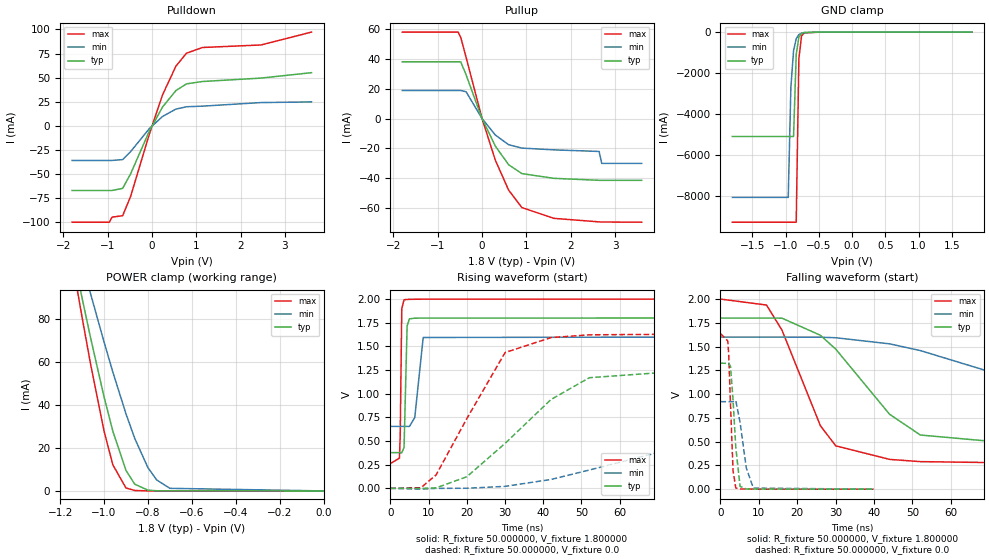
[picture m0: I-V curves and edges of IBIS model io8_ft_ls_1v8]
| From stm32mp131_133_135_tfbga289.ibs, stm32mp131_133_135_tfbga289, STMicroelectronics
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|   Model io8_ft_ls_1v8
[Model]  io8_ft_ls_1v8
Model_type I/O
Polarity   Non-Inverting
Enable   Active-Low
Vinl =   0.540000V
Vinh =   1.260000V
Vmeas =  0.900000V
Cref =   50.000000pF
Rref =   100.000000M
Vref =   0.0V
C_comp   3.181500pF   3.164300pF   3.208900pF
[Temperature Range]   25.000000   0.140000k   -40.000000
[Pullup Reference]   1.800000V   1.600000V   2.000000V
[Pulldown Reference]   0.0V   0.0V   0.0V
[POWER Clamp Reference]   1.800000V   1.600000V   2.000000V
[GND Clamp Reference]   0.0V   0.0V   0.0V
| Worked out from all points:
|   slope of the pulldown table from 0 to 0.27 V, typ, clamps not added: 12.5 ohm
|   slope of the pullup table from 0 to 0.27 V, typ, clamps not added: 16 ohm
|   GND clamp passes 1 mA (typ) near -0.47 V on its own axis
|   POWER clamp passes 1 mA (typ) near -0.83 V on its own axis
|   rising waveform, R_fixture 50.000000, V_fixture 1.800000: 20-80 % time 363ps typ, 728ps min, 285ps max; typ from 0.377 V to 1.8 V
|   rising waveform, R_fixture 50.000000, V_fixture 0.0: 20-80 % time 21.7ns typ, 54ns min, 12.5ns max; typ from 0 V to 1.32 V
|   falling waveform, R_fixture 50.000000, V_fixture 1.800000: 20-80 % time 18.6ns typ, 47.6ns min, 10.6ns max; typ from 1.8 V to 0.377 V
|   falling waveform, R_fixture 50.000000, V_fixture 0.0: 20-80 % time 1.22ns typ, 1.91ns min, 857ps max; typ from 1.32 V to 0 V
[Pulldown]
|Voltage   I(typ)   I(min)   I(max)
-1.8V     -67.09mA   -35.91mA   -100mA
-960mV    -67.09mA   -35.91mA   -100mA
-900mV    -67.09mA   -35.91mA   -94.73mA
-660mV    -64.86mA   -35.04mA   -93.29mA
-480mV    -49.73mA   -26.7mA    -73.15mA
-60mV     -5.61mA    -2.937mA   -8.854mA
240mV     19.58mA    9.767mA    32.18mA
540mV     36.57mA    17.36mA    61.85mA
780mV     43.58mA    19.81mA    75.41mA
1.14V     46.02mA    20.44mA    81.32mA
2.46V     49.57mA    24.16mA    83.94mA
3.6V      55.18mA    24.86mA    97.31mA
[Pullup]
|Voltage   I(typ)   I(min)   I(max)
-1.8V     37.91mA    18.78mA    57.81mA
-540mV    37.91mA    18.78mA    57.81mA
-480mV    37.91mA    18.78mA    54.19mA
-360mV    29.25mA    17.91mA    40.95mA
0V        5.86pA     765pA      4.35pA
300mV     -18.47mA   -11.04mA   -27.85mA
600mV     -30.86mA   -17.49mA   -47.91mA
900mV     -36.82mA   -19.76mA   -59.55mA
1.62V     -39.97mA   -20.94mA   -66.73mA
2.64V     -41.3mA    -22mA      -69.09mA
2.7V      -41.3mA    -30mA      -69.18mA
3.6V      -41.3mA    -30mA      -69.3mA
[GND_clamp]
|Voltage   I(typ)   I(min)   I(max)
-1.8V     -5.08A     -8.044A    -9.251A
-960mV    -5.08A     -8.044A    -9.251A
-920mV    -5.08A     -2.669A    -9.251A
-880mV    -5.08A     -908mA     -9.251A
-840mV    -1.096A    -323.6mA   -9.251A
-800mV    -248.9mA   -123.7mA   -1.293A
-760mV    -64.81mA   -51.32mA   -196.6mA
-720mV    -22.13mA   -23.23mA   -39.69mA
-480mV    -1.149mA   -1.898mA   -936.1uA
1.8V      0A         44.33nA    0A
[POWER_clamp]
|Voltage   I(typ)   I(min)   I(max)
-1.8V     460.5mA    392.1mA    526.9mA
-1.12V    99.56mA    114.1mA    92.51mA
-1.1V     89.79mA    106.4mA    80.86mA
-1.06V    70.71mA    91.32mA    58.34mA
-1V       43.82mA    69.37mA    27.91mA
-960mV    27.85mA    55.39mA    12.18mA
-900mV    9.544mA    35.9mA     1.368mA
-860mV    3.133mA    24.42mA    203.6uA
-800mV    367uA      10.84mA    10.43uA
-760mV    78.93uA    5.095mA    1.426uA
-700mV    7.679uA    1.212mA    72.45nA
0V        0A         59.16nA    0A
[Ramp]
| variable   typ   min   max
dV/dt_r  0.79476/21.60778n   0.55238/53.91503n   0.98220/12.41421n
dV/dt_f  0.85363/18.45188n   0.56723/47.51838n   1.04298/10.52669n
R_load = 50.000000
[Rising Waveform]
R_fixture= 50.000000
V_fixture= 1.800000
V_fixture_min= 1.600000
V_fixture_max= 2.000000
|time   V(typ)   V(min)   V(max)
0s        377.3mV    654.6mV    261.7mV
2.402ns   377.3mV    654.6mV    319.2mV
2.603ns   377.3mV    654.6mV    570.9mV
3.003ns   375.6mV    654.6mV    1.896V
3.604ns   434.3mV    654.6mV    1.993V
4.404ns   1.716V     654.7mV    1.996V
5.005ns   1.791V     653.5mV    1.997V
6.406ns   1.798V     748.7mV    1.998V
8.609ns   1.799V     1.594V     1.999V
99.7ns    1.8V       1.6V       2V
[Rising Waveform]
R_fixture= 50.000000
V_fixture= 0.0
V_fixture_min= 0.0
V_fixture_max= 0.0
|time   V(typ)   V(min)   V(max)
0s        2.004nV    378.7nV    939.1pV
8.008ns   -568.6uV   -8.718mV   6.504mV
12.01ns   5.152mV    -235.5uV   143.1mV
20.02ns   122.6mV    950uV      737.3mV
30.03ns   474.9mV    20.83mV    1.435V
42.04ns   938.7mV    93.95mV    1.593V
52.05ns   1.169V     193.5mV    1.622V
104.1ns   1.319V     729.9mV    1.637V
164.2ns   1.325V     894.4mV    1.637V
997ns     1.325V     920.7mV    1.637V
[Falling Waveform]
R_fixture= 50.000000
V_fixture= 1.800000
V_fixture_min= 1.600000
V_fixture_max= 2.000000
|time   V(typ)   V(min)   V(max)
0s        1.8V       1.6V       2V
12.01ns   1.8V       1.6V       1.937V
16.02ns   1.799V     1.6V       1.674V
26.03ns   1.619V     1.599V     667.3mV
30.03ns   1.473V     1.593V     455.6mV
44.04ns   787.9mV    1.529V     313.2mV
52.05ns   569.6mV    1.458V     289.8mV
100.1ns   396.2mV    867.2mV    263.4mV
166.2ns   378.8mV    690.4mV    261.7mV
997ns     377.3mV    654.6mV    261.7mV
[Falling Waveform]
R_fixture= 50.000000
V_fixture= 0.0
V_fixture_min= 0.0
V_fixture_max= 0.0
|time   V(typ)   V(min)   V(max)
0s        1.325V     920.7mV    1.637V
1.922ns   1.324V     920.7mV    1.559V
2.162ns   1.327V     920.7mV    1.42V
2.643ns   1.289V     920.7mV    877.3mV
3.283ns   942.2mV    920.4mV    197.1mV
4.004ns   439mV      932.3mV    13.3mV
5.125ns   29.12mV    702.9mV    2.27mV
6.727ns   1.816mV    225.3mV    1.271mV
8.569ns   716.3uV    11.3mV     981.8uV
39.88ns   2.004nV    378.7nV    939.1pV
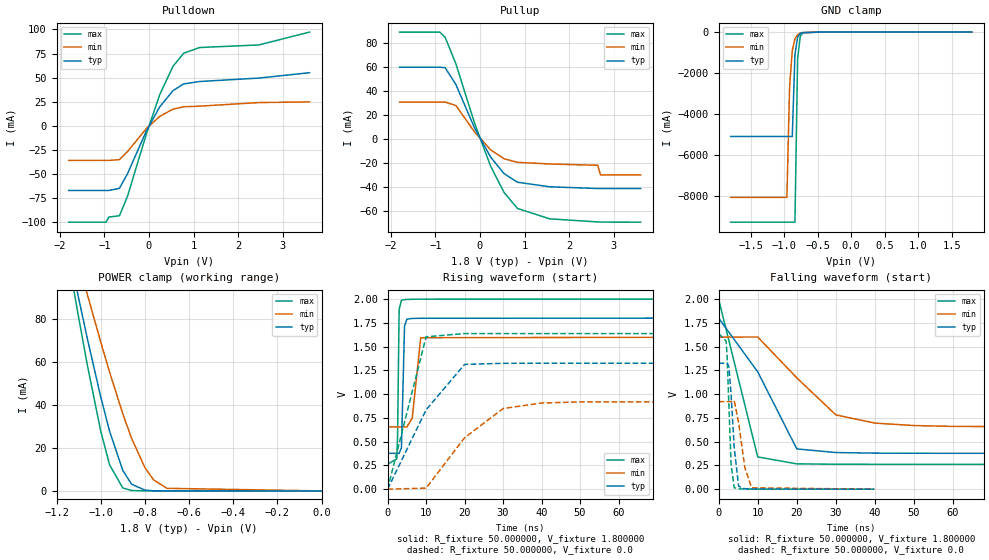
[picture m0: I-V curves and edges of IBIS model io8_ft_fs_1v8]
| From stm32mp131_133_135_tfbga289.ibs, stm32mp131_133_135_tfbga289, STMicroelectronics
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|   Model io8_ft_fs_1v8
[Model]  io8_ft_fs_1v8
Model_type I/O
Polarity   Non-Inverting
Enable   Active-Low
Vinl =   0.540000V
Vinh =   1.260000V
Vmeas =  0.900000V
Cref =   50.000000pF
Rref =   100.000000M
Vref =   0.0V
C_comp   3.181500pF   3.164300pF   3.208900pF
[Temperature Range]   25.000000   0.140000k   -40.000000
[Pullup Reference]   1.800000V   1.600000V   2.000000V
[Pulldown Reference]   0.0V   0.0V   0.0V
[POWER Clamp Reference]   1.800000V   1.600000V   2.000000V
[GND Clamp Reference]   0.0V   0.0V   0.0V
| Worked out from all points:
|   slope of the pulldown table from 0 to 0.27 V, typ, clamps not added: 12.5 ohm
|   slope of the pullup table from 0 to 0.27 V, typ, clamps not added: 16 ohm
|   GND clamp passes 1 mA (typ) near -0.47 V on its own axis
|   POWER clamp passes 1 mA (typ) near -0.83 V on its own axis
|   rising waveform, R_fixture 50.000000, V_fixture 1.800000: 20-80 % time 365ps typ, 729ps min, 287ps max; typ from 0.377 V to 1.8 V
|   rising waveform, R_fixture 50.000000, V_fixture 0.0: 20-80 % time 11.5ns typ, 13.1ns min, 6.13ns max; typ from 0 V to 1.32 V
|   falling waveform, R_fixture 50.000000, V_fixture 1.800000: 20-80 % time 12ns typ, 14ns min, 6.29ns max; typ from 1.8 V to 0.377 V
|   falling waveform, R_fixture 50.000000, V_fixture 0.0: 20-80 % time 1.22ns typ, 1.91ns min, 860ps max; typ from 1.32 V to 0 V
[Pulldown]
|Voltage   I(typ)   I(min)   I(max)
-1.8V     -67.09mA   -35.91mA   -100mA
-960mV    -67.09mA   -35.91mA   -100mA
-900mV    -67.09mA   -35.91mA   -94.73mA
-660mV    -64.86mA   -35.04mA   -93.29mA
-480mV    -49.73mA   -26.7mA    -73.15mA
-60mV     -5.61mA    -2.937mA   -8.854mA
240mV     19.58mA    9.767mA    32.18mA
540mV     36.57mA    17.36mA    61.85mA
780mV     43.58mA    19.81mA    75.41mA
1.14V     46.02mA    20.44mA    81.32mA
2.46V     49.57mA    24.16mA    83.94mA
3.6V      55.18mA    24.86mA    97.31mA
[Pullup]
|Voltage   I(typ)   I(min)   I(max)
-1.8V     59.55mA    30.58mA    88.77mA
-900mV    59.55mA    30.58mA    88.77mA
-780mV    59.21mA    30.58mA    84.38mA
-540mV    45.23mA    27.77mA    62.46mA
-120mV    8.961mA    5.668mA    12.94mA
240mV     -15.24mA   -9.189mA   -22.87mA
540mV     -28.9mA    -16.58mA   -44.57mA
840mV     -36.08mA   -19.51mA   -57.87mA
1.56V     -39.85mA   -20.89mA   -66.5mA
2.64V     -41.3mA    -22mA      -69.09mA
2.7V      -41.3mA    -30mA      -69.18mA
3.6V      -41.3mA    -30mA      -69.3mA
[GND_clamp]
|Voltage   I(typ)   I(min)   I(max)
-1.8V     -5.08A     -8.044A    -9.251A
-960mV    -5.08A     -8.044A    -9.251A
-920mV    -5.08A     -2.669A    -9.251A
-880mV    -5.08A     -908mA     -9.251A
-840mV    -1.096A    -323.6mA   -9.251A
-800mV    -248.9mA   -123.7mA   -1.293A
-760mV    -64.81mA   -51.32mA   -196.6mA
-720mV    -22.13mA   -23.23mA   -39.69mA
-480mV    -1.149mA   -1.898mA   -936.1uA
1.8V      0A         44.33nA    0A
[POWER_clamp]
|Voltage   I(typ)   I(min)   I(max)
-1.8V     460.5mA    392.1mA    526.9mA
-1.12V    99.56mA    114.1mA    92.51mA
-1.1V     89.79mA    106.4mA    80.86mA
-1.06V    70.71mA    91.32mA    58.34mA
-1V       43.82mA    69.37mA    27.91mA
-960mV    27.85mA    55.39mA    12.18mA
-900mV    9.544mA    35.9mA     1.368mA
-860mV    3.133mA    24.42mA    203.6uA
-800mV    367uA      10.84mA    10.43uA
-760mV    78.93uA    5.095mA    1.426uA
-700mV    7.679uA    1.212mA    72.45nA
0V        0A         59.16nA    0A
[Ramp]
| variable   typ   min   max
dV/dt_r  0.79476/4.10814n   0.55240/10.19838n   0.98226/2.31449n
dV/dt_f  0.85363/4.33132n   0.56724/10.75987n   1.04297/2.48564n
R_load = 50.000000
[Rising Waveform]
R_fixture= 50.000000
V_fixture= 1.800000
V_fixture_min= 1.600000
V_fixture_max= 2.000000
|time   V(typ)   V(min)   V(max)
0s        377.3mV    654.6mV    261.7mV
2.402ns   377.3mV    654.6mV    319.5mV
2.603ns   377.3mV    654.6mV    570.4mV
3.003ns   375.6mV    654.6mV    1.89V
3.604ns   434.2mV    654.6mV    1.988V
4.404ns   1.713V     654.7mV    1.994V
5.005ns   1.788V     653.6mV    1.996V
6.406ns   1.796V     748.6mV    1.998V
8.609ns   1.798V     1.593V     1.999V
99.7ns    1.8V       1.6V       2V
[Rising Waveform]
R_fixture= 50.000000
V_fixture= 0.0
V_fixture_min= 0.0
V_fixture_max= 0.0
|time   V(typ)   V(min)   V(max)
0s        2.004nV    378.7nV    939.1pV
10.01ns   835mV      10.85mV    1.603V
20.02ns   1.313V     541.8mV    1.637V
30.03ns   1.324V     848.6mV    1.637V
40.04ns   1.325V     906.5mV    1.637V
50.05ns   1.325V     918.2mV    1.637V
991ns     1.325V     920.7mV    1.637V
[Falling Waveform]
R_fixture= 50.000000
V_fixture= 1.800000
V_fixture_min= 1.600000
V_fixture_max= 2.000000
|time   V(typ)   V(min)   V(max)
0s        1.8V       1.6V       2V
10.01ns   1.235V     1.601V     339.2mV
20.02ns   423.6mV    1.171V     266.3mV
30.03ns   385.3mV    781.3mV    262.2mV
40.04ns   379.1mV    694.9mV    261.7mV
50.05ns   377.6mV    669.2mV    261.7mV
60.06ns   377.3mV    660.3mV    261.7mV
100.1ns   377.3mV    654.7mV    261.7mV
991ns     377.3mV    654.6mV    261.7mV
[Falling Waveform]
R_fixture= 50.000000
V_fixture= 0.0
V_fixture_min= 0.0
V_fixture_max= 0.0
|time   V(typ)   V(min)   V(max)
0s        1.325V     920.7mV    1.637V
1.922ns   1.324V     920.7mV    1.558V
2.162ns   1.327V     920.7mV    1.417V
2.643ns   1.288V     920.7mV    874.9mV
3.203ns   992.4mV    920.5mV    256.7mV
4.004ns   436.6mV    931.2mV    16mV
5.125ns   30.14mV    700.1mV    3.312mV
6.727ns   3.667mV    224.1mV    1.151mV
8.488ns   1.83mV     14.08mV    645.6uV
39.88ns   2.004nV    378.7nV    939.1pV
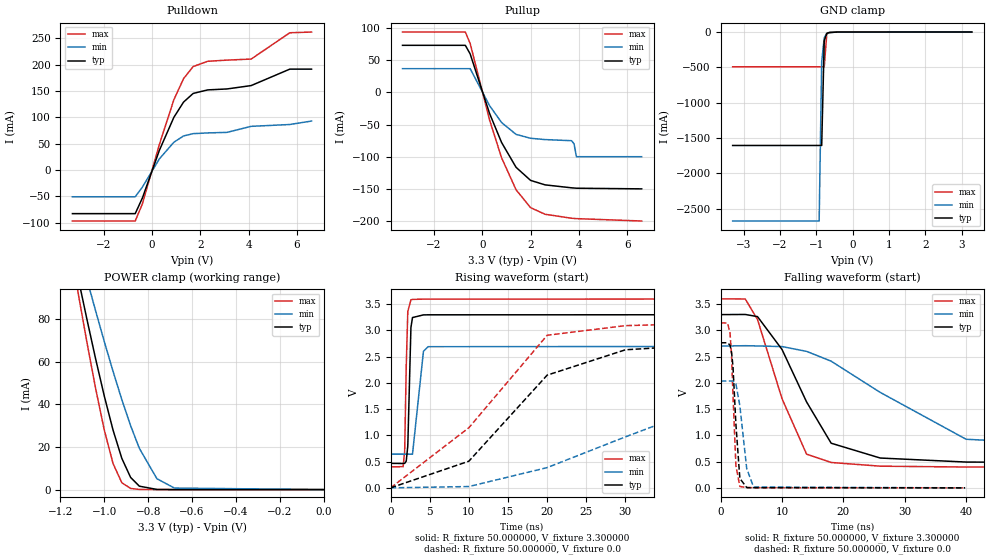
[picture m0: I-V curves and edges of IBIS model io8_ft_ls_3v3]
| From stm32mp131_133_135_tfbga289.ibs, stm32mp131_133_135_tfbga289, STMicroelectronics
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|   Model io8_ft_ls_3v3
[Model]  io8_ft_ls_3v3
Model_type I/O
Polarity   Non-Inverting
Enable   Active-Low
Vinl =   0.990000V
Vinh =   2.310000V
Vmeas =  1.650000V
Cref =   50.000000pF
Rref =   100.000000M
Vref =   0.0V
C_comp   3.331100pF   3.329200pF   3.346200pF
[Temperature Range]   25.000000   0.140000k   -40.000000
[Pullup Reference]   3.300000V   2.700000V   3.600000V
[Pulldown Reference]   0.0V   0.0V   0.0V
[POWER Clamp Reference]   3.300000V   2.700000V   3.600000V
[GND Clamp Reference]   0.0V   0.0V   0.0V
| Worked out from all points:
|   slope of the pulldown table from 0 to 0.495 V, typ, clamps not added: 8.27 ohm
|   slope of the pullup table from 0 to 0.495 V, typ, clamps not added: 9.61 ohm
|   GND clamp passes 1 mA (typ) near -0.46 V on its own axis
|   POWER clamp passes 1 mA (typ) near -0.82 V on its own axis
|   rising waveform, R_fixture 50.000000, V_fixture 3.300000: 20-80 % time 298ps typ, 372ps min, 282ps max; typ from 0.466 V to 3.3 V
|   rising waveform, R_fixture 50.000000, V_fixture 0.0: 20-80 % time 11.1ns typ, 22.9ns min, 12.3ns max; typ from 0 V to 2.76 V
|   falling waveform, R_fixture 50.000000, V_fixture 3.300000: 20-80 % time 7.44ns typ, 16.2ns min, 5.44ns max; typ from 3.3 V to 0.466 V
|   falling waveform, R_fixture 50.000000, V_fixture 0.0: 20-80 % time 746ps typ, 1.13ns min, 609ps max; typ from 2.76 V to 0 V
[Pulldown]
|Voltage   I(typ)   I(min)   I(max)
-3.3V     -82.68mA   -50.69mA   -96.69mA
-700mV    -82.68mA   -50.69mA   -96.69mA
-400mV    -52.74mA   -32.14mA   -63.87mA
300mV     37.41mA    21.2mA     48.47mA
900mV     100mA      52.8mA     133.4mA
1.3V      128.9mA    64.69mA    173.3mA
1.7V      145.4mA    69.09mA    196.4mA
2.3V      152.1mA    70.46mA    206.4mA
3.1V      153.9mA    71.5mA     208.6mA
4.1V      160.3mA    82.94mA    210.6mA
5.7V      191.5mA    86.44mA    260.5mA
6.6V      191.5mA    93mA       261.9mA
[Pullup]
|Voltage   I(typ)   I(min)   I(max)
-3.3V     73.22mA    36.92mA    93.89mA
-700mV    73.22mA    36.92mA    93.89mA
-500mV    59.82mA    36.92mA    76.02mA
300mV     -32.45mA   -20.38mA   -42.55mA
800mV     -77.86mA   -46.83mA   -101.6mA
1.4V      -116.5mA   -65.29mA   -151.4mA
2V        -136.8mA   -71.31mA   -179.2mA
2.6V      -143.8mA   -73.35mA   -189.5mA
3.7V      -148.4mA   -75.1mA    -195.7mA
3.8V      -148.7mA   -80mA      -196mA
3.9V      -149mA     -100mA     -196.3mA
6.6V      -150mA     -100mA     -200mA
[GND_clamp]
|Voltage   I(typ)   I(min)   I(max)
-3.3V     -1.605A    -2.674A    -491.7mA
-920mV    -1.605A    -2.674A    -491.7mA
-850mV    -1.605A    -419.8mA   -491.7mA
-780mV    -124.6mA   -80.71mA   -491.7mA
-710mV    -18.13mA   -20.11mA   -27.93mA
-640mV    -6.917mA   -6.958mA   -7.362mA
-430mV    -466.9uA   -1.206mA   -281.7uA
3.28V     0A         45.63nA    0A
[POWER_clamp]
|Voltage   I(typ)   I(min)   I(max)
-3.28V    1.28A      1.024A     1.509A
-1.12V    99.56mA    114.1mA    92.51mA
-1.08V    80.16mA    98.83mA    69.45mA
-1.04V    61.47mA    83.9mA     47.62mA
-1V       43.82mA    69.37mA    27.91mA
-960mV    27.85mA    55.39mA    12.18mA
-920mV    14.63mA    42.15mA    3.226mA
-880mV    5.71mA     29.97mA    537.4uA
-840mV    1.599mA    19.32mA    75.95uA
-760mV    78.93uA    5.095mA    1.426uA
-680mV    3.528uA    713.7uA    27.27nA
0V        0A         62.3nA     0A
[Ramp]
| variable   typ   min   max
dV/dt_r  1.65858/10.24860n   1.22046/21.78605n   1.88568/7.88366n
dV/dt_f  1.70022/7.28874n   1.23440/16.12476n   1.92035/5.37283n
R_load = 50.000000
[Rising Waveform]
R_fixture= 50.000000
V_fixture= 3.300000
V_fixture_min= 2.700000
V_fixture_max= 3.600000
|time   V(typ)   V(min)   V(max)
0s        466.3mV    642.7mV    399.4mV
1.602ns   463.9mV    642.7mV    403.6mV
1.802ns   465.7mV    642.7mV    694.9mV
2.002ns   509mV      642.7mV    2.309V
2.202ns   796.8mV    642.8mV    3.358V
2.603ns   3.056V     641.6mV    3.583V
2.803ns   3.244V     641.9mV    3.59V
4.204ns   3.295V     2.601V     3.595V
4.805ns   3.296V     2.689V     3.595V
99.7ns    3.3V       2.7V       3.6V
[Rising Waveform]
R_fixture= 50.000000
V_fixture= 0.0
V_fixture_min= 0.0
V_fixture_max= 0.0
|time   V(typ)   V(min)   V(max)
0s        2.574nV    280.9nV    5.711nV
10.01ns   507.7mV    24.77mV    1.145V
20.02ns   2.147V     385.7mV    2.907V
30.03ns   2.63V      971.6mV    3.09V
40.04ns   2.72V      1.534V     3.13V
50.05ns   2.748V     1.821V     3.139V
60.06ns   2.758V     1.925V     3.142V
80.08ns   2.764V     2V         3.143V
100.1ns   2.764V     2.023V     3.143V
991ns     2.764V     2.034V     3.143V
[Falling Waveform]
R_fixture= 50.000000
V_fixture= 3.300000
V_fixture_min= 2.700000
V_fixture_max= 3.600000
|time   V(typ)   V(min)   V(max)
0s        3.3V       2.7V       3.6V
4.004ns   3.303V     2.708V     3.598V
6.006ns   3.262V     2.703V     3.207V
10.01ns   2.635V     2.691V     1.697V
14.01ns   1.637V     2.6V       642.1mV
18.02ns   850.4mV    2.413V     483.3mV
26.03ns   568mV      1.818V     412.8mV
40.04ns   491.4mV    925.7mV    396.6mV
82.08ns   467.6mV    673.9mV    399.1mV
997ns     466.3mV    642.7mV    399.4mV
[Falling Waveform]
R_fixture= 50.000000
V_fixture= 0.0
V_fixture_min= 0.0
V_fixture_max= 0.0
|time   V(typ)   V(min)   V(max)
0s        2.764V     2.034V     3.143V
1.121ns   2.764V     2.034V     3.14V
1.522ns   2.719V     2.034V     2.951V
1.762ns   2.589V     2.034V     2.541V
2.002ns   2.318V     2.037V     1.778V
2.482ns   1.209V     1.98V      420.7mV
3.123ns   180.2mV    1.566V     27.35mV
4.244ns   5.433mV    367.8mV    4.58mV
5.365ns   2.953mV    15.69mV    3.729mV
39.88ns   2.574nV    280.9nV    5.711nV
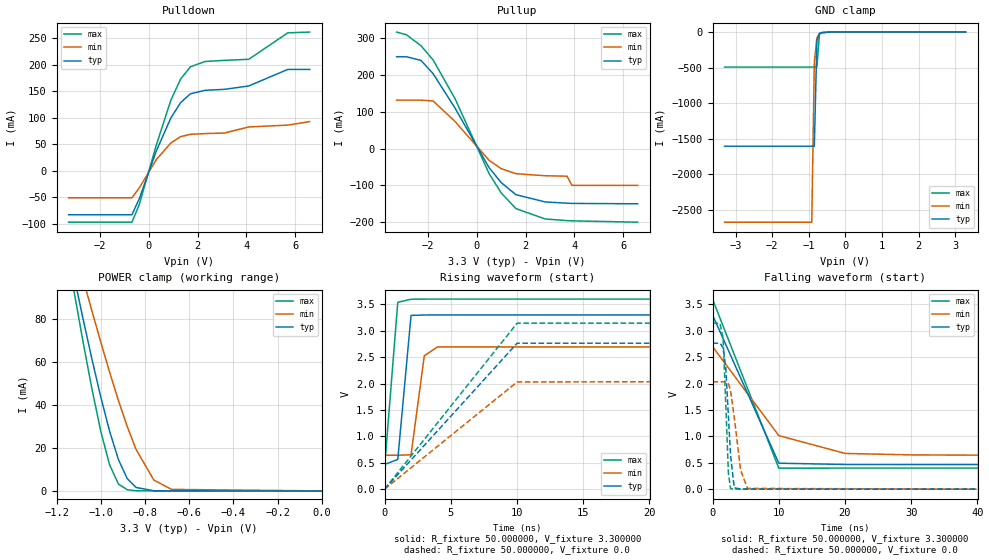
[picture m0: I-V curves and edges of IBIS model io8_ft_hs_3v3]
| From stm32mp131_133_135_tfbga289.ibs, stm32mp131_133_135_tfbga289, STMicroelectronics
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|   Model io8_ft_hs_3v3
[Model]  io8_ft_hs_3v3
Model_type I/O
Polarity   Non-Inverting
Enable   Active-Low
Vinl =   0.990000V
Vinh =   2.310000V
Vmeas =  1.650000V
Cref =   50.000000pF
Rref =   100.000000M
Vref =   0.0V
C_comp   3.331100pF   3.329200pF   3.346200pF
[Temperature Range]   25.000000   0.140000k   -40.000000
[Pullup Reference]   3.300000V   2.700000V   3.600000V
[Pulldown Reference]   0.0V   0.0V   0.0V
[POWER Clamp Reference]   3.300000V   2.700000V   3.600000V
[GND Clamp Reference]   0.0V   0.0V   0.0V
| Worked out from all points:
|   slope of the pulldown table from 0 to 0.495 V, typ, clamps not added: 8.27 ohm
|   slope of the pullup table from 0 to 0.495 V, typ, clamps not added: 9.61 ohm
|   GND clamp passes 1 mA (typ) near -0.46 V on its own axis
|   POWER clamp passes 1 mA (typ) near -0.82 V on its own axis
|   rising waveform, R_fixture 50.000000, V_fixture 3.300000: 20-80 % time 624ps typ, 658ps min, 612ps max; typ from 0.466 V to 3.3 V
|   rising waveform, R_fixture 50.000000, V_fixture 0.0: 20-80 % time 6.01ns typ, 6.02ns min, 6.01ns max; typ from 0 V to 2.76 V
|   falling waveform, R_fixture 50.000000, V_fixture 3.300000: 20-80 % time 6.06ns typ, 7.33ns min, 6ns max; typ from 3.3 V to 0.466 V
|   falling waveform, R_fixture 50.000000, V_fixture 0.0: 20-80 % time 720ps typ, 1.13ns min, 527ps max; typ from 2.76 V to 0 V
[Pulldown]
|Voltage   I(typ)   I(min)   I(max)
-3.3V     -82.68mA   -50.69mA   -96.69mA
-700mV    -82.68mA   -50.69mA   -96.69mA
-400mV    -52.74mA   -32.14mA   -63.87mA
300mV     37.41mA    21.2mA     48.47mA
900mV     100mA      52.8mA     133.4mA
1.3V      128.9mA    64.69mA    173.3mA
1.7V      145.4mA    69.09mA    196.4mA
2.3V      152.1mA    70.46mA    206.4mA
3.1V      153.9mA    71.5mA     208.6mA
4.1V      160.3mA    82.94mA    210.6mA
5.7V      191.5mA    86.44mA    260.5mA
6.6V      191.5mA    93mA       261.9mA
[Pullup]
|Voltage   I(typ)   I(min)   I(max)
-3.3V     249.5mA    131.5mA    316.4mA
-2.9V     249.5mA    131.5mA    309.3mA
-2.3V     239.6mA    131.5mA    279.6mA
-1.8V     203.4mA    129.4mA    240.8mA
-900mV    110mA      73.66mA    135.5mA
500mV     -51.98mA   -32.11mA   -68.11mA
1V        -92.73mA   -54.65mA   -120.7mA
1.6V      -125.3mA   -68.24mA   -163.1mA
2.8V      -145mA     -73.8mA    -191.2mA
3.7V      -148.4mA   -75.1mA    -195.7mA
3.9V      -149mA     -100mA     -196.3mA
6.6V      -150mA     -100mA     -200mA
[GND_clamp]
|Voltage   I(typ)   I(min)   I(max)
-3.3V     -1.605A    -2.674A    -491.7mA
-920mV    -1.605A    -2.674A    -491.7mA
-850mV    -1.605A    -419.8mA   -491.7mA
-780mV    -124.6mA   -80.71mA   -491.7mA
-710mV    -18.13mA   -20.11mA   -27.93mA
-640mV    -6.917mA   -6.958mA   -7.362mA
-430mV    -466.9uA   -1.206mA   -281.7uA
3.28V     0A         45.63nA    0A
[POWER_clamp]
|Voltage   I(typ)   I(min)   I(max)
-3.28V    1.28A      1.024A     1.509A
-1.12V    99.56mA    114.1mA    92.51mA
-1.08V    80.16mA    98.83mA    69.45mA
-1.04V    61.47mA    83.9mA     47.62mA
-1V       43.82mA    69.37mA    27.91mA
-960mV    27.85mA    55.39mA    12.18mA
-920mV    14.63mA    42.15mA    3.226mA
-880mV    5.71mA     29.97mA    537.4uA
-840mV    1.599mA    19.32mA    75.95uA
-760mV    78.93uA    5.095mA    1.426uA
-680mV    3.528uA    713.7uA    27.27nA
0V        0A         62.3nA     0A
[Ramp]
| variable   typ   min   max
dV/dt_r  1.65858/0.65228n   1.22046/1.25109n   1.88568/1.02238n
dV/dt_f  1.70022/1.60578n   1.23439/3.71657n   1.92035/1.23486n
R_load = 50.000000
[Rising Waveform]
R_fixture= 50.000000
V_fixture= 3.300000
V_fixture_min= 2.700000
V_fixture_max= 3.600000
|time   V(typ)   V(min)   V(max)
0s        466.3mV    642.7mV    399.6mV
1.001ns   563.8mV    642.7mV    3.539V
2.002ns   3.291V     650.3mV    3.597V
3.003ns   3.298V     2.527V     3.599V
4.004ns   3.299V     2.693V     3.6V
99.1ns    3.3V       2.7V       3.6V
[Rising Waveform]
R_fixture= 50.000000
V_fixture= 0.0
V_fixture_min= 0.0
V_fixture_max= 0.0
|time   V(typ)   V(min)   V(max)
0s        2.574nV    280.9nV    5.711nV
10.01ns   2.764V     2.03V      3.143V
20.02ns   2.764V     2.034V     3.143V
991ns     2.764V     2.034V     3.143V
[Falling Waveform]
R_fixture= 50.000000
V_fixture= 3.300000
V_fixture_min= 2.700000
V_fixture_max= 3.600000
|time   V(typ)   V(min)   V(max)
0s        3.3V       2.7V       3.6V
10.01ns   491.5mV    1.014V     397mV
20.02ns   467.5mV    676.7mV    399.3mV
30.03ns   466.4mV    649mV      399.6mV
40.04ns   466.3mV    643.9mV    399.6mV
991ns     466.3mV    642.7mV    399.6mV
[Falling Waveform]
R_fixture= 50.000000
V_fixture= 0.0
V_fixture_min= 0.0
V_fixture_max= 0.0
|time   V(typ)   V(min)   V(max)
0s        2.764V     2.034V     3.143V
1.121ns   2.764V     2.034V     3.139V
1.602ns   2.68V      2.034V     2.856V
2.002ns   2.304V     2.036V     1.616V
2.402ns   1.371V     2.002V     306.3mV
2.723ns   645.9mV    1.866V     9.639mV
3.283ns   24.97mV    1.361V     2.969mV
4.244ns   2.933mV    358mV      1.604mV
5.285ns   1.718mV    14.36mV    1.119mV
39.88ns   2.574nV    280.9nV    5.711nV
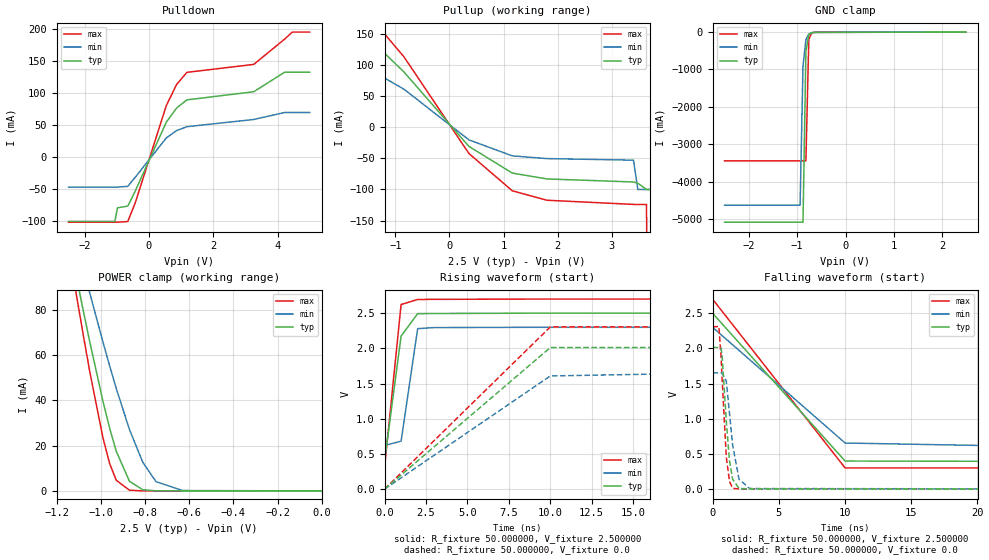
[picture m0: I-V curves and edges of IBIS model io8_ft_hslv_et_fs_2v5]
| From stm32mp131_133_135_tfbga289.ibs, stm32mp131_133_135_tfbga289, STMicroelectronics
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|   Model io8_ft_hslv_et_fs_2v5
[Model]  io8_ft_hslv_et_fs_2v5
Model_type I/O
Polarity   Non-Inverting
Enable   Active-Low
Vinl =   0.750000V
Vinh =   1.750000V
Vmeas =  1.250000V
Cref =   50.000000pF
Rref =   100.000000M
Vref =   0.0V
C_comp   3.268600pF   3.267200pF   3.310300pF
[Temperature Range]   25.000000   0.140000k   -40.000000
[Pullup Reference]   2.500000V   2.300000V   2.700000V
[Pulldown Reference]   0.0V   0.0V   0.0V
[POWER Clamp Reference]   2.500000V   2.300000V   2.700000V
[GND Clamp Reference]   0.0V   0.0V   0.0V
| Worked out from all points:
|   slope of the pulldown table from 0 to 0.375 V, typ, clamps not added: 9.35 ohm
|   slope of the pullup table from 0 to 0.375 V, typ, clamps not added: 11.7 ohm
|   GND clamp passes 1 mA (typ) near -0.47 V on its own axis
|   POWER clamp passes 1 mA (typ) near -0.82 V on its own axis
|   rising waveform, R_fixture 50.000000, V_fixture 2.500000: 20-80 % time 711ps typ, 631ps min, 621ps max; typ from 0.396 V to 2.5 V
|   rising waveform, R_fixture 50.000000, V_fixture 0.0: 20-80 % time 6.01ns typ, 6.17ns min, 6.01ns max; typ from 0 V to 2.01 V
|   falling waveform, R_fixture 50.000000, V_fixture 2.500000: 20-80 % time 6.02ns typ, 6.13ns min, 6.01ns max; typ from 2.5 V to 0.396 V
|   falling waveform, R_fixture 50.000000, V_fixture 0.0: 20-80 % time 457ps typ, 600ps min, 384ps max; typ from 2.01 V to 0 V
[Pulldown]
|Voltage   I(typ)   I(min)   I(max)
-2.5V     -100mA     -46.5mA    -101.2mA
-1.06V    -100mA     -46.5mA    -101.2mA
-980mV    -78.83mA   -46.5mA    -101.2mA
-660mV    -76.17mA   -45.35mA   -100.2mA
-420mV    -51.93mA   -30.73mA   -70.08mA
540mV     54.77mA    30.24mA    80.67mA
860mV     76.84mA    41.64mA    113.6mA
1.18V     89.58mA    47.74mA    132.5mA
3.26V     102.3mA    59.01mA    144.9mA
4.22V     132.7mA    69.88mA    184.3mA
4.46V     132.7mA    69.88mA    195.3mA
5V        132.7mA    69.88mA    195.3mA
[Pullup]
|Voltage   I(typ)   I(min)   I(max)
-2.5V     135.7mA    85.31mA    174.8mA
-1.48V    135.7mA    85.31mA    172.6mA
-1.32V    128.7mA    84.79mA    162mA
-840mV    88.44mA    60.86mA    112.7mA
360mV     -30.95mA   -20.48mA   -42.37mA
1.16V     -73.66mA   -46.1mA    -102.1mA
1.8V      -83.12mA   -50.48mA   -117.3mA
3.4V      -88mA      -53mA      -124mA
3.48V     -90mA      -100mA     -124.1mA
3.64V     -100mA     -100mA     -124.1mA
3.72V     -100mA     -100mA     -1A
4.92V     -100mA     -100mA     -1A
[GND_clamp]
|Voltage   I(typ)   I(min)   I(max)
-2.5V     -5.082A    -4.628A    -3.442A
-940mV    -5.082A    -4.628A    -3.442A
-880mV    -5.082A    -910.9mA   -3.442A
-820mV    -518.2mA   -200mA     -3.442A
-760mV    -65.41mA   -52.42mA   -196.1mA
-700mV    -14.98mA   -16.7mA    -21.53mA
-640mV    -6.913mA   -6.897mA   -7.503mA
2.48V     0A         42.99nA    0A
[POWER_clamp]
|Voltage   I(typ)   I(min)   I(max)
-2.49V    840.6mA    685.1mA    983.2mA
-1.11V    94.66mA    110.3mA    86.66mA
-1.08V    80.16mA    98.83mA    69.45mA
-1.05V    66.06mA    87.6mA     52.92mA
-990mV    39.64mA    65.82mA    23.5mA
-960mV    27.85mA    55.39mA    12.18mA
-930mV    17.59mA    45.37mA    4.744mA
-870mV    4.273mA    27.14mA    331.7uA
-810mV    535.4uA    12.72mA    17.14uA
-750mV    53.58uA    4.101mA    867.4nA
-630mV    505.3nA    181.4uA    0A
0V        0A         61.21nA    0A
[Ramp]
| variable   typ   min   max
dV/dt_r  1.20762/1.63655n   0.99054/3.00030n   1.38258/1.30470n
dV/dt_f  1.26241/1.08990n   1.00776/2.21955n   1.43924/0.87726n
R_load = 50.000000
[Rising Waveform]
R_fixture= 50.000000
V_fixture= 2.500000
V_fixture_min= 2.300000
V_fixture_max= 2.700000
|time   V(typ)   V(min)   V(max)
0s        396mV      620.4mV    301.3mV
1.001ns   2.174V     681.8mV    2.623V
2.002ns   2.493V     2.28V      2.694V
3.003ns   2.495V     2.295V     2.696V
9.009ns   2.5V       2.299V     2.7V
99.1ns    2.5V       2.3V       2.7V
[Rising Waveform]
R_fixture= 50.000000
V_fixture= 0.0
V_fixture_min= 0.0
V_fixture_max= 0.0
|time   V(typ)   V(min)   V(max)
0s        2.078nV    303.8nV    1.128nV
10.01ns   2.011V     1.608V     2.304V
20.02ns   2.013V     1.65V      2.304V
30.03ns   2.013V     1.651V     2.304V
991ns     2.013V     1.651V     2.304V
[Falling Waveform]
R_fixture= 50.000000
V_fixture= 2.500000
V_fixture_min= 2.300000
V_fixture_max= 2.700000
|time   V(typ)   V(min)   V(max)
0s        2.5V       2.3V       2.7V
10.01ns   399.3mV    655.3mV    301.5mV
20.02ns   396mV      621.4mV    301.3mV
30.03ns   396mV      620.4mV    301.3mV
991ns     396mV      620.4mV    301.3mV
[Falling Waveform]
R_fixture= 50.000000
V_fixture= 0.0
V_fixture_min= 0.0
V_fixture_max= 0.0
|time   V(typ)   V(min)   V(max)
0s        2.013V     1.651V     2.304V
480.5ps   2.013V     1.651V     2.311V
640.6ps   2.009V     1.651V     1.897V
720.7ps   1.908V     1.652V     1.578V
1.041ns   966.6mV    1.535V     453.9mV
1.281ns   402.5mV    1.08V      112.1mV
1.522ns   140.7mV    625.1mV    11.47mV
2.002ns   10.88mV    141.2mV    3.459mV
2.803ns   3.099mV    9.098mV    1.825mV
39.88ns   2.078nV    303.8nV    1.128nV
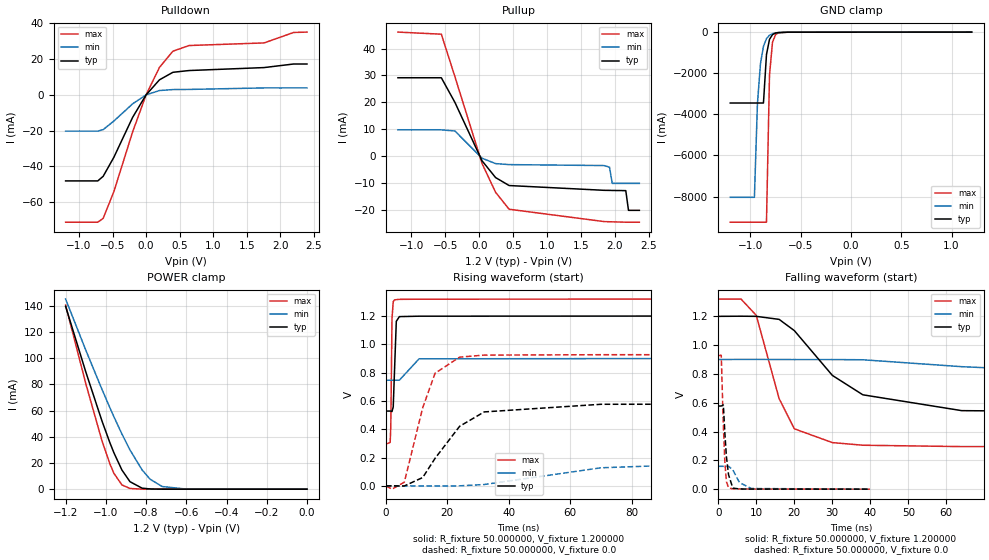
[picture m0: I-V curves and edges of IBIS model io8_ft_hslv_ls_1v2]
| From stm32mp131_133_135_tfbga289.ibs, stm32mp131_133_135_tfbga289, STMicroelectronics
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|   Model io8_ft_hslv_ls_1v2
[Model]  io8_ft_hslv_ls_1v2
Model_type I/O
Polarity   Non-Inverting
Enable   Active-Low
Vinl =   0.360000V
Vinh =   0.840000V
Vmeas =  0.600000V
Cref =   50.000000pF
Rref =   100.000000M
Vref =   0.0V
C_comp   2.940600pF   2.918400pF   2.961700pF
[Temperature Range]   25.000000   0.140000k   -40.000000
[Pullup Reference]   1.200000V   0.900000V   1.320000V
[Pulldown Reference]   0.0V   0.0V   0.0V
[POWER Clamp Reference]   1.200000V   0.900000V   1.320000V
[GND Clamp Reference]   0.0V   0.0V   0.0V
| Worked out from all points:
|   slope of the pulldown table from 0 to 0.18 V, typ, clamps not added: 23.2 ohm
|   slope of the pullup table from 0 to 0.18 V, typ, clamps not added: 28.5 ohm
|   GND clamp passes 1 mA (typ) near -0.47 V on its own axis
|   POWER clamp passes 1 mA (typ) near -0.83 V on its own axis
|   rising waveform, R_fixture 50.000000, V_fixture 1.200000: 20-80 % time 511ps typ, 1.42ns min, 320ps max; typ from 0.529 V to 1.2 V
|   rising waveform, R_fixture 50.000000, V_fixture 0.0: 20-80 % time 12.8ns typ, 30.4ns min, 6.86ns max; typ from 0 V to 0.577 V
|   falling waveform, R_fixture 50.000000, V_fixture 1.200000: 20-80 % time 16.2ns typ, 40.8ns min, 6.7ns max; typ from 1.2 V to 0.529 V
|   falling waveform, R_fixture 50.000000, V_fixture 0.0: 20-80 % time 1.02ns typ, 2.3ns min, 759ps max; typ from 0.577 V to 0 V
[Pulldown]
|Voltage   I(typ)   I(min)   I(max)
-1.2V     -48.14mA   -20.28mA   -71.24mA
-720mV    -48.14mA   -20.28mA   -71.24mA
-640mV    -45.58mA   -19.44mA   -69.11mA
-480mV    -34.9mA    -14.62mA   -54.1mA
-200mV    -12.54mA   -4.988mA   -20.65mA
0V        0A         -3pA       0A
200mV     8.434mA    2.439mA    15.39mA
400mV     12.64mA    2.982mA    24.45mA
640mV     13.62mA    3.048mA    27.62mA
1.76V     15.28mA    3.899mA    29.08mA
2.2V      17.28mA    3.899mA    34.92mA
2.4V      17.28mA    3.899mA    35.14mA
[Pullup]
|Voltage   I(typ)   I(min)   I(max)
-1.2V     29.16mA    9.837mA    46.09mA
-560mV    29.16mA    9.837mA    45.31mA
-360mV    20.04mA    9.414mA    29.58mA
40mV      -1.628mA   -670.5uA   -2.623mA
240mV     -7.854mA   -2.676mA   -13.31mA
440mV     -10.81mA   -3.05mA    -19.6mA
1.84V     -12.58mA   -3.4mA     -24.17mA
1.92V     -12.61mA   -4mA       -24.24mA
1.96V     -12.63mA   -10mA      -24.27mA
2.16V     -12.7mA    -10mA      -24.4mA
2.2V      -20mA      -10mA      -24.4mA
2.36V     -20mA      -10mA      -24.4mA
[GND_clamp]
|Voltage   I(typ)   I(min)   I(max)
-1.2V     -3.45A     -8.037A    -9.248A
-960mV    -3.45A     -8.037A    -9.248A
-930mV    -3.45A     -3.504A    -9.248A
-900mV    -3.45A     -1.544A    -9.248A
-870mV    -3.45A     -693.1mA   -9.248A
-840mV    -1.093A    -319.7mA   -9.248A
-810mV    -355mA     -153mA     -2.104A
-780mV    -122.1mA   -76.47mA   -492.8mA
-750mV    -46.85mA   -40.02mA   -125.6mA
-720mV    -21.41mA   -22.04mA   -38.94mA
-630mV    -6.028mA   -5.668mA   -6.589mA
1.2V      0A         44.19nA    0A
[POWER_clamp]
|Voltage   I(typ)   I(min)   I(max)
-1.2V     139.7mA    145.3mA    140.7mA
-1.1V     89.79mA    106.4mA    80.86mA
-1.02V    52.48mA    76.58mA    37.41mA
-980mV    35.57mA    62.3mA     19.38mA
-960mV    27.85mA    55.39mA    12.18mA
-920mV    14.63mA    42.15mA    3.226mA
-880mV    5.71mA     29.97mA    537.4uA
-820mV    777uA      14.76mA    28.17uA
-780mV    170.8uA    7.604mA    3.856uA
-720mV    16.71uA    2.018mA    195.3nA
-600mV    157.7nA    78.69uA    0A
0V        0A         56.62nA    0A
[Ramp]
| variable   typ   min   max
dV/dt_r  0.34635/12.77779n   95.18962m/30.40235n 0.55614/6.74798n
dV/dt_f  0.40279/16.13854n   91.98000m/40.72299n 0.61499/6.56990n
R_load = 50.000000
[Rising Waveform]
R_fixture= 50.000000
V_fixture= 1.200000
V_fixture_min= 0.900000
V_fixture_max= 1.320000
|time   V(typ)   V(min)   V(max)
0s        528.7mV    746.7mV    295mV
1.401ns   528.8mV    746.7mV    307.3mV
1.602ns   528.8mV    746.7mV    412.3mV
2.002ns   525.2mV    746.7mV    1.183V
2.402ns   557.9mV    746.7mV    1.302V
2.803ns   804.8mV    746.7mV    1.314V
3.403ns   1.163V     746.7mV    1.316V
4.404ns   1.196V     746.8mV    1.318V
10.81ns   1.199V     897.8mV    1.319V
99.7ns    1.2V       900mV      1.32V
[Rising Waveform]
R_fixture= 50.000000
V_fixture= 0.0
V_fixture_min= 0.0
V_fixture_max= 0.0
|time   V(typ)   V(min)   V(max)
0s        2.345nV    636.2nV    922.7pV
2.002ns   224.7uV    217.4nV    -23.05mV
6.006ns   -592.6uV   -216.6uV   26.06mV
12.01ns   59.41mV    -362.8uV   552.7mV
16.02ns   194.6mV    -75.36uV   795.6mV
24.02ns   421.1mV    386uV      909.7mV
32.03ns   522.7mV    9.872mV    924.1mV
70.07ns   576.7mV    128mV      926.9mV
106.1ns   577.1mV    155.7mV    926.9mV
997ns     577.3mV    158.7mV    926.9mV
[Falling Waveform]
R_fixture= 50.000000
V_fixture= 1.200000
V_fixture_min= 0.900000
V_fixture_max= 1.320000
|time   V(typ)   V(min)   V(max)
0s        1.2V       900mV      1.32V
6.006ns   1.201V     901.1mV    1.32V
10.01ns   1.2V       901.1mV    1.207V
16.02ns   1.179V     900.2mV    628.8mV
20.02ns   1.101V     900mV      419.2mV
30.03ns   789.7mV    900mV      323.3mV
38.04ns   655.2mV    898.5mV    305.1mV
64.06ns   545.2mV    850.5mV    295.6mV
148.1ns   528.7mV    752mV      295mV
997ns     528.7mV    746.7mV    295mV
[Falling Waveform]
R_fixture= 50.000000
V_fixture= 0.0
V_fixture_min= 0.0
V_fixture_max= 0.0
|time   V(typ)   V(min)   V(max)
0s        577.3mV    158.7mV    926.9mV
800.8ps   577.4mV    158.7mV    930mV
1.361ns   584.1mV    158.7mV    435.1mV
1.762ns   384.9mV    158.7mV    185.2mV
2.162ns   225.6mV    158.7mV    52.33mV
2.723ns   100.3mV    158.7mV    9.14mV
3.844ns   7.692mV    133.9mV    2.144mV
5.606ns   1.315mV    45.49mV    1.385mV
8.729ns   549uV      4.482mV    1.201mV
39.88ns   2.345nV    636.2nV    922.7pV
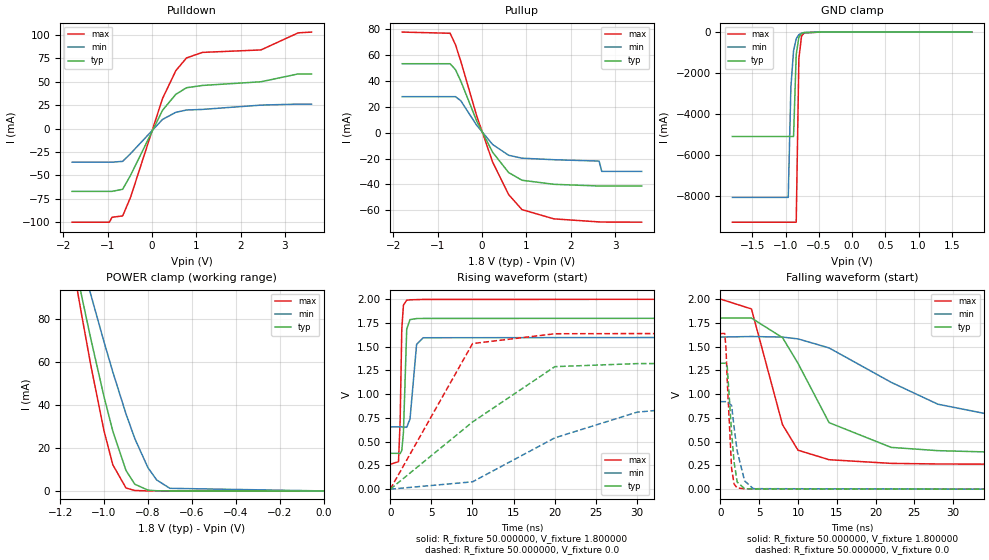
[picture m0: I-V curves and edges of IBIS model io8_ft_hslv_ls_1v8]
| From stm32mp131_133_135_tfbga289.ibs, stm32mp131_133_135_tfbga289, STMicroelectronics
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|   Model io8_ft_hslv_ls_1v8
[Model]  io8_ft_hslv_ls_1v8
Model_type I/O
Polarity   Non-Inverting
Enable   Active-Low
Vinl =   0.540000V
Vinh =   1.260000V
Vmeas =  0.900000V
Cref =   50.000000pF
Rref =   100.000000M
Vref =   0.0V
C_comp   3.156400pF   3.140600pF   3.186200pF
[Temperature Range]   25.000000   0.140000k   -40.000000
[Pullup Reference]   1.800000V   1.600000V   2.000000V
[Pulldown Reference]   0.0V   0.0V   0.0V
[POWER Clamp Reference]   1.800000V   1.600000V   2.000000V
[GND Clamp Reference]   0.0V   0.0V   0.0V
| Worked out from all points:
|   slope of the pulldown table from 0 to 0.27 V, typ, clamps not added: 12.5 ohm
|   slope of the pullup table from 0 to 0.27 V, typ, clamps not added: 16 ohm
|   GND clamp passes 1 mA (typ) near -0.47 V on its own axis
|   POWER clamp passes 1 mA (typ) near -0.83 V on its own axis
|   rising waveform, R_fixture 50.000000, V_fixture 1.800000: 20-80 % time 299ps typ, 482ps min, 244ps max; typ from 0.377 V to 1.8 V
|   rising waveform, R_fixture 50.000000, V_fixture 0.0: 20-80 % time 12.3ns typ, 15ns min, 6.42ns max; typ from 0 V to 1.32 V
|   falling waveform, R_fixture 50.000000, V_fixture 1.800000: 20-80 % time 5.97ns typ, 14.2ns min, 3.67ns max; typ from 1.8 V to 0.377 V
|   falling waveform, R_fixture 50.000000, V_fixture 0.0: 20-80 % time 726ps typ, 1.07ns min, 542ps max; typ from 1.32 V to 0 V
[Pulldown]
|Voltage   I(typ)   I(min)   I(max)
-1.8V     -67.09mA   -35.91mA   -100mA
-960mV    -67.09mA   -35.91mA   -100mA
-900mV    -67.09mA   -35.91mA   -94.73mA
-660mV    -64.86mA   -35.04mA   -93.29mA
-480mV    -49.73mA   -26.69mA   -73.15mA
240mV     19.58mA    9.766mA    32.18mA
540mV     36.57mA    17.36mA    61.85mA
780mV     43.58mA    19.8mA     75.41mA
1.14V     46.02mA    20.44mA    81.32mA
2.46V     49.96mA    25.03mA    83.95mA
3.3V      58.34mA    26.11mA    102.2mA
3.6V      58.34mA    26.11mA    103mA
[Pullup]
|Voltage   I(typ)   I(min)   I(max)
-1.8V     53.37mA    27.88mA    77.86mA
-720mV    53.37mA    27.88mA    76.95mA
-600mV    48.8mA     27.88mA    68.13mA
-480mV    39.99mA    24.74mA    55.38mA
-120mV    8.961mA    5.668mA    12.94mA
240mV     -15.24mA   -9.188mA   -22.87mA
600mV     -30.86mA   -17.49mA   -47.91mA
900mV     -36.82mA   -19.76mA   -59.55mA
1.62V     -39.97mA   -20.94mA   -66.73mA
2.64V     -41.3mA    -22mA      -69.09mA
2.7V      -41.3mA    -30mA      -69.18mA
3.6V      -41.3mA    -30mA      -69.3mA
[GND_clamp]
|Voltage   I(typ)   I(min)   I(max)
-1.8V     -5.08A     -8.044A    -9.251A
-960mV    -5.08A     -8.044A    -9.251A
-920mV    -5.08A     -2.669A    -9.251A
-880mV    -5.08A     -908mA     -9.251A
-840mV    -1.096A    -323.6mA   -9.251A
-800mV    -248.9mA   -123.7mA   -1.293A
-760mV    -64.81mA   -51.32mA   -196.6mA
-720mV    -22.13mA   -23.23mA   -39.69mA
-480mV    -1.149mA   -1.898mA   -936.1uA
1.8V      0A         44.33nA    0A
[POWER_clamp]
|Voltage   I(typ)   I(min)   I(max)
-1.8V     460.5mA    392.1mA    526.9mA
-1.12V    99.56mA    114.1mA    92.51mA
-1.1V     89.79mA    106.4mA    80.86mA
-1.06V    70.71mA    91.32mA    58.34mA
-1V       43.82mA    69.37mA    27.91mA
-960mV    27.85mA    55.39mA    12.18mA
-900mV    9.544mA    35.9mA     1.368mA
-860mV    3.133mA    24.42mA    203.6uA
-800mV    367uA      10.84mA    10.43uA
-760mV    78.93uA    5.095mA    1.426uA
-700mV    7.679uA    1.212mA    72.45nA
0V        0A         59.16nA    0A
[Ramp]
| variable   typ   min   max
dV/dt_r  0.79476/5.90039n   0.55238/13.48172n   0.98226/3.51185n
dV/dt_f  0.85363/5.80959n   0.56722/14.21745n   1.04297/3.35400n
R_load = 50.000000
[Rising Waveform]
R_fixture= 50.000000
V_fixture= 1.800000
V_fixture_min= 1.600000
V_fixture_max= 2.000000
|time   V(typ)   V(min)   V(max)
0s        377.3mV    654.6mV    261.7mV
1.001ns   377.2mV    654.7mV    289.1mV
1.201ns   374.4mV    654.7mV    716.1mV
1.401ns   406.2mV    654.8mV    1.684V
1.602ns   599.4mV    654.5mV    1.937V
2.002ns   1.685V     650.6mV    1.988V
2.402ns   1.784V     739.3mV    1.992V
3.203ns   1.795V     1.524V     1.994V
4.004ns   1.796V     1.593V     1.996V
99.7ns    1.8V       1.6V       2V
[Rising Waveform]
R_fixture= 50.000000
V_fixture= 0.0
V_fixture_min= 0.0
V_fixture_max= 0.0
|time   V(typ)   V(min)   V(max)
0s        2.004nV    378.7nV    939.1pV
10.01ns   707mV      77.34mV    1.532V
20.02ns   1.289V     540.1mV    1.635V
30.03ns   1.321V     810.3mV    1.637V
40.04ns   1.324V     888.6mV    1.637V
50.05ns   1.325V     911mV      1.637V
60.06ns   1.325V     918.2mV    1.637V
991ns     1.325V     920.6mV    1.637V
[Falling Waveform]
R_fixture= 50.000000
V_fixture= 1.800000
V_fixture_min= 1.600000
V_fixture_max= 2.000000
|time   V(typ)   V(min)   V(max)
0s        1.8V       1.6V       2V
4.004ns   1.8V       1.606V     1.896V
8.008ns   1.594V     1.6V       678.2mV
10.01ns   1.323V     1.581V     409.7mV
14.01ns   699.9mV    1.486V     309.9mV
22.02ns   439.5mV    1.124V     271.3mV
28.03ns   405.2mV    894mV      265mV
36.04ns   387.6mV    764.6mV    262.5mV
70.07ns   377.5mV    662.3mV    261.7mV
997ns     377.3mV    654.6mV    261.7mV
[Falling Waveform]
R_fixture= 50.000000
V_fixture= 0.0
V_fixture_min= 0.0
V_fixture_max= 0.0
|time   V(typ)   V(min)   V(max)
0s        1.325V     920.6mV    1.637V
560.6ps   1.325V     920.7mV    1.638V
720.7ps   1.328V     920.7mV    1.481V
880.9ps   1.289V     920.7mV    1.144V
1.441ns   598.3mV    881mV      221mV
1.762ns   287.1mV    653.6mV    54.58mV
2.162ns   75.49mV    401.6mV    12.93mV
3.123ns   4.704mV    86.65mV    4.01mV
4.244ns   2.241mV    5.196mV    3.424mV
39.88ns   2.004nV    378.7nV    939.1pV
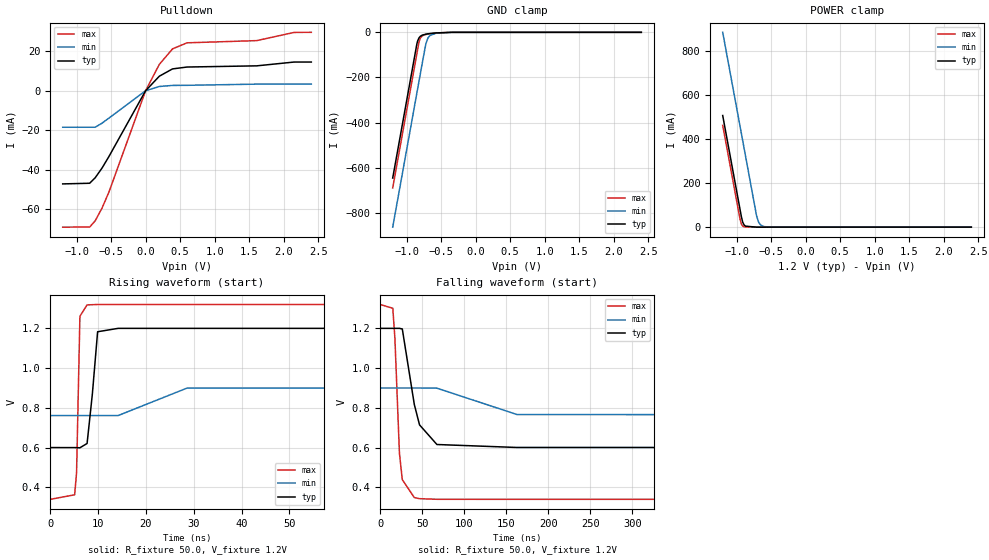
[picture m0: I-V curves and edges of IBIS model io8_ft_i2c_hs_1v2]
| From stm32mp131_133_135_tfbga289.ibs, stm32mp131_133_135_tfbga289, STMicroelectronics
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|   io8_ft_i2c_hs_1v2
[Model]   io8_ft_i2c_hs_1v2
Model_type I/O_open_drain
Polarity   Non-Inverting
Enable   Active-Low
| CAP_THRESHOLD on pad IOFT is "UDTCAPC" :
| Rising=20.0% of vddiom   Falling=80.0% of vddiom
| C_comp min and max val. don't necessarily correlate with the min and max pvt
| but are the smallest and greatest pad capacitance found.
| var   typ   min   max
C_comp   1.36950pF  1.28355pF  1.45130pF
Vinl = 360.0mV
Vinh = 840.0mV
Vmeas = 600.0mV   | Reference voltage for timing measurements
Cref  = 100.0nF   | Timing specification test load capacitance value
Rref  = 1.0kOhm   | Timing specification test load resistance value
Vref  = 600.1mV   | Timing specification test load voltage
[Model Spec]
| TIME_THRESHOLD on pin ZIV11 is "CMOS" :
| Rising=40.0% of vdd   Falling=60.0% of vdd
Vinl 465.80000mV 358.80000mV 518.80000mV
Vinh 741.20000mV 543.20000mV 820.20000mV
| variable   typ   min   max
[Temperature Range] 25.0 140.0 -40.0
| variable   typ   min   max
[Voltage Range] 1.2V 900.0mV 1.32V
| variable   typ   min   max
[POWER Clamp Reference] 1.2V 900.0mV 1.32V
| variable   typ   min   max
[GND Clamp Reference] 0V 0V 0V
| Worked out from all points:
|   slope of the pulldown table from 0 to 0.18 V, typ, clamps not added: 26.5 ohm
|   GND clamp passes 1 mA (typ) near -0.49 V on its own axis
|   POWER clamp passes 1 mA (typ) near -0.83 V on its own axis
|   rising waveform, R_fixture 50.0, V_fixture 1.2V: 20-80 % time 937ps typ, 3.09ns min, 434ps max; typ from 0.6 V to 1.2 V
|   falling waveform, R_fixture 50.0, V_fixture 1.2V: 20-80 % time 14ns typ, 37.2ns min, 5.71ns max; typ from 1.2 V to 0.601 V
[POWER Clamp]
-1.2V     507mA      884.8mA    462.5mA
-950mV    82mA       459.8mA    37.51mA
-930mV    48mA       425.8mA    13.86mA
-910mV    22.04mA    391.8mA    5.123mA
-890mV    10.12mA    357.8mA    1.893mA
-870mV    4.646mA    323.8mA    699.7uA
-710mV    9.171uA    51.95mA    243.5nA
-680mV    2.852uA    22.37mA    54.74nA
-650mV    886.6nA    9.63mA     12.33nA
-600mV    125.8nA    2.365mA    1.054nA
-490mV    1.049nA    108uA      41.48pA
2.4V      0A         0A         0A
[GND Clamp]
-1.2V     -646.3mA   -864.2mA   -690.1mA
-850mV    -51.35mA   -269.2mA   -95.05mA
-840mV    -39.26mA   -252.2mA   -78.05mA
-820mV    -24.85mA   -218.2mA   -44.05mA
-800mV    -17.5mA    -184.2mA   -25.22mA
-770mV    -12.13mA   -133.2mA   -15.02mA
-720mV    -8.143mA   -50.86mA   -9.665mA
-690mV    -6.656mA   -25.2mA    -7.855mA
-660mV    -5.424mA   -13.63mA   -6.324mA
-570mV    -2.602mA   -3.787mA   -2.765mA
-350mV    -41.28uA   -263.5uA   -8.566uA
2.4V      4.788nA    1.261uA    272.6pA
| variable   typ   min   max
[Pullup Reference] 1.2V 900.0mV 1.32V
| variable   typ   min   max
[Pulldown Reference] 0V 0V 0V
[Pulldown]
-1.2V     -47.11mA   -18.46mA   -68.98mA
-810mV    -46.78mA   -18.46mA   -68.93mA
-730mV    -44.02mA   -18.46mA   -65.79mA
-630mV    -39.07mA   -16.4mA    -59.3mA
-530mV    -33.22mA   -13.8mA    -51.19mA
0V        0A         0A         1fA
200mV     7.375mA    2.155mA    13.36mA
390mV     11.04mA    2.691mA    21.16mA
600mV     11.99mA    2.746mA    24.23mA
1.61V     12.59mA    3.342mA    25.35mA
2.15V     14.51mA    3.342mA    29.49mA
2.4V      14.51mA    3.342mA    29.54mA
[Ramp]
dV/dt_r 359.7803mV/936.25418ps 83.02702mV/3.08549ns 587.93904mV/433.07975ps
dV/dt_f 359.28377mV/14.03786ns 82.9748mV/37.17162ns 587.93924mV/5.7085ns
R_load = 50.0
| Removed startup time: 0s 0s 0s  .
| Removed end time: 2.1994us.
[Rising Waveform]
R_fixture   = 50.0
V_fixture   = 1.2V
V_fixture_min = 900.0mV
V_fixture_max = 1.32V
0s        600.4mV    761.6mV    340.1mV
5.1ns     600.3mV    761.6mV    362.9mV
5.5ns     600.2mV    761.6mV    474.7mV
6.2ns     599.3mV    761.6mV    1.261V
7.7ns     621.1mV    761.6mV    1.318V
8.8ns     868.9mV    761.6mV    1.319V
9.9ns     1.183V     761.5mV    1.32V
14.2ns    1.2V       761.5mV    1.32V
28.6ns    1.2V       899.6mV    1.32V
2.199us   1.2V       900mV      1.32V
| Removed startup time: 0s 0s 0s  .
| Removed end time: 2.1994us.
[Falling Waveform]
R_fixture   = 50.0
V_fixture   = 1.2V
V_fixture_min = 900.0mV
V_fixture_max = 1.32V
0s        1.2V       900mV      1.32V
14.9ns    1.2V       900mV      1.301V
17.4ns    1.2V       900mV      1.151V
22.8ns    1.2V       900mV      572.3mV
26.2ns    1.197V     900mV      439mV
40.5ns    817.1mV    900mV      349mV
46.7ns    714.6mV    900mV      343.4mV
67.4ns    615.8mV    899.2mV    340.3mV
162.7ns   600.9mV    766.6mV    340.1mV
2.199us   601.2mV    761.7mV    340.1mV
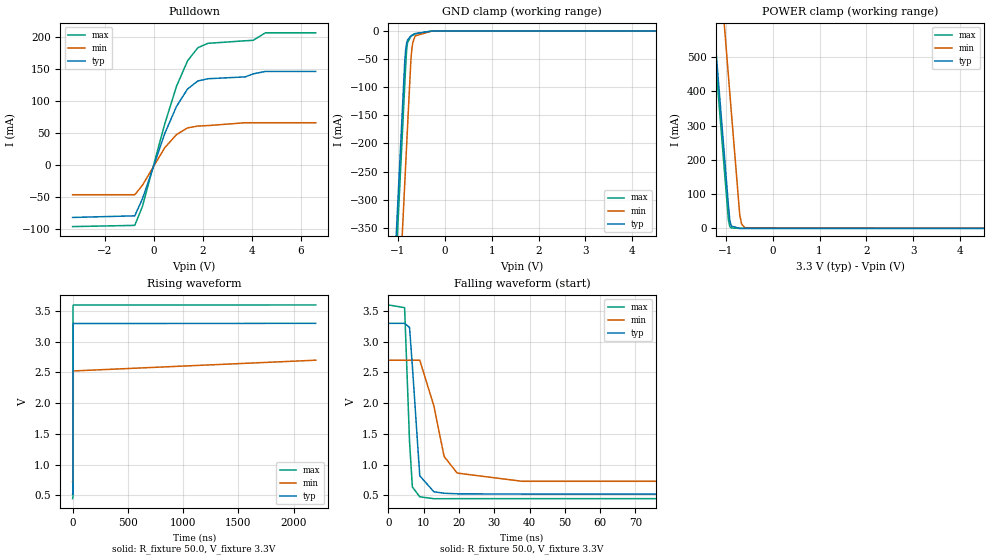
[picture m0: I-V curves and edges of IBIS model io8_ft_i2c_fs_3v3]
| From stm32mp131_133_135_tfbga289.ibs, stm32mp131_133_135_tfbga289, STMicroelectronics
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|   io8_ft_i2c_fs_3v3
[Model]   io8_ft_i2c_fs_3v3
Model_type I/O_open_drain
Polarity   Non-Inverting
Enable   Active-Low
| CAP_THRESHOLD on pad IOFT is "UDTCAPC" :
| Rising=20.0% of vddiom   Falling=80.0% of vddiom
| C_comp min and max val. don't necessarily correlate with the min and max pvt
| but are the smallest and greatest pad capacitance found.
| var   typ   min   max
C_comp   1.34042pF  1.15520pF  1.54320pF
Vinl = 990.0mV
Vinh = 2.31V
Vmeas = 1.65V   | Reference voltage for timing measurements
Cref  = 100.0nF   | Timing specification test load capacitance value
Rref  = 1.0kOhm   | Timing specification test load resistance value
Vref  = 1.6501V   | Timing specification test load voltage
[Model Spec]
| TIME_THRESHOLD on pin ZIV11 is "CMOS" :
| Rising=40.0% of vdd   Falling=60.0% of vdd
Vinl 1.34180V 1.13180V 1.44880V
Vinh 1.68120V 1.43520V 1.78820V
| variable   typ   min   max
[Temperature Range] 25.0 140.0 -40.0
| variable   typ   min   max
[Voltage Range] 3.3V 2.7V 3.6V
| variable   typ   min   max
[POWER Clamp Reference] 3.3V 2.7V 3.6V
| variable   typ   min   max
[GND Clamp Reference] 0V 0V 0V
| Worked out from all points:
|   slope of the pulldown table from 0 to 0.495 V, typ, clamps not added: 9.3 ohm
|   GND clamp passes 1 mA (typ) near -0.49 V on its own axis
|   POWER clamp passes 1 mA (typ) near -0.83 V on its own axis
|   rising waveform, R_fixture 50.0, V_fixture 3.3V: 20-80 % time 285ps typ, 435ps min, 261ps max; typ from 0.519 V to 3.3 V
|   falling waveform, R_fixture 50.0, V_fixture 3.3V: 20-80 % time 1.76ns typ, 4.19ns min, 1.17ns max; typ from 3.3 V to 0.519 V
[POWER Clamp]
-3.3V     4.077A     4.455A     4.033A
-1.46V    949mA      1.327A     904.5mA
-1.27V    626mA      1.004A     581.5mA
-1.26V    609mA      986.8mA    564.5mA
-1.03V    218mA      595.8mA    173.5mA
-940mV    65mA       442.8mA    22.8mA
-910mV    22.04mA    391.8mA    5.123mA
-880mV    6.856mA    340.8mA    1.151mA
-700mV    6.214uA    39.22mA    148.1nA
-660mV    1.31uA     12.75mA    20.31nA
-590mV    85.8nA     1.786mA    712.7pA
6.6V      0A         0A         0A
[GND Clamp]
-3.3V     -4.218A    -4.435A    -4.26A
-1.1V     -477.8mA   -695.1mA   -520mA
-850mV    -52.79mA   -270.1mA   -95.04mA
-830mV    -31.95mA   -236.1mA   -61.04mA
-810mV    -21.49mA   -202.1mA   -32.57mA
-790mV    -15.94mA   -168.1mA   -20.48mA
-720mV    -8.551mA   -51.68mA   -9.742mA
-700mV    -7.47mA    -32.3mA    -8.496mA
-680mV    -6.53mA    -20.95mA   -7.399mA
-630mV    -4.559mA   -8.621mA   -5.037mA
-270mV    -2.277uA   -52.49uA   -181.4nA
6.6V      13.05nA    3.22uA     779pA
| variable   typ   min   max
[Pullup Reference] 3.3V 2.7V 3.6V
| variable   typ   min   max
[Pulldown Reference] 0V 0V 0V
[Pulldown]
-3.3V     -81.92mA   -46.49mA   -96.17mA
-770mV    -79.41mA   -46.49mA   -94.28mA
-460mV    -53.18mA   -31.87mA   -65.04mA
450mV     48.74mA    26.76mA    63.75mA
930mV     91.28mA    47.31mA    122.6mA
1.38V     118.4mA    57.78mA    162.3mA
1.8V      130.9mA    60.6mA     182.8mA
2.21V     134.4mA    61.34mA    189.6mA
3.73V     137.3mA    65.79mA    193.6mA
4.05V     142mA      65.79mA    194.3mA
4.55V     145.8mA    65.79mA    206mA
6.6V      145.8mA    65.79mA    206mA
[Ramp]
dV/dt_r 1.66844V/278.46617ps 1.18658V/429.88362ps 1.89295V/253.04391ps
dV/dt_f 1.66844V/1.7575ns 1.18658V/4.19342ns 1.89295V/1.17033ns
R_load = 50.0
| Removed startup time: 0s 0s 0s  .
| Removed end time: 2.1994us.
[Rising Waveform]
R_fixture   = 50.0
V_fixture   = 3.3V
V_fixture_min = 2.7V
V_fixture_max = 3.6V
0s        519.3mV    722.4mV    445.1mV
3.1ns     518.7mV    722.4mV    473.2mV
3.3ns     516.8mV    722.4mV    933mV
3.6ns     555.1mV    722.3mV    3.098V
3.9ns     1.084V     722.1mV    3.546V
4.2ns     2.84V      721.7mV    3.586V
4.3ns     3.089V     721.6mV    3.589V
5.3ns     3.294V     951.9mV    3.596V
6ns       3.297V     2.525V     3.598V
2.199us   3.3V       2.7V       3.6V
| Removed startup time: 0s 0s 0s  .
| Removed end time: 2.1994us.
[Falling Waveform]
R_fixture   = 50.0
V_fixture   = 3.3V
V_fixture_min = 2.7V
V_fixture_max = 3.6V
0s        3.3V       2.7V       3.6V
4.6ns     3.3V       2.7V       3.556V
6ns       3.233V     2.7V       1.376V
6.8ns     2.608V     2.7V       635.6mV
8.9ns     816.6mV    2.7V       475.1mV
12.9ns    557.1mV    1.955V     444.5mV
15.8ns    533.2mV    1.132V     444.3mV
19.5ns    524mV      861.5mV    444.8mV
37.9ns    519.3mV    727.7mV    445.1mV
2.199us   519.3mV    722.4mV    445.1mV
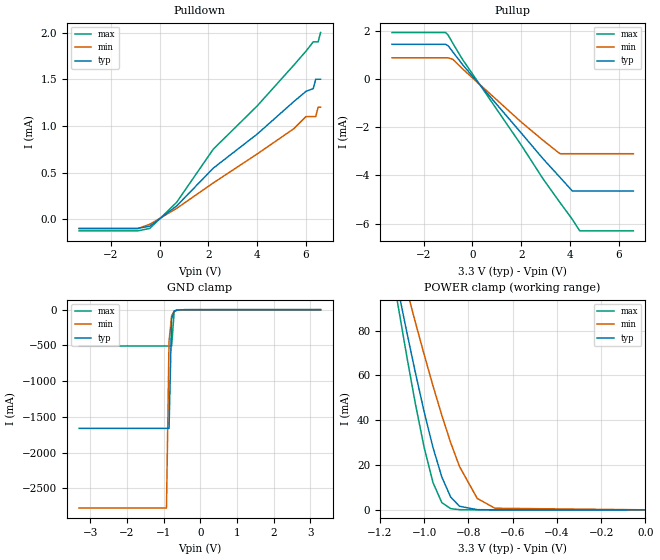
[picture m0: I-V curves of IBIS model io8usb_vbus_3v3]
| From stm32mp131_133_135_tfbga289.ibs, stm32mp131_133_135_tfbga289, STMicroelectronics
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|   Model io8usb_vbus_3v3
[Model]  io8usb_vbus_3v3
Model_type I/O
Polarity   Non-Inverting
Enable   Active-High
Vinl =   0.990000V
Vinh =   2.310000V
Vmeas =  1.650000V
Cref =   50.000000pF
Rref =   100.000000M
Vref =   0.0V
C_comp   3.902700pF   3.901500pF   3.914800pF
[Temperature Range]   25.000000   0.140000k   -40.000000
[Pullup Reference]   3.300000V   2.700000V   3.600000V
[Pulldown Reference]   0.0V   0.0V   0.0V
[POWER Clamp Reference]   3.300000V   2.700000V   3.600000V
[GND Clamp Reference]   0.0V   0.0V   0.0V
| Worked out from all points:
|   slope of the pulldown table from 0 to 0.495 V, typ, clamps not added: 5.1 kohm
|   slope of the pullup table from 0 to 0.495 V, typ, clamps not added: 860 ohm
|   GND clamp passes 1 mA (typ) near -0.46 V on its own axis
|   POWER clamp passes 1 mA (typ) near -0.82 V on its own axis
[Pulldown]
|Voltage   I(typ)   I(min)   I(max)
-3.3V     -96uA      -100uA     -123uA
-900mV    -96uA      -100uA     -123uA
-400mV    -73.4uA    -51.72uA   -96.68uA
700mV     144.1uA    117.9uA    183.5uA
2.2V      548.1uA    390uA      751.2uA
4V        912.7uA    700uA      1.214mA
5.5V      1.26mA     970uA      1.65mA
6V        1.37mA     1.1mA      1.8mA
6.3V      1.4mA      1.1mA      1.9mA
6.4V      1.5mA      1.1mA      1.9mA
6.5V      1.5mA      1.2mA      1.9mA
6.6V      1.5mA      1.2mA      2mA
[Pullup]
|Voltage   I(typ)   I(min)   I(max)
-3.3V     1.436mA    879uA      1.927mA
-1.1V     1.436mA    879uA      1.927mA
-1V       1.383mA    879uA      1.827mA
-800mV    1.12mA     813uA      1.475mA
-400mV    590.8uA    414.8uA    802.3uA
2V        -2.239mA   -1.786mA   -2.738mA
2.9V      -3.315mA   -2.548mA   -4.148mA
3.5V      -3.98mA    -3.03mA    -4.998mA
3.6V      -4.09mA    -3.1mA     -5.137mA
4.1V      -4.65mA    -3.1mA     -5.827mA
4.4V      -4.65mA    -3.1mA     -6.3mA
6.6V      -4.65mA    -3.1mA     -6.3mA
[GND_clamp]
|Voltage   I(typ)   I(min)   I(max)
-3.3V     -1.662A    -2.777A    -508.4mA
-920mV    -1.662A    -2.777A    -508.4mA
-850mV    -1.662A    -441.8mA   -508.4mA
-780mV    -129mA     -87.56mA   -508.4mA
-710mV    -18.66mA   -22.27mA   -28.79mA
-640mV    -7.04mA    -7.478mA   -7.491mA
-430mV    -483.3uA   -1.241mA   -292.5uA
3.28V     0A         49.83nA    0A
[POWER_clamp]
|Voltage   I(typ)   I(min)   I(max)
-3.28V    1.28A      1.024A     1.509A
-1.12V    99.56mA    114.1mA    92.51mA
-1.08V    80.16mA    98.83mA    69.45mA
-1.04V    61.47mA    83.9mA     47.62mA
-1V       43.82mA    69.37mA    27.91mA
-960mV    27.85mA    55.39mA    12.18mA
-920mV    14.63mA    42.15mA    3.226mA
-880mV    5.71mA     29.97mA    537.4uA
-840mV    1.599mA    19.32mA    75.95uA
-760mV    78.93uA    5.095mA    1.427uA
-680mV    3.529uA    713.7uA    37.26nA
0V        0A         68.58nA    0A
[Ramp]
| variable   typ   min   max
dV/dt_r  0.10687/1.50810n   68.66910m/2.93589n  0.14407/1.12599n
dV/dt_f  19.32000m/1.19881n  12.84000m/1.99221n  26.82000m/1.00808n
R_load = 50.000000
|End [Model] io8usb_vbus_3v3
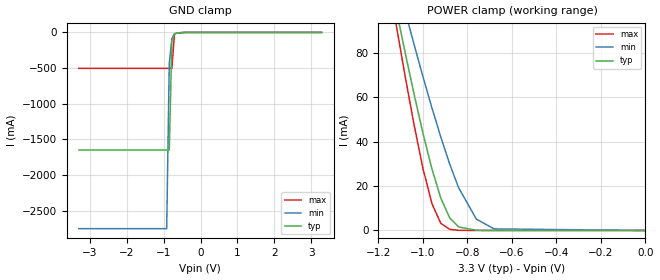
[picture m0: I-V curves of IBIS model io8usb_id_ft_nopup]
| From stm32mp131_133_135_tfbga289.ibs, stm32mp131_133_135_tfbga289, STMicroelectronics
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|   Model io8usb_id_ft_nopup
[Model]  io8usb_id_ft_nopup
Model_type Input
Polarity   Non-Inverting
Vinl =   0.990000V
Vinh =   2.310000V
C_comp   3.385500pF   3.380900pF   3.405500pF
[Temperature Range]   25.000000   0.140000k   -40.000000
[Pullup Reference]   3.300000V   2.700000V   3.600000V
[Pulldown Reference]   0.0V   0.0V   0.0V
[POWER Clamp Reference]   3.300000V   2.700000V   3.600000V
[GND Clamp Reference]   0.0V   0.0V   0.0V
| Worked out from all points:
|   GND clamp passes 1 mA (typ) near -0.46 V on its own axis
|   POWER clamp passes 1 mA (typ) near -0.82 V on its own axis
[GND_clamp]
|Voltage   I(typ)   I(min)   I(max)
-3.3V     -1.648A    -2.751A    -503.9mA
-920mV    -1.648A    -2.751A    -503.9mA
-850mV    -1.648A    -437.6mA   -503.9mA
-780mV    -127.7mA   -86.69mA   -503.9mA
-710mV    -18.39mA   -21.99mA   -28.41mA
-640mV    -6.939mA   -7.349mA   -7.384mA
-430mV    -466.9uA   -1.207mA   -281.8uA
3.28V     0A         -31.43nA   -31.97nA
[POWER_clamp]
|Voltage   I(typ)   I(min)   I(max)
-3.28V    1.28A      1.024A     1.509A
-1.12V    99.56mA    114.1mA    92.51mA
-1.08V    80.16mA    98.83mA    69.45mA
-1.04V    61.47mA    83.9mA     47.62mA
-1V       43.82mA    69.37mA    27.91mA
-960mV    27.85mA    55.39mA    12.18mA
-920mV    14.63mA    42.15mA    3.226mA
-880mV    5.71mA     29.97mA    537.4uA
-840mV    1.599mA    19.32mA    75.95uA
-760mV    78.93uA    5.095mA    1.427uA
-680mV    3.529uA    713.7uA    70.04nA
0V        0A         70.49nA    0A
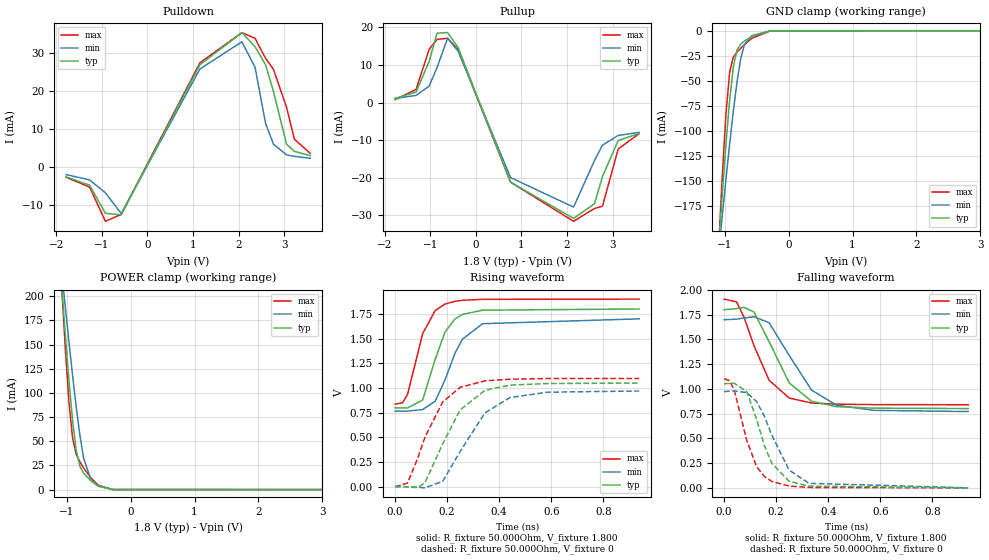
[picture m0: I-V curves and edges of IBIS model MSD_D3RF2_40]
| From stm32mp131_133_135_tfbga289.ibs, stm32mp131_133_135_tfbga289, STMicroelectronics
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[Model] MSD_D3RF2_40
Model_type   I/O
C_comp 2.228pF   2.149pF   2.345pF
Vinh = 1.150V
Vinl = 650.000mV
Vmeas = 900.000mV
Vref = 900.000mV
[Model Spec]
Vinh   1.150V   1.100V   1.200V
Vinl   650.000mV   600.000mV   700.000mV
Vmeas   900.000mV   850.000mV   950.000mV
Vref   900.000mV   850.000mV   950.000mV
[Temperature Range]   25.000   125.000   -40.000
[Voltage Range]   1.800V   1.700V   1.900V
[GND Clamp Reference]   0.00V   0.00V   0.00V
[Pulldown Reference]   0.00V   0.00V   0.00V
[POWER Clamp Reference]   1.800V   1.700V   1.900V
[Pullup Reference]   1.800V   1.700V   1.900V
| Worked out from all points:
|   slope of the pulldown table from 0 to 0.27 V, typ, clamps not added: 37.2 ohm
|   slope of the pullup table from 0 to 0.27 V, typ, clamps not added: 29.4 ohm
|   GND clamp passes 1 mA (typ) near -0.41 V on its own axis
|   POWER clamp passes 1 mA (typ) near -0.41 V on its own axis
|   rising waveform, R_fixture 50.000Ohm, V_fixture 1.800: 20-80 % time 75.4ps typ, 92ps min, 68ps max; typ from 0.798 V to 1.8 V
|   rising waveform, R_fixture 50.000Ohm, V_fixture 0: 20-80 % time 120ps typ, 138ps min, 111ps max; typ from 0.001 V to 1.05 V
|   falling waveform, R_fixture 50.000Ohm, V_fixture 1.800: 20-80 % time 115ps typ, 134ps min, 101ps max; typ from 1.8 V to 0.801 V
|   falling waveform, R_fixture 50.000Ohm, V_fixture 0: 20-80 % time 83.6ps typ, 100ps min, 73.1ps max; typ from 1.05 V to 0 V
[GND Clamp]
-1.785V   -901.2mA   -688.7mA   -1.21A
-1.094V   -214.6mA   -220.9mA   -215.3mA
-1.036V   -161.8mA   -183.6mA   -143.3mA
-978.8mV  -112.2mA   -147.3mA   -82mA
-921.2mV  -68.48mA   -112.3mA   -40.93mA
-863.6mV  -35.72mA   -79.61mA   -26.14mA
-806.1mV  -18.98mA   -50.61mA   -21.24mA
-748.5mV  -13.21mA   -27.8mA    -17.43mA
-690.9mV  -10.21mA   -13.79mA   -13.87mA
-575.8mV  -5.519mA   -4.737mA   -7.464mA
-287.9mV  -70.53uA   -119uA     -55.71uA
3.57V     33.94nA    572.8nA    3.717nA
[Power Clamp]
-1.77V    882.6mA    689.8mA    1.159A
-1.079V   212.4mA    226.5mA    212.1mA
-1.021V   160.9mA    189.3mA    146.7mA
-963.6mV  112.9mA    152.9mA    90.89mA
-906.1mV  71.15mA    117.8mA    52.89mA
-848.5mV  40.01mA    84.75mA    36.15mA
-790.9mV  23.77mA    55.41mA    28.47mA
-733.3mV  16.96mA    32.2mA     22.3mA
-618.2mV  8.941mA    9.722mA    11.92mA
-503mV    3.409mA    3.507mA    4.442mA
-272.7mV  29.94uA    100.2uA    29.64uA
3.585V    -51.59nA   -929.3nA   -5.523nA
[Pulldown]
-1.785V   -2.6mA     -2mA       -2.7mA
-1.267V   -4.8mA     -3.4mA     -5.3mA
-921.2mV  -12.19mA   -6.8mA     -14.29mA
-575.8mV  -12.6mA    -12.24mA   -12.48mA
1.152V    26.92mA    25.79mA    27.42mA
2.073V    35.36mA    32.95mA    35.37mA
2.361V    31.62mA    26.21mA    33.85mA
2.591V    26.91mA    11.5mA     28.61mA
2.764V    19.9mA     6mA        25.7mA
3.052V    6mA        3.2mA      15.7mA
3.224V    4.1mA      2.8mA      7.3mA
3.57V     3mA        2.3mA      3.6mA
[Pullup]
-1.77V    1.1mA      1.1mA      773.7uA
-1.309V   2.8mA      1.921mA    3.516mA
-1.021V   11mA       4.389mA    14.22mA
-848.5mV  18.49mA    9.339mA    16.82mA
-618.2mV  18.64mA    17.12mA    17.12mA
-387.9mV  14.68mA    13.71mA    14.14mA
763.6mV   -21.21mA   -19.96mA   -21.18mA
2.145V    -30.84mA   -27.83mA   -31.61mA
2.606V    -26.91mA   -15.4mA    -28.18mA
2.779V    -19.7mA    -11.34mA   -27.6mA
3.124V    -10.1mA    -8.753mA   -12.36mA
3.585V    -8.2mA     -7.926mA   -8.247mA
[Ramp]
R_load=50.000Ohm
dV/dt_r   614.460mV/98.500ps  569.819mV/115.500ps  646.950mV/90.000ps
dV/dt_f   614.460mV/100.000ps  569.819mV/118.500ps  646.950mV/88.000ps
[Rising waveform]
R_fixture=50.000Ohm
V_fixture=1.800
V_fixture_min=1.700
V_fixture_max=1.900
0s        798.1mV    765.1mV    835.3mV
29ps      796.5mV    764.3mV    849mV
48ps      796.6mV    764.7mV    933.3mV
106ps     876.7mV    780.2mV    1.55V
154ps     1.288V     864.3mV    1.783V
192ps     1.567V     1.081V     1.85V
230ps     1.698V     1.351V     1.878V
259ps     1.745V     1.494V     1.888V
336ps     1.788V     1.651V     1.898V
938ps     1.8V       1.7V       1.9V
[Rising waveform]
R_fixture=50.000Ohm
V_fixture=0
0s        680.8uV    673.2uV    -3.341mV
48ps      -4.502mV   -1.464mV   35.27mV
87ps      -11.24mV   -7.271mV   286.5mV
115ps     40.22mV    -13.72mV   501mV
183ps     432.4mV    52.48mV    856.8mV
250ps     776.3mV    355.3mV    1.006V
345ps     975.4mV    746.1mV    1.071V
441ps     1.028V     901.7mV    1.088V
585ps     1.044V     956.3mV    1.095V
938ps     1.049V     968.6mV    1.096V
[Falling waveform]
R_fixture=50.000Ohm
V_fixture=1.800
V_fixture_min=1.700
V_fixture_max=1.900
0s        1.799V     1.698V     1.906V
48ps      1.81V      1.704V     1.878V
77ps      1.823V     1.715V     1.721V
115ps     1.775V     1.728V     1.435V
173ps     1.477V     1.668V     1.087V
250ps     1.061V     1.338V     907mV
336ps     874.3mV    987.4mV    856.8mV
432ps     820mV      834.9mV    844.9mV
575ps     805mV      782.8mV    840.6mV
938ps     800.8mV    770.5mV    839.4mV
[Falling waveform]
R_fixture=50.000Ohm
V_fixture=0
0s        1.051V     972.7mV    1.102V
20ps      1.055V     975.9mV    1.084V
39ps      1.057V     978.6mV    990.5mV
87ps      972.9mV    962.1mV    480.3mV
125ps     692.9mV    871.3mV    214.9mV
154ps     433.2mV    728.2mV    117.2mV
183ps     249.2mV    535mV      65.56mV
250ps     66.91mV    178.6mV    18.15mV
326ps     17.47mV    45.87mV    4.36mV
938ps     12.79uV    22.79uV    -548nV
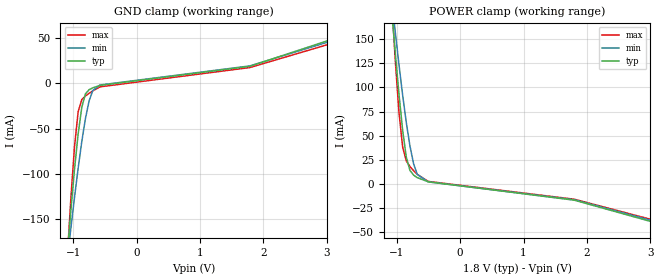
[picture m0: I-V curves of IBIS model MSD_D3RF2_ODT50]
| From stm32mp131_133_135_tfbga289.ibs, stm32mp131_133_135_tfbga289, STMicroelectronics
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[Model] MSD_D3RF2_ODT50
Model_type   Input
C_comp 2.137pF   2.101pF   2.161pF
Vinh = 1.150V
Vinl = 650.000mV
[Temperature Range]   25.000   125.000   -40.000
[Voltage Range]   1.800V   1.700V   1.900V
[GND Clamp Reference]   0.00V   0.00V   0.00V
[POWER Clamp Reference]   1.800V   1.700V   1.900V
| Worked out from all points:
|   GND clamp passes 1 mA (typ) near -0.51 V on its own axis
|   POWER clamp passes 1 mA (typ) near -0.36 V on its own axis
[GND Clamp]
-1.785V   -857.9mA   -648mA     -1.167A
-1.094V   -190.2mA   -195.8mA   -194.3mA
-1.036V   -140.6mA   -160.4mA   -127.3mA
-978.8mV  -95.2mA    -126.3mA   -70.24mA
-921.2mV  -55.93mA   -93.89mA   -31.36mA
-863.6mV  -26.43mA   -64.25mA   -17.75mA
-806.1mV  -11.49mA   -38.75mA   -13.78mA
-748.5mV  -6.856mA   -19.33mA   -10.89mA
-690.9mV  -4.834mA   -7.894mA   -8.224mA
-575.8mV  -2.08mA    -1.648mA   -3.72mA
1.785V    18.98mA    19.43mA    17.59mA
3.57V     60.15mA    57.63mA    54.49mA
[Power Clamp]
-1.77V    824.9mA    636.5mA    1.105A
-1.079V   181mA      191.5mA    188.8mA
-1.021V   134.9mA    156.8mA    126.8mA
-963.6mV  92.62mA    123.4mA    73.67mA
-906.1mV  55.4mA     91.94mA    38.12mA
-848.5mV  27.54mA    63.44mA    23.6mA
-790.9mV  13.74mA    39.09mA    17.85mA
-733.3mV  8.908mA    20.68mA    13.48mA
-675.8mV  6.312mA    9.71mA     9.711mA
-503mV    1.984mA    1.889mA    2.393mA
1.8V      -17.11mA   -16.63mA   -16.13mA
3.585V    -49.91mA   -48.31mA   -47.06mA
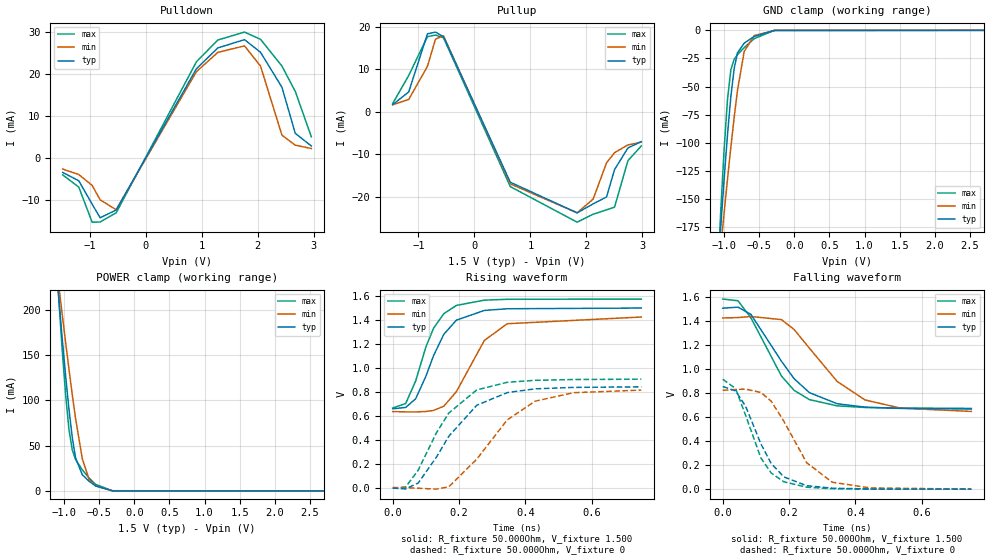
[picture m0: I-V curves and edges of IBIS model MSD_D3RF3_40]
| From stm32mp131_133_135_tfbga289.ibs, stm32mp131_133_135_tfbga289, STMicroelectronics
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[Model] MSD_D3RF3_40
Model_type   I/O
C_comp 2.240pF   2.160pF   2.357pF
Vinh = 925.000mV
Vinl = 575.000mV
Vmeas = 750.000mV
Vref = 750.000mV
[Model Spec]
Vinh   925.000mV   888.000mV   963.000mV
Vinl   575.000mV   538.000mV   613.000mV
Vmeas   750.000mV   713.000mV   788.000mV
Vref   750.000mV   713.000mV   788.000mV
[Temperature Range]   25.000   125.000   -40.000
[Voltage Range]   1.500V   1.425V   1.575V
[GND Clamp Reference]   0.00V   0.00V   0.00V
[Pulldown Reference]   0.00V   0.00V   0.00V
[POWER Clamp Reference]   1.500V   1.425V   1.575V
[Pullup Reference]   1.500V   1.425V   1.575V
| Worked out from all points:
|   slope of the pulldown table from 0 to 0.225 V, typ, clamps not added: 36.6 ohm
|   slope of the pullup table from 0 to 0.225 V, typ, clamps not added: 31.2 ohm
|   GND clamp passes 1 mA (typ) near -0.40 V on its own axis
|   POWER clamp passes 1 mA (typ) near -0.41 V on its own axis
|   rising waveform, R_fixture 50.000Ohm, V_fixture 1.500: 20-80 % time 81.8ps typ, 98.2ps min, 72.2ps max; typ from 0.658 V to 1.5 V
|   rising waveform, R_fixture 50.000Ohm, V_fixture 0: 20-80 % time 133ps typ, 149ps min, 119ps max; typ from -0.004 V to 0.842 V
|   falling waveform, R_fixture 50.000Ohm, V_fixture 1.500: 20-80 % time 128ps typ, 153ps min, 113ps max; typ from 1.5 V to 0.667 V
|   falling waveform, R_fixture 50.000Ohm, V_fixture 0: 20-80 % time 87.9ps typ, 105ps min, 76.7ps max; typ from 0.854 V to 0 V
[GND Clamp]
-1.48V    -593.9mA   -479.7mA   -763.1mA
-1.098V   -218.2mA   -223.3mA   -220.2mA
-1.05V    -174.1mA   -192.4mA   -159.6mA
-1.002V   -131.9mA   -161.9mA   -105.2mA
-954.6mV  -92.83mA   -132.3mA   -61.52mA
-906.8mV  -59.01mA   -103.9mA   -35.13mA
-859.1mV  -33.79mA   -77.16mA   -25.62mA
-811.4mV  -19.9mA    -53.07mA   -21.61mA
-715.9mV  -11.4mA    -18.73mA   -15.39mA
-572.7mV  -5.41mA    -4.631mA   -7.313mA
-286.4mV  -67.53uA   -115uA     -52.79uA
2.959V    27.81nA    447.4nA    3.163nA
[Power Clamp]
-1.459V   577.6mA    479.2mA    722.9mA
-1.077V   211mA      225.5mA    210.2mA
-1.03V    168.2mA    194.7mA    155.6mA
-981.8mV  127.5mA    164.3mA    106.7mA
-934.1mV  90.48mA    134.7mA    68.25mA
-886.4mV  59mA       106.2mA    45.16mA
-838.6mV  36.16mA    79.4mA     34.6mA
-743.2mV  17.85mA    35.54mA    23.3mA
-647.7mV  10.74mA    12.83mA    14.33mA
-552.3mV  5.472mA    5.424mA    7.214mA
-313.6mV  99.23uA    231.1uA    112.6uA
2.98V     -43.92nA   -827nA     -4.179nA
[Pulldown]
-1.48V    -3.4mA     -2.6mA     -4mA
-1.193V   -5.4mA     -3.9mA     -6.9mA
-954.6mV  -10.97mA   -6.5mA     -15.27mA
-811.4mV  -14.22mA   -9.94mA    -15.22mA
-525mV    -12.36mA   -12.3mA    -13.03mA
906.8mV   21.31mA    20.61mA    22.96mA
1.289V    26.28mA    25.22mA    28.17mA
1.766V    28.26mA    26.77mA    30.06mA
2.052V    25.24mA    21.95mA    28.34mA
2.434V    16.92mA    5.5mA      21.96mA
2.673V    5.9mA      3.1mA      15.9mA
2.959V    2.9mA      2.3mA      5.1mA
[Pullup]
-1.459V   1.7mA      1.657mA    1.971mA
-1.173V   4.7mA      2.929mA    8.571mA
-838.6mV  18.38mA    10.71mA    17.72mA
-695.5mV  18.79mA    17.13mA    18.09mA
-552.3mV  17.7mA     17.94mA    17.47mA
640.9mV   -16.58mA   -16.97mA   -17.61mA
1.834V    -23.79mA   -23.78mA   -25.99mA
2.12V     -21.68mA   -20.55mA   -24.11mA
2.359V    -20.05mA   -12.01mA   -23.08mA
2.502V    -13.6mA    -9.614mA   -22.45mA
2.741V    -8.5mA     -7.786mA   -11.5mA
2.98V     -7mA       -7.143mA   -8.029mA
[Ramp]
R_load=50.000Ohm
dV/dt_r   502.920mV/108.000ps  480.719mV/124.500ps  542.820mV/96.500ps
dV/dt_f   502.920mV/108.500ps  480.719mV/131.000ps  542.820mV/96.000ps
[Rising waveform]
R_fixture=50.000Ohm
V_fixture=1.500
V_fixture_min=1.425
V_fixture_max=1.575
0s        658.2mV    635.1mV    665mV
39ps      669.9mV    632.7mV    702.1mV
69ps      741.3mV    632.3mV    889.6mV
100ps     930.2mV    635.7mV    1.175V
123ps     1.102V     644.8mV    1.331V
154ps     1.281V     680.2mV    1.453V
192ps     1.399V     802mV      1.522V
276ps     1.48V      1.229V     1.566V
345ps     1.494V     1.369V     1.573V
749ps     1.5V       1.425V     1.575V
[Rising waveform]
R_fixture=50.000Ohm
V_fixture=0
0s        -4.307mV   803.6uV    -4.774mV
39ps      -10.98mV   -916uV     5.28mV
77ps      38.78mV    -5.215mV   146.3mV
131ps     251.8mV    -13.05mV   454.4mV
169ps     428.8mV    7.094mV    623mV
253ps     687.6mV    236.9mV    815.7mV
345ps     793.6mV    565.6mV    879.6mV
429ps     824.9mV    721.9mV    896.1mV
544ps     837.1mV    792.7mV    902.9mV
749ps     841.7mV    814.6mV    905.7mV
[Falling waveform]
R_fixture=50.000Ohm
V_fixture=1.500
V_fixture_min=1.425
V_fixture_max=1.575
0s        1.505V     1.424V     1.581V
46ps      1.514V     1.427V     1.567V
85ps      1.454V     1.436V     1.425V
177ps     1.064V     1.41V      941mV
215ps     919.2mV    1.328V     821.9mV
261ps     803.1mV    1.173V     744.9mV
345ps     710.5mV    895.3mV    693mV
429ps     682mV      741.8mV    679.2mV
536ps     671.6mV    673.9mV    674.2mV
749ps     667.3mV    646.5mV    671.7mV
[Falling waveform]
R_fixture=50.000Ohm
V_fixture=0
0s        854mV      822.2mV    914.2mV
39ps      816.7mV    828.9mV    836.6mV
69ps      689.9mV    832mV      614.1mV
115ps     376.9mV    804.3mV    259.6mV
146ps     214mV      732mV      134.8mV
184ps     102.6mV    565.9mV    61.67mV
253ps     28.76mV    219.7mV    16.25mV
330ps     8.155mV    57.88mV    3.875mV
444ps     1.411mV    10.33mV    521.5uV
749ps     28.97uV    274uV      20.03uV
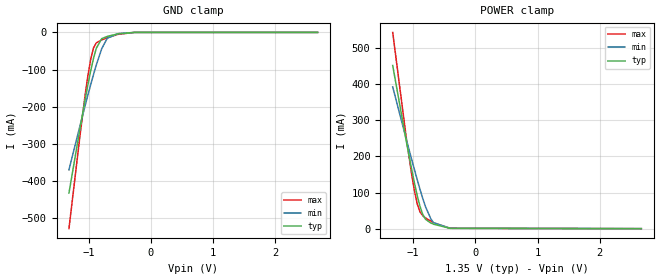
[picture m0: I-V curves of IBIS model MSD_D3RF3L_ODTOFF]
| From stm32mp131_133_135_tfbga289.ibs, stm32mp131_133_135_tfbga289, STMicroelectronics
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[Model] MSD_D3RF3L_ODTOFF
Model_type   Input
C_comp 2.247pF   2.166pF   2.364pF
Vinh = 810.000mV
Vinl = 540.000mV
[Receiver Thresholds]
Vth   =  0.675V
Vth_min  =  0.6615V
Vth_max  =  0.6885V
Vinh_ac  =  0.160V
Vinh_dc  =  0.090V
Vinl_ac  = -0.160V
Vinl_dc  = -0.090V
Tslew_ac =  5.000ns |Not specified, so set to high value
[Temperature Range]   25.000   125.000   -40.000
[Voltage Range]   1.350V   1.283V   1.450V
[GND Clamp Reference]   0.00V   0.00V   0.00V
[POWER Clamp Reference]   1.350V   1.283V   1.450V
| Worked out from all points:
|   GND clamp passes 1 mA (typ) near -0.41 V on its own axis
|   POWER clamp passes 1 mA (typ) near -0.41 V on its own axis
[GND Clamp]
-1.318V   -432.8mA   -370.3mA   -528.8mA
-1.142V   -260.6mA   -252.7mA   -280.2mA
-1.055V   -178.2mA   -195.3mA   -165.2mA
-1.011V   -139.1mA   -167.2mA   -114.1mA
-966.7mV  -102.4mA   -139.8mA   -71.26mA
-922.7mV  -69.52mA   -113.2mA   -41.65mA
-878.8mV  -42.91mA   -87.93mA   -28.28mA
-790.9mV  -16.85mA   -43.88mA   -20.2mA
-703mV    -10.77mA   -15.98mA   -14.6mA
-527.3mV  -3.882mA   -3.287mA   -5.181mA
-263.6mV  -34.33uA   -68.91uA   -22.73uA
2.68V     23.23nA    650.7nA    2.891nA
[Power Clamp]
-1.33V    452.1mA    392.8mA    543.8mA
-1.111V   241.8mA    247.2mA    250.6mA
-1.023V   162.2mA    190.3mA    147.9mA
-978.8mV  125.1mA    162.4mA    103.4mA
-934.9mV  91.03mA    135.1mA    67.95mA
-890.9mV  61.68mA    108.8mA    46.37mA
-847mV    39.38mA    83.87mA    35.91mA
-803mV    26.06mA    61.08mA    29.87mA
-715.1mV  15.46mA    26.37mA    20.47mA
-671.2mV  12.27mA    16.31mA    16.36mA
-407.6mV  879.9uA    1.157mA    1.067mA
2.668V    -39.91nA   -766.7nA   -3.592nA
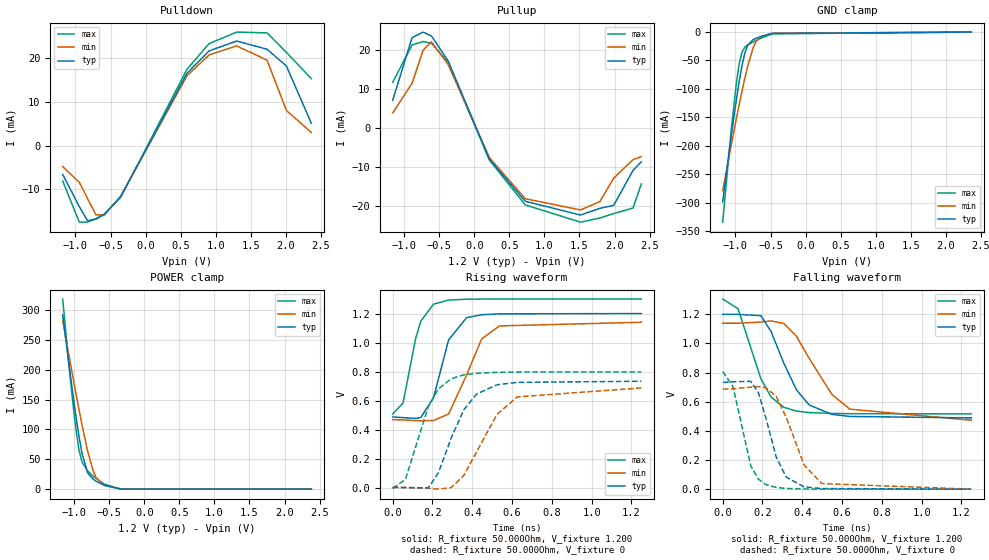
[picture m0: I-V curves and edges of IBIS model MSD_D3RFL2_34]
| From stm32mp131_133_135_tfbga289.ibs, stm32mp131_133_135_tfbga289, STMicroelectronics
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[Model] MSD_D3RFL2_34
Model_type   I/O
C_comp 2.255pF   2.172pF   2.373pF
Vinh = 820.000mV
Vinl = 380.000mV
Vmeas = 600.000mV
Vref = 600.000mV
[Model Spec]
Vinh   820.000mV   790.000mV   870.000mV
Vinl   380.000mV   350.000mV   430.000mV
Vmeas   600.000mV   570.000mV   650.000mV
Vref   600.000mV   570.000mV   650.000mV
[Receiver Thresholds]
Vth   =  0.600V
Vth_min  =  0.5880V
Vth_max  =  0.6120V
Vinh_ac  =  0.220V
Vinh_dc  =  0.130V
Vinl_ac  = -0.220V
Vinl_dc  = -0.130V
Tslew_ac =  5.000ns |Not specified, so set to high value
[Temperature Range]   25.000   125.000   -40.000
[Voltage Range]   1.200V   1.140V   1.300V
[GND Clamp Reference]   0.00V   0.00V   0.00V
[Pulldown Reference]   0.00V   0.00V   0.00V
[POWER Clamp Reference]   1.200V   1.140V   1.300V
[Pullup Reference]   1.200V   1.140V   1.300V
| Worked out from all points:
|   slope of the pulldown table from 0 to 0.18 V, typ, clamps not added: 31.3 ohm
|   slope of the pullup table from 0 to 0.18 V, typ, clamps not added: 26.5 ohm
|   GND clamp passes 1 mA (typ) near -0.41 V on its own axis
|   POWER clamp passes 1 mA (typ) near -0.41 V on its own axis
|   rising waveform, R_fixture 50.000Ohm, V_fixture 1.200: 20-80 % time 86ps typ, 113ps min, 73ps max; typ from 0.487 V to 1.2 V
|   rising waveform, R_fixture 50.000Ohm, V_fixture 0: 20-80 % time 138ps typ, 170ps min, 120ps max; typ from 0.001 V to 0.733 V
|   falling waveform, R_fixture 50.000Ohm, V_fixture 1.200: 20-80 % time 146ps typ, 190ps min, 121ps max; typ from 1.2 V to 0.489 V
|   falling waveform, R_fixture 50.000Ohm, V_fixture 0: 20-80 % time 92.7ps typ, 118ps min, 79ps max; typ from 0.732 V to 0 V
[GND Clamp]
-1.182V   -298.7mA   -278.8mA   -334.6mA
-1.064V   -186.5mA   -201.2mA   -176.5mA
-984.9mV  -117.2mA   -151mA     -87.71mA
-945.5mV  -85.9mA    -126.8mA   -54.95mA
-906.1mV  -58.53mA   -103.4mA   -34.88mA
-866.7mV  -37.07mA   -81.25mA   -26.52mA
-827.3mV  -23.31mA   -60.73mA   -22.77mA
-748.5mV  -13.21mA   -27.8mA    -17.44mA
-709.1mV  -11.06mA   -17.22mA   -14.97mA
-630.3mV  -7.606mA   -7.312mA   -10.35mA
-472.7mV  -2.342mA   -2.056mA   -3.037mA
2.364V    24.05nA    406.6nA    2.606nA
[Power Clamp]
-1.164V   291.7mA    282.1mA    318.2mA
-1.085V   217.9mA    230.4mA    219.1mA
-1.006V   147.8mA    179.6mA    130.3mA
-966.7mV  115.3mA    154.7mA    92.57mA
-927.3mV  85.58mA    130.4mA    63.26mA
-887.9mV  59.89mA    107mA      45.2mA
-809.1mV  27.4mA     63.99mA    30.58mA
-730.3mV  16.7mA     30.88mA    21.97mA
-690.9mV  13.64mA    20.08mA    18.15mA
-572.7mV  6.466mA    6.412mA    8.539mA
-336.4mV  182.5uA    350.9uA    204.7uA
2.382V    -20.25nA   -432nA     -2.132nA
[Pulldown]
-1.182V   -6.6mA     -4.8mA     -8.1mA
-945.5mV  -13.94mA   -8.4mA     -17.51mA
-827.3mV  -17.19mA   -12.13mA   -17.47mA
-709.1mV  -16.81mA   -15.79mA   -16.7mA
-590.9mV  -15.78mA   -15.92mA   -15.69mA
-354.6mV  -11.64mA   -11.57mA   -11.83mA
590.9mV   16.52mA    15.96mA    17.45mA
906.1mV   21.65mA    20.73mA    23.3mA
1.3V      23.89mA    22.78mA    25.94mA
1.733V    22.02mA    19.52mA    25.76mA
2.009V    18.18mA    8.01mA     21.29mA
2.364V    5.1mA      3mA        15.3mA
[Pullup]
-1.164V   7.2mA      3.962mA    11.8mA
-887.9mV  23.27mA    11.55mA    21.41mA
-730.3mV  24.7mA     20.07mA    22.27mA
-612.1mV  23.69mA    22.21mA    21.84mA
-375.8mV  17.4mA     16.45mA    16.98mA
215.2mV   -7.945mA   -7.529mA   -8.167mA
727.3mV   -18.74mA   -18.08mA   -19.68mA
1.515V    -22.27mA   -20.97mA   -24.11mA
1.791V    -20.55mA   -18.82mA   -23.03mA
1.988V    -19.79mA   -12.8mA    -21.9mA
2.264V    -10.8mA    -8.043mA   -20.47mA
2.382V    -8.6mA     -7.295mA   -14.29mA
[Ramp]
R_load=50.000Ohm
dV/dt_r   433.200mV/113.000ps  406.739mV/142.000ps  474.120mV/96.500ps
dV/dt_f   433.200mV/120.000ps  406.709mV/155.000ps  474.120mV/100.500ps
[Rising waveform]
R_fixture=50.000Ohm
V_fixture=1.200
V_fixture_min=1.140
V_fixture_max=1.300
0s        486.9mV    468.9mV    507.3mV
52ps      482.2mV    466mV      582.8mV
115ps     476.8mV    461.9mV    1.026V
141ps     483mV      460.5mV    1.147V
205ps     618.5mV    462.5mV    1.265V
281ps     1.018V     506.9mV    1.293V
371ps     1.171V     774.6mV    1.299V
447ps     1.192V     1.025V     1.3V
537ps     1.198V     1.115V     1.3V
1.25ns    1.2V       1.14V      1.3V
[Rising waveform]
R_fixture=50.000Ohm
V_fixture=0
0s        960.3uV    881.1uV    -6.61mV
64ps      -235.3uV   889.5uV    56.32mV
179ps     -2.377mV   -5.391mV   559.1mV
230ps     102.2mV    -11.14mV   680.3mV
294ps     341.8mV    -525.3uV   750.3mV
358ps     537.2mV    84.11mV    777.8mV
422ps     645.3mV    246.9mV    788.3mV
524ps     708.6mV    504.1mV    794.4mV
626ps     725.3mV    625.2mV    796.6mV
1.25ns    733.1mV    687.1mV    797.4mV
[Falling waveform]
R_fixture=50.000Ohm
V_fixture=1.200
V_fixture_min=1.140
V_fixture_max=1.300
0s        1.2V       1.139V     1.305V
77ps      1.2V       1.139V     1.239V
192ps     1.191V     1.147V     758.2mV
243ps     1.083V     1.155V     632.5mV
307ps     865.3mV    1.137V     562.2mV
371ps     681.4mV    1.049V     535.8mV
435ps     577.8mV    896.9mV    525.9mV
549ps     513.3mV    650.5mV    519.9mV
639ps     499.2mV    549.2mV    518.1mV
1.25ns    489.2mV    473.2mV    517mV
[Falling waveform]
R_fixture=50.000Ohm
V_fixture=0
0s        732.4mV    686.7mV    808.4mV
52ps      737.1mV    688.8mV    703.4mV
141ps     740.3mV    700.7mV    159.9mV
179ps     664.3mV    704.3mV    69.61mV
218ps     484.5mV    696.4mV    30.77mV
269ps     220.7mV    636.3mV    11.69mV
320ps     81.78mV    490.7mV    4.708mV
409ps     15.88mV    166.3mV    970.7uV
498ps     4.344mV    38.55mV    199.8uV
1.25ns    1.445uV    21.49uV    0V
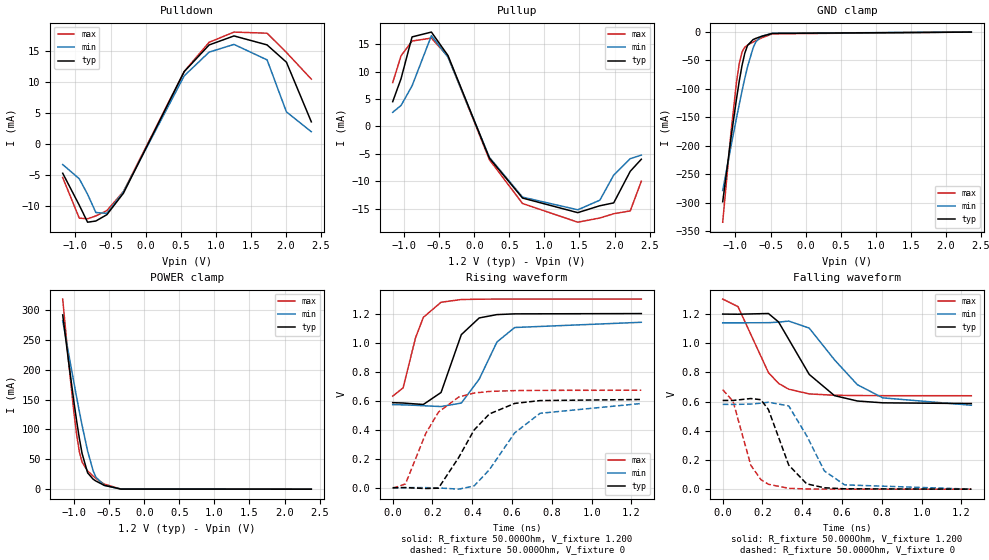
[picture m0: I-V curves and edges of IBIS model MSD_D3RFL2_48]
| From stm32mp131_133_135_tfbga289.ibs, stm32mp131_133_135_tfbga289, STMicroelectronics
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[Model] MSD_D3RFL2_48
Model_type   I/O
C_comp 2.255pF   2.172pF   2.373pF
Vinh = 820.000mV
Vinl = 380.000mV
Vmeas = 600.000mV
Vref = 600.000mV
[Model Spec]
Vinh   820.000mV   790.000mV   870.000mV
Vinl   380.000mV   350.000mV   430.000mV
Vmeas   600.000mV   570.000mV   650.000mV
Vref   600.000mV   570.000mV   650.000mV
[Receiver Thresholds]
Vth   =  0.600V
Vth_min  =  0.5880V
Vth_max  =  0.6120V
Vinh_ac  =  0.220V
Vinh_dc  =  0.130V
Vinl_ac  = -0.220V
Vinl_dc  = -0.130V
Tslew_ac =  5.000ns |Not specified, so set to high value
[Temperature Range]   25.000   125.000   -40.000
[Voltage Range]   1.200V   1.140V   1.300V
[GND Clamp Reference]   0.00V   0.00V   0.00V
[Pulldown Reference]   0.00V   0.00V   0.00V
[POWER Clamp Reference]   1.200V   1.140V   1.300V
[Pullup Reference]   1.200V   1.140V   1.300V
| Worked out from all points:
|   slope of the pulldown table from 0 to 0.18 V, typ, clamps not added: 41.6 ohm
|   slope of the pullup table from 0 to 0.18 V, typ, clamps not added: 36.3 ohm
|   GND clamp passes 1 mA (typ) near -0.41 V on its own axis
|   POWER clamp passes 1 mA (typ) near -0.41 V on its own axis
|   rising waveform, R_fixture 50.000Ohm, V_fixture 1.200: 20-80 % time 96.4ps typ, 124ps min, 82.1ps max; typ from 0.586 V to 1.2 V
|   rising waveform, R_fixture 50.000Ohm, V_fixture 0: 20-80 % time 165ps typ, 198ps min, 141ps max; typ from 0 V to 0.608 V
|   falling waveform, R_fixture 50.000Ohm, V_fixture 1.200: 20-80 % time 173ps typ, 220ps min, 140ps max; typ from 1.2 V to 0.587 V
|   falling waveform, R_fixture 50.000Ohm, V_fixture 0: 20-80 % time 103ps typ, 128ps min, 87.4ps max; typ from 0.608 V to 0 V
[GND Clamp]
-1.182V   -298.7mA   -278.8mA   -334.6mA
-1.064V   -186.5mA   -201.2mA   -176.5mA
-984.9mV  -117.2mA   -151mA     -87.71mA
-945.5mV  -85.9mA    -126.8mA   -54.95mA
-906.1mV  -58.53mA   -103.4mA   -34.88mA
-866.7mV  -37.07mA   -81.25mA   -26.52mA
-827.3mV  -23.31mA   -60.73mA   -22.77mA
-748.5mV  -13.21mA   -27.8mA    -17.44mA
-709.1mV  -11.06mA   -17.22mA   -14.97mA
-630.3mV  -7.606mA   -7.312mA   -10.35mA
-472.7mV  -2.342mA   -2.056mA   -3.037mA
2.364V    24.05nA    406.6nA    2.606nA
[Power Clamp]
-1.164V   291.7mA    282.1mA    318.2mA
-1.085V   217.9mA    230.4mA    219.1mA
-1.006V   147.8mA    179.6mA    130.3mA
-966.7mV  115.3mA    154.7mA    92.57mA
-927.3mV  85.58mA    130.4mA    63.26mA
-887.9mV  59.89mA    107mA      45.2mA
-809.1mV  27.4mA     63.99mA    30.58mA
-730.3mV  16.7mA     30.88mA    21.97mA
-690.9mV  13.64mA    20.08mA    18.15mA
-572.7mV  6.466mA    6.412mA    8.539mA
-336.4mV  182.5uA    350.9uA    204.7uA
2.382V    -20.25nA   -432nA     -2.132nA
[Pulldown]
-1.182V   -4.7mA     -3.3mA     -5.4mA
-945.5mV  -9.87mA    -5.6mA     -11.96mA
-827.3mV  -12.61mA   -8.1mA     -12.05mA
-709.1mV  -12.42mA   -11.05mA   -11.6mA
-551.5mV  -11.39mA   -11.18mA   -10.73mA
-315.1mV  -7.913mA   -7.699mA   -7.643mA
551.5mV   11.72mA    11.04mA    11.75mA
906.1mV   16.02mA    14.86mA    16.45mA
1.261V    17.48mA    16.11mA    18.1mA
1.733V    16.03mA    13.61mA    17.92mA
2.009V    13.23mA    5.21mA     14.81mA
2.364V    3.6mA      2mA        10.5mA
[Pullup]
-1.164V   4.5mA      2.557mA    7.977mA
-1.045V   8.7mA      3.814mA    12.86mA
-887.9mV  16.31mA    7.385mA    15.56mA
-612.1mV  17.19mA    16.54mA    16.09mA
-375.8mV  12.92mA    12.62mA    12.74mA
215.2mV   -5.799mA   -5.653mA   -6.081mA
687.9mV   -13.08mA   -12.91mA   -14.07mA
1.476V    -15.74mA   -15.22mA   -17.48mA
1.791V    -14.48mA   -13.46mA   -16.71mA
1.988V    -13.96mA   -8.894mA   -15.94mA
2.224V    -8.2mA     -5.895mA   -15.42mA
2.382V    -6mA       -5.248mA   -10.01mA
[Ramp]
R_load=50.000Ohm
dV/dt_r   366.690mV/131.500ps  344.609mV/162.000ps  399.540mV/112.000ps
dV/dt_f   366.690mV/138.500ps  344.609mV/176.000ps  399.540mV/114.500ps
[Rising waveform]
R_fixture=50.000Ohm
V_fixture=1.200
V_fixture_min=1.140
V_fixture_max=1.300
0s        586.2mV    572.5mV    631.1mV
52ps      583.8mV    571.1mV    687.7mV
115ps     577.3mV    567.8mV    1.034V
154ps     573.7mV    565mV      1.174V
243ps     656.2mV    559.4mV    1.278V
345ps     1.055V     583.5mV    1.297V
435ps     1.17V      748.6mV    1.299V
524ps     1.193V     1.004V     1.3V
613ps     1.198V     1.104V     1.3V
1.25ns    1.2V       1.14V      1.3V
[Rising waveform]
R_fixture=50.000Ohm
V_fixture=0
0s        252uV      153.2uV    -3.982mV
64ps      823uV      576.8uV    26.22mV
166ps     -5.529mV   701.6uV    373.5mV
230ps     -3.078mV   -1.204mV   520.8mV
332ps     208.9mV    -9.85mV    625.1mV
409ps     397.3mV    11.93mV    652.4mV
486ps     508.4mV    123.8mV    663.6mV
613ps     580.9mV    377.7mV    669.2mV
741ps     600.6mV    513mV      670.8mV
1.25ns    608.1mV    580.5mV    672mV
[Falling waveform]
R_fixture=50.000Ohm
V_fixture=1.200
V_fixture_min=1.140
V_fixture_max=1.300
0s        1.2V       1.14V      1.303V
77ps      1.199V     1.14V      1.251V
230ps     1.204V     1.141V     798.7mV
281ps     1.146V     1.145V     725mV
332ps     1.027V     1.152V     685.1mV
435ps     786.4mV    1.104V     652.9mV
562ps     641mV      886.6mV    643.6mV
677ps     604.3mV    716.1mV    641.6mV
805ps     591.8mV    625.7mV    640.9mV
1.25ns    586.8mV    575.4mV    640.4mV
[Falling waveform]
R_fixture=50.000Ohm
V_fixture=0
0s        608.1mV    581.1mV    681.9mV
52ps      608mV      580.7mV    602.7mV
141ps     621.2mV    583.2mV    165mV
192ps     613.2mV    589.6mV    65.07mV
230ps     545.1mV    595.9mV    33.32mV
332ps     165.1mV    570.6mV    5.974mV
422ps     36.56mV    366.5mV    1.307mV
511ps     9.521mV    125.2mV    329.5uV
613ps     2.393mV    29.41mV    96.99uV
1.25ns    2.439uV    44.99uV    650nV
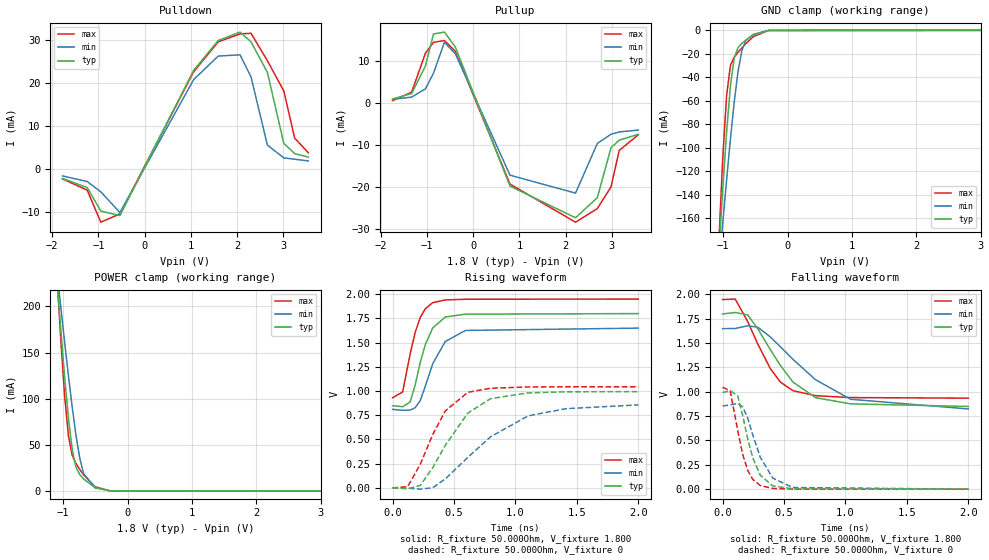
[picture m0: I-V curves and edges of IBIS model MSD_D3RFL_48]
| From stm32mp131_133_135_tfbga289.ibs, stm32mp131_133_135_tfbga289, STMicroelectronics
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[Model] MSD_D3RFL_48
Model_type   I/O
C_comp 2.228pF   2.147pF   2.347pF
Vinh = 1.440V
Vinl = 360.000mV
Vmeas = 900.000mV
Vref = 900.000mV
[Model Spec]
Vinh   1.440V   1.365V   1.515V
Vinl   360.000mV   285.000mV   435.000mV
Vmeas   900.000mV   825.000mV   975.000mV
Vref   900.000mV   825.000mV   975.000mV
[Temperature Range]   25.000   125.000   -40.000
[Voltage Range]   1.800V   1.650V   1.950V
[GND Clamp Reference]   0.00V   0.00V   0.00V
[Pulldown Reference]   0.00V   0.00V   0.00V
[POWER Clamp Reference]   1.800V   1.650V   1.950V
[Pullup Reference]   1.800V   1.650V   1.950V
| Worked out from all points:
|   slope of the pulldown table from 0 to 0.27 V, typ, clamps not added: 41 ohm
|   slope of the pullup table from 0 to 0.27 V, typ, clamps not added: 32.3 ohm
|   GND clamp passes 1 mA (typ) near -0.40 V on its own axis
|   POWER clamp passes 1 mA (typ) near -0.41 V on its own axis
|   rising waveform, R_fixture 50.000Ohm, V_fixture 1.800: 20-80 % time 129ps typ, 162ps min, 114ps max; typ from 0.848 V to 1.8 V
|   rising waveform, R_fixture 50.000Ohm, V_fixture 0: 20-80 % time 309ps typ, 493ps min, 239ps max; typ from 0.001 V to 0.994 V
|   falling waveform, R_fixture 50.000Ohm, V_fixture 1.800: 20-80 % time 317ps typ, 461ps min, 248ps max; typ from 1.8 V to 0.85 V
|   falling waveform, R_fixture 50.000Ohm, V_fixture 0: 20-80 % time 126ps typ, 156ps min, 109ps max; typ from 0.993 V to 0 V
[GND Clamp]
-1.773V   -889mA     -680.4mA   -1.192A
-1.064V   -186.5mA   -201.2mA   -176.5mA
-1.005V   -133.8mA   -163.4mA   -107.6mA
-945.5mV  -85.89mA   -126.8mA   -54.95mA
-886.4mV  -46.93mA   -92.18mA   -29.68mA
-827.3mV  -23.31mA   -60.73mA   -22.77mA
-768.2mV  -14.61mA   -34.71mA   -18.7mA
-709.1mV  -11.06mA   -17.22mA   -14.97mA
-650mV    -8.417mA   -8.794mA   -11.47mA
-531.8mV  -4.026mA   -3.406mA   -5.382mA
-295.4mV  -87.46uA   -140.3uA   -72.54uA
3.545V    30.39nA    447.4nA    3.637nA
[Power Clamp]
-1.745V   858.7mA    673.3mA    1.125A
-1.095V   227.7mA    237.3mA    232.3mA
-1.036V   174.2mA    199mA      163.4mA
-977.3mV  123.8mA    161.5mA    103.2mA
-918.2mV  79.24mA    125.1mA    60.03mA
-859.1mV  44.68mA    90.74mA    38.59mA
-800mV    25.45mA    59.93mA    29.58mA
-740.9mV  17.64mA    35.13mA    23.09mA
-681.8mV  13mA       18.78mA    17.36mA
-504.5mV  3.465mA    3.577mA    4.548mA
-268.2mV  26.04uA    93.18uA    29.58uA
3.573V    -30.16nA   -532.8nA   -4.248nA
[Pulldown]
-1.773V   -2.3mA     -1.7mA     -2.4mA
-1.241V   -4.4mA     -3mA       -5mA
-945.5mV  -9.88mA    -5.4mA     -12.48mA
-531.8mV  -10.94mA   -10.23mA   -10.54mA
1.064V    22.92mA    20.76mA    22.58mA
1.595V    29.86mA    26.24mA    29.55mA
2.068V    31.83mA    26.53mA    31.41mA
2.305V    29.56mA    21.37mA    31.55mA
2.659V    22.44mA    5.5mA      25.16mA
3.014V    5.9mA      2.5mA      18.1mA
3.25V     3.5mA      2.2mA      7.1mA
3.545V    2.7mA      1.8mA      3.7mA
[Pullup]
-1.745V   1mA        900uA      600uA
-1.332V   2.3mA      1.454mA    2.615mA
-1.036V   8.8mA      3.377mA    11.85mA
-859.1mV  16.47mA    7.15mA     14.48mA
-622.7mV  16.92mA    14.49mA    14.91mA
-386.4mV  13.35mA    11.76mA    12.33mA
795.5mV   -19.73mA   -17.13mA   -19.24mA
2.214V    -27.27mA   -21.4mA    -28.32mA
2.686V    -22.48mA   -9.569mA   -25.08mA
2.982V    -10.6mA    -7.392mA   -19.91mA
3.159V    -8.8mA     -6.846mA   -11.25mA
3.573V    -7.4mA     -6.4mA     -7.508mA
[Ramp]
R_load=50.000Ohm
dV/dt_r   583.770mV/220.000ps  505.859mV/323.500ps  617.730mV/177.000ps
dV/dt_f   583.678mV/222.000ps  504.444mV/309.500ps  617.730mV/179.000ps
[Rising waveform]
R_fixture=50.000Ohm
V_fixture=1.800
V_fixture_min=1.650
V_fixture_max=1.950
0s        848.3mV    810.7mV    931.1mV
82ps      838.1mV    800.9mV    990.4mV
143ps     887.3mV    803.5mV    1.383V
184ps     1.063V     828.3mV    1.606V
225ps     1.295V     901.2mV    1.759V
266ps     1.477V     1.048V     1.85V
327ps     1.652V     1.283V     1.913V
429ps     1.765V     1.512V     1.941V
593ps     1.794V     1.626V     1.948V
2ns       1.8V       1.65V      1.95V
[Rising waveform]
R_fixture=50.000Ohm
V_fixture=0
0s        1.105mV    1.195mV    336.7uV
123ps     -8.926mV   -3.146mV   12.63mV
225ps     24.95mV    -13.22mV   242.3mV
327ps     209.2mV    1.288mV    550.9mV
429ps     440.1mV    92mV       794.8mV
613ps     772.6mV    316.1mV    987mV
797ps     921.6mV    527.1mV    1.029V
1.103ns   981.1mV    743.7mV    1.042V
1.409ns   992mV      817.9mV    1.044V
2ns       994.1mV    857.2mV    1.044V
[Falling waveform]
R_fixture=50.000Ohm
V_fixture=1.800
V_fixture_min=1.650
V_fixture_max=1.950
0s        1.8V       1.649V     1.948V
103ps     1.815V     1.651V     1.953V
205ps     1.79V      1.678V     1.721V
286ps     1.649V     1.664V     1.492V
388ps     1.435V     1.565V     1.24V
470ps     1.272V     1.463V     1.101V
572ps     1.101V     1.335V     1.012V
756ps     940.3mV    1.125V     960.2mV
1.042ns   876.4mV    923.5mV    941.1mV
2ns       849.6mV    824.2mV    934.8mV
[Falling waveform]
R_fixture=50.000Ohm
V_fixture=0
0s        993.4mV    854.5mV    1.047V
62ps      1.009V     864.4mV    1.011V
123ps     963.1mV    881mV      605mV
164ps     755.9mV    846mV      356.3mV
205ps     512.9mV    730mV      192.2mV
246ps     322.4mV    556.7mV    100mV
307ps     142.8mV    327.7mV    37.45mV
409ps     32.8mV     112.8mV    7.691mV
572ps     4.018mV    16.75mV    961.4uV
2ns       15.29uV    95.2uV     764.6nV
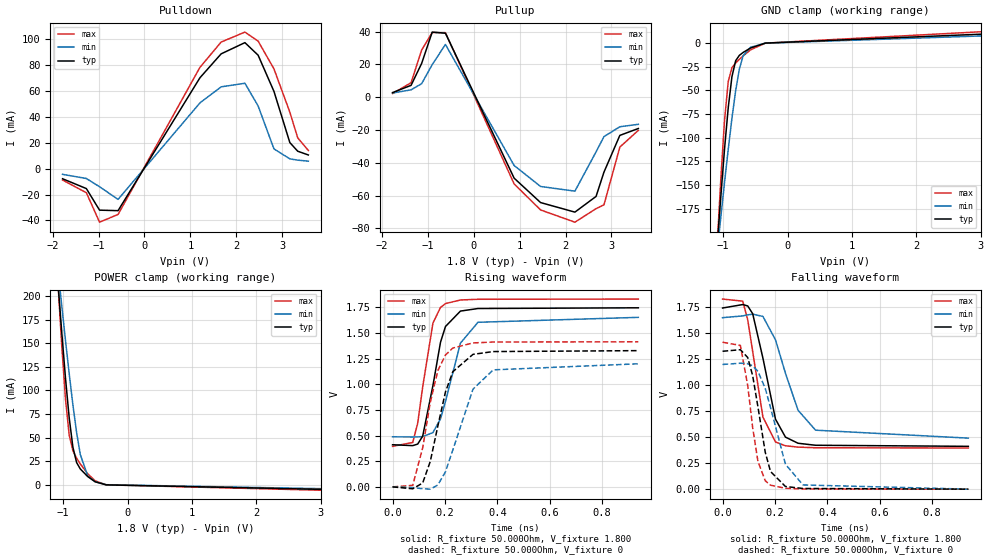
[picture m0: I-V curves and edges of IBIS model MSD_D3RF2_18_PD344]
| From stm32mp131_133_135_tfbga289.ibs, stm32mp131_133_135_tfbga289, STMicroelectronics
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[Model] MSD_D3RF2_18_PD344
Model_type   I/O
C_comp 2.313pF   2.232pF   2.432pF
Vinh = 1.150V
Vinl = 650.000mV
Vmeas = 900.000mV
Vref = 900.000mV
[Model Spec]
Vinh   1.150V   1.100V   1.200V
Vinl   650.000mV   600.000mV   700.000mV
Vmeas   900.000mV   850.000mV   950.000mV
Vref   900.000mV   850.000mV   950.000mV
[Temperature Range]   25.000   125.000   -40.000
[Voltage Range]   1.800V   1.700V   1.900V
[GND Clamp Reference]   0.00V   0.00V   0.00V
[Pulldown Reference]   0.00V   0.00V   0.00V
[POWER Clamp Reference]   1.800V   1.700V   1.900V
[Pullup Reference]   1.800V   1.700V   1.900V
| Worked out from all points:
|   slope of the pulldown table from 0 to 0.27 V, typ, clamps not added: 15.3 ohm
|   slope of the pullup table from 0 to 0.27 V, typ, clamps not added: 14.6 ohm
|   GND clamp passes 1 mA (typ) near -0.41 V on its own axis
|   POWER clamp passes 1 mA (typ) near -0.41 V on its own axis
|   rising waveform, R_fixture 50.000Ohm, V_fixture 1.800: 20-80 % time 56.5ps typ, 72.2ps min, 49.3ps max; typ from 0.411 V to 1.74 V
|   rising waveform, R_fixture 50.000Ohm, V_fixture 0: 20-80 % time 73.9ps typ, 93.3ps min, 64.9ps max; typ from 0.001 V to 1.33 V
|   falling waveform, R_fixture 50.000Ohm, V_fixture 1.800: 20-80 % time 63.9ps typ, 91.1ps min, 53.4ps max; typ from 1.74 V to 0.412 V
|   falling waveform, R_fixture 50.000Ohm, V_fixture 0: 20-80 % time 54.2ps typ, 75.8ps min, 45.1ps max; typ from 1.33 V to 0 V
[GND Clamp]
-1.785V   -901.2mA   -688.6mA   -1.21A
-1.094V   -214.7mA   -220.8mA   -215.3mA
-1.036V   -161.8mA   -183.6mA   -143.3mA
-978.8mV  -112.1mA   -147.2mA   -82.01mA
-921.2mV  -68.48mA   -112.4mA   -40.94mA
-863.6mV  -35.72mA   -79.61mA   -26.14mA
-806.1mV  -18.98mA   -50.62mA   -21.23mA
-748.5mV  -13.21mA   -27.8mA    -17.43mA
-690.9mV  -10.21mA   -13.8mA    -13.87mA
-575.8mV  -5.52mA    -4.739mA   -7.464mA
-345.4mV  -312.6uA   -378.8uA   -329uA
3.57V     10.68mA    8.508mA    13.66mA
[Power Clamp]
-1.77V    882.5mA    689.6mA    1.159A
-1.079V   212.4mA    226.4mA    212.1mA
-1.021V   160.9mA    189.3mA    146.7mA
-963.6mV  112.9mA    152.9mA    90.87mA
-906.1mV  71.13mA    117.8mA    52.88mA
-848.5mV  39.99mA    84.73mA    36.14mA
-790.9mV  23.76mA    55.38mA    28.45mA
-733.3mV  16.95mA    32.18mA    22.29mA
-618.2mV  8.932mA    9.702mA    11.91mA
-503mV    3.404mA    3.492mA    4.434mA
-330.3mV  151.6uA    319.4uA    178.5uA
3.585V    -5.406mA   -4.594mA   -6.496mA
[Pulldown]
-1.785V   -7.8mA     -4.4mA     -8.8mA
-1.267V   -15.4mA    -7.6mA     -18.6mA
-978.8mV  -32.1mA    -14mA      -41.42mA
-575.8mV  -32.5mA    -23.76mA   -35.41mA
1.209V    70.39mA    50.93mA    78.43mA
1.67V     88.85mA    63.32mA    97.99mA
2.188V    97.54mA    66.1mA     105.7mA
2.476V    87.81mA    48.54mA    98.72mA
2.821V    59.8mA     15.3mA     77.21mA
3.167V    20.2mA     7.6mA      43.7mA
3.339V    13.5mA     6.6mA      23.8mA
3.57V     10.6mA     5.8mA      14.1mA
[Pullup]
-1.77V    2.8mA      2.547mA    2.179mA
-1.367V   7.2mA      4.468mA    8.789mA
-1.136V   20.6mA     8.232mA    28.74mA
-906.1mV  39.67mA    19.82mA    39.4mA
-618.2mV  38.98mA    32.13mA    39.33mA
878.8mV   -49.37mA   -41.65mA   -52.88mA
1.455V    -64.25mA   -54.44mA   -68.74mA
2.203V    -70.07mA   -57.29mA   -76.21mA
2.664V    -60.5mA    -33.33mA   -67.94mA
2.836V    -45.7mA    -24.05mA   -65.63mA
3.182V    -23.3mA    -18.03mA   -30.43mA
3.585V    -19.1mA    -16.55mA   -20.22mA
[Ramp]
R_load=50.000Ohm
dV/dt_r   797.490mV/66.000ps  707.609mV/83.500ps  853.950mV/58.000ps
dV/dt_f   797.490mV/60.000ps  707.609mV/83.500ps  853.950mV/50.000ps
[Rising waveform]
R_fixture=50.000Ohm
V_fixture=1.800
V_fixture_min=1.700
V_fixture_max=1.900
0s        411.1mV    488.5mV    395.5mV
77ps      402.5mV    486.5mV    433.3mV
96ps      417.9mV    487.4mV    622.2mV
115ps     494.9mV    490.6mV    974.4mV
154ps     986.3mV    529.1mV    1.595V
183ps     1.409V     662.6mV    1.747V
202ps     1.562V     833.1mV    1.785V
259ps     1.712V     1.4V       1.82V
326ps     1.737V     1.603V     1.827V
938ps     1.744V     1.651V     1.829V
[Rising waveform]
R_fixture=50.000Ohm
V_fixture=0
0s        1.127mV    996.4uV    984uV
77ps      -17.64mV   -5.769mV   15.69mV
115ps     39.03mV    -16.81mV   381.9mV
144ps     249.1mV    -21.21mV   823.8mV
173ps     596.4mV    20.04mV    1.134V
202ps     925.9mV    148.5mV    1.285V
230ps     1.122V     360.8mV    1.352V
307ps     1.291V     952.6mV    1.402V
384ps     1.318V     1.14V      1.411V
938ps     1.327V     1.199V     1.413V
[Falling waveform]
R_fixture=50.000Ohm
V_fixture=1.800
V_fixture_min=1.700
V_fixture_max=1.900
0s        1.742V     1.649V     1.828V
77ps      1.775V     1.666V     1.808V
96ps      1.762V     1.676V     1.629V
115ps     1.687V     1.683V     1.323V
154ps     1.26V      1.661V     693.5mV
202ps     673.1mV    1.436V     453.6mV
240ps     500.6mV    1.115V     417.4mV
288ps     441.5mV    758.9mV    404.3mV
355ps     422.2mV    567.1mV    398.2mV
938ps     411.8mV    490.8mV    395.7mV
[Falling waveform]
R_fixture=50.000Ohm
V_fixture=0
0s        1.326V     1.199V     1.413V
68ps      1.341V     1.211V     1.382V
96ps      1.266V     1.207V     996.9mV
115ps     1.09V      1.185V     590.6mV
135ps     791.3mV    1.133V     266.8mV
163ps     353.9mV    968.7mV    80.74mV
183ps     169.7mV    785mV      38.25mV
240ps     25.53mV    239.3mV    8.445mV
307ps     6.537mV    40.67mV    2.042mV
938ps     3.609uV    16.19uV    1.347uV
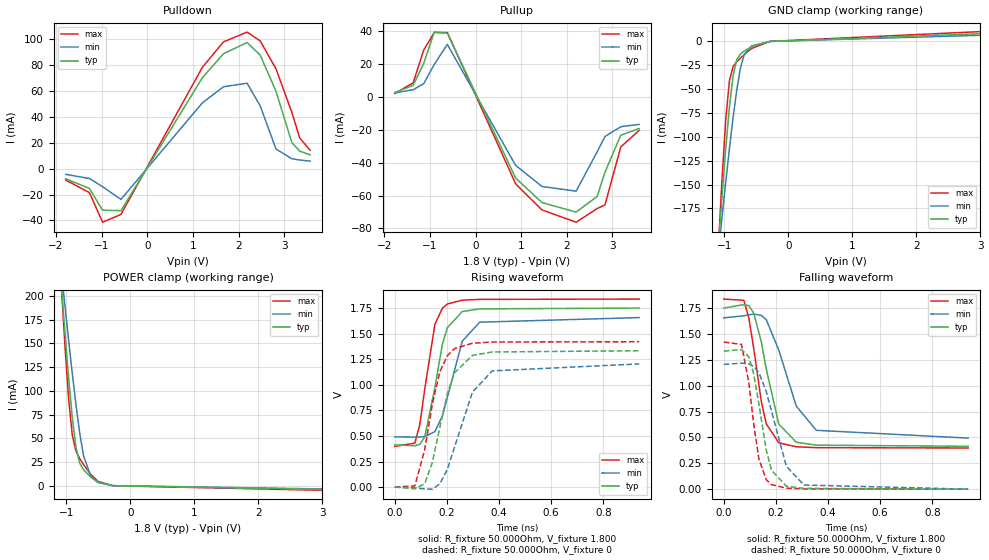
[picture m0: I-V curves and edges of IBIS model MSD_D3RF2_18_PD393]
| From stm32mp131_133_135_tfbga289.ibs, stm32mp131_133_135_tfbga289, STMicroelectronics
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[Model] MSD_D3RF2_18_PD393
Model_type   I/O
C_comp 2.343pF   2.262pF   2.463pF
Vinh = 1.150V
Vinl = 650.000mV
Vmeas = 900.000mV
Vref = 900.000mV
[Model Spec]
Vinh   1.150V   1.100V   1.200V
Vinl   650.000mV   600.000mV   700.000mV
Vmeas   900.000mV   850.000mV   950.000mV
Vref   900.000mV   850.000mV   950.000mV
[Temperature Range]   25.000   125.000   -40.000
[Voltage Range]   1.800V   1.700V   1.900V
[GND Clamp Reference]   0.00V   0.00V   0.00V
[Pulldown Reference]   0.00V   0.00V   0.00V
[POWER Clamp Reference]   1.800V   1.700V   1.900V
[Pullup Reference]   1.800V   1.700V   1.900V
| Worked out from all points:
|   slope of the pulldown table from 0 to 0.27 V, typ, clamps not added: 15.3 ohm
|   slope of the pullup table from 0 to 0.27 V, typ, clamps not added: 14.6 ohm
|   GND clamp passes 1 mA (typ) near -0.41 V on its own axis
|   POWER clamp passes 1 mA (typ) near -0.41 V on its own axis
|   rising waveform, R_fixture 50.000Ohm, V_fixture 1.800: 20-80 % time 56.5ps typ, 72.4ps min, 49.6ps max; typ from 0.413 V to 1.75 V
|   rising waveform, R_fixture 50.000Ohm, V_fixture 0: 20-80 % time 74.2ps typ, 93.7ps min, 65.6ps max; typ from 0.001 V to 1.33 V
|   falling waveform, R_fixture 50.000Ohm, V_fixture 1.800: 20-80 % time 64.6ps typ, 91.9ps min, 54ps max; typ from 1.75 V to 0.414 V
|   falling waveform, R_fixture 50.000Ohm, V_fixture 0: 20-80 % time 54.5ps typ, 76.8ps min, 45.4ps max; typ from 1.33 V to 0 V
[GND Clamp]
-1.785V   -901.7mA   -689.1mA   -1.21A
-1.094V   -214.9mA   -221.1mA   -215.5mA
-1.036V   -162mA     -183.8mA   -143.5mA
-978.8mV  -112.3mA   -147.4mA   -82.22mA
-921.2mV  -68.63mA   -112.4mA   -41.13mA
-863.6mV  -35.85mA   -79.72mA   -26.32mA
-806.1mV  -19.09mA   -50.71mA   -21.39mA
-748.5mV  -13.31mA   -27.88mA   -17.56mA
-690.9mV  -10.29mA   -13.87mA   -13.98mA
-575.8mV  -5.571mA   -4.782mA   -7.532mA
-287.9mV  -72.78uA   -122.5uA   -58.3uA
3.57V     9.343mA    7.446mA    11.95mA
[Power Clamp]
-1.77V    883mA      690.1mA    1.159A
-1.079V   212.6mA    226.6mA    212.3mA
-1.021V   161mA      189.4mA    146.9mA
-963.6mV  113.1mA    153mA      91.13mA
-906.1mV  71.28mA    117.8mA    53.07mA
-848.5mV  40.13mA    84.84mA    36.32mA
-790.9mV  23.88mA    55.48mA    28.61mA
-733.3mV  17.05mA    32.27mA    22.42mA
-618.2mV  8.997mA    9.762mA    11.99mA
-503mV    3.435mA    3.526mA    4.476mA
-272.7mV  28uA       96.27uA    27.84uA
3.585V    -4.731mA   -4.02mA    -5.687mA
[Pulldown]
-1.785V   -7.8mA     -4.4mA     -8.8mA
-1.267V   -15.3mA    -7.6mA     -18.5mA
-978.8mV  -32.1mA    -13.9mA    -41.38mA
-575.8mV  -32.49mA   -23.76mA   -35.4mA
1.209V    70.38mA    50.92mA    78.43mA
1.67V     88.85mA    63.32mA    97.99mA
2.188V    97.55mA    66.1mA     105.6mA
2.476V    87.76mA    48.48mA    98.74mA
2.821V    59.8mA     15.2mA     77.16mA
3.167V    20.3mA     7.7mA      43.7mA
3.339V    13.6mA     6.7mA      23.9mA
3.57V     10.7mA     5.8mA      14.2mA
[Pullup]
-1.77V    2.8mA      2.547mA    2.179mA
-1.367V   7.2mA      4.495mA    8.716mA
-1.136V   20.5mA     8.205mA    28.69mA
-906.1mV  39.63mA    19.85mA    39.36mA
-618.2mV  38.98mA    32.13mA    39.33mA
878.8mV   -49.37mA   -41.65mA   -52.89mA
1.455V    -64.25mA   -54.44mA   -68.74mA
2.203V    -70.07mA   -57.29mA   -76.21mA
2.664V    -60.51mA   -33.33mA   -67.93mA
2.836V    -45.7mA    -23.98mA   -65.61mA
3.182V    -23.2mA    -18.03mA   -30.35mA
3.585V    -19.1mA    -16.6mA    -20.22mA
[Ramp]
R_load=50.000Ohm
dV/dt_r   800.940mV/66.000ps  710.369mV/83.500ps  858.450mV/58.500ps
dV/dt_f   800.940mV/60.000ps  710.369mV/84.500ps  858.450mV/50.500ps
[Rising waveform]
R_fixture=50.000Ohm
V_fixture=1.800
V_fixture_min=1.700
V_fixture_max=1.900
0s        413mV      490.5mV    397.6mV
77ps      404.4mV    488.8mV    429.6mV
96ps      418mV      490.1mV    610.4mV
115ps     491.1mV    494mV      956.8mV
154ps     972.5mV    541.9mV    1.591V
183ps     1.401V     696.6mV    1.75V
202ps     1.559V     878.9mV    1.79V
259ps     1.716V     1.427V     1.827V
326ps     1.742V     1.612V     1.835V
938ps     1.75V      1.657V     1.838V
[Rising waveform]
R_fixture=50.000Ohm
V_fixture=0
0s        1.14mV     968.2uV    1.004mV
77ps      -17.18mV   -6.678mV   11.12mV
115ps     34.02mV    -18.22mV   367.6mV
144ps     239.5mV    -20.1mV    810.5mV
173ps     584mV      32.62mV    1.128V
202ps     917.7mV    174.2mV    1.285V
230ps     1.119V     396.6mV    1.355V
298ps     1.287V     928.8mV    1.406V
374ps     1.321V     1.136V     1.418V
938ps     1.333V     1.204V     1.421V
[Falling waveform]
R_fixture=50.000Ohm
V_fixture=1.800
V_fixture_min=1.700
V_fixture_max=1.900
0s        1.749V     1.655V     1.836V
77ps      1.782V     1.674V     1.824V
96ps      1.772V     1.684V     1.654V
115ps     1.701V     1.691V     1.357V
144ps     1.422V     1.678V     845.8mV
163ps     1.159V     1.637V     631.5mV
211ps     629.3mV    1.344V     447.6mV
278ps     453.3mV    802.3mV    409.6mV
355ps     425.2mV    568.3mV    400.7mV
938ps     413.7mV    493.1mV    397.7mV
[Falling waveform]
R_fixture=50.000Ohm
V_fixture=0
0s        1.333V     1.205V     1.421V
68ps      1.348V     1.217V     1.398V
96ps      1.279V     1.21V      1.03V
115ps     1.111V     1.185V     624.2mV
135ps     818.9mV    1.123V     288.4mV
163ps     375.2mV    944mV      90.48mV
183ps     183.4mV    753.2mV    43.48mV
240ps     28.9mV     222.7mV    10.07mV
307ps     7.744mV    40.03mV    2.562mV
938ps     4.514uV    20.14uV    0V
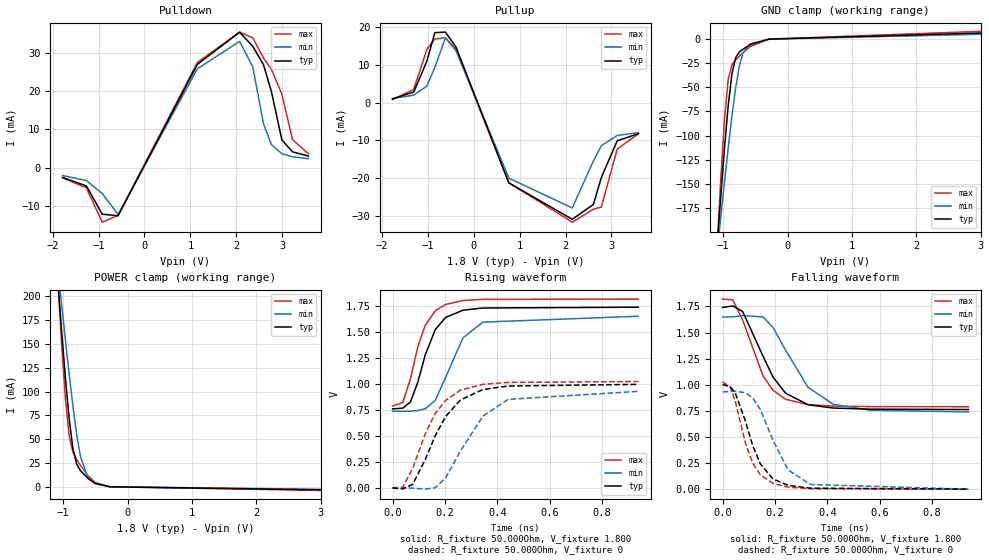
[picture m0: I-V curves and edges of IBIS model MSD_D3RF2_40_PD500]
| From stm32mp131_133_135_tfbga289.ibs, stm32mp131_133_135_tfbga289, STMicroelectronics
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[Model] MSD_D3RF2_40_PD500
Model_type   I/O
C_comp 2.389pF   2.307pF   2.511pF
Vinh = 1.150V
Vinl = 650.000mV
Vmeas = 900.000mV
Vref = 900.000mV
[Model Spec]
Vinh   1.150V   1.100V   1.200V
Vinl   650.000mV   600.000mV   700.000mV
Vmeas   900.000mV   850.000mV   950.000mV
Vref   900.000mV   850.000mV   950.000mV
[Temperature Range]   25.000   125.000   -40.000
[Voltage Range]   1.800V   1.700V   1.900V
[GND Clamp Reference]   0.00V   0.00V   0.00V
[Pulldown Reference]   0.00V   0.00V   0.00V
[POWER Clamp Reference]   1.800V   1.700V   1.900V
[Pullup Reference]   1.800V   1.700V   1.900V
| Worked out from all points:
|   slope of the pulldown table from 0 to 0.27 V, typ, clamps not added: 37.2 ohm
|   slope of the pullup table from 0 to 0.27 V, typ, clamps not added: 29.4 ohm
|   GND clamp passes 1 mA (typ) near -0.40 V on its own axis
|   POWER clamp passes 1 mA (typ) near -0.41 V on its own axis
|   rising waveform, R_fixture 50.000Ohm, V_fixture 1.800: 20-80 % time 79.1ps typ, 96.7ps min, 71.7ps max; typ from 0.759 V to 1.74 V
|   rising waveform, R_fixture 50.000Ohm, V_fixture 0: 20-80 % time 125ps typ, 142ps min, 114ps max; typ from -0.002 V to 0.994 V
|   falling waveform, R_fixture 50.000Ohm, V_fixture 1.800: 20-80 % time 115ps typ, 135ps min, 99.1ps max; typ from 1.74 V to 0.763 V
|   falling waveform, R_fixture 50.000Ohm, V_fixture 0: 20-80 % time 85.5ps typ, 102ps min, 73.9ps max; typ from 1 V to 0 V
[GND Clamp]
-1.785V   -902.3mA   -689.6mA   -1.211A
-1.094V   -215.1mA   -221.3mA   -215.9mA
-1.036V   -162.2mA   -184mA     -144mA
-978.8mV  -112.6mA   -147.7mA   -82.55mA
-921.2mV  -68.85mA   -112.7mA   -41.43mA
-863.6mV  -36.05mA   -79.88mA   -26.58mA
-806.1mV  -19.27mA   -50.85mA   -21.61mA
-748.5mV  -13.46mA   -28mA      -17.75mA
-690.9mV  -10.41mA   -13.96mA   -14.14mA
-575.8mV  -5.648mA   -4.846mA   -7.634mA
-287.9mV  -74.98uA   -125.3uA   -60.3uA
3.57V     7.346mA    5.855mA    9.39mA
[Power Clamp]
-1.77V    883.7mA    690.7mA    1.16A
-1.079V   212.9mA    226.9mA    212.8mA
-1.021V   161.3mA    189.7mA    147.3mA
-963.6mV  113.3mA    153.3mA    91.41mA
-906.1mV  71.51mA    118.1mA    53.37mA
-848.5mV  40.33mA    85.03mA    36.57mA
-790.9mV  24.05mA    55.63mA    28.83mA
-733.3mV  17.2mA     32.4mA     22.61mA
-618.2mV  9.094mA    9.85mA     12.12mA
-503mV    3.487mA    3.577mA    4.547mA
-272.7mV  29uA       100.4uA    30.26uA
3.585V    -3.718mA   -3.159mA   -4.469mA
[Pulldown]
-1.785V   -2.6mA     -2.1mA     -2.7mA
-1.267V   -4.8mA     -3.4mA     -5.3mA
-921.2mV  -12.19mA   -6.8mA     -14.28mA
-575.8mV  -12.6mA    -12.25mA   -12.47mA
1.152V    26.92mA    25.79mA    27.43mA
2.073V    35.35mA    32.95mA    35.37mA
2.361V    31.62mA    26.22mA    33.85mA
2.591V    26.91mA    11.5mA     28.61mA
2.764V    19.9mA     6mA        25.7mA
2.994V    7.2mA      3.6mA      19.1mA
3.224V    4.1mA      2.8mA      7.3mA
3.57V     3mA        2.3mA      3.6mA
[Pullup]
-1.77V    1mA        1.074mA    773.7uA
-1.309V   2.8mA      1.974mA    3.516mA
-1.021V   11mA       4.389mA    14.14mA
-848.5mV  18.49mA    9.339mA    16.82mA
-618.2mV  18.64mA    17.12mA    17.13mA
-387.9mV  14.67mA    13.72mA    14.14mA
763.6mV   -21.21mA   -19.96mA   -21.19mA
2.145V    -30.84mA   -27.84mA   -31.6mA
2.606V    -26.91mA   -15.4mA    -28.18mA
2.779V    -19.8mA    -11.41mA   -27.59mA
3.124V    -10.1mA    -8.679mA   -12.28mA
3.585V    -8.2mA     -7.926mA   -8.247mA
[Ramp]
R_load=50.000Ohm
dV/dt_r   590.550mV/102.500ps  551.489mV/120.500ps  614.430mV/93.500ps
dV/dt_f   590.550mV/101.000ps  551.489mV/119.500ps  614.430mV/86.500ps
[Rising waveform]
R_fixture=50.000Ohm
V_fixture=1.800
V_fixture_min=1.700
V_fixture_max=1.900
0s        758.8mV    735.8mV    785.8mV
39ps      765.5mV    734.9mV    819.7mV
68ps      824.5mV    736.4mV    1.046V
96ps      1.013V     742.5mV    1.353V
125ps     1.28V      759.7mV    1.564V
163ps     1.521V     840.9mV    1.702V
202ps     1.638V     1.059V     1.763V
269ps     1.708V     1.443V     1.801V
345ps     1.729V     1.593V     1.812V
938ps     1.737V     1.65V      1.815V
[Rising waveform]
R_fixture=50.000Ohm
V_fixture=0
0s        -2.077mV   665.2uV    -2.863mV
39ps      -11.37mV   -399uV     3.385mV
77ps      33.31mV    -4.315mV   187.1mV
125ps     272.3mV    -13.85mV   521.4mV
163ps     500.9mV    281.4uV    714.1mV
202ps     683.3mV    93.47mV    839.8mV
259ps     844.8mV    353.2mV    938.8mV
345ps     944.9mV    688.8mV    995.1mV
441ps     978.7mV    850.2mV    1.013V
938ps     994.4mV    927.3mV    1.022V
[Falling waveform]
R_fixture=50.000Ohm
V_fixture=1.800
V_fixture_min=1.700
V_fixture_max=1.900
0s        1.741V     1.648V     1.821V
39ps      1.755V     1.651V     1.813V
77ps      1.701V     1.662V     1.618V
154ps     1.276V     1.65V      1.088V
192ps     1.076V     1.551V     948.4mV
240ps     920.2mV    1.334V     861.7mV
326ps     809.3mV    976.5mV    809.4mV
422ps     777mV      813mV      795.9mV
566ps     766.4mV    755.2mV    790.6mV
938ps     762.9mV    740.4mV    789.5mV
[Falling waveform]
R_fixture=50.000Ohm
V_fixture=0
0s        1.002V     931.3mV    1.028V
29ps      981.5mV    935.8mV    979.6mV
48ps      924.5mV    937.8mV    846.6mV
87ps      653.9mV    923.5mV    443.5mV
115ps     417.9mV    873.1mV    249.6mV
144ps     242.7mV    763.8mV    137.8mV
192ps     98.35mV    470.9mV    55.26mV
250ps     36.24mV    184.1mV    19.65mV
336ps     9.626mV    44.46mV    4.525mV
938ps     -3.064uV   34.02uV    -1uV
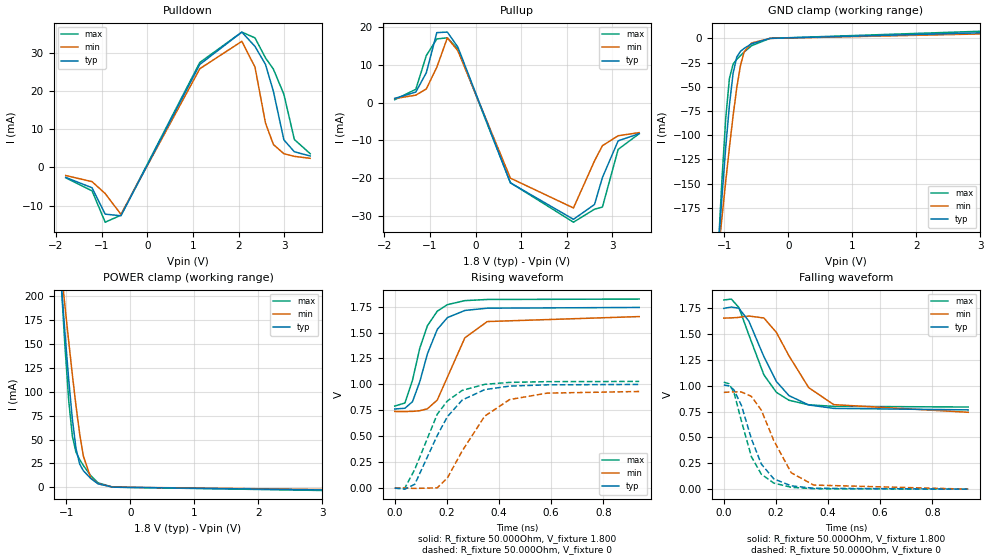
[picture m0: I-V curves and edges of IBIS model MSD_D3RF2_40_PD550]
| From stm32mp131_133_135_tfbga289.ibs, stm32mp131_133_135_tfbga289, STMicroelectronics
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[Model] MSD_D3RF2_40_PD550
Model_type   I/O
C_comp 2.402pF   2.319pF   2.523pF
Vinh = 1.150V
Vinl = 650.000mV
Vmeas = 900.000mV
Vref = 900.000mV
[Model Spec]
Vinh   1.150V   1.100V   1.200V
Vinl   650.000mV   600.000mV   700.000mV
Vmeas   900.000mV   850.000mV   950.000mV
Vref   900.000mV   850.000mV   950.000mV
[Temperature Range]   25.000   125.000   -40.000
[Voltage Range]   1.800V   1.700V   1.900V
[GND Clamp Reference]   0.00V   0.00V   0.00V
[Pulldown Reference]   0.00V   0.00V   0.00V
[POWER Clamp Reference]   1.800V   1.700V   1.900V
[Pullup Reference]   1.800V   1.700V   1.900V
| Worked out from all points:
|   slope of the pulldown table from 0 to 0.27 V, typ, clamps not added: 37.2 ohm
|   slope of the pullup table from 0 to 0.27 V, typ, clamps not added: 29.4 ohm
|   GND clamp passes 1 mA (typ) near -0.40 V on its own axis
|   POWER clamp passes 1 mA (typ) near -0.41 V on its own axis
|   rising waveform, R_fixture 50.000Ohm, V_fixture 1.800: 20-80 % time 79.1ps typ, 97.1ps min, 71.9ps max; typ from 0.762 V to 1.74 V
|   rising waveform, R_fixture 50.000Ohm, V_fixture 0: 20-80 % time 125ps typ, 143ps min, 115ps max; typ from -0.002 V to 0.999 V
|   falling waveform, R_fixture 50.000Ohm, V_fixture 1.800: 20-80 % time 116ps typ, 136ps min, 100ps max; typ from 1.75 V to 0.766 V
|   falling waveform, R_fixture 50.000Ohm, V_fixture 0: 20-80 % time 85.9ps typ, 102ps min, 74.6ps max; typ from 1.01 V to 0 V
[GND Clamp]
-1.785V   -902.5mA   -689.8mA   -1.211A
-1.094V   -215.2mA   -221.3mA   -216.1mA
-1.036V   -162.3mA   -184.1mA   -144mA
-978.8mV  -112.6mA   -147.7mA   -82.66mA
-921.2mV  -68.94mA   -112.7mA   -41.52mA
-863.6mV  -36.12mA   -79.94mA   -26.66mA
-806.1mV  -19.32mA   -50.9mA    -21.69mA
-748.5mV  -13.5mA    -28.05mA   -17.83mA
-690.9mV  -10.45mA   -14mA      -14.19mA
-575.8mV  -5.674mA   -4.868mA   -7.668mA
-287.9mV  -75.78uA   -126.4uA   -61.1uA
3.57V     6.676mA    5.321mA    8.541mA
[Power Clamp]
-1.77V    883.8mA    690.9mA    1.161A
-1.079V   213mA      227mA      212.9mA
-1.021V   161.4mA    189.7mA    147.4mA
-963.6mV  113.4mA    153.3mA    91.57mA
-906.1mV  71.59mA    118.1mA    53.46mA
-848.5mV  40.4mA     85.07mA    36.66mA
-790.9mV  24.12mA    55.69mA    28.9mA
-733.3mV  17.24mA    32.45mA    22.67mA
-618.2mV  9.128mA    9.881mA    12.16mA
-503mV    3.505mA    3.595mA    4.563mA
-272.7mV  30uA       102.8uA    29.36uA
3.585V    -3.38mA    -2.872mA   -4.063mA
[Pulldown]
-1.785V   -2.6mA     -2.1mA     -2.7mA
-1.209V   -5.3mA     -3.7mA     -6.1mA
-921.2mV  -12.19mA   -6.8mA     -14.29mA
-575.8mV  -12.61mA   -12.24mA   -12.47mA
1.152V    26.92mA    25.79mA    27.42mA
2.073V    35.36mA    32.95mA    35.36mA
2.361V    31.62mA    26.21mA    33.85mA
2.591V    26.91mA    11.6mA     28.62mA
2.764V    19.9mA     6mA        25.7mA
2.994V    7.2mA      3.6mA      19.1mA
3.224V    4.1mA      2.9mA      7.3mA
3.57V     3mA        2.4mA      3.6mA
[Pullup]
-1.77V    1.1mA      1.074mA    773.7uA
-1.309V   2.8mA      1.974mA    3.516mA
-1.079V   7.9mA      3.616mA    12.43mA
-848.5mV  18.5mA     9.365mA    16.83mA
-618.2mV  18.64mA    17.11mA    17.13mA
-387.9mV  14.68mA    13.71mA    14.14mA
763.6mV   -21.2mA    -19.96mA   -21.18mA
2.145V    -30.84mA   -27.84mA   -31.6mA
2.606V    -26.92mA   -15.4mA    -28.17mA
2.779V    -19.8mA    -11.38mA   -27.6mA
3.124V    -10.1mA    -8.753mA   -12.36mA
3.585V    -8.2mA     -7.926mA   -8.2mA
[Ramp]
R_load=50.000Ohm
dV/dt_r   592.680mV/103.000ps  553.109mV/120.500ps  617.310mV/94.000ps
dV/dt_f   592.680mV/101.000ps  553.109mV/120.000ps  617.310mV/88.000ps
[Rising waveform]
R_fixture=50.000Ohm
V_fixture=1.800
V_fixture_min=1.700
V_fixture_max=1.900
0s        762.1mV    738.3mV    790.2mV
39ps      769.4mV    737.5mV    820.2mV
68ps      832.5mV    739.2mV    1.04V
96ps      1.026V     745.5mV    1.349V
125ps     1.292V     763.5mV    1.564V
163ps     1.53V      848.1mV    1.706V
202ps     1.644V     1.069V     1.769V
269ps     1.713V     1.449V     1.808V
355ps     1.735V     1.606V     1.819V
938ps     1.742V     1.654V     1.823V
[Rising waveform]
R_fixture=50.000Ohm
V_fixture=0
0s        -2.223mV   658uV      -2.627mV
39ps      -11.59mV   -457uV     1.153mV
77ps      36.22mV    -4.471mV   180.3mV
163ps     506.7mV    1.57mV     711.8mV
202ps     688.4mV    96.86mV    840mV
259ps     848.8mV    358.2mV    941.8mV
345ps     949mV      692.7mV    1V
441ps     983.1mV    853.4mV    1.019V
585ps     995.2mV    915.4mV    1.026V
938ps     999.2mV    931mV      1.028V
[Falling waveform]
R_fixture=50.000Ohm
V_fixture=1.800
V_fixture_min=1.700
V_fixture_max=1.900
0s        1.747V     1.653V     1.828V
29ps      1.76V      1.655V     1.837V
58ps      1.748V     1.66V      1.755V
96ps      1.625V     1.673V     1.492V
154ps     1.28V      1.654V     1.104V
202ps     1.04V      1.514V     935.3mV
250ps     904.1mV    1.289V     859.4mV
326ps     813.8mV    980.7mV    815mV
422ps     780.7mV    816.8mV    800.5mV
938ps     766.2mV    743mV      793.8mV
[Falling waveform]
R_fixture=50.000Ohm
V_fixture=0
0s        1.007V     935mV      1.034V
20ps      998.2mV    938.1mV    1.019V
39ps      959.5mV    940.8mV    935.1mV
68ps      806.7mV    939.2mV    655mV
106ps     486.3mV    896.3mV    313.3mV
144ps     242.8mV    763.4mV    144.5mV
192ps     99.24mV    469.1mV    58.6mV
259ps     32.15mV    158mV      18.03mV
345ps     8.766mV    39.5mV     4.223mV
938ps     -6.728uV   44.01uV    7.356uV
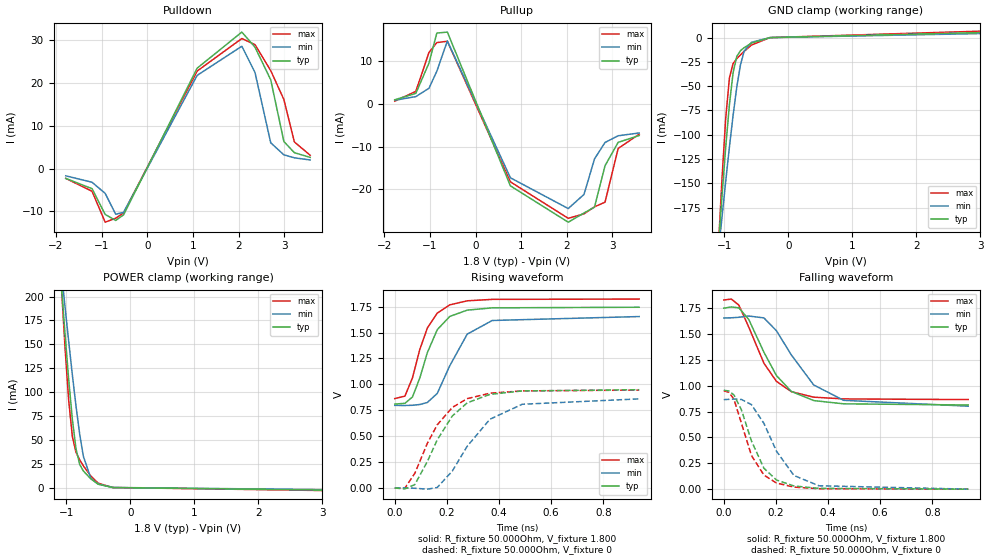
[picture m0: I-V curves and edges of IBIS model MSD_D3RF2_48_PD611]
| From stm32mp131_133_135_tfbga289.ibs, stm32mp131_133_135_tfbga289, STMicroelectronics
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[Model] MSD_D3RF2_48_PD611
Model_type   I/O
C_comp 2.419pF   2.337pF   2.541pF
Vinh = 1.150V
Vinl = 650.000mV
Vmeas = 900.000mV
Vref = 900.000mV
[Model Spec]
Vinh   1.150V   1.100V   1.200V
Vinl   650.000mV   600.000mV   700.000mV
Vmeas   900.000mV   850.000mV   950.000mV
Vref   900.000mV   850.000mV   950.000mV
[Temperature Range]   25.000   125.000   -40.000
[Voltage Range]   1.800V   1.700V   1.900V
[GND Clamp Reference]   0.00V   0.00V   0.00V
[Pulldown Reference]   0.00V   0.00V   0.00V
[POWER Clamp Reference]   1.800V   1.700V   1.900V
[Pullup Reference]   1.800V   1.700V   1.900V
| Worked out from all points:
|   slope of the pulldown table from 0 to 0.27 V, typ, clamps not added: 41 ohm
|   slope of the pullup table from 0 to 0.27 V, typ, clamps not added: 32.3 ohm
|   GND clamp passes 1 mA (typ) near -0.40 V on its own axis
|   POWER clamp passes 1 mA (typ) near -0.41 V on its own axis
|   rising waveform, R_fixture 50.000Ohm, V_fixture 1.800: 20-80 % time 83.3ps typ, 102ps min, 77.5ps max; typ from 0.809 V to 1.75 V
|   rising waveform, R_fixture 50.000Ohm, V_fixture 0: 20-80 % time 132ps typ, 155ps min, 126ps max; typ from -0.002 V to 0.948 V
|   falling waveform, R_fixture 50.000Ohm, V_fixture 1.800: 20-80 % time 122ps typ, 147ps min, 111ps max; typ from 1.75 V to 0.813 V
|   falling waveform, R_fixture 50.000Ohm, V_fixture 0: 20-80 % time 89.6ps typ, 109ps min, 81.3ps max; typ from 0.956 V to 0 V
[GND Clamp]
-1.785V   -902.8mA   -690.1mA   -1.212A
-1.094V   -215.3mA   -221.5mA   -216.2mA
-1.036V   -162.4mA   -184.2mA   -144.2mA
-978.8mV  -112.7mA   -147.8mA   -82.77mA
-921.2mV  -69.01mA   -112.7mA   -41.62mA
-863.6mV  -36.19mA   -80mA      -26.75mA
-806.1mV  -19.39mA   -50.94mA   -21.76mA
-748.5mV  -13.55mA   -28.08mA   -17.89mA
-690.9mV  -10.49mA   -14.03mA   -14.25mA
-575.8mV  -5.7mA     -4.889mA   -7.701mA
-287.9mV  -76.48uA   -127.3uA   -62uA
3.57V     6.005mA    4.786mA    7.679mA
[Power Clamp]
-1.77V    884.1mA    691.1mA    1.161A
-1.079V   213.2mA    227.1mA    213.1mA
-1.021V   161.5mA    189.8mA    147.5mA
-963.6mV  113.5mA    153.4mA    91.67mA
-906.1mV  71.67mA    118.2mA    53.57mA
-848.5mV  40.47mA    85.14mA    36.75mA
-790.9mV  24.17mA    55.75mA    28.98mA
-733.3mV  17.3mA     32.49mA    22.73mA
-618.2mV  9.163mA    9.916mA    12.2mA
-503mV    3.524mA    3.614mA    4.591mA
-272.7mV  32uA       104.5uA    32.1uA
3.585V    -3.042mA   -2.585mA   -3.657mA
[Pulldown]
-1.785V   -2.3mA     -1.7mA     -2.3mA
-1.209V   -4.7mA     -3.2mA     -5.3mA
-921.2mV  -10.71mA   -5.8mA     -12.52mA
-690.9mV  -12.11mA   -10.66mA   -11.59mA
-518.2mV  -10.81mA   -10.23mA   -10.35mA
1.094V    23.42mA    21.74mA    22.75mA
2.073V    31.84mA    28.54mA    30.34mA
2.361V    28.32mA    22.42mA    28.91mA
2.706V    20.7mA     6mA        22.85mA
2.994V    6.3mA      3.2mA      16.1mA
3.224V    3.7mA      2.5mA      6.2mA
3.57V     2.6mA      2mA        3.1mA
[Pullup]
-1.77V    1mA        873.7uA    673.7uA
-1.309V   2.5mA      1.747mA    2.963mA
-1.021V   9.6mA      3.689mA    12.09mA
-848.5mV  16.66mA    7.7mA      14.42mA
-618.2mV  16.89mA    14.81mA    14.74mA
763.6mV   -19.22mA   -17.32mA   -18.28mA
2.03V     -27.75mA   -24.55mA   -26.84mA
2.376V    -25.59mA   -21.23mA   -25.8mA
2.606V    -24.21mA   -12.89mA   -24.14mA
2.836V    -14.5mA    -9.032mA   -23.06mA
3.124V    -9mA       -7.453mA   -10.44mA
3.585V    -7.4mA     -6.8mA     -7.074mA
[Ramp]
R_load=50.000Ohm
dV/dt_r   564.030mV/108.500ps  514.679mV/129.000ps  570.960mV/102.500ps
dV/dt_f   564.030mV/106.500ps  514.679mV/129.000ps  570.960mV/97.000ps
[Rising waveform]
R_fixture=50.000Ohm
V_fixture=1.800
V_fixture_min=1.700
V_fixture_max=1.900
0s        809.2mV    796.4mV    862.4mV
39ps      816.8mV    795.7mV    886.1mV
68ps      878mV      797.7mV    1.063V
96ps      1.061V     805mV      1.337V
125ps     1.306V     824.6mV    1.544V
163ps     1.528V     912mV      1.688V
211ps     1.656V     1.179V     1.768V
278ps     1.717V     1.485V     1.807V
374ps     1.739V     1.617V     1.821V
938ps     1.745V     1.655V     1.824V
[Rising waveform]
R_fixture=50.000Ohm
V_fixture=0
0s        -1.817mV   585.4uV    -1.966mV
39ps      -10.61mV   -518.4uV   -1.585mV
77ps      31.63mV    -4.324mV   140mV
125ps     254.5mV    -13.01mV   429.8mV
163ps     463.6mV    3.168mV    608.7mV
221ps     694.7mV    162.4mV    777mV
278ps     821.3mV    401.4mV    861.6mV
365ps     902.9mV    662.5mV    914.4mV
489ps     936.2mV    807.4mV    936.7mV
938ps     948.1mV    859.4mV    944.4mV
[Falling waveform]
R_fixture=50.000Ohm
V_fixture=1.800
V_fixture_min=1.700
V_fixture_max=1.900
0s        1.749V     1.654V     1.828V
29ps      1.761V     1.656V     1.837V
58ps      1.752V     1.661V     1.778V
96ps      1.639V     1.673V     1.565V
154ps     1.323V     1.655V     1.217V
202ps     1.098V     1.531V     1.042V
259ps     945mV      1.298V     942.5mV
345ps     856.1mV    1.007V     889mV
460ps     824.6mV    858.4mV    872mV
938ps     813.4mV    801.9mV    865.7mV
[Falling waveform]
R_fixture=50.000Ohm
V_fixture=0
0s        956.1mV    864.9mV    949.8mV
20ps      947.8mV    868.1mV    936.2mV
39ps      910.5mV    870.5mV    868.9mV
68ps      764.4mV    866.5mV    634.5mV
106ps     466.9mV    817.1mV    325.9mV
154ps     202.7mV    635.8mV    135.8mV
202ps     88.59mV    368mV      59.4mV
269ps     30.88mV    132.4mV    19.79mV
365ps     7.776mV    32.72mV    4.483mV
938ps     -10.96uV   57.4uV     -20.01uV
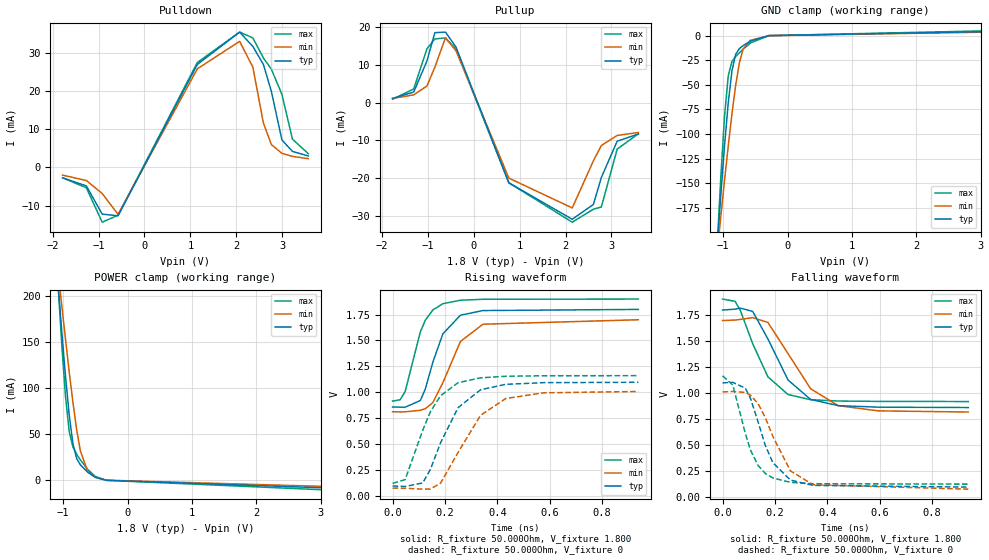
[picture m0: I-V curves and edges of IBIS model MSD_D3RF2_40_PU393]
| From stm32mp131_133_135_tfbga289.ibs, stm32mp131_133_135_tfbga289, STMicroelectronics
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[Model] MSD_D3RF2_40_PU393
Model_type   I/O
C_comp 2.345pF   2.264pF   2.466pF
Vinh = 1.150V
Vinl = 650.000mV
Vmeas = 900.000mV
Vref = 900.000mV
[Model Spec]
Vinh   1.150V   1.100V   1.200V
Vinl   650.000mV   600.000mV   700.000mV
Vmeas   900.000mV   850.000mV   950.000mV
Vref   900.000mV   850.000mV   950.000mV
[Temperature Range]   25.000   125.000   -40.000
[Voltage Range]   1.800V   1.700V   1.900V
[GND Clamp Reference]   0.00V   0.00V   0.00V
[Pulldown Reference]   0.00V   0.00V   0.00V
[POWER Clamp Reference]   1.800V   1.700V   1.900V
[Pullup Reference]   1.800V   1.700V   1.900V
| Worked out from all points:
|   slope of the pulldown table from 0 to 0.27 V, typ, clamps not added: 37.2 ohm
|   slope of the pullup table from 0 to 0.27 V, typ, clamps not added: 29.4 ohm
|   GND clamp passes 1 mA (typ) near -0.41 V on its own axis
|   POWER clamp passes 1 mA (typ) near -0.41 V on its own axis
|   rising waveform, R_fixture 50.000Ohm, V_fixture 1.800: 20-80 % time 75.4ps typ, 93.5ps min, 66.8ps max; typ from 0.857 V to 1.8 V
|   rising waveform, R_fixture 50.000Ohm, V_fixture 0: 20-80 % time 114ps typ, 133ps min, 102ps max; typ from 0.094 V to 1.1 V
|   falling waveform, R_fixture 50.000Ohm, V_fixture 1.800: 20-80 % time 117ps typ, 137ps min, 103ps max; typ from 1.8 V to 0.86 V
|   falling waveform, R_fixture 50.000Ohm, V_fixture 0: 20-80 % time 86.4ps typ, 103ps min, 75.2ps max; typ from 1.1 V to 0.093 V
[GND Clamp]
-1.785V   -901.6mA   -689mA     -1.21A
-1.094V   -214.8mA   -221mA     -215.5mA
-1.036V   -162mA     -183.8mA   -143.6mA
-978.8mV  -112.3mA   -147.4mA   -82.21mA
-921.2mV  -68.61mA   -112.4mA   -41.12mA
-863.6mV  -35.84mA   -79.69mA   -26.31mA
-806.1mV  -19.09mA   -50.68mA   -21.38mA
-748.5mV  -13.3mA    -27.86mA   -17.56mA
-690.9mV  -10.28mA   -13.84mA   -13.97mA
-575.8mV  -5.56mA    -4.768mA   -7.53mA
-287.9mV  -69.99uA   -117uA     -56.99uA
3.57V     4.61mA     3.97mA     5.507mA
[Power Clamp]
-1.77V    883mA      690.2mA    1.159A
-1.079V   212.6mA    226.6mA    212.4mA
-1.021V   161mA      189.5mA    146.9mA
-963.6mV  113.1mA    153.1mA    91.15mA
-906.1mV  71.31mA    117.9mA    53.09mA
-848.5mV  40.15mA    84.87mA    36.33mA
-790.9mV  23.9mA     55.52mA    28.61mA
-733.3mV  17.07mA    32.3mA     22.42mA
-618.2mV  9.01mA     9.784mA    12.01mA
-503mV    3.446mA    3.544mA    4.486mA
-330.3mV  160.6uA    336.1uA    187.2uA
3.585V    -9.248mA   -7.505mA   -11.75mA
[Pulldown]
-1.785V   -2.7mA     -2mA       -2.7mA
-1.267V   -4.8mA     -3.4mA     -5.3mA
-921.2mV  -12.19mA   -6.8mA     -14.29mA
-575.8mV  -12.61mA   -12.24mA   -12.47mA
1.152V    26.93mA    25.78mA    27.43mA
2.073V    35.36mA    32.95mA    35.37mA
2.361V    31.62mA    26.22mA    33.85mA
2.591V    26.91mA    11.6mA     28.61mA
2.764V    19.9mA     6mA        25.7mA
2.994V    7.2mA      3.7mA      19.1mA
3.224V    4.2mA      2.9mA      7.4mA
3.57V     3mA        2.3mA      3.6mA
[Pullup]
-1.77V    1.1mA      1.1mA      873.7uA
-1.309V   2.8mA      2.047mA    3.616mA
-1.021V   11mA       4.389mA    14.22mA
-848.5mV  18.49mA    9.365mA    16.82mA
-618.2mV  18.64mA    17.12mA    17.12mA
-387.9mV  14.68mA    13.71mA    14.13mA
763.6mV   -21.2mA    -19.96mA   -21.19mA
2.145V    -30.84mA   -27.84mA   -31.61mA
2.606V    -26.91mA   -15.39mA   -28.18mA
2.779V    -19.8mA    -11.34mA   -27.59mA
3.124V    -10.2mA    -8.679mA   -12.28mA
3.585V    -8.3mA     -7.9mA     -8.247mA
[Ramp]
R_load=50.000Ohm
dV/dt_r   582.768mV/95.000ps  545.409mV/114.000ps  606.030mV/85.000ps
dV/dt_f   582.768mV/102.500ps  545.409mV/121.000ps  606.030mV/89.000ps
[Rising waveform]
R_fixture=50.000Ohm
V_fixture=1.800
V_fixture_min=1.700
V_fixture_max=1.900
0s        857.2mV    811.1mV    913.8mV
29ps      855.6mV    810.2mV    927.1mV
48ps      855.5mV    810.6mV    1.006V
106ps     919.6mV    825.3mV    1.583V
125ps     1.031V     841.2mV    1.696V
154ps     1.292V     900.4mV    1.795V
192ps     1.564V     1.092V     1.855V
259ps     1.744V     1.49V      1.889V
345ps     1.789V     1.657V     1.898V
938ps     1.8V       1.7V       1.9V
[Rising waveform]
R_fixture=50.000Ohm
V_fixture=0
0s        93.7mV     73.73mV    119.1mV
48ps      89.89mV    72.14mV    155.2mV
115ps     123.1mV    63.17mV    631.9mV
144ps     252mV      64.03mV    809.5mV
183ps     510.2mV    120.6mV    965.4mV
250ps     850.6mV    418.1mV    1.092V
336ps     1.024V     777.7mV    1.139V
432ps     1.076V     938.9mV    1.154V
575ps     1.092V     993.9mV    1.159V
938ps     1.096V     1.007V     1.16V
[Falling waveform]
R_fixture=50.000Ohm
V_fixture=1.800
V_fixture_min=1.700
V_fixture_max=1.900
0s        1.799V     1.698V     1.905V
48ps      1.808V     1.703V     1.883V
68ps      1.818V     1.709V     1.794V
115ps     1.786V     1.726V     1.475V
173ps     1.521V     1.68V      1.156V
250ps     1.125V     1.379V     984.9mV
336ps     938mV      1.041V     935.5mV
441ps     878.3mV    878.3mV    922.4mV
595ps     863.4mV    827.7mV    919mV
938ps     860mV      816.7mV    917.8mV
[Falling waveform]
R_fixture=50.000Ohm
V_fixture=0
0s        1.097V     1.01V      1.166V
39ps      1.103V     1.015V     1.077V
87ps      1.046V     1.005V     609.3mV
106ps     952.2mV    980.7mV    453.7mV
135ps     725.3mV    899.7mV    303.3mV
163ps     496mV      764.1mV    225mV
192ps     328.3mV    581.1mV    181.1mV
259ps     161.2mV    249.8mV    139.4mV
345ps     109.7mV    116.3mV    125.7mV
938ps     93.26mV    73.42mV    122mV
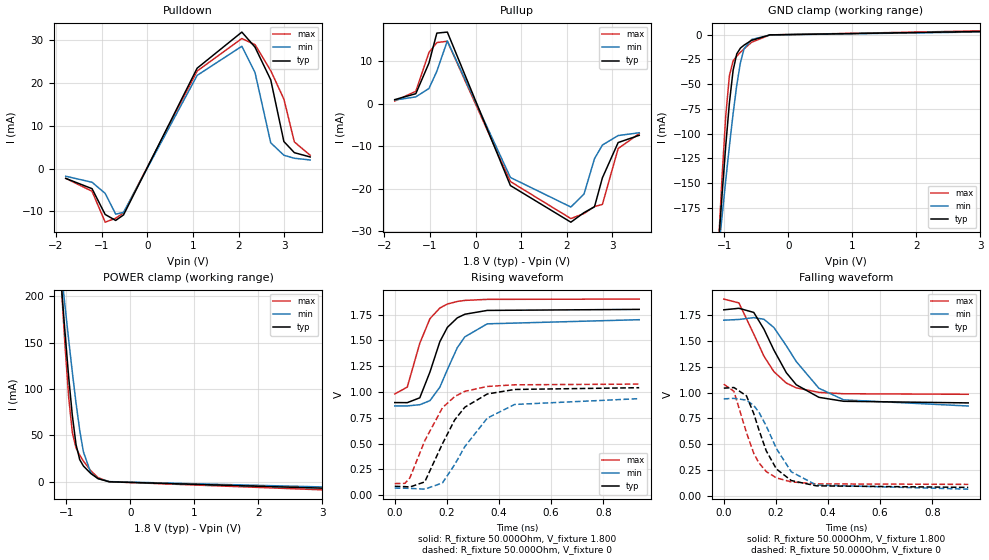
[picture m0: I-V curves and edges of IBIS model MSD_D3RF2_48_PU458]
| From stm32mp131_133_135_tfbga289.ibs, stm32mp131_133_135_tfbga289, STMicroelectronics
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[Model] MSD_D3RF2_48_PU458
Model_type   I/O
C_comp 2.374pF   2.292pF   2.496pF
Vinh = 1.150V
Vinl = 650.000mV
Vmeas = 900.000mV
Vref = 900.000mV
[Model Spec]
Vinh   1.150V   1.100V   1.200V
Vinl   650.000mV   600.000mV   700.000mV
Vmeas   900.000mV   850.000mV   950.000mV
Vref   900.000mV   850.000mV   950.000mV
[Temperature Range]   25.000   125.000   -40.000
[Voltage Range]   1.800V   1.700V   1.900V
[GND Clamp Reference]   0.00V   0.00V   0.00V
[Pulldown Reference]   0.00V   0.00V   0.00V
[POWER Clamp Reference]   1.800V   1.700V   1.900V
[Pullup Reference]   1.800V   1.700V   1.900V
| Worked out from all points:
|   slope of the pulldown table from 0 to 0.27 V, typ, clamps not added: 41 ohm
|   slope of the pullup table from 0 to 0.27 V, typ, clamps not added: 32.3 ohm
|   GND clamp passes 1 mA (typ) near -0.40 V on its own axis
|   POWER clamp passes 1 mA (typ) near -0.41 V on its own axis
|   rising waveform, R_fixture 50.000Ohm, V_fixture 1.800: 20-80 % time 79.6ps typ, 98.7ps min, 72.8ps max; typ from 0.897 V to 1.8 V
|   rising waveform, R_fixture 50.000Ohm, V_fixture 0: 20-80 % time 122ps typ, 145ps min, 114ps max; typ from 0.085 V to 1.04 V
|   falling waveform, R_fixture 50.000Ohm, V_fixture 1.800: 20-80 % time 124ps typ, 149ps min, 115ps max; typ from 1.8 V to 0.9 V
|   falling waveform, R_fixture 50.000Ohm, V_fixture 0: 20-80 % time 90.4ps typ, 111ps min, 81.7ps max; typ from 1.04 V to 0.085 V
[GND Clamp]
-1.785V   -902.1mA   -689.3mA   -1.211A
-1.094V   -215mA     -221.2mA   -215.8mA
-1.036V   -162.1mA   -183.9mA   -143.7mA
-978.8mV  -112.5mA   -147.5mA   -82.43mA
-921.2mV  -68.76mA   -112.6mA   -41.32mA
-863.6mV  -35.98mA   -79.81mA   -26.48mA
-806.1mV  -19.2mA    -50.78mA   -21.53mA
-748.5mV  -13.39mA   -27.95mA   -17.68mA
-690.9mV  -10.36mA   -13.92mA   -14.07mA
-575.8mV  -5.615mA   -4.814mA   -7.598mA
-287.9mV  -70.99uA   -120uA     -56.99uA
3.57V     3.952mA    3.403mA    4.721mA
[Power Clamp]
-1.77V    883.4mA    690.7mA    1.16A
-1.079V   212.8mA    226.9mA    212.7mA
-1.021V   161.2mA    189.6mA    147.2mA
-963.6mV  113.2mA    153.2mA    91.32mA
-906.1mV  71.46mA    118mA      53.29mA
-848.5mV  40.28mA    85mA       36.5mA
-790.9mV  24.01mA    55.62mA    28.77mA
-733.3mV  17.16mA    32.39mA    22.55mA
-618.2mV  9.07mA     9.843mA    12.09mA
-503mV    3.48mA     3.576mA    4.528mA
-330.3mV  164.3uA    342.2uA    191.7uA
3.585V    -7.932mA   -6.431mA   -10.07mA
[Pulldown]
-1.785V   -2.3mA     -1.8mA     -2.3mA
-1.209V   -4.7mA     -3.2mA     -5.3mA
-921.2mV  -10.72mA   -5.8mA     -12.52mA
-690.9mV  -12.11mA   -10.65mA   -11.59mA
-518.2mV  -10.81mA   -10.23mA   -10.36mA
1.094V    23.42mA    21.74mA    22.76mA
2.073V    31.84mA    28.53mA    30.34mA
2.361V    28.33mA    22.42mA    28.91mA
2.706V    20.7mA     6mA        22.85mA
2.994V    6.3mA      3.1mA      16.2mA
3.224V    3.7mA      2.4mA      6.2mA
3.57V     2.7mA      2mA        3.1mA
[Pullup]
-1.77V    1mA        900uA      673.7uA
-1.309V   2.4mA      1.647mA    2.963mA
-1.021V   9.6mA      3.616mA    12.09mA
-848.5mV  16.65mA    7.674mA    14.42mA
-618.2mV  16.89mA    14.81mA    14.74mA
763.6mV   -19.22mA   -17.32mA   -18.28mA
2.088V    -27.84mA   -24.27mA   -26.99mA
2.376V    -25.59mA   -21.22mA   -25.81mA
2.606V    -24.21mA   -12.89mA   -24.15mA
2.779V    -17.4mA    -9.684mA   -23.66mA
3.124V    -9.1mA     -7.453mA   -10.51mA
3.585V    -7.4mA     -6.8mA     -7mA
[Ramp]
R_load=50.000Ohm
dV/dt_r   556.947mV/101.500ps  509.580mV/122.500ps  563.610mV/94.000ps
dV/dt_f   556.947mV/108.000ps  509.580mV/130.000ps  563.610mV/99.000ps
[Rising waveform]
R_fixture=50.000Ohm
V_fixture=1.800
V_fixture_min=1.700
V_fixture_max=1.900
0s        897mV      864.8mV    980mV
48ps      896.1mV    864.6mV    1.047V
96ps      943.1mV    876.1mV    1.472V
135ps     1.193V     915.7mV    1.71V
173ps     1.487V     1.046V     1.813V
202ps     1.626V     1.217V     1.852V
240ps     1.718V     1.429V     1.877V
269ps     1.753V     1.534V     1.887V
355ps     1.79V      1.66V      1.897V
938ps     1.8V       1.7V       1.9V
[Rising waveform]
R_fixture=50.000Ohm
V_fixture=0
0s        85.25mV    68.01mV    111.9mV
39ps      82.43mV    66.89mV    114mV
58ps      78.76mV    65.5mV     167.3mV
115ps     128.2mV    57.77mV    526.8mV
183ps     497.8mV    118.2mV    846.8mV
230ps     729.4mV    296.1mV    955.4mV
269ps     852.3mV    470.9mV    1.006V
355ps     980.1mV    746.1mV    1.053V
460ps     1.024V     878.6mV    1.069V
938ps     1.041V     935mV      1.076V
[Falling waveform]
R_fixture=50.000Ohm
V_fixture=1.800
V_fixture_min=1.700
V_fixture_max=1.900
0s        1.799V     1.699V     1.903V
58ps      1.814V     1.706V     1.866V
115ps     1.774V     1.724V     1.565V
154ps     1.613V     1.708V     1.352V
192ps     1.412V     1.629V     1.203V
240ps     1.192V     1.452V     1.092V
278ps     1.076V     1.3V       1.046V
365ps     954.4mV    1.042V     1.002V
460ps     916.2mV    929.9mV    988.9mV
938ps     900.5mV    870.7mV    983.7mV
[Falling waveform]
R_fixture=50.000Ohm
V_fixture=0
0s        1.043V     939.3mV    1.081V
39ps      1.049V     944.6mV    1.012V
87ps      968.8mV    927.7mV    613.7mV
115ps     797.6mV    875.7mV    413.7mV
135ps     638.4mV    810.1mV    320.7mV
163ps     437.4mV    678mV      237.5mV
202ps     262.3mV    459.1mV    176.5mV
259ps     150.9mV    235.3mV    137.9mV
355ps     99.86mV    107.7mV    118.8mV
938ps     84.84mV    67.76mV    113.9mV
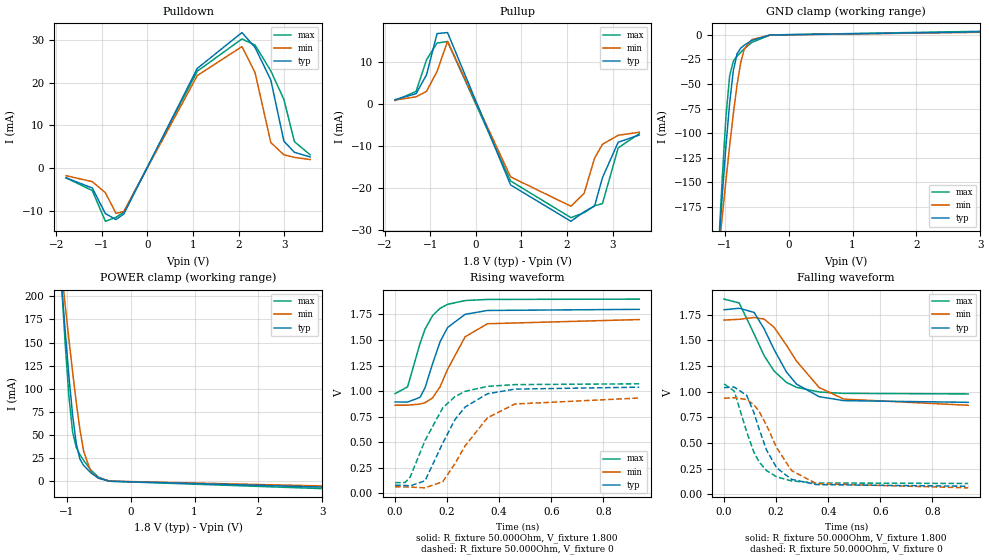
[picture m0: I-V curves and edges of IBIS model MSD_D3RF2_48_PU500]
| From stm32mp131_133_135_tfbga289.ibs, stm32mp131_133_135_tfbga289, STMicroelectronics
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[Model] MSD_D3RF2_48_PU500
Model_type   I/O
C_comp 2.391pF   2.309pF   2.512pF
Vinh = 1.150V
Vinl = 650.000mV
Vmeas = 900.000mV
Vref = 900.000mV
[Model Spec]
Vinh   1.150V   1.100V   1.200V
Vinl   650.000mV   600.000mV   700.000mV
Vmeas   900.000mV   850.000mV   950.000mV
Vref   900.000mV   850.000mV   950.000mV
[Temperature Range]   25.000   125.000   -40.000
[Voltage Range]   1.800V   1.700V   1.900V
[GND Clamp Reference]   0.00V   0.00V   0.00V
[Pulldown Reference]   0.00V   0.00V   0.00V
[POWER Clamp Reference]   1.800V   1.700V   1.900V
[Pullup Reference]   1.800V   1.700V   1.900V
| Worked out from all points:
|   slope of the pulldown table from 0 to 0.27 V, typ, clamps not added: 41 ohm
|   slope of the pullup table from 0 to 0.27 V, typ, clamps not added: 32.3 ohm
|   GND clamp passes 1 mA (typ) near -0.40 V on its own axis
|   POWER clamp passes 1 mA (typ) near -0.41 V on its own axis
|   rising waveform, R_fixture 50.000Ohm, V_fixture 1.800: 20-80 % time 80.2ps typ, 99.3ps min, 73.5ps max; typ from 0.893 V to 1.8 V
|   rising waveform, R_fixture 50.000Ohm, V_fixture 0: 20-80 % time 123ps typ, 146ps min, 115ps max; typ from 0.078 V to 1.04 V
|   falling waveform, R_fixture 50.000Ohm, V_fixture 1.800: 20-80 % time 124ps typ, 149ps min, 116ps max; typ from 1.8 V to 0.896 V
|   falling waveform, R_fixture 50.000Ohm, V_fixture 0: 20-80 % time 90.9ps typ, 111ps min, 82.3ps max; typ from 1.04 V to 0.078 V
[GND Clamp]
-1.785V   -902.2mA   -689.6mA   -1.211A
-1.094V   -215.1mA   -221.3mA   -215.9mA
-1.036V   -162.2mA   -184mA     -143.9mA
-978.8mV  -112.6mA   -147.6mA   -82.55mA
-921.2mV  -68.85mA   -112.6mA   -41.42mA
-863.6mV  -36.04mA   -79.87mA   -26.57mA
-806.1mV  -19.26mA   -50.83mA   -21.61mA
-748.5mV  -13.45mA   -27.99mA   -17.76mA
-690.9mV  -10.4mA    -13.95mA   -14.13mA
-575.8mV  -5.644mA   -4.836mA   -7.63mA
-287.9mV  -71.99uA   -121uA     -59.99uA
3.57V     3.622mA    3.119mA    4.327mA
[Power Clamp]
-1.77V    883.7mA    690.8mA    1.16A
-1.079V   212.9mA    226.9mA    212.8mA
-1.021V   161.4mA    189.7mA    147.3mA
-963.6mV  113.3mA    153.2mA    91.44mA
-906.1mV  71.54mA    118.1mA    53.38mA
-848.5mV  40.35mA    85.05mA    36.59mA
-790.9mV  24.07mA    55.67mA    28.84mA
-733.3mV  17.21mA    32.43mA    22.61mA
-618.2mV  9.105mA    9.871mA    12.13mA
-503mV    3.496mA    3.593mA    4.55mA
-330.3mV  166.1uA    345.1uA    193.6uA
3.585V    -7.27mA    -5.895mA   -9.227mA
[Pulldown]
-1.785V   -2.3mA     -1.8mA     -2.3mA
-1.209V   -4.7mA     -3.2mA     -5.3mA
-921.2mV  -10.71mA   -5.8mA     -12.52mA
-690.9mV  -12.11mA   -10.66mA   -11.59mA
-518.2mV  -10.81mA   -10.23mA   -10.36mA
1.094V    23.42mA    21.74mA    22.76mA
2.073V    31.84mA    28.54mA    30.34mA
2.361V    28.33mA    22.42mA    28.91mA
2.706V    20.7mA     6mA        22.84mA
2.994V    6.3mA      3.1mA      16.1mA
3.224V    3.7mA      2.5mA      6.2mA
3.57V     2.6mA      2mA        3.1mA
[Pullup]
-1.77V    1mA        900uA      773.7uA
-1.309V   2.4mA      1.647mA    2.937mA
-1.079V   6.9mA      2.968mA    10.45mA
-848.5mV  16.65mA    7.7mA      14.42mA
-618.2mV  16.89mA    14.82mA    14.75mA
763.6mV   -19.22mA   -17.31mA   -18.28mA
2.088V    -27.84mA   -24.27mA   -26.98mA
2.376V    -25.59mA   -21.23mA   -25.8mA
2.606V    -24.21mA   -12.89mA   -24.15mA
2.779V    -17.5mA    -9.584mA   -23.66mA
3.124V    -9.1mA     -7.453mA   -10.44mA
3.585V    -7.4mA     -6.726mA   -7.074mA
[Ramp]
R_load=50.000Ohm
dV/dt_r   559.104mV/102.500ps  511.215mV/123.000ps  566.370mV/95.000ps
dV/dt_f   559.104mV/109.000ps  511.215mV/130.500ps  566.370mV/100.000ps
[Rising waveform]
R_fixture=50.000Ohm
V_fixture=1.800
V_fixture_min=1.700
V_fixture_max=1.900
0s        893mV      861.6mV    974.6mV
48ps      892mV      861.4mV    1.041V
96ps      938.6mV    872.7mV    1.466V
115ps     1.031V     886mV      1.605V
144ps     1.266V     932.4mV    1.738V
173ps     1.483V     1.042V     1.81V
202ps     1.622V     1.213V     1.849V
269ps     1.751V     1.531V     1.886V
355ps     1.789V     1.659V     1.897V
938ps     1.8V       1.7V       1.9V
[Rising waveform]
R_fixture=50.000Ohm
V_fixture=0
0s        78.47mV    62.57mV    102.9mV
39ps      75.65mV    61.45mV    104.8mV
58ps      71.95mV    60.05mV    157.9mV
115ps     120.9mV    52.19mV    514.9mV
183ps     488.4mV    112mV      835.1mV
230ps     719.9mV    288.7mV    945.2mV
269ps     843.6mV    462.9mV    996.9mV
355ps     973.7mV    738.7mV    1.046V
460ps     1.019V     873.1mV    1.063V
938ps     1.038V     931.8mV    1.071V
[Falling waveform]
R_fixture=50.000Ohm
V_fixture=1.800
V_fixture_min=1.700
V_fixture_max=1.900
0s        1.799V     1.699V     1.903V
58ps      1.814V     1.706V     1.866V
115ps     1.774V     1.724V     1.565V
154ps     1.613V     1.708V     1.351V
192ps     1.412V     1.629V     1.202V
240ps     1.191V     1.452V     1.09V
278ps     1.075V     1.3V       1.043V
365ps     952mV      1.041V     997.3mV
460ps     912.9mV    928.1mV    983.9mV
938ps     896.4mV    867.6mV    978.3mV
[Falling waveform]
R_fixture=50.000Ohm
V_fixture=0
0s        1.04V      936.2mV    1.076V
39ps      1.045V     941.5mV    1.006V
87ps      964.6mV    924.4mV    607.3mV
115ps     793mV      872.1mV    407.4mV
135ps     633.5mV    806.3mV    314.3mV
163ps     432.6mV    673.9mV    231mV
202ps     257.5mV    454.8mV    169.3mV
259ps     145.7mV    231.1mV    130mV
355ps     93.84mV    103.2mV    110.3mV
938ps     78.06mV    62.31mV    104.9mV
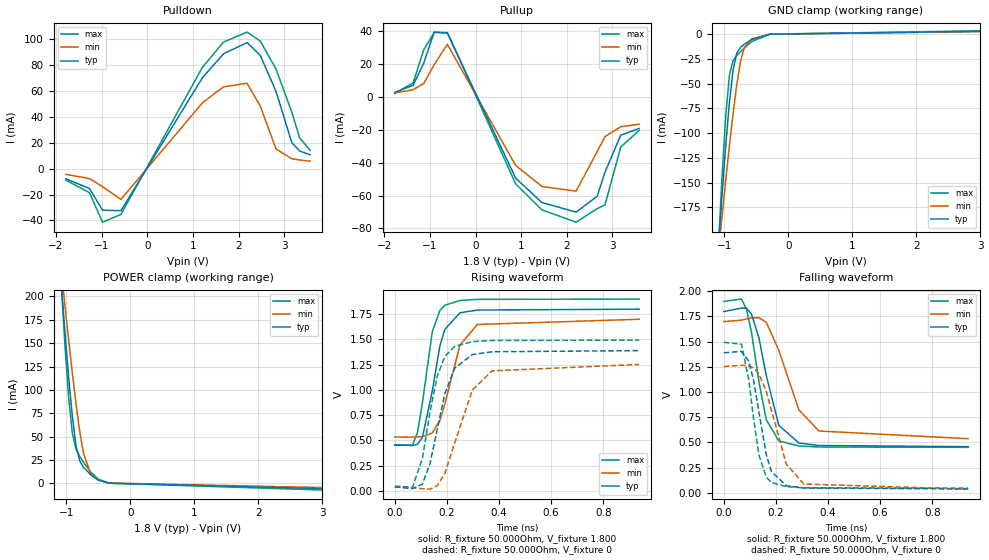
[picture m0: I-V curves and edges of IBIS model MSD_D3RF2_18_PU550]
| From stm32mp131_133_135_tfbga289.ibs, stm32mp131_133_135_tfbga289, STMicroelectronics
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[Model] MSD_D3RF2_18_PU550
Model_type   I/O
C_comp 2.403pF   2.321pF   2.525pF
Vinh = 1.150V
Vinl = 650.000mV
Vmeas = 900.000mV
Vref = 900.000mV
[Model Spec]
Vinh   1.150V   1.100V   1.200V
Vinl   650.000mV   600.000mV   700.000mV
Vmeas   900.000mV   850.000mV   950.000mV
Vref   900.000mV   850.000mV   950.000mV
[Temperature Range]   25.000   125.000   -40.000
[Voltage Range]   1.800V   1.700V   1.900V
[GND Clamp Reference]   0.00V   0.00V   0.00V
[Pulldown Reference]   0.00V   0.00V   0.00V
[POWER Clamp Reference]   1.800V   1.700V   1.900V
[Pullup Reference]   1.800V   1.700V   1.900V
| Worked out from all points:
|   slope of the pulldown table from 0 to 0.27 V, typ, clamps not added: 15.3 ohm
|   slope of the pullup table from 0 to 0.27 V, typ, clamps not added: 14.6 ohm
|   GND clamp passes 1 mA (typ) near -0.40 V on its own axis
|   POWER clamp passes 1 mA (typ) near -0.41 V on its own axis
|   rising waveform, R_fixture 50.000Ohm, V_fixture 1.800: 20-80 % time 56ps typ, 71.8ps min, 48.7ps max; typ from 0.456 V to 1.8 V
|   rising waveform, R_fixture 50.000Ohm, V_fixture 0: 20-80 % time 72.6ps typ, 92.3ps min, 63.8ps max; typ from 0.039 V to 1.39 V
|   falling waveform, R_fixture 50.000Ohm, V_fixture 1.800: 20-80 % time 66.8ps typ, 94.7ps min, 56.5ps max; typ from 1.8 V to 0.458 V
|   falling waveform, R_fixture 50.000Ohm, V_fixture 0: 20-80 % time 56.1ps typ, 78.3ps min, 47.3ps max; typ from 1.39 V to 0.038 V
[GND Clamp]
-1.785V   -902.5mA   -689.8mA   -1.211A
-1.094V   -215.3mA   -221.3mA   -216.1mA
-1.036V   -162.4mA   -184mA     -144mA
-978.8mV  -112.7mA   -147.7mA   -82.66mA
-921.2mV  -68.92mA   -112.7mA   -41.51mA
-863.6mV  -36.11mA   -79.92mA   -26.65mA
-806.1mV  -19.32mA   -50.89mA   -21.68mA
-748.5mV  -13.5mA    -28.03mA   -17.81mA
-690.9mV  -10.44mA   -13.99mA   -14.19mA
-575.8mV  -5.673mA   -4.859mA   -7.667mA
-287.9mV  -73.99uA   -123uA     -58.99uA
3.57V     3.293mA    2.836mA    3.934mA
[Power Clamp]
-1.77V    883.9mA    691mA      1.161A
-1.079V   213mA      227mA      212.9mA
-1.021V   161.5mA    189.8mA    147.4mA
-963.6mV  113.4mA    153.4mA    91.56mA
-906.1mV  71.61mA    118.2mA    53.48mA
-848.5mV  40.42mA    85.13mA    36.67mA
-790.9mV  24.13mA    55.72mA    28.91mA
-733.3mV  17.27mA    32.47mA    22.68mA
-618.2mV  9.14mA     9.901mA    12.17mA
-503mV    3.513mA    3.609mA    4.571mA
-330.3mV  167.9uA    348uA      196.2uA
3.585V    -6.609mA   -5.357mA   -8.396mA
[Pulldown]
-1.785V   -7.8mA     -4.4mA     -8.8mA
-1.267V   -15.3mA    -7.6mA     -18.5mA
-978.8mV  -32.1mA    -13.9mA    -41.4mA
-575.8mV  -32.49mA   -23.76mA   -35.4mA
1.209V    70.38mA    50.92mA    78.44mA
1.67V     88.85mA    63.32mA    97.95mA
2.188V    97.57mA    66.1mA     105.7mA
2.476V    87.81mA    48.5mA     98.74mA
2.821V    59.8mA     15.3mA     77.21mA
3.167V    20.2mA     7.7mA      43.8mA
3.339V    13.7mA     6.7mA      23.9mA
3.57V     10.7mA     5.8mA      14.2mA
[Pullup]
-1.77V    2.9mA      2.547mA    2.179mA
-1.367V   7.2mA      4.495mA    8.716mA
-1.136V   20.6mA     8.305mA    28.74mA
-906.1mV  39.6mA     19.75mA    39.4mA
-618.2mV  38.98mA    32.14mA    39.32mA
878.8mV   -49.38mA   -41.66mA   -52.89mA
1.455V    -64.25mA   -54.45mA   -68.75mA
2.203V    -70.07mA   -57.29mA   -76.21mA
2.664V    -60.47mA   -33.26mA   -67.94mA
2.836V    -45.7mA    -24.05mA   -65.61mA
3.182V    -23.2mA    -18.03mA   -30.35mA
3.585V    -19.1mA    -16.53mA   -20.27mA
[Ramp]
R_load=50.000Ohm
dV/dt_r   808.116mV/65.500ps  713.817mV/82.500ps  868.821mV/56.500ps
dV/dt_f   808.116mV/62.000ps  713.817mV/87.500ps  868.821mV/52.500ps
[Rising waveform]
R_fixture=50.000Ohm
V_fixture=1.800
V_fixture_min=1.700
V_fixture_max=1.900
0s        456.4mV    534mV      450.8mV
68ps      449.3mV    532.7mV    454.7mV
87ps      460.7mV    534mV      575mV
106ps     528.8mV    537.6mV    870.5mV
144ps     989.7mV    572.5mV    1.576V
173ps     1.434V     695.5mV    1.786V
192ps     1.599V     859.8mV    1.839V
250ps     1.764V     1.443V     1.886V
317ps     1.791V     1.648V     1.897V
938ps     1.8V       1.7V       1.9V
[Rising waveform]
R_fixture=50.000Ohm
V_fixture=0
0s        38.55mV    36.95mV    46.91mV
68ps      22.03mV    31.15mV    35.63mV
106ps     66.45mV    21.36mV    319.8mV
135ps     268.4mV    16.39mV    776.5mV
163ps     609.6mV    50.51mV    1.137V
192ps     960.9mV    171.5mV    1.33V
230ps     1.216V     473.6mV    1.431V
298ps     1.35V      1V         1.478V
374ps     1.378V     1.189V     1.49V
938ps     1.389V     1.252V     1.493V
[Falling waveform]
R_fixture=50.000Ohm
V_fixture=1.800
V_fixture_min=1.700
V_fixture_max=1.900
0s        1.798V     1.698V     1.899V
68ps      1.833V     1.713V     1.922V
87ps      1.831V     1.725V     1.821V
106ps     1.775V     1.735V     1.597V
135ps     1.535V     1.737V     1.1V
163ps     1.163V     1.691V     726.1mV
211ps     669.8mV    1.415V     515.1mV
288ps     494.4mV    823.6mV    464.4mV
365ps     469.5mV    613mV      454.6mV
938ps     457.7mV    537mV      451.1mV
[Falling waveform]
R_fixture=50.000Ohm
V_fixture=0
0s        1.389V     1.253V     1.493V
68ps      1.403V     1.265V     1.474V
96ps      1.306V     1.26V      1.12V
115ps     1.108V     1.237V     721.4mV
135ps     798.6mV    1.179V     373.7mV
163ps     378.9mV    1.006V     155.8mV
183ps     210.3mV    818mV      102.1mV
240ps     70.94mV    284.2mV    60.29mV
307ps     47.7mV     87.07mV    49.93mV
938ps     37.68mV    36.24mV    46.02mV
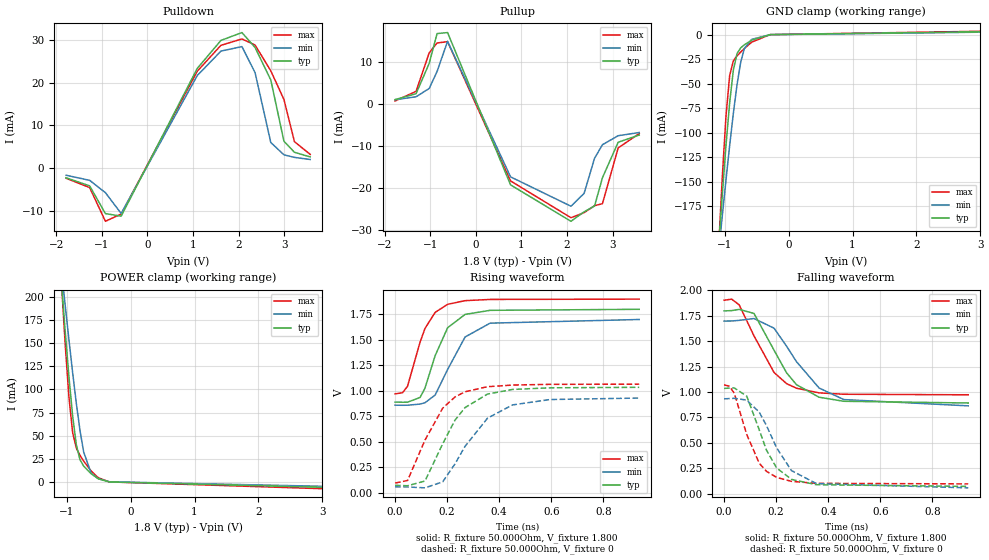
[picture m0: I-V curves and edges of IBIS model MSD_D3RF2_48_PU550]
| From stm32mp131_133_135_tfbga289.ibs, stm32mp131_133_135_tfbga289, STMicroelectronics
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[Model] MSD_D3RF2_48_PU550
Model_type   I/O
C_comp 2.403pF   2.321pF   2.525pF
Vinh = 1.150V
Vinl = 650.000mV
Vmeas = 900.000mV
Vref = 900.000mV
[Model Spec]
Vinh   1.150V   1.100V   1.200V
Vinl   650.000mV   600.000mV   700.000mV
Vmeas   900.000mV   850.000mV   950.000mV
Vref   900.000mV   850.000mV   950.000mV
[Temperature Range]   25.000   125.000   -40.000
[Voltage Range]   1.800V   1.700V   1.900V
[GND Clamp Reference]   0.00V   0.00V   0.00V
[Pulldown Reference]   0.00V   0.00V   0.00V
[POWER Clamp Reference]   1.800V   1.700V   1.900V
[Pullup Reference]   1.800V   1.700V   1.900V
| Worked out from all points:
|   slope of the pulldown table from 0 to 0.27 V, typ, clamps not added: 41 ohm
|   slope of the pullup table from 0 to 0.27 V, typ, clamps not added: 32.3 ohm
|   GND clamp passes 1 mA (typ) near -0.40 V on its own axis
|   POWER clamp passes 1 mA (typ) near -0.41 V on its own axis
|   rising waveform, R_fixture 50.000Ohm, V_fixture 1.800: 20-80 % time 80.5ps typ, 99.8ps min, 74ps max; typ from 0.889 V to 1.8 V
|   rising waveform, R_fixture 50.000Ohm, V_fixture 0: 20-80 % time 125ps typ, 148ps min, 117ps max; typ from 0.072 V to 1.03 V
|   falling waveform, R_fixture 50.000Ohm, V_fixture 1.800: 20-80 % time 125ps typ, 150ps min, 117ps max; typ from 1.8 V to 0.892 V
|   falling waveform, R_fixture 50.000Ohm, V_fixture 0: 20-80 % time 91.2ps typ, 112ps min, 82.8ps max; typ from 1.04 V to 0.071 V
[GND Clamp]
-1.785V   -902.5mA   -689.8mA   -1.211A
-1.094V   -215.3mA   -221.3mA   -216.1mA
-1.036V   -162.4mA   -184mA     -144mA
-978.8mV  -112.7mA   -147.7mA   -82.66mA
-921.2mV  -68.92mA   -112.7mA   -41.51mA
-863.6mV  -36.11mA   -79.92mA   -26.65mA
-806.1mV  -19.32mA   -50.89mA   -21.68mA
-748.5mV  -13.5mA    -28.03mA   -17.81mA
-690.9mV  -10.44mA   -13.99mA   -14.19mA
-575.8mV  -5.673mA   -4.859mA   -7.667mA
-287.9mV  -73.99uA   -123uA     -58.99uA
3.57V     3.293mA    2.836mA    3.934mA
[Power Clamp]
-1.77V    883.9mA    691mA      1.161A
-1.079V   213mA      227mA      212.9mA
-1.021V   161.5mA    189.8mA    147.4mA
-963.6mV  113.4mA    153.4mA    91.56mA
-906.1mV  71.61mA    118.2mA    53.48mA
-848.5mV  40.42mA    85.13mA    36.67mA
-790.9mV  24.13mA    55.72mA    28.91mA
-733.3mV  17.27mA    32.47mA    22.68mA
-618.2mV  9.14mA     9.901mA    12.17mA
-503mV    3.513mA    3.609mA    4.571mA
-330.3mV  167.9uA    348uA      196.2uA
3.585V    -6.609mA   -5.357mA   -8.396mA
[Pulldown]
-1.785V   -2.3mA     -1.7mA     -2.4mA
-1.267V   -4.2mA     -2.9mA     -4.6mA
-921.2mV  -10.72mA   -5.8mA     -12.53mA
-575.8mV  -11.32mA   -10.69mA   -10.82mA
1.094V    23.43mA    21.74mA    22.76mA
1.612V    29.99mA    27.48mA    28.84mA
2.073V    31.84mA    28.54mA    30.34mA
2.361V    28.33mA    22.42mA    28.91mA
2.706V    20.7mA     6mA        22.85mA
2.994V    6.3mA      3.1mA      16.1mA
3.224V    3.7mA      2.5mA      6.2mA
3.57V     2.6mA      2mA        3.2mA
[Pullup]
-1.77V    1mA        973.7uA    673.7uA
-1.309V   2.4mA      1.674mA    2.963mA
-1.021V   9.6mA      3.642mA    12.09mA
-848.5mV  16.65mA    7.666mA    14.42mA
-618.2mV  16.89mA    14.82mA    14.74mA
763.6mV   -19.21mA   -17.31mA   -18.27mA
2.088V    -27.84mA   -24.27mA   -26.99mA
2.376V    -25.59mA   -21.23mA   -25.8mA
2.606V    -24.21mA   -12.89mA   -24.14mA
2.779V    -17.5mA    -9.684mA   -23.66mA
3.124V    -9.1mA     -7.553mA   -10.44mA
3.585V    -7.4mA     -6.8mA     -7.047mA
[Ramp]
R_load=50.000Ohm
dV/dt_r   561.306mV/103.000ps  512.892mV/124.500ps  569.130mV/96.000ps
dV/dt_f   561.306mV/109.000ps  512.892mV/131.000ps  569.130mV/100.500ps
[Rising waveform]
R_fixture=50.000Ohm
V_fixture=1.800
V_fixture_min=1.700
V_fixture_max=1.900
0s        888.8mV    858.4mV    969.2mV
29ps      887.4mV    857.6mV    981.1mV
48ps      887.9mV    858.2mV    1.045V
96ps      934.1mV    869.4mV    1.477V
115ps     1.026V     882.6mV    1.612V
154ps     1.345V     958.2mV    1.77V
202ps     1.619V     1.209V     1.849V
269ps     1.75V      1.528V     1.885V
365ps     1.79V      1.664V     1.897V
938ps     1.8V       1.7V       1.9V
[Rising waveform]
R_fixture=50.000Ohm
V_fixture=0
0s        71.65mV    57.11mV    93.4mV
48ps      67.26mV    55.4mV     119.3mV
115ps     113.6mV    46.56mV    515.6mV
183ps     479.1mV    105.7mV    829.2mV
230ps     710.5mV    281.2mV    938.8mV
269ps     835.1mV    454.9mV    990.4mV
355ps     967.5mV    730.6mV    1.04V
451ps     1.013V     861mV      1.056V
595ps     1.029V     914mV      1.063V
938ps     1.034V     928.5mV    1.065V
[Falling waveform]
R_fixture=50.000Ohm
V_fixture=1.800
V_fixture_min=1.700
V_fixture_max=1.900
0s        1.799V     1.699V     1.904V
29ps      1.802V     1.7V       1.915V
58ps      1.814V     1.706V     1.859V
115ps     1.774V     1.724V     1.553V
192ps     1.412V     1.629V     1.193V
240ps     1.19V      1.452V     1.083V
278ps     1.073V     1.3V       1.038V
365ps     949.3mV    1.04V      992.1mV
460ps     909.3mV    926mV      978.5mV
938ps     892.3mV    864.4mV    972.9mV
[Falling waveform]
R_fixture=50.000Ohm
V_fixture=0
0s        1.036V     933mV      1.071V
20ps      1.039V     936mV      1.058V
39ps      1.041V     938.3mV    989.8mV
87ps      960.4mV    921mV      583mV
135ps     628.6mV    802.5mV    299.6mV
163ps     427.6mV    669.7mV    219.5mV
202ps     252.5mV    450.3mV    159.6mV
259ps     140.2mV    226.7mV    120.9mV
355ps     87.51mV    98.48mV    101.2mV
938ps     71.22mV    56.83mV    95.81mV
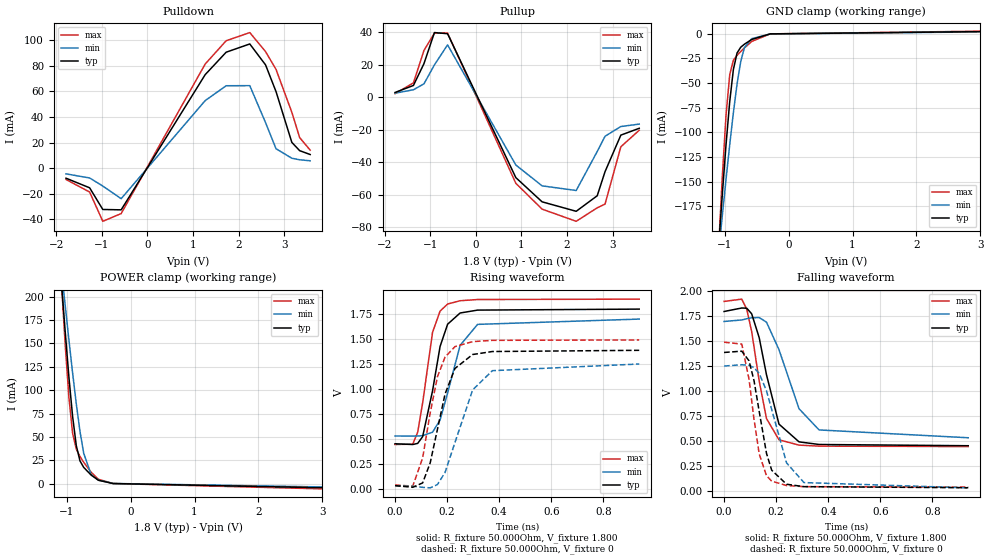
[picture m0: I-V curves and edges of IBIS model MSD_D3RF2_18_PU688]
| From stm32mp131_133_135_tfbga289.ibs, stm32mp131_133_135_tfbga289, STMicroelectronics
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[Model] MSD_D3RF2_18_PU688
Model_type   I/O
C_comp 2.432pF   2.350pF   2.555pF
Vinh = 1.150V
Vinl = 650.000mV
Vmeas = 900.000mV
Vref = 900.000mV
[Model Spec]
Vinh   1.150V   1.100V   1.200V
Vinl   650.000mV   600.000mV   700.000mV
Vmeas   900.000mV   850.000mV   950.000mV
Vref   900.000mV   850.000mV   950.000mV
[Temperature Range]   25.000   125.000   -40.000
[Voltage Range]   1.800V   1.700V   1.900V
[GND Clamp Reference]   0.00V   0.00V   0.00V
[Pulldown Reference]   0.00V   0.00V   0.00V
[POWER Clamp Reference]   1.800V   1.700V   1.900V
[Pullup Reference]   1.800V   1.700V   1.900V
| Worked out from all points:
|   slope of the pulldown table from 0 to 0.27 V, typ, clamps not added: 15.3 ohm
|   slope of the pullup table from 0 to 0.27 V, typ, clamps not added: 14.6 ohm
|   GND clamp passes 1 mA (typ) near -0.40 V on its own axis
|   POWER clamp passes 1 mA (typ) near -0.41 V on its own axis
|   rising waveform, R_fixture 50.000Ohm, V_fixture 1.800: 20-80 % time 56.4ps typ, 72.5ps min, 49.2ps max; typ from 0.45 V to 1.8 V
|   rising waveform, R_fixture 50.000Ohm, V_fixture 0: 20-80 % time 73.6ps typ, 93.2ps min, 64.6ps max; typ from 0.031 V to 1.39 V
|   falling waveform, R_fixture 50.000Ohm, V_fixture 1.800: 20-80 % time 67.2ps typ, 95.3ps min, 56.8ps max; typ from 1.8 V to 0.452 V
|   falling waveform, R_fixture 50.000Ohm, V_fixture 0: 20-80 % time 56.4ps typ, 78.6ps min, 47.6ps max; typ from 1.39 V to 0.03 V
[GND Clamp]
-1.785V   -902.9mA   -690.1mA   -1.212A
-1.094V   -215.4mA   -221.6mA   -216.3mA
-1.036V   -162.5mA   -184.2mA   -144.3mA
-978.8mV  -112.8mA   -147.8mA   -82.88mA
-921.2mV  -69.07mA   -112.8mA   -41.71mA
-863.6mV  -36.25mA   -80.04mA   -26.83mA
-806.1mV  -19.44mA   -50.98mA   -21.84mA
-748.5mV  -13.6mA    -28.12mA   -17.94mA
-690.9mV  -10.53mA   -14.06mA   -14.3mA
-575.8mV  -5.721mA   -4.905mA   -7.728mA
-287.9mV  -76uA      -126uA     -60.99uA
3.57V     2.635mA    2.269mA    3.148mA
[Power Clamp]
-1.77V    884.4mA    691.4mA    1.161A
-1.079V   213.2mA    227.2mA    213.2mA
-1.021V   161.7mA    190mA      147.7mA
-963.6mV  113.6mA    153.5mA    91.81mA
-906.1mV  71.77mA    118.3mA    53.68mA
-848.5mV  40.56mA    85.23mA    36.85mA
-790.9mV  24.24mA    55.82mA    29.07mA
-733.3mV  17.36mA    32.56mA    22.8mA
-618.2mV  9.2mA      9.96mA     12.25mA
-503mV    3.547mA    3.642mA    4.614mA
-272.7mV  33.94uA    110.5uA    33.56uA
3.585V    -5.286mA   -4.283mA   -6.715mA
[Pulldown]
-1.785V   -7.8mA     -4.4mA     -8.8mA
-1.267V   -15.3mA    -7.6mA     -18.6mA
-978.8mV  -32.2mA    -13.9mA    -41.43mA
-575.8mV  -32.49mA   -23.76mA   -35.41mA
1.267V    73.04mA    52.78mA    81.35mA
1.727V    90.57mA    64.39mA    99.51mA
2.245V    97.01mA    64.46mA    105.9mA
2.591V    80.68mA    35.6mA     91.04mA
2.821V    59.8mA     15.2mA     77.14mA
3.167V    20.2mA     7.8mA      43.7mA
3.339V    13.7mA     6.6mA      23.9mA
3.57V     10.7mA     5.8mA      14.1mA
[Pullup]
-1.77V    2.9mA      2.474mA    2.153mA
-1.367V   7.2mA      4.542mA    8.789mA
-1.136V   20.6mA     8.205mA    28.69mA
-906.1mV  39.68mA    19.85mA    39.36mA
-618.2mV  38.98mA    32.14mA    39.33mA
878.8mV   -49.38mA   -41.65mA   -52.88mA
1.455V    -64.25mA   -54.44mA   -68.74mA
2.203V    -70.07mA   -57.29mA   -76.21mA
2.664V    -60.52mA   -33.36mA   -67.93mA
2.836V    -45.7mA    -23.98mA   -65.63mA
3.182V    -23.3mA    -18.01mA   -30.45mA
3.585V    -19.1mA    -16.53mA   -20.3mA
[Ramp]
R_load=50.000Ohm
dV/dt_r   811.602mV/65.500ps  716.976mV/83.500ps  873.096mV/57.000ps
dV/dt_f   811.602mV/62.500ps  716.976mV/88.000ps  873.096mV/52.500ps
[Rising waveform]
R_fixture=50.000Ohm
V_fixture=1.800
V_fixture_min=1.700
V_fixture_max=1.900
0s        450.5mV    528.6mV    443.3mV
68ps      443.2mV    527.3mV    446.8mV
87ps      454.3mV    528.5mV    566.4mV
106ps     522mV      532mV      860mV
144ps     980.7mV    566.3mV    1.567V
173ps     1.426V     688.3mV    1.78V
202ps     1.649V     960.2mV    1.851V
250ps     1.761V     1.437V     1.884V
317ps     1.79V      1.647V     1.896V
938ps     1.8V       1.7V       1.9V
[Rising waveform]
R_fixture=50.000Ohm
V_fixture=0
0s        31.16mV    29.86mV    37.89mV
68ps      14.49mV    24.01mV    26.33mV
106ps     58.44mV    14.04mV    308.2mV
135ps     258.9mV    8.79mV     760.3mV
163ps     597.4mV    42.45mV    1.123V
192ps     948.5mV    162.4mV    1.319V
230ps     1.205V     462.1mV    1.424V
298ps     1.345V     990.4mV    1.474V
374ps     1.375V     1.183V     1.487V
938ps     1.387V     1.25V      1.491V
[Falling waveform]
R_fixture=50.000Ohm
V_fixture=1.800
V_fixture_min=1.700
V_fixture_max=1.900
0s        1.798V     1.698V     1.899V
68ps      1.833V     1.713V     1.922V
87ps      1.831V     1.725V     1.821V
106ps     1.775V     1.735V     1.597V
135ps     1.535V     1.737V     1.099V
163ps     1.163V     1.691V     724.2mV
211ps     668.1mV    1.415V     510.8mV
288ps     490.4mV    822.5mV    457.9mV
365ps     464.2mV    610mV      447.4mV
938ps     451.6mV    531.6mV    443.6mV
[Falling waveform]
R_fixture=50.000Ohm
V_fixture=0
0s        1.387V     1.251V     1.49V
68ps      1.4V       1.264V     1.471V
96ps      1.303V     1.258V     1.116V
115ps     1.105V     1.235V     717.1mV
135ps     794.9mV    1.176V     369.1mV
163ps     375mV      1.003V     150.5mV
183ps     206.1mV    814.3mV    96.13mV
240ps     65.57mV    279.7mV    52.62mV
307ps     41.19mV    81.98mV    41.37mV
938ps     30.27mV    29.11mV    36.98mV
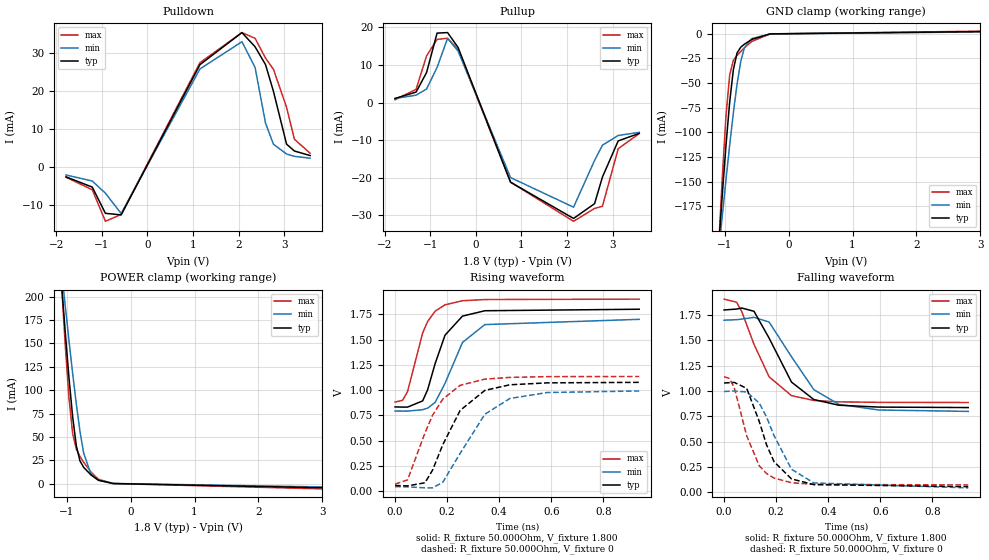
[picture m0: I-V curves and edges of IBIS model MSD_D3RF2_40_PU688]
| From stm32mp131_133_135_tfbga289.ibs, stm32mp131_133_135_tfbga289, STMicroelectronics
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[Model] MSD_D3RF2_40_PU688
Model_type   I/O
C_comp 2.432pF   2.350pF   2.555pF
Vinh = 1.150V
Vinl = 650.000mV
Vmeas = 900.000mV
Vref = 900.000mV
[Model Spec]
Vinh   1.150V   1.100V   1.200V
Vinl   650.000mV   600.000mV   700.000mV
Vmeas   900.000mV   850.000mV   950.000mV
Vref   900.000mV   850.000mV   950.000mV
[Temperature Range]   25.000   125.000   -40.000
[Voltage Range]   1.800V   1.700V   1.900V
[GND Clamp Reference]   0.00V   0.00V   0.00V
[Pulldown Reference]   0.00V   0.00V   0.00V
[POWER Clamp Reference]   1.800V   1.700V   1.900V
[Pullup Reference]   1.800V   1.700V   1.900V
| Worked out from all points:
|   slope of the pulldown table from 0 to 0.27 V, typ, clamps not added: 37.2 ohm
|   slope of the pullup table from 0 to 0.27 V, typ, clamps not added: 29.4 ohm
|   GND clamp passes 1 mA (typ) near -0.40 V on its own axis
|   POWER clamp passes 1 mA (typ) near -0.41 V on its own axis
|   rising waveform, R_fixture 50.000Ohm, V_fixture 1.800: 20-80 % time 78.1ps typ, 96.1ps min, 70.3ps max; typ from 0.833 V to 1.8 V
|   rising waveform, R_fixture 50.000Ohm, V_fixture 0: 20-80 % time 121ps typ, 140ps min, 111ps max; typ from 0.055 V to 1.08 V
|   falling waveform, R_fixture 50.000Ohm, V_fixture 1.800: 20-80 % time 121ps typ, 140ps min, 107ps max; typ from 1.8 V to 0.836 V
|   falling waveform, R_fixture 50.000Ohm, V_fixture 0: 20-80 % time 88.7ps typ, 105ps min, 77.8ps max; typ from 1.08 V to 0.054 V
[GND Clamp]
-1.785V   -902.9mA   -690.1mA   -1.212A
-1.094V   -215.4mA   -221.6mA   -216.3mA
-1.036V   -162.5mA   -184.2mA   -144.3mA
-978.8mV  -112.8mA   -147.8mA   -82.88mA
-921.2mV  -69.07mA   -112.8mA   -41.71mA
-863.6mV  -36.25mA   -80.04mA   -26.83mA
-806.1mV  -19.44mA   -50.98mA   -21.84mA
-748.5mV  -13.6mA    -28.12mA   -17.94mA
-690.9mV  -10.53mA   -14.06mA   -14.3mA
-575.8mV  -5.721mA   -4.905mA   -7.728mA
-287.9mV  -76uA      -126uA     -60.99uA
3.57V     2.635mA    2.269mA    3.148mA
[Power Clamp]
-1.77V    884.4mA    691.4mA    1.161A
-1.079V   213.2mA    227.2mA    213.2mA
-1.021V   161.7mA    190mA      147.7mA
-963.6mV  113.6mA    153.5mA    91.81mA
-906.1mV  71.77mA    118.3mA    53.68mA
-848.5mV  40.56mA    85.23mA    36.85mA
-790.9mV  24.24mA    55.82mA    29.07mA
-733.3mV  17.36mA    32.56mA    22.8mA
-618.2mV  9.2mA      9.96mA     12.25mA
-503mV    3.547mA    3.642mA    4.614mA
-272.7mV  33.94uA    110.5uA    33.56uA
3.585V    -5.286mA   -4.283mA   -6.715mA
[Pulldown]
-1.785V   -2.6mA     -2.1mA     -2.7mA
-1.209V   -5.3mA     -3.7mA     -6mA
-921.2mV  -12.19mA   -6.9mA     -14.29mA
-575.8mV  -12.6mA    -12.25mA   -12.48mA
1.152V    26.92mA    25.79mA    27.43mA
2.073V    35.36mA    32.95mA    35.36mA
2.361V    31.62mA    26.21mA    33.85mA
2.591V    26.91mA    11.5mA     28.62mA
2.764V    19.9mA     6mA        25.7mA
3.052V    6mA        3.4mA      15.7mA
3.224V    4.2mA      2.8mA      7.3mA
3.57V     3mA        2.3mA      3.6mA
[Pullup]
-1.77V    1.1mA      1.074mA    773.7uA
-1.309V   2.8mA      1.974mA    3.516mA
-1.079V   8mA        3.616mA    12.43mA
-848.5mV  18.49mA    9.339mA    16.82mA
-618.2mV  18.64mA    17.11mA    17.13mA
-387.9mV  14.68mA    13.71mA    14.14mA
763.6mV   -21.2mA    -19.96mA   -21.18mA
2.145V    -30.84mA   -27.84mA   -31.6mA
2.606V    -26.91mA   -15.4mA    -28.18mA
2.779V    -19.8mA    -11.34mA   -27.6mA
3.124V    -10.2mA    -8.753mA   -12.28mA
3.585V    -8.2mA     -7.926mA   -8.247mA
[Ramp]
R_load=50.000Ohm
dV/dt_r   596.079mV/101.000ps  555.681mV/118.000ps  623.133mV/91.000ps
dV/dt_f   596.079mV/105.500ps  555.681mV/123.500ps  623.133mV/92.500ps
[Rising waveform]
R_fixture=50.000Ohm
V_fixture=1.800
V_fixture_min=1.700
V_fixture_max=1.900
0s        832.8mV    792.1mV    881.5mV
29ps      831.2mV    791.2mV    897.8mV
48ps      831mV      791.5mV    984.5mV
106ps     892.4mV    805.3mV    1.565V
125ps     1.001V     820.6mV    1.678V
154ps     1.262V     877.7mV    1.78V
192ps     1.543V     1.067V     1.844V
259ps     1.732V     1.471V     1.884V
345ps     1.785V     1.648V     1.896V
938ps     1.8V       1.7V       1.9V
[Rising waveform]
R_fixture=50.000Ohm
V_fixture=0
0s        54.92mV    43.12mV    68.13mV
48ps      51.04mV    41.5mV     110.6mV
115ps     81.98mV    31.7mV     576.1mV
144ps     206.6mV    31.55mV    750.3mV
183ps     456.5mV    85.3mV     909.3mV
250ps     798.2mV    373.1mV    1.047V
345ps     996.5mV    760.1mV    1.108V
441ps     1.052V     916.5mV    1.125V
585ps     1.071V     975.4mV    1.133V
938ps     1.076V     990.8mV    1.134V
[Falling waveform]
R_fixture=50.000Ohm
V_fixture=1.800
V_fixture_min=1.700
V_fixture_max=1.900
0s        1.799V     1.698V     1.906V
48ps      1.808V     1.703V     1.876V
68ps      1.818V     1.709V     1.783V
115ps     1.786V     1.726V     1.46V
173ps     1.521V     1.68V      1.139V
259ps     1.087V     1.337V     953.2mV
345ps     914.4mV    1.012V     905.5mV
441ps     858.5mV    867mV      891.9mV
595ps     840.1mV    811.3mV    887mV
938ps     835.5mV    797.6mV    885.5mV
[Falling waveform]
R_fixture=50.000Ohm
V_fixture=0
0s        1.078V     994mV      1.14V
20ps      1.081V     996.8mV    1.123V
39ps      1.084V     999.5mV    1.034V
87ps      1.025V     989.2mV    555.6mV
135ps     699mV      880.5mV    261.2mV
163ps     469mV      742.8mV    184.3mV
192ps     301.1mV    558.1mV    139.1mV
259ps     130.6mV    226.7mV    93.44mV
345ps     74.94mV    91.2mV     76.92mV
938ps     54.4mV     42.69mV    71.48mV
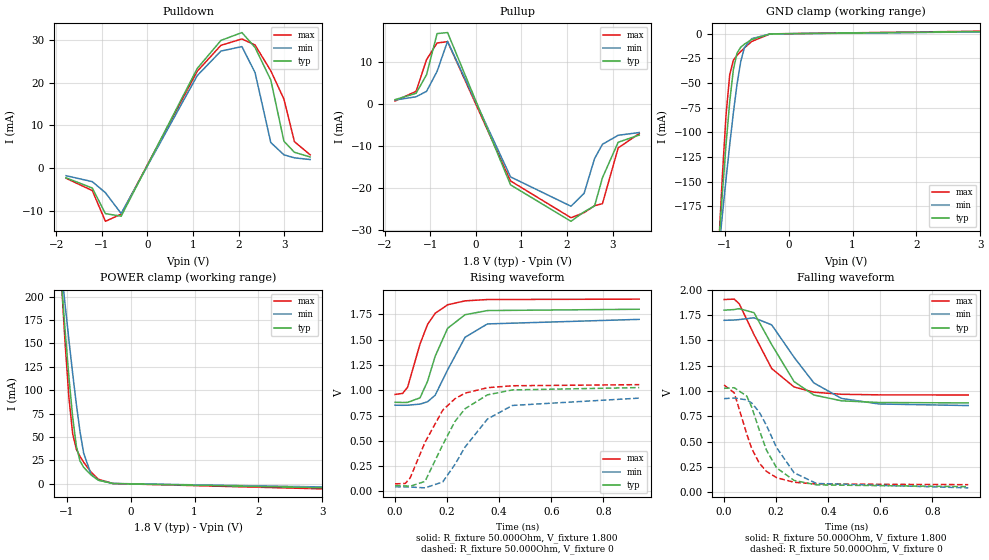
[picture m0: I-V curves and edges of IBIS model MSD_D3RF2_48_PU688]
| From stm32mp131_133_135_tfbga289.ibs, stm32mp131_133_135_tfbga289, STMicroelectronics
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[Model] MSD_D3RF2_48_PU688
Model_type   I/O
C_comp 2.432pF   2.350pF   2.555pF
Vinh = 1.150V
Vinl = 650.000mV
Vmeas = 900.000mV
Vref = 900.000mV
[Model Spec]
Vinh   1.150V   1.100V   1.200V
Vinl   650.000mV   600.000mV   700.000mV
Vmeas   900.000mV   850.000mV   950.000mV
Vref   900.000mV   850.000mV   950.000mV
[Temperature Range]   25.000   125.000   -40.000
[Voltage Range]   1.800V   1.700V   1.900V
[GND Clamp Reference]   0.00V   0.00V   0.00V
[Pulldown Reference]   0.00V   0.00V   0.00V
[POWER Clamp Reference]   1.800V   1.700V   1.900V
[Pullup Reference]   1.800V   1.700V   1.900V
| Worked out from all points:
|   slope of the pulldown table from 0 to 0.27 V, typ, clamps not added: 41 ohm
|   slope of the pullup table from 0 to 0.27 V, typ, clamps not added: 32.3 ohm
|   GND clamp passes 1 mA (typ) near -0.40 V on its own axis
|   POWER clamp passes 1 mA (typ) near -0.41 V on its own axis
|   rising waveform, R_fixture 50.000Ohm, V_fixture 1.800: 20-80 % time 81.6ps typ, 101ps min, 75.5ps max; typ from 0.881 V to 1.8 V
|   rising waveform, R_fixture 50.000Ohm, V_fixture 0: 20-80 % time 127ps typ, 150ps min, 120ps max; typ from 0.058 V to 1.03 V
|   falling waveform, R_fixture 50.000Ohm, V_fixture 1.800: 20-80 % time 126ps typ, 151ps min, 118ps max; typ from 1.8 V to 0.884 V
|   falling waveform, R_fixture 50.000Ohm, V_fixture 0: 20-80 % time 92ps typ, 112ps min, 83.9ps max; typ from 1.03 V to 0.057 V
[GND Clamp]
-1.785V   -902.9mA   -690.1mA   -1.212A
-1.094V   -215.4mA   -221.6mA   -216.3mA
-1.036V   -162.5mA   -184.2mA   -144.3mA
-978.8mV  -112.8mA   -147.8mA   -82.88mA
-921.2mV  -69.07mA   -112.8mA   -41.71mA
-863.6mV  -36.25mA   -80.04mA   -26.83mA
-806.1mV  -19.44mA   -50.98mA   -21.84mA
-748.5mV  -13.6mA    -28.12mA   -17.94mA
-690.9mV  -10.53mA   -14.06mA   -14.3mA
-575.8mV  -5.721mA   -4.905mA   -7.728mA
-287.9mV  -76uA      -126uA     -60.99uA
3.57V     2.635mA    2.269mA    3.148mA
[Power Clamp]
-1.77V    884.4mA    691.4mA    1.161A
-1.079V   213.2mA    227.2mA    213.2mA
-1.021V   161.7mA    190mA      147.7mA
-963.6mV  113.6mA    153.5mA    91.81mA
-906.1mV  71.77mA    118.3mA    53.68mA
-848.5mV  40.56mA    85.23mA    36.85mA
-790.9mV  24.24mA    55.82mA    29.07mA
-733.3mV  17.36mA    32.56mA    22.8mA
-618.2mV  9.2mA      9.96mA     12.25mA
-503mV    3.547mA    3.642mA    4.614mA
-272.7mV  33.94uA    110.5uA    33.56uA
3.585V    -5.286mA   -4.283mA   -6.715mA
[Pulldown]
-1.785V   -2.3mA     -1.8mA     -2.4mA
-1.209V   -4.7mA     -3.2mA     -5.3mA
-921.2mV  -10.72mA   -5.8mA     -12.52mA
-575.8mV  -11.32mA   -10.69mA   -10.83mA
1.094V    23.43mA    21.74mA    22.76mA
1.612V    29.99mA    27.49mA    28.84mA
2.073V    31.84mA    28.54mA    30.34mA
2.361V    28.33mA    22.42mA    28.91mA
2.706V    20.69mA    6mA        22.85mA
2.994V    6.3mA      3.1mA      16.2mA
3.224V    3.7mA      2.4mA      6.2mA
3.57V     2.6mA      2mA        3.1mA
[Pullup]
-1.77V    1mA        900uA      673.7uA
-1.309V   2.5mA      1.674mA    2.963mA
-1.079V   6.9mA      2.968mA    10.47mA
-848.5mV  16.65mA    7.693mA    14.42mA
-618.2mV  16.89mA    14.82mA    14.74mA
763.6mV   -19.21mA   -17.32mA   -18.28mA
2.088V    -27.84mA   -24.27mA   -26.99mA
2.376V    -25.59mA   -21.22mA   -25.8mA
2.606V    -24.2mA    -12.97mA   -24.14mA
2.779V    -17.5mA    -9.584mA   -23.66mA
3.124V    -9.1mA     -7.453mA   -10.44mA
3.585V    -7.4mA     -6.8mA     -7.047mA
[Ramp]
R_load=50.000Ohm
dV/dt_r   565.695mV/105.500ps  516.216mV/126.500ps  574.725mV/98.500ps
dV/dt_f   565.695mV/110.000ps  516.216mV/133.000ps  574.725mV/101.500ps
[Rising waveform]
R_fixture=50.000Ohm
V_fixture=1.800
V_fixture_min=1.700
V_fixture_max=1.900
0s        880.5mV    851.9mV    958.1mV
29ps      879mV      851.1mV    968.5mV
48ps      879.5mV    851.7mV    1.028V
96ps      925mV      862.7mV    1.457V
125ps     1.089V     886.3mV    1.651V
154ps     1.335V     950.4mV    1.76V
202ps     1.612V     1.201V     1.844V
269ps     1.746V     1.523V     1.883V
355ps     1.787V     1.655V     1.896V
938ps     1.8V       1.7V       1.9V
[Rising waveform]
R_fixture=50.000Ohm
V_fixture=0
0s        57.86mV    46.07mV    75.14mV
39ps      55.02mV    44.94mV    78.1mV
58ps      51.22mV    43.5mV     133.1mV
115ps     98.89mV    35.22mV    484.9mV
183ps     460.1mV    93.03mV    802.4mV
230ps     691.2mV    266.1mV    916.1mV
269ps     817.3mV    438.6mV    971mV
355ps     954.3mV    715.6mV    1.025V
451ps     1.003V     849.6mV    1.044V
938ps     1.026V     921.9mV    1.055V
[Falling waveform]
R_fixture=50.000Ohm
V_fixture=1.800
V_fixture_min=1.700
V_fixture_max=1.900
0s        1.799V     1.699V     1.904V
39ps      1.805V     1.702V     1.908V
58ps      1.814V     1.706V     1.863V
115ps     1.774V     1.724V     1.558V
183ps     1.459V     1.654V     1.223V
269ps     1.094V     1.334V     1.041V
345ps     961.9mV    1.081V     989.7mV
451ps     904.7mV    928.3mV    969.1mV
595ps     888mV      873.4mV    963.4mV
938ps     883.9mV    857.9mV    961.9mV
[Falling waveform]
R_fixture=50.000Ohm
V_fixture=0
0s        1.028V     926.6mV    1.06V
39ps      1.034V     931.9mV    983.4mV
87ps      951.9mV    914.3mV    578.3mV
106ps     844mV      883.1mV    435.7mV
135ps     618.7mV    794.6mV    290.4mV
163ps     417.7mV    661.2mV    207.9mV
202ps     242.5mV    441.4mV    145.8mV
269ps     119mV      194.9mV    100.9mV
355ps     75.03mV    89.03mV    83.55mV
938ps     57.35mV    45.76mV    77.35mV
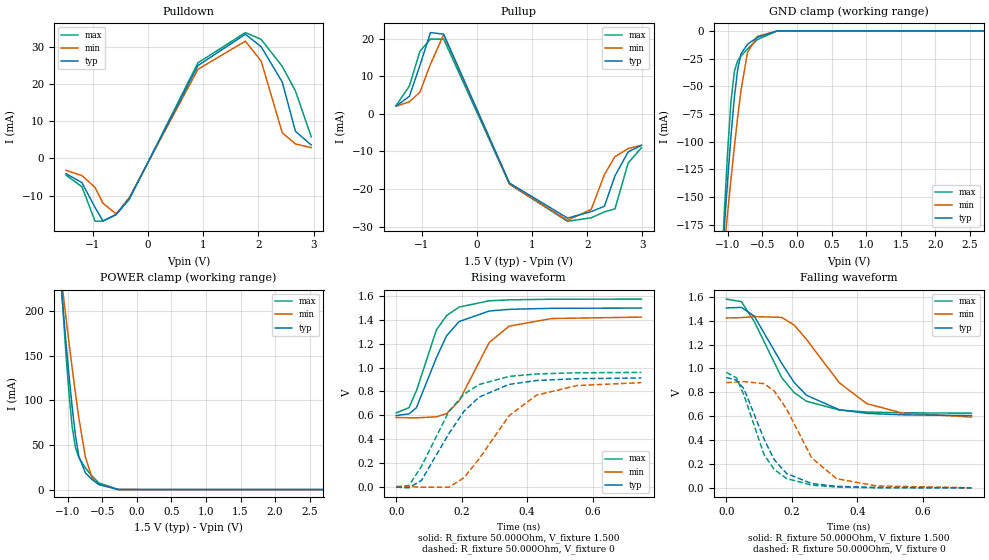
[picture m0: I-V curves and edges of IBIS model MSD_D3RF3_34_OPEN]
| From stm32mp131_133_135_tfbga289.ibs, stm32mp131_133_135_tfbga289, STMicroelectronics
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[Model] MSD_D3RF3_34_OPEN
Model_type   I/O
C_comp 2.564pF   2.479pF   2.689pF
Vinh = 925.000mV
Vinl = 575.000mV
Vmeas = 750.000mV
Vref = 750.000mV
[Model Spec]
Vinh   925.000mV   888.000mV   963.000mV
Vinl   575.000mV   538.000mV   613.000mV
Vmeas   750.000mV   713.000mV   788.000mV
Vref   750.000mV   713.000mV   788.000mV
[Temperature Range]   25.000   125.000   -40.000
[Voltage Range]   1.500V   1.425V   1.575V
[GND Clamp Reference]   0.00V   0.00V   0.00V
[Pulldown Reference]   0.00V   0.00V   0.00V
[POWER Clamp Reference]   1.500V   1.425V   1.575V
[Pullup Reference]   1.500V   1.425V   1.575V
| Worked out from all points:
|   slope of the pulldown table from 0 to 0.225 V, typ, clamps not added: 31.5 ohm
|   slope of the pullup table from 0 to 0.225 V, typ, clamps not added: 26.9 ohm
|   GND clamp passes 1 mA (typ) near -0.40 V on its own axis
|   POWER clamp passes 1 mA (typ) near -0.41 V on its own axis
|   rising waveform, R_fixture 50.000Ohm, V_fixture 1.500: 20-80 % time 84.1ps typ, 99.1ps min, 75.4ps max; typ from 0.597 V to 1.5 V
|   rising waveform, R_fixture 50.000Ohm, V_fixture 0: 20-80 % time 133ps typ, 147ps min, 123ps max; typ from -0.005 V to 0.912 V
|   falling waveform, R_fixture 50.000Ohm, V_fixture 1.500: 20-80 % time 128ps typ, 154ps min, 114ps max; typ from 1.51 V to 0.606 V
|   falling waveform, R_fixture 50.000Ohm, V_fixture 0: 20-80 % time 90ps typ, 108ps min, 80ps max; typ from 0.924 V to 0 V
[GND Clamp]
-1.48V    -596.5mA   -481.9mA   -766.5mA
-1.098V   -219.9mA   -224.7mA   -222.4mA
-1.05V    -175.6mA   -193.6mA   -161.6mA
-1.002V   -133.3mA   -163.1mA   -107mA
-954.6mV  -94.12mA   -133.4mA   -63.19mA
-906.8mV  -60.18mA   -104.9mA   -36.66mA
-859.1mV  -34.85mA   -78.03mA   -27mA
-811.4mV  -20.84mA   -53.84mA   -22.84mA
-715.9mV  -12.12mA   -19.32mA   -16.33mA
-572.7mV  -5.815mA   -4.971mA   -7.847mA
-286.4mV  -79.35uA   -131.3uA   -65.66uA
2.959V    34.12nA    533.7nA    4.576nA
[Power Clamp]
-1.459V   580.3mA    481.5mA    726.4mA
-1.077V   212.7mA    226.9mA    212.4mA
-1.03V    169.7mA    196mA      157.5mA
-981.8mV  129mA      165.5mA    108.5mA
-934.1mV  91.79mA    135.8mA    69.91mA
-886.4mV  60.19mA    107.2mA    46.67mA
-838.6mV  37.22mA    80.32mA    35.95mA
-743.2mV  18.67mA    36.26mA    24.33mA
-647.7mV  11.33mA    13.35mA    15.07mA
-552.3mV  5.847mA    5.773mA    7.686mA
-265.9mV  29.71uA    98.64uA    29.06uA
2.98V     -53.11nA   -976.3nA   -5.314nA
[Pulldown]
-1.48V    -4.1mA     -3.2mA     -4.5mA
-1.193V   -6.5mA     -4.6mA     -7.6mA
-954.6mV  -13.18mA   -7.8mA     -16.88mA
-811.4mV  -16.78mA   -12.04mA   -16.84mA
-572.7mV  -15.07mA   -14.91mA   -15.03mA
-334.1mV  -10.73mA   -10.48mA   -10.95mA
906.8mV   24.93mA    23.93mA    25.67mA
1.766V    33.35mA    31.49mA    33.8mA
2.052V    30.01mA    26.15mA    31.97mA
2.434V    20.51mA    6.9mA      24.73mA
2.673V    7.3mA      3.9mA      18.1mA
2.959V    3.6mA      2.9mA      5.8mA
[Pullup]
-1.459V   2.1mA      2.057mA    2.271mA
-1.22V    4.7mA      3.229mA    7.443mA
-1.03V    12.9mA     5.771mA    16.66mA
-838.6mV  21.66mA    13.23mA    19.92mA
-600mV    21.23mA    21.13mA    19.93mA
593.2mV   -18.41mA   -18.64mA   -18.71mA
1.643V    -27.73mA   -28.34mA   -28.59mA
2.073V    -26mA      -25.4mA    -27.65mA
2.311V    -24.58mA   -16.14mA   -26.08mA
2.502V    -16.5mA    -11.4mA    -25.27mA
2.741V    -10.1mA    -9.229mA   -13.07mA
2.98V     -8.4mA     -8.343mA   -9.029mA
[Ramp]
R_load=50.000Ohm
dV/dt_r   542.580mV/109.500ps  515.459mV/125.500ps  572.760mV/100.500ps
dV/dt_f   542.580mV/109.500ps  515.459mV/133.000ps  572.760mV/97.500ps
[Rising waveform]
R_fixture=50.000Ohm
V_fixture=1.500
V_fixture_min=1.425
V_fixture_max=1.575
0s        596.7mV    580.5mV    618.7mV
39ps      610.7mV    578.2mV    662.3mV
62ps      663.3mV    577.5mV    807.2mV
123ps     1.084V     586.3mV    1.317V
154ps     1.267V     613mV      1.437V
192ps     1.386V     718.3mV    1.508V
284ps     1.475V     1.21V      1.561V
345ps     1.489V     1.348V     1.569V
475ps     1.498V     1.412V     1.574V
749ps     1.5V       1.424V     1.575V
[Rising waveform]
R_fixture=50.000Ohm
V_fixture=0
0s        -5.474mV   883.5uV    -5.448mV
39ps      -10.9mV    -739.3uV   9.684mV
77ps      51.18mV    -4.917mV   168.6mV
161ps     445.2mV    -5.416mV   631.8mV
207ps     632.1mV    73.75mV    776.4mV
253ps     751.4mV    231.9mV    857.2mV
345ps     858.5mV    596mV      925.7mV
429ps     891.2mV    768.5mV    946mV
552ps     906.5mV    848.7mV    956.2mV
749ps     912.4mV    873.4mV    959.2mV
[Falling waveform]
R_fixture=50.000Ohm
V_fixture=1.500
V_fixture_min=1.425
V_fixture_max=1.575
0s        1.507V     1.423V     1.581V
46ps      1.512V     1.426V     1.56V
85ps      1.44V      1.435V     1.395V
169ps     1.044V     1.428V     924mV
207ps     884mV      1.364V     798.7mV
245ps     775.7mV    1.244V     725.5mV
345ps     654.2mV    880.4mV    652.2mV
429ps     624.2mV    705.6mV    635.6mV
536ps     611.8mV    627.6mV    628.5mV
749ps     605.6mV    592.9mV    625.7mV
[Falling waveform]
R_fixture=50.000Ohm
V_fixture=0
0s        924.5mV    881.5mV    968.1mV
31ps      902.2mV    886.2mV    921.3mV
54ps      828.9mV    890mV      776.3mV
115ps     410mV      872.8mV    279.6mV
146ps     237.3mV    812.5mV    154.4mV
184ps     120.3mV    661mV      78.4mV
261ps     35.67mV    250.1mV    22.68mV
337ps     12.87mV    76.26mV    7.109mV
460ps     2.694mV    15.91mV    1.145mV
749ps     129.1uV    783.6uV    10.74uV
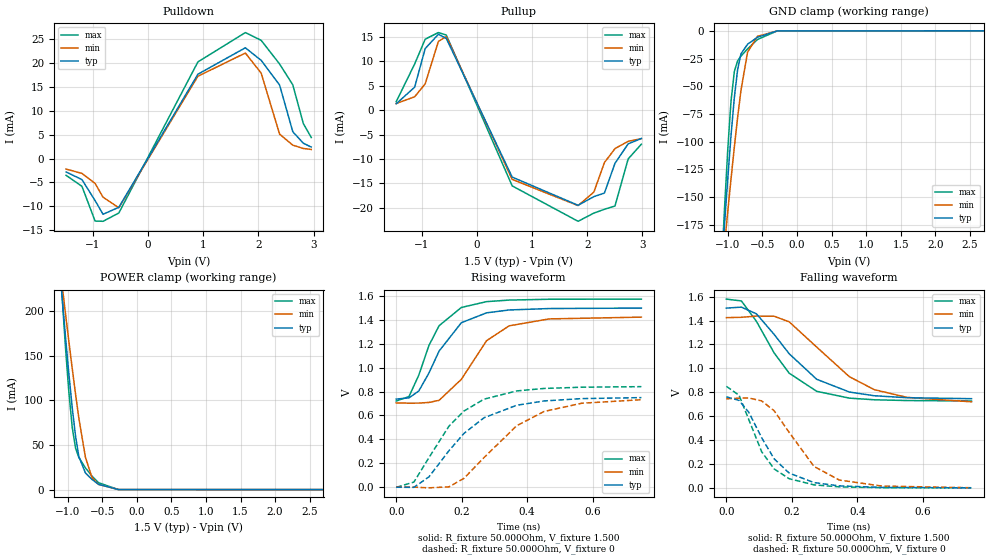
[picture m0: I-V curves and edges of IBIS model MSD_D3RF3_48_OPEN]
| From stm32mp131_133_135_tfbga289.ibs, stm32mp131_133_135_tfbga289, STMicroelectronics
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[Model] MSD_D3RF3_48_OPEN
Model_type   I/O
C_comp 2.564pF   2.479pF   2.689pF
Vinh = 925.000mV
Vinl = 575.000mV
Vmeas = 750.000mV
Vref = 750.000mV
[Model Spec]
Vinh   925.000mV   888.000mV   963.000mV
Vinl   575.000mV   538.000mV   613.000mV
Vmeas   750.000mV   713.000mV   788.000mV
Vref   750.000mV   713.000mV   788.000mV
[Temperature Range]   25.000   125.000   -40.000
[Voltage Range]   1.500V   1.425V   1.575V
[GND Clamp Reference]   0.00V   0.00V   0.00V
[Pulldown Reference]   0.00V   0.00V   0.00V
[POWER Clamp Reference]   1.500V   1.425V   1.575V
[Pullup Reference]   1.500V   1.425V   1.575V
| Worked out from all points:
|   slope of the pulldown table from 0 to 0.225 V, typ, clamps not added: 44.1 ohm
|   slope of the pullup table from 0 to 0.225 V, typ, clamps not added: 37.5 ohm
|   GND clamp passes 1 mA (typ) near -0.40 V on its own axis
|   POWER clamp passes 1 mA (typ) near -0.41 V on its own axis
|   rising waveform, R_fixture 50.000Ohm, V_fixture 1.500: 20-80 % time 97.1ps typ, 112ps min, 82.9ps max; typ from 0.736 V to 1.5 V
|   rising waveform, R_fixture 50.000Ohm, V_fixture 0: 20-80 % time 162ps typ, 175ps min, 140ps max; typ from -0.003 V to 0.749 V
|   falling waveform, R_fixture 50.000Ohm, V_fixture 1.500: 20-80 % time 155ps typ, 180ps min, 128ps max; typ from 1.5 V to 0.746 V
|   falling waveform, R_fixture 50.000Ohm, V_fixture 0: 20-80 % time 104ps typ, 121ps min, 87.5ps max; typ from 0.762 V to 0 V
[GND Clamp]
-1.48V    -596.5mA   -481.9mA   -766.5mA
-1.098V   -219.9mA   -224.7mA   -222.4mA
-1.05V    -175.6mA   -193.6mA   -161.6mA
-1.002V   -133.3mA   -163.1mA   -107mA
-954.6mV  -94.12mA   -133.4mA   -63.19mA
-906.8mV  -60.18mA   -104.9mA   -36.66mA
-859.1mV  -34.85mA   -78.03mA   -27mA
-811.4mV  -20.84mA   -53.84mA   -22.84mA
-715.9mV  -12.12mA   -19.32mA   -16.33mA
-572.7mV  -5.815mA   -4.971mA   -7.847mA
-286.4mV  -79.35uA   -131.3uA   -65.66uA
2.959V    34.12nA    533.7nA    4.576nA
[Power Clamp]
-1.459V   580.3mA    481.5mA    726.4mA
-1.077V   212.7mA    226.9mA    212.4mA
-1.03V    169.7mA    196mA      157.5mA
-981.8mV  129mA      165.5mA    108.5mA
-934.1mV  91.79mA    135.8mA    69.91mA
-886.4mV  60.19mA    107.2mA    46.67mA
-838.6mV  37.22mA    80.32mA    35.95mA
-743.2mV  18.67mA    36.26mA    24.33mA
-647.7mV  11.33mA    13.35mA    15.07mA
-552.3mV  5.847mA    5.773mA    7.686mA
-265.9mV  29.71uA    98.64uA    29.06uA
2.98V     -53.11nA   -976.3nA   -5.314nA
[Pulldown]
-1.48V    -2.8mA     -2.2mA     -3.5mA
-1.193V   -4.4mA     -3.1mA     -5.8mA
-954.6mV  -8.78mA    -5.2mA     -13.06mA
-811.4mV  -11.64mA   -8.07mA    -13.11mA
-525mV    -10.19mA   -10.28mA   -11.38mA
906.8mV   17.62mA    17.2mA     20.19mA
1.766V    23.14mA    22.04mA    26.32mA
2.052V    20.52mA    17.86mA    24.7mA
2.386V    15.36mA    5.1mA      19.75mA
2.625V    5.6mA      2.8mA      15.4mA
2.816V    3.2mA      2.1mA      7.3mA
2.959V    2.4mA      1.9mA      4.4mA
[Pullup]
-1.459V   1.3mA      1.357mA    1.729mA
-1.125V   4.7mA      2.729mA    9.443mA
-934.1mV  12.61mA    5.386mA    14.53mA
-695.5mV  15.52mA    14.06mA    15.88mA
-552.3mV  14.69mA    15.08mA    15.38mA
640.9mV   -13.71mA   -14.18mA   -15.51mA
1.834V    -19.48mA   -19.55mA   -22.76mA
2.12V     -17.71mA   -16.78mA   -21.08mA
2.311V    -16.98mA   -10.74mA   -20.3mA
2.502V    -10.9mA    -7.871mA   -19.63mA
2.741V    -6.9mA     -6.386mA   -9.986mA
2.98V     -5.8mA     -5.843mA   -6.971mA
[Ramp]
R_load=50.000Ohm
dV/dt_r   452.340mV/130.500ps  436.349mV/146.500ps  507.300mV/112.500ps
dV/dt_f   452.340mV/130.500ps  436.319mV/154.000ps  507.300mV/108.500ps
[Rising waveform]
R_fixture=50.000Ohm
V_fixture=1.500
V_fixture_min=1.425
V_fixture_max=1.575
0s        736.4mV    704.3mV    720.3mV
39ps      746.6mV    702.3mV    757.6mV
69ps      804.4mV    702.7mV    937.4mV
100ps     955mV      708.3mV    1.186V
131ps     1.139V     726mV      1.352V
199ps     1.377V     902.1mV    1.505V
276ps     1.46V      1.226V     1.554V
345ps     1.484V     1.351V     1.567V
467ps     1.496V     1.409V     1.574V
749ps     1.5V       1.424V     1.575V
[Rising waveform]
R_fixture=50.000Ohm
V_fixture=0
0s        -3.053mV   617.7uV    -3.828mV
54ps      -4.099mV   -2.214mV   40.16mV
100ps     83.87mV    -8.257mV   245mV
161ps     302.6mV    288.9uV    509mV
207ps     448.4mV    71.65mV    636.1mV
268ps     579.4mV    245.3mV    735.5mV
368ps     684.6mV    512.7mV    804.8mV
452ps     720.8mV    632.8mV    825.7mV
567ps     740.5mV    701.6mV    836.1mV
749ps     748.8mV    731.2mV    840.8mV
[Falling waveform]
R_fixture=50.000Ohm
V_fixture=1.500
V_fixture_min=1.425
V_fixture_max=1.575
0s        1.504V     1.424V     1.579V
46ps      1.512V     1.427V     1.564V
92ps      1.456V     1.437V     1.393V
146ps     1.284V     1.436V     1.129V
192ps     1.122V     1.389V     959.5mV
276ps     908.4mV    1.178V     807.7mV
376ps     801.8mV    929.8mV    750.7mV
452ps     770.7mV    821.6mV    736.9mV
552ps     754.1mV    757mV      730.5mV
749ps     746mV      719.9mV    727mV
[Falling waveform]
R_fixture=50.000Ohm
V_fixture=0
0s        761.6mV    744.8mV    849.6mV
39ps      731.6mV    750.8mV    774.5mV
69ps      630.8mV    751.6mV    568.3mV
108ps     419mV      727.3mV    302mV
146ps     243.3mV    645.3mV    158.4mV
192ps     123.4mV    463.7mV    76.41mV
268ps     43.95mV    178.8mV    24.91mV
345ps     16.71mV    65.52mV    8.28mV
475ps     3.51mV     15.03mV    1.567mV
749ps     192.2uV    948.3uV    -41.99uV
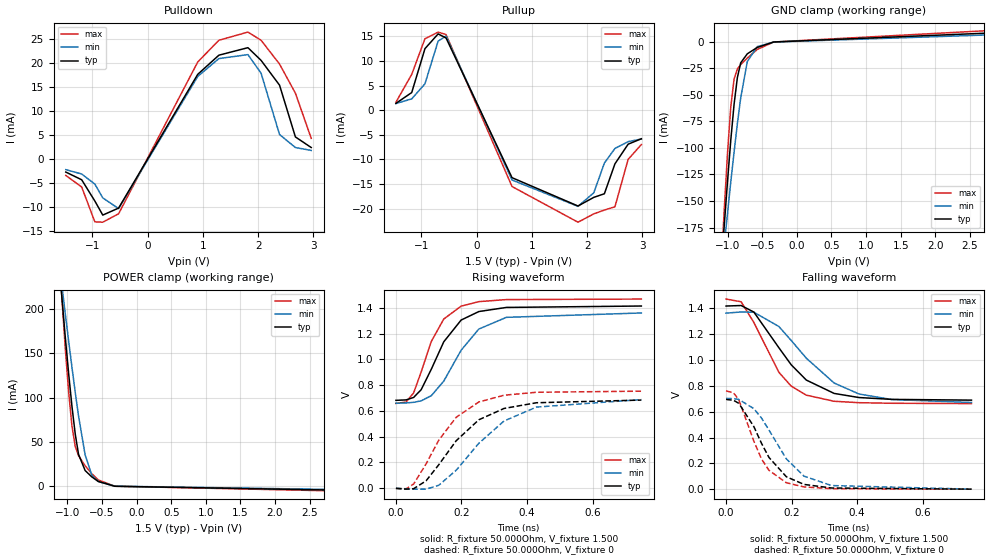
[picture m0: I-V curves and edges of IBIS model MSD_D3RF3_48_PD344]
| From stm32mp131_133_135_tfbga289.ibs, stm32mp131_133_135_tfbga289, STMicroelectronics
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[Model] MSD_D3RF3_48_PD344
Model_type   I/O
C_comp 2.325pF   2.244pF   2.446pF
Vinh = 925.000mV
Vinl = 575.000mV
Vmeas = 750.000mV
Vref = 750.000mV
[Model Spec]
Vinh   925.000mV   888.000mV   963.000mV
Vinl   575.000mV   538.000mV   613.000mV
Vmeas   750.000mV   713.000mV   788.000mV
Vref   750.000mV   713.000mV   788.000mV
[Temperature Range]   25.000   125.000   -40.000
[Voltage Range]   1.500V   1.425V   1.575V
[GND Clamp Reference]   0.00V   0.00V   0.00V
[Pulldown Reference]   0.00V   0.00V   0.00V
[POWER Clamp Reference]   1.500V   1.425V   1.575V
[Pullup Reference]   1.500V   1.425V   1.575V
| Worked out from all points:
|   slope of the pulldown table from 0 to 0.225 V, typ, clamps not added: 44.1 ohm
|   slope of the pullup table from 0 to 0.225 V, typ, clamps not added: 37.5 ohm
|   GND clamp passes 1 mA (typ) near -0.40 V on its own axis
|   POWER clamp passes 1 mA (typ) near -0.41 V on its own axis
|   rising waveform, R_fixture 50.000Ohm, V_fixture 1.500: 20-80 % time 91.5ps typ, 109ps min, 77.4ps max; typ from 0.681 V to 1.41 V
|   rising waveform, R_fixture 50.000Ohm, V_fixture 0: 20-80 % time 145ps typ, 166ps min, 124ps max; typ from -0.003 V to 0.683 V
|   falling waveform, R_fixture 50.000Ohm, V_fixture 1.500: 20-80 % time 134ps typ, 164ps min, 106ps max; typ from 1.42 V to 0.689 V
|   falling waveform, R_fixture 50.000Ohm, V_fixture 0: 20-80 % time 92.6ps typ, 112ps min, 75.8ps max; typ from 0.695 V to 0 V
[GND Clamp]
-1.48V    -593.9mA   -479.7mA   -763.2mA
-1.098V   -218.2mA   -223.4mA   -220.2mA
-1.05V    -174.1mA   -192.4mA   -159.6mA
-1.002V   -131.9mA   -161.9mA   -105.2mA
-954.6mV  -92.83mA   -132.3mA   -61.52mA
-906.8mV  -59.01mA   -103.9mA   -35.14mA
-859.1mV  -33.8mA    -77.16mA   -25.62mA
-811.4mV  -19.9mA    -53.08mA   -21.6mA
-715.9mV  -11.4mA    -18.73mA   -15.4mA
-572.7mV  -5.412mA   -4.636mA   -7.313mA
-334.1mV  -240.8uA   -308.8uA   -242.5uA
2.959V    8.682mA    6.832mA    11.15mA
[Power Clamp]
-1.459V   577.4mA    478.9mA    722.8mA
-1.077V   210.9mA    225.3mA    210.2mA
-1.03V    168.1mA    194.5mA    155.5mA
-981.8mV  127.5mA    164.2mA    106.7mA
-934.1mV  90.43mA    134.6mA    68.21mA
-886.4mV  58.96mA    106.1mA    45.13mA
-838.6mV  36.12mA    79.33mA    34.57mA
-743.2mV  17.82mA    35.48mA    23.27mA
-647.7mV  10.71mA    12.79mA    14.31mA
-552.3mV  5.453mA    5.392mA    7.2mA
-313.6mV  90.62uA    219.4uA    108.4uA
2.98V     -4.416mA   -3.704mA   -5.362mA
[Pulldown]
-1.48V    -2.7mA     -2.2mA     -3.4mA
-1.193V   -4.3mA     -3.1mA     -5.8mA
-954.6mV  -8.72mA    -5.2mA     -13.05mA
-811.4mV  -11.64mA   -8.07mA    -13.12mA
-525mV    -10.19mA   -10.29mA   -11.37mA
906.8mV   17.62mA    17.19mA    20.19mA
1.289V    21.6mA     20.89mA    24.7mA
1.814V    23.16mA    21.72mA    26.4mA
2.052V    20.52mA    17.85mA    24.7mA
2.386V    15.36mA    5.1mA      19.75mA
2.673V    4.6mA      2.4mA      13.7mA
2.959V    2.4mA      1.8mA      4.3mA
[Pullup]
-1.459V   1.4mA      1.357mA    1.629mA
-1.173V   3.6mA      2.314mA    7.3mA
-934.1mV  12.52mA    5.372mA    14.53mA
-695.5mV  15.52mA    14.06mA    15.89mA
-552.3mV  14.69mA    15.08mA    15.38mA
640.9mV   -13.71mA   -14.18mA   -15.51mA
1.834V    -19.47mA   -19.54mA   -22.76mA
2.12V     -17.71mA   -16.78mA   -21.07mA
2.311V    -16.98mA   -10.75mA   -20.29mA
2.502V    -10.9mA    -7.771mA   -19.63mA
2.741V    -6.9mA     -6.386mA   -9.986mA
2.98V     -5.8mA     -5.843mA   -6.971mA
[Ramp]
R_load=50.000Ohm
dV/dt_r   423.060mV/119.000ps  414.929mV/138.500ps  467.550mV/101.000ps
dV/dt_f   423.060mV/114.500ps  414.929mV/138.500ps  467.550mV/91.500ps
[Rising waveform]
R_fixture=50.000Ohm
V_fixture=1.500
V_fixture_min=1.425
V_fixture_max=1.575
0s        681.4mV    659.5mV    657.1mV
31ps      684.7mV    661.1mV    667.5mV
54ps      703.8mV    665.9mV    739mV
77ps      763.8mV    677.2mV    901.3mV
108ps     923.1mV    717.3mV    1.139V
146ps     1.136V     830.7mV    1.313V
199ps     1.305V     1.071V     1.413V
253ps     1.371V     1.235V     1.448V
337ps     1.403V     1.326V     1.464V
749ps     1.414V     1.36V      1.468V
[Rising waveform]
R_fixture=50.000Ohm
V_fixture=0
0s        -2.759mV   -1.787mV   -3.137mV
31ps      -8.298mV   -5.33mV    -6.613mV
54ps      -5.348mV   -8.672mV   31.07mV
92ps      55.89mV    -8.746mV   187.4mV
131ps     181.8mV    22mV       373mV
184ps     367.7mV    138.3mV    549.7mV
253ps     530.2mV    347.8mV    668.7mV
330ps     618.4mV    521mV      721mV
429ps     662.6mV    628.9mV    744mV
749ps     683.3mV    687.3mV    752.5mV
[Falling waveform]
R_fixture=50.000Ohm
V_fixture=1.500
V_fixture_min=1.425
V_fixture_max=1.575
0s        1.418V     1.363V     1.472V
46ps      1.422V     1.372V     1.451V
85ps      1.371V     1.37V      1.29V
161ps     1.096V     1.26V      905.7mV
199ps     962.6mV    1.151V     797.2mV
245ps     844.7mV    1.014V     728mV
330ps     741.3mV    821.6mV    680.6mV
406ps     709.4mV    736.8mV    669.6mV
506ps     695.3mV    694mV      665.1mV
749ps     689.4mV    671.1mV    662.7mV
[Falling waveform]
R_fixture=50.000Ohm
V_fixture=0
0s        695.1mV    702.7mV    761.2mV
23ps      687.8mV    701.4mV    745mV
39ps      664.7mV    694.8mV    692.3mV
85ps      483.6mV    623.3mV    370.8mV
108ps     356mV      551mV      234.6mV
131ps     245.5mV    457.8mV    146mV
184ps     96.19mV    234.4mV    49.77mV
238ps     36.76mV    100.7mV    17.42mV
322ps     9.01mV     27.89mV    3.575mV
749ps     -1.099uV   148uV      25.02uV
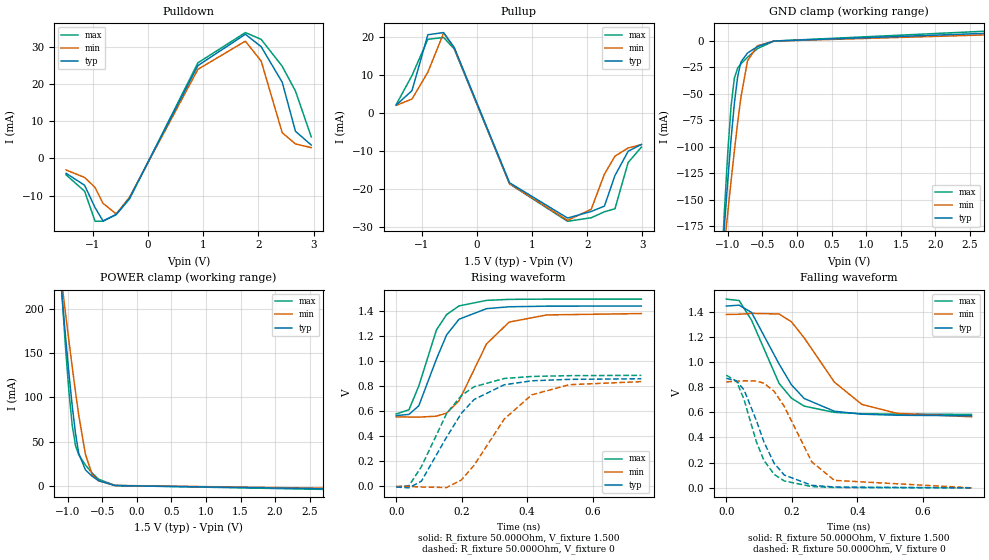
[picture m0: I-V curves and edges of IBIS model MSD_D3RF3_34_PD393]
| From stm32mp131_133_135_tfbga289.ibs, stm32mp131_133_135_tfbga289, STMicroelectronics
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[Model] MSD_D3RF3_34_PD393
Model_type   I/O
C_comp 2.355pF   2.274pF   2.477pF
Vinh = 925.000mV
Vinl = 575.000mV
Vmeas = 750.000mV
Vref = 750.000mV
[Model Spec]
Vinh   925.000mV   888.000mV   963.000mV
Vinl   575.000mV   538.000mV   613.000mV
Vmeas   750.000mV   713.000mV   788.000mV
Vref   750.000mV   713.000mV   788.000mV
[Temperature Range]   25.000   125.000   -40.000
[Voltage Range]   1.500V   1.425V   1.575V
[GND Clamp Reference]   0.00V   0.00V   0.00V
[Pulldown Reference]   0.00V   0.00V   0.00V
[POWER Clamp Reference]   1.500V   1.425V   1.575V
[Pullup Reference]   1.500V   1.425V   1.575V
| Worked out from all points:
|   slope of the pulldown table from 0 to 0.225 V, typ, clamps not added: 31.5 ohm
|   slope of the pullup table from 0 to 0.225 V, typ, clamps not added: 26.9 ohm
|   GND clamp passes 1 mA (typ) near -0.40 V on its own axis
|   POWER clamp passes 1 mA (typ) near -0.41 V on its own axis
|   rising waveform, R_fixture 50.000Ohm, V_fixture 1.500: 20-80 % time 80.4ps typ, 97ps min, 71.8ps max; typ from 0.565 V to 1.44 V
|   rising waveform, R_fixture 50.000Ohm, V_fixture 0: 20-80 % time 125ps typ, 141ps min, 112ps max; typ from -0.005 V to 0.858 V
|   falling waveform, R_fixture 50.000Ohm, V_fixture 1.500: 20-80 % time 114ps typ, 142ps min, 99.1ps max; typ from 1.44 V to 0.573 V
|   falling waveform, R_fixture 50.000Ohm, V_fixture 0: 20-80 % time 82.6ps typ, 102ps min, 71.7ps max; typ from 0.87 V to 0 V
[GND Clamp]
-1.48V    -594.2mA   -480mA     -763.6mA
-1.098V   -218.4mA   -223.5mA   -220.5mA
-1.05V    -174.3mA   -192.5mA   -159.9mA
-1.002V   -132.1mA   -162.1mA   -105.5mA
-954.6mV  -92.99mA   -132.5mA   -61.72mA
-906.8mV  -59.16mA   -104mA     -35.32mA
-859.1mV  -33.93mA   -77.28mA   -25.79mA
-811.4mV  -20.01mA   -53.17mA   -21.76mA
-715.9mV  -11.49mA   -18.81mA   -15.51mA
-572.7mV  -5.463mA   -4.679mA   -7.379mA
-334.1mV  -245.4uA   -313.4uA   -248.8uA
2.959V    7.591mA    5.979mA    9.761mA
[Power Clamp]
-1.459V   577.8mA    479.3mA    723.3mA
-1.077V   211.2mA    225.6mA    210.4mA
-1.03V    168.3mA    194.7mA    155.7mA
-981.8mV  127.7mA    164.4mA    106.9mA
-934.1mV  90.61mA    134.7mA    68.43mA
-886.4mV  59.12mA    106.2mA    45.32mA
-838.6mV  36.26mA    79.46mA    34.74mA
-743.2mV  17.92mA    35.58mA    23.41mA
-647.7mV  10.79mA    12.86mA    14.4mA
-552.3mV  5.5mA      5.442mA    7.264mA
-313.6mV  95.81uA    225.2uA    112.2uA
2.98V     -3.864mA   -3.241mA   -4.693mA
[Pulldown]
-1.48V    -4mA       -3.1mA     -4.4mA
-1.145V   -7.2mA     -5.1mA     -8.8mA
-954.6mV  -13.22mA   -7.8mA     -16.88mA
-811.4mV  -16.78mA   -12.04mA   -16.85mA
-572.7mV  -15.06mA   -14.91mA   -15.04mA
-334.1mV  -10.72mA   -10.48mA   -10.94mA
906.8mV   24.93mA    23.93mA    25.67mA
1.766V    33.35mA    31.49mA    33.8mA
2.052V    30.02mA    26.15mA    31.98mA
2.434V    20.44mA    6.9mA      24.74mA
2.673V    7.3mA      3.9mA      18.1mA
2.959V    3.6mA      2.9mA      5.8mA
[Pullup]
-1.459V   2.1mA      2.014mA    2.229mA
-1.173V   5.9mA      3.686mA    9.9mA
-886.4mV  20.66mA    10.76mA    19.45mA
-600mV    21.23mA    21.12mA    19.93mA
-409.1mV  17.29mA    17.18mA    16.91mA
593.2mV   -18.41mA   -18.64mA   -18.71mA
1.643V    -27.73mA   -28.34mA   -28.59mA
2.073V    -25.99mA   -25.4mA    -27.65mA
2.311V    -24.58mA   -16.14mA   -26.08mA
2.502V    -16.5mA    -11.4mA    -25.28mA
2.741V    -10.1mA    -9.229mA   -13.06mA
2.98V     -8.3mA     -8.343mA   -9.029mA
[Ramp]
R_load=50.000Ohm
dV/dt_r   517.230mV/103.500ps  496.979mV/120.000ps  538.560mV/92.500ps
dV/dt_f   517.230mV/99.000ps  496.979mV/123.500ps  538.560mV/85.500ps
[Rising waveform]
R_fixture=50.000Ohm
V_fixture=1.500
V_fixture_min=1.425
V_fixture_max=1.575
0s        564.6mV    555.2mV    577.2mV
39ps      574.1mV    553mV      611.3mV
69ps      642.5mV    552.1mV    800.1mV
123ps     1.016V     559.9mV    1.248V
154ps     1.208V     584.7mV    1.37V
192ps     1.333V     683.2mV    1.439V
276ps     1.417V     1.136V     1.483V
345ps     1.432V     1.31V      1.491V
460ps     1.437V     1.367V     1.493V
749ps     1.438V     1.378V     1.493V
[Rising waveform]
R_fixture=50.000Ohm
V_fixture=0
0s        -4.768mV   859.6uV    -4.847mV
39ps      -11.62mV   -718.8uV   5.735mV
77ps      42.1mV     -4.816mV   157.2mV
154ps     392.8mV    -9.429mV   580.8mV
199ps     582.8mV    51.39mV    724mV
238ps     693mV      168.7mV    794.5mV
330ps     810.3mV    536.7mV    860.2mV
414ps     841.8mV    729.6mV    876.5mV
529ps     853.4mV    810.9mV    882.8mV
749ps     857.9mV    835.3mV    885.4mV
[Falling waveform]
R_fixture=50.000Ohm
V_fixture=1.500
V_fixture_min=1.425
V_fixture_max=1.575
0s        1.444V     1.377V     1.499V
39ps      1.451V     1.379V     1.488V
77ps      1.393V     1.386V     1.332V
161ps     984.6mV    1.381V     830.4mV
199ps     818.2mV    1.319V     712.3mV
238ps     709.6mV    1.191V     649mV
330ps     608.6mV    840.2mV    599.6mV
414ps     585.3mV    663.1mV    589.2mV
521ps     576.8mV    592mV      584.9mV
749ps     572.7mV    564.5mV    583.6mV
[Falling waveform]
R_fixture=50.000Ohm
V_fixture=0
0s        870.1mV    841.7mV    894.4mV
31ps      849.3mV    846.7mV    847.8mV
54ps      778.8mV    850.5mV    702.6mV
92ps      533.8mV    848.6mV    364mV
115ps     363.2mV    831mV      218.1mV
146ps     195.4mV    767.2mV    107.7mV
177ps     102mV      647.1mV    54.69mV
261ps     20.26mV    207mV      10.42mV
330ps     6.647mV    59.44mV    2.884mV
749ps     31.9uV     307.3uV    16.88uV
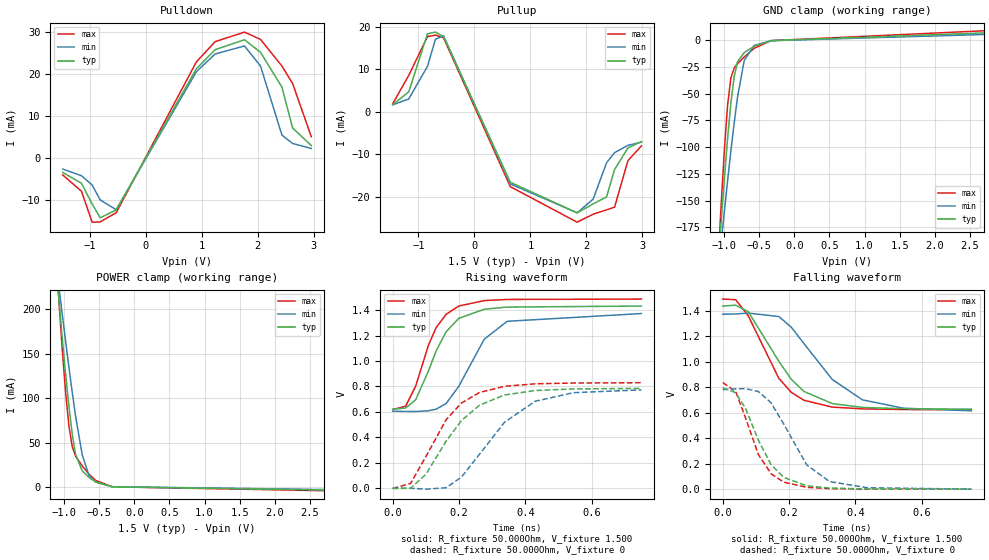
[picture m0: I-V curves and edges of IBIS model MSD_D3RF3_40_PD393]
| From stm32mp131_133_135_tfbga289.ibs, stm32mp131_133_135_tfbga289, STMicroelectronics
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[Model] MSD_D3RF3_40_PD393
Model_type   I/O
C_comp 2.355pF   2.274pF   2.477pF
Vinh = 925.000mV
Vinl = 575.000mV
Vmeas = 750.000mV
Vref = 750.000mV
[Model Spec]
Vinh   925.000mV   888.000mV   963.000mV
Vinl   575.000mV   538.000mV   613.000mV
Vmeas   750.000mV   713.000mV   788.000mV
Vref   750.000mV   713.000mV   788.000mV
[Temperature Range]   25.000   125.000   -40.000
[Voltage Range]   1.500V   1.425V   1.575V
[GND Clamp Reference]   0.00V   0.00V   0.00V
[Pulldown Reference]   0.00V   0.00V   0.00V
[POWER Clamp Reference]   1.500V   1.425V   1.575V
[Pullup Reference]   1.500V   1.425V   1.575V
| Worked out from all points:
|   slope of the pulldown table from 0 to 0.225 V, typ, clamps not added: 36.6 ohm
|   slope of the pullup table from 0 to 0.225 V, typ, clamps not added: 31.2 ohm
|   GND clamp passes 1 mA (typ) near -0.40 V on its own axis
|   POWER clamp passes 1 mA (typ) near -0.41 V on its own axis
|   rising waveform, R_fixture 50.000Ohm, V_fixture 1.500: 20-80 % time 85.4ps typ, 102ps min, 75.6ps max; typ from 0.62 V to 1.43 V
|   rising waveform, R_fixture 50.000Ohm, V_fixture 0: 20-80 % time 135ps typ, 152ps min, 120ps max; typ from -0.004 V to 0.784 V
|   falling waveform, R_fixture 50.000Ohm, V_fixture 1.500: 20-80 % time 124ps typ, 151ps min, 107ps max; typ from 1.44 V to 0.628 V
|   falling waveform, R_fixture 50.000Ohm, V_fixture 0: 20-80 % time 87.6ps typ, 105ps min, 75.7ps max; typ from 0.796 V to 0 V
[GND Clamp]
-1.48V    -594.2mA   -480mA     -763.6mA
-1.098V   -218.4mA   -223.5mA   -220.5mA
-1.05V    -174.3mA   -192.5mA   -159.9mA
-1.002V   -132.1mA   -162.1mA   -105.5mA
-954.6mV  -92.99mA   -132.5mA   -61.72mA
-906.8mV  -59.16mA   -104mA     -35.32mA
-859.1mV  -33.93mA   -77.28mA   -25.79mA
-811.4mV  -20.01mA   -53.17mA   -21.76mA
-715.9mV  -11.49mA   -18.81mA   -15.51mA
-572.7mV  -5.463mA   -4.679mA   -7.379mA
-334.1mV  -245.4uA   -313.4uA   -248.8uA
2.959V    7.591mA    5.979mA    9.761mA
[Power Clamp]
-1.459V   577.8mA    479.3mA    723.3mA
-1.077V   211.2mA    225.6mA    210.4mA
-1.03V    168.3mA    194.7mA    155.7mA
-981.8mV  127.7mA    164.4mA    106.9mA
-934.1mV  90.61mA    134.7mA    68.43mA
-886.4mV  59.12mA    106.2mA    45.32mA
-838.6mV  36.26mA    79.46mA    34.74mA
-743.2mV  17.92mA    35.58mA    23.41mA
-647.7mV  10.79mA    12.86mA    14.4mA
-552.3mV  5.5mA      5.442mA    7.264mA
-313.6mV  95.81uA    225.2uA    112.2uA
2.98V     -3.864mA   -3.241mA   -4.693mA
[Pulldown]
-1.48V    -3.4mA     -2.6mA     -4mA
-1.145V   -6mA       -4.2mA     -7.9mA
-954.6mV  -10.92mA   -6.4mA     -15.28mA
-811.4mV  -14.23mA   -9.95mA    -15.22mA
-525mV    -12.36mA   -12.3mA    -13.02mA
906.8mV   21.32mA    20.61mA    22.96mA
1.241V    25.87mA    24.84mA    27.78mA
1.766V    28.25mA    26.77mA    30.07mA
2.052V    25.24mA    21.96mA    28.34mA
2.434V    16.94mA    5.5mA      21.97mA
2.625V    7.2mA      3.5mA      17.8mA
2.959V    3mA        2.3mA      5.1mA
[Pullup]
-1.459V   1.7mA      1.657mA    1.929mA
-1.173V   4.7mA      3.029mA    8.571mA
-838.6mV  18.38mA    10.71mA    17.72mA
-695.5mV  18.79mA    17.12mA    18.09mA
-552.3mV  17.71mA    17.94mA    17.47mA
640.9mV   -16.58mA   -16.97mA   -17.62mA
1.834V    -23.79mA   -23.78mA   -25.99mA
2.12V     -21.67mA   -20.55mA   -24.11mA
2.359V    -20.05mA   -12.01mA   -23.08mA
2.502V    -13.6mA    -9.614mA   -22.45mA
2.741V    -8.5mA     -7.886mA   -11.5mA
2.98V     -7mA       -7.143mA   -8.029mA
[Ramp]
R_load=50.000Ohm
dV/dt_r   477.030mV/111.000ps  461.879mV/129.000ps  508.020mV/98.500ps
dV/dt_f   477.030mV/106.500ps  461.879mV/130.000ps  508.020mV/91.500ps
[Rising waveform]
R_fixture=50.000Ohm
V_fixture=1.500
V_fixture_min=1.425
V_fixture_max=1.575
0s        619.6mV    604.6mV    617.5mV
39ps      629.3mV    602.5mV    643.7mV
69ps      693.7mV    602.1mV    800.5mV
108ps     922.4mV    608mV      1.126V
131ps     1.08V      620.2mV    1.263V
161ps     1.23V      664.8mV    1.367V
199ps     1.335V     800.2mV    1.432V
276ps     1.407V     1.172V     1.475V
345ps     1.424V     1.312V     1.484V
749ps     1.432V     1.373V     1.487V
[Rising waveform]
R_fixture=50.000Ohm
V_fixture=0
0s        -4.123mV   720.9uV    -3.96mV
54ps      -2.747mV   -2.435mV   36.11mV
100ps     107.8mV    -9.287mV   247.4mV
161ps     369.1mV    2.005mV    537.4mV
207ps     530.6mV    85.49mV    668.3mV
261ps     651.2mV    263.7mV    751.2mV
337ps     732mV      517.9mV    800.6mV
429ps     767mV      682.3mV    819.9mV
544ps     779.6mV    750mV      826.1mV
749ps     783.7mV    772.3mV    828.7mV
[Falling waveform]
R_fixture=50.000Ohm
V_fixture=1.500
V_fixture_min=1.425
V_fixture_max=1.575
0s        1.437V     1.373V     1.492V
39ps      1.444V     1.375V     1.487V
77ps      1.393V     1.382V     1.36V
169ps     1.004V     1.355V     870.3mV
207ps     861.1mV    1.27V      759mV
245ps     766.8mV    1.142V     697.6mV
330ps     671.7mV    861mV      644.1mV
421ps     641.6mV    701.1mV    630.2mV
544ps     631.4mV    635.6mV    624.9mV
749ps     627.5mV    614.9mV    623.4mV
[Falling waveform]
R_fixture=50.000Ohm
V_fixture=0
0s        796.2mV    780.6mV    837.2mV
39ps      757.2mV    787.1mV    766.3mV
69ps      632.8mV    789mV      557.8mV
108ps     381.2mV    765.5mV    268.5mV
146ps     191.1mV    676.9mV    120.5mV
184ps     92.31mV    510.3mV    55.34mV
253ps     26.52mV    191mV      14.74mV
322ps     8.77mV     59.58mV    4.169mV
437ps     1.565mV    11.06mV    595uV
749ps     40.99uV    285.4uV    25.03uV
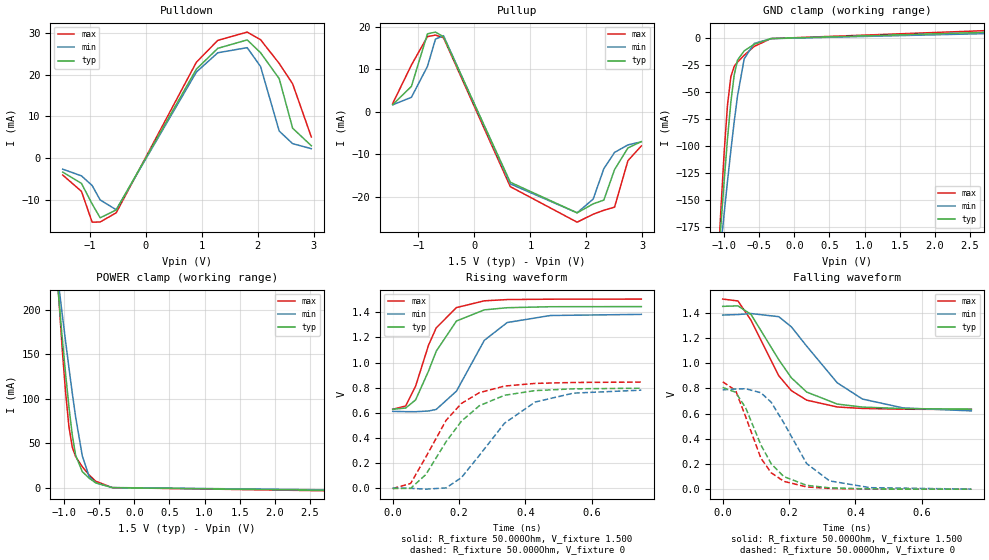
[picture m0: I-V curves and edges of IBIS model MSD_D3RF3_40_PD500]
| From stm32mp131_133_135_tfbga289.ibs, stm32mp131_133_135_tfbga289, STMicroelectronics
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[Model] MSD_D3RF3_40_PD500
Model_type   I/O
C_comp 2.402pF   2.320pF   2.524pF
Vinh = 925.000mV
Vinl = 575.000mV
Vmeas = 750.000mV
Vref = 750.000mV
[Model Spec]
Vinh   925.000mV   888.000mV   963.000mV
Vinl   575.000mV   538.000mV   613.000mV
Vmeas   750.000mV   713.000mV   788.000mV
Vref   750.000mV   713.000mV   788.000mV
[Temperature Range]   25.000   125.000   -40.000
[Voltage Range]   1.500V   1.425V   1.575V
[GND Clamp Reference]   0.00V   0.00V   0.00V
[Pulldown Reference]   0.00V   0.00V   0.00V
[POWER Clamp Reference]   1.500V   1.425V   1.575V
[Pullup Reference]   1.500V   1.425V   1.575V
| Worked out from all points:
|   slope of the pulldown table from 0 to 0.225 V, typ, clamps not added: 36.6 ohm
|   slope of the pullup table from 0 to 0.225 V, typ, clamps not added: 31.2 ohm
|   GND clamp passes 1 mA (typ) near -0.40 V on its own axis
|   POWER clamp passes 1 mA (typ) near -0.41 V on its own axis
|   rising waveform, R_fixture 50.000Ohm, V_fixture 1.500: 20-80 % time 86.4ps typ, 103ps min, 76.5ps max; typ from 0.628 V to 1.45 V
|   rising waveform, R_fixture 50.000Ohm, V_fixture 0: 20-80 % time 137ps typ, 154ps min, 123ps max; typ from -0.004 V to 0.795 V
|   falling waveform, R_fixture 50.000Ohm, V_fixture 1.500: 20-80 % time 128ps typ, 153ps min, 110ps max; typ from 1.45 V to 0.636 V
|   falling waveform, R_fixture 50.000Ohm, V_fixture 0: 20-80 % time 89.4ps typ, 107ps min, 77.6ps max; typ from 0.808 V to 0 V
[GND Clamp]
-1.48V    -594.8mA   -480.4mA   -764.2mA
-1.098V   -218.7mA   -223.8mA   -220.9mA
-1.05V    -174.5mA   -192.8mA   -160.2mA
-1.002V   -132.3mA   -162.4mA   -105.8mA
-954.6mV  -93.23mA   -132.6mA   -62.04mA
-906.8mV  -59.38mA   -104.2mA   -35.61mA
-859.1mV  -34.13mA   -77.43mA   -26.05mA
-811.4mV  -20.2mA    -53.31mA   -21.99mA
-715.9mV  -11.62mA   -18.92mA   -15.69mA
-572.7mV  -5.538mA   -4.741mA   -7.48mA
-334.1mV  -251.7uA   -319.9uA   -256.8uA
2.959V    5.967mA    4.7mA      7.668mA
[Power Clamp]
-1.459V   578.3mA    479.7mA    723.9mA
-1.077V   211.5mA    225.8mA    210.9mA
-1.03V    168.6mA    195mA      156.1mA
-981.8mV  128mA      164.6mA    107.2mA
-934.1mV  90.86mA    134.9mA    68.75mA
-886.4mV  59.34mA    106.4mA    45.62mA
-838.6mV  36.47mA    79.64mA    35mA
-743.2mV  18.09mA    35.72mA    23.61mA
-647.7mV  10.91mA    12.96mA    14.55mA
-552.3mV  5.576mA    5.511mA    7.355mA
-313.6mV  99.81uA    233.7uA    118uA
2.98V     -3.037mA   -2.547mA   -3.688mA
[Pulldown]
-1.48V    -3.3mA     -2.6mA     -4mA
-1.145V   -6mA       -4.2mA     -7.9mA
-954.6mV  -10.91mA   -6.5mA     -15.27mA
-811.4mV  -14.22mA   -9.95mA    -15.22mA
-525mV    -12.36mA   -12.3mA    -13.03mA
906.8mV   21.31mA    20.61mA    22.96mA
1.289V    26.28mA    25.22mA    28.18mA
1.814V    28.29mA    26.44mA    30.16mA
2.052V    25.24mA    21.95mA    28.34mA
2.386V    19.03mA    6.5mA      22.66mA
2.625V    7.2mA      3.5mA      17.8mA
2.959V    3mA        2.3mA      5.1mA
[Pullup]
-1.459V   1.7mA      1.657mA    1.971mA
-1.125V   6mA        3.429mA    11.03mA
-838.6mV  18.38mA    10.71mA    17.72mA
-695.5mV  18.79mA    17.13mA    18.09mA
-552.3mV  17.7mA     17.94mA    17.47mA
640.9mV   -16.58mA   -16.97mA   -17.62mA
1.834V    -23.79mA   -23.78mA   -25.99mA
2.12V     -21.67mA   -20.55mA   -24.11mA
2.311V    -20.78mA   -13.39mA   -23.18mA
2.502V    -13.6mA    -9.557mA   -22.45mA
2.741V    -8.5mA     -7.786mA   -11.5mA
2.98V     -7mA       -7.043mA   -8.029mA
[Ramp]
R_load=50.000Ohm
dV/dt_r   482.460mV/112.500ps  465.869mV/129.500ps  515.310mV/100.500ps
dV/dt_f   482.460mV/109.500ps  465.869mV/132.000ps  515.310mV/94.500ps
[Rising waveform]
R_fixture=50.000Ohm
V_fixture=1.500
V_fixture_min=1.425
V_fixture_max=1.575
0s        627.5mV    611mV      627.1mV
39ps      637.5mV    608.7mV    653.8mV
69ps      702.6mV    608.3mV    812.1mV
108ps     932.8mV    614mV      1.139V
131ps     1.09V      626.2mV    1.276V
192ps     1.331V     772mV      1.438V
276ps     1.42V      1.177V     1.492V
345ps     1.437V     1.319V     1.502V
475ps     1.445V     1.375V     1.505V
749ps     1.446V     1.384V     1.506V
[Rising waveform]
R_fixture=50.000Ohm
V_fixture=0
0s        -4.121mV   738.7uV    -3.959mV
54ps      -2.768mV   -2.315mV   36.09mV
100ps     107.9mV    -9.12mV    247.8mV
161ps     370mV      943.3uV    540.2mV
207ps     532.9mV    83.02mV    673.9mV
261ps     655.7mV    260.2mV    759.9mV
337ps     739.3mV    516.8mV    812.6mV
429ps     776.5mV    685.2mV    833.9mV
544ps     790.5mV    756.1mV    841.2mV
749ps     795.4mV    780mV      844.4mV
[Falling waveform]
R_fixture=50.000Ohm
V_fixture=1.500
V_fixture_min=1.425
V_fixture_max=1.575
0s        1.452V     1.383V     1.51V
46ps      1.456V     1.387V     1.495V
85ps      1.389V     1.395V     1.343V
169ps     1.028V     1.37V      900.4mV
207ps     884.1mV    1.289V     782.2mV
253ps     771.5mV    1.136V     707.1mV
345ps     676.1mV    844.9mV    652.8mV
421ps     651.9mV    715.8mV    641.1mV
544ps     640.1mV    644.9mV    635mV
749ps     635.7mV    621.8mV    633.1mV
[Falling waveform]
R_fixture=50.000Ohm
V_fixture=0
0s        808mV      789.1mV    852.8mV
39ps      769.8mV    795.6mV    783.4mV
69ps      646.6mV    797.8mV    576.1mV
115ps     351.8mV    766.1mV    245.9mV
146ps     202mV      691mV      130.7mV
184ps     100.1mV    526.8mV    62.18mV
253ps     30.42mV    203mV      17.79mV
322ps     10.67mV    65.77mV    5.438mV
444ps     1.91mV     11.88mV    819.9uV
749ps     65.45uV    392.7uV    32.25uV
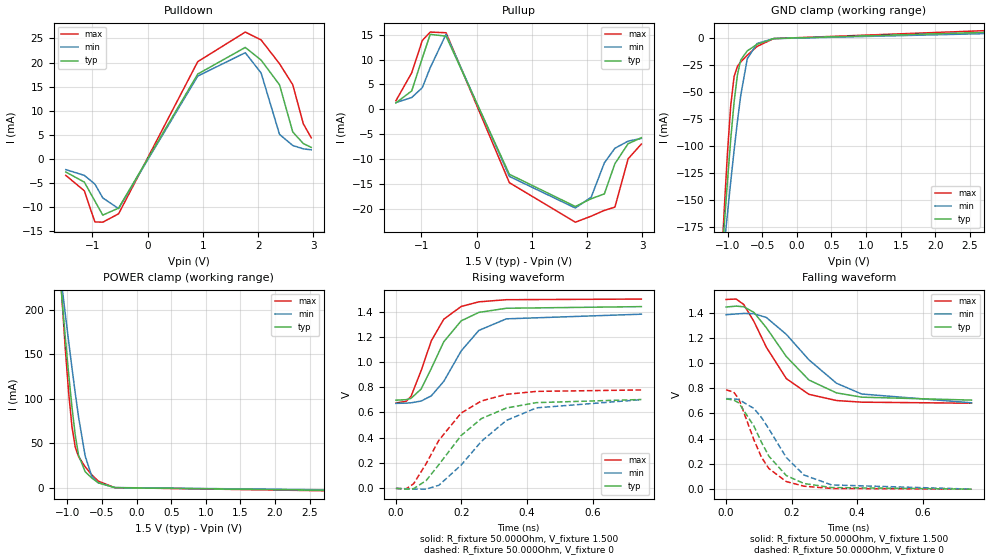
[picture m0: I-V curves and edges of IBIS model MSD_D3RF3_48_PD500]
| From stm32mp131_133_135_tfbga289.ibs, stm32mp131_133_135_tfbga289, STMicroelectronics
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[Model] MSD_D3RF3_48_PD500
Model_type   I/O
C_comp 2.402pF   2.320pF   2.524pF
Vinh = 925.000mV
Vinl = 575.000mV
Vmeas = 750.000mV
Vref = 750.000mV
[Model Spec]
Vinh   925.000mV   888.000mV   963.000mV
Vinl   575.000mV   538.000mV   613.000mV
Vmeas   750.000mV   713.000mV   788.000mV
Vref   750.000mV   713.000mV   788.000mV
[Temperature Range]   25.000   125.000   -40.000
[Voltage Range]   1.500V   1.425V   1.575V
[GND Clamp Reference]   0.00V   0.00V   0.00V
[Pulldown Reference]   0.00V   0.00V   0.00V
[POWER Clamp Reference]   1.500V   1.425V   1.575V
[Pullup Reference]   1.500V   1.425V   1.575V
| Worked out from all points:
|   slope of the pulldown table from 0 to 0.225 V, typ, clamps not added: 44.1 ohm
|   slope of the pullup table from 0 to 0.225 V, typ, clamps not added: 37.5 ohm
|   GND clamp passes 1 mA (typ) near -0.40 V on its own axis
|   POWER clamp passes 1 mA (typ) near -0.41 V on its own axis
|   rising waveform, R_fixture 50.000Ohm, V_fixture 1.500: 20-80 % time 93.2ps typ, 110ps min, 79.2ps max; typ from 0.698 V to 1.44 V
|   rising waveform, R_fixture 50.000Ohm, V_fixture 0: 20-80 % time 150ps typ, 170ps min, 129ps max; typ from -0.003 V to 0.703 V
|   falling waveform, R_fixture 50.000Ohm, V_fixture 1.500: 20-80 % time 140ps typ, 170ps min, 113ps max; typ from 1.44 V to 0.706 V
|   falling waveform, R_fixture 50.000Ohm, V_fixture 0: 20-80 % time 95.9ps typ, 115ps min, 79.3ps max; typ from 0.715 V to 0 V
[GND Clamp]
-1.48V    -594.8mA   -480.4mA   -764.2mA
-1.098V   -218.7mA   -223.8mA   -220.9mA
-1.05V    -174.5mA   -192.8mA   -160.2mA
-1.002V   -132.3mA   -162.4mA   -105.8mA
-954.6mV  -93.23mA   -132.6mA   -62.04mA
-906.8mV  -59.38mA   -104.2mA   -35.61mA
-859.1mV  -34.13mA   -77.43mA   -26.05mA
-811.4mV  -20.2mA    -53.31mA   -21.99mA
-715.9mV  -11.62mA   -18.92mA   -15.69mA
-572.7mV  -5.538mA   -4.741mA   -7.48mA
-334.1mV  -251.7uA   -319.9uA   -256.8uA
2.959V    5.967mA    4.7mA      7.668mA
[Power Clamp]
-1.459V   578.3mA    479.7mA    723.9mA
-1.077V   211.5mA    225.8mA    210.9mA
-1.03V    168.6mA    195mA      156.1mA
-981.8mV  128mA      164.6mA    107.2mA
-934.1mV  90.86mA    134.9mA    68.75mA
-886.4mV  59.34mA    106.4mA    45.62mA
-838.6mV  36.47mA    79.64mA    35mA
-743.2mV  18.09mA    35.72mA    23.61mA
-647.7mV  10.91mA    12.96mA    14.55mA
-552.3mV  5.576mA    5.511mA    7.355mA
-313.6mV  99.81uA    233.7uA    118uA
2.98V     -3.037mA   -2.547mA   -3.688mA
[Pulldown]
-1.48V    -2.7mA     -2.2mA     -3.4mA
-1.145V   -4.8mA     -3.4mA     -6.6mA
-954.6mV  -8.71mA    -5.2mA     -13.05mA
-811.4mV  -11.64mA   -8.07mA    -13.11mA
-525mV    -10.19mA   -10.29mA   -11.37mA
906.8mV   17.62mA    17.2mA     20.19mA
1.766V    23.14mA    22.04mA    26.32mA
2.052V    20.52mA    17.85mA    24.7mA
2.386V    15.37mA    5.1mA      19.75mA
2.625V    5.6mA      2.8mA      15.4mA
2.816V    3.2mA      2.1mA      7.3mA
2.959V    2.4mA      1.9mA      4.4mA
[Pullup]
-1.459V   1.3mA      1.357mA    1.729mA
-1.173V   3.7mA      2.371mA    7.343mA
-981.8mV  10.3mA     4.357mA    13.83mA
-838.6mV  15.06mA    8.367mA    15.51mA
-552.3mV  14.69mA    15.08mA    15.38mA
593.2mV   -13.04mA   -13.47mA   -14.73mA
1.786V    -19.51mA   -19.82mA   -22.66mA
2.073V    -17.95mA   -17.63mA   -21.45mA
2.311V    -16.98mA   -10.74mA   -20.29mA
2.502V    -10.9mA    -7.814mA   -19.63mA
2.741V    -6.9mA     -6.386mA   -9.928mA
2.98V     -5.7mA     -5.843mA   -6.971mA
[Ramp]
R_load=50.000Ohm
dV/dt_r   432.030mV/122.500ps  421.559mV/141.000ps  479.640mV/104.500ps
dV/dt_f   432.030mV/119.000ps  421.559mV/143.000ps  479.640mV/97.000ps
[Rising waveform]
R_fixture=50.000Ohm
V_fixture=1.500
V_fixture_min=1.425
V_fixture_max=1.575
0s        697.6mV    672.2mV    675.4mV
31ps      701.5mV    673.9mV    687.8mV
46ps      712mV      676.6mV    727.3mV
77ps      786.3mV    690.6mV    932.3mV
108ps     949.3mV    731.7mV    1.169V
146ps     1.161V     846.8mV    1.34V
199ps     1.327V     1.088V     1.441V
253ps     1.394V     1.251V     1.478V
337ps     1.427V     1.343V     1.495V
749ps     1.44V      1.38V      1.5V
[Rising waveform]
R_fixture=50.000Ohm
V_fixture=0
0s        -2.894mV   -1.781mV   -3.354mV
31ps      -8.45mV    -5.329mV   -6.141mV
54ps      -4.702mV   -8.679mV   34.03mV
92ps      58.57mV    -8.783mV   192.8mV
131ps     185.8mV    21.93mV    379.1mV
199ps     416.9mV    182.5mV    595.3mV
261ps     551.4mV    371.1mV    691.7mV
337ps     635.3mV    536.6mV    743.8mV
429ps     678.1mV    636.7mV    767.3mV
749ps     702.8mV    701.6mV    778.6mV
[Falling waveform]
R_fixture=50.000Ohm
V_fixture=1.500
V_fixture_min=1.425
V_fixture_max=1.575
0s        1.444V     1.383V     1.504V
31ps      1.451V     1.389V     1.507V
54ps      1.446V     1.393V     1.464V
85ps      1.401V     1.391V     1.33V
123ps     1.28V      1.361V     1.125V
184ps     1.051V     1.227V     876.2mV
253ps     865.1mV    1.025V     751.6mV
337ps     763.4mV    839.8mV    702.7mV
414ps     729.2mV    754.3mV    689.6mV
749ps     706mV      684.7mV    681.3mV
[Falling waveform]
R_fixture=50.000Ohm
V_fixture=0
0s        714.9mV    717.5mV    787.3mV
23ps      707.2mV    716.3mV    770.3mV
39ps      683.4mV    710mV      715.8mV
85ps      500.6mV    640.1mV    391.2mV
108ps     372.1mV    568.6mV    253.3mV
131ps     260.7mV    475.8mV    162.2mV
184ps     107.7mV    250.4mV    60.16mV
238ps     44.82mV    111.9mV    23.31mV
322ps     12.67mV    33.7mV     5.676mV
749ps     100.5uV    261.6uV    -31.76uV
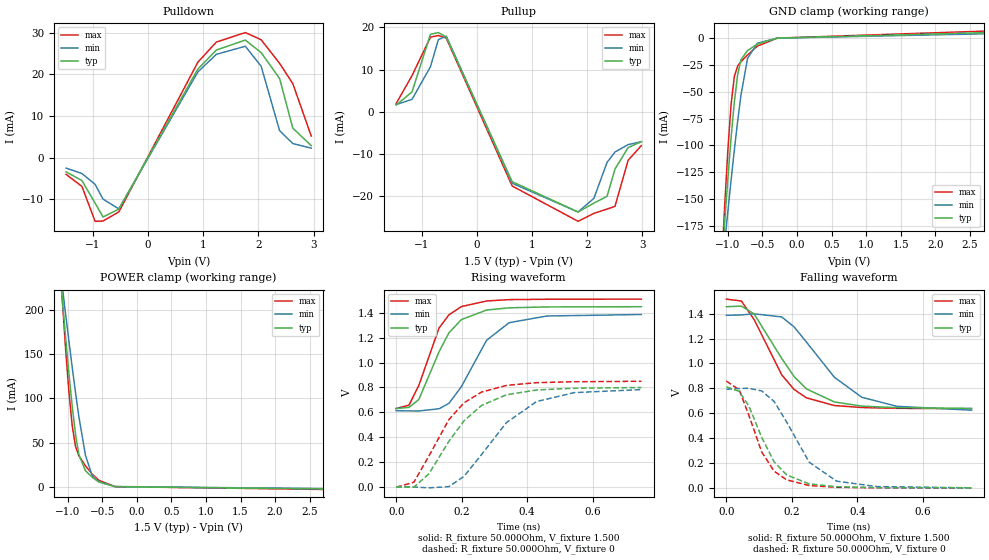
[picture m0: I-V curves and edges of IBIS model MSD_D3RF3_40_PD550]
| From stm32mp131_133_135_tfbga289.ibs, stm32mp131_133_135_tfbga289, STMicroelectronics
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[Model] MSD_D3RF3_40_PD550
Model_type   I/O
C_comp 2.415pF   2.332pF   2.538pF
Vinh = 925.000mV
Vinl = 575.000mV
Vmeas = 750.000mV
Vref = 750.000mV
[Model Spec]
Vinh   925.000mV   888.000mV   963.000mV
Vinl   575.000mV   538.000mV   613.000mV
Vmeas   750.000mV   713.000mV   788.000mV
Vref   750.000mV   713.000mV   788.000mV
[Temperature Range]   25.000   125.000   -40.000
[Voltage Range]   1.500V   1.425V   1.575V
[GND Clamp Reference]   0.00V   0.00V   0.00V
[Pulldown Reference]   0.00V   0.00V   0.00V
[POWER Clamp Reference]   1.500V   1.425V   1.575V
[Pullup Reference]   1.500V   1.425V   1.575V
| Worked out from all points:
|   slope of the pulldown table from 0 to 0.225 V, typ, clamps not added: 36.6 ohm
|   slope of the pullup table from 0 to 0.225 V, typ, clamps not added: 31.2 ohm
|   GND clamp passes 1 mA (typ) near -0.40 V on its own axis
|   POWER clamp passes 1 mA (typ) near -0.41 V on its own axis
|   rising waveform, R_fixture 50.000Ohm, V_fixture 1.500: 20-80 % time 86.6ps typ, 103ps min, 77.1ps max; typ from 0.63 V to 1.45 V
|   rising waveform, R_fixture 50.000Ohm, V_fixture 0: 20-80 % time 138ps typ, 154ps min, 123ps max; typ from -0.004 V to 0.799 V
|   falling waveform, R_fixture 50.000Ohm, V_fixture 1.500: 20-80 % time 128ps typ, 154ps min, 111ps max; typ from 1.46 V to 0.639 V
|   falling waveform, R_fixture 50.000Ohm, V_fixture 0: 20-80 % time 90ps typ, 107ps min, 78.2ps max; typ from 0.812 V to 0 V
[GND Clamp]
-1.48V    -594.8mA   -480.6mA   -764.4mA
-1.098V   -218.9mA   -223.9mA   -221.1mA
-1.05V    -174.6mA   -192.8mA   -160.4mA
-1.002V   -132.4mA   -162.4mA   -105.9mA
-954.6mV  -93.31mA   -132.8mA   -62.14mA
-906.8mV  -59.46mA   -104.2mA   -35.71mA
-859.1mV  -34.19mA   -77.49mA   -26.14mA
-811.4mV  -20.25mA   -53.36mA   -22.06mA
-715.9mV  -11.67mA   -18.95mA   -15.74mA
-572.7mV  -5.563mA   -4.762mA   -7.514mA
-286.4mV  -72.83uA   -122.9uA   -58.2uA
2.959V    5.427mA    4.273mA    6.977mA
[Power Clamp]
-1.459V   578.6mA    479.9mA    724.1mA
-1.077V   211.6mA    226mA      211mA
-1.03V    168.7mA    195.1mA    156.2mA
-981.8mV  128mA      164.7mA    107.3mA
-934.1mV  90.94mA    135mA      68.85mA
-886.4mV  59.42mA    106.5mA    45.71mA
-838.6mV  36.53mA    79.7mA     35.09mA
-743.2mV  18.14mA    35.77mA    23.67mA
-647.7mV  10.94mA    13mA       14.59mA
-552.3mV  5.6mA      5.535mA    7.379mA
-313.6mV  101uA      237.7uA    117.6uA
2.98V     -2.761mA   -2.315mA   -3.352mA
[Pulldown]
-1.48V    -3.4mA     -2.5mA     -4mA
-1.193V   -5.5mA     -3.8mA     -6.9mA
-954.6mV  -10.91mA   -6.4mA     -15.28mA
-811.4mV  -14.23mA   -9.94mA    -15.22mA
-525mV    -12.36mA   -12.3mA    -13.03mA
906.8mV   21.31mA    20.61mA    22.95mA
1.241V    25.86mA    24.84mA    27.78mA
1.766V    28.26mA    26.77mA    30.06mA
2.052V    25.24mA    21.96mA    28.33mA
2.386V    19.03mA    6.5mA      22.66mA
2.625V    7.1mA      3.4mA      17.8mA
2.959V    2.9mA      2.3mA      5.2mA
[Pullup]
-1.459V   1.6mA      1.714mA    1.971mA
-1.173V   4.7mA      2.929mA    8.571mA
-838.6mV  18.38mA    10.7mA     17.71mA
-695.5mV  18.79mA    17.12mA    18.09mA
-552.3mV  17.71mA    17.94mA    17.47mA
640.9mV   -16.59mA   -16.97mA   -17.62mA
1.834V    -23.79mA   -23.77mA   -25.99mA
2.12V     -21.68mA   -20.55mA   -24.11mA
2.359V    -20.05mA   -12.01mA   -23.08mA
2.502V    -13.6mA    -9.557mA   -22.45mA
2.741V    -8.5mA     -7.786mA   -11.5mA
2.98V     -7.1mA     -7.1mA     -8.014mA
[Ramp]
R_load=50.000Ohm
dV/dt_r   484.290mV/113.000ps  467.189mV/130.500ps  517.770mV/101.000ps
dV/dt_f   484.290mV/109.500ps  467.189mV/132.500ps  517.770mV/95.500ps
[Rising waveform]
R_fixture=50.000Ohm
V_fixture=1.500
V_fixture_min=1.425
V_fixture_max=1.575
0s        630.3mV    613.1mV    630.4mV
39ps      639.5mV    610.9mV    657.2mV
69ps      702.1mV    610.5mV    816.1mV
131ps     1.088V     628.4mV    1.28V
161ps     1.24V      671.9mV    1.385V
199ps     1.347V     806.2mV    1.452V
276ps     1.424V     1.18V      1.497V
345ps     1.442V     1.322V     1.508V
460ps     1.449V     1.376V     1.511V
749ps     1.451V     1.388V     1.512V
[Rising waveform]
R_fixture=50.000Ohm
V_fixture=0
0s        -3.927mV   739.9uV    -3.958mV
54ps      -3.583mV   -2.314mV   36.08mV
100ps     104.4mV    -9.122mV   247.9mV
161ps     366.1mV    931.4uV    541.2mV
207ps     530.8mV    83.01mV    676mV
261ps     655.6mV    260.3mV    763.1mV
337ps     741.3mV    517.4mV    816.8mV
429ps     779.7mV    686.8mV    838.8mV
544ps     794.2mV    758.4mV    846.3mV
749ps     799.4mV    782.9mV    849.7mV
[Falling waveform]
R_fixture=50.000Ohm
V_fixture=1.500
V_fixture_min=1.425
V_fixture_max=1.575
0s        1.456V     1.387V     1.517V
46ps      1.461V     1.39V      1.502V
85ps      1.398V     1.399V     1.352V
169ps     1.041V     1.374V     909mV
207ps     894.9mV    1.294V     791.1mV
245ps     795.3mV    1.171V     723.2mV
330ps     690.6mV    889.2mV    661.9mV
414ps     657mV      727.9mV    645.6mV
521ps     644.3mV    655.6mV    639.1mV
749ps     638.5mV    624.2mV    636.4mV
[Falling waveform]
R_fixture=50.000Ohm
V_fixture=0
0s        812mV      792mV      858.1mV
39ps      776.3mV    798.5mV    789.3mV
69ps      656.8mV    800.7mV    582.3mV
108ps     406.1mV    779.2mV    289mV
146ps     209.3mV    694.5mV    134.2mV
184ps     104.6mV    530.7mV    64.4mV
253ps     32.15mV    206.6mV    18.69mV
337ps     9.164mV    53.76mV    4.481mV
460ps     1.641mV    10.28mV    590.4uV
749ps     68.04uV    404.7uV    -9.074uV
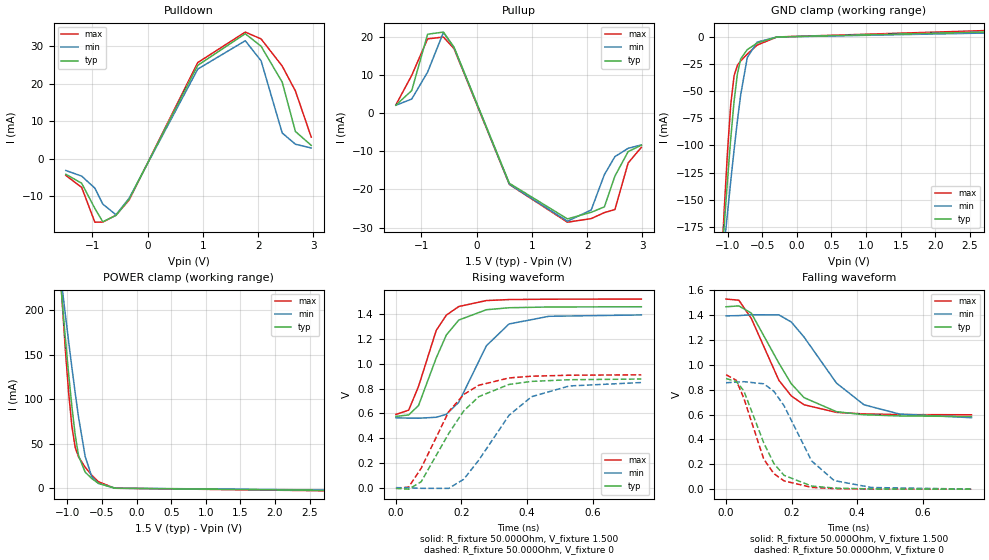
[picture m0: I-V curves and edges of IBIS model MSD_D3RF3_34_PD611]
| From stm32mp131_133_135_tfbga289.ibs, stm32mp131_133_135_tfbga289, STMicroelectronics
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[Model] MSD_D3RF3_34_PD611
Model_type   I/O
C_comp 2.432pF   2.349pF   2.555pF
Vinh = 925.000mV
Vinl = 575.000mV
Vmeas = 750.000mV
Vref = 750.000mV
[Model Spec]
Vinh   925.000mV   888.000mV   963.000mV
Vinl   575.000mV   538.000mV   613.000mV
Vmeas   750.000mV   713.000mV   788.000mV
Vref   750.000mV   713.000mV   788.000mV
[Temperature Range]   25.000   125.000   -40.000
[Voltage Range]   1.500V   1.425V   1.575V
[GND Clamp Reference]   0.00V   0.00V   0.00V
[Pulldown Reference]   0.00V   0.00V   0.00V
[POWER Clamp Reference]   1.500V   1.425V   1.575V
[Pullup Reference]   1.500V   1.425V   1.575V
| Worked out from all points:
|   slope of the pulldown table from 0 to 0.225 V, typ, clamps not added: 31.5 ohm
|   slope of the pullup table from 0 to 0.225 V, typ, clamps not added: 26.9 ohm
|   GND clamp passes 1 mA (typ) near -0.40 V on its own axis
|   POWER clamp passes 1 mA (typ) near -0.41 V on its own axis
|   rising waveform, R_fixture 50.000Ohm, V_fixture 1.500: 20-80 % time 81.7ps typ, 97.8ps min, 72.9ps max; typ from 0.576 V to 1.46 V
|   rising waveform, R_fixture 50.000Ohm, V_fixture 0: 20-80 % time 128ps typ, 143ps min, 116ps max; typ from -0.005 V to 0.877 V
|   falling waveform, R_fixture 50.000Ohm, V_fixture 1.500: 20-80 % time 119ps typ, 146ps min, 104ps max; typ from 1.47 V to 0.584 V
|   falling waveform, R_fixture 50.000Ohm, V_fixture 0: 20-80 % time 85.1ps typ, 103ps min, 74.4ps max; typ from 0.889 V to 0 V
[GND Clamp]
-1.48V    -595mA     -480.7mA   -764.6mA
-1.098V   -219mA     -223.9mA   -221.1mA
-1.05V    -174.7mA   -192.9mA   -160.5mA
-1.002V   -132.5mA   -162.5mA   -106mA
-954.6mV  -93.4mA    -132.8mA   -62.25mA
-906.8mV  -59.53mA   -104.3mA   -35.8mA
-859.1mV  -34.26mA   -77.55mA   -26.22mA
-811.4mV  -20.31mA   -53.41mA   -22.15mA
-715.9mV  -11.72mA   -18.99mA   -15.8mA
-572.7mV  -5.588mA   -4.783mA   -7.547mA
-286.4mV  -73.43uA   -123.8uA   -58.97uA
2.959V    4.881mA    3.846mA    6.279mA
[Power Clamp]
-1.459V   578.7mA    480mA      724.4mA
-1.077V   211.7mA    226mA      211.1mA
-1.03V    168.8mA    195.2mA    156.4mA
-981.8mV  128.1mA    164.8mA    107.5mA
-934.1mV  91.03mA    135.1mA    68.96mA
-886.4mV  59.5mA     106.6mA    45.8mA
-838.6mV  36.6mA     79.76mA    35.17mA
-743.2mV  18.19mA    35.82mA    23.74mA
-647.7mV  10.98mA    13.03mA    14.65mA
-552.3mV  5.626mA    5.558mA    7.412mA
-313.6mV  103.6uA    240.5uA    119.4uA
2.98V     -2.485mA   -2.084mA   -3.018mA
[Pulldown]
-1.48V    -4.1mA     -3.1mA     -4.4mA
-1.193V   -6.5mA     -4.6mA     -7.6mA
-954.6mV  -13.2mA    -7.8mA     -16.88mA
-811.4mV  -16.78mA   -12.04mA   -16.85mA
-572.7mV  -15.06mA   -14.91mA   -15.03mA
-334.1mV  -10.72mA   -10.49mA   -10.95mA
906.8mV   24.93mA    23.93mA    25.67mA
1.766V    33.35mA    31.49mA    33.79mA
2.052V    30.02mA    26.14mA    31.97mA
2.434V    20.45mA    6.9mA      24.74mA
2.673V    7.3mA      3.9mA      18.1mA
2.959V    3.6mA      2.9mA      5.8mA
[Pullup]
-1.459V   2.1mA      2.057mA    2.171mA
-1.173V   5.9mA      3.686mA    9.9mA
-886.4mV  20.67mA    10.74mA    19.45mA
-600mV    21.23mA    21.13mA    19.93mA
-409.1mV  17.29mA    17.18mA    16.91mA
593.2mV   -18.4mA    -18.64mA   -18.71mA
1.643V    -27.73mA   -28.33mA   -28.59mA
2.073V    -25.99mA   -25.39mA   -27.65mA
2.311V    -24.58mA   -16.14mA   -26.08mA
2.502V    -16.5mA    -11.4mA    -25.27mA
2.741V    -10.1mA    -9.229mA   -13.07mA
2.98V     -8.4mA     -8.343mA   -8.971mA
[Ramp]
R_load=50.000Ohm
dV/dt_r   526.170mV/105.000ps  503.519mV/121.500ps  550.530mV/95.000ps
dV/dt_f   526.170mV/102.500ps  503.519mV/126.500ps  550.530mV/89.500ps
[Rising waveform]
R_fixture=50.000Ohm
V_fixture=1.500
V_fixture_min=1.425
V_fixture_max=1.575
0s        575.6mV    564.1mV    591.4mV
39ps      587.3mV    561.8mV    626.2mV
69ps      663.5mV    560.9mV    817.8mV
123ps     1.047V     568.6mV    1.269V
154ps     1.233V     592.5mV    1.393V
192ps     1.353V     690mV      1.462V
276ps     1.436V     1.145V     1.51V
345ps     1.452V     1.321V     1.518V
467ps     1.458V     1.383V     1.521V
749ps     1.46V      1.394V     1.522V
[Rising waveform]
R_fixture=50.000Ohm
V_fixture=0
0s        -5.231mV   882.8uV    -4.845mV
39ps      -11.33mV   -647.9uV   5.699mV
77ps      48.14mV    -4.677mV   157.4mV
161ps     437.3mV    -5.122mV   613.3mV
207ps     619.9mV    69.01mV    752.2mV
253ps     735.2mV    223mV      826.9mV
345ps     833.2mV    584.3mV    885.7mV
414ps     857.9mV    734.5mV    899.7mV
529ps     871.4mV    821.1mV    907.8mV
749ps     876.9mV    848.7mV    910.9mV
[Falling waveform]
R_fixture=50.000Ohm
V_fixture=1.500
V_fixture_min=1.425
V_fixture_max=1.575
0s        1.466V     1.393V     1.528V
39ps      1.473V     1.395V     1.519V
77ps      1.415V     1.402V     1.373V
161ps     1.014V     1.401V     876.2mV
199ps     847.4mV    1.344V     749.4mV
238ps     735.6mV    1.223V     678.3mV
337ps     622.9mV    852.6mV    617mV
421ps     598.2mV    678.2mV    604.8mV
529ps     588.6mV    604mV      599.6mV
749ps     583.9mV    574.3mV    597.9mV
[Falling waveform]
R_fixture=50.000Ohm
V_fixture=0
0s        889.1mV    855.4mV    919.9mV
31ps      866mV      860.3mV    875.5mV
54ps      791.6mV    864.1mV    733mV
115ps     372.6mV    847mV      241.8mV
146ps     205.6mV    786.6mV    124.9mV
177ps     111.5mV    670.7mV    66.47mV
261ps     25.06mV    227.3mV    14.49mV
330ps     8.993mV    69.01mV    4.5mV
444ps     1.854mV    13.36mV    754.7uV
749ps     60.56uV    467.7uV    32.78uV
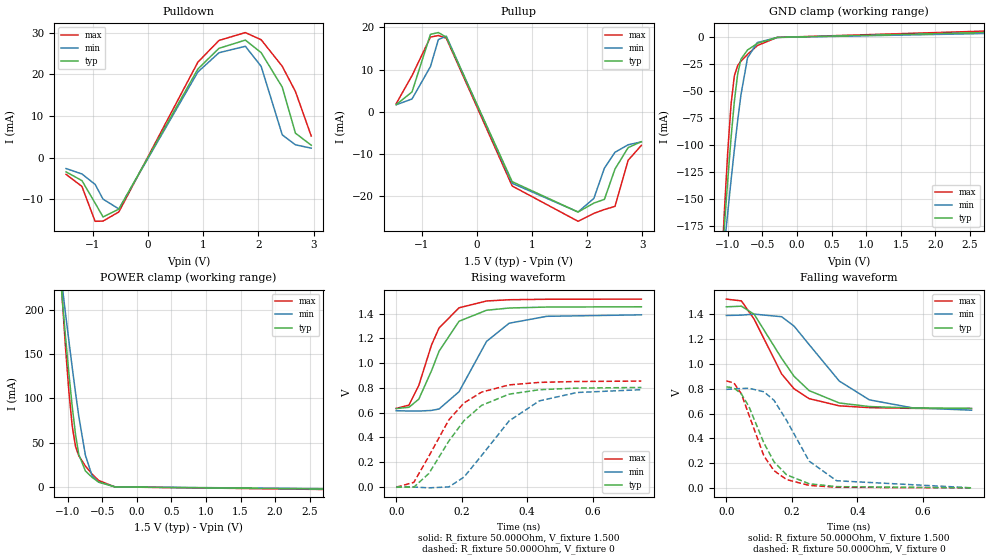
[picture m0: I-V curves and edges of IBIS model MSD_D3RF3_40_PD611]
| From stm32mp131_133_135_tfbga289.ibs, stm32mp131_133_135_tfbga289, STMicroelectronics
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[Model] MSD_D3RF3_40_PD611
Model_type   I/O
C_comp 2.432pF   2.349pF   2.555pF
Vinh = 925.000mV
Vinl = 575.000mV
Vmeas = 750.000mV
Vref = 750.000mV
[Model Spec]
Vinh   925.000mV   888.000mV   963.000mV
Vinl   575.000mV   538.000mV   613.000mV
Vmeas   750.000mV   713.000mV   788.000mV
Vref   750.000mV   713.000mV   788.000mV
[Temperature Range]   25.000   125.000   -40.000
[Voltage Range]   1.500V   1.425V   1.575V
[GND Clamp Reference]   0.00V   0.00V   0.00V
[Pulldown Reference]   0.00V   0.00V   0.00V
[POWER Clamp Reference]   1.500V   1.425V   1.575V
[Pullup Reference]   1.500V   1.425V   1.575V
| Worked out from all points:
|   slope of the pulldown table from 0 to 0.225 V, typ, clamps not added: 36.6 ohm
|   slope of the pullup table from 0 to 0.225 V, typ, clamps not added: 31.2 ohm
|   GND clamp passes 1 mA (typ) near -0.40 V on its own axis
|   POWER clamp passes 1 mA (typ) near -0.41 V on its own axis
|   rising waveform, R_fixture 50.000Ohm, V_fixture 1.500: 20-80 % time 87ps typ, 103ps min, 77.3ps max; typ from 0.633 V to 1.46 V
|   rising waveform, R_fixture 50.000Ohm, V_fixture 0: 20-80 % time 139ps typ, 155ps min, 124ps max; typ from -0.004 V to 0.803 V
|   falling waveform, R_fixture 50.000Ohm, V_fixture 1.500: 20-80 % time 129ps typ, 155ps min, 113ps max; typ from 1.46 V to 0.641 V
|   falling waveform, R_fixture 50.000Ohm, V_fixture 0: 20-80 % time 90.5ps typ, 108ps min, 78.9ps max; typ from 0.816 V to 0 V
[GND Clamp]
-1.48V    -595mA     -480.7mA   -764.6mA
-1.098V   -219mA     -223.9mA   -221.1mA
-1.05V    -174.7mA   -192.9mA   -160.5mA
-1.002V   -132.5mA   -162.5mA   -106mA
-954.6mV  -93.4mA    -132.8mA   -62.25mA
-906.8mV  -59.53mA   -104.3mA   -35.8mA
-859.1mV  -34.26mA   -77.55mA   -26.22mA
-811.4mV  -20.31mA   -53.41mA   -22.15mA
-715.9mV  -11.72mA   -18.99mA   -15.8mA
-572.7mV  -5.588mA   -4.783mA   -7.547mA
-286.4mV  -73.43uA   -123.8uA   -58.97uA
2.959V    4.881mA    3.846mA    6.279mA
[Power Clamp]
-1.459V   578.7mA    480mA      724.4mA
-1.077V   211.7mA    226mA      211.1mA
-1.03V    168.8mA    195.2mA    156.4mA
-981.8mV  128.1mA    164.8mA    107.5mA
-934.1mV  91.03mA    135.1mA    68.96mA
-886.4mV  59.5mA     106.6mA    45.8mA
-838.6mV  36.6mA     79.76mA    35.17mA
-743.2mV  18.19mA    35.82mA    23.74mA
-647.7mV  10.98mA    13.03mA    14.65mA
-552.3mV  5.626mA    5.558mA    7.412mA
-313.6mV  103.6uA    240.5uA    119.4uA
2.98V     -2.485mA   -2.084mA   -3.018mA
[Pulldown]
-1.48V    -3.4mA     -2.6mA     -4mA
-1.193V   -5.5mA     -3.9mA     -6.9mA
-954.6mV  -10.9mA    -6.4mA     -15.27mA
-811.4mV  -14.22mA   -9.94mA    -15.22mA
-525mV    -12.36mA   -12.3mA    -13.03mA
906.8mV   21.32mA    20.61mA    22.96mA
1.289V    26.28mA    25.22mA    28.17mA
1.766V    28.25mA    26.77mA    30.06mA
2.052V    25.24mA    21.95mA    28.33mA
2.434V    16.95mA    5.5mA      21.97mA
2.673V    5.9mA      3.1mA      15.9mA
2.959V    3mA        2.3mA      5.2mA
[Pullup]
-1.459V   1.7mA      1.657mA    1.929mA
-1.173V   4.7mA      3.029mA    8.571mA
-838.6mV  18.38mA    10.73mA    17.72mA
-695.5mV  18.79mA    17.13mA    18.09mA
-552.3mV  17.7mA     17.94mA    17.46mA
640.9mV   -16.59mA   -16.97mA   -17.62mA
1.834V    -23.79mA   -23.78mA   -25.99mA
2.12V     -21.67mA   -20.55mA   -24.11mA
2.311V    -20.78mA   -13.38mA   -23.19mA
2.502V    -13.6mA    -9.614mA   -22.45mA
2.741V    -8.5mA     -7.829mA   -11.5mA
2.98V     -7.1mA     -7.143mA   -7.971mA
[Ramp]
R_load=50.000Ohm
dV/dt_r   486.120mV/114.000ps  468.539mV/131.000ps  520.200mV/102.000ps
dV/dt_f   486.120mV/110.000ps  468.539mV/133.500ps  520.200mV/96.500ps
[Rising waveform]
R_fixture=50.000Ohm
V_fixture=1.500
V_fixture_min=1.425
V_fixture_max=1.575
0s        632.9mV    615.3mV    633.7mV
39ps      643.1mV    613.1mV    660.7mV
69ps      708.7mV    612.5mV    820.1mV
108ps     939.9mV    617.6mV    1.148V
131ps     1.097V     629.4mV    1.285V
192ps     1.339V     768.9mV    1.448V
276ps     1.428V     1.176V     1.503V
345ps     1.446V     1.323V     1.513V
460ps     1.454V     1.379V     1.517V
749ps     1.456V     1.391V     1.518V
[Rising waveform]
R_fixture=50.000Ohm
V_fixture=0
0s        -4.12mV    770.2uV    -3.958mV
54ps      -2.782mV   -2.133mV   36.08mV
100ps     107.9mV    -8.78mV    248mV
161ps     370.5mV    -1.137mV   542.1mV
207ps     534.5mV    78.07mV    677.7mV
261ps     658.8mV    252.9mV    766mV
345ps     749.3mV    533.1mV    824.2mV
437ps     785mV      694.5mV    844.4mV
552ps     798.4mV    762.5mV    851.7mV
749ps     803.4mV    785.6mV    855mV
[Falling waveform]
R_fixture=50.000Ohm
V_fixture=1.500
V_fixture_min=1.425
V_fixture_max=1.575
0s        1.461V     1.391V     1.523V
46ps      1.466V     1.394V     1.509V
85ps      1.401V     1.402V     1.361V
169ps     1.045V     1.381V     919.1mV
207ps     899.8mV    1.305V     799.1mV
253ps     784.6mV    1.156V     720mV
345ps     685mV      862mV      661.9mV
437ps     656.1mV    710.1mV    647.4mV
567ps     645mV      646.6mV    641.4mV
749ps     641.3mV    626.7mV    639.8mV
[Falling waveform]
R_fixture=50.000Ohm
V_fixture=0
0s        816mV      794.7mV    863.4mV
23ps      805.9mV    798.4mV    846.7mV
46ps      758.4mV    802.1mV    758.4mV
69ps      656mV      803.7mV    588.6mV
115ps     360.9mV    775.3mV    255.9mV
146ps     209.5mV    705.4mV    138.1mV
184ps     105.5mV    544.9mV    66.97mV
253ps     33.11mV    215.9mV    19.91mV
337ps     9.695mV    57.29mV    4.925mV
749ps     81.06uV    463.1uV    -10.27uV
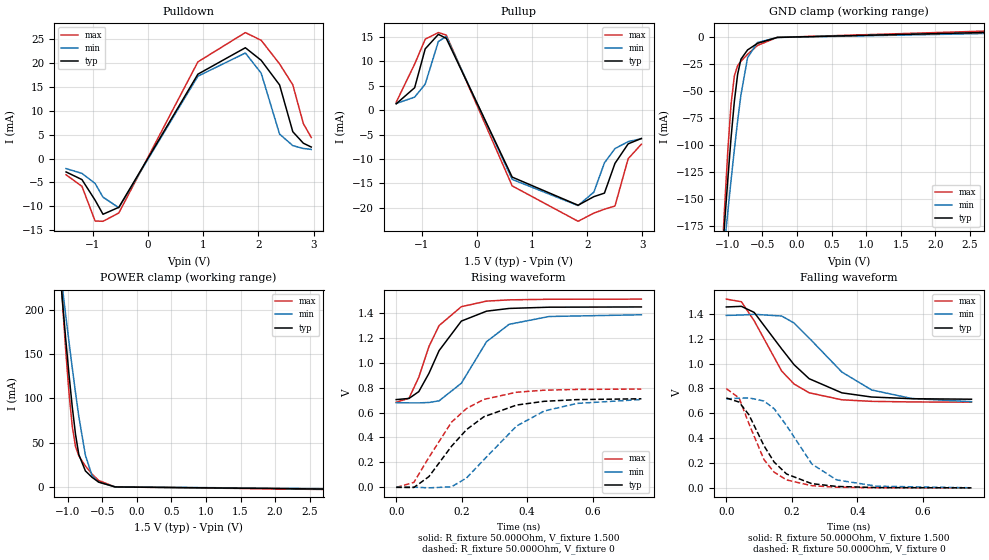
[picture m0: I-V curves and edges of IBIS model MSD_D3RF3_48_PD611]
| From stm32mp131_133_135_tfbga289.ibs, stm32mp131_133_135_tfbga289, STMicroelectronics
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[Model] MSD_D3RF3_48_PD611
Model_type   I/O
C_comp 2.432pF   2.349pF   2.555pF
Vinh = 925.000mV
Vinl = 575.000mV
Vmeas = 750.000mV
Vref = 750.000mV
[Model Spec]
Vinh   925.000mV   888.000mV   963.000mV
Vinl   575.000mV   538.000mV   613.000mV
Vmeas   750.000mV   713.000mV   788.000mV
Vref   750.000mV   713.000mV   788.000mV
[Temperature Range]   25.000   125.000   -40.000
[Voltage Range]   1.500V   1.425V   1.575V
[GND Clamp Reference]   0.00V   0.00V   0.00V
[Pulldown Reference]   0.00V   0.00V   0.00V
[POWER Clamp Reference]   1.500V   1.425V   1.575V
[Pullup Reference]   1.500V   1.425V   1.575V
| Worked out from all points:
|   slope of the pulldown table from 0 to 0.225 V, typ, clamps not added: 44.1 ohm
|   slope of the pullup table from 0 to 0.225 V, typ, clamps not added: 37.5 ohm
|   GND clamp passes 1 mA (typ) near -0.40 V on its own axis
|   POWER clamp passes 1 mA (typ) near -0.41 V on its own axis
|   rising waveform, R_fixture 50.000Ohm, V_fixture 1.500: 20-80 % time 94ps typ, 110ps min, 80ps max; typ from 0.704 V to 1.45 V
|   rising waveform, R_fixture 50.000Ohm, V_fixture 0: 20-80 % time 152ps typ, 169ps min, 131ps max; typ from -0.003 V to 0.711 V
|   falling waveform, R_fixture 50.000Ohm, V_fixture 1.500: 20-80 % time 143ps typ, 170ps min, 115ps max; typ from 1.46 V to 0.713 V
|   falling waveform, R_fixture 50.000Ohm, V_fixture 0: 20-80 % time 97.3ps typ, 115ps min, 80.7ps max; typ from 0.723 V to 0 V
[GND Clamp]
-1.48V    -595mA     -480.7mA   -764.6mA
-1.098V   -219mA     -223.9mA   -221.1mA
-1.05V    -174.7mA   -192.9mA   -160.5mA
-1.002V   -132.5mA   -162.5mA   -106mA
-954.6mV  -93.4mA    -132.8mA   -62.25mA
-906.8mV  -59.53mA   -104.3mA   -35.8mA
-859.1mV  -34.26mA   -77.55mA   -26.22mA
-811.4mV  -20.31mA   -53.41mA   -22.15mA
-715.9mV  -11.72mA   -18.99mA   -15.8mA
-572.7mV  -5.588mA   -4.783mA   -7.547mA
-286.4mV  -73.43uA   -123.8uA   -58.97uA
2.959V    4.881mA    3.846mA    6.279mA
[Power Clamp]
-1.459V   578.7mA    480mA      724.4mA
-1.077V   211.7mA    226mA      211.1mA
-1.03V    168.8mA    195.2mA    156.4mA
-981.8mV  128.1mA    164.8mA    107.5mA
-934.1mV  91.03mA    135.1mA    68.96mA
-886.4mV  59.5mA     106.6mA    45.8mA
-838.6mV  36.6mA     79.76mA    35.17mA
-743.2mV  18.19mA    35.82mA    23.74mA
-647.7mV  10.98mA    13.03mA    14.65mA
-552.3mV  5.626mA    5.558mA    7.412mA
-313.6mV  103.6uA    240.5uA    119.4uA
2.98V     -2.485mA   -2.084mA   -3.018mA
[Pulldown]
-1.48V    -2.8mA     -2.1mA     -3.4mA
-1.193V   -4.4mA     -3.1mA     -5.8mA
-954.6mV  -8.7mA     -5.2mA     -13.05mA
-811.4mV  -11.64mA   -8.07mA    -13.11mA
-525mV    -10.19mA   -10.28mA   -11.37mA
906.8mV   17.62mA    17.2mA     20.19mA
1.766V    23.14mA    22.04mA    26.31mA
2.052V    20.52mA    17.85mA    24.7mA
2.386V    15.37mA    5.1mA      19.76mA
2.625V    5.6mA      2.7mA      15.4mA
2.816V    3.2mA      2.1mA      7.3mA
2.959V    2.4mA      1.9mA      4.4mA
[Pullup]
-1.459V   1.3mA      1.357mA    1.629mA
-1.125V   4.6mA      2.671mA    9.443mA
-934.1mV  12.55mA    5.329mA    14.53mA
-695.5mV  15.52mA    14.06mA    15.89mA
-552.3mV  14.7mA     15.09mA    15.38mA
640.9mV   -13.71mA   -14.18mA   -15.51mA
1.834V    -19.47mA   -19.54mA   -22.76mA
2.12V     -17.71mA   -16.78mA   -21.08mA
2.311V    -16.99mA   -10.8mA    -20.29mA
2.502V    -10.9mA    -7.871mA   -19.63mA
2.741V    -6.9mA     -6.443mA   -9.943mA
2.98V     -5.8mA     -5.843mA   -6.971mA
[Ramp]
R_load=50.000Ohm
dV/dt_r   435.630mV/124.000ps  424.199mV/142.000ps  484.560mV/106.000ps
dV/dt_f   435.630mV/120.500ps  424.199mV/145.000ps  484.560mV/98.000ps
[Rising waveform]
R_fixture=50.000Ohm
V_fixture=1.500
V_fixture_min=1.425
V_fixture_max=1.575
0s        704.3mV    680mV      683.1mV
39ps      713.5mV    677.9mV    715mV
69ps      768.6mV    677.7mV    884.5mV
100ps     915.7mV    681mV      1.132V
131ps     1.099V     694.3mV    1.301V
199ps     1.337V     836.3mV    1.453V
276ps     1.417V     1.171V     1.498V
345ps     1.439V     1.311V     1.508V
467ps     1.449V     1.374V     1.513V
749ps     1.451V     1.388V     1.514V
[Rising waveform]
R_fixture=50.000Ohm
V_fixture=0
0s        -3.055mV   715.3uV    -3.592mV
54ps      -4.041mV   -1.561mV   37.11mV
100ps     83.83mV    -7.063mV   238.7mV
169ps     328.3mV    1.238mV    522.6mV
215ps     462.8mV    72.71mV    633mV
268ps     566.3mV    220.3mV    706mV
368ps     660.5mV    491.5mV    763.6mV
452ps     690.4mV    612.5mV    780.1mV
552ps     704.2mV    673.5mV    786.3mV
749ps     710.8mV    704.9mV    789.3mV
[Falling waveform]
R_fixture=50.000Ohm
V_fixture=1.500
V_fixture_min=1.425
V_fixture_max=1.575
0s        1.455V     1.387V     1.518V
46ps      1.46V      1.39V      1.497V
85ps      1.411V     1.396V     1.344V
169ps     1.118V     1.382V     939.8mV
207ps     990.5mV    1.326V     835.1mV
253ps     878mV      1.205V     764.6mV
353ps     764.2mV    931.3mV    708.3mV
444ps     730.6mV    787.4mV    695.8mV
567ps     717.1mV    718.4mV    691mV
749ps     712.9mV    693.3mV    689.1mV
[Falling waveform]
R_fixture=50.000Ohm
V_fixture=0
0s        723.1mV    715.2mV    798.1mV
39ps      689.9mV    721.4mV    723mV
69ps      587.6mV    723.7mV    516.5mV
115ps     338.9mV    698.6mV    227.2mV
146ps     207.6mV    636.9mV    126.3mV
184ps     111.5mV    500.7mV    63.8mV
261ps     33.7mV     192.5mV    17.47mV
337ps     11.43mV    63.92mV    5.131mV
460ps     2.202mV    13.19mV    900uV
749ps     27.94uV    560.7uV    -35.74uV
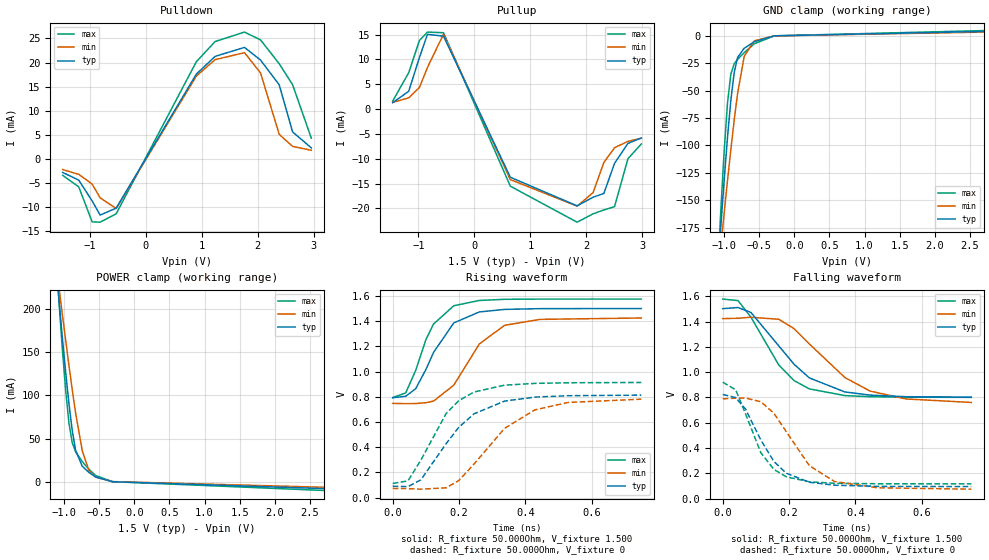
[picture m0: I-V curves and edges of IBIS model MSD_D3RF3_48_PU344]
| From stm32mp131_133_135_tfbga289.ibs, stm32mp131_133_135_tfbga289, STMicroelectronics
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[Model] MSD_D3RF3_48_PU344
Model_type   I/O
C_comp 2.329pF   2.247pF   2.450pF
Vinh = 925.000mV
Vinl = 575.000mV
Vmeas = 750.000mV
Vref = 750.000mV
[Model Spec]
Vinh   925.000mV   888.000mV   963.000mV
Vinl   575.000mV   538.000mV   613.000mV
Vmeas   750.000mV   713.000mV   788.000mV
Vref   750.000mV   713.000mV   788.000mV
[Temperature Range]   25.000   125.000   -40.000
[Voltage Range]   1.500V   1.425V   1.575V
[GND Clamp Reference]   0.00V   0.00V   0.00V
[Pulldown Reference]   0.00V   0.00V   0.00V
[POWER Clamp Reference]   1.500V   1.425V   1.575V
[Pullup Reference]   1.500V   1.425V   1.575V
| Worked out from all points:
|   slope of the pulldown table from 0 to 0.225 V, typ, clamps not added: 44.1 ohm
|   slope of the pullup table from 0 to 0.225 V, typ, clamps not added: 37.5 ohm
|   GND clamp passes 1 mA (typ) near -0.40 V on its own axis
|   POWER clamp passes 1 mA (typ) near -0.41 V on its own axis
|   rising waveform, R_fixture 50.000Ohm, V_fixture 1.500: 20-80 % time 87.7ps typ, 105ps min, 72.7ps max; typ from 0.793 V to 1.5 V
|   rising waveform, R_fixture 50.000Ohm, V_fixture 0: 20-80 % time 133ps typ, 154ps min, 112ps max; typ from 0.091 V to 0.813 V
|   falling waveform, R_fixture 50.000Ohm, V_fixture 1.500: 20-80 % time 144ps typ, 171ps min, 117ps max; typ from 1.5 V to 0.802 V
|   falling waveform, R_fixture 50.000Ohm, V_fixture 0: 20-80 % time 97.8ps typ, 116ps min, 80.2ps max; typ from 0.824 V to 0.095 V
[GND Clamp]
-1.48V    -593.8mA   -479.5mA   -763mA
-1.098V   -218.2mA   -223.3mA   -220.2mA
-1.05V    -174mA     -192.3mA   -159.6mA
-1.002V   -131.9mA   -161.9mA   -105.2mA
-954.6mV  -92.79mA   -132.2mA   -61.49mA
-906.8mV  -58.98mA   -103.9mA   -35.12mA
-859.1mV  -33.77mA   -77.12mA   -25.6mA
-811.4mV  -19.87mA   -53.03mA   -21.59mA
-715.9mV  -11.38mA   -18.7mA    -15.38mA
-572.7mV  -5.4mA     -4.611mA   -7.303mA
-286.4mV  -62.82uA   -108.6uA   -50.82uA
2.959V    4.272mA    3.643mA    5.154mA
[Power Clamp]
-1.459V   577.6mA    479.2mA    722.9mA
-1.077V   211mA      225.5mA    210.3mA
-1.03V    168.2mA    194.7mA    155.6mA
-981.8mV  127.5mA    164.3mA    106.7mA
-934.1mV  90.5mA     134.7mA    68.26mA
-886.4mV  59.02mA    106.2mA    45.17mA
-838.6mV  36.17mA    79.41mA    34.61mA
-743.2mV  17.86mA    35.55mA    23.3mA
-647.7mV  10.74mA    12.84mA    14.33mA
-552.3mV  5.478mA    5.433mA    7.218mA
-313.6mV  101.8uA    235.2uA    114.2uA
2.98V     -8.607mA   -6.939mA   -10.98mA
[Pulldown]
-1.48V    -2.8mA     -2.2mA     -3.4mA
-1.193V   -4.4mA     -3.2mA     -5.8mA
-954.6mV  -8.71mA    -5.2mA     -13.05mA
-811.4mV  -11.64mA   -8.07mA    -13.12mA
-525mV    -10.2mA    -10.28mA   -11.37mA
906.8mV   17.61mA    17.2mA     20.18mA
1.241V    21.28mA    20.6mA     24.36mA
1.766V    23.14mA    22.05mA    26.32mA
2.052V    20.52mA    17.85mA    24.7mA
2.386V    15.37mA    5.1mA      19.75mA
2.625V    5.6mA      2.6mA      15.4mA
2.959V    2.3mA      1.8mA      4.3mA
[Pullup]
-1.459V   1.3mA      1.357mA    1.629mA
-1.173V   3.6mA      2.271mA    7.343mA
-981.8mV  10.4mA     4.357mA    13.82mA
-838.6mV  15.06mA    8.386mA    15.51mA
-552.3mV  14.69mA    15.09mA    15.38mA
640.9mV   -13.71mA   -14.18mA   -15.51mA
1.834V    -19.47mA   -19.54mA   -22.76mA
2.12V     -17.72mA   -16.78mA   -21.07mA
2.311V    -16.98mA   -10.74mA   -20.3mA
2.502V    -10.9mA    -7.771mA   -19.63mA
2.741V    -6.9mA     -6.486mA   -9.986mA
2.98V     -5.8mA     -5.857mA   -7.014mA
[Ramp]
R_load=50.000Ohm
dV/dt_r   425.874mV/111.500ps  414.456mV/131.000ps  471.540mV/93.000ps
dV/dt_f   425.874mV/121.500ps  414.426mV/146.500ps  471.540mV/99.500ps
[Rising waveform]
R_fixture=50.000Ohm
V_fixture=1.500
V_fixture_min=1.425
V_fixture_max=1.575
0s        792.7mV    747.9mV    794.4mV
39ps      804.2mV    745.9mV    830.4mV
69ps      863.8mV    746.7mV    1.008V
100ps     1.016V     753.3mV    1.253V
123ps     1.152V     766.1mV    1.377V
184ps     1.386V     892.3mV    1.522V
261ps     1.473V     1.219V     1.564V
337ps     1.493V     1.367V     1.573V
444ps     1.499V     1.414V     1.575V
749ps     1.5V       1.425V     1.575V
[Rising waveform]
R_fixture=50.000Ohm
V_fixture=0
0s        91.28mV    73.83mV    112.9mV
46ps      87.95mV    71.72mV    133.8mV
85ps      142.4mV    67.83mV    298.9mV
161ps     429.1mV    78.4mV     667.7mV
199ps     558.1mV    136.2mV    769.4mV
245ps     665.1mV    266.6mV    838.2mV
337ps     766mV      550.1mV    892.3mV
429ps     797.9mV    697.2mV    906.5mV
529ps     808.7mV    755.5mV    911.4mV
749ps     813.4mV    781.2mV    913.8mV
[Falling waveform]
R_fixture=50.000Ohm
V_fixture=1.500
V_fixture_min=1.425
V_fixture_max=1.575
0s        1.503V     1.424V     1.579V
46ps      1.512V     1.427V     1.567V
85ps      1.473V     1.435V     1.436V
169ps     1.208V     1.419V     1.057V
215ps     1.063V     1.345V     933.6mV
261ps     954.9mV    1.224V     868.1mV
368ps     843.8mV    957.9mV    814.9mV
444ps     818.7mV    850.6mV    805.9mV
552ps     806.1mV    788.3mV    802.2mV
749ps     801.5mV    760.6mV    801.1mV
[Falling waveform]
R_fixture=50.000Ohm
V_fixture=0
0s        823.9mV    789mV      921mV
39ps      799.3mV    794.6mV    861.2mV
69ps      706.7mV    796mV      668.8mV
115ps     462.8mV    766.1mV    362.2mV
154ps     293.8mV    676.2mV    230.4mV
192ps     199.8mV    527.3mV    171.7mV
261ps     128.8mV    260.3mV    132.5mV
337ps     105.6mV    134.6mV    120.7mV
467ps     96.24mV    84.96mV    117mV
749ps     94.58mV    74.18mV    116.5mV
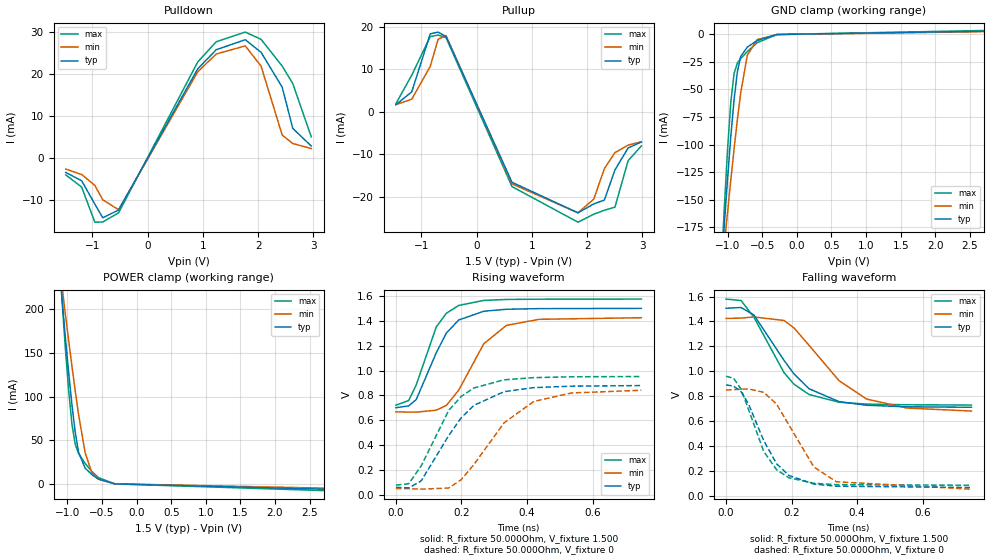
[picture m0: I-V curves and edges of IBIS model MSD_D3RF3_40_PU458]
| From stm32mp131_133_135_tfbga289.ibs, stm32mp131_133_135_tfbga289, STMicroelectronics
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[Model] MSD_D3RF3_40_PU458
Model_type   I/O
C_comp 2.387pF   2.305pF   2.510pF
Vinh = 925.000mV
Vinl = 575.000mV
Vmeas = 750.000mV
Vref = 750.000mV
[Model Spec]
Vinh   925.000mV   888.000mV   963.000mV
Vinl   575.000mV   538.000mV   613.000mV
Vmeas   750.000mV   713.000mV   788.000mV
Vref   750.000mV   713.000mV   788.000mV
[Temperature Range]   25.000   125.000   -40.000
[Voltage Range]   1.500V   1.425V   1.575V
[GND Clamp Reference]   0.00V   0.00V   0.00V
[Pulldown Reference]   0.00V   0.00V   0.00V
[POWER Clamp Reference]   1.500V   1.425V   1.575V
[Pullup Reference]   1.500V   1.425V   1.575V
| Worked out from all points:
|   slope of the pulldown table from 0 to 0.225 V, typ, clamps not added: 36.6 ohm
|   slope of the pullup table from 0 to 0.225 V, typ, clamps not added: 31.2 ohm
|   GND clamp passes 1 mA (typ) near -0.40 V on its own axis
|   POWER clamp passes 1 mA (typ) near -0.41 V on its own axis
|   rising waveform, R_fixture 50.000Ohm, V_fixture 1.500: 20-80 % time 83.3ps typ, 100ps min, 72.8ps max; typ from 0.701 V to 1.5 V
|   rising waveform, R_fixture 50.000Ohm, V_fixture 0: 20-80 % time 128ps typ, 146ps min, 112ps max; typ from 0.06 V to 0.879 V
|   falling waveform, R_fixture 50.000Ohm, V_fixture 1.500: 20-80 % time 133ps typ, 158ps min, 116ps max; typ from 1.51 V to 0.71 V
|   falling waveform, R_fixture 50.000Ohm, V_fixture 0: 20-80 % time 91.9ps typ, 109ps min, 80.4ps max; typ from 0.89 V to 0.065 V
[GND Clamp]
-1.48V    -594.4mA   -480.1mA   -764mA
-1.098V   -218.6mA   -223.6mA   -220.7mA
-1.05V    -174.5mA   -192.7mA   -160.1mA
-1.002V   -132.2mA   -162.2mA   -105.7mA
-954.6mV  -93.12mA   -132.5mA   -61.92mA
-906.8mV  -59.28mA   -104.1mA   -35.5mA
-859.1mV  -34.03mA   -77.35mA   -25.95mA
-811.4mV  -20.11mA   -53.24mA   -21.91mA
-715.9mV  -11.56mA   -18.86mA   -15.62mA
-572.7mV  -5.498mA   -4.705mA   -7.443mA
-286.4mV  -67.01uA   -116.4uA   -54.62uA
2.959V    3.204mA    2.733mA    3.866mA
[Power Clamp]
-1.459V   578.3mA    479.7mA    723.8mA
-1.077V   211.4mA    225.9mA    210.8mA
-1.03V    168.5mA    195mA      156.1mA
-981.8mV  127.9mA    164.6mA    107.2mA
-934.1mV  90.82mA    134.9mA    68.67mA
-886.4mV  59.31mA    106.4mA    45.54mA
-838.6mV  36.44mA    79.64mA    34.94mA
-743.2mV  18.07mA    35.72mA    23.56mA
-647.7mV  10.89mA    12.97mA    14.52mA
-552.3mV  5.57mA     5.518mA    7.336mA
-313.6mV  106.2uA    243.6uA    119.9uA
2.98V     -6.459mA   -5.197mA   -8.237mA
[Pulldown]
-1.48V    -3.4mA     -2.6mA     -4mA
-1.193V   -5.4mA     -3.9mA     -6.9mA
-954.6mV  -10.95mA   -6.5mA     -15.27mA
-811.4mV  -14.22mA   -9.94mA    -15.22mA
-525mV    -12.36mA   -12.3mA    -13.03mA
906.8mV   21.31mA    20.61mA    22.95mA
1.241V    25.87mA    24.84mA    27.77mA
1.766V    28.25mA    26.78mA    30.07mA
2.052V    25.24mA    21.95mA    28.34mA
2.434V    16.93mA    5.5mA      21.96mA
2.625V    7.1mA      3.5mA      17.8mA
2.959V    2.9mA      2.3mA      5.1mA
[Pullup]
-1.459V   1.7mA      1.714mA    1.929mA
-1.173V   4.7mA      2.971mA    8.628mA
-838.6mV  18.38mA    10.71mA    17.72mA
-695.5mV  18.79mA    17.12mA    18.09mA
-552.3mV  17.71mA    17.94mA    17.47mA
640.9mV   -16.59mA   -16.97mA   -17.61mA
1.834V    -23.79mA   -23.78mA   -25.99mA
2.12V     -21.68mA   -20.55mA   -24.11mA
2.311V    -20.78mA   -13.39mA   -23.18mA
2.502V    -13.7mA    -9.614mA   -22.45mA
2.741V    -8.5mA     -7.829mA   -11.5mA
2.98V     -7.1mA     -7.043mA   -8.029mA
[Ramp]
R_load=50.000Ohm
dV/dt_r   481.770mV/106.500ps  463.491mV/124.500ps  515.043mV/93.000ps
dV/dt_f   481.770mV/112.500ps  463.491mV/135.500ps  515.043mV/99.000ps
[Rising waveform]
R_fixture=50.000Ohm
V_fixture=1.500
V_fixture_min=1.425
V_fixture_max=1.575
0s        700.8mV    667.7mV    721mV
39ps      715.5mV    665.5mV    758.7mV
62ps      766.3mV    665.2mV    884.5mV
123ps     1.142V     680.9mV    1.35V
154ps     1.302V     719.5mV    1.461V
192ps     1.407V     844mV      1.524V
268ps     1.477V     1.215V     1.564V
337ps     1.493V     1.363V     1.572V
437ps     1.498V     1.412V     1.574V
749ps     1.5V       1.425V     1.575V
[Rising waveform]
R_fixture=50.000Ohm
V_fixture=0
0s        60.41mV    51.32mV    78.23mV
39ps      56.01mV    49.54mV    89.15mV
77ps      111.8mV    45.51mV    232.1mV
161ps     476.4mV    54.89mV    678.7mV
199ps     619.1mV    121.2mV    791.2mV
238ps     720mV      243.8mV    860mV
330ps     830mV      579.2mV    925.2mV
421ps     862.6mV    751.6mV    942.8mV
536ps     874.2mV    819.5mV    949.7mV
749ps     879mV      841.2mV    951.8mV
[Falling waveform]
R_fixture=50.000Ohm
V_fixture=1.500
V_fixture_min=1.425
V_fixture_max=1.575
0s        1.506V     1.424V     1.58V
46ps      1.512V     1.427V     1.568V
85ps      1.452V     1.436V     1.434V
177ps     1.087V     1.408V     988.2mV
207ps     979.2mV    1.349V     896.2mV
253ps     859.3mV    1.209V     812.9mV
345ps     755.1mV    923.3mV    750.5mV
429ps     726.1mV    775.9mV    735.4mV
552ps     713.7mV    703.7mV    729.9mV
749ps     710mV      679.5mV    727.8mV
[Falling waveform]
R_fixture=50.000Ohm
V_fixture=0
0s        890mV      848.4mV    959.4mV
23ps      880mV      851.8mV    943.5mV
46ps      834.7mV    855.4mV    855.7mV
69ps      734.1mV    857mV      689.7mV
115ps     441.6mV    830.3mV    354.2mV
154ps     256.7mV    735.8mV    208.1mV
192ps     161.6mV    566.5mV    143.2mV
268ps     92.42mV    229.6mV    98.69mV
337ps     75.06mV    110.8mV    87.73mV
749ps     65.17mV    51.44mV    82.83mV
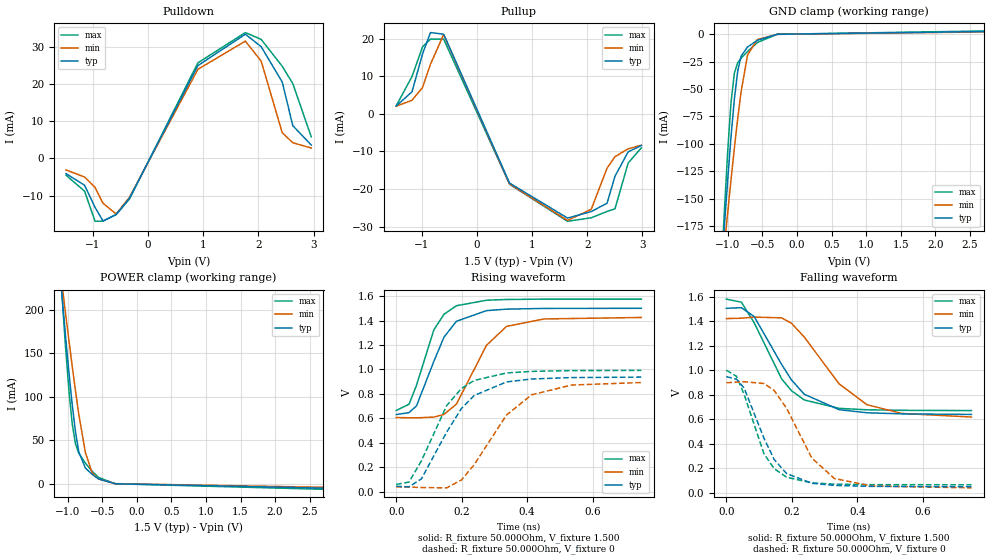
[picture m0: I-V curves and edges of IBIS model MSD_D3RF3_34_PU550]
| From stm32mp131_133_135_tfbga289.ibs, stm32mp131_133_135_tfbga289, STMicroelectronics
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[Model] MSD_D3RF3_34_PU550
Model_type   I/O
C_comp 2.417pF   2.334pF   2.540pF
Vinh = 925.000mV
Vinl = 575.000mV
Vmeas = 750.000mV
Vref = 750.000mV
[Model Spec]
Vinh   925.000mV   888.000mV   963.000mV
Vinl   575.000mV   538.000mV   613.000mV
Vmeas   750.000mV   713.000mV   788.000mV
Vref   750.000mV   713.000mV   788.000mV
[Temperature Range]   25.000   125.000   -40.000
[Voltage Range]   1.500V   1.425V   1.575V
[GND Clamp Reference]   0.00V   0.00V   0.00V
[Pulldown Reference]   0.00V   0.00V   0.00V
[POWER Clamp Reference]   1.500V   1.425V   1.575V
[Pullup Reference]   1.500V   1.425V   1.575V
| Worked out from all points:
|   slope of the pulldown table from 0 to 0.225 V, typ, clamps not added: 31.5 ohm
|   slope of the pullup table from 0 to 0.225 V, typ, clamps not added: 26.9 ohm
|   GND clamp passes 1 mA (typ) near -0.40 V on its own axis
|   POWER clamp passes 1 mA (typ) near -0.41 V on its own axis
|   rising waveform, R_fixture 50.000Ohm, V_fixture 1.500: 20-80 % time 79.3ps typ, 96.8ps min, 70ps max; typ from 0.631 V to 1.5 V
|   rising waveform, R_fixture 50.000Ohm, V_fixture 0: 20-80 % time 121ps typ, 137ps min, 108ps max; typ from 0.044 V to 0.938 V
|   falling waveform, R_fixture 50.000Ohm, V_fixture 1.500: 20-80 % time 123ps typ, 149ps min, 109ps max; typ from 1.51 V to 0.64 V
|   falling waveform, R_fixture 50.000Ohm, V_fixture 0: 20-80 % time 87ps typ, 106ps min, 76.4ps max; typ from 0.949 V to 0.05 V
[GND Clamp]
-1.48V    -594.8mA   -480.5mA   -764.4mA
-1.098V   -218.8mA   -223.8mA   -221mA
-1.05V    -174.6mA   -192.8mA   -160.3mA
-1.002V   -132.4mA   -162.4mA   -105.9mA
-954.6mV  -93.29mA   -132.7mA   -62.13mA
-906.8mV  -59.43mA   -104.2mA   -35.7mA
-859.1mV  -34.17mA   -77.46mA   -26.12mA
-811.4mV  -20.23mA   -53.34mA   -22.06mA
-715.9mV  -11.65mA   -18.94mA   -15.73mA
-572.7mV  -5.552mA   -4.746mA   -7.503mA
-286.4mV  -69.21uA   -117uA     -55.41uA
2.959V    2.671mA    2.278mA    3.222mA
[Power Clamp]
-1.459V   578.6mA    480mA      724.3mA
-1.077V   211.6mA    226mA      211.1mA
-1.03V    168.7mA    195.2mA    156.3mA
-981.8mV  128.1mA    164.8mA    107.4mA
-934.1mV  90.98mA    135.1mA    68.88mA
-886.4mV  59.46mA    106.6mA    45.73mA
-838.6mV  36.57mA    79.76mA    35.11mA
-743.2mV  18.16mA    35.82mA    23.68mA
-647.7mV  10.96mA    13.03mA    14.61mA
-552.3mV  5.616mA    5.561mA    7.395mA
-313.6mV  108.4uA    247.8uA    122.3uA
2.98V     -5.382mA   -4.337mA   -6.867mA
[Pulldown]
-1.48V    -4.1mA     -3.1mA     -4.5mA
-1.145V   -7.2mA     -5mA       -8.8mA
-954.6mV  -13.17mA   -7.8mA     -16.88mA
-811.4mV  -16.78mA   -12.04mA   -16.85mA
-572.7mV  -15.07mA   -14.91mA   -15.04mA
-334.1mV  -10.73mA   -10.48mA   -10.94mA
906.8mV   24.92mA    23.93mA    25.67mA
1.766V    33.35mA    31.49mA    33.79mA
2.052V    30.01mA    26.14mA    31.97mA
2.434V    20.51mA    6.9mA      24.73mA
2.625V    8.8mA      4.2mA      20.1mA
2.959V    3.6mA      2.8mA      5.8mA
[Pullup]
-1.459V   2.1mA      2.057mA    2.171mA
-1.173V   5.9mA      3.629mA    9.943mA
-981.8mV  16mA       7.043mA    17.88mA
-838.6mV  21.66mA    13.24mA    19.92mA
-600mV    21.23mA    21.13mA    19.92mA
593.2mV   -18.41mA   -18.64mA   -18.71mA
1.643V    -27.73mA   -28.34mA   -28.59mA
2.073V    -26mA      -25.39mA   -27.65mA
2.359V    -23.77mA   -14.44mA   -25.96mA
2.502V    -16.6mA    -11.4mA    -25.27mA
2.741V    -10.1mA    -9.286mA   -13.06mA
2.98V     -8.4mA     -8.343mA   -9.029mA
[Ramp]
R_load=50.000Ohm
dV/dt_r   524.580mV/100.000ps  500.970mV/117.500ps  549.297mV/89.500ps
dV/dt_f   524.580mV/105.500ps  500.970mV/130.000ps  549.297mV/93.000ps
[Rising waveform]
R_fixture=50.000Ohm
V_fixture=1.500
V_fixture_min=1.425
V_fixture_max=1.575
0s        631mV      607.1mV    664.4mV
39ps      646.7mV    604.8mV    715.1mV
62ps      701.9mV    604.1mV    870.6mV
115ps     1.066V     610.3mV    1.324V
146ps     1.264V     632.2mV    1.451V
184ps     1.394V     716.7mV    1.521V
276ps     1.481V     1.198V     1.566V
337ps     1.493V     1.352V     1.572V
452ps     1.499V     1.413V     1.575V
749ps     1.5V       1.425V     1.575V
[Rising waveform]
R_fixture=50.000Ohm
V_fixture=0
0s        44.4mV     39.89mV    59.41mV
39ps      40.14mV    38.29mV    78.93mV
77ps      105.6mV    34.36mV    252.3mV
154ps     486.6mV    31.63mV    703.7mV
199ps     679.8mV    95.55mV    843.1mV
238ps     786.5mV    220.2mV    909.8mV
337ps     898mV      627.6mV    971.3mV
414ps     921.9mV    793mV      984mV
536ps     933.5mV    872.5mV    990.7mV
749ps     937.5mV    893.2mV    992.2mV
[Falling waveform]
R_fixture=50.000Ohm
V_fixture=1.500
V_fixture_min=1.425
V_fixture_max=1.575
0s        1.507V     1.423V     1.582V
46ps      1.512V     1.426V     1.557V
85ps      1.44V      1.435V     1.389V
169ps     1.048V     1.429V     930.1mV
199ps     921.7mV    1.385V     833.7mV
238ps     804.9mV    1.272V     758.2mV
345ps     678.3mV    888.8mV    689.3mV
429ps     653.6mV    719.9mV    677.9mV
536ps     644.3mV    648mV      673.4mV
749ps     639.9mV    618.4mV    671.3mV
[Falling waveform]
R_fixture=50.000Ohm
V_fixture=0
0s        948.8mV    899mV      1.001V
31ps      928.1mV    903.5mV    951.6mV
54ps      857.6mV    907.2mV    806.8mV
115ps     445.3mV    892.5mV    318.4mV
146ps     272.6mV    836mV      197.5mV
184ps     156.8mV    690.6mV    126.8mV
261ps     77.6mV     283.6mV    80.74mV
330ps     59.95mV    116.5mV    70.02mV
444ps     52.05mV    54.84mV    65.99mV
749ps     50.05mV    39.86mV    65.24mV
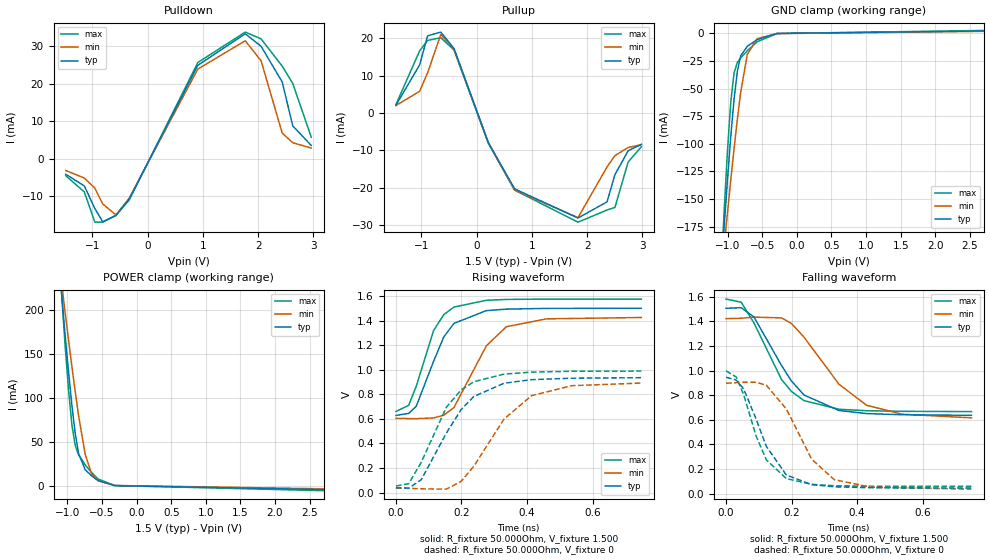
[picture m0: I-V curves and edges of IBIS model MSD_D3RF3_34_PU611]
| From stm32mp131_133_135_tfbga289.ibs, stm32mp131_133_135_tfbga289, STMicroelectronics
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[Model] MSD_D3RF3_34_PU611
Model_type   I/O
C_comp 2.434pF   2.351pF   2.557pF
Vinh = 925.000mV
Vinl = 575.000mV
Vmeas = 750.000mV
Vref = 750.000mV
[Model Spec]
Vinh   925.000mV   888.000mV   963.000mV
Vinl   575.000mV   538.000mV   613.000mV
Vmeas   750.000mV   713.000mV   788.000mV
Vref   750.000mV   713.000mV   788.000mV
[Temperature Range]   25.000   125.000   -40.000
[Voltage Range]   1.500V   1.425V   1.575V
[GND Clamp Reference]   0.00V   0.00V   0.00V
[Pulldown Reference]   0.00V   0.00V   0.00V
[POWER Clamp Reference]   1.500V   1.425V   1.575V
[Pullup Reference]   1.500V   1.425V   1.575V
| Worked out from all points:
|   slope of the pulldown table from 0 to 0.225 V, typ, clamps not added: 31.5 ohm
|   slope of the pullup table from 0 to 0.225 V, typ, clamps not added: 26.9 ohm
|   GND clamp passes 1 mA (typ) near -0.40 V on its own axis
|   POWER clamp passes 1 mA (typ) near -0.41 V on its own axis
|   rising waveform, R_fixture 50.000Ohm, V_fixture 1.500: 20-80 % time 79.6ps typ, 97.2ps min, 70.6ps max; typ from 0.628 V to 1.5 V
|   rising waveform, R_fixture 50.000Ohm, V_fixture 0: 20-80 % time 122ps typ, 138ps min, 109ps max; typ from 0.039 V to 0.935 V
|   falling waveform, R_fixture 50.000Ohm, V_fixture 1.500: 20-80 % time 124ps typ, 150ps min, 109ps max; typ from 1.51 V to 0.637 V
|   falling waveform, R_fixture 50.000Ohm, V_fixture 0: 20-80 % time 87.1ps typ, 106ps min, 76.8ps max; typ from 0.946 V to 0.045 V
[GND Clamp]
-1.48V    -595mA     -480.6mA   -764.6mA
-1.098V   -218.9mA   -223.9mA   -221.2mA
-1.05V    -174.8mA   -192.9mA   -160.5mA
-1.002V   -132.5mA   -162.4mA   -106.1mA
-954.6mV  -93.38mA   -132.8mA   -62.24mA
-906.8mV  -59.5mA    -104.2mA   -35.79mA
-859.1mV  -34.24mA   -77.51mA   -26.21mA
-811.4mV  -20.29mA   -53.38mA   -22.14mA
-715.9mV  -11.7mA    -18.98mA   -15.79mA
-572.7mV  -5.58mA    -4.768mA   -7.539mA
-286.4mV  -69.81uA   -117.8uA   -56.41uA
2.959V    2.404mA    2.05mA     2.9mA
[Power Clamp]
-1.459V   578.8mA    480.2mA    724.4mA
-1.077V   211.7mA    226.1mA    211.2mA
-1.03V    168.8mA    195.2mA    156.4mA
-981.8mV  128.2mA    164.8mA    107.5mA
-934.1mV  91.06mA    135.1mA    68.98mA
-886.4mV  59.53mA    106.6mA    45.83mA
-838.6mV  36.63mA    79.81mA    35.19mA
-743.2mV  18.22mA    35.86mA    23.75mA
-647.7mV  11mA       13.06mA    14.65mA
-552.3mV  5.639mA    5.582mA    7.423mA
-313.6mV  109.4uA    249.9uA    123.7uA
2.98V     -4.843mA   -3.907mA   -6.18mA
[Pulldown]
-1.48V    -4.1mA     -3.1mA     -4.5mA
-1.145V   -7.2mA     -5.1mA     -8.8mA
-954.6mV  -13.23mA   -7.8mA     -16.87mA
-811.4mV  -16.78mA   -12.04mA   -16.85mA
-572.7mV  -15.06mA   -14.9mA    -15.04mA
-334.1mV  -10.73mA   -10.49mA   -10.95mA
906.8mV   24.93mA    23.93mA    25.68mA
1.766V    33.34mA    31.49mA    33.8mA
2.052V    30.02mA    26.15mA    31.98mA
2.434V    20.5mA     6.9mA      24.73mA
2.625V    8.8mA      4.3mA      20.1mA
2.959V    3.6mA      2.9mA      5.8mA
[Pullup]
-1.459V   2.1mA      2.014mA    2.271mA
-1.03V    12.9mA     5.828mA    16.66mA
-886.4mV  20.67mA    10.77mA    19.45mA
-647.7mV  21.68mA    21.03mA    20.18mA
-409.1mV  17.29mA    17.18mA    16.91mA
211.4mV   -7.901mA   -7.87mA    -8.056mA
688.6mV   -20.3mA    -20.62mA   -20.64mA
1.834V    -28.1mA    -28.01mA   -29.22mA
2.359V    -23.78mA   -14.44mA   -25.96mA
2.502V    -16.5mA    -11.4mA    -25.27mA
2.741V    -10.1mA    -9.229mA   -13.11mA
2.98V     -8.4mA     -8.443mA   -9.029mA
[Ramp]
R_load=50.000Ohm
dV/dt_r   526.341mV/101.500ps  502.392mV/119.000ps  551.580mV/90.500ps
dV/dt_f   526.341mV/106.000ps  502.392mV/130.500ps  551.580mV/94.000ps
[Rising waveform]
R_fixture=50.000Ohm
V_fixture=1.500
V_fixture_min=1.425
V_fixture_max=1.575
0s        627.7mV    604.5mV    660mV
39ps      644.6mV    602.2mV    710.3mV
62ps      702.2mV    601.5mV    865.3mV
115ps     1.069V     607.6mV    1.319V
146ps     1.266V     629.4mV    1.448V
177ps     1.377V     691.5mV    1.51V
276ps     1.481V     1.195V     1.565V
337ps     1.493V     1.35V      1.572V
460ps     1.499V     1.414V     1.575V
749ps     1.5V       1.425V     1.575V
[Rising waveform]
R_fixture=50.000Ohm
V_fixture=0
0s        39.31mV    36.08mV    53.1mV
39ps      35.66mV    34.47mV    72.42mV
77ps      103.5mV    30.53mV    245mV
154ps     484.4mV    27.6mV     694.8mV
199ps     675.8mV    91.2mV     836mV
238ps     782.4mV    215.3mV    902.3mV
330ps     890mV      598.9mV    964.2mV
414ps     918.9mV    788.8mV    980.1mV
536ps     930.8mV    869.8mV    987.3mV
749ps     935.1mV    891.3mV    989.1mV
[Falling waveform]
R_fixture=50.000Ohm
V_fixture=1.500
V_fixture_min=1.425
V_fixture_max=1.575
0s        1.507V     1.423V     1.582V
46ps      1.512V     1.426V     1.557V
85ps      1.437V     1.435V     1.389V
169ps     1.043V     1.429V     929.1mV
199ps     917.4mV    1.385V     832.1mV
238ps     801.5mV    1.272V     756mV
345ps     675.6mV    888.3mV    685.8mV
429ps     650.7mV    718.7mV    673.9mV
536ps     641.2mV    646.1mV    669.1mV
749ps     636.6mV    616mV      666.9mV
[Falling waveform]
R_fixture=50.000Ohm
V_fixture=0
0s        946.4mV    897.3mV    997.8mV
31ps      923.4mV    901.8mV    948.2mV
54ps      850.5mV    905.5mV    803mV
92ps      604.8mV    905.2mV    466.3mV
123ps     383.7mV    881.1mV    274.5mV
184ps     151.3mV    688.2mV    122.1mV
261ps     73.18mV    280.8mV    75.18mV
330ps     55.42mV    113.6mV    64.05mV
444ps     47.31mV    51.46mV    59.77mV
749ps     45.2mV     36.06mV    58.93mV
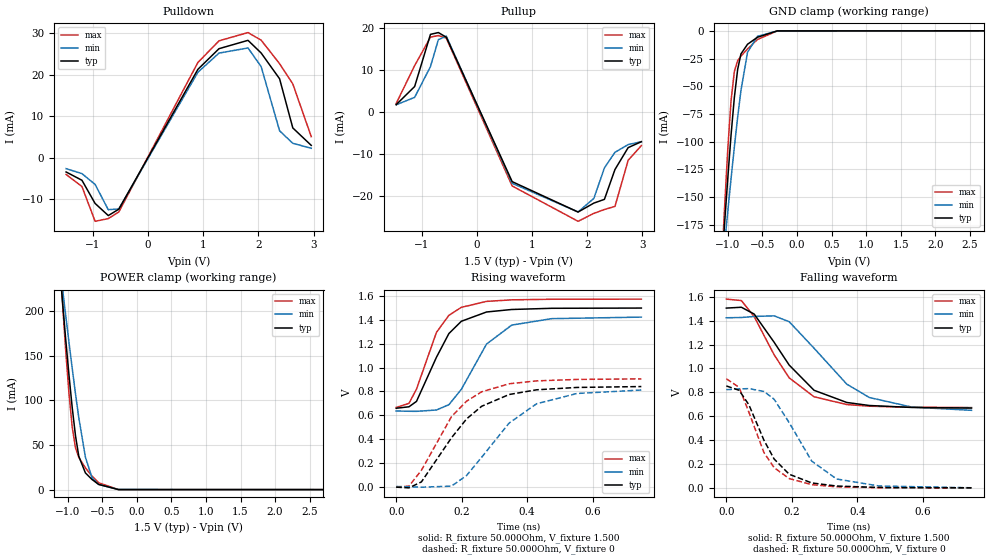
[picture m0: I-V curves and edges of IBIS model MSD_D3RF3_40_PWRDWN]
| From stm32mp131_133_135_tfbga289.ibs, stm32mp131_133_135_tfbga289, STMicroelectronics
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[Model] MSD_D3RF3_40_PWRDWN
Model_type   I/O
C_comp 2.564pF   2.479pF   2.689pF
Vinh = 925.000mV
Vinl = 575.000mV
Vmeas = 750.000mV
Vref = 750.000mV
[Model Spec]
Vinh   925.000mV   888.000mV   963.000mV
Vinl   575.000mV   538.000mV   613.000mV
Vmeas   750.000mV   713.000mV   788.000mV
Vref   750.000mV   713.000mV   788.000mV
[Temperature Range]   25.000   125.000   -40.000
[Voltage Range]   1.500V   1.425V   1.575V
[GND Clamp Reference]   0.00V   0.00V   0.00V
[Pulldown Reference]   0.00V   0.00V   0.00V
[POWER Clamp Reference]   1.500V   1.425V   1.575V
[Pullup Reference]   1.500V   1.425V   1.575V
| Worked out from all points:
|   slope of the pulldown table from 0 to 0.225 V, typ, clamps not added: 36.6 ohm
|   slope of the pullup table from 0 to 0.225 V, typ, clamps not added: 31.2 ohm
|   GND clamp passes 1 mA (typ) near -0.40 V on its own axis
|   POWER clamp passes 1 mA (typ) near -0.41 V on its own axis
|   rising waveform, R_fixture 50.000Ohm, V_fixture 1.500: 20-80 % time 89.4ps typ, 105ps min, 80ps max; typ from 0.659 V to 1.5 V
|   rising waveform, R_fixture 50.000Ohm, V_fixture 0: 20-80 % time 146ps typ, 160ps min, 132ps max; typ from -0.004 V to 0.841 V
|   falling waveform, R_fixture 50.000Ohm, V_fixture 1.500: 20-80 % time 140ps typ, 164ps min, 124ps max; typ from 1.5 V to 0.668 V
|   falling waveform, R_fixture 50.000Ohm, V_fixture 0: 20-80 % time 96.2ps typ, 113ps min, 85.2ps max; typ from 0.853 V to 0 V
[GND Clamp]
-1.48V    -596.5mA   -481.9mA   -766.5mA
-1.098V   -219.9mA   -224.7mA   -222.4mA
-1.05V    -175.6mA   -193.6mA   -161.6mA
-1.002V   -133.3mA   -163.1mA   -107mA
-954.6mV  -94.12mA   -133.4mA   -63.19mA
-906.8mV  -60.18mA   -104.9mA   -36.66mA
-859.1mV  -34.85mA   -78.03mA   -27mA
-811.4mV  -20.84mA   -53.84mA   -22.84mA
-715.9mV  -12.12mA   -19.32mA   -16.33mA
-572.7mV  -5.815mA   -4.971mA   -7.847mA
-286.4mV  -79.35uA   -131.3uA   -65.66uA
2.959V    34.12nA    533.7nA    4.576nA
[Power Clamp]
-1.459V   580.3mA    481.5mA    726.4mA
-1.077V   212.7mA    226.9mA    212.4mA
-1.03V    169.7mA    196mA      157.5mA
-981.8mV  129mA      165.5mA    108.5mA
-934.1mV  91.79mA    135.8mA    69.91mA
-886.4mV  60.19mA    107.2mA    46.67mA
-838.6mV  37.22mA    80.32mA    35.95mA
-743.2mV  18.67mA    36.26mA    24.33mA
-647.7mV  11.33mA    13.35mA    15.07mA
-552.3mV  5.847mA    5.773mA    7.686mA
-265.9mV  29.71uA    98.64uA    29.06uA
2.98V     -53.11nA   -976.3nA   -5.314nA
[Pulldown]
-1.48V    -3.4mA     -2.6mA     -4mA
-1.193V   -5.4mA     -3.8mA     -6.9mA
-954.6mV  -10.98mA   -6.4mA     -15.28mA
-715.9mV  -13.9mA    -12.49mA   -14.63mA
-525mV    -12.36mA   -12.3mA    -13.03mA
906.8mV   21.31mA    20.61mA    22.96mA
1.289V    26.28mA    25.22mA    28.17mA
1.814V    28.29mA    26.45mA    30.16mA
2.052V    25.24mA    21.96mA    28.33mA
2.386V    19.03mA    6.5mA      22.66mA
2.625V    7.2mA      3.5mA      17.8mA
2.959V    3mA        2.3mA      5.1mA
[Pullup]
-1.459V   1.7mA      1.657mA    1.971mA
-1.125V   6mA        3.429mA    10.97mA
-838.6mV  18.38mA    10.73mA    17.71mA
-695.5mV  18.8mA     17.12mA    18.09mA
-552.3mV  17.7mA     17.94mA    17.47mA
640.9mV   -16.58mA   -16.97mA   -17.61mA
1.834V    -23.79mA   -23.78mA   -25.99mA
2.12V     -21.67mA   -20.55mA   -24.11mA
2.311V    -20.78mA   -13.32mA   -23.19mA
2.502V    -13.7mA    -9.614mA   -22.45mA
2.741V    -8.5mA     -7.786mA   -11.5mA
2.98V     -7.1mA     -7.1mA     -8.029mA
[Ramp]
R_load=50.000Ohm
dV/dt_r   502.920mV/118.500ps  480.719mV/134.500ps  542.820mV/107.000ps
dV/dt_f   502.920mV/118.500ps  480.719mV/141.000ps  542.820mV/105.500ps
[Rising waveform]
R_fixture=50.000Ohm
V_fixture=1.500
V_fixture_min=1.425
V_fixture_max=1.575
0s        658.6mV    635.5mV    665.3mV
39ps      670.7mV    633.1mV    699.4mV
62ps      716.2mV    632.5mV    819.4mV
123ps     1.087V     643.7mV    1.296V
161ps     1.286V     688.4mV    1.439V
199ps     1.389V     817.4mV    1.506V
276ps     1.467V     1.198V     1.556V
353ps     1.488V     1.357V     1.569V
475ps     1.498V     1.411V     1.574V
749ps     1.5V       1.424V     1.575V
[Rising waveform]
R_fixture=50.000Ohm
V_fixture=0
0s        -4.332mV   822.9uV    -4.437mV
39ps      -10.19mV   -712.1uV   4.427mV
77ps      39.85mV    -4.67mV    137.3mV
169ps     410.9mV    4.259mV    588.5mV
215ps     568.9mV    93.58mV    717.9mV
261ps     675mV      246.7mV    796.6mV
345ps     773.9mV    534.2mV    864mV
429ps     813.5mV    696.3mV    888.4mV
552ps     833.2mV    782.4mV    900.5mV
749ps     840.7mV    811.5mV    905.2mV
[Falling waveform]
R_fixture=50.000Ohm
V_fixture=1.500
V_fixture_min=1.425
V_fixture_max=1.575
0s        1.505V     1.424V     1.58V
46ps      1.512V     1.426V     1.568V
85ps      1.455V     1.435V     1.434V
146ps     1.219V     1.44V      1.114V
192ps     1.028V     1.391V     921.1mV
268ps     816.9mV    1.169V     762.5mV
368ps     714.8mV    868.3mV    697.5mV
437ps     689.5mV    756.3mV    683.6mV
567ps     673.1mV    676mV      674.9mV
749ps     667.9mV    649.2mV    672mV
[Falling waveform]
R_fixture=50.000Ohm
V_fixture=0
0s        853.3mV    821.8mV    913.6mV
39ps      816.8mV    828mV      841.5mV
69ps      695.1mV    831mV      633mV
115ps     398.3mV    807mV      295.1mV
146ps     241.7mV    741.8mV    169.3mV
192ps     114mV      546.2mV    77.72mV
261ps     41.13mV    223.6mV    26.74mV
337ps     15.23mV    74.07mV    8.664mV
467ps     3.035mV    15.39mV    1.3mV
749ps     169.2uV    842.4uV    -6.201uV
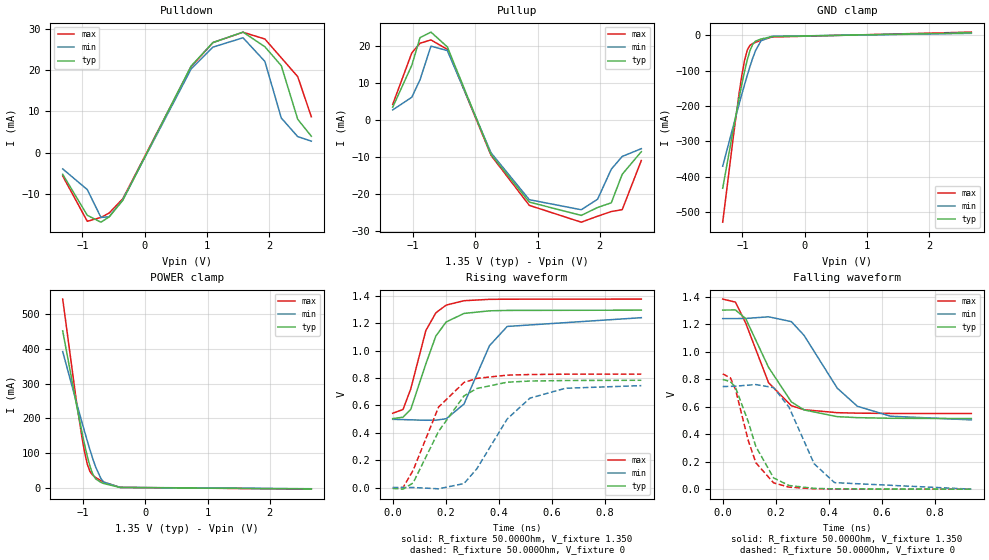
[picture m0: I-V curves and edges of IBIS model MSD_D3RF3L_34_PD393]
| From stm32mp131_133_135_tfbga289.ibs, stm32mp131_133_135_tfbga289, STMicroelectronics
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[Model] MSD_D3RF3L_34_PD393
Model_type   I/O
C_comp 2.363pF   2.279pF   2.485pF
Vinh = 810.000mV
Vinl = 540.000mV
Vmeas = 675.000mV
Vref = 675.000mV
[Model Spec]
Vinh   810.000mV   777.000mV   860.000mV
Vinl   540.000mV   507.000mV   590.000mV
Vmeas   675.000mV   642.000mV   725.000mV
Vref   675.000mV   642.000mV   725.000mV
[Receiver Thresholds]
Vth   =  0.675V
Vth_min  =  0.6615V
Vth_max  =  0.6885V
Vinh_ac  =  0.160V
Vinh_dc  =  0.090V
Vinl_ac  = -0.160V
Vinl_dc  = -0.090V
Tslew_ac =  5.000ns |Not specified, so set to high value
Threshold_sensitivity = 0.50
Reference_supply Pullup_ref
[Temperature Range]   25.000   125.000   -40.000
[Voltage Range]   1.350V   1.283V   1.450V
[GND Clamp Reference]   0.00V   0.00V   0.00V
[Pulldown Reference]   0.00V   0.00V   0.00V
[POWER Clamp Reference]   1.350V   1.283V   1.450V
[Pullup Reference]   1.350V   1.283V   1.450V
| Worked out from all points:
|   slope of the pulldown table from 0 to 0.203 V, typ, clamps not added: 31 ohm
|   slope of the pullup table from 0 to 0.203 V, typ, clamps not added: 26.2 ohm
|   GND clamp passes 1 mA (typ) near -0.40 V on its own axis
|   POWER clamp passes 1 mA (typ) near -0.41 V on its own axis
|   rising waveform, R_fixture 50.000Ohm, V_fixture 1.350: 20-80 % time 83.1ps typ, 104ps min, 73.5ps max; typ from 0.504 V to 1.3 V
|   rising waveform, R_fixture 50.000Ohm, V_fixture 0: 20-80 % time 131ps typ, 155ps min, 115ps max; typ from -0.006 V to 0.784 V
|   falling waveform, R_fixture 50.000Ohm, V_fixture 1.350: 20-80 % time 126ps typ, 158ps min, 107ps max; typ from 1.3 V to 0.513 V
|   falling waveform, R_fixture 50.000Ohm, V_fixture 0: 20-80 % time 87.1ps typ, 107ps min, 75.1ps max; typ from 0.798 V to 0 V
[GND Clamp]
-1.318V   -433.1mA   -370.5mA   -529.1mA
-1.142V   -260.9mA   -253mA     -280.5mA
-1.055V   -178.4mA   -195.4mA   -165.5mA
-1.011V   -139.3mA   -167.3mA   -114.3mA
-966.7mV  -102.5mA   -139.9mA   -71.47mA
-922.7mV  -69.67mA   -113.3mA   -41.85mA
-878.8mV  -43.06mA   -88.06mA   -28.46mA
-834.9mV  -25.47mA   -64.63mA   -23.53mA
-790.9mV  -16.97mA   -43.99mA   -20.34mA
-703mV    -10.86mA   -16.06mA   -14.72mA
-527.3mV  -3.925mA   -3.327mA   -5.234mA
2.68V     6.766mA    5.271mA    8.773mA
[Power Clamp]
-1.33V    452.2mA    392.7mA    544.1mA
-1.111V   241.9mA    247.2mA    250.9mA
-1.023V   162.3mA    190.3mA    148.1mA
-978.8mV  125.2mA    162.4mA    103.6mA
-934.9mV  91.13mA    135.2mA    68.12mA
-890.9mV  61.77mA    108.8mA    46.52mA
-847mV    39.46mA    83.89mA    36.05mA
-803mV    26.13mA    61.11mA    29.99mA
-715.1mV  15.51mA    26.39mA    20.56mA
-671.2mV  12.32mA    16.32mA    16.43mA
-407.6mV  880uA      1.151mA    1.073mA
2.668V    -3.403mA   -2.836mA   -4.045mA
[Pulldown]
-1.318V   -5.2mA     -3.9mA     -5.6mA
-922.7mV  -15.11mA   -8.9mA     -16.55mA
-703mV    -16.77mA   -15.62mA   -15.62mA
-571.2mV  -15.5mA    -15.46mA   -14.56mA
-351.5mV  -11.48mA   -11.33mA   -11.1mA
747mV     20.94mA    20.23mA    20.78mA
1.098V    26.62mA    25.52mA    26.63mA
1.582V    29.15mA    27.78mA    29.11mA
1.933V    25.61mA    22.07mA    27.48mA
2.197V    21.04mA    8.4mA      22.94mA
2.461V    8.1mA      3.9mA      18.4mA
2.68V     4mA        2.8mA      8.7mA
[Pullup]
-1.33V    3.4mA      2.657mA    4.152mA
-1.023V   14.7mA     6.077mA    18.04mA
-890.9mV  22.16mA    10.8mA     20.65mA
-715.1mV  23.66mA    19.86mA    21.55mA
-451.5mV  19.66mA    18.67mA    18.99mA
251.5mV   -9.374mA   -8.924mA   -9.6mA
866.7mV   -22.21mA   -21.56mA   -23.09mA
1.702V    -25.8mA    -24.27mA   -27.63mA
1.965V    -23.66mA   -21.43mA   -26.01mA
2.185V    -22.4mA    -13.34mA   -24.76mA
2.361V    -14.7mA    -9.885mA   -24.24mA
2.668V    -8.6mA     -7.795mA   -10.98mA
[Ramp]
R_load=50.000Ohm
dV/dt_r   470.010mV/108.000ps  446.069mV/131.000ps  496.590mV/94.500ps
dV/dt_f   470.010mV/106.000ps  446.069mV/134.500ps  496.590mV/91.500ps
[Rising waveform]
R_fixture=50.000Ohm
V_fixture=1.350
V_fixture_min=1.283
V_fixture_max=1.450
0s        503.5mV    498.4mV    542.8mV
39ps      514mV      496.5mV    570.5mV
68ps      570.3mV    494.7mV    720.2mV
125ps     903.2mV    491.6mV    1.147V
163ps     1.108V     492.4mV    1.277V
202ps     1.21V      502.8mV    1.333V
269ps     1.272V     610.2mV    1.365V
365ps     1.291V     1.036V     1.375V
432ps     1.294V     1.177V     1.376V
938ps     1.296V     1.241V     1.377V
[Rising waveform]
R_fixture=50.000Ohm
V_fixture=0
0s        -6.202mV   877.4uV    -5.212mV
39ps      -11.75mV   963uV      -77.2uV
77ps      33.86mV    329.6uV    125.5mV
173ps     410.4mV    -9.089mV   588.1mV
269ps     669.6mV    29.3mV     767.8mV
317ps     723.3mV    136.1mV    797.5mV
432ps     769.5mV    501.4mV    821.3mV
518ps     778.1mV    653.5mV    825.7mV
652ps     782.1mV    725.4mV    828.2mV
938ps     783.8mV    744.7mV    828.8mV
[Falling waveform]
R_fixture=50.000Ohm
V_fixture=1.350
V_fixture_min=1.283
V_fixture_max=1.450
0s        1.302V     1.24V      1.382V
48ps      1.303V     1.24V      1.36V
87ps      1.239V     1.241V     1.206V
173ps     885.6mV    1.253V     773.7mV
259ps     634.3mV    1.218V     606.6mV
307ps     576.2mV    1.118V     577.6mV
432ps     527.2mV    734.7mV    556.1mV
508ps     519.9mV    602.8mV    552.6mV
633ps     515.4mV    530.4mV    550.6mV
938ps     513.3mV    503.7mV    550.2mV
[Falling waveform]
R_fixture=50.000Ohm
V_fixture=0
0s        797.7mV    746mV      838.3mV
29ps      781.8mV    747.3mV    808.9mV
48ps      740.5mV    748.9mV    726.2mV
96ps      493.2mV    755.9mV    356.2mV
125ps     309.9mV    760.4mV    192.1mV
192ps     81.93mV    738.3mV    45.75mV
250ps     26.66mV    596.7mV    14.91mV
345ps     5.907mV    184.5mV    2.662mV
422ps     1.986mV    47.45mV    670.9uV
938ps     7.783uV    127.9uV    4.452uV
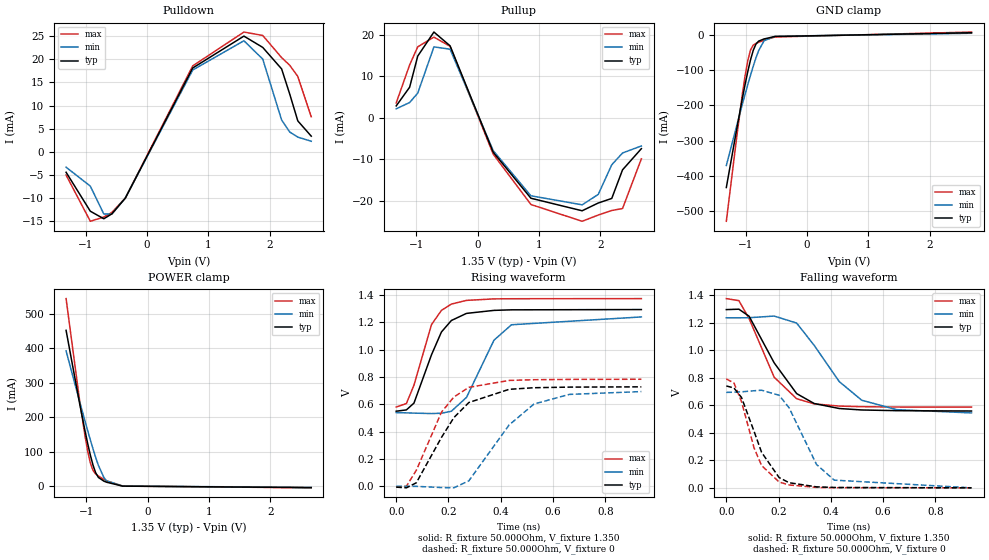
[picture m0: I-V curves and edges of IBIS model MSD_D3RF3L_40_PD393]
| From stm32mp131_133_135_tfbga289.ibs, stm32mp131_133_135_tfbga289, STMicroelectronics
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[Model] MSD_D3RF3L_40_PD393
Model_type   I/O
C_comp 2.363pF   2.279pF   2.485pF
Vinh = 810.000mV
Vinl = 540.000mV
Vmeas = 675.000mV
Vref = 675.000mV
[Model Spec]
Vinh   810.000mV   777.000mV   860.000mV
Vinl   540.000mV   507.000mV   590.000mV
Vmeas   675.000mV   642.000mV   725.000mV
Vref   675.000mV   642.000mV   725.000mV
[Receiver Thresholds]
Vth   =  0.675V
Vth_min  =  0.6615V
Vth_max  =  0.6885V
Vinh_ac  =  0.160V
Vinh_dc  =  0.090V
Vinl_ac  = -0.160V
Vinl_dc  = -0.090V
Tslew_ac =  5.000ns |Not specified, so set to high value
Threshold_sensitivity = 0.50
Reference_supply Pullup_ref
[Temperature Range]   25.000   125.000   -40.000
[Voltage Range]   1.350V   1.283V   1.450V
[GND Clamp Reference]   0.00V   0.00V   0.00V
[Pulldown Reference]   0.00V   0.00V   0.00V
[POWER Clamp Reference]   1.350V   1.283V   1.450V
[Pullup Reference]   1.350V   1.283V   1.450V
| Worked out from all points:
|   slope of the pulldown table from 0 to 0.203 V, typ, clamps not added: 35.6 ohm
|   slope of the pullup table from 0 to 0.203 V, typ, clamps not added: 29.7 ohm
|   GND clamp passes 1 mA (typ) near -0.40 V on its own axis
|   POWER clamp passes 1 mA (typ) near -0.41 V on its own axis
|   rising waveform, R_fixture 50.000Ohm, V_fixture 1.350: 20-80 % time 88.6ps typ, 109ps min, 75.9ps max; typ from 0.549 V to 1.29 V
|   rising waveform, R_fixture 50.000Ohm, V_fixture 0: 20-80 % time 140ps typ, 166ps min, 121ps max; typ from -0.005 V to 0.727 V
|   falling waveform, R_fixture 50.000Ohm, V_fixture 1.350: 20-80 % time 137ps typ, 166ps min, 115ps max; typ from 1.3 V to 0.559 V
|   falling waveform, R_fixture 50.000Ohm, V_fixture 0: 20-80 % time 92.4ps typ, 110ps min, 79.2ps max; typ from 0.741 V to 0 V
[GND Clamp]
-1.318V   -433.1mA   -370.5mA   -529.1mA
-1.142V   -260.9mA   -253mA     -280.5mA
-1.055V   -178.4mA   -195.4mA   -165.5mA
-1.011V   -139.3mA   -167.3mA   -114.3mA
-966.7mV  -102.5mA   -139.9mA   -71.47mA
-922.7mV  -69.67mA   -113.3mA   -41.85mA
-878.8mV  -43.06mA   -88.06mA   -28.46mA
-834.9mV  -25.47mA   -64.63mA   -23.53mA
-790.9mV  -16.97mA   -43.99mA   -20.34mA
-703mV    -10.86mA   -16.06mA   -14.72mA
-527.3mV  -3.925mA   -3.327mA   -5.234mA
2.68V     6.766mA    5.271mA    8.773mA
[Power Clamp]
-1.33V    452.2mA    392.7mA    544.1mA
-1.111V   241.9mA    247.2mA    250.9mA
-1.023V   162.3mA    190.3mA    148.1mA
-978.8mV  125.2mA    162.4mA    103.6mA
-934.9mV  91.13mA    135.2mA    68.12mA
-890.9mV  61.77mA    108.8mA    46.52mA
-847mV    39.46mA    83.89mA    36.05mA
-803mV    26.13mA    61.11mA    29.99mA
-715.1mV  15.51mA    26.39mA    20.56mA
-671.2mV  12.32mA    16.32mA    16.43mA
-407.6mV  880uA      1.151mA    1.073mA
2.668V    -3.403mA   -2.836mA   -4.045mA
[Pulldown]
-1.318V   -4.4mA     -3.3mA     -5mA
-922.7mV  -12.82mA   -7.4mA     -14.99mA
-703mV    -14.45mA   -13.41mA   -14.07mA
-571.2mV  -13.39mA   -13.44mA   -13.08mA
-351.5mV  -9.978mA   -9.96mA    -9.95mA
747mV     18.13mA    17.69mA    18.58mA
1.582V    25.02mA    24.02mA    25.9mA
1.889V    22.58mA    20.05mA    25.16mA
2.197V    17.93mA    6.9mA      20.37mA
2.329V    12.5mA     4.3mA      18.73mA
2.461V    6.7mA      3.2mA      16.3mA
2.68V     3.4mA      2.3mA      7.6mA
[Pullup]
-1.33V    2.9mA      2.205mA    3.607mA
-1.111V   7.4mA      3.715mA    12.77mA
-978.8mV  14.9mA     5.977mA    17.13mA
-715.1mV  20.69mA    17.11mA    19.47mA
-451.5mV  17.37mA    16.56mA    17.25mA
251.5mV   -8.25mA    -7.869mA   -8.718mA
866.7mV   -19.34mA   -18.75mA   -20.85mA
1.702V    -22.36mA   -20.93mA   -24.89mA
1.965V    -20.49mA   -18.42mA   -23.39mA
2.185V    -19.39mA   -11.29mA   -22.29mA
2.361V    -12.5mA    -8.438mA   -21.82mA
2.668V    -7.4mA     -6.748mA   -9.848mA
[Ramp]
R_load=50.000Ohm
dV/dt_r   438.120mV/115.000ps  417.269mV/139.000ps  470.280mV/99.000ps
dV/dt_f   438.120mV/115.000ps  417.269mV/140.000ps  470.280mV/97.500ps
[Rising waveform]
R_fixture=50.000Ohm
V_fixture=1.350
V_fixture_min=1.283
V_fixture_max=1.450
0s        549.4mV    539.4mV    580.2mV
39ps      559mV      537.3mV    605.5mV
68ps      608.8mV    535.5mV    740mV
135ps     961.5mV    532.2mV    1.182V
173ps     1.128V     534.7mV    1.286V
211ps     1.212V     549.1mV    1.332V
269ps     1.264V     650.5mV    1.359V
374ps     1.286V     1.068V     1.37V
441ps     1.29V      1.181V     1.371V
938ps     1.292V     1.238V     1.372V
[Rising waveform]
R_fixture=50.000Ohm
V_fixture=0
0s        -5.265mV   817.9uV    -4.643mV
39ps      -10.35mV   917.8uV    1.399mV
77ps      26.68mV    377.8uV    117.8mV
173ps     357.4mV    -8.322mV   541.7mV
221ps     503.4mV    -9.851mV   653.8mV
278ps     613mV      40.98mV    723.7mV
432ps     709.3mV    448.9mV    774.3mV
527ps     721mV      601.8mV    779.5mV
662ps     725.4mV    672.1mV    781.8mV
938ps     727.4mV    692.9mV    782.9mV
[Falling waveform]
R_fixture=50.000Ohm
V_fixture=1.350
V_fixture_min=1.283
V_fixture_max=1.450
0s        1.297V     1.237V     1.377V
48ps      1.3V       1.237V     1.362V
87ps      1.249V     1.238V     1.232V
183ps     909.7mV    1.25V      805.1mV
269ps     685.8mV    1.199V     648.4mV
336ps     613.7mV    1.037V     611.1mV
432ps     577.2mV    773.2mV    594.9mV
518ps     566.6mV    637.5mV    590.5mV
652ps     561.5mV    568.8mV    588mV
938ps     559mV      545.1mV    587.4mV
[Falling waveform]
R_fixture=50.000Ohm
V_fixture=0
0s        741.4mV    694.5mV    792mV
29ps      726.8mV    695.8mV    763.6mV
58ps      657.8mV    698.7mV    627.6mV
106ps     411.6mV    706.5mV    291.1mV
135ps     257.9mV    710.2mV    162.1mV
202ps     74.64mV    673.6mV    42.49mV
240ps     37.34mV    583mV      20.93mV
345ps     7.163mV    170.1mV    3.23mV
413ps     2.721mV    55.96mV    980.3uV
938ps     7.967uV    123.1uV    5.749uV
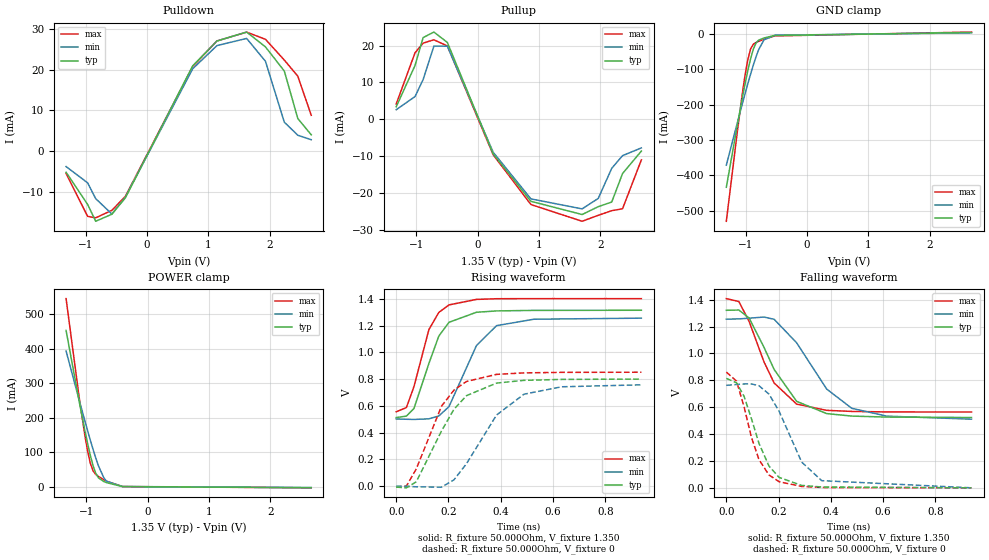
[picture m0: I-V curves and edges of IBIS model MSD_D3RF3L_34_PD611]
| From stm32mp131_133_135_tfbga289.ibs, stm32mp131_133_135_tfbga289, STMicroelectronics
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[Model] MSD_D3RF3L_34_PD611
Model_type   I/O
C_comp 2.439pF   2.355pF   2.563pF
Vinh = 810.000mV
Vinl = 540.000mV
Vmeas = 675.000mV
Vref = 675.000mV
[Model Spec]
Vinh   810.000mV   777.000mV   860.000mV
Vinl   540.000mV   507.000mV   590.000mV
Vmeas   675.000mV   642.000mV   725.000mV
Vref   675.000mV   642.000mV   725.000mV
[Receiver Thresholds]
Vth   =  0.675V
Vth_min  =  0.6615V
Vth_max  =  0.6885V
Vinh_ac  =  0.160V
Vinh_dc  =  0.090V
Vinl_ac  = -0.160V
Vinl_dc  = -0.090V
Tslew_ac =  5.000ns |Not specified, so set to high value
Threshold_sensitivity = 0.50
Reference_supply Pullup_ref
[Temperature Range]   25.000   125.000   -40.000
[Voltage Range]   1.350V   1.283V   1.450V
[GND Clamp Reference]   0.00V   0.00V   0.00V
[Pulldown Reference]   0.00V   0.00V   0.00V
[POWER Clamp Reference]   1.350V   1.283V   1.450V
[Pullup Reference]   1.350V   1.283V   1.450V
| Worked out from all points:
|   slope of the pulldown table from 0 to 0.203 V, typ, clamps not added: 31 ohm
|   slope of the pullup table from 0 to 0.203 V, typ, clamps not added: 26.2 ohm
|   GND clamp passes 1 mA (typ) near -0.40 V on its own axis
|   POWER clamp passes 1 mA (typ) near -0.41 V on its own axis
|   rising waveform, R_fixture 50.000Ohm, V_fixture 1.350: 20-80 % time 84.3ps typ, 106ps min, 74.6ps max; typ from 0.513 V to 1.31 V
|   rising waveform, R_fixture 50.000Ohm, V_fixture 0: 20-80 % time 134ps typ, 158ps min, 118ps max; typ from -0.006 V to 0.801 V
|   falling waveform, R_fixture 50.000Ohm, V_fixture 1.350: 20-80 % time 131ps typ, 163ps min, 112ps max; typ from 1.32 V to 0.523 V
|   falling waveform, R_fixture 50.000Ohm, V_fixture 0: 20-80 % time 89.5ps typ, 110ps min, 77.8ps max; typ from 0.814 V to 0 V
[GND Clamp]
-1.318V   -433.8mA   -371.2mA   -530.1mA
-1.142V   -261.4mA   -253.4mA   -281.2mA
-1.055V   -178.9mA   -195.9mA   -166mA
-1.011V   -139.7mA   -167.8mA   -114.9mA
-966.7mV  -102.9mA   -140.2mA   -72.01mA
-922.7mV  -70.05mA   -113.7mA   -42.34mA
-878.8mV  -43.4mA    -88.34mA   -28.91mA
-834.9mV  -25.77mA   -64.88mA   -23.94mA
-790.9mV  -17.25mA   -44.21mA   -20.71mA
-703mV    -11.07mA   -16.23mA   -15mA
-527.3mV  -4.022mA   -3.409mA   -5.364mA
2.68V     4.353mA    3.39mA     5.636mA
[Power Clamp]
-1.33V    453mA      393.4mA    545.1mA
-1.111V   242.5mA    247.8mA    251.6mA
-1.023V   162.8mA    190.7mA    148.7mA
-978.8mV  125.6mA    162.8mA    104.1mA
-934.9mV  91.56mA    135.5mA    68.65mA
-890.9mV  62.16mA    109.2mA    47mA
-847mV    39.83mA    84.22mA    36.49mA
-803mV    26.46mA    61.4mA     30.39mA
-715.1mV  15.76mA    26.62mA    20.87mA
-671.2mV  12.53mA    16.52mA    16.7mA
-407.6mV  918uA      1.198mA    1.12mA
2.668V    -2.188mA   -1.824mA   -2.601mA
[Pulldown]
-1.318V   -5.2mA     -3.8mA     -5.5mA
-966.7mV  -13.1mA    -7.8mA     -16.02mA
-834.9mV  -17.24mA   -11.68mA   -16.39mA
-571.2mV  -15.5mA    -15.46mA   -14.56mA
-351.5mV  -11.48mA   -11.32mA   -11.11mA
747mV     20.95mA    20.23mA    20.78mA
1.142V    27.05mA    25.92mA    27.06mA
1.626V    29.25mA    27.68mA    29.23mA
1.933V    25.61mA    22.08mA    27.47mA
2.241V    19.66mA    7.1mA      22.36mA
2.461V    8mA        3.9mA      18.4mA
2.68V     4mA        2.8mA      8.8mA
[Pullup]
-1.33V    3.4mA      2.605mA    4.152mA
-1.023V   14.6mA     6.177mA    18.04mA
-890.9mV  22.16mA    10.79mA    20.66mA
-715.1mV  23.66mA    19.86mA    21.56mA
-495.5mV  20.83mA    19.82mA    19.88mA
251.5mV   -9.374mA   -8.924mA   -9.601mA
866.7mV   -22.22mA   -21.56mA   -23.09mA
1.702V    -25.8mA    -24.27mA   -27.63mA
1.965V    -23.67mA   -21.43mA   -26.01mA
2.185V    -22.41mA   -13.27mA   -24.76mA
2.361V    -14.7mA    -9.838mA   -24.24mA
2.668V    -8.6mA     -7.748mA   -10.98mA
[Ramp]
R_load=50.000Ohm
dV/dt_r   477.810mV/109.500ps  451.949mV/132.500ps  507.180mV/97.000ps
dV/dt_f   477.810mV/110.000ps  451.949mV/138.500ps  507.180mV/95.500ps
[Rising waveform]
R_fixture=50.000Ohm
V_fixture=1.350
V_fixture_min=1.283
V_fixture_max=1.450
0s        513.3mV    503mV      556.4mV
39ps      524.2mV    500.6mV    587.9mV
68ps      581.4mV    499.2mV    744.8mV
125ps     917.1mV    503.8mV    1.17V
163ps     1.122V     525.1mV    1.299V
202ps     1.225V     595.2mV    1.355V
307ps     1.3V       1.051V     1.396V
384ps     1.31V      1.2V       1.401V
527ps     1.314V     1.248V     1.402V
938ps     1.315V     1.256V     1.402V
[Rising waveform]
R_fixture=50.000Ohm
V_fixture=0
0s        -6.2mV     778.8uV    -5.493mV
39ps      -11.78mV   -611.6uV   1.553mV
77ps      33.8mV     -3.99mV    130.3mV
173ps     412.1mV    -7.066mV   597mV
221ps     575.4mV    47.94mV    718.5mV
269ps     677mV      168.8mV    783.1mV
384ps     770.8mV    532.3mV    836mV
489ps     791.3mV    687.9mV    846.9mV
633ps     798.3mV    743.2mV    851.1mV
938ps     800.7mV    757.8mV    852mV
[Falling waveform]
R_fixture=50.000Ohm
V_fixture=1.350
V_fixture_min=1.283
V_fixture_max=1.450
0s        1.321V     1.255V     1.408V
48ps      1.323V     1.257V     1.386V
87ps      1.264V     1.262V     1.239V
144ps     1.046V     1.271V     937.6mV
183ps     880.5mV    1.254V     780mV
269ps     643.7mV    1.079V     622.9mV
384ps     552.3mV    735mV      576.7mV
480ps     533.9mV    591.7mV    568.5mV
614ps     526.4mV    533.5mV    564.8mV
938ps     523.2mV    510.9mV    564mV
[Falling waveform]
R_fixture=50.000Ohm
V_fixture=0
0s        814.3mV    762.7mV    861.4mV
39ps      781.9mV    768.6mV    794.3mV
68ps      680.4mV    772.9mV    601.9mV
96ps      515mV      773.1mV    375.9mV
125ps     330.4mV    759.4mV    209.4mV
163ps     162.8mV    698mV      96.14mV
202ps     77.48mV    569.2mV    45.48mV
288ps     18.13mV    192.3mV    10.33mV
365ps     6.178mV    53.4mV     2.903mV
938ps     -1.236uV   101.1uV    8.469uV
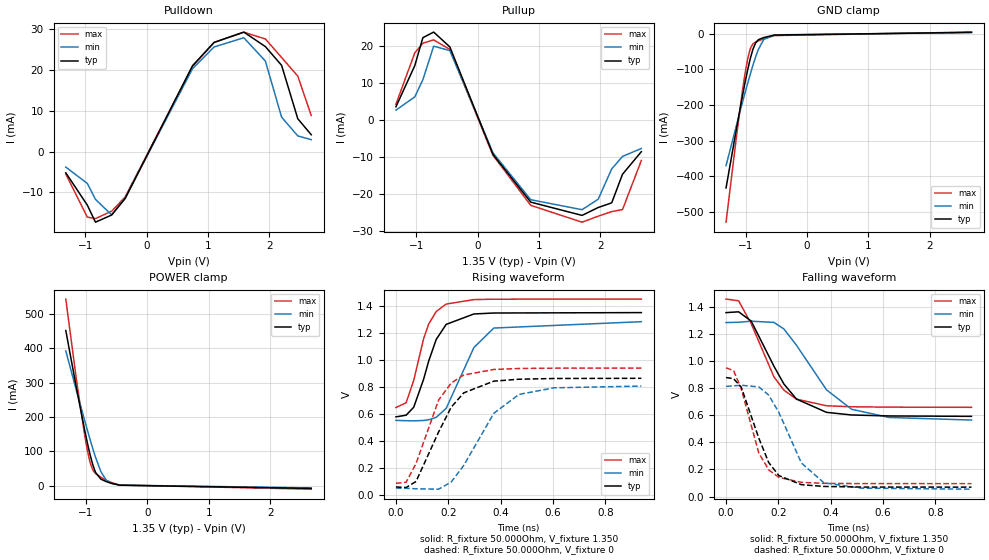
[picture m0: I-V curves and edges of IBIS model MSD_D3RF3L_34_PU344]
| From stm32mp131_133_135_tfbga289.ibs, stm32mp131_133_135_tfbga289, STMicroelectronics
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[Model] MSD_D3RF3L_34_PU344
Model_type   I/O
C_comp 2.337pF   2.253pF   2.460pF
Vinh = 810.000mV
Vinl = 540.000mV
Vmeas = 675.000mV
Vref = 675.000mV
[Model Spec]
Vinh   810.000mV   777.000mV   860.000mV
Vinl   540.000mV   507.000mV   590.000mV
Vmeas   675.000mV   642.000mV   725.000mV
Vref   675.000mV   642.000mV   725.000mV
[Receiver Thresholds]
Vth   =  0.675V
Vth_min  =  0.6615V
Vth_max  =  0.6885V
Vinh_ac  =  0.160V
Vinh_dc  =  0.090V
Vinl_ac  = -0.160V
Vinl_dc  = -0.090V
Tslew_ac =  5.000ns |Not specified, so set to high value
Threshold_sensitivity = 0.50
Reference_supply Pullup_ref
[Temperature Range]   25.000   125.000   -40.000
[Voltage Range]   1.350V   1.283V   1.450V
[GND Clamp Reference]   0.00V   0.00V   0.00V
[Pulldown Reference]   0.00V   0.00V   0.00V
[POWER Clamp Reference]   1.350V   1.283V   1.450V
[Pullup Reference]   1.350V   1.283V   1.450V
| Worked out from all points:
|   slope of the pulldown table from 0 to 0.203 V, typ, clamps not added: 31 ohm
|   slope of the pullup table from 0 to 0.203 V, typ, clamps not added: 26.2 ohm
|   GND clamp passes 1 mA (typ) near -0.41 V on its own axis
|   POWER clamp passes 1 mA (typ) near -0.41 V on its own axis
|   rising waveform, R_fixture 50.000Ohm, V_fixture 1.350: 20-80 % time 79.6ps typ, 103ps min, 68.9ps max; typ from 0.58 V to 1.35 V
|   rising waveform, R_fixture 50.000Ohm, V_fixture 0: 20-80 % time 119ps typ, 145ps min, 103ps max; typ from 0.063 V to 0.865 V
|   falling waveform, R_fixture 50.000Ohm, V_fixture 1.350: 20-80 % time 132ps typ, 164ps min, 114ps max; typ from 1.35 V to 0.591 V
|   falling waveform, R_fixture 50.000Ohm, V_fixture 0: 20-80 % time 90.5ps typ, 111ps min, 78.3ps max; typ from 0.877 V to 0.069 V
[GND Clamp]
-1.318V   -432.7mA   -370.2mA   -528.8mA
-1.142V   -260.6mA   -252.7mA   -280.1mA
-1.055V   -178.2mA   -195.2mA   -165.1mA
-1.011V   -139mA     -167.2mA   -114.1mA
-966.7mV  -102.3mA   -139.7mA   -71.22mA
-922.7mV  -69.47mA   -113.2mA   -41.62mA
-878.8mV  -42.87mA   -87.88mA   -28.25mA
-834.9mV  -25.29mA   -64.47mA   -23.34mA
-790.9mV  -16.82mA   -43.84mA   -20.18mA
-703mV    -10.74mA   -15.95mA   -14.58mA
-527.3mV  -3.867mA   -3.267mA   -5.173mA
2.68V     3.846mA    3.267mA    4.549mA
[Power Clamp]
-1.33V    452.1mA    392.8mA    543.8mA
-1.155V   283.1mA    276.1mA    306.4mA
-1.023V   162.2mA    190.3mA    147.9mA
-978.8mV  125.1mA    162.4mA    103.4mA
-934.9mV  91.05mA    135.1mA    67.96mA
-890.9mV  61.71mA    108.8mA    46.37mA
-847mV    39.4mA     83.89mA    35.92mA
-759.1mV  19.48mA    41.52mA    24.95mA
-671.2mV  12.28mA    16.32mA    16.36mA
-583.3mV  7.022mA    7.054mA    9.286mA
-451.5mV  1.801mA    2.042mA    2.252mA
2.668V    -7.581mA   -6.072mA   -9.749mA
[Pulldown]
-1.318V   -5.2mA     -3.8mA     -5.5mA
-966.7mV  -13.1mA    -7.8mA     -16.02mA
-834.9mV  -17.25mA   -11.68mA   -16.38mA
-571.2mV  -15.5mA    -15.46mA   -14.56mA
-351.5mV  -11.48mA   -11.33mA   -11.11mA
747mV     20.95mA    20.23mA    20.78mA
1.098V    26.63mA    25.53mA    26.63mA
1.582V    29.15mA    27.77mA    29.12mA
1.933V    25.61mA    22.08mA    27.48mA
2.197V    21.04mA    8.4mA      22.95mA
2.461V    8mA        3.8mA      18.4mA
2.68V     4.1mA      2.9mA      8.8mA
[Pullup]
-1.33V    3.5mA      2.605mA    4.179mA
-1.023V   14.6mA     6.177mA    18.04mA
-890.9mV  22.15mA    10.81mA    20.66mA
-715.1mV  23.66mA    19.86mA    21.56mA
-451.5mV  19.66mA    18.67mA    18.98mA
251.5mV   -9.373mA   -8.922mA   -9.599mA
866.7mV   -22.22mA   -21.57mA   -23.09mA
1.702V    -25.8mA    -24.26mA   -27.63mA
1.965V    -23.67mA   -21.43mA   -26.01mA
2.185V    -22.41mA   -13.26mA   -24.77mA
2.361V    -14.7mA    -9.885mA   -24.24mA
2.668V    -8.6mA     -7.748mA   -10.98mA
[Ramp]
R_load=50.000Ohm
dV/dt_r   466.635mV/100.000ps  442.875mV/124.500ps  491.349mV/86.500ps
dV/dt_f   466.635mV/111.000ps  442.845mV/138.500ps  491.349mV/96.500ps
[Rising waveform]
R_fixture=50.000Ohm
V_fixture=1.350
V_fixture_min=1.283
V_fixture_max=1.450
0s        580.1mV    554.4mV    649.2mV
39ps      592.6mV    551.8mV    684.2mV
68ps      651.2mV    550.9mV    849.4mV
106ps     859.1mV    553.5mV    1.159V
125ps     990.8mV    558.3mV    1.264V
154ps     1.152V     577.1mV    1.358V
192ps     1.263V     642.8mV    1.413V
298ps     1.34V      1.092V     1.446V
374ps     1.347V     1.236V     1.449V
938ps     1.35V      1.283V     1.45V
[Rising waveform]
R_fixture=50.000Ohm
V_fixture=0
0s        62.93mV    54.27mV    89.52mV
39ps      58.41mV    52.65mV    97.36mV
77ps      103.5mV    49.23mV    236.4mV
163ps     468.2mV    46.36mV    703.5mV
211ps     650.6mV    98.68mV    829.5mV
259ps     757.2mV    221.2mV    889.4mV
374ps     843.8mV    606.2mV    930mV
470ps     858.2mV    745.7mV    937.4mV
604ps     863.5mV    794.7mV    939.8mV
938ps     865mV      807.5mV    940.1mV
[Falling waveform]
R_fixture=50.000Ohm
V_fixture=1.350
V_fixture_min=1.283
V_fixture_max=1.450
0s        1.355V     1.282V     1.455V
48ps      1.361V     1.284V     1.442V
96ps      1.293V     1.292V     1.274V
183ps     960.3mV    1.283V     881.5mV
221ps     829.3mV    1.235V     784mV
269ps     718.3mV    1.115V     717.7mV
384ps     620.2mV    785.9mV    668.8mV
480ps     600.9mV    642.8mV    661.3mV
623ps     593.6mV    582.5mV    658.5mV
938ps     590.8mV    563.5mV    657.3mV
[Falling waveform]
R_fixture=50.000Ohm
V_fixture=0
0s        877.2mV    811.5mV    948.6mV
29ps      868mV      815.5mV    927.1mV
58ps      806.3mV    819.8mV    794.4mV
125ps     431mV      807.5mV    321.7mV
163ps     250.3mV    747.9mV    196.4mV
202ps     154.1mV    618.8mV    140.9mV
288ps     87.15mV    247mV      104.4mV
374ps     74.3mV     101.2mV    97.02mV
518ps     69.79mV    61.48mV    95.17mV
938ps     69.06mV    54.17mV    94.98mV
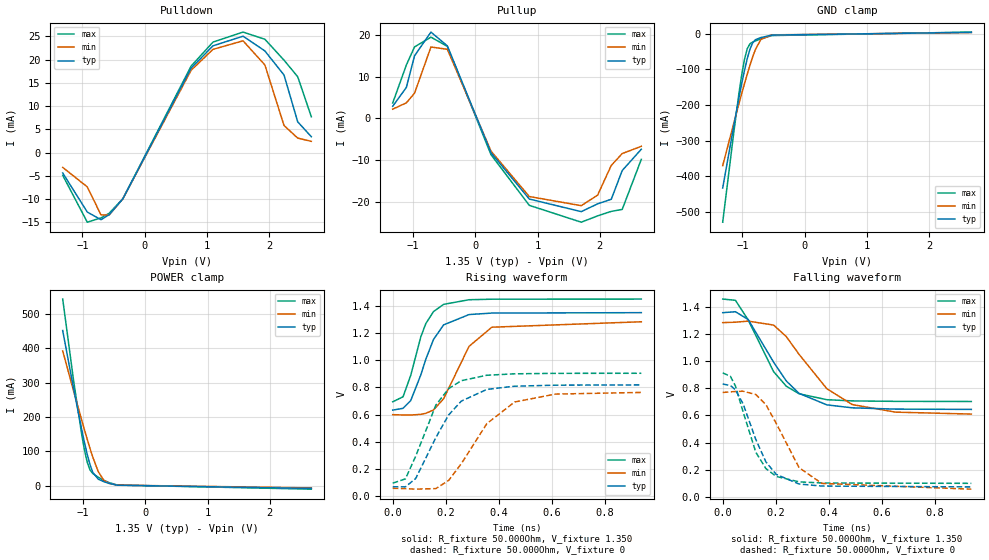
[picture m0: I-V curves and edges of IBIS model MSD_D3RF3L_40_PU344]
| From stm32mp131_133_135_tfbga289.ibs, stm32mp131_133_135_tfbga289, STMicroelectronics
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[Model] MSD_D3RF3L_40_PU344
Model_type   I/O
C_comp 2.337pF   2.253pF   2.460pF
Vinh = 810.000mV
Vinl = 540.000mV
Vmeas = 675.000mV
Vref = 675.000mV
[Model Spec]
Vinh   810.000mV   777.000mV   860.000mV
Vinl   540.000mV   507.000mV   590.000mV
Vmeas   675.000mV   642.000mV   725.000mV
Vref   675.000mV   642.000mV   725.000mV
[Receiver Thresholds]
Vth   =  0.675V
Vth_min  =  0.6615V
Vth_max  =  0.6885V
Vinh_ac  =  0.160V
Vinh_dc  =  0.090V
Vinl_ac  = -0.160V
Vinl_dc  = -0.090V
Tslew_ac =  5.000ns |Not specified, so set to high value
Threshold_sensitivity = 0.50
Reference_supply Pullup_ref
[Temperature Range]   25.000   125.000   -40.000
[Voltage Range]   1.350V   1.283V   1.450V
[GND Clamp Reference]   0.00V   0.00V   0.00V
[Pulldown Reference]   0.00V   0.00V   0.00V
[POWER Clamp Reference]   1.350V   1.283V   1.450V
[Pullup Reference]   1.350V   1.283V   1.450V
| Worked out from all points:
|   slope of the pulldown table from 0 to 0.203 V, typ, clamps not added: 35.6 ohm
|   slope of the pullup table from 0 to 0.203 V, typ, clamps not added: 29.7 ohm
|   GND clamp passes 1 mA (typ) near -0.41 V on its own axis
|   POWER clamp passes 1 mA (typ) near -0.41 V on its own axis
|   rising waveform, R_fixture 50.000Ohm, V_fixture 1.350: 20-80 % time 84.1ps typ, 107ps min, 71.1ps max; typ from 0.633 V to 1.35 V
|   rising waveform, R_fixture 50.000Ohm, V_fixture 0: 20-80 % time 128ps typ, 154ps min, 108ps max; typ from 0.069 V to 0.819 V
|   falling waveform, R_fixture 50.000Ohm, V_fixture 1.350: 20-80 % time 144ps typ, 173ps min, 124ps max; typ from 1.35 V to 0.644 V
|   falling waveform, R_fixture 50.000Ohm, V_fixture 0: 20-80 % time 96.2ps typ, 115ps min, 83.1ps max; typ from 0.831 V to 0.075 V
[GND Clamp]
-1.318V   -432.7mA   -370.2mA   -528.8mA
-1.142V   -260.6mA   -252.7mA   -280.1mA
-1.055V   -178.2mA   -195.2mA   -165.1mA
-1.011V   -139mA     -167.2mA   -114.1mA
-966.7mV  -102.3mA   -139.7mA   -71.22mA
-922.7mV  -69.47mA   -113.2mA   -41.62mA
-878.8mV  -42.87mA   -87.88mA   -28.25mA
-834.9mV  -25.29mA   -64.47mA   -23.34mA
-790.9mV  -16.82mA   -43.84mA   -20.18mA
-703mV    -10.74mA   -15.95mA   -14.58mA
-527.3mV  -3.867mA   -3.267mA   -5.173mA
2.68V     3.846mA    3.267mA    4.549mA
[Power Clamp]
-1.33V    452.1mA    392.8mA    543.8mA
-1.155V   283.1mA    276.1mA    306.4mA
-1.023V   162.2mA    190.3mA    147.9mA
-978.8mV  125.1mA    162.4mA    103.4mA
-934.9mV  91.05mA    135.1mA    67.96mA
-890.9mV  61.71mA    108.8mA    46.37mA
-847mV    39.4mA     83.89mA    35.92mA
-759.1mV  19.48mA    41.52mA    24.95mA
-671.2mV  12.28mA    16.32mA    16.36mA
-583.3mV  7.022mA    7.054mA    9.286mA
-451.5mV  1.801mA    2.042mA    2.252mA
2.668V    -7.581mA   -6.072mA   -9.749mA
[Pulldown]
-1.318V   -4.4mA     -3.2mA     -4.9mA
-922.7mV  -12.81mA   -7.4mA     -14.99mA
-703mV    -14.46mA   -13.41mA   -14.07mA
-571.2mV  -13.38mA   -13.45mA   -13.08mA
-351.5mV  -9.978mA   -9.967mA   -9.956mA
747mV     18.14mA    17.69mA    18.58mA
1.098V    22.94mA    22.18mA    23.74mA
1.582V    25.02mA    24.02mA    25.9mA
1.933V    21.85mA    18.84mA    24.36mA
2.241V    16.67mA    5.8mA      19.86mA
2.461V    6.6mA      3.1mA      16.3mA
2.68V     3.4mA      2.4mA      7.7mA
[Pullup]
-1.33V    2.9mA      2.205mA    3.679mA
-1.111V   7.4mA      3.715mA    12.77mA
-978.8mV  15mA       6.025mA    17.13mA
-715.1mV  20.68mA    17.11mA    19.47mA
-451.5mV  17.37mA    16.56mA    17.25mA
251.5mV   -8.25mA    -7.87mA    -8.717mA
866.7mV   -19.34mA   -18.74mA   -20.85mA
1.702V    -22.36mA   -20.93mA   -24.89mA
1.965V    -20.49mA   -18.41mA   -23.38mA
2.185V    -19.39mA   -11.27mA   -22.3mA
2.361V    -12.5mA    -8.438mA   -21.82mA
2.668V    -7.4mA     -6.7mA     -9.821mA
[Ramp]
R_load=50.000Ohm
dV/dt_r   435.081mV/106.000ps  414.456mV/130.500ps  465.240mV/90.000ps
dV/dt_f   435.081mV/121.000ps  414.456mV/145.500ps  465.240mV/104.000ps
[Rising waveform]
R_fixture=50.000Ohm
V_fixture=1.350
V_fixture_min=1.283
V_fixture_max=1.450
0s        633.2mV    599.7mV    694.2mV
39ps      646.3mV    597.3mV    731.2mV
68ps      703.2mV    596.9mV    888.6mV
106ps     891.8mV    602mV      1.172V
125ps     1.008V     609.6mV    1.27V
154ps     1.153V     634.2mV    1.358V
192ps     1.26V      716.7mV    1.411V
288ps     1.336V     1.102V     1.445V
374ps     1.347V     1.243V     1.449V
938ps     1.35V      1.283V     1.45V
[Rising waveform]
R_fixture=50.000Ohm
V_fixture=0
0s        69.19mV    58.16mV    95.66mV
48ps      68.74mV    55.65mV    127.4mV
87ps      130.6mV    51.63mV    295mV
163ps     431.8mV    55.94mV    670.6mV
211ps     597.5mV    116.1mV    791.3mV
259ps     699.6mV    239.2mV    849.7mV
355ps     785.2mV    533.6mV    889.6mV
460ps     809.1mV    692.8mV    900.1mV
614ps     816.6mV    751.1mV    903.6mV
938ps     818.7mV    763.2mV    904.1mV
[Falling waveform]
R_fixture=50.000Ohm
V_fixture=1.350
V_fixture_min=1.283
V_fixture_max=1.450
0s        1.355V     1.282V     1.455V
48ps      1.362V     1.285V     1.446V
96ps      1.305V     1.293V     1.302V
192ps     991.3mV    1.264V     921.7mV
240ps     853.1mV    1.179V     814.7mV
288ps     761.9mV    1.049V     759.2mV
393ps     677.6mV    796mV      715.7mV
489ps     655.8mV    679.7mV    706.7mV
652ps     646.5mV    624.2mV    703.4mV
938ps     644.3mV    610mV      702.4mV
[Falling waveform]
R_fixture=50.000Ohm
V_fixture=0
0s        830.8mV    768.8mV    912.3mV
29ps      820.1mV    773.1mV    887.6mV
48ps      788.4mV    776mV      816.6mV
77ps      684.8mV    777.9mV    625.9mV
125ps     422.5mV    753.6mV    329mV
163ps     258.7mV    679.3mV    209.4mV
202ps     166.7mV    541.3mV    151.7mV
288ps     96.16mV    216.3mV    112.1mV
374ps     81.12mV    100.5mV    103.6mV
938ps     74.84mV    58.29mV    101.1mV
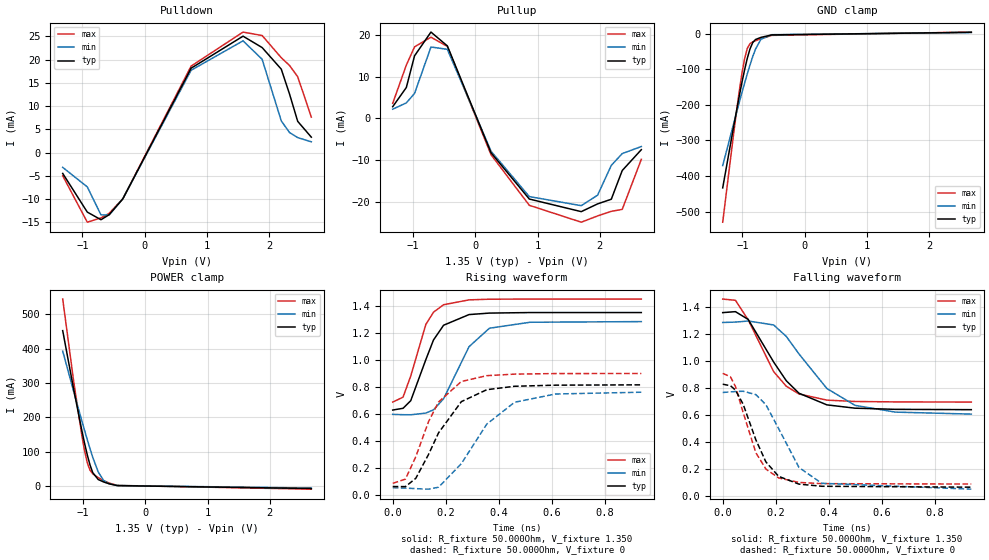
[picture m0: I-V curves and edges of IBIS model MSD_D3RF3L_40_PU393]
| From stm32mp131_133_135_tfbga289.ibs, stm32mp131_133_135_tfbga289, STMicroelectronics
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[Model] MSD_D3RF3L_40_PU393
Model_type   I/O
C_comp 2.367pF   2.282pF   2.491pF
Vinh = 810.000mV
Vinl = 540.000mV
Vmeas = 675.000mV
Vref = 675.000mV
[Model Spec]
Vinh   810.000mV   777.000mV   860.000mV
Vinl   540.000mV   507.000mV   590.000mV
Vmeas   675.000mV   642.000mV   725.000mV
Vref   675.000mV   642.000mV   725.000mV
[Receiver Thresholds]
Vth   =  0.675V
Vth_min  =  0.6615V
Vth_max  =  0.6885V
Vinh_ac  =  0.160V
Vinh_dc  =  0.090V
Vinl_ac  = -0.160V
Vinl_dc  = -0.090V
Tslew_ac =  5.000ns |Not specified, so set to high value
Threshold_sensitivity = 0.50
Reference_supply Pullup_ref
[Temperature Range]   25.000   125.000   -40.000
[Voltage Range]   1.350V   1.283V   1.450V
[GND Clamp Reference]   0.00V   0.00V   0.00V
[Pulldown Reference]   0.00V   0.00V   0.00V
[POWER Clamp Reference]   1.350V   1.283V   1.450V
[Pullup Reference]   1.350V   1.283V   1.450V
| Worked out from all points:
|   slope of the pulldown table from 0 to 0.203 V, typ, clamps not added: 35.6 ohm
|   slope of the pullup table from 0 to 0.203 V, typ, clamps not added: 29.7 ohm
|   GND clamp passes 1 mA (typ) near -0.41 V on its own axis
|   POWER clamp passes 1 mA (typ) near -0.41 V on its own axis
|   rising waveform, R_fixture 50.000Ohm, V_fixture 1.350: 20-80 % time 85.1ps typ, 107ps min, 71.9ps max; typ from 0.627 V to 1.35 V
|   rising waveform, R_fixture 50.000Ohm, V_fixture 0: 20-80 % time 130ps typ, 156ps min, 110ps max; typ from 0.06 V to 0.814 V
|   falling waveform, R_fixture 50.000Ohm, V_fixture 1.350: 20-80 % time 145ps typ, 174ps min, 125ps max; typ from 1.35 V to 0.638 V
|   falling waveform, R_fixture 50.000Ohm, V_fixture 0: 20-80 % time 96.8ps typ, 116ps min, 83.7ps max; typ from 0.826 V to 0.066 V
[GND Clamp]
-1.318V   -433mA     -370.4mA   -529.2mA
-1.142V   -260.8mA   -252.9mA   -280.4mA
-1.055V   -178.3mA   -195.3mA   -165.4mA
-1.011V   -139.2mA   -167.3mA   -114.3mA
-966.7mV  -102.4mA   -139.8mA   -71.44mA
-922.7mV  -69.62mA   -113.3mA   -41.82mA
-878.8mV  -43.01mA   -87.99mA   -28.44mA
-834.9mV  -25.43mA   -64.57mA   -23.51mA
-790.9mV  -16.93mA   -43.94mA   -20.33mA
-703mV    -10.83mA   -16.02mA   -14.7mA
-527.3mV  -3.907mA   -3.3mA     -5.218mA
2.68V     3.366mA    2.86mA     3.981mA
[Power Clamp]
-1.33V    452.4mA    393mA      544.2mA
-1.155V   283.3mA    276.3mA    306.7mA
-1.023V   162.4mA    190.5mA    148.2mA
-978.8mV  125.2mA    162.6mA    103.6mA
-934.9mV  91.22mA    135.3mA    68.17mA
-890.9mV  61.85mA    109mA      46.56mA
-847mV    39.54mA    84.01mA    36.1mA
-759.1mV  19.58mA    41.61mA    25.09mA
-671.2mV  12.36mA    16.39mA    16.46mA
-583.3mV  7.075mA    7.103mA    9.355mA
-451.5mV  1.823mA    2.063mA    2.279mA
2.668V    -6.637mA   -5.319mA   -8.53mA
[Pulldown]
-1.318V   -4.5mA     -3.2mA     -5mA
-922.7mV  -12.82mA   -7.4mA     -14.99mA
-703mV    -14.46mA   -13.41mA   -14.07mA
-571.2mV  -13.38mA   -13.44mA   -13.08mA
-351.5mV  -9.977mA   -9.967mA   -9.951mA
747mV     18.13mA    17.69mA    18.58mA
1.582V    25.02mA    24.02mA    25.9mA
1.889V    22.57mA    20.05mA    25.16mA
2.197V    17.92mA    6.8mA      20.38mA
2.329V    12.6mA     4.3mA      18.73mA
2.461V    6.7mA      3.2mA      16.3mA
2.68V     3.3mA      2.3mA      7.6mA
[Pullup]
-1.33V    2.8mA      2.205mA    3.607mA
-1.111V   7.4mA      3.71mA     12.77mA
-978.8mV  15mA       5.977mA    17.15mA
-715.1mV  20.69mA    17.11mA    19.47mA
-451.5mV  17.38mA    16.56mA    17.25mA
251.5mV   -8.249mA   -7.869mA   -8.718mA
866.7mV   -19.34mA   -18.75mA   -20.84mA
1.702V    -22.36mA   -20.93mA   -24.89mA
1.965V    -20.5mA    -18.41mA   -23.39mA
2.185V    -19.39mA   -11.27mA   -22.29mA
2.361V    -12.5mA    -8.438mA   -21.82mA
2.668V    -7.5mA     -6.748mA   -9.821mA
[Ramp]
R_load=50.000Ohm
dV/dt_r   438.159mV/108.000ps  416.865mV/132.500ps  469.503mV/91.500ps
dV/dt_f   438.159mV/121.500ps  416.835mV/146.000ps  469.503mV/105.000ps
[Rising waveform]
R_fixture=50.000Ohm
V_fixture=1.350
V_fixture_min=1.283
V_fixture_max=1.450
0s        627.3mV    595.2mV    686.2mV
39ps      640.2mV    592.7mV    722.8mV
68ps      696.5mV    592.3mV    879.3mV
125ps     1.001V     604.7mV    1.262V
154ps     1.147V     629.1mV    1.353V
192ps     1.256V     711.1mV    1.408V
288ps     1.335V     1.097V     1.444V
365ps     1.346V     1.234V     1.449V
518ps     1.35V      1.278V     1.45V
938ps     1.35V      1.283V     1.45V
[Rising waveform]
R_fixture=50.000Ohm
V_fixture=0
0s        60.28mV    51.2mV     83.73mV
48ps      59.56mV    48.7mV     115mV
87ps      120.8mV    44.62mV    280.5mV
135ps     297.4mV    40.7mV     540.9mV
173ps     458.2mV    55.25mV    687mV
259ps     689.6mV    229.8mV    839mV
355ps     778.1mV    523.1mV    882.1mV
460ps     803.5mV    685.1mV    893.6mV
614ps     811.7mV    746.2mV    897.7mV
938ps     814.1mV    759.4mV    898.2mV
[Falling waveform]
R_fixture=50.000Ohm
V_fixture=1.350
V_fixture_min=1.283
V_fixture_max=1.450
0s        1.355V     1.282V     1.455V
48ps      1.362V     1.285V     1.446V
96ps      1.305V     1.293V     1.302V
192ps     990.7mV    1.264V     919.6mV
240ps     851.5mV    1.179V     811.1mV
288ps     759.3mV    1.049V     754.1mV
393ps     673.8mV    794.5mV    708.8mV
499ps     649.3mV    670.2mV    698.7mV
652ps     640.7mV    620.2mV    695.6mV
938ps     638.3mV    605.5mV    694.4mV
[Falling waveform]
R_fixture=50.000Ohm
V_fixture=0
0s        826.3mV    765.2mV    906.5mV
29ps      815.4mV    769.5mV    881.4mV
48ps      783.3mV    772.4mV    809.8mV
77ps      679.1mV    774.3mV    618.2mV
125ps     415.9mV    749.7mV    320.6mV
163ps     252.4mV    674.9mV    199.6mV
211ps     145.8mV    498.3mV    134.2mV
288ps     88.36mV    210.8mV    101.1mV
374ps     72.66mV    94.51mV    91.93mV
938ps     65.88mV    51.27mV    89.1mV
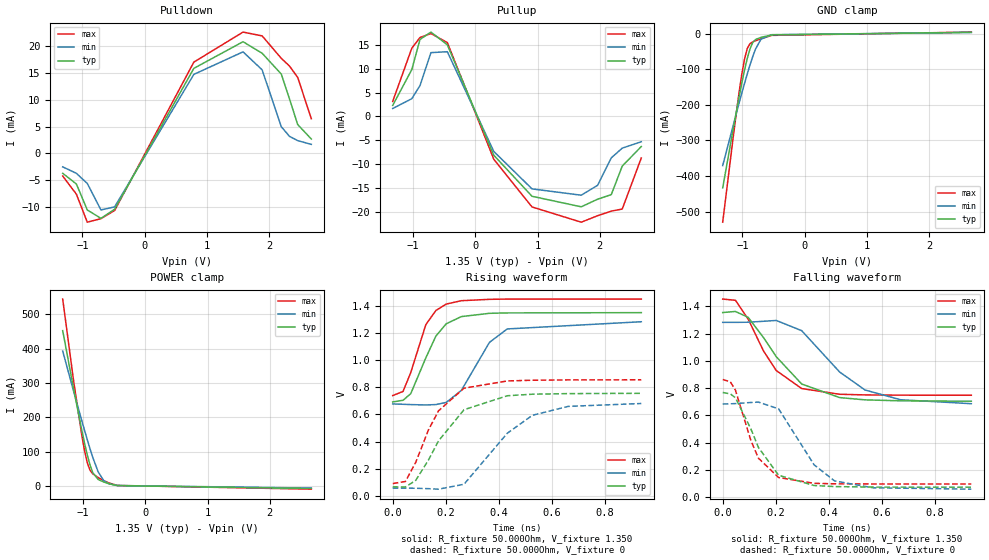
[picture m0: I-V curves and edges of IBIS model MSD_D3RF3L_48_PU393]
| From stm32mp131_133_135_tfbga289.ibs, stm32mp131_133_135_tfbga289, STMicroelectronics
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[Model] MSD_D3RF3L_48_PU393
Model_type   I/O
C_comp 2.367pF   2.282pF   2.491pF
Vinh = 810.000mV
Vinl = 540.000mV
Vmeas = 675.000mV
Vref = 675.000mV
[Model Spec]
Vinh   810.000mV   777.000mV   860.000mV
Vinl   540.000mV   507.000mV   590.000mV
Vmeas   675.000mV   642.000mV   725.000mV
Vref   675.000mV   642.000mV   725.000mV
[Receiver Thresholds]
Vth   =  0.675V
Vth_min  =  0.6615V
Vth_max  =  0.6885V
Vinh_ac  =  0.160V
Vinh_dc  =  0.090V
Vinl_ac  = -0.160V
Vinl_dc  = -0.090V
Tslew_ac =  5.000ns |Not specified, so set to high value
Threshold_sensitivity = 0.50
Reference_supply Pullup_ref
[Temperature Range]   25.000   125.000   -40.000
[Voltage Range]   1.350V   1.283V   1.450V
[GND Clamp Reference]   0.00V   0.00V   0.00V
[Pulldown Reference]   0.00V   0.00V   0.00V
[POWER Clamp Reference]   1.350V   1.283V   1.450V
[Pullup Reference]   1.350V   1.283V   1.450V
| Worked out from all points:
|   slope of the pulldown table from 0 to 0.203 V, typ, clamps not added: 42.2 ohm
|   slope of the pullup table from 0 to 0.203 V, typ, clamps not added: 34.5 ohm
|   GND clamp passes 1 mA (typ) near -0.41 V on its own axis
|   POWER clamp passes 1 mA (typ) near -0.41 V on its own axis
|   rising waveform, R_fixture 50.000Ohm, V_fixture 1.350: 20-80 % time 90ps typ, 114ps min, 74.8ps max; typ from 0.693 V to 1.35 V
|   rising waveform, R_fixture 50.000Ohm, V_fixture 0: 20-80 % time 140ps typ, 172ps min, 117ps max; typ from 0.068 V to 0.756 V
|   falling waveform, R_fixture 50.000Ohm, V_fixture 1.350: 20-80 % time 160ps typ, 191ps min, 127ps max; typ from 1.35 V to 0.703 V
|   falling waveform, R_fixture 50.000Ohm, V_fixture 0: 20-80 % time 104ps typ, 123ps min, 85ps max; typ from 0.767 V to 0.072 V
[GND Clamp]
-1.318V   -433mA     -370.4mA   -529.2mA
-1.142V   -260.8mA   -252.9mA   -280.4mA
-1.055V   -178.3mA   -195.3mA   -165.4mA
-1.011V   -139.2mA   -167.3mA   -114.3mA
-966.7mV  -102.4mA   -139.8mA   -71.44mA
-922.7mV  -69.62mA   -113.3mA   -41.82mA
-878.8mV  -43.01mA   -87.99mA   -28.44mA
-834.9mV  -25.43mA   -64.57mA   -23.51mA
-790.9mV  -16.93mA   -43.94mA   -20.33mA
-703mV    -10.83mA   -16.02mA   -14.7mA
-527.3mV  -3.907mA   -3.3mA     -5.218mA
2.68V     3.366mA    2.86mA     3.981mA
[Power Clamp]
-1.33V    452.4mA    393mA      544.2mA
-1.155V   283.3mA    276.3mA    306.7mA
-1.023V   162.4mA    190.5mA    148.2mA
-978.8mV  125.2mA    162.6mA    103.6mA
-934.9mV  91.22mA    135.3mA    68.17mA
-890.9mV  61.85mA    109mA      46.56mA
-847mV    39.54mA    84.01mA    36.1mA
-759.1mV  19.58mA    41.61mA    25.09mA
-671.2mV  12.36mA    16.39mA    16.46mA
-583.3mV  7.075mA    7.103mA    9.355mA
-451.5mV  1.823mA    2.063mA    2.279mA
2.668V    -6.637mA   -5.319mA   -8.53mA
[Pulldown]
-1.318V   -3.7mA     -2.5mA     -4.2mA
-1.098V   -5.7mA     -3.7mA     -7.6mA
-922.7mV  -10.55mA   -5.6mA     -12.83mA
-703mV    -12.11mA   -10.54mA   -12.17mA
-483.3mV  -10.41mA   -9.974mA   -10.65mA
790.9mV   15.9mA     14.77mA    17.06mA
1.582V    20.87mA    18.98mA    22.67mA
1.889V    18.72mA    15.62mA    21.96mA
2.197V    14.83mA    5mA        17.77mA
2.329V    10.2mA     3.2mA      16.33mA
2.461V    5.4mA      2.4mA      14.2mA
2.68V     2.7mA      1.7mA      6.5mA
[Pullup]
-1.33V    2.3mA      1.652mA    3.135mA
-1.023V   9.8mA      3.715mA    14.27mA
-890.9mV  16.12mA    6.461mA    16.52mA
-715.1mV  17.65mA    13.35mA    17.34mA
-451.5mV  14.99mA    13.54mA    15.46mA
295.4mV   -8.125mA   -7.33mA    -8.963mA
910.6mV   -16.72mA   -15.17mA   -18.95mA
1.702V    -18.92mA   -16.49mA   -22.14mA
1.965V    -17.33mA   -14.42mA   -20.78mA
2.185V    -16.37mA   -8.675mA   -19.82mA
2.361V    -10.4mA    -6.643mA   -19.39mA
2.668V    -6.3mA     -5.3mA     -8.693mA
[Ramp]
R_load=50.000Ohm
dV/dt_r   399.411mV/114.500ps  368.340mV/144.000ps  439.011mV/96.500ps
dV/dt_f   399.411mV/131.500ps  368.310mV/159.500ps  438.981mV/106.000ps
[Rising waveform]
R_fixture=50.000Ohm
V_fixture=1.350
V_fixture_min=1.283
V_fixture_max=1.450
0s        692.7mV    677.9mV    739.2mV
39ps      704.6mV    675.2mV    769.7mV
68ps      753.3mV    673mV      908.4mV
125ps     1.017V     670.1mV    1.262V
163ps     1.178V     673.2mV    1.366V
202ps     1.268V     688.9mV    1.413V
259ps     1.321V     777.4mV    1.438V
365ps     1.345V     1.131V     1.448V
432ps     1.348V     1.23V      1.45V
938ps     1.35V      1.283V     1.45V
[Rising waveform]
R_fixture=50.000Ohm
V_fixture=0
0s        67.54mV    57.8mV     91.46mV
48ps      65.81mV    57.68mV    106.8mV
87ps      115.3mV    56.83mV    248.2mV
135ps     265.1mV    53.85mV    486.9mV
173ps     405.9mV    50.15mV    627.3mV
269ps     635.1mV    86.22mV    793.7mV
432ps     738mV      461.4mV    847mV
527ps     749.4mV    594.1mV    852.3mV
662ps     753.8mV    659.6mV    854.8mV
938ps     755.9mV    681mV      855.4mV
[Falling waveform]
R_fixture=50.000Ohm
V_fixture=1.350
V_fixture_min=1.283
V_fixture_max=1.450
0s        1.354V     1.282V     1.453V
48ps      1.362V     1.282V     1.444V
96ps      1.319V     1.283V     1.306V
154ps     1.17V      1.29V      1.072V
202ps     1.03V      1.296V     928.4mV
298ps     829.4mV    1.221V     796mV
441ps     729.9mV    917.9mV    754.2mV
537ps     713.1mV    785.4mV    749.4mV
671ps     706mV      714mV      747.6mV
938ps     703.1mV    684.9mV    746.9mV
[Falling waveform]
R_fixture=50.000Ohm
V_fixture=0
0s        767.3mV    682.8mV    862.8mV
29ps      756.9mV    684.1mV    845.1mV
48ps      728.3mV    685.7mV    784.3mV
106ps     500.8mV    693.8mV    416.6mV
135ps     363.3mV    696.7mV    284.5mV
211ps     159.5mV    647mV      142.8mV
345ps     84.28mV    235.8mV    100.5mV
422ps     76.53mV    118.1mV    96.85mV
566ps     72.8mV     67.86mV    95.64mV
938ps     72.16mV    57.55mV    95.44mV
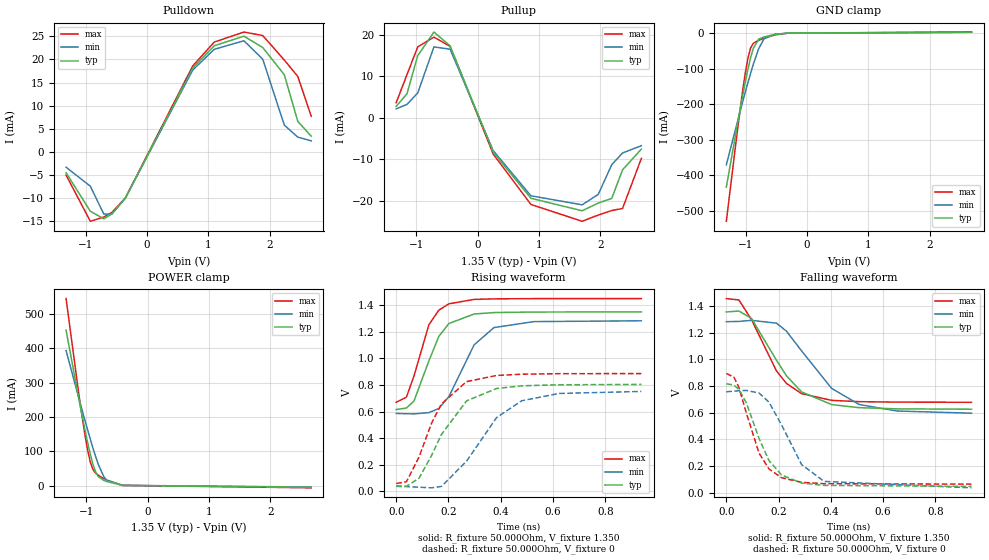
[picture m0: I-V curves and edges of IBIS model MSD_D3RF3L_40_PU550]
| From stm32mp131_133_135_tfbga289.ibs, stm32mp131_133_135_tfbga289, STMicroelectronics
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[Model] MSD_D3RF3L_40_PU550
Model_type   I/O
C_comp 2.425pF   2.340pF   2.550pF
Vinh = 810.000mV
Vinl = 540.000mV
Vmeas = 675.000mV
Vref = 675.000mV
[Model Spec]
Vinh   810.000mV   777.000mV   860.000mV
Vinl   540.000mV   507.000mV   590.000mV
Vmeas   675.000mV   642.000mV   725.000mV
Vref   675.000mV   642.000mV   725.000mV
[Receiver Thresholds]
Vth   =  0.675V
Vth_min  =  0.6615V
Vth_max  =  0.6885V
Vinh_ac  =  0.160V
Vinh_dc  =  0.090V
Vinl_ac  = -0.160V
Vinl_dc  = -0.090V
Tslew_ac =  5.000ns |Not specified, so set to high value
Threshold_sensitivity = 0.50
Reference_supply Pullup_ref
[Temperature Range]   25.000   125.000   -40.000
[Voltage Range]   1.350V   1.283V   1.450V
[GND Clamp Reference]   0.00V   0.00V   0.00V
[Pulldown Reference]   0.00V   0.00V   0.00V
[POWER Clamp Reference]   1.350V   1.283V   1.450V
[Pullup Reference]   1.350V   1.283V   1.450V
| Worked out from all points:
|   slope of the pulldown table from 0 to 0.203 V, typ, clamps not added: 35.7 ohm
|   slope of the pullup table from 0 to 0.203 V, typ, clamps not added: 29.7 ohm
|   GND clamp passes 1 mA (typ) near -0.40 V on its own axis
|   POWER clamp passes 1 mA (typ) near -0.41 V on its own axis
|   rising waveform, R_fixture 50.000Ohm, V_fixture 1.350: 20-80 % time 86.8ps typ, 109ps min, 73.7ps max; typ from 0.615 V to 1.35 V
|   rising waveform, R_fixture 50.000Ohm, V_fixture 0: 20-80 % time 135ps typ, 161ps min, 116ps max; typ from 0.042 V to 0.804 V
|   falling waveform, R_fixture 50.000Ohm, V_fixture 1.350: 20-80 % time 147ps typ, 176ps min, 128ps max; typ from 1.35 V to 0.626 V
|   falling waveform, R_fixture 50.000Ohm, V_fixture 0: 20-80 % time 98.2ps typ, 116ps min, 84.8ps max; typ from 0.817 V to 0.048 V
[GND Clamp]
-1.318V   -433.6mA   -370.9mA   -529.9mA
-1.142V   -261.3mA   -253.2mA   -281mA
-1.055V   -178.7mA   -195.7mA   -165.9mA
-1.011V   -139.6mA   -167.6mA   -114.8mA
-966.7mV  -102.8mA   -140.1mA   -71.88mA
-922.7mV  -69.94mA   -113.6mA   -42.23mA
-878.8mV  -43.31mA   -88.24mA   -28.81mA
-790.9mV  -17.16mA   -44.13mA   -20.63mA
-703mV    -11.02mA   -16.16mA   -14.93mA
-527.3mV  -3.992mA   -3.373mA   -5.331mA
-307.6mV  -127.2uA   -185uA     -115.4uA
2.68V     2.404mA    2.042mA    2.844mA
[Power Clamp]
-1.33V    453mA      393.5mA    545mA
-1.111V   242.5mA    247.8mA    251.5mA
-1.023V   162.8mA    190.8mA    148.6mA
-978.8mV  125.6mA    162.8mA    104.1mA
-934.9mV  91.53mA    135.6mA    68.58mA
-890.9mV  62.14mA    109.2mA    46.94mA
-847mV    39.8mA     84.23mA    36.44mA
-803mV    26.44mA    61.41mA    30.34mA
-715.1mV  15.75mA    26.63mA    20.83mA
-671.2mV  12.52mA    16.53mA    16.67mA
-407.6mV  924.4uA    1.209mA    1.119mA
2.668V    -4.735mA   -3.8mA     -6.092mA
[Pulldown]
-1.318V   -4.5mA     -3.3mA     -5mA
-922.7mV  -12.81mA   -7.4mA     -14.98mA
-703mV    -14.45mA   -13.42mA   -14.07mA
-571.2mV  -13.38mA   -13.44mA   -13.08mA
-351.5mV  -9.986mA   -9.957mA   -9.952mA
747mV     18.14mA    17.69mA    18.58mA
1.098V    22.94mA    22.18mA    23.74mA
1.582V    25.02mA    24.02mA    25.91mA
1.889V    22.57mA    20.05mA    25.16mA
2.241V    16.68mA    5.8mA      19.86mA
2.461V    6.6mA      3.2mA      16.3mA
2.68V     3.4mA      2.4mA      7.7mA
[Pullup]
-1.33V    2.8mA      2.205mA    3.679mA
-1.155V   5.8mA      3.257mA    10.41mA
-978.8mV  15mA       6.025mA    17.12mA
-715.1mV  20.69mA    17.11mA    19.47mA
-451.5mV  17.37mA    16.56mA    17.25mA
251.5mV   -8.249mA   -7.87mA    -8.718mA
866.7mV   -19.34mA   -18.75mA   -20.84mA
1.702V    -22.37mA   -20.93mA   -24.89mA
1.965V    -20.5mA    -18.41mA   -23.39mA
2.185V    -19.39mA   -11.26mA   -22.3mA
2.361V    -12.5mA    -8.438mA   -21.81mA
2.668V    -7.5mA     -6.695mA   -9.748mA
[Ramp]
R_load=50.000Ohm
dV/dt_r   444.384mV/111.000ps  421.713mV/135.500ps  478.074mV/95.500ps
dV/dt_f   444.384mV/123.000ps  421.713mV/148.000ps  478.074mV/106.500ps
[Rising waveform]
R_fixture=50.000Ohm
V_fixture=1.350
V_fixture_min=1.283
V_fixture_max=1.450
0s        615.3mV    586.2mV    669.9mV
39ps      626.8mV    583.6mV    708.3mV
68ps      679.7mV    582.8mV    867.5mV
125ps     980.7mV    592.2mV    1.253V
163ps     1.166V     622.9mV    1.363V
202ps     1.263V     714mV      1.411V
298ps     1.334V     1.102V     1.444V
374ps     1.345V     1.232V     1.448V
527ps     1.349V     1.277V     1.45V
938ps     1.35V      1.283V     1.45V
[Rising waveform]
R_fixture=50.000Ohm
V_fixture=0
0s        42.3mV     37.23mV    59.07mV
39ps      37.84mV    35.64mV    71.73mV
87ps      98.19mV    31.03mV    256.5mV
135ps     268.7mV    26.28mV    511.2mV
173ps     427.7mV    36.75mV    657.3mV
269ps     680.2mV    226.3mV    825.4mV
384ps     773.5mV    554.9mV    871.7mV
480ps     793.8mV    681.4mV    881.1mV
623ps     801.6mV    736.4mV    885.3mV
938ps     804.4mV    751.5mV    886mV
[Falling waveform]
R_fixture=50.000Ohm
V_fixture=1.350
V_fixture_min=1.283
V_fixture_max=1.450
0s        1.355V     1.282V     1.455V
48ps      1.362V     1.284V     1.445V
96ps      1.307V     1.292V     1.298V
192ps     992.7mV    1.271V     912.4mV
230ps     876.4mV    1.211V     819.4mV
288ps     755.6mV    1.063V     743mV
403ps     661mV      782.2mV    692.5mV
508ps     637.8mV    661.5mV    682.7mV
652ps     628.9mV    612.9mV    679.4mV
938ps     626.1mV    596.2mV    678mV
[Falling waveform]
R_fixture=50.000Ohm
V_fixture=0
0s        816.8mV    757mV      894.4mV
29ps      806.6mV    761.3mV    866.4mV
48ps      775mV      764.4mV    790.6mV
77ps      672mV      767mV      594.8mV
125ps     407.8mV    747.7mV    297.7mV
163ps     242mV      679.4mV    178.6mV
211ps     133.1mV    509.5mV    113mV
288ps     72.88mV    211.4mV    78.26mV
374ps     55.47mV    85.15mV    68.07mV
938ps     47.64mV    37.02mV    64.63mV
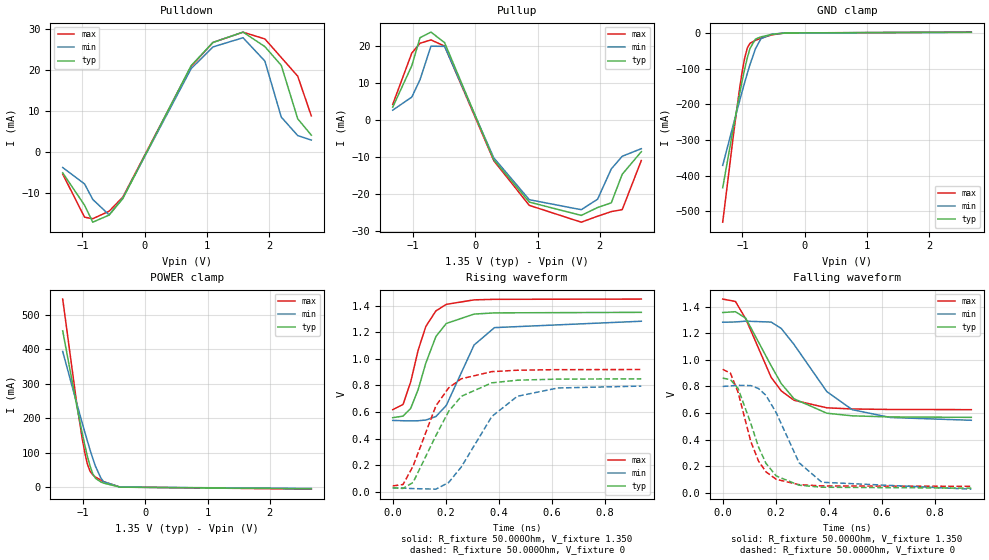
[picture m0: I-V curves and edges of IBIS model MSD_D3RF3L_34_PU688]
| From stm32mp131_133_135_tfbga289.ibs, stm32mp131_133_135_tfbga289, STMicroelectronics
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[Model] MSD_D3RF3L_34_PU688
Model_type   I/O
C_comp 2.455pF   2.369pF   2.579pF
Vinh = 810.000mV
Vinl = 540.000mV
Vmeas = 675.000mV
Vref = 675.000mV
[Model Spec]
Vinh   810.000mV   777.000mV   860.000mV
Vinl   540.000mV   507.000mV   590.000mV
Vmeas   675.000mV   642.000mV   725.000mV
Vref   675.000mV   642.000mV   725.000mV
[Receiver Thresholds]
Vth   =  0.675V
Vth_min  =  0.6615V
Vth_max  =  0.6885V
Vinh_ac  =  0.160V
Vinh_dc  =  0.090V
Vinl_ac  = -0.160V
Vinl_dc  = -0.090V
Tslew_ac =  5.000ns |Not specified, so set to high value
Threshold_sensitivity = 0.50
Reference_supply Pullup_ref
[Temperature Range]   25.000   125.000   -40.000
[Voltage Range]   1.350V   1.283V   1.450V
[GND Clamp Reference]   0.00V   0.00V   0.00V
[Pulldown Reference]   0.00V   0.00V   0.00V
[POWER Clamp Reference]   1.350V   1.283V   1.450V
[Pullup Reference]   1.350V   1.283V   1.450V
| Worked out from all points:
|   slope of the pulldown table from 0 to 0.203 V, typ, clamps not added: 31 ohm
|   slope of the pullup table from 0 to 0.203 V, typ, clamps not added: 26.2 ohm
|   GND clamp passes 1 mA (typ) near -0.40 V on its own axis
|   POWER clamp passes 1 mA (typ) near -0.41 V on its own axis
|   rising waveform, R_fixture 50.000Ohm, V_fixture 1.350: 20-80 % time 82.9ps typ, 105ps min, 72.4ps max; typ from 0.557 V to 1.35 V
|   rising waveform, R_fixture 50.000Ohm, V_fixture 0: 20-80 % time 128ps typ, 153ps min, 113ps max; typ from 0.029 V to 0.849 V
|   falling waveform, R_fixture 50.000Ohm, V_fixture 1.350: 20-80 % time 136ps typ, 168ps min, 119ps max; typ from 1.35 V to 0.567 V
|   falling waveform, R_fixture 50.000Ohm, V_fixture 0: 20-80 % time 92.5ps typ, 113ps min, 81ps max; typ from 0.862 V to 0.035 V
[GND Clamp]
-1.318V   -433.9mA   -371.1mA   -530.2mA
-1.142V   -261.5mA   -253.4mA   -281.4mA
-1.055V   -179mA     -195.9mA   -166.2mA
-1.011V   -139.7mA   -167.8mA   -115mA
-966.7mV  -103mA     -140.2mA   -72.1mA
-922.7mV  -70.1mA    -113.7mA   -42.42mA
-878.8mV  -43.45mA   -88.35mA   -28.99mA
-790.9mV  -17.28mA   -44.22mA   -20.77mA
-703mV    -11.1mA    -16.24mA   -15.04mA
-527.3mV  -4.032mA   -3.409mA   -5.385mA
-307.6mV  -129uA     -188.8uA   -119.4uA
2.68V     1.923mA    1.635mA    2.275mA
[Power Clamp]
-1.33V    453.3mA    393.7mA    545.4mA
-1.111V   242.7mA    248mA      251.8mA
-1.023V   163mA      191mA      148.9mA
-978.8mV  125.8mA    163mA      104.3mA
-934.9mV  91.7mA     135.6mA    68.79mA
-890.9mV  62.29mA    109.3mA    47.13mA
-847mV    39.94mA    84.35mA    36.61mA
-803mV    26.56mA    61.51mA    30.49mA
-715.1mV  15.84mA    26.7mA     20.95mA
-671.2mV  12.6mA     16.6mA     16.77mA
-407.6mV  937.9uA    1.223mA    1.135mA
2.668V    -3.791mA   -3.04mA    -4.872mA
[Pulldown]
-1.318V   -5.2mA     -3.9mA     -5.5mA
-966.7mV  -13.1mA    -7.9mA     -16.02mA
-834.9mV  -17.24mA   -11.68mA   -16.39mA
-571.2mV  -15.5mA    -15.46mA   -14.56mA
-351.5mV  -11.49mA   -11.33mA   -11.11mA
747mV     20.95mA    20.22mA    20.78mA
1.098V    26.62mA    25.53mA    26.63mA
1.582V    29.15mA    27.77mA    29.12mA
1.933V    25.61mA    22.08mA    27.48mA
2.197V    21.03mA    8.4mA      22.94mA
2.461V    8mA        3.9mA      18.4mA
2.68V     4mA        2.8mA      8.7mA
[Pullup]
-1.33V    3.4mA      2.605mA    4.152mA
-1.023V   14.6mA     6.125mA    18.01mA
-890.9mV  22.15mA    10.83mA    20.65mA
-715.1mV  23.67mA    19.86mA    21.56mA
-495.5mV  20.82mA    19.82mA    19.89mA
295.4mV   -10.76mA   -10.27mA   -11.03mA
866.7mV   -22.21mA   -21.56mA   -23.09mA
1.702V    -25.8mA    -24.26mA   -27.63mA
1.965V    -23.67mA   -21.43mA   -26.01mA
2.185V    -22.41mA   -13.26mA   -24.77mA
2.361V    -14.7mA    -9.838mA   -24.24mA
2.668V    -8.6mA     -7.795mA   -10.98mA
[Ramp]
R_load=50.000Ohm
dV/dt_r   479.130mV/105.500ps  452.607mV/129.500ps  508.572mV/93.000ps
dV/dt_f   479.130mV/114.000ps  452.607mV/142.000ps  508.572mV/100.500ps
[Rising waveform]
R_fixture=50.000Ohm
V_fixture=1.350
V_fixture_min=1.283
V_fixture_max=1.450
0s        556.6mV    536.2mV    617.2mV
39ps      568.8mV    533.7mV    656.4mV
68ps      627.6mV    532.7mV    827.1mV
96ps      768.7mV    533.7mV    1.065V
125ps     968mV      539.3mV    1.244V
163ps     1.168V     565.5mV    1.361V
202ps     1.266V     648.6mV    1.41V
307ps     1.337V     1.104V     1.444V
384ps     1.346V     1.235V     1.448V
938ps     1.35V      1.283V     1.45V
[Rising waveform]
R_fixture=50.000Ohm
V_fixture=0
0s        29.16mV    27.99mV    43mV
39ps      24.11mV    26.41mV    53.57mV
77ps      69.49mV    22.87mV    192.6mV
163ps     422mV      18.53mV    646mV
211ps     604.1mV    68.66mV    781.4mV
259ps     717.8mV    186.3mV    849.8mV
374ps     819.2mV    565.9mV    903.5mV
470ps     839mV      717.9mV    914.2mV
623ps     847.2mV    780.4mV    918.6mV
938ps     849.3mV    794.7mV    919.2mV
[Falling waveform]
R_fixture=50.000Ohm
V_fixture=1.350
V_fixture_min=1.283
V_fixture_max=1.450
0s        1.355V     1.282V     1.456V
48ps      1.361V     1.284V     1.438V
87ps      1.312V     1.29V      1.307V
183ps     953.9mV    1.283V     866.9mV
221ps     820.7mV    1.235V     765.7mV
269ps     706.7mV    1.115V     695.7mV
393ps     598.3mV    760.2mV    638.9mV
489ps     578.6mV    624.6mV    630.2mV
633ps     570.4mV    566.1mV    626.4mV
938ps     567.2mV    545.3mV    625.2mV
[Falling waveform]
R_fixture=50.000Ohm
V_fixture=0
0s        862mV      799.3mV    928mV
29ps      850.8mV    803.4mV    899.4mV
58ps      784.9mV    807.8mV    755.1mV
106ps     521.6mV    805.8mV    385.6mV
135ps     344.8mV    783.8mV    239.3mV
163ps     222.3mV    733.2mV    158.3mV
202ps     126.8mV    601.4mV    101.7mV
288ps     57.47mV    226.4mV    61.39mV
374ps     42.19mV    79.5mV     52mV
938ps     35.31mV    27.65mV    48.87mV
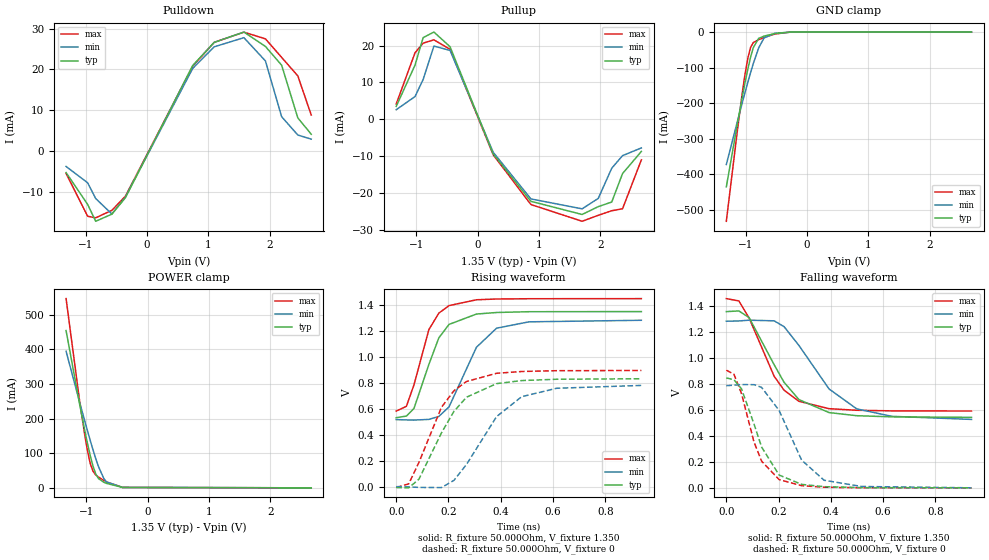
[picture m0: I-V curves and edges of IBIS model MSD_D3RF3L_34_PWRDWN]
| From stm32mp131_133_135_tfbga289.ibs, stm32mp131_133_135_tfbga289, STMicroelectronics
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[Model] MSD_D3RF3L_34_PWRDWN
Model_type   I/O
C_comp 2.572pF   2.485pF   2.698pF
Vinh = 810.000mV
Vinl = 540.000mV
Vmeas = 675.000mV
Vref = 675.000mV
[Model Spec]
Vinh   810.000mV   777.000mV   860.000mV
Vinl   540.000mV   507.000mV   590.000mV
Vmeas   675.000mV   642.000mV   725.000mV
Vref   675.000mV   642.000mV   725.000mV
[Receiver Thresholds]
Vth   =  0.675V
Vth_min  =  0.6615V
Vth_max  =  0.6885V
Vinh_ac  =  0.160V
Vinh_dc  =  0.090V
Vinl_ac  = -0.160V
Vinl_dc  = -0.090V
Tslew_ac =  5.000ns |Not specified, so set to high value
Threshold_sensitivity = 0.50
Reference_supply Pullup_ref
[Temperature Range]   25.000   125.000   -40.000
[Voltage Range]   1.350V   1.283V   1.450V
[GND Clamp Reference]   0.00V   0.00V   0.00V
[Pulldown Reference]   0.00V   0.00V   0.00V
[POWER Clamp Reference]   1.350V   1.283V   1.450V
[Pullup Reference]   1.350V   1.283V   1.450V
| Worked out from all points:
|   slope of the pulldown table from 0 to 0.203 V, typ, clamps not added: 31 ohm
|   slope of the pullup table from 0 to 0.203 V, typ, clamps not added: 26.2 ohm
|   GND clamp passes 1 mA (typ) near -0.40 V on its own axis
|   POWER clamp passes 1 mA (typ) near -0.41 V on its own axis
|   rising waveform, R_fixture 50.000Ohm, V_fixture 1.350: 20-80 % time 86.2ps typ, 108ps min, 77.1ps max; typ from 0.532 V to 1.35 V
|   rising waveform, R_fixture 50.000Ohm, V_fixture 0: 20-80 % time 139ps typ, 162ps min, 125ps max; typ from -0.006 V to 0.832 V
|   falling waveform, R_fixture 50.000Ohm, V_fixture 1.350: 20-80 % time 140ps typ, 171ps min, 124ps max; typ from 1.36 V to 0.542 V
|   falling waveform, R_fixture 50.000Ohm, V_fixture 0: 20-80 % time 94.9ps typ, 115ps min, 83.9ps max; typ from 0.846 V to 0 V
[GND Clamp]
-1.318V   -435mA     -372.2mA   -531.7mA
-1.142V   -262.4mA   -254.2mA   -282.5mA
-1.055V   -179.8mA   -196.6mA   -167.2mA
-1.011V   -140.5mA   -168.4mA   -116mA
-966.7mV  -103.7mA   -140.9mA   -72.98mA
-922.7mV  -70.73mA   -114.2mA   -43.23mA
-878.8mV  -44.02mA   -88.84mA   -29.72mA
-790.9mV  -17.74mA   -44.62mA   -21.37mA
-703mV    -11.46mA   -16.55mA   -15.5mA
-527.3mV  -4.197mA   -3.553mA   -5.598mA
-263.6mV  -40.6uA    -78.9uA    -28.72uA
2.68V     28.25nA    782nA      4.355nA
[Power Clamp]
-1.33V    454.4mA    394.7mA    546.8mA
-1.111V   243.5mA    248.7mA    252.9mA
-1.023V   163.7mA    191.5mA    149.8mA
-978.8mV  126.5mA    163.6mA    105.2mA
-934.9mV  92.34mA    136.2mA    69.61mA
-890.9mV  62.88mA    109.8mA    47.89mA
-847mV    40.47mA    84.8mA     37.29mA
-803mV    27.03mA    61.92mA    31.1mA
-715.1mV  16.21mA    27.03mA    21.42mA
-671.2mV  12.92mA    16.88mA    17.18mA
-407.6mV  989.1uA    1.283mA    1.2mA
2.668V    -48.24nA   -903.5nA   -4.583nA
[Pulldown]
-1.318V   -5.3mA     -3.8mA     -5.5mA
-966.7mV  -13.1mA    -7.8mA     -16.01mA
-834.9mV  -17.24mA   -11.67mA   -16.39mA
-571.2mV  -15.49mA   -15.46mA   -14.56mA
-351.5mV  -11.48mA   -11.33mA   -11.1mA
747mV     20.95mA    20.23mA    20.78mA
1.098V    26.62mA    25.53mA    26.63mA
1.582V    29.15mA    27.77mA    29.12mA
1.933V    25.62mA    22.07mA    27.48mA
2.197V    21.03mA    8.4mA      22.94mA
2.461V    8.1mA      3.9mA      18.4mA
2.68V     4.1mA      2.9mA      8.8mA
[Pullup]
-1.33V    3.5mA      2.605mA    4.152mA
-1.023V   14.7mA     6.177mA    18.04mA
-890.9mV  22.15mA    10.8mA     20.65mA
-715.1mV  23.66mA    19.86mA    21.55mA
-451.5mV  19.67mA    18.67mA    18.98mA
251.5mV   -9.374mA   -8.925mA   -9.602mA
866.7mV   -22.22mA   -21.57mA   -23.09mA
1.702V    -25.79mA   -24.26mA   -27.63mA
1.965V    -23.66mA   -21.43mA   -26.01mA
2.185V    -22.41mA   -13.25mA   -24.77mA
2.361V    -14.7mA    -9.838mA   -24.24mA
2.668V    -8.7mA     -7.748mA   -10.98mA
[Ramp]
R_load=50.000Ohm
dV/dt_r   492.120mV/113.000ps  462.689mV/135.000ps  526.590mV/101.500ps
dV/dt_f   492.120mV/117.500ps  462.689mV/144.000ps  526.590mV/104.000ps
[Rising waveform]
R_fixture=50.000Ohm
V_fixture=1.350
V_fixture_min=1.283
V_fixture_max=1.450
0s        532.1mV    517.5mV    583mV
39ps      544.7mV    515mV      619.6mV
68ps      603.6mV    513.7mV    785.6mV
125ps     942.9mV    519mV      1.211V
163ps     1.147V     541.8mV    1.338V
202ps     1.251V     615.1mV    1.396V
307ps     1.331V     1.075V     1.441V
384ps     1.343V     1.222V     1.447V
508ps     1.349V     1.271V     1.449V
938ps     1.35V      1.283V     1.45V
[Rising waveform]
R_fixture=50.000Ohm
V_fixture=0
0s        -6.207mV   775.4uV    -5.773mV
48ps      -8.52mV    -1.234mV   22.37mV
87ps      58.48mV    -5.313mV   187.6mV
173ps     414.4mV    -6.698mV   611.6mV
221ps     581.4mV    49.26mV    740.1mV
269ps     690.1mV    172mV      811.4mV
384ps     794.6mV    540.5mV    874.3mV
480ps     818.3mV    693.9mV    888.2mV
614ps     828.4mV    758.9mV    894.4mV
938ps     832.3mV    780.8mV    896mV
[Falling waveform]
R_fixture=50.000Ohm
V_fixture=1.350
V_fixture_min=1.283
V_fixture_max=1.450
0s        1.356V     1.282V     1.456V
48ps      1.361V     1.284V     1.438V
87ps      1.31V      1.29V      1.307V
183ps     947.3mV    1.285V     858.1mV
221ps     811.7mV    1.24V      751.2mV
278ps     678.7mV    1.095V     665.7mV
393ps     579.1mV    760.8mV    609mV
499ps     555mV      607.4mV    596.9mV
633ps     546.2mV    550.2mV    592.2mV
938ps     542.3mV    526.4mV    590.9mV
[Falling waveform]
R_fixture=50.000Ohm
V_fixture=0
0s        845.5mV    785.9mV    905mV
29ps      832.2mV    790mV      874.7mV
58ps      761.3mV    794.6mV    725.6mV
106ps     490.4mV    793.8mV    351.9mV
135ps     314mV      772.9mV    205.2mV
202ps     98.51mV    595.1mV    63.08mV
288ps     26.51mV    213.6mV    16.69mV
374ps     8.78mV     58.4mV     4.638mV
518ps     1.484mV    10.34mV    665.5uV
938ps     31.09uV    167.6uV    -8.164uV
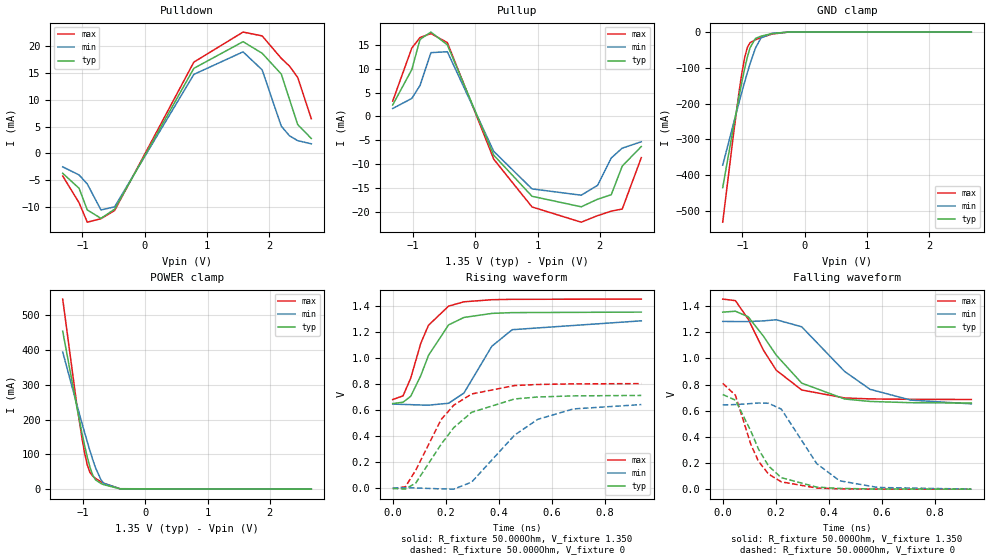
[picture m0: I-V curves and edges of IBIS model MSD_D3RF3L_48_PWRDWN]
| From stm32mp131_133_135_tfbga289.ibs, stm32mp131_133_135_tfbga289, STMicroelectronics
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[Model] MSD_D3RF3L_48_PWRDWN
Model_type   I/O
C_comp 2.572pF   2.485pF   2.698pF
Vinh = 810.000mV
Vinl = 540.000mV
Vmeas = 675.000mV
Vref = 675.000mV
[Model Spec]
Vinh   810.000mV   777.000mV   860.000mV
Vinl   540.000mV   507.000mV   590.000mV
Vmeas   675.000mV   642.000mV   725.000mV
Vref   675.000mV   642.000mV   725.000mV
[Receiver Thresholds]
Vth   =  0.675V
Vth_min  =  0.6615V
Vth_max  =  0.6885V
Vinh_ac  =  0.160V
Vinh_dc  =  0.090V
Vinl_ac  = -0.160V
Vinl_dc  = -0.090V
Tslew_ac =  5.000ns |Not specified, so set to high value
Threshold_sensitivity = 0.50
Reference_supply Pullup_ref
[Temperature Range]   25.000   125.000   -40.000
[Voltage Range]   1.350V   1.283V   1.450V
[GND Clamp Reference]   0.00V   0.00V   0.00V
[Pulldown Reference]   0.00V   0.00V   0.00V
[POWER Clamp Reference]   1.350V   1.283V   1.450V
[Pullup Reference]   1.350V   1.283V   1.450V
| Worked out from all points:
|   slope of the pulldown table from 0 to 0.203 V, typ, clamps not added: 42.2 ohm
|   slope of the pullup table from 0 to 0.203 V, typ, clamps not added: 34.5 ohm
|   GND clamp passes 1 mA (typ) near -0.40 V on its own axis
|   POWER clamp passes 1 mA (typ) near -0.41 V on its own axis
|   rising waveform, R_fixture 50.000Ohm, V_fixture 1.350: 20-80 % time 97.8ps typ, 120ps min, 83.7ps max; typ from 0.648 V to 1.35 V
|   rising waveform, R_fixture 50.000Ohm, V_fixture 0: 20-80 % time 163ps typ, 193ps min, 142ps max; typ from -0.004 V to 0.71 V
|   falling waveform, R_fixture 50.000Ohm, V_fixture 1.350: 20-80 % time 170ps typ, 199ps min, 138ps max; typ from 1.35 V to 0.658 V
|   falling waveform, R_fixture 50.000Ohm, V_fixture 0: 20-80 % time 108ps typ, 126ps min, 91.5ps max; typ from 0.724 V to 0 V
[GND Clamp]
-1.318V   -435mA     -372.2mA   -531.7mA
-1.142V   -262.4mA   -254.2mA   -282.5mA
-1.055V   -179.8mA   -196.6mA   -167.2mA
-1.011V   -140.5mA   -168.4mA   -116mA
-966.7mV  -103.7mA   -140.9mA   -72.98mA
-922.7mV  -70.73mA   -114.2mA   -43.23mA
-878.8mV  -44.02mA   -88.84mA   -29.72mA
-790.9mV  -17.74mA   -44.62mA   -21.37mA
-703mV    -11.46mA   -16.55mA   -15.5mA
-527.3mV  -4.197mA   -3.553mA   -5.598mA
-263.6mV  -40.6uA    -78.9uA    -28.72uA
2.68V     28.25nA    782nA      4.355nA
[Power Clamp]
-1.33V    454.4mA    394.7mA    546.8mA
-1.111V   243.5mA    248.7mA    252.9mA
-1.023V   163.7mA    191.5mA    149.8mA
-978.8mV  126.5mA    163.6mA    105.2mA
-934.9mV  92.34mA    136.2mA    69.61mA
-890.9mV  62.88mA    109.8mA    47.89mA
-847mV    40.47mA    84.8mA     37.29mA
-803mV    27.03mA    61.92mA    31.1mA
-715.1mV  16.21mA    27.03mA    21.42mA
-671.2mV  12.92mA    16.88mA    17.18mA
-407.6mV  989.1uA    1.283mA    1.2mA
2.668V    -48.24nA   -903.5nA   -4.583nA
[Pulldown]
-1.318V   -3.7mA     -2.5mA     -4.2mA
-1.055V   -6.5mA     -4mA       -9.2mA
-922.7mV  -10.54mA   -5.7mA     -12.83mA
-703mV    -12.11mA   -10.54mA   -12.18mA
-483.3mV  -10.4mA    -9.969mA   -10.66mA
790.9mV   15.9mA     14.77mA    17.06mA
1.582V    20.88mA    18.98mA    22.67mA
1.889V    18.72mA    15.62mA    21.96mA
2.197V    14.83mA    5.1mA      17.77mA
2.329V    10.1mA     3.3mA      16.32mA
2.461V    5.4mA      2.4mA      14.2mA
2.68V     2.8mA      1.8mA      6.5mA
[Pullup]
-1.33V    2.4mA      1.652mA    3.207mA
-1.023V   9.8mA      3.767mA    14.3mA
-890.9mV  16.12mA    6.477mA    16.51mA
-715.1mV  17.65mA    13.35mA    17.34mA
-451.5mV  14.98mA    13.54mA    15.46mA
295.4mV   -8.125mA   -7.33mA    -8.964mA
910.6mV   -16.72mA   -15.17mA   -18.95mA
1.702V    -18.92mA   -16.49mA   -22.14mA
1.965V    -17.33mA   -14.42mA   -20.77mA
2.185V    -16.38mA   -8.694mA   -19.82mA
2.361V    -10.4mA    -6.643mA   -19.39mA
2.668V    -6.3mA     -5.3mA     -8.621mA
[Ramp]
R_load=50.000Ohm
dV/dt_r   421.110mV/131.500ps  384.659mV/159.000ps  469.710mV/113.000ps
dV/dt_f   421.110mV/139.500ps  384.628mV/165.500ps  469.710mV/115.500ps
[Rising waveform]
R_fixture=50.000Ohm
V_fixture=1.350
V_fixture_min=1.283
V_fixture_max=1.450
0s        648.1mV    643.8mV    678.6mV
39ps      658.3mV    641.6mV    707.2mV
68ps      703.8mV    639.6mV    843.3mV
106ps     862.5mV    636.9mV    1.111V
135ps     1.018V     635.7mV    1.249V
211ps     1.252V     650.3mV    1.396V
269ps     1.309V     729.4mV    1.429V
374ps     1.34V      1.088V     1.445V
451ps     1.346V     1.215V     1.448V
938ps     1.35V      1.283V     1.45V
[Rising waveform]
R_fixture=50.000Ohm
V_fixture=0
0s        -4.232mV   633uV      -3.884mV
48ps      -7.762mV   821.8uV    9.786mV
87ps      38.15mV    414uV      137.1mV
183ps     336.4mV    -6.982mV   526.2mV
230ps     462.6mV    -8.983mV   635mV
298ps     581.1mV    45.43mV    721.7mV
460ps     683.4mV    406.1mV    786.3mV
547ps     698.5mV    526.7mV    794.4mV
681ps     706.9mV    606.7mV    799.1mV
938ps     710.4mV    640.2mV    801.1mV
[Falling waveform]
R_fixture=50.000Ohm
V_fixture=1.350
V_fixture_min=1.283
V_fixture_max=1.450
0s        1.354V     1.283V     1.454V
48ps      1.361V     1.282V     1.442V
96ps      1.319V     1.282V     1.301V
154ps     1.169V     1.287V     1.062V
202ps     1.025V     1.296V     909.8mV
298ps     811.1mV    1.242V     758.5mV
460ps     689.7mV    900.3mV    697.5mV
556ps     670.9mV    763.6mV    690.4mV
710ps     661.4mV    681mV      687.2mV
938ps     658.5mV    652.6mV    685.9mV
[Falling waveform]
R_fixture=50.000Ohm
V_fixture=0
0s        723.8mV    644.7mV    809.4mV
48ps      681mV      646.8mV    718.5mV
106ps     445.5mV    654.7mV    342.9mV
135ps     306.2mV    659mV      213.3mV
173ps     176.9mV    656.8mV    115.4mV
221ps     88.06mV    612.5mV    56.09mV
355ps     15.77mV    194.7mV    8.458mV
441ps     5.686mV    64.15mV    2.579mV
585ps     1.049mV    12.94mV    286.3uV
938ps     52.66uV    419.1uV    -1.994uV
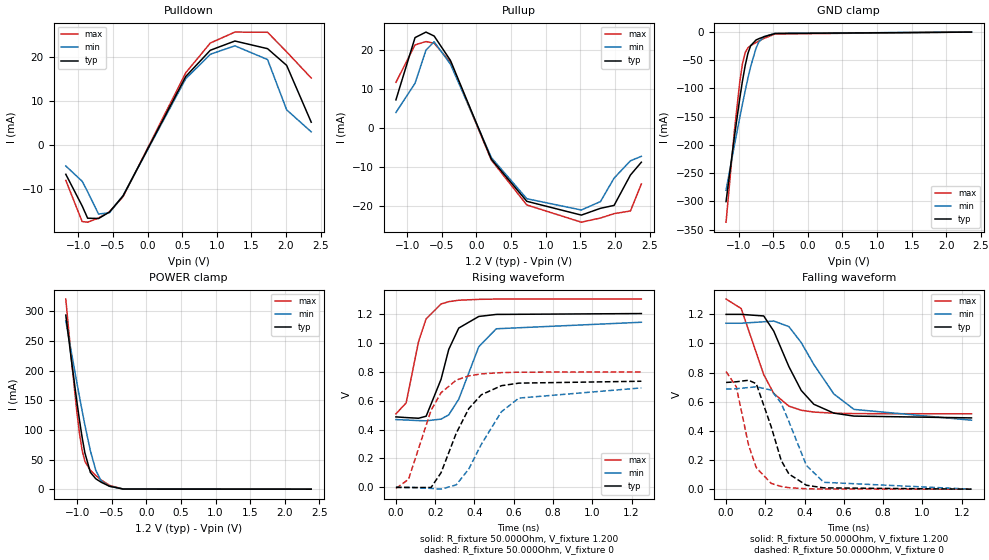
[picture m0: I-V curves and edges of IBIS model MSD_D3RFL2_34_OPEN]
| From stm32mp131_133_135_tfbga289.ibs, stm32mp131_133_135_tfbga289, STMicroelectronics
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[Model] MSD_D3RFL2_34_OPEN
Model_type   I/O
C_comp 2.581pF   2.493pF   2.708pF
Vinh = 820.000mV
Vinl = 380.000mV
Vmeas = 600.000mV
Vref = 600.000mV
[Model Spec]
Vinh   820.000mV   790.000mV   870.000mV
Vinl   380.000mV   350.000mV   430.000mV
Vmeas   600.000mV   570.000mV   650.000mV
Vref   600.000mV   570.000mV   650.000mV
[Receiver Thresholds]
Vth   =  0.600V
Vth_min  =  0.5880V
Vth_max  =  0.6120V
Vinh_ac  =  0.220V
Vinh_dc  =  0.130V
Vinl_ac  = -0.220V
Vinl_dc  = -0.130V
Tslew_ac =  5.000ns |Not specified, so set to high value
[Temperature Range]   25.000   125.000   -40.000
[Voltage Range]   1.200V   1.140V   1.300V
[GND Clamp Reference]   0.00V   0.00V   0.00V
[Pulldown Reference]   0.00V   0.00V   0.00V
[POWER Clamp Reference]   1.200V   1.140V   1.300V
[Pullup Reference]   1.200V   1.140V   1.300V
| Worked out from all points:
|   slope of the pulldown table from 0 to 0.18 V, typ, clamps not added: 31.3 ohm
|   slope of the pullup table from 0 to 0.18 V, typ, clamps not added: 26.5 ohm
|   GND clamp passes 1 mA (typ) near -0.40 V on its own axis
|   POWER clamp passes 1 mA (typ) near -0.41 V on its own axis
|   rising waveform, R_fixture 50.000Ohm, V_fixture 1.200: 20-80 % time 93.1ps typ, 119ps min, 79.7ps max; typ from 0.487 V to 1.2 V
|   rising waveform, R_fixture 50.000Ohm, V_fixture 0: 20-80 % time 151ps typ, 181ps min, 131ps max; typ from 0.001 V to 0.733 V
|   falling waveform, R_fixture 50.000Ohm, V_fixture 1.200: 20-80 % time 157ps typ, 201ps min, 132ps max; typ from 1.2 V to 0.489 V
|   falling waveform, R_fixture 50.000Ohm, V_fixture 0: 20-80 % time 101ps typ, 126ps min, 87.3ps max; typ from 0.732 V to 0 V
[GND Clamp]
-1.182V   -300.5mA   -280.4mA   -337mA
-1.064V   -188.1mA   -202.5mA   -178.5mA
-984.9mV  -118.6mA   -152.2mA   -89.49mA
-945.5mV  -87.16mA   -127.9mA   -56.6mA
-906.1mV  -59.71mA   -104.4mA   -36.4mA
-866.7mV  -38.14mA   -82.14mA   -27.92mA
-827.3mV  -24.29mA   -61.54mA   -24.05mA
-748.5mV  -14mA      -28.45mA   -18.47mA
-709.1mV  -11.76mA   -17.8mA    -15.89mA
-630.3mV  -8.132mA   -7.75mA    -11.05mA
-472.7mV  -2.557mA   -2.242mA   -3.323mA
2.364V    29.58nA    484.6nA    2.864nA
[Power Clamp]
-1.164V   293.6mA    283.6mA    320.6mA
-1.085V   219.6mA    231.9mA    221.3mA
-1.006V   149.3mA    180.9mA    132.2mA
-966.7mV  116.7mA    156mA      94.33mA
-927.3mV  86.87mA    131.6mA    64.9mA
-887.9mV  61.07mA    108mA      46.71mA
-809.1mV  28.38mA    64.84mA    31.83mA
-730.3mV  17.49mA    31.58mA    22.97mA
-651.5mV  11.58mA    13.7mA     15.38mA
-533.3mV  4.956mA    4.897mA    6.46mA
-336.4mV  215.7uA    403.7uA    242.8uA
2.382V    -24.83nA   -515.5nA   -2.721nA
[Pulldown]
-1.182V   -6.7mA     -4.8mA     -8.1mA
-945.5mV  -13.94mA   -8.3mA     -17.51mA
-866.7mV  -16.74mA   -10.69mA   -17.65mA
-709.1mV  -16.81mA   -15.79mA   -16.7mA
-551.5mV  -15.33mA   -15.49mA   -15.28mA
-354.6mV  -11.64mA   -11.56mA   -11.83mA
551.5mV   15.66mA    15.15mA    16.51mA
906.1mV   21.65mA    20.73mA    23.3mA
1.261V    23.76mA    22.66mA    25.8mA
1.733V    22.01mA    19.52mA    25.76mA
2.009V    18.19mA    8.03mA     21.28mA
2.364V    5.2mA      3mA        15.3mA
[Pullup]
-1.164V   7.3mA      4.062mA    11.8mA
-887.9mV  23.28mA    11.56mA    21.41mA
-730.3mV  24.7mA     20.06mA    22.27mA
-612.1mV  23.69mA    22.22mA    21.84mA
-375.8mV  17.41mA    16.45mA    16.97mA
215.2mV   -7.945mA   -7.529mA   -8.167mA
727.3mV   -18.74mA   -18.08mA   -19.68mA
1.515V    -22.28mA   -20.97mA   -24.1mA
1.791V    -20.54mA   -18.81mA   -23.03mA
1.988V    -19.79mA   -12.79mA   -21.91mA
2.224V    -12mA      -8.343mA   -21.22mA
2.382V    -8.7mA     -7.195mA   -14.29mA
[Ramp]
R_load=50.000Ohm
dV/dt_r   433.200mV/123.000ps  406.739mV/151.000ps  474.120mV/105.500ps
dV/dt_f   433.200mV/129.500ps  406.678mV/165.500ps  474.120mV/109.500ps
[Rising waveform]
R_fixture=50.000Ohm
V_fixture=1.200
V_fixture_min=1.140
V_fixture_max=1.300
0s        487mV      468.5mV    507.9mV
52ps      482.4mV    465.6mV    583.3mV
115ps     477.6mV    461.5mV    1.005V
154ps     491.7mV    459.9mV    1.164V
230ps     747.1mV    471.8mV    1.266V
269ps     952.6mV    501.1mV    1.282V
320ps     1.1V       608.9mV    1.292V
422ps     1.18V      971.2mV    1.298V
511ps     1.194V     1.095V     1.3V
1.25ns    1.2V       1.14V      1.3V
[Rising waveform]
R_fixture=50.000Ohm
V_fixture=0
0s        919uV      893.4uV    -6.48mV
64ps      -301.3uV   779uV      55.94mV
179ps     69.52uV    -6.257mV   532.6mV
230ps     102.1mV    -11.64mV   654.1mV
307ps     373.9mV    17.71mV    740.6mV
371ps     544mV      127.5mV    770.2mV
435ps     639.7mV    297.7mV    783.7mV
537ps     702.2mV    522.1mV    792.5mV
626ps     720mV      616.7mV    795.6mV
1.25ns    733mV      687mV      797.4mV
[Falling waveform]
R_fixture=50.000Ohm
V_fixture=1.200
V_fixture_min=1.140
V_fixture_max=1.300
0s        1.2V       1.139V     1.305V
77ps      1.2V       1.139V     1.24V
192ps     1.189V     1.149V     786mV
243ps     1.085V     1.154V     656.9mV
320ps     841.4mV    1.116V     569.9mV
383ps     677.5mV    1.006V     541.8mV
447ps     582.9mV    856.1mV    529.3mV
549ps     522mV      653.6mV    521.6mV
652ps     501.6mV    547.4mV    518.6mV
1.25ns    489.2mV    473.4mV    517mV
[Falling waveform]
R_fixture=50.000Ohm
V_fixture=0
0s        732.5mV    686.9mV    807.8mV
52ps      737.1mV    689.6mV    703.5mV
115ps     748mV      697.7mV    301mV
154ps     723.6mV    702.9mV    147.5mV
230ps     428.1mV    680.2mV    39.65mV
281ps     197mV      589.8mV    18.18mV
320ps     104.3mV    464.5mV    10.21mV
409ps     27.09mV    163.1mV    2.76mV
498ps     8.871mV    47.01mV    751.9uV
1.25ns    5.405uV    39.03uV    1.799uV
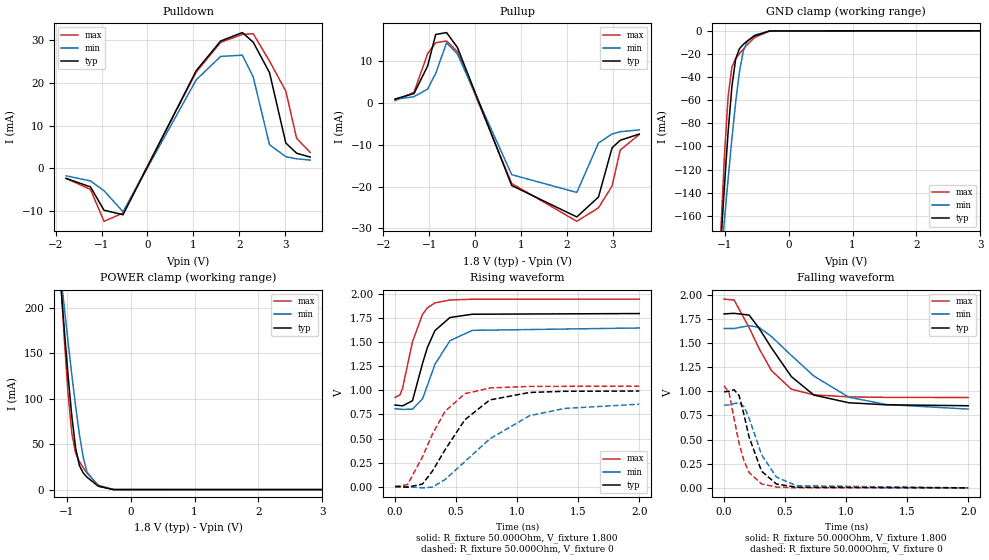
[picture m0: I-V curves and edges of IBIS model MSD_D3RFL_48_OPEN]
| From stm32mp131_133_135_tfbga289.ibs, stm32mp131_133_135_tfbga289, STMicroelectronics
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[Model] MSD_D3RFL_48_OPEN
Model_type   I/O
C_comp 2.550pF   2.464pF   2.678pF
Vinh = 1.440V
Vinl = 360.000mV
Vmeas = 900.000mV
Vref = 900.000mV
[Model Spec]
Vinh   1.440V   1.365V   1.515V
Vinl   360.000mV   285.000mV   435.000mV
Vmeas   900.000mV   825.000mV   975.000mV
Vref   900.000mV   825.000mV   975.000mV
[Temperature Range]   25.000   125.000   -40.000
[Voltage Range]   1.800V   1.650V   1.950V
[GND Clamp Reference]   0.00V   0.00V   0.00V
[Pulldown Reference]   0.00V   0.00V   0.00V
[POWER Clamp Reference]   1.800V   1.650V   1.950V
[Pullup Reference]   1.800V   1.650V   1.950V
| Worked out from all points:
|   slope of the pulldown table from 0 to 0.27 V, typ, clamps not added: 41 ohm
|   slope of the pullup table from 0 to 0.27 V, typ, clamps not added: 32.3 ohm
|   GND clamp passes 1 mA (typ) near -0.40 V on its own axis
|   POWER clamp passes 1 mA (typ) near -0.40 V on its own axis
|   rising waveform, R_fixture 50.000Ohm, V_fixture 1.800: 20-80 % time 143ps typ, 178ps min, 126ps max; typ from 0.848 V to 1.8 V
|   rising waveform, R_fixture 50.000Ohm, V_fixture 0: 20-80 % time 321ps typ, 505ps min, 252ps max; typ from 0.001 V to 0.994 V
|   falling waveform, R_fixture 50.000Ohm, V_fixture 1.800: 20-80 % time 329ps typ, 481ps min, 262ps max; typ from 1.8 V to 0.85 V
|   falling waveform, R_fixture 50.000Ohm, V_fixture 0: 20-80 % time 139ps typ, 171ps min, 120ps max; typ from 0.994 V to 0 V
[GND Clamp]
-1.773V   -892.4mA   -683.3mA   -1.196A
-1.064V   -188.1mA   -202.5mA   -178.5mA
-1.005V   -135.3mA   -164.6mA   -109.5mA
-945.5mV  -87.16mA   -127.9mA   -56.6mA
-886.4mV  -48.05mA   -93.1mA    -31.14mA
-827.3mV  -24.29mA   -61.54mA   -24.05mA
-768.2mV  -15.45mA   -35.41mA   -19.8mA
-709.1mV  -11.76mA   -17.8mA    -15.89mA
-650mV    -8.985mA   -9.267mA   -12.21mA
-531.8mV  -4.349mA   -3.679mA   -5.81mA
-295.4mV  -102.5uA   -159.7uA   -89.52uA
3.545V    35.5nA     528.3nA    5.672nA
[Power Clamp]
-1.745V   862.2mA    676.3mA    1.129A
-1.095V   229.4mA    238.8mA    234.5mA
-1.036V   175.7mA    200.4mA    165.4mA
-977.3mV  125.3mA    162.7mA    105mA
-918.2mV  80.5mA     126.2mA    61.63mA
-859.1mV  45.79mA    91.68mA    40mA
-800mV    26.41mA    60.76mA    30.8mA
-740.9mV  18.45mA    35.84mA    24.13mA
-681.8mV  13.67mA    19.37mA    18.21mA
-504.5mV  3.741mA    3.845mA    4.895mA
-268.2mV  31.85uA    110.6uA    36.37uA
3.573V    -37.18nA   -641.8nA   -5.478nA
[Pulldown]
-1.773V   -2.4mA     -1.8mA     -2.4mA
-1.241V   -4.4mA     -3mA       -5mA
-945.5mV  -9.88mA    -5.3mA     -12.48mA
-531.8mV  -10.94mA   -10.23mA   -10.54mA
1.064V    22.92mA    20.76mA    22.58mA
1.595V    29.86mA    26.24mA    29.55mA
2.068V    31.84mA    26.53mA    31.41mA
2.305V    29.56mA    21.37mA    31.56mA
2.659V    22.44mA    5.5mA      25.15mA
3.014V    5.9mA      2.7mA      18.1mA
3.25V     3.5mA      2.2mA      7mA
3.545V    2.6mA      1.9mA      3.7mA
[Pullup]
-1.745V   1mA        900uA      600uA
-1.332V   2.3mA      1.554mA    2.623mA
-1.036V   8.9mA      3.377mA    11.85mA
-859.1mV  16.47mA    7.15mA     14.48mA
-622.7mV  16.92mA    14.48mA    14.9mA
-386.4mV  13.35mA    11.77mA    12.34mA
795.5mV   -19.73mA   -17.13mA   -19.24mA
2.214V    -27.27mA   -21.4mA    -28.31mA
2.686V    -22.49mA   -9.523mA   -25.08mA
2.982V    -10.7mA    -7.392mA   -19.85mA
3.159V    -8.9mA     -6.846mA   -11.25mA
3.573V    -7.4mA     -6.4mA     -7.508mA
[Ramp]
R_load=50.000Ohm
dV/dt_r   583.770mV/233.000ps  505.649mV/337.000ps  617.730mV/189.500ps
dV/dt_f   583.649mV/235.500ps  504.325mV/321.500ps  617.730mV/191.000ps
[Rising waveform]
R_fixture=50.000Ohm
V_fixture=1.800
V_fixture_min=1.650
V_fixture_max=1.950
0s        848.1mV    810.3mV    928mV
41ps      842.9mV    805.7mV    954.7mV
62ps      839.8mV    802.9mV    1.025V
143ps     893.4mV    805.5mV    1.508V
225ps     1.281V     912.8mV    1.792V
266ps     1.451V     1.056V     1.86V
327ps     1.623V     1.273V     1.911V
450ps     1.759V     1.518V     1.941V
633ps     1.793V     1.625V     1.949V
2ns       1.8V       1.65V      1.95V
[Rising waveform]
R_fixture=50.000Ohm
V_fixture=0
0s        1.089mV    1.226mV    -2.413mV
103ps     -6.197mV   -1.824mV   22.14mV
225ps     26.83mV    -13.13mV   310.6mV
307ps     162.5mV    -5.45mV    547.7mV
409ps     381.9mV    72.53mV    782.2mV
572ps     695.4mV    260.1mV    966.5mV
776ps     901.4mV    496.7mV    1.026V
1.103ns   979.2mV    737.8mV    1.042V
1.389ns   991.3mV    812.9mV    1.043V
2ns       994.1mV    857.2mV    1.044V
[Falling waveform]
R_fixture=50.000Ohm
V_fixture=1.800
V_fixture_min=1.650
V_fixture_max=1.950
0s        1.8V       1.649V     1.953V
82ps      1.806V     1.649V     1.944V
205ps     1.788V     1.678V     1.659V
286ps     1.653V     1.661V     1.444V
388ps     1.449V     1.566V     1.214V
552ps     1.15V      1.369V     1.02V
736ps     960.4mV    1.157V     962.6mV
1.021ns   880.7mV    938.5mV    941.5mV
1.328ns   859.6mV    862.4mV    936.4mV
2ns       849.8mV    815.3mV    934.7mV
[Falling waveform]
R_fixture=50.000Ohm
V_fixture=0
0s        993.5mV    854.7mV    1.057V
41ps      1V         859.3mV    981.1mV
82ps      1.015V     872.6mV    716.2mV
123ps     955.1mV    879.4mV    460.2mV
164ps     752.3mV    839.4mV    275.3mV
205ps     526mV      722.1mV    159.2mV
307ps     172.7mV    343.6mV    40.57mV
429ps     39.66mV    111.4mV    8.523mV
593ps     6.427mV    21.89mV    1.204mV
2ns       14.23uV    89.2uV     -931.1nV
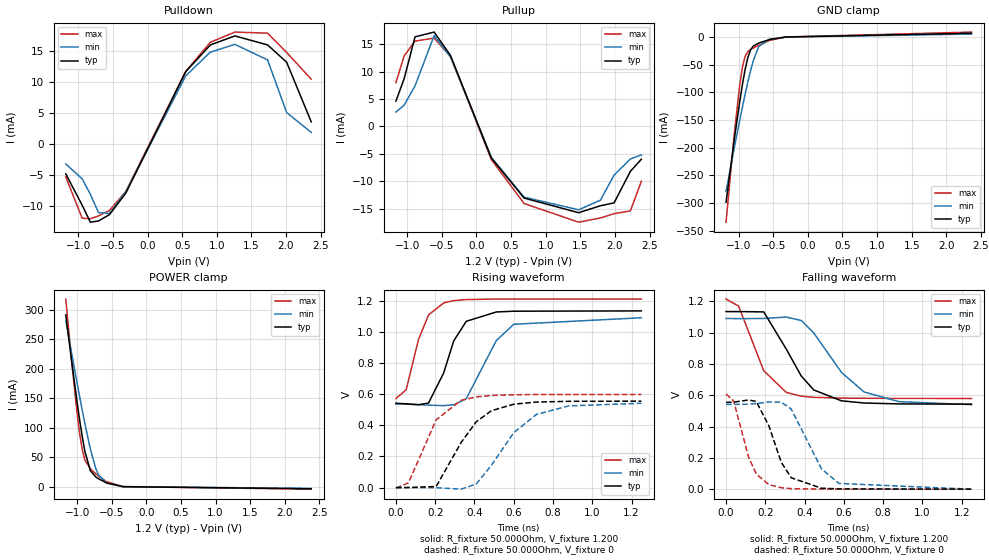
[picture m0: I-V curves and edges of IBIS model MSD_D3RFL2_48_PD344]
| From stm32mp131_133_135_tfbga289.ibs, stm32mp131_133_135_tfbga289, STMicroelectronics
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[Model] MSD_D3RFL2_48_PD344
Model_type   I/O
C_comp 2.341pF   2.257pF   2.465pF
Vinh = 820.000mV
Vinl = 380.000mV
Vmeas = 600.000mV
Vref = 600.000mV
[Model Spec]
Vinh   820.000mV   790.000mV   870.000mV
Vinl   380.000mV   350.000mV   430.000mV
Vmeas   600.000mV   570.000mV   650.000mV
Vref   600.000mV   570.000mV   650.000mV
[Receiver Thresholds]
Vth   =  0.600V
Vth_min  =  0.5880V
Vth_max  =  0.6120V
Vinh_ac  =  0.220V
Vinh_dc  =  0.130V
Vinl_ac  = -0.220V
Vinl_dc  = -0.130V
Tslew_ac =  5.000ns |Not specified, so set to high value
[Temperature Range]   25.000   125.000   -40.000
[Voltage Range]   1.200V   1.140V   1.300V
[GND Clamp Reference]   0.00V   0.00V   0.00V
[Pulldown Reference]   0.00V   0.00V   0.00V
[POWER Clamp Reference]   1.200V   1.140V   1.300V
[Pullup Reference]   1.200V   1.140V   1.300V
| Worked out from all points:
|   slope of the pulldown table from 0 to 0.18 V, typ, clamps not added: 41.6 ohm
|   slope of the pullup table from 0 to 0.18 V, typ, clamps not added: 36.2 ohm
|   GND clamp passes 1 mA (typ) near -0.40 V on its own axis
|   POWER clamp passes 1 mA (typ) near -0.42 V on its own axis
|   rising waveform, R_fixture 50.000Ohm, V_fixture 1.200: 20-80 % time 100ps typ, 129ps min, 85.4ps max; typ from 0.542 V to 1.14 V
|   rising waveform, R_fixture 50.000Ohm, V_fixture 0: 20-80 % time 164ps typ, 200ps min, 138ps max; typ from 0.001 V to 0.555 V
|   falling waveform, R_fixture 50.000Ohm, V_fixture 1.200: 20-80 % time 162ps typ, 210ps min, 127ps max; typ from 1.14 V to 0.543 V
|   falling waveform, R_fixture 50.000Ohm, V_fixture 0: 20-80 % time 100ps typ, 126ps min, 84.2ps max; typ from 0.554 V to 0 V
[GND Clamp]
-1.182V   -298.7mA   -278.9mA   -334.7mA
-1.064V   -186.5mA   -201.2mA   -176.5mA
-984.9mV  -117.2mA   -151.1mA   -87.71mA
-945.5mV  -85.91mA   -126.8mA   -54.95mA
-906.1mV  -58.56mA   -103.4mA   -34.88mA
-866.7mV  -37.08mA   -81.29mA   -26.52mA
-827.3mV  -23.32mA   -60.76mA   -22.77mA
-787.9mV  -16.51mA   -42.62mA   -20mA
-709.1mV  -11.08mA   -17.24mA   -14.98mA
-551.5mV  -4.681mA   -3.974mA   -6.287mA
-315.1mV  -154.2uA   -220.1uA   -140.9uA
2.364V    6.653mA    5.111mA    8.718mA
[Power Clamp]
-1.164V   291.4mA    281.7mA    318.1mA
-1.085V   217.8mA    230mA      219mA
-1.006V   147.7mA    179.3mA    130.2mA
-966.7mV  115.2mA    154.5mA    92.47mA
-927.3mV  85.46mA    130.3mA    63.19mA
-887.9mV  59.77mA    106.8mA    45.13mA
-809.1mV  27.31mA    63.82mA    30.53mA
-730.3mV  16.63mA    30.75mA    21.92mA
-690.9mV  13.57mA    19.97mA    18.11mA
-572.7mV  6.421mA    6.328mA    8.512mA
-336.4mV  165.6uA    318.9uA    193uA
2.382V    -3.424mA   -2.825mA   -4.062mA
[Pulldown]
-1.182V   -4.8mA     -3.2mA     -5.3mA
-945.5mV  -9.87mA    -5.6mA     -11.97mA
-827.3mV  -12.61mA   -8.1mA     -12.05mA
-709.1mV  -12.41mA   -11.06mA   -11.6mA
-551.5mV  -11.39mA   -11.19mA   -10.72mA
-315.1mV  -7.913mA   -7.699mA   -7.643mA
551.5mV   11.72mA    11.04mA    11.76mA
906.1mV   16.02mA    14.86mA    16.45mA
1.261V    17.48mA    16.12mA    18.1mA
1.733V    16.03mA    13.61mA    17.93mA
2.009V    13.23mA    5.1mA      14.8mA
2.364V    3.6mA      1.9mA      10.5mA
[Pullup]
-1.164V   4.6mA      2.609mA    7.977mA
-1.045V   8.7mA      3.862mA    12.86mA
-887.9mV  16.32mA    7.38mA     15.55mA
-612.1mV  17.19mA    16.54mA    16.09mA
-375.8mV  12.93mA    12.63mA    12.74mA
215.2mV   -5.799mA   -5.653mA   -6.08mA
687.9mV   -13.08mA   -12.91mA   -14.07mA
1.476V    -15.75mA   -15.22mA   -17.48mA
1.791V    -14.48mA   -13.46mA   -16.71mA
1.988V    -13.96mA   -8.899mA   -15.93mA
2.224V    -8.2mA     -5.943mA   -15.42mA
2.382V    -6mA       -5.2mA     -10.01mA
[Ramp]
R_load=50.000Ohm
dV/dt_r   344.100mV/132.500ps  328.529mV/165.000ps  368.850mV/112.000ps
dV/dt_f   344.130mV/132.000ps  328.529mV/169.500ps  368.850mV/106.000ps
[Rising waveform]
R_fixture=50.000Ohm
V_fixture=1.200
V_fixture_min=1.140
V_fixture_max=1.300
0s        541.8mV    537.6mV    572.2mV
52ps      538.1mV    536.2mV    628.1mV
115ps     532.4mV    533mV      950.8mV
166ps     543.2mV    529.8mV    1.109V
243ps     735.6mV    526.4mV    1.186V
294ps     941.1mV    532.2mV    1.201V
358ps     1.068V     570.7mV    1.208V
511ps     1.128V     943.9mV    1.211V
600ps     1.133V     1.049V     1.211V
1.25ns    1.135V     1.091V     1.211V
[Rising waveform]
R_fixture=50.000Ohm
V_fixture=0
0s        623.7uV    211.1uV    -4.289mV
64ps      397.3uV    626.2uV    31.1mV
205ps     7.295mV    -574.6uV   435.8mV
332ps     289.6mV    -9.932mV   560.5mV
409ps     422.8mV    22.87mV    582.9mV
486ps     493.9mV    142.6mV    591.9mV
600ps     535.6mV    353.1mV    596.6mV
715ps     549.5mV    469.7mV    597.7mV
881ps     554.3mV    525.1mV    598.1mV
1.25ns    555.2mV    541.7mV    598.3mV
[Falling waveform]
R_fixture=50.000Ohm
V_fixture=1.200
V_fixture_min=1.140
V_fixture_max=1.300
0s        1.135V     1.091V     1.215V
64ps      1.135V     1.09V      1.17V
192ps     1.133V     1.091V     756.7mV
307ps     894.5mV    1.1V       618.3mV
383ps     723.3mV    1.078V     594.5mV
447ps     633.9mV    997.7mV    586.9mV
588ps     564.6mV    746.1mV    582mV
703ps     550.6mV    621.1mV    580.9mV
881ps     544.9mV    559.1mV    580.1mV
1.25ns    543.2mV    540.3mV    579.9mV
[Falling waveform]
R_fixture=50.000Ohm
V_fixture=0
0s        554.5mV    541.9mV    608.6mV
39ps      556.3mV    541.6mV    562.7mV
115ps     570.1mV    543.2mV    203.6mV
154ps     560.2mV    547.1mV    97.09mV
218ps     405.3mV    557.2mV    28.9mV
281ps     172.4mV    556.3mV    9.049mV
332ps     72.85mV    511.7mV    3.433mV
486ps     6.147mV    129.9mV    323uV
575ps     1.723mV    36.53mV    66.26uV
1.25ns    2.996uV    35.55uV    -1.002uV
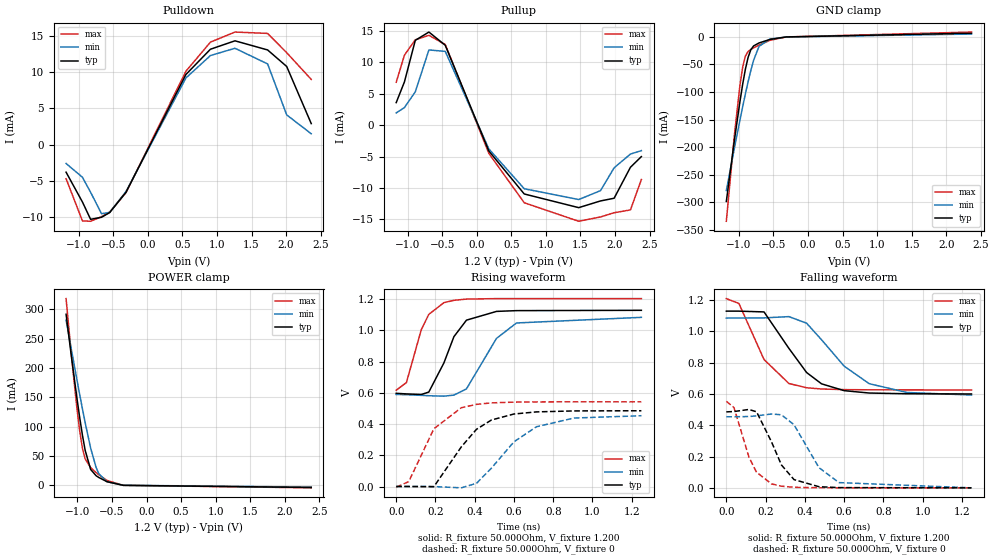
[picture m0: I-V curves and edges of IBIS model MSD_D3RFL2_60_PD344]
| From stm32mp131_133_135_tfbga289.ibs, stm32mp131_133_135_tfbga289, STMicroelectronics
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[Model] MSD_D3RFL2_60_PD344
Model_type   I/O
C_comp 2.341pF   2.257pF   2.465pF
Vinh = 820.000mV
Vinl = 380.000mV
Vmeas = 600.000mV
Vref = 600.000mV
[Model Spec]
Vinh   820.000mV   790.000mV   870.000mV
Vinl   380.000mV   350.000mV   430.000mV
Vmeas   600.000mV   570.000mV   650.000mV
Vref   600.000mV   570.000mV   650.000mV
[Receiver Thresholds]
Vth   =  0.600V
Vth_min  =  0.5880V
Vth_max  =  0.6120V
Vinh_ac  =  0.220V
Vinh_dc  =  0.130V
Vinl_ac  = -0.220V
Vinl_dc  = -0.130V
Tslew_ac =  5.000ns |Not specified, so set to high value
[Temperature Range]   25.000   125.000   -40.000
[Voltage Range]   1.200V   1.140V   1.300V
[GND Clamp Reference]   0.00V   0.00V   0.00V
[Pulldown Reference]   0.00V   0.00V   0.00V
[POWER Clamp Reference]   1.200V   1.140V   1.300V
[Pullup Reference]   1.200V   1.140V   1.300V
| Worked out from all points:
|   slope of the pulldown table from 0 to 0.18 V, typ, clamps not added: 50.1 ohm
|   slope of the pullup table from 0 to 0.18 V, typ, clamps not added: 42.9 ohm
|   GND clamp passes 1 mA (typ) near -0.40 V on its own axis
|   POWER clamp passes 1 mA (typ) near -0.42 V on its own axis
|   rising waveform, R_fixture 50.000Ohm, V_fixture 1.200: 20-80 % time 107ps typ, 137ps min, 88.1ps max; typ from 0.597 V to 1.13 V
|   rising waveform, R_fixture 50.000Ohm, V_fixture 0: 20-80 % time 173ps typ, 215ps min, 143ps max; typ from 0.001 V to 0.486 V
|   falling waveform, R_fixture 50.000Ohm, V_fixture 1.200: 20-80 % time 178ps typ, 229ps min, 138ps max; typ from 1.13 V to 0.599 V
|   falling waveform, R_fixture 50.000Ohm, V_fixture 0: 20-80 % time 106ps typ, 132ps min, 89.7ps max; typ from 0.485 V to 0 V
[GND Clamp]
-1.182V   -298.7mA   -278.9mA   -334.7mA
-1.064V   -186.5mA   -201.2mA   -176.5mA
-984.9mV  -117.2mA   -151.1mA   -87.71mA
-945.5mV  -85.91mA   -126.8mA   -54.95mA
-906.1mV  -58.56mA   -103.4mA   -34.88mA
-866.7mV  -37.08mA   -81.29mA   -26.52mA
-827.3mV  -23.32mA   -60.76mA   -22.77mA
-787.9mV  -16.51mA   -42.62mA   -20mA
-709.1mV  -11.08mA   -17.24mA   -14.98mA
-551.5mV  -4.681mA   -3.974mA   -6.287mA
-315.1mV  -154.2uA   -220.1uA   -140.9uA
2.364V    6.653mA    5.111mA    8.718mA
[Power Clamp]
-1.164V   291.4mA    281.7mA    318.1mA
-1.085V   217.8mA    230mA      219mA
-1.006V   147.7mA    179.3mA    130.2mA
-966.7mV  115.2mA    154.5mA    92.47mA
-927.3mV  85.46mA    130.3mA    63.19mA
-887.9mV  59.77mA    106.8mA    45.13mA
-809.1mV  27.31mA    63.82mA    30.53mA
-730.3mV  16.63mA    30.75mA    21.92mA
-690.9mV  13.57mA    19.97mA    18.11mA
-572.7mV  6.421mA    6.328mA    8.512mA
-336.4mV  165.6uA    318.9uA    193uA
2.382V    -3.424mA   -2.825mA   -4.062mA
[Pulldown]
-1.182V   -3.8mA     -2.6mA     -4.7mA
-945.5mV  -7.91mA    -4.5mA     -10.52mA
-827.3mV  -10.3mA    -6.57mA    -10.57mA
-669.7mV  -10.02mA   -9.53mA    -9.94mA
-551.5mV  -9.371mA   -9.342mA   -9.302mA
-315.1mV  -6.567mA   -6.464mA   -6.607mA
551.5mV   9.679mA    9.196mA    10.13mA
906.1mV   13.16mA    12.29mA    14.14mA
1.261V    14.32mA    13.29mA    15.53mA
1.733V    13.06mA    11.13mA    15.34mA
2.009V    10.78mA    4.1mA      12.68mA
2.364V    2.9mA      1.5mA      9mA
[Pullup]
-1.164V   3.6mA      1.957mA    6.838mA
-1.045V   6.9mA      2.809mA    11.16mA
-887.9mV  13.52mA    5.323mA    13.61mA
-690.9mV  14.84mA    11.99mA    14.32mA
-454.5mV  12.73mA    11.76mA    12.85mA
175.8mV   -4.107mA   -3.772mA   -4.491mA
687.9mV   -10.95mA   -10.12mA   -12.35mA
1.476V    -13.13mA   -11.84mA   -15.3mA
1.791V    -12.06mA   -10.42mA   -14.61mA
1.988V    -11.63mA   -6.779mA   -13.94mA
2.224V    -6.7mA     -4.595mA   -13.49mA
2.382V    -5mA       -4.048mA   -8.654mA
[Ramp]
R_load=50.000Ohm
dV/dt_r   304.530mV/140.000ps  284.549mV/177.500ps  336.750mV/115.500ps
dV/dt_f   304.530mV/143.000ps  284.490mV/183.500ps  336.750mV/114.000ps
[Rising waveform]
R_fixture=50.000Ohm
V_fixture=1.200
V_fixture_min=1.140
V_fixture_max=1.300
0s        597.3mV    589.9mV    617.2mV
52ps      593.4mV    588.4mV    666.3mV
128ps     589.7mV    584.3mV    1.006V
166ps     605.2mV    581.8mV    1.103V
243ps     792mV      579mV      1.178V
294ps     960.2mV    585.9mV    1.193V
358ps     1.066V     625.9mV    1.201V
511ps     1.122V     949.2mV    1.204V
613ps     1.127V     1.048V     1.204V
1.249ns   1.129V     1.084V     1.204V
[Rising waveform]
R_fixture=50.000Ohm
V_fixture=0
0s        572.5uV    198.1uV    -3.678mV
64ps      238.8uV    552.2uV    31.77mV
192ps     -655.5uV   -136.5uV   370.6mV
332ps     254.8mV    -8.215mV   505.2mV
409ps     366.8mV    20.8mV     526.5mV
485ps     426.3mV    117.8mV    535.9mV
600ps     464.8mV    287mV      540.8mV
715ps     478.3mV    383.3mV    542.2mV
906ps     484.5mV    439mV      542.8mV
1.249ns   485.6mV    453.6mV    542.8mV
[Falling waveform]
R_fixture=50.000Ohm
V_fixture=1.200
V_fixture_min=1.140
V_fixture_max=1.300
0s        1.128V     1.084V     1.208V
64ps      1.128V     1.084V     1.177V
192ps     1.123V     1.085V     819.1mV
319ps     889.9mV    1.093V     665.9mV
409ps     736.1mV    1.051V     638.8mV
485ps     664mV      945.3mV    631mV
600ps     620.4mV    777mV      627mV
728ps     605.2mV    664.8mV    625.8mV
919ps     600.5mV    608.9mV    625.3mV
1.249ns   599.2mV    592.3mV    624.9mV
[Falling waveform]
R_fixture=50.000Ohm
V_fixture=0
0s        484.9mV    453.8mV    552.6mV
39ps      487.1mV    453.5mV    512.2mV
115ps     500.3mV    455.3mV    196.9mV
154ps     485.3mV    459.4mV    99.42mV
230ps     294mV      471.2mV    25.2mV
281ps     145.4mV    466.3mV    10.42mV
345ps     52.5mV     402.5mV    3.303mV
472ps     7.146mV    128.6mV    517.6uV
574ps     1.443mV    33.35mV    90.35uV
1.249ns   -2.234uV   2.652uV    -1.461uV
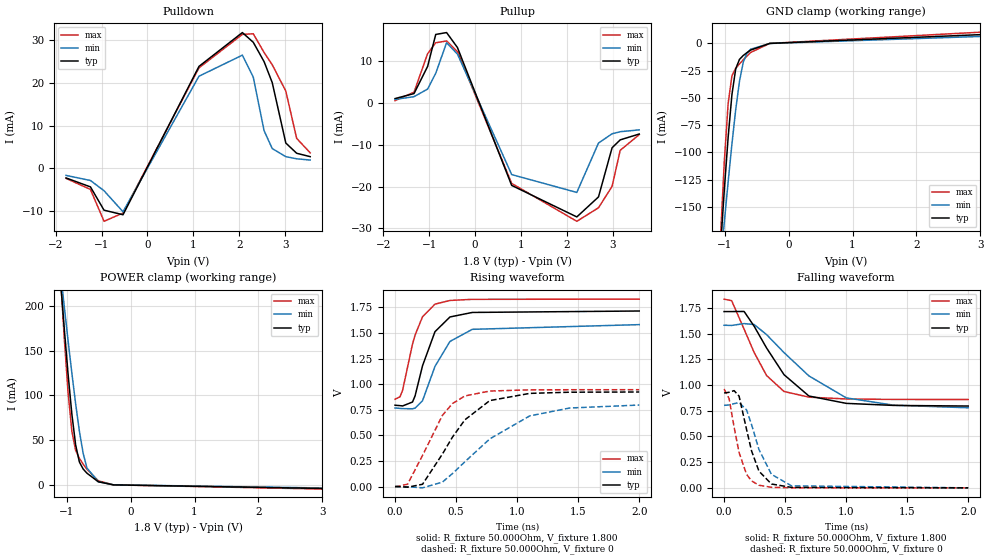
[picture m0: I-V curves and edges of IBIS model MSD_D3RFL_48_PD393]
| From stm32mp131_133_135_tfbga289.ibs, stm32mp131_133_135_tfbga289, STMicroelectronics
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[Model] MSD_D3RFL_48_PD393
Model_type   I/O
C_comp 2.343pF   2.260pF   2.465pF
Vinh = 1.440V
Vinl = 360.000mV
Vmeas = 900.000mV
Vref = 900.000mV
[Model Spec]
Vinh   1.440V   1.365V   1.515V
Vinl   360.000mV   285.000mV   435.000mV
Vmeas   900.000mV   825.000mV   975.000mV
Vref   900.000mV   825.000mV   975.000mV
[Temperature Range]   25.000   125.000   -40.000
[Voltage Range]   1.800V   1.650V   1.950V
[GND Clamp Reference]   0.00V   0.00V   0.00V
[Pulldown Reference]   0.00V   0.00V   0.00V
[POWER Clamp Reference]   1.800V   1.650V   1.950V
[Pullup Reference]   1.800V   1.650V   1.950V
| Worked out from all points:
|   slope of the pulldown table from 0 to 0.27 V, typ, clamps not added: 41 ohm
|   slope of the pullup table from 0 to 0.27 V, typ, clamps not added: 32.3 ohm
|   GND clamp passes 1 mA (typ) near -0.40 V on its own axis
|   POWER clamp passes 1 mA (typ) near -0.41 V on its own axis
|   rising waveform, R_fixture 50.000Ohm, V_fixture 1.800: 20-80 % time 152ps typ, 194ps min, 134ps max; typ from 0.795 V to 1.72 V
|   rising waveform, R_fixture 50.000Ohm, V_fixture 0: 20-80 % time 319ps typ, 496ps min, 245ps max; typ from 0.001 V to 0.924 V
|   falling waveform, R_fixture 50.000Ohm, V_fixture 1.800: 20-80 % time 317ps typ, 469ps min, 240ps max; typ from 1.72 V to 0.796 V
|   falling waveform, R_fixture 50.000Ohm, V_fixture 0: 20-80 % time 122ps typ, 152ps min, 104ps max; typ from 0.923 V to 0 V
[GND Clamp]
-1.773V   -889.4mA   -680.7mA   -1.193A
-1.064V   -186.7mA   -201.3mA   -176.7mA
-1.005V   -134mA     -163.6mA   -107.8mA
-945.5mV  -86.06mA   -127mA     -55.16mA
-886.4mV  -47.07mA   -92.3mA    -29.87mA
-827.3mV  -23.43mA   -60.83mA   -22.94mA
-768.2mV  -14.72mA   -34.81mA   -18.84mA
-709.1mV  -11.15mA   -17.3mA    -15.09mA
-650mV    -8.488mA   -8.86mA    -11.55mA
-590.9mV  -6.132mA   -5.359mA   -8.314mA
-295.4mV  -90.89uA   -145.5uA   -74.99uA
3.545V    9.288mA    7.362mA    11.89mA
[Power Clamp]
-1.745V   858.9mA    673.5mA    1.125A
-1.095V   227.9mA    237.4mA    232.6mA
-1.036V   174.4mA    199.1mA    163.7mA
-977.3mV  124mA      161.5mA    103.4mA
-918.2mV  79.37mA    125.2mA    60.21mA
-859.1mV  44.8mA     90.83mA    38.75mA
-800mV    25.55mA    60mA       29.72mA
-740.9mV  17.72mA    35.19mA    23.21mA
-681.8mV  13.07mA    18.83mA    17.46mA
-504.5mV  3.489mA    3.595mA    4.589mA
-268.2mV  22.03uA    89.14uA    28.08uA
3.573V    -4.696mA   -4.082mA   -5.482mA
[Pulldown]
-1.773V   -2.3mA     -1.7mA     -2.4mA
-1.241V   -4.4mA     -2.9mA     -5mA
-945.5mV  -9.87mA    -5.3mA     -12.48mA
-531.8mV  -10.94mA   -10.24mA   -10.54mA
1.123V    23.9mA     21.59mA    23.56mA
2.068V    31.84mA    26.54mA    31.41mA
2.305V    29.56mA    21.37mA    31.56mA
2.541V    25.01mA    8.8mA      27.16mA
2.718V    20.1mA     4.6mA      24.29mA
3.014V    5.9mA      2.7mA      18.1mA
3.25V     3.5mA      2.2mA      7mA
3.545V    2.7mA      1.9mA      3.6mA
[Pullup]
-1.745V   1.1mA      900uA      600uA
-1.332V   2.3mA      1.554mA    2.623mA
-1.036V   8.8mA      3.377mA    11.85mA
-859.1mV  16.47mA    7.155mA    14.48mA
-622.7mV  16.92mA    14.48mA    14.91mA
-386.4mV  13.34mA    11.77mA    12.34mA
795.5mV   -19.72mA   -17.12mA   -19.24mA
2.214V    -27.27mA   -21.4mA    -28.32mA
2.686V    -22.48mA   -9.569mA   -25.08mA
2.982V    -10.7mA    -7.338mA   -19.95mA
3.159V    -8.8mA     -6.846mA   -11.3mA
3.573V    -7.4mA     -6.4mA     -7.554mA
[Ramp]
R_load=50.000Ohm
dV/dt_r   553.290mV/236.000ps  482.969mV/346.500ps  575.460mV/190.000ps
dV/dt_f   553.259mV/220.000ps  482.275mV/311.000ps  575.460mV/171.500ps
[Rising waveform]
R_fixture=50.000Ohm
V_fixture=1.800
V_fixture_min=1.650
V_fixture_max=1.950
0s        795.1mV    767.8mV    853.4mV
41ps      790.7mV    764mV      877.7mV
62ps      787.6mV    761.5mV    941.5mV
143ps     826.1mV    760.1mV    1.392V
164ps     885.7mV    766.7mV    1.479V
225ps     1.18V      838.6mV    1.659V
327ps     1.513V     1.174V     1.782V
450ps     1.657V     1.418V     1.818V
633ps     1.701V     1.536V     1.829V
2ns       1.715V     1.582V     1.831V
[Rising waveform]
R_fixture=50.000Ohm
V_fixture=0
0s        1.03mV     1.109mV    -2.547mV
103ps     -5.66mV    -1.223mV   23.88mV
225ps     22.64mV    -12.26mV   304.5mV
388ps     318mV      43.95mV    696.1mV
470ps     483mV      126.7mV    810.8mV
572ps     652.2mV    242.6mV    885.3mV
776ps     840.1mV    466mV      933.4mV
1.103ns   910.4mV    690.6mV    944.8mV
1.43ns    921.9mV    767.6mV    946.2mV
2ns       924mV      796.6mV    946.3mV
[Falling waveform]
R_fixture=50.000Ohm
V_fixture=1.800
V_fixture_min=1.650
V_fixture_max=1.950
0s        1.715V     1.582V     1.836V
62ps      1.715V     1.58V      1.821V
164ps     1.716V     1.598V     1.544V
246ps     1.573V     1.589V     1.318V
348ps     1.361V     1.491V     1.093V
491ps     1.101V     1.316V     937.4mV
695ps     893.5mV    1.089V     882.5mV
1.001ns   821.9mV    875.3mV    864.7mV
1.389ns   802mV      804.3mV    860.2mV
2ns       795.9mV    779mV      859.4mV
[Falling waveform]
R_fixture=50.000Ohm
V_fixture=0
0s        923.2mV    802.8mV    961.5mV
41ps      929.5mV    806.2mV    869.8mV
82ps      945.9mV    819mV      591.6mV
123ps     892mV      830mV      342.9mV
184ps     568.8mV    758.6mV    132.5mV
225ps     359.9mV    615.8mV    67.99mV
286ps     161.9mV    372.3mV    25.35mV
388ps     37.57mV    131.6mV    5.459mV
552ps     4.481mV    19.65mV    764.6uV
2ns       14.21uV    90.2uV     948.1nV
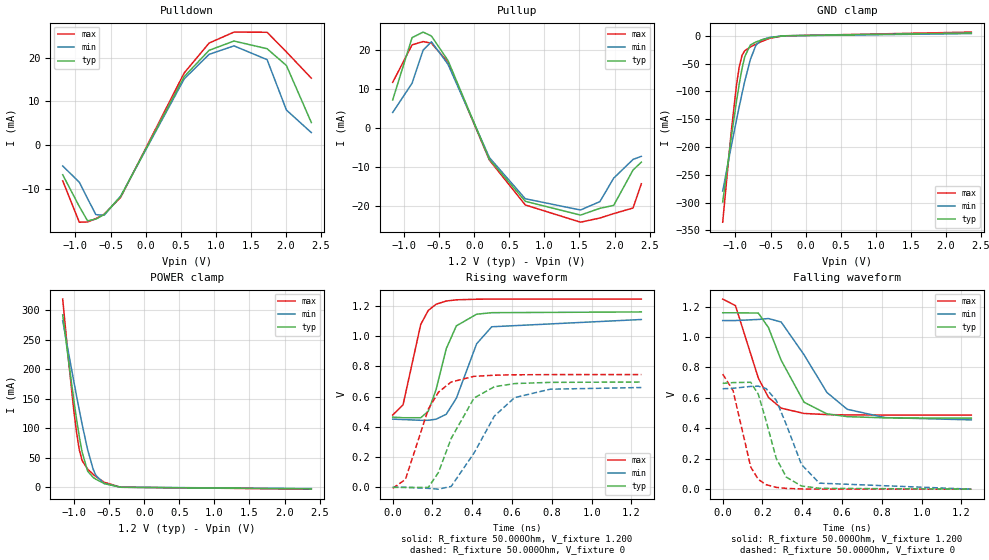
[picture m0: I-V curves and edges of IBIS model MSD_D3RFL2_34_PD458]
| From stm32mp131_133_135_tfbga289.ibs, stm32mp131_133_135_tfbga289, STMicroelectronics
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[Model] MSD_D3RFL2_34_PD458
Model_type   I/O
C_comp 2.402pF   2.316pF   2.526pF
Vinh = 820.000mV
Vinl = 380.000mV
Vmeas = 600.000mV
Vref = 600.000mV
[Model Spec]
Vinh   820.000mV   790.000mV   870.000mV
Vinl   380.000mV   350.000mV   430.000mV
Vmeas   600.000mV   570.000mV   650.000mV
Vref   600.000mV   570.000mV   650.000mV
[Receiver Thresholds]
Vth   =  0.600V
Vth_min  =  0.5880V
Vth_max  =  0.6120V
Vinh_ac  =  0.220V
Vinh_dc  =  0.130V
Vinl_ac  = -0.220V
Vinl_dc  = -0.130V
Tslew_ac =  5.000ns |Not specified, so set to high value
[Temperature Range]   25.000   125.000   -40.000
[Voltage Range]   1.200V   1.140V   1.300V
[GND Clamp Reference]   0.00V   0.00V   0.00V
[Pulldown Reference]   0.00V   0.00V   0.00V
[POWER Clamp Reference]   1.200V   1.140V   1.300V
[Pullup Reference]   1.200V   1.140V   1.300V
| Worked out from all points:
|   slope of the pulldown table from 0 to 0.18 V, typ, clamps not added: 31.3 ohm
|   slope of the pullup table from 0 to 0.18 V, typ, clamps not added: 26.5 ohm
|   GND clamp passes 1 mA (typ) near -0.40 V on its own axis
|   POWER clamp passes 1 mA (typ) near -0.41 V on its own axis
|   rising waveform, R_fixture 50.000Ohm, V_fixture 1.200: 20-80 % time 90.3ps typ, 117ps min, 77.1ps max; typ from 0.464 V to 1.16 V
|   rising waveform, R_fixture 50.000Ohm, V_fixture 0: 20-80 % time 143ps typ, 175ps min, 123ps max; typ from 0.001 V to 0.696 V
|   falling waveform, R_fixture 50.000Ohm, V_fixture 1.200: 20-80 % time 144ps typ, 189ps min, 118ps max; typ from 1.16 V to 0.466 V
|   falling waveform, R_fixture 50.000Ohm, V_fixture 0: 20-80 % time 93.6ps typ, 120ps min, 79.8ps max; typ from 0.695 V to 0 V
[GND Clamp]
-1.182V   -299.1mA   -279.3mA   -335.3mA
-1.064V   -187mA     -201.5mA   -177mA
-984.9mV  -117.6mA   -151.3mA   -88.16mA
-945.5mV  -86.22mA   -127.1mA   -55.37mA
-906.1mV  -58.84mA   -103.8mA   -35.26mA
-866.7mV  -37.35mA   -81.5mA    -26.87mA
-787.9mV  -16.73mA   -42.8mA    -20.29mA
-709.1mV  -11.25mA   -17.38mA   -15.2mA
-630.3mV  -7.745mA   -7.438mA   -10.54mA
-512.1mV  -3.498mA   -2.984mA   -4.633mA
-315.1mV  -158.7uA   -224.9uA   -147.6uA
2.364V    4.99mA     3.837mA    6.535mA
[Power Clamp]
-1.164V   292mA      282.1mA    318.7mA
-1.085V   218.3mA    230.5mA    219.6mA
-1.006V   148.1mA    179.7mA    130.7mA
-966.7mV  115.5mA    154.8mA    92.95mA
-927.3mV  85.81mA    130.6mA    63.61mA
-887.9mV  60.1mA     107.1mA    45.52mA
-809.1mV  27.58mA    64.08mA    30.85mA
-730.3mV  16.84mA    30.96mA    22.19mA
-690.9mV  13.77mA    20.14mA    18.34mA
-572.7mV  6.533mA    6.447mA    8.649mA
-336.4mV  178.2uA    339.3uA    207.6uA
2.382V    -2.569mA   -2.119mA   -3.047mA
[Pulldown]
-1.182V   -6.7mA     -4.7mA     -8.1mA
-945.5mV  -13.92mA   -8.4mA     -17.51mA
-827.3mV  -17.2mA    -12.13mA   -17.46mA
-709.1mV  -16.81mA   -15.79mA   -16.7mA
-590.9mV  -15.77mA   -15.93mA   -15.69mA
-354.6mV  -11.63mA   -11.56mA   -11.83mA
551.5mV   15.67mA    15.15mA    16.51mA
906.1mV   21.65mA    20.73mA    23.3mA
1.261V    23.76mA    22.66mA    25.8mA
1.733V    22.01mA    19.52mA    25.76mA
2.009V    18.18mA    8.04mA     21.28mA
2.364V    5.2mA      2.9mA      15.3mA
[Pullup]
-1.164V   7.3mA      4.062mA    11.8mA
-887.9mV  23.27mA    11.57mA    21.42mA
-730.3mV  24.7mA     20.06mA    22.27mA
-612.1mV  23.69mA    22.22mA    21.84mA
-375.8mV  17.41mA    16.45mA    16.97mA
215.2mV   -7.945mA   -7.528mA   -8.168mA
727.3mV   -18.74mA   -18.09mA   -19.68mA
1.515V    -22.28mA   -20.97mA   -24.1mA
1.791V    -20.54mA   -18.82mA   -23.03mA
1.988V    -19.78mA   -12.79mA   -21.9mA
2.264V    -10.7mA    -7.991mA   -20.46mA
2.382V    -8.7mA     -7.195mA   -14.24mA
[Ramp]
R_load=50.000Ohm
dV/dt_r   416.640mV/117.000ps  394.439mV/146.500ps  450.600mV/100.000ps
dV/dt_f   416.640mV/119.000ps  394.439mV/156.000ps  450.600mV/98.500ps
[Rising waveform]
R_fixture=50.000Ohm
V_fixture=1.200
V_fixture_min=1.140
V_fixture_max=1.300
0s        464.4mV    451mV      478.2mV
52ps      460.2mV    448.2mV    545.5mV
141ps     460.2mV    443.2mV    1.077V
179ps     503.2mV    443.5mV    1.169V
218ps     645.8mV    450.5mV    1.21V
269ps     915.4mV    482.9mV    1.231V
320ps     1.067V     588.9mV    1.239V
422ps     1.144V     948.7mV    1.243V
498ps     1.154V     1.061V     1.244V
1.25ns    1.159V     1.109V     1.244V
[Rising waveform]
R_fixture=50.000Ohm
V_fixture=0
0s        907.5uV    889.4uV    -6.227mV
64ps      -244.2uV   755uV      52.9mV
179ps     -536.7uV   -6.373mV   517mV
230ps     99.12mV    -11.62mV   629.1mV
294ps     323.6mV    6.609mV    696.2mV
409ps     590.6mV    227.3mV    733.5mV
511ps     664.8mV    470.9mV    741.1mV
613ps     685.8mV    593mV      743.7mV
792ps     693.8mV    648.7mV    745mV
1.25ns    695.9mV    659.8mV    745.2mV
[Falling waveform]
R_fixture=50.000Ohm
V_fixture=1.200
V_fixture_min=1.140
V_fixture_max=1.300
0s        1.159V     1.108V     1.249V
64ps      1.159V     1.108V     1.206V
179ps     1.157V     1.115V     730.2mV
230ps     1.062V     1.121V     602.9mV
294ps     846.9mV    1.098V     532.2mV
409ps     571.2mV    882.8mV    497.4mV
524ps     494.6mV    635.4mV    490mV
626ps     476.5mV    524.7mV    487.8mV
817ps     468.5mV    470mV      487mV
1.25ns    466.3mV    455.2mV    486.9mV
[Falling waveform]
R_fixture=50.000Ohm
V_fixture=0
0s        695.3mV    659.7mV    756.2mV
52ps      700.3mV    662.7mV    647.7mV
141ps     702.2mV    675.2mV    144.9mV
179ps     623.5mV    676.6mV    64.29mV
218ps     449.5mV    661mV      29.76mV
269ps     203mV      583.9mV    11.87mV
320ps     78.87mV    423.8mV    4.983mV
396ps     20.7mV     161.9mV    1.385mV
486ps     5.662mV    39.46mV    299.4uV
1.25ns    1.767uV    23.14uV    534.3nV
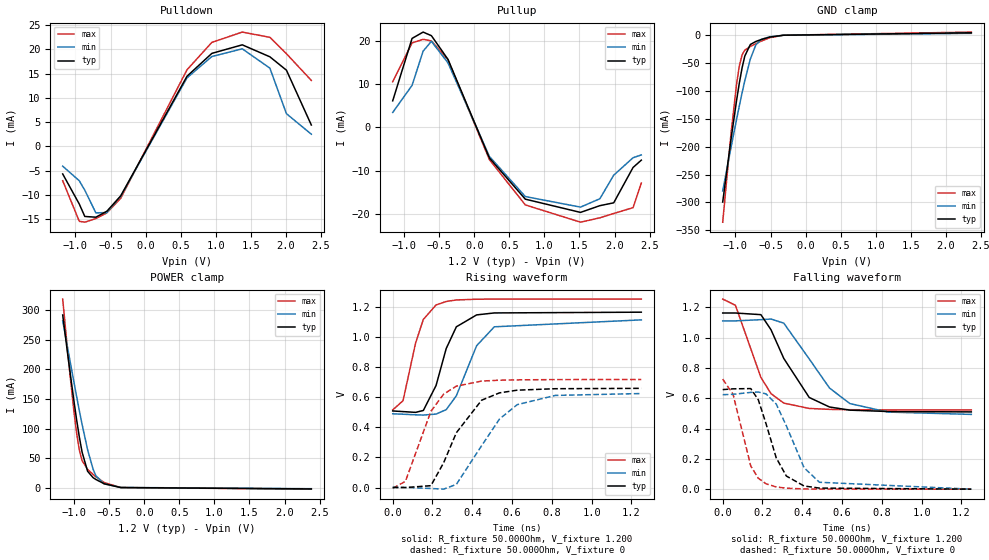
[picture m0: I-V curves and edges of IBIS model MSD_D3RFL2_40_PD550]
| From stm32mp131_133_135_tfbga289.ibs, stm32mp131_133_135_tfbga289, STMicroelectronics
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[Model] MSD_D3RFL2_40_PD550
Model_type   I/O
C_comp 2.431pF   2.345pF   2.556pF
Vinh = 820.000mV
Vinl = 380.000mV
Vmeas = 600.000mV
Vref = 600.000mV
[Model Spec]
Vinh   820.000mV   790.000mV   870.000mV
Vinl   380.000mV   350.000mV   430.000mV
Vmeas   600.000mV   570.000mV   650.000mV
Vref   600.000mV   570.000mV   650.000mV
[Receiver Thresholds]
Vth   =  0.600V
Vth_min  =  0.5880V
Vth_max  =  0.6120V
Vinh_ac  =  0.220V
Vinh_dc  =  0.130V
Vinl_ac  = -0.220V
Vinl_dc  = -0.130V
Tslew_ac =  5.000ns |Not specified, so set to high value
[Temperature Range]   25.000   125.000   -40.000
[Voltage Range]   1.200V   1.140V   1.300V
[GND Clamp Reference]   0.00V   0.00V   0.00V
[Pulldown Reference]   0.00V   0.00V   0.00V
[POWER Clamp Reference]   1.200V   1.140V   1.300V
[Pullup Reference]   1.200V   1.140V   1.300V
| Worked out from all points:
|   slope of the pulldown table from 0 to 0.18 V, typ, clamps not added: 35.6 ohm
|   slope of the pullup table from 0 to 0.18 V, typ, clamps not added: 29.6 ohm
|   GND clamp passes 1 mA (typ) near -0.40 V on its own axis
|   POWER clamp passes 1 mA (typ) near -0.41 V on its own axis
|   rising waveform, R_fixture 50.000Ohm, V_fixture 1.200: 20-80 % time 94.5ps typ, 122ps min, 80.9ps max; typ from 0.508 V to 1.16 V
|   rising waveform, R_fixture 50.000Ohm, V_fixture 0: 20-80 % time 154ps typ, 188ps min, 131ps max; typ from 0.001 V to 0.658 V
|   falling waveform, R_fixture 50.000Ohm, V_fixture 1.200: 20-80 % time 158ps typ, 200ps min, 125ps max; typ from 1.16 V to 0.51 V
|   falling waveform, R_fixture 50.000Ohm, V_fixture 0: 20-80 % time 98.9ps typ, 124ps min, 83.2ps max; typ from 0.657 V to 0 V
[GND Clamp]
-1.182V   -299.4mA   -279.4mA   -335.5mA
-1.064V   -187.2mA   -201.7mA   -177.2mA
-984.9mV  -117.7mA   -151.5mA   -88.38mA
-945.5mV  -86.38mA   -127.3mA   -55.57mA
-906.1mV  -58.98mA   -103.8mA   -35.45mA
-866.7mV  -37.48mA   -81.61mA   -27.05mA
-787.9mV  -16.83mA   -42.88mA   -20.43mA
-709.1mV  -11.34mA   -17.45mA   -15.32mA
-630.3mV  -7.809mA   -7.49mA    -10.62mA
-512.1mV  -3.532mA   -3.013mA   -4.68mA
-315.1mV  -161.1uA   -227.4uA   -151.1uA
2.364V    4.162mA    3.192mA    5.446mA
[Power Clamp]
-1.164V   292.2mA    282.4mA    319.1mA
-1.085V   218.5mA    230.7mA    219.9mA
-1.006V   148.3mA    179.9mA    131mA
-966.7mV  115.8mA    155mA      93.19mA
-927.3mV  85.99mA    130.7mA    63.83mA
-887.9mV  60.26mA    107.3mA    45.72mA
-809.1mV  27.71mA    64.21mA    31.02mA
-730.3mV  16.94mA    31.06mA    22.31mA
-690.9mV  13.86mA    20.24mA    18.46mA
-572.7mV  6.594mA    6.506mA    8.718mA
-336.4mV  182.6uA    351.4uA    213.2uA
2.382V    -2.141mA   -1.766mA   -2.539mA
[Pulldown]
-1.182V   -5.7mA     -4.1mA     -7.1mA
-945.5mV  -11.91mA   -7.1mA     -15.47mA
-866.7mV  -14.47mA   -9.06mA    -15.65mA
-709.1mV  -14.62mA   -13.73mA   -14.9mA
-551.5mV  -13.38mA   -13.66mA   -13.72mA
-354.6mV  -10.22mA   -10.29mA   -10.71mA
590.9mV   14.46mA    14.13mA    15.79mA
945.5mV   19.18mA    18.53mA    21.45mA
1.379V    20.94mA    20.12mA    23.57mA
1.773V    18.47mA    16.13mA    22.49mA
2.009V    15.71mA    6.74mA     19.11mA
2.364V    4.4mA      2.5mA      13.6mA
[Pullup]
-1.164V   6.1mA      3.409mA    10.51mA
-887.9mV  20.51mA    9.662mA    19.47mA
-730.3mV  21.97mA    17.57mA    20.3mA
-612.1mV  21.14mA    19.84mA    19.93mA
-375.8mV  15.67mA    14.87mA    15.59mA
215.2mV   -7.105mA   -6.743mA   -7.481mA
727.3mV   -16.61mA   -16.01mA   -17.94mA
1.515V    -19.67mA   -18.45mA   -21.93mA
1.791V    -18.11mA   -16.51mA   -20.92mA
1.988V    -17.46mA   -11.08mA   -19.92mA
2.264V    -9.3mA     -7.043mA   -18.57mA
2.382V    -7.6mA     -6.395mA   -12.88mA
[Ramp]
R_load=50.000Ohm
dV/dt_r   393.420mV/125.000ps  373.229mV/155.500ps  432.960mV/106.000ps
dV/dt_f   393.420mV/129.500ps  373.229mV/163.000ps  432.960mV/104.000ps
[Rising waveform]
R_fixture=50.000Ohm
V_fixture=1.200
V_fixture_min=1.140
V_fixture_max=1.300
0s        507.9mV    489.1mV    514.6mV
52ps      503.6mV    486.2mV    576.1mV
115ps     498.5mV    482.3mV    958.3mV
154ps     511.1mV    480.7mV    1.115V
218ps     676.8mV    487.2mV    1.211V
269ps     921.9mV    516.5mV    1.234V
320ps     1.066V     608.6mV    1.244V
422ps     1.145V     940.7mV    1.249V
511ps     1.158V     1.066V     1.25V
1.25ns    1.163V     1.112V     1.25V
[Rising waveform]
R_fixture=50.000Ohm
V_fixture=0
0s        839.2uV    803.1uV    -5.389mV
64ps      -188.5uV   788.4uV    41.16mV
192ps     12.25mV    -6.441mV   505.5mV
256ps     164.1mV    -10.87mV   619.3mV
320ps     363.4mV    20.68mV    672.3mV
447ps     579.1mV    277.6mV    706.1mV
537ps     627.9mV    454.5mV    711.9mV
626ps     645.7mV    549.7mV    714.1mV
817ps     655.4mV    610.9mV    715.9mV
1.25ns    657.8mV    623.5mV    716.2mV
[Falling waveform]
R_fixture=50.000Ohm
V_fixture=1.200
V_fixture_min=1.140
V_fixture_max=1.300
0s        1.163V     1.111V     1.255V
64ps      1.163V     1.111V     1.214V
192ps     1.152V     1.119V     737.6mV
243ps     1.052V     1.123V     630.5mV
307ps     863.1mV    1.096V     568.2mV
435ps     605.3mV    859.8mV    532.9mV
537ps     542.4mV    667.6mV    526.8mV
639ps     521.7mV    565.3mV    524.5mV
830ps     512.7mV    509mV      523.4mV
1.25ns    510mV      493.6mV    523.2mV
[Falling waveform]
R_fixture=50.000Ohm
V_fixture=0
0s        657.3mV    623.6mV    726.8mV
52ps      662.3mV    626.3mV    627.1mV
141ps     664.1mV    638.8mV    152.6mV
179ps     589.8mV    641.3mV    72.13mV
218ps     431.5mV    628.8mV    35.12mV
269ps     206.8mV    562.2mV    14.67mV
320ps     86.78mV    418.1mV    6.367mV
409ps     20.99mV    141.7mV    1.502mV
486ps     7.174mV    45.58mV    453.1uV
1.25ns    2.692uV    24.17uV    907.7nV
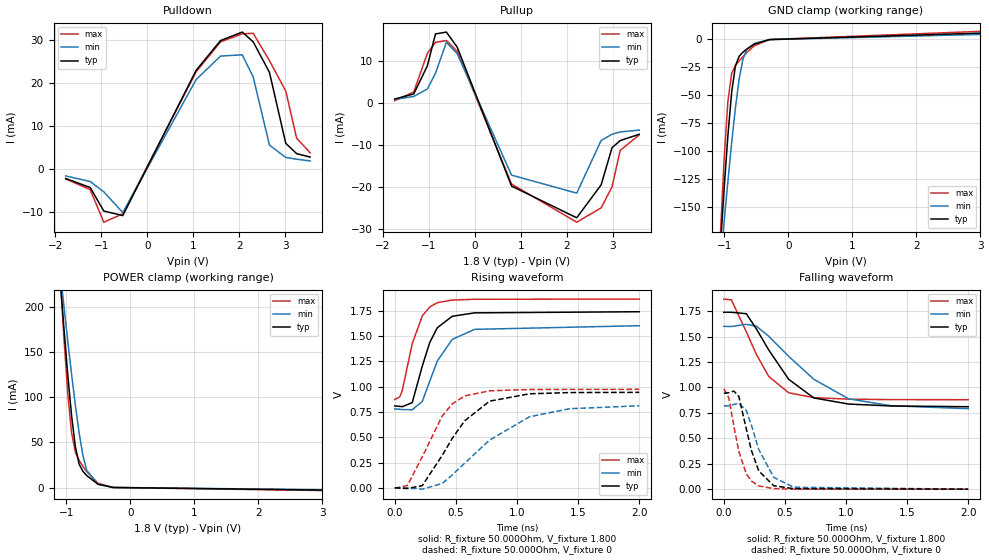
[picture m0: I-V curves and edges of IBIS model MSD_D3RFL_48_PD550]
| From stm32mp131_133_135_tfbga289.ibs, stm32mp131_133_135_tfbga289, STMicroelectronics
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[Model] MSD_D3RFL_48_PD550
Model_type   I/O
C_comp 2.402pF   2.318pF   2.526pF
Vinh = 1.440V
Vinl = 360.000mV
Vmeas = 900.000mV
Vref = 900.000mV
[Model Spec]
Vinh   1.440V   1.365V   1.515V
Vinl   360.000mV   285.000mV   435.000mV
Vmeas   900.000mV   825.000mV   975.000mV
Vref   900.000mV   825.000mV   975.000mV
[Temperature Range]   25.000   125.000   -40.000
[Voltage Range]   1.800V   1.650V   1.950V
[GND Clamp Reference]   0.00V   0.00V   0.00V
[Pulldown Reference]   0.00V   0.00V   0.00V
[POWER Clamp Reference]   1.800V   1.650V   1.950V
[Pullup Reference]   1.800V   1.650V   1.950V
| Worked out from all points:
|   slope of the pulldown table from 0 to 0.27 V, typ, clamps not added: 41 ohm
|   slope of the pullup table from 0 to 0.27 V, typ, clamps not added: 32.3 ohm
|   GND clamp passes 1 mA (typ) near -0.40 V on its own axis
|   POWER clamp passes 1 mA (typ) near -0.41 V on its own axis
|   rising waveform, R_fixture 50.000Ohm, V_fixture 1.800: 20-80 % time 149ps typ, 190ps min, 132ps max; typ from 0.81 V to 1.74 V
|   rising waveform, R_fixture 50.000Ohm, V_fixture 0: 20-80 % time 319ps typ, 495ps min, 247ps max; typ from 0.001 V to 0.943 V
|   falling waveform, R_fixture 50.000Ohm, V_fixture 1.800: 20-80 % time 320ps typ, 469ps min, 247ps max; typ from 1.74 V to 0.811 V
|   falling waveform, R_fixture 50.000Ohm, V_fixture 0: 20-80 % time 126ps typ, 157ps min, 109ps max; typ from 0.942 V to 0 V
[GND Clamp]
-1.773V   -890.2mA   -681.5mA   -1.194A
-1.064V   -187.1mA   -201.7mA   -177.2mA
-1.005V   -134.4mA   -163.8mA   -108.3mA
-945.5mV  -86.37mA   -127.2mA   -55.57mA
-886.4mV  -47.35mA   -92.53mA   -30.23mA
-827.3mV  -23.67mA   -61.04mA   -23.25mA
-768.2mV  -14.93mA   -34.97mA   -19.12mA
-709.1mV  -11.33mA   -17.43mA   -15.32mA
-650mV    -8.632mA   -8.975mA   -11.75mA
-531.8mV  -4.149mA   -3.512mA   -5.543mA
-295.4mV  -94.18uA   -149.6uA   -79.84uA
3.545V    6.63mA     5.259mA    8.494mA
[Power Clamp]
-1.745V   859.9mA    674.3mA    1.126A
-1.095V   228.4mA    237.9mA    233.1mA
-1.036V   174.7mA    199.5mA    164.1mA
-977.3mV  124.4mA    161.9mA    103.9mA
-918.2mV  79.7mA     125.5mA    60.62mA
-859.1mV  45.08mA    91.1mA     39.11mA
-800mV    25.79mA    60.22mA    30.02mA
-740.9mV  17.93mA    35.37mA    23.47mA
-681.8mV  13.24mA    18.98mA    17.67mA
-504.5mV  3.563mA    3.666mA    4.672mA
-268.2mV  26.02uA    95.29uA    30.5uA
3.573V    -3.355mA   -2.916mA   -3.915mA
[Pulldown]
-1.773V   -2.3mA     -1.7mA     -2.4mA
-1.241V   -4.4mA     -3mA       -4.9mA
-945.5mV  -9.88mA    -5.4mA     -12.48mA
-531.8mV  -10.94mA   -10.23mA   -10.54mA
1.064V    22.92mA    20.76mA    22.58mA
1.595V    29.86mA    26.24mA    29.55mA
2.068V    31.83mA    26.53mA    31.42mA
2.305V    29.56mA    21.37mA    31.55mA
2.659V    22.44mA    5.5mA      25.16mA
3.014V    5.9mA      2.6mA      18.1mA
3.25V     3.5mA      2.2mA      7.1mA
3.545V    2.7mA      1.8mA      3.7mA
[Pullup]
-1.745V   1mA        900uA      600uA
-1.332V   2.2mA      1.608mA    2.669mA
-1.036V   8.9mA      3.377mA    11.85mA
-859.1mV  16.47mA    7.104mA    14.48mA
-622.7mV  16.92mA    14.49mA    14.91mA
-386.4mV  13.34mA    11.77mA    12.33mA
795.5mV   -19.73mA   -17.12mA   -19.23mA
2.214V    -27.27mA   -21.4mA    -28.32mA
2.745V    -19.44mA   -8.877mA   -24.91mA
2.982V    -10.6mA    -7.392mA   -19.91mA
3.159V    -8.9mA     -6.846mA   -11.25mA
3.573V    -7.4mA     -6.4mA     -7.554mA
[Ramp]
R_load=50.000Ohm
dV/dt_r   561.840mV/235.500ps  489.359mV/343.500ps  587.250mV/190.000ps
dV/dt_f   561.809mV/224.500ps  488.456mV/314.500ps  587.250mV/177.500ps
[Rising waveform]
R_fixture=50.000Ohm
V_fixture=1.800
V_fixture_min=1.650
V_fixture_max=1.950
0s        809.6mV    779.6mV    873.3mV
41ps      805mV      775.8mV    898.8mV
62ps      801.9mV    773.1mV    964.9mV
143ps     841.8mV    771.8mV    1.425V
225ps     1.202V     852.4mV    1.696V
286ps     1.435V     1.053V     1.786V
348ps     1.581V     1.252V     1.828V
470ps     1.694V     1.466V     1.854V
654ps     1.728V     1.565V     1.862V
2ns       1.739V     1.601V     1.864V
[Rising waveform]
R_fixture=50.000Ohm
V_fixture=0
0s        1.031mV    1.111mV    -2.544mV
103ps     -5.661mV   -1.215mV   23.82mV
225ps     22.55mV    -12.3mV    307mV
388ps     320.5mV    43.84mV    709.4mV
470ps     488.6mV    127.1mV    829.3mV
572ps     662.4mV    244.4mV    907.6mV
776ps     856.4mV    472.2mV    958.6mV
1.103ns   929.1mV    702.7mV    971.3mV
1.43ns    941.2mV    781.6mV    972.5mV
2ns       943.3mV    810.7mV    972.7mV
[Falling waveform]
R_fixture=50.000Ohm
V_fixture=1.800
V_fixture_min=1.650
V_fixture_max=1.950
0s        1.739V     1.601V     1.869V
62ps      1.739V     1.599V     1.861V
184ps     1.725V     1.621V     1.548V
266ps     1.577V     1.603V     1.327V
368ps     1.368V     1.503V     1.108V
531ps     1.08V      1.306V     947.7mV
736ps     897.3mV    1.081V     900.3mV
1.021ns   836.8mV    888.3mV    885mV
1.369ns   817.8mV    820.2mV    880.5mV
2ns       810.6mV    791.5mV    879.5mV
[Falling waveform]
R_fixture=50.000Ohm
V_fixture=0
0s        942.5mV    817.1mV    987.5mV
41ps      948.5mV    820.4mV    898.6mV
82ps      964.7mV    832.9mV    623mV
123ps     912.7mV    843.8mV    372.2mV
184ps     593.3mV    774.2mV    151.6mV
225ps     383.7mV    633.1mV    80.7mV
286ps     179.6mV    390.3mV    31.82mV
409ps     33.79mV    115.5mV    5.536mV
572ps     4.671mV    19.03mV    920.2uV
2ns       14.52uV    88.7uV     0V
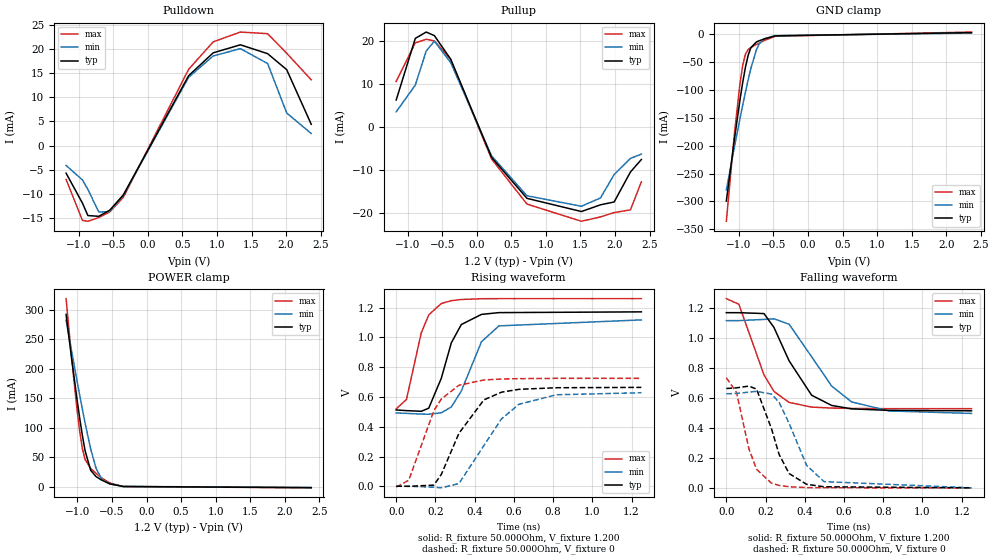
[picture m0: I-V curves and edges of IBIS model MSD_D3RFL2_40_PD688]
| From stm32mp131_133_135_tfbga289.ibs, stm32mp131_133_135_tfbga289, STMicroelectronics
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[Model] MSD_D3RFL2_40_PD688
Model_type   I/O
C_comp 2.461pF   2.375pF   2.586pF
Vinh = 820.000mV
Vinl = 380.000mV
Vmeas = 600.000mV
Vref = 600.000mV
[Model Spec]
Vinh   820.000mV   790.000mV   870.000mV
Vinl   380.000mV   350.000mV   430.000mV
Vmeas   600.000mV   570.000mV   650.000mV
Vref   600.000mV   570.000mV   650.000mV
[Receiver Thresholds]
Vth   =  0.600V
Vth_min  =  0.5880V
Vth_max  =  0.6120V
Vinh_ac  =  0.220V
Vinh_dc  =  0.130V
Vinl_ac  = -0.220V
Vinl_dc  = -0.130V
Tslew_ac =  5.000ns |Not specified, so set to high value
[Temperature Range]   25.000   125.000   -40.000
[Voltage Range]   1.200V   1.140V   1.300V
[GND Clamp Reference]   0.00V   0.00V   0.00V
[Pulldown Reference]   0.00V   0.00V   0.00V
[POWER Clamp Reference]   1.200V   1.140V   1.300V
[Pullup Reference]   1.200V   1.140V   1.300V
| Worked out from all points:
|   slope of the pulldown table from 0 to 0.18 V, typ, clamps not added: 35.6 ohm
|   slope of the pullup table from 0 to 0.18 V, typ, clamps not added: 29.6 ohm
|   GND clamp passes 1 mA (typ) near -0.40 V on its own axis
|   POWER clamp passes 1 mA (typ) near -0.41 V on its own axis
|   rising waveform, R_fixture 50.000Ohm, V_fixture 1.200: 20-80 % time 95ps typ, 122ps min, 81.3ps max; typ from 0.512 V to 1.17 V
|   rising waveform, R_fixture 50.000Ohm, V_fixture 0: 20-80 % time 156ps typ, 189ps min, 133ps max; typ from 0.001 V to 0.664 V
|   falling waveform, R_fixture 50.000Ohm, V_fixture 1.200: 20-80 % time 161ps typ, 202ps min, 128ps max; typ from 1.17 V to 0.514 V
|   falling waveform, R_fixture 50.000Ohm, V_fixture 0: 20-80 % time 100ps typ, 124ps min, 84.6ps max; typ from 0.664 V to 0 V
[GND Clamp]
-1.182V   -299.6mA   -279.7mA   -335.9mA
-1.064V   -187.4mA   -201.8mA   -177.5mA
-984.9mV  -117.9mA   -151.6mA   -88.6mA
-945.5mV  -86.54mA   -127.3mA   -55.77mA
-906.1mV  -59.13mA   -104mA     -35.64mA
-866.7mV  -37.61mA   -81.71mA   -27.22mA
-827.3mV  -23.8mA    -61.15mA   -23.42mA
-748.5mV  -13.62mA   -28.14mA   -17.95mA
-709.1mV  -11.42mA   -17.52mA   -15.44mA
-630.3mV  -7.875mA   -7.542mA   -10.71mA
-472.7mV  -2.454mA   -2.156mA   -3.182mA
2.364V    3.327mA    2.556mA    4.357mA
[Power Clamp]
-1.164V   292.5mA    282.6mA    319.4mA
-1.085V   218.7mA    230.9mA    220.2mA
-1.006V   148.5mA    180.1mA    131.2mA
-966.7mV  115.9mA    155.2mA    93.42mA
-927.3mV  86.16mA    130.9mA    64.04mA
-887.9mV  60.43mA    107.4mA    45.92mA
-809.1mV  27.85mA    64.33mA    31.18mA
-730.3mV  17.06mA    31.16mA    22.45mA
-651.5mV  11.24mA    13.38mA    14.99mA
-533.3mV  4.769mA    4.703mA    6.239mA
-336.4mV  190.8uA    361uA      219.4uA
2.382V    -1.713mA   -1.413mA   -2.032mA
[Pulldown]
-1.182V   -5.7mA     -4.1mA     -7mA
-945.5mV  -11.89mA   -7.1mA     -15.47mA
-866.7mV  -14.47mA   -9.06mA    -15.65mA
-709.1mV  -14.62mA   -13.73mA   -14.89mA
-551.5mV  -13.37mA   -13.66mA   -13.72mA
-354.6mV  -10.22mA   -10.29mA   -10.71mA
590.9mV   14.46mA    14.13mA    15.78mA
945.5mV   19.18mA    18.53mA    21.45mA
1.339V    20.84mA    20.05mA    23.48mA
1.733V    19.01mA    16.97mA    23.14mA
2.009V    15.7mA     6.74mA     19.1mA
2.364V    4.4mA      2.5mA      13.6mA
[Pullup]
-1.164V   6.2mA      3.457mA    10.51mA
-887.9mV  20.5mA     9.662mA    19.46mA
-730.3mV  21.97mA    17.56mA    20.29mA
-612.1mV  21.14mA    19.85mA    19.93mA
-375.8mV  15.67mA    14.87mA    15.59mA
215.2mV   -7.105mA   -6.743mA   -7.481mA
727.3mV   -16.61mA   -16.01mA   -17.94mA
1.515V    -19.67mA   -18.45mA   -21.93mA
1.791V    -18.11mA   -16.51mA   -20.92mA
1.988V    -17.45mA   -11.09mA   -19.91mA
2.224V    -10.5mA    -7.343mA   -19.29mA
2.382V    -7.6mA     -6.348mA   -12.78mA
[Ramp]
R_load=50.000Ohm
dV/dt_r   396.180mV/126.000ps  375.269mV/156.500ps  436.890mV/107.000ps
dV/dt_f   396.180mV/131.500ps  375.239mV/165.000ps  436.890mV/106.500ps
[Rising waveform]
R_fixture=50.000Ohm
V_fixture=1.200
V_fixture_min=1.140
V_fixture_max=1.300
0s        512.5mV    492.6mV    520.1mV
52ps      508.2mV    489.7mV    582.3mV
128ps     503.7mV    484.9mV    1.031V
166ps     524.7mV    483.9mV    1.151V
230ps     725.7mV    493.8mV    1.227V
281ps     963mV      532.6mV    1.246V
332ps     1.086V     639.8mV    1.254V
435ps     1.154V     970.9mV    1.259V
524ps     1.166V     1.077V     1.26V
1.25ns    1.171V     1.117V     1.26V
[Rising waveform]
R_fixture=50.000Ohm
V_fixture=0
0s        817.3uV    795uV      -5.389mV
64ps      -18.26uV   800.2uV    41.15mV
192ps     8.129mV    -6.228mV   507.7mV
230ps     80.02mV    -10.09mV   586.2mV
320ps     356.1mV    18.57mV    678.5mV
447ps     580.2mV    273.3mV    714mV
537ps     632mV      453.1mV    720.3mV
626ps     651.1mV    550.8mV    722.7mV
817ps     661.8mV    614.6mV    724.7mV
1.25ns    664.1mV    628.1mV    725mV
[Falling waveform]
R_fixture=50.000Ohm
V_fixture=1.200
V_fixture_min=1.140
V_fixture_max=1.300
0s        1.17V      1.117V     1.264V
64ps      1.17V      1.117V     1.226V
192ps     1.164V     1.125V     754.1mV
243ps     1.071V     1.129V     643.7mV
320ps     848.4mV    1.093V     570.4mV
435ps     618.5mV    875.2mV    539.4mV
537ps     550.3mV    680.3mV    532.8mV
639ps     527.5mV    573.7mV    530.2mV
830ps     517.4mV    513.6mV    528.9mV
1.25ns    514.4mV    497mV      528.7mV
[Falling waveform]
R_fixture=50.000Ohm
V_fixture=0
0s        663.6mV    628.2mV    735.4mV
52ps      668mV      630.7mV    637mV
115ps     679.7mV    639mV      261.4mV
154ps     659.4mV    644.6mV    124.3mV
230ps     395.9mV    626.2mV    31.11mV
269ps     223.6mV    571.3mV    16.34mV
320ps     95.46mV    430.9mV    7.249mV
409ps     23.75mV    150.4mV    1.777mV
498ps     7.117mV    41.71mV    467.7uV
1.25ns    3.436uV    27.08uV    1.032uV
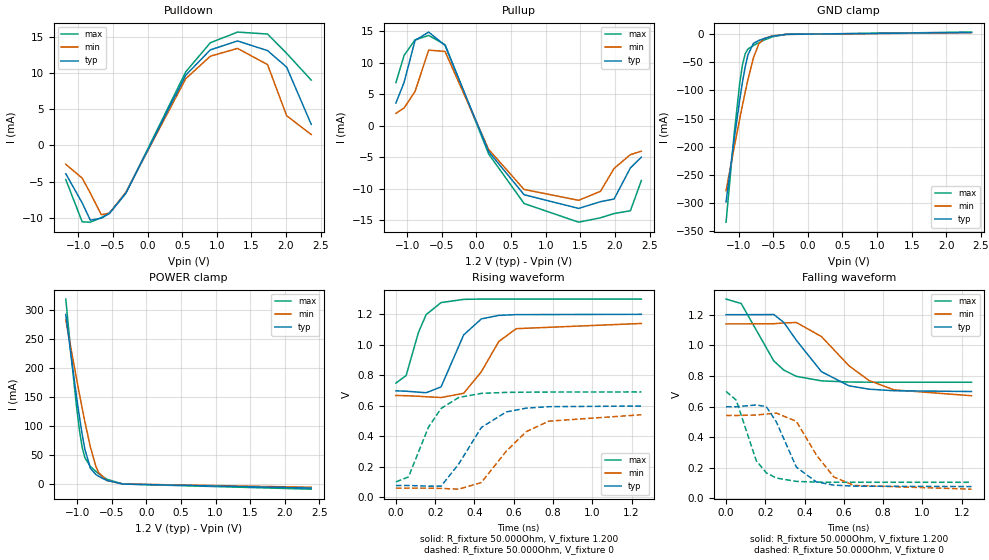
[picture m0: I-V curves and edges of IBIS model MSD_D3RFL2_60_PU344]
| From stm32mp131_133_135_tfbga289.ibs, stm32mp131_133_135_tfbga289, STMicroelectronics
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[Model] MSD_D3RFL2_60_PU344
Model_type   I/O
C_comp 2.348pF   2.261pF   2.473pF
Vinh = 820.000mV
Vinl = 380.000mV
Vmeas = 600.000mV
Vref = 600.000mV
[Model Spec]
Vinh   820.000mV   790.000mV   870.000mV
Vinl   380.000mV   350.000mV   430.000mV
Vmeas   600.000mV   570.000mV   650.000mV
Vref   600.000mV   570.000mV   650.000mV
[Receiver Thresholds]
Vth   =  0.600V
Vth_min  =  0.5880V
Vth_max  =  0.6120V
Vinh_ac  =  0.220V
Vinh_dc  =  0.130V
Vinl_ac  = -0.220V
Vinl_dc  = -0.130V
Tslew_ac =  5.000ns |Not specified, so set to high value
[Temperature Range]   25.000   125.000   -40.000
[Voltage Range]   1.200V   1.140V   1.300V
[GND Clamp Reference]   0.00V   0.00V   0.00V
[Pulldown Reference]   0.00V   0.00V   0.00V
[POWER Clamp Reference]   1.200V   1.140V   1.300V
[Pullup Reference]   1.200V   1.140V   1.300V
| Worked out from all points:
|   slope of the pulldown table from 0 to 0.18 V, typ, clamps not added: 50.1 ohm
|   slope of the pullup table from 0 to 0.18 V, typ, clamps not added: 42.9 ohm
|   GND clamp passes 1 mA (typ) near -0.41 V on its own axis
|   POWER clamp passes 1 mA (typ) near -0.41 V on its own axis
|   rising waveform, R_fixture 50.000Ohm, V_fixture 1.200: 20-80 % time 101ps typ, 133ps min, 82.2ps max; typ from 0.698 V to 1.2 V
|   rising waveform, R_fixture 50.000Ohm, V_fixture 0: 20-80 % time 161ps typ, 203ps min, 129ps max; typ from 0.078 V to 0.599 V
|   falling waveform, R_fixture 50.000Ohm, V_fixture 1.200: 20-80 % time 192ps typ, 243ps min, 154ps max; typ from 1.2 V to 0.698 V
|   falling waveform, R_fixture 50.000Ohm, V_fixture 0: 20-80 % time 114ps typ, 143ps min, 96.2ps max; typ from 0.599 V to 0.078 V
[GND Clamp]
-1.182V   -298.5mA   -278.7mA   -334.6mA
-1.064V   -186.4mA   -201mA     -176.4mA
-984.9mV  -117.1mA   -150.9mA   -87.65mA
-945.5mV  -85.8mA    -126.7mA   -54.89mA
-906.1mV  -58.45mA   -103.4mA   -34.82mA
-866.7mV  -36.99mA   -81.15mA   -26.46mA
-787.9mV  -16.43mA   -42.51mA   -19.96mA
-709.1mV  -11.02mA   -17.14mA   -14.94mA
-630.3mV  -7.563mA   -7.255mA   -10.33mA
-512.1mV  -3.391mA   -2.874mA   -4.513mA
-315.1mV  -135.6uA   -195uA     -130uA
2.364V    3.306mA    2.793mA    3.888mA
[Power Clamp]
-1.164V   291.7mA    282.1mA    318.2mA
-1.085V   217.9mA    230.5mA    219.1mA
-1.006V   147.8mA    179.6mA    130.3mA
-966.7mV  115.4mA    154.8mA    92.58mA
-927.3mV  85.61mA    130.5mA    63.27mA
-887.9mV  59.92mA    107mA      45.21mA
-809.1mV  27.42mA    64.02mA    30.59mA
-730.3mV  16.72mA    30.92mA    21.98mA
-690.9mV  13.66mA    20.11mA    18.17mA
-572.7mV  6.48mA     6.432mA    8.549mA
-336.4mV  188.5uA    360.2uA    208.2uA
2.382V    -6.618mA   -5.26mA    -8.576mA
[Pulldown]
-1.182V   -3.9mA     -2.6mA     -4.7mA
-945.5mV  -7.91mA    -4.5mA     -10.52mA
-827.3mV  -10.3mA    -6.57mA    -10.57mA
-669.7mV  -10.02mA   -9.53mA    -9.94mA
-551.5mV  -9.37mA    -9.334mA   -9.3mA
-315.1mV  -6.566mA   -6.464mA   -6.608mA
551.5mV   9.679mA    9.198mA    10.14mA
906.1mV   13.16mA    12.29mA    14.14mA
1.3V      14.39mA    13.36mA    15.61mA
1.733V    13.06mA    11.13mA    15.34mA
2.009V    10.78mA    4.09mA     12.68mA
2.364V    2.9mA      1.5mA      9mA
[Pullup]
-1.164V   3.6mA      1.952mA    6.838mA
-1.045V   6.9mA      2.809mA    11.16mA
-887.9mV  13.51mA    5.418mA    13.61mA
-690.9mV  14.84mA    11.98mA    14.31mA
-454.5mV  12.73mA    11.77mA    12.85mA
175.8mV   -4.107mA   -3.772mA   -4.491mA
687.9mV   -10.95mA   -10.12mA   -12.35mA
1.476V    -13.13mA   -11.84mA   -15.31mA
1.791V    -12.06mA   -10.42mA   -14.61mA
1.988V    -11.63mA   -6.784mA   -13.94mA
2.224V    -6.7mA     -4.595mA   -13.49mA
2.382V    -5mA       -4.048mA   -8.7mA
[Ramp]
R_load=50.000Ohm
dV/dt_r   307.014mV/131.500ps  286.149mV/169.000ps  338.100mV/106.000ps
dV/dt_f   307.014mV/154.000ps  286.206mV/195.000ps  338.100mV/125.500ps
[Rising waveform]
R_fixture=50.000Ohm
V_fixture=1.200
V_fixture_min=1.140
V_fixture_max=1.300
0s        698.4mV    667.9mV    749.4mV
52ps      696.1mV    666.4mV    798.8mV
115ps     689.7mV    662.8mV    1.082V
154ps     686.1mV    659.9mV    1.198V
230ps     724.4mV    654.7mV    1.277V
345ps     1.065V     682.2mV    1.298V
435ps     1.17V      823.5mV    1.3V
524ps     1.193V     1.022V     1.3V
613ps     1.198V     1.106V     1.3V
1.25ns    1.2V       1.14V      1.3V
[Rising waveform]
R_fixture=50.000Ohm
V_fixture=0
0s        77.75mV    60.67mV    102.1mV
64ps      78mV       60.88mV    134.2mV
166ps     73.58mV    60.63mV    460.4mV
230ps     73.86mV    59.02mV    583mV
320ps     219.2mV    53.96mV    655.1mV
435ps     458.3mV    97.39mV    681.8mV
562ps     560.2mV    302.8mV    688.3mV
664ps     585mV      431.1mV    689.8mV
779ps     594.7mV    499.8mV    690.5mV
1.25ns    598.9mV    541.7mV    691.3mV
[Falling waveform]
R_fixture=50.000Ohm
V_fixture=1.200
V_fixture_min=1.140
V_fixture_max=1.300
0s        1.2V       1.14V      1.302V
77ps      1.2V       1.14V      1.273V
243ps     1.201V     1.141V     898.4mV
294ps     1.15V      1.146V     838.4mV
358ps     1.033V     1.149V     797.3mV
486ps     827.8mV    1.057V     768mV
626ps     735.6mV    866.6mV    760.4mV
728ps     713.7mV    770.2mV    759.2mV
856ps     703.2mV    709mV      758.8mV
1.25ns    698.3mV    670.8mV    758.7mV
[Falling waveform]
R_fixture=50.000Ohm
V_fixture=0
0s        599mV      542.1mV    699.1mV
52ps      598.8mV    541.8mV    641.8mV
154ps     610.5mV    544.9mV    246mV
205ps     599.5mV    551.1mV    167.1mV
256ps     500.3mV    557.4mV    133.4mV
358ps     204.6mV    504.1mV    111.5mV
460ps     108mV      284mV      106.8mV
549ps     87.24mV    140.1mV    106mV
652ps     80.4mV     84.89mV    105.7mV
1.25ns    77.63mV    60.7mV     105.6mV
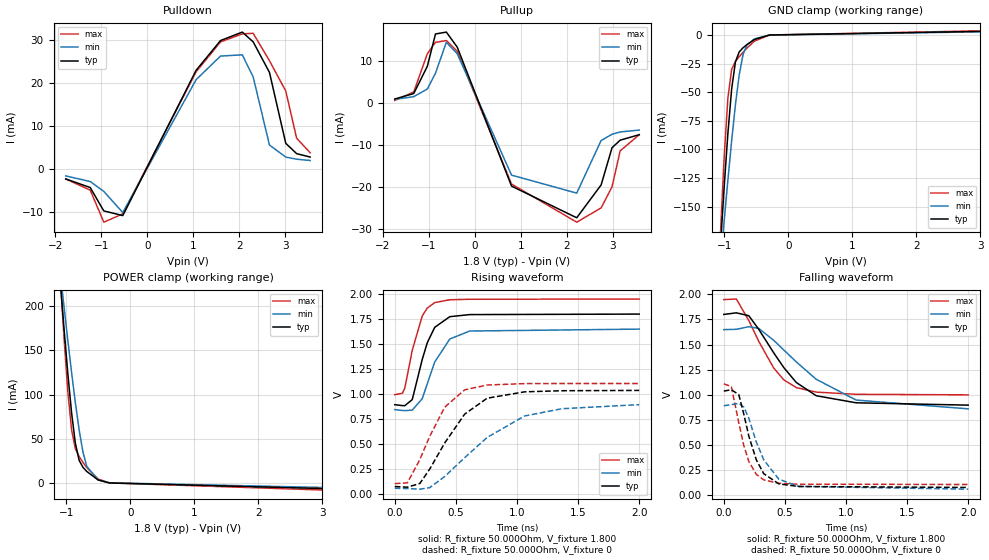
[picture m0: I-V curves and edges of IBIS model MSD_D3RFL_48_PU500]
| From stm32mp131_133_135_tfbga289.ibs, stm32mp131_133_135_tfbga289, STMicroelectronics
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[Model] MSD_D3RFL_48_PU500
Model_type   I/O
C_comp 2.391pF   2.307pF   2.515pF
Vinh = 1.440V
Vinl = 360.000mV
Vmeas = 900.000mV
Vref = 900.000mV
[Model Spec]
Vinh   1.440V   1.365V   1.515V
Vinl   360.000mV   285.000mV   435.000mV
Vmeas   900.000mV   825.000mV   975.000mV
Vref   900.000mV   825.000mV   975.000mV
[Temperature Range]   25.000   125.000   -40.000
[Voltage Range]   1.800V   1.650V   1.950V
[GND Clamp Reference]   0.00V   0.00V   0.00V
[Pulldown Reference]   0.00V   0.00V   0.00V
[POWER Clamp Reference]   1.800V   1.650V   1.950V
[Pullup Reference]   1.800V   1.650V   1.950V
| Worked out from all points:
|   slope of the pulldown table from 0 to 0.27 V, typ, clamps not added: 41 ohm
|   slope of the pullup table from 0 to 0.27 V, typ, clamps not added: 32.3 ohm
|   GND clamp passes 1 mA (typ) near -0.40 V on its own axis
|   POWER clamp passes 1 mA (typ) near -0.41 V on its own axis
|   rising waveform, R_fixture 50.000Ohm, V_fixture 1.800: 20-80 % time 129ps typ, 163ps min, 112ps max; typ from 0.895 V to 1.8 V
|   rising waveform, R_fixture 50.000Ohm, V_fixture 0: 20-80 % time 313ps typ, 504ps min, 239ps max; typ from 0.079 V to 1.04 V
|   falling waveform, R_fixture 50.000Ohm, V_fixture 1.800: 20-80 % time 331ps typ, 476ps min, 261ps max; typ from 1.8 V to 0.897 V
|   falling waveform, R_fixture 50.000Ohm, V_fixture 0: 20-80 % time 142ps typ, 178ps min, 121ps max; typ from 1.04 V to 0.078 V
[GND Clamp]
-1.773V   -889.9mA   -681.2mA   -1.193A
-1.064V   -187mA     -201.5mA   -177.1mA
-1.005V   -134.3mA   -163.7mA   -108.2mA
-945.5mV  -86.27mA   -127.1mA   -55.46mA
-886.4mV  -47.26mA   -92.45mA   -30.13mA
-827.3mV  -23.6mA    -60.96mA   -23.17mA
-768.2mV  -14.86mA   -34.92mA   -19.05mA
-709.1mV  -11.27mA   -17.39mA   -15.26mA
-650mV    -8.582mA   -8.931mA   -11.7mA
-531.8mV  -4.12mA    -3.482mA   -5.513mA
-295.4mV  -88.42uA   -142.6uA   -78.02uA
3.545V    3.572mA    3.151mA    4.141mA
[Power Clamp]
-1.745V   859.7mA    674.3mA    1.126A
-1.095V   228.3mA    237.8mA    233.1mA
-1.036V   174.7mA    199.5mA    164mA
-977.3mV  124.3mA    161.9mA    103.8mA
-918.2mV  79.64mA    125.4mA    60.53mA
-859.1mV  45.03mA    91.04mA    39.03mA
-800mV    25.75mA    60.2mA     29.96mA
-740.9mV  17.89mA    35.35mA    23.42mA
-681.8mV  13.21mA    18.96mA    17.63mA
-504.5mV  3.553mA    3.665mA    4.657mA
-327.3mV  153.6uA    335uA      195.3uA
3.573V    -7.251mA   -5.855mA   -9.213mA
[Pulldown]
-1.773V   -2.4mA     -1.7mA     -2.4mA
-1.241V   -4.4mA     -3mA       -5mA
-945.5mV  -9.85mA    -5.3mA     -12.48mA
-531.8mV  -10.94mA   -10.23mA   -10.54mA
1.064V    22.93mA    20.75mA    22.58mA
1.595V    29.86mA    26.24mA    29.55mA
2.068V    31.83mA    26.53mA    31.41mA
2.305V    29.55mA    21.37mA    31.55mA
2.659V    22.44mA    5.5mA      25.15mA
3.014V    5.9mA      2.7mA      18.1mA
3.25V     3.5mA      2.2mA      7.1mA
3.545V    2.7mA      1.9mA      3.7mA
[Pullup]
-1.745V   1mA        900uA      646.2uA
-1.332V   2.3mA      1.554mA    2.669mA
-1.036V   8.8mA      3.377mA    11.79mA
-859.1mV  16.47mA    7.15mA     14.48mA
-622.7mV  16.92mA    14.49mA    14.91mA
-386.4mV  13.34mA    11.77mA    12.33mA
795.5mV   -19.73mA   -17.12mA   -19.24mA
2.214V    -27.27mA   -21.4mA    -28.32mA
2.745V    -19.45mA   -8.877mA   -24.91mA
2.982V    -10.6mA    -7.392mA   -19.91mA
3.159V    -8.8mA     -6.846mA   -11.35mA
3.573V    -7.5mA     -6.4mA     -7.508mA
[Ramp]
R_load=50.000Ohm
dV/dt_r   559.134mV/221.000ps  488.463mV/329.500ps  585.120mV/176.500ps
dV/dt_f   558.948mV/237.500ps  486.480mV/327.500ps  585.120mV/191.500ps
[Rising waveform]
R_fixture=50.000Ohm
V_fixture=1.800
V_fixture_min=1.650
V_fixture_max=1.950
0s        895.4mV    846mV      995.9mV
62ps      886.6mV    838.1mV    1.009V
82ps      885.9mV    835.8mV    1.06V
143ps     946.2mV    841.5mV    1.439V
225ps     1.348V     956.3mV    1.782V
266ps     1.514V     1.104V     1.86V
327ps     1.668V     1.322V     1.915V
450ps     1.774V     1.551V     1.943V
613ps     1.795V     1.631V     1.948V
2ns       1.8V       1.65V      1.95V
[Rising waveform]
R_fixture=50.000Ohm
V_fixture=0
0s        79.03mV    61.66mV    107.6mV
103ps     71.93mV    58.22mV    115.5mV
205ps     109.2mV    52.32mV    347mV
286ps     252.7mV    67.56mV    579.8mV
409ps     514.1mV    179.1mV    871.3mV
572ps     801.8mV    367.1mV    1.044V
756ps     960.3mV    568.8mV    1.092V
1.062ns   1.024V     782.9mV    1.106V
1.369ns   1.035V     855.5mV    1.107V
2ns       1.038V     896.2mV    1.107V
[Falling waveform]
R_fixture=50.000Ohm
V_fixture=1.800
V_fixture_min=1.650
V_fixture_max=1.950
0s        1.8V       1.649V     1.948V
103ps     1.816V     1.652V     1.953V
205ps     1.787V     1.678V     1.739V
286ps     1.652V     1.661V     1.532V
409ps     1.417V     1.542V     1.266V
491ps     1.271V     1.446V     1.149V
593ps     1.123V     1.328V     1.072V
756ps     991.2mV    1.155V     1.027V
1.083ns   920.6mV    947.8mV    1.005V
2ns       897.3mV    860.3mV    999.8mV
[Falling waveform]
R_fixture=50.000Ohm
V_fixture=0
0s        1.037V     891.9mV    1.11V
62ps      1.051V     901.8mV    1.081V
123ps     1.001V     915.3mV    719.6mV
164ps     807.4mV    878mV      495mV
205ps     588.3mV    765.3mV    336.4mV
266ps     353.3mV    531.1mV    208.5mV
327ps     215mV      353.1mV    153.7mV
450ps     114mV      160.7mV    119.2mV
613ps     87.74mV    88.38mV    110.6mV
2ns       78.09mV    61.1mV     107.5mV
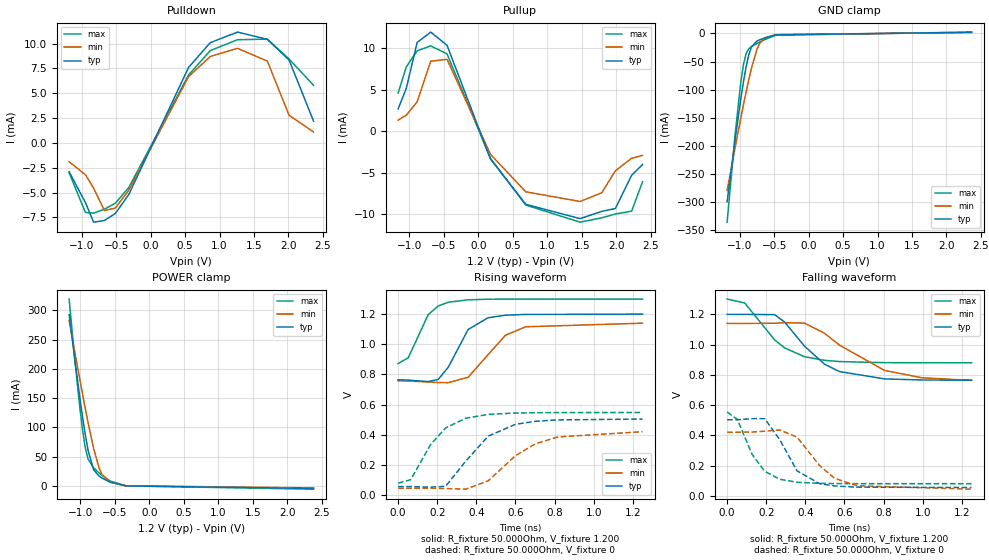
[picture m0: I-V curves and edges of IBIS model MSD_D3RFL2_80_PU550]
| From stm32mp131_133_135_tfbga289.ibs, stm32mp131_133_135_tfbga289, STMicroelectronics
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[Model] MSD_D3RFL2_80_PU550
Model_type   I/O
C_comp 2.435pF   2.348pF   2.561pF
Vinh = 820.000mV
Vinl = 380.000mV
Vmeas = 600.000mV
Vref = 600.000mV
[Model Spec]
Vinh   820.000mV   790.000mV   870.000mV
Vinl   380.000mV   350.000mV   430.000mV
Vmeas   600.000mV   570.000mV   650.000mV
Vref   600.000mV   570.000mV   650.000mV
[Receiver Thresholds]
Vth   =  0.600V
Vth_min  =  0.5880V
Vth_max  =  0.6120V
Vinh_ac  =  0.220V
Vinh_dc  =  0.130V
Vinl_ac  = -0.220V
Vinl_dc  = -0.130V
Tslew_ac =  5.000ns |Not specified, so set to high value
[Temperature Range]   25.000   125.000   -40.000
[Voltage Range]   1.200V   1.140V   1.300V
[GND Clamp Reference]   0.00V   0.00V   0.00V
[Pulldown Reference]   0.00V   0.00V   0.00V
[POWER Clamp Reference]   1.200V   1.140V   1.300V
[Pullup Reference]   1.200V   1.140V   1.300V
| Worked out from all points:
|   slope of the pulldown table from 0 to 0.18 V, typ, clamps not added: 63.6 ohm
|   slope of the pullup table from 0 to 0.18 V, typ, clamps not added: 52.8 ohm
|   GND clamp passes 1 mA (typ) near -0.40 V on its own axis
|   POWER clamp passes 1 mA (typ) near -0.41 V on its own axis
|   rising waveform, R_fixture 50.000Ohm, V_fixture 1.200: 20-80 % time 112ps typ, 149ps min, 96.2ps max; typ from 0.765 V to 1.2 V
|   rising waveform, R_fixture 50.000Ohm, V_fixture 0: 20-80 % time 182ps typ, 228ps min, 155ps max; typ from 0.055 V to 0.504 V
|   falling waveform, R_fixture 50.000Ohm, V_fixture 1.200: 20-80 % time 205ps typ, 276ps min, 186ps max; typ from 1.2 V to 0.765 V
|   falling waveform, R_fixture 50.000Ohm, V_fixture 0: 20-80 % time 120ps typ, 157ps min, 113ps max; typ from 0.503 V to 0.055 V
[GND Clamp]
-1.182V   -299.3mA   -279.3mA   -335.5mA
-1.064V   -187.1mA   -201.6mA   -177.2mA
-984.9mV  -117.6mA   -151.4mA   -88.33mA
-945.5mV  -86.31mA   -127.1mA   -55.53mA
-906.1mV  -58.92mA   -103.8mA   -35.42mA
-866.7mV  -37.43mA   -81.52mA   -27.01mA
-827.3mV  -23.64mA   -60.97mA   -23.23mA
-748.5mV  -13.47mA   -27.99mA   -17.8mA
-709.1mV  -11.3mA    -17.39mA   -15.29mA
-630.3mV  -7.775mA   -7.441mA   -10.6mA
-472.7mV  -2.409mA   -2.105mA   -3.132mA
2.364V    2.067mA    1.746mA    2.431mA
[Power Clamp]
-1.164V   292.4mA    282.7mA    319.1mA
-1.085V   218.6mA    231mA      220mA
-1.006V   148.4mA    180.1mA    131mA
-966.7mV  115.9mA    155.2mA    93.22mA
-927.3mV  86.08mA    130.9mA    63.88mA
-887.9mV  60.35mA    107.4mA    45.77mA
-809.1mV  27.78mA    64.33mA    31.06mA
-730.3mV  17mA       31.16mA    22.35mA
-690.9mV  13.91mA    20.33mA    18.49mA
-572.7mV  6.632mA    6.569mA    8.741mA
-336.4mV  198.8uA    376.6uA    221.3uA
2.382V    -4.134mA   -3.29mA    -5.363mA
[Pulldown]
-1.182V   -2.9mA     -1.9mA     -3mA
-945.5mV  -6.01mA    -3.2mA     -7mA
-827.3mV  -7.98mA    -4.55mA    -7.07mA
-669.7mV  -7.81mA    -6.81mA    -6.67mA
-512.1mV  -7.108mA   -6.559mA   -6.077mA
-315.1mV  -5.18mA    -4.739mA   -4.478mA
551.5mV   7.6mA      6.678mA    6.842mA
866.7mV   10.09mA    8.7mA      9.291mA
1.261V    11.15mA    9.516mA    10.38mA
1.694V    10.42mA    8.231mA    10.44mA
2.009V    8.34mA     2.78mA     8.44mA
2.364V    2.2mA      1.1mA      5.8mA
[Pullup]
-1.164V   2.7mA      1.352mA    4.608mA
-1.045V   5.2mA      1.957mA    7.769mA
-887.9mV  10.71mA    3.556mA    9.704mA
-690.9mV  11.96mA    8.455mA    10.29mA
-454.5mV  10.37mA    8.68mA     9.333mA
175.8mV   -3.335mA   -2.766mA   -3.264mA
687.9mV   -8.796mA   -7.289mA   -8.883mA
1.476V    -10.52mA   -8.453mA   -10.95mA
1.791V    -9.644mA   -7.401mA   -10.42mA
1.988V    -9.3mA     -4.754mA   -9.962mA
2.224V    -5.3mA     -3.248mA   -9.615mA
2.382V    -4mA       -2.9mA     -6.085mA
[Ramp]
R_load=50.000Ohm
dV/dt_r   265.101mV/147.500ps  227.751mV/190.000ps  266.043mV/126.500ps
dV/dt_f   265.101mV/163.500ps  227.661mV/221.000ps  266.043mV/150.000ps
[Rising waveform]
R_fixture=50.000Ohm
V_fixture=1.200
V_fixture_min=1.140
V_fixture_max=1.300
0s        764.6mV    757.8mV    871.7mV
52ps      762.1mV    756.3mV    910.9mV
154ps     752.3mV    749.9mV    1.197V
205ps     766.5mV    746.1mV    1.254V
256ps     846.8mV    744.9mV    1.279V
358ps     1.098V     781.1mV    1.295V
460ps     1.176V     930.9mV    1.299V
549ps     1.193V     1.06V      1.3V
652ps     1.198V     1.116V     1.3V
1.25ns    1.2V       1.14V      1.3V
[Rising waveform]
R_fixture=50.000Ohm
V_fixture=0
0s        55.36mV    44.31mV    77.94mV
64ps      55.64mV    44.5mV     101.1mV
166ps     51.79mV    44.39mV    334.1mV
243ps     57.5mV     42.64mV    444.8mV
345ps     222.9mV    38.39mV    508.8mV
460ps     389.7mV    92.99mV    534.5mV
600ps     468.8mV    260.5mV    543.9mV
703ps     489mV      340.1mV    546mV
817ps     498.2mV    384.9mV    546.7mV
1.25ns    503.6mV    419.8mV    547.1mV
[Falling waveform]
R_fixture=50.000Ohm
V_fixture=1.200
V_fixture_min=1.140
V_fixture_max=1.300
0s        1.2V       1.14V      1.301V
90ps      1.2V       1.14V      1.275V
243ps     1.198V     1.141V     1.031V
294ps     1.149V     1.145V     978.3mV
396ps     989.4mV    1.142V     919.9mV
498ps     870.7mV    1.075V     895.9mV
575ps     821.5mV    996.1mV    887.8mV
805ps     773.3mV    829.3mV    880.7mV
996ps     766.1mV    780.7mV    880.1mV
1.25ns    764.6mV    763.1mV    880mV
[Falling waveform]
R_fixture=50.000Ohm
V_fixture=0
0s        503.2mV    420.9mV    554.3mV
52ps      503.1mV    420.6mV    506.1mV
128ps     510.4mV    421.8mV    273.5mV
192ps     510.5mV    427.8mV    162.7mV
269ps     371.6mV    435.8mV    109.7mV
358ps     164.9mV    387.7mV    90mV
473ps     80.79mV    200.3mV    82.71mV
549ps     65.57mV    116.6mV    81.24mV
664ps     57.64mV    66.68mV    80.64mV
1.25ns    55.23mV    44.3mV     80.49mV
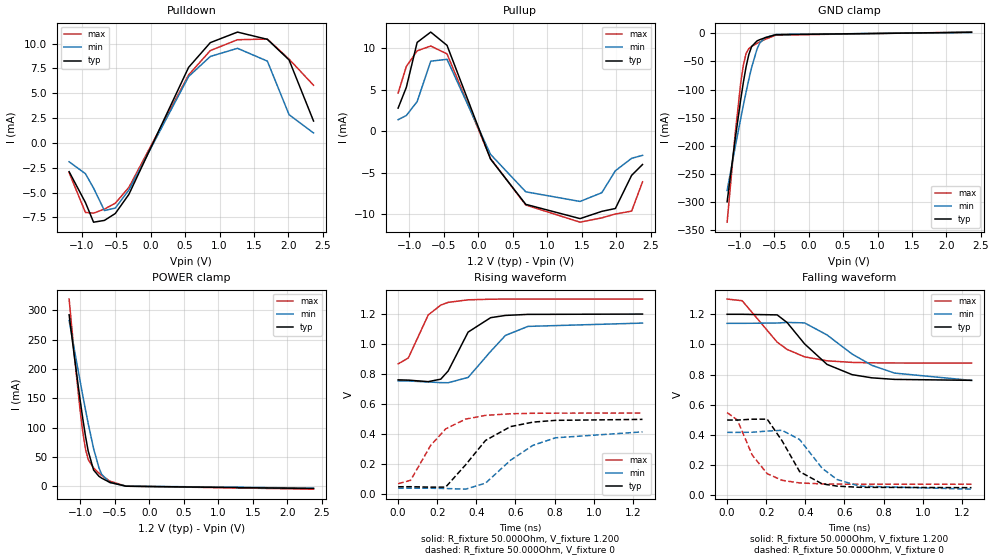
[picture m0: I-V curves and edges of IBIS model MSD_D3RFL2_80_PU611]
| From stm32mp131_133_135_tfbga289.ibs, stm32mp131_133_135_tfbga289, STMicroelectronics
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[Model] MSD_D3RFL2_80_PU611
Model_type   I/O
C_comp 2.451pF   2.364pF   2.578pF
Vinh = 820.000mV
Vinl = 380.000mV
Vmeas = 600.000mV
Vref = 600.000mV
[Model Spec]
Vinh   820.000mV   790.000mV   870.000mV
Vinl   380.000mV   350.000mV   430.000mV
Vmeas   600.000mV   570.000mV   650.000mV
Vref   600.000mV   570.000mV   650.000mV
[Receiver Thresholds]
Vth   =  0.600V
Vth_min  =  0.5880V
Vth_max  =  0.6120V
Vinh_ac  =  0.220V
Vinh_dc  =  0.130V
Vinl_ac  = -0.220V
Vinl_dc  = -0.130V
Tslew_ac =  5.000ns |Not specified, so set to high value
[Temperature Range]   25.000   125.000   -40.000
[Voltage Range]   1.200V   1.140V   1.300V
[GND Clamp Reference]   0.00V   0.00V   0.00V
[Pulldown Reference]   0.00V   0.00V   0.00V
[POWER Clamp Reference]   1.200V   1.140V   1.300V
[Pullup Reference]   1.200V   1.140V   1.300V
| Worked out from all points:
|   slope of the pulldown table from 0 to 0.18 V, typ, clamps not added: 63.6 ohm
|   slope of the pullup table from 0 to 0.18 V, typ, clamps not added: 52.8 ohm
|   GND clamp passes 1 mA (typ) near -0.40 V on its own axis
|   POWER clamp passes 1 mA (typ) near -0.41 V on its own axis
|   rising waveform, R_fixture 50.000Ohm, V_fixture 1.200: 20-80 % time 112ps typ, 150ps min, 97.7ps max; typ from 0.762 V to 1.2 V
|   rising waveform, R_fixture 50.000Ohm, V_fixture 0: 20-80 % time 184ps typ, 230ps min, 157ps max; typ from 0.05 V to 0.499 V
|   falling waveform, R_fixture 50.000Ohm, V_fixture 1.200: 20-80 % time 206ps typ, 277ps min, 188ps max; typ from 1.2 V to 0.762 V
|   falling waveform, R_fixture 50.000Ohm, V_fixture 0: 20-80 % time 121ps typ, 157ps min, 114ps max; typ from 0.499 V to 0.05 V
[GND Clamp]
-1.182V   -299.4mA   -279.4mA   -335.7mA
-1.064V   -187.2mA   -201.7mA   -177.3mA
-984.9mV  -117.7mA   -151.5mA   -88.45mA
-945.5mV  -86.41mA   -127.2mA   -55.64mA
-906.1mV  -59.01mA   -103.9mA   -35.52mA
-866.7mV  -37.5mA    -81.58mA   -27.1mA
-827.3mV  -23.7mA    -61.03mA   -23.31mA
-748.5mV  -13.53mA   -28.05mA   -17.87mA
-709.1mV  -11.34mA   -17.43mA   -15.36mA
-630.3mV  -7.814mA   -7.472mA   -10.65mA
-472.7mV  -2.424mA   -2.118mA   -3.155mA
2.364V    1.86mA     1.572mA    2.188mA
[Power Clamp]
-1.164V   292.5mA    282.8mA    319.3mA
-1.085V   218.7mA    231.1mA    220.1mA
-1.006V   148.5mA    180.2mA    131.1mA
-966.7mV  116mA      155.3mA    93.34mA
-927.3mV  86.16mA    131mA      63.99mA
-887.9mV  60.42mA    107.5mA    45.87mA
-809.1mV  27.84mA    64.38mA    31.14mA
-730.3mV  17.05mA    31.2mA     22.42mA
-690.9mV  13.96mA    20.37mA    18.55mA
-572.7mV  6.658mA    6.592mA    8.774mA
-336.4mV  200.5uA    379.1uA    223.4uA
2.382V    -3.72mA    -2.96mA    -4.821mA
[Pulldown]
-1.182V   -2.9mA     -1.9mA     -3mA
-945.5mV  -6mA       -3.1mA     -7mA
-827.3mV  -7.98mA    -4.55mA    -7.07mA
-669.7mV  -7.8mA     -6.81mA    -6.66mA
-512.1mV  -7.107mA   -6.56mA    -6.071mA
-315.1mV  -5.18mA    -4.739mA   -4.478mA
551.5mV   7.6mA      6.678mA    6.842mA
866.7mV   10.09mA    8.7mA      9.291mA
1.261V    11.15mA    9.517mA    10.38mA
1.694V    10.42mA    8.229mA    10.45mA
2.009V    8.35mA     2.84mA     8.43mA
2.364V    2.2mA      1mA        5.8mA
[Pullup]
-1.164V   2.8mA      1.405mA    4.608mA
-1.045V   5.3mA      1.905mA    7.815mA
-887.9mV  10.72mA    3.587mA    9.704mA
-690.9mV  11.96mA    8.455mA    10.28mA
-454.5mV  10.36mA    8.679mA    9.332mA
175.8mV   -3.334mA   -2.766mA   -3.264mA
687.9mV   -8.799mA   -7.289mA   -8.879mA
1.476V    -10.52mA   -8.449mA   -10.95mA
1.791V    -9.646mA   -7.398mA   -10.43mA
1.988V    -9.3mA     -4.754mA   -9.962mA
2.224V    -5.3mA     -3.248mA   -9.615mA
2.382V    -4mA       -2.9mA     -6.085mA
[Ramp]
R_load=50.000Ohm
dV/dt_r   266.127mV/148.500ps  228.408mV/192.000ps  267.471mV/128.000ps
dV/dt_f   266.127mV/164.500ps  228.321mV/222.500ps  267.471mV/151.000ps
[Rising waveform]
R_fixture=50.000Ohm
V_fixture=1.200
V_fixture_min=1.140
V_fixture_max=1.300
0s        762.1mV    755.8mV    868.3mV
52ps      760.1mV    754.3mV    907.3mV
154ps     750mV      748mV      1.194V
218ps     766.5mV    743.4mV    1.26V
256ps     821.1mV    742.8mV    1.278V
358ps     1.08V      778.1mV    1.295V
473ps     1.176V     951.2mV    1.299V
549ps     1.191V     1.058V     1.3V
664ps     1.198V     1.118V     1.3V
1.25ns    1.2V       1.14V      1.3V
[Rising waveform]
R_fixture=50.000Ohm
V_fixture=0
0s        49.99mV    40.02mV    70.32mV
64ps      50.31mV    40.21mV    93.21mV
166ps     47.38mV    40.14mV    324.5mV
243ps     47.66mV    38.42mV    435.4mV
345ps     195.9mV    33.96mV    500.5mV
447ps     358.5mV    74.07mV    525.3mV
575ps     450.7mV    226.7mV    536.2mV
690ps     480.5mV    326.2mV    539.3mV
805ps     492.2mV    376.1mV    540.2mV
1.25ns    498.7mV    415.6mV    540.8mV
[Falling waveform]
R_fixture=50.000Ohm
V_fixture=1.200
V_fixture_min=1.140
V_fixture_max=1.300
0s        1.2V       1.14V      1.301V
77ps      1.2V       1.14V      1.29V
256ps     1.196V     1.142V     1.015V
307ps     1.145V     1.146V     966.9mV
396ps     1.004V     1.143V     917.8mV
511ps     867.5mV    1.063V     891.5mV
639ps     799.7mV    936.4mV    880.9mV
741ps     778.4mV    861.2mV    878mV
856ps     768.2mV    810mV      876.9mV
1.25ns    761.9mV    761.3mV    876.5mV
[Falling waveform]
R_fixture=50.000Ohm
V_fixture=0
0s        498.6mV    416.8mV    548mV
52ps      498.3mV    416.5mV    499.6mV
128ps     504.1mV    417.7mV    266.8mV
205ps     504.3mV    425.3mV    142.7mV
281ps     360.8mV    430.5mV    98.86mV
371ps     156.2mV    368.9mV    81.27mV
486ps     75.19mV    178.4mV    74.91mV
562ps     60.17mV    104.1mV    73.52mV
677ps     52.33mV    60.26mV    72.95mV
1.25ns    49.92mV    40.01mV    72.84mV
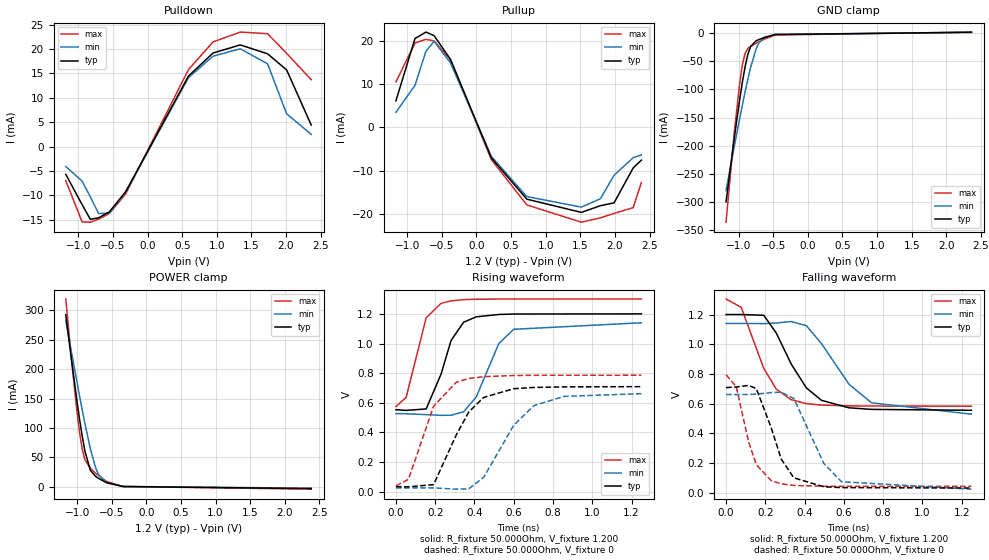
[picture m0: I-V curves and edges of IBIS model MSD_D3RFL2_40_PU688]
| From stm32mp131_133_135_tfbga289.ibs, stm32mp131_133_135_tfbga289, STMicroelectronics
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[Model] MSD_D3RFL2_40_PU688
Model_type   I/O
C_comp 2.464pF   2.377pF   2.591pF
Vinh = 820.000mV
Vinl = 380.000mV
Vmeas = 600.000mV
Vref = 600.000mV
[Model Spec]
Vinh   820.000mV   790.000mV   870.000mV
Vinl   380.000mV   350.000mV   430.000mV
Vmeas   600.000mV   570.000mV   650.000mV
Vref   600.000mV   570.000mV   650.000mV
[Receiver Thresholds]
Vth   =  0.600V
Vth_min  =  0.5880V
Vth_max  =  0.6120V
Vinh_ac  =  0.220V
Vinh_dc  =  0.130V
Vinl_ac  = -0.220V
Vinl_dc  = -0.130V
Tslew_ac =  5.000ns |Not specified, so set to high value
[Temperature Range]   25.000   125.000   -40.000
[Voltage Range]   1.200V   1.140V   1.300V
[GND Clamp Reference]   0.00V   0.00V   0.00V
[Pulldown Reference]   0.00V   0.00V   0.00V
[POWER Clamp Reference]   1.200V   1.140V   1.300V
[Pullup Reference]   1.200V   1.140V   1.300V
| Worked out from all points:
|   slope of the pulldown table from 0 to 0.18 V, typ, clamps not added: 35.6 ohm
|   slope of the pullup table from 0 to 0.18 V, typ, clamps not added: 29.6 ohm
|   GND clamp passes 1 mA (typ) near -0.40 V on its own axis
|   POWER clamp passes 1 mA (typ) near -0.41 V on its own axis
|   rising waveform, R_fixture 50.000Ohm, V_fixture 1.200: 20-80 % time 92.7ps typ, 120ps min, 78.9ps max; typ from 0.554 V to 1.2 V
|   rising waveform, R_fixture 50.000Ohm, V_fixture 0: 20-80 % time 149ps typ, 182ps min, 126ps max; typ from 0.034 V to 0.709 V
|   falling waveform, R_fixture 50.000Ohm, V_fixture 1.200: 20-80 % time 166ps typ, 208ps min, 135ps max; typ from 1.2 V to 0.556 V
|   falling waveform, R_fixture 50.000Ohm, V_fixture 0: 20-80 % time 104ps typ, 128ps min, 86.9ps max; typ from 0.708 V to 0.033 V
[GND Clamp]
-1.182V   -299.5mA   -279.5mA   -335.8mA
-1.064V   -187.3mA   -201.8mA   -177.4mA
-984.9mV  -117.9mA   -151.6mA   -88.56mA
-945.5mV  -86.48mA   -127.3mA   -55.74mA
-906.1mV  -59.08mA   -103.8mA   -35.61mA
-866.7mV  -37.56mA   -81.65mA   -27.19mA
-827.3mV  -23.76mA   -61.08mA   -23.39mA
-748.5mV  -13.58mA   -28.09mA   -17.94mA
-709.1mV  -11.39mA   -17.47mA   -15.42mA
-630.3mV  -7.849mA   -7.504mA   -10.69mA
-472.7mV  -2.436mA   -2.132mA   -3.171mA
2.364V    1.653mA    1.397mA    1.945mA
[Power Clamp]
-1.164V   292.6mA    282.9mA    319.4mA
-1.085V   218.8mA    231.1mA    220.2mA
-1.006V   148.6mA    180.3mA    131.2mA
-966.7mV  116mA      155.4mA    93.45mA
-927.3mV  86.24mA    131mA      64.09mA
-887.9mV  60.5mA     107.5mA    45.96mA
-809.1mV  27.9mA     64.44mA    31.21mA
-730.3mV  17.1mA     31.25mA    22.47mA
-690.9mV  14mA       20.4mA     18.6mA
-572.7mV  6.682mA    6.615mA    8.806mA
-336.4mV  202.2uA    381.9uA    225.6uA
2.382V    -3.312mA   -2.631mA   -4.291mA
[Pulldown]
-1.182V   -5.7mA     -4.1mA     -7mA
-945.5mV  -11.93mA   -7.1mA     -15.47mA
-827.3mV  -14.92mA   -10.33mA   -15.51mA
-709.1mV  -14.62mA   -13.73mA   -14.89mA
-551.5mV  -13.37mA   -13.66mA   -13.72mA
-315.1mV  -9.221mA   -9.274mA   -9.684mA
590.9mV   14.46mA    14.13mA    15.79mA
945.5mV   19.18mA    18.53mA    21.45mA
1.339V    20.84mA    20.05mA    23.47mA
1.733V    19.02mA    16.97mA    23.14mA
2.009V    15.71mA    6.71mA     19.11mA
2.364V    4.4mA      2.5mA      13.7mA
[Pullup]
-1.164V   6.1mA      3.457mA    10.46mA
-887.9mV  20.5mA     9.694mA    19.46mA
-730.3mV  21.97mA    17.56mA    20.3mA
-612.1mV  21.14mA    19.84mA    19.94mA
-375.8mV  15.67mA    14.86mA    15.58mA
215.2mV   -7.104mA   -6.743mA   -7.481mA
727.3mV   -16.61mA   -16.01mA   -17.94mA
1.515V    -19.67mA   -18.45mA   -21.93mA
1.791V    -18.12mA   -16.51mA   -20.92mA
1.988V    -17.46mA   -11.09mA   -19.91mA
2.264V    -9.4mA     -7.043mA   -18.57mA
2.382V    -7.6mA     -6.395mA   -12.78mA
[Ramp]
R_load=50.000Ohm
dV/dt_r   396.012mV/121.500ps  374.964mV/152.500ps  437.376mV/102.000ps
dV/dt_f   396.012mV/135.500ps  374.874mV/169.500ps  437.376mV/111.500ps
[Rising waveform]
R_fixture=50.000Ohm
V_fixture=1.200
V_fixture_min=1.140
V_fixture_max=1.300
0s        553.5mV    527mV      574.4mV
52ps      548.6mV    525.7mV    636mV
154ps     558.5mV    520mV      1.174V
230ps     793.9mV    515.2mV    1.271V
281ps     1.021V     516.2mV    1.288V
345ps     1.144V     539.2mV    1.296V
409ps     1.18V      639.2mV    1.299V
524ps     1.196V     1V         1.3V
600ps     1.199V     1.096V     1.3V
1.25ns    1.2V       1.14V      1.3V
[Rising waveform]
R_fixture=50.000Ohm
V_fixture=0
0s        33.98mV    25.68mV    39.35mV
64ps      32.75mV    26.06mV    83.7mV
192ps     47.9mV     25.43mV    577.3mV
307ps     382mV      17mV       738mV
371ps     537.8mV    19.53mV    763.9mV
447ps     636.2mV    96.67mV    776.4mV
600ps     695mV      448mV      784.1mV
703ps     703.5mV    581.1mV    785.5mV
856ps     707.4mV    643mV      785.9mV
1.25ns    709mV      661.4mV    786mV
[Falling waveform]
R_fixture=50.000Ohm
V_fixture=1.200
V_fixture_min=1.140
V_fixture_max=1.300
0s        1.2V       1.14V      1.304V
77ps      1.2V       1.14V      1.249V
192ps     1.195V     1.139V     837.8mV
256ps     1.075V     1.143V     698.2mV
332ps     866.8mV    1.153V     627.2mV
409ps     706.7mV    1.125V     600.7mV
486ps     623.1mV    1.005V     591.1mV
626ps     572.8mV    731.3mV    585.9mV
741ps     562.1mV    606.4mV    584.5mV
1.25ns    556.1mV    530mV      583.6mV
[Falling waveform]
R_fixture=50.000Ohm
V_fixture=0
0s        708.5mV    662.1mV    795.4mV
52ps      712.9mV    661.7mV    714.9mV
115ps     723.4mV    662.4mV    343.4mV
154ps     701.7mV    665mV      190.7mV
230ps     439.1mV    675mV      82.76mV
281ps     227.9mV    677.6mV    61.37mV
345ps     102mV      635.7mV    50.76mV
498ps     41.74mV    198.6mV    45.08mV
588ps     36.15mV    75.46mV    44.69mV
1.25ns    33.27mV    25.61mV    44.48mV
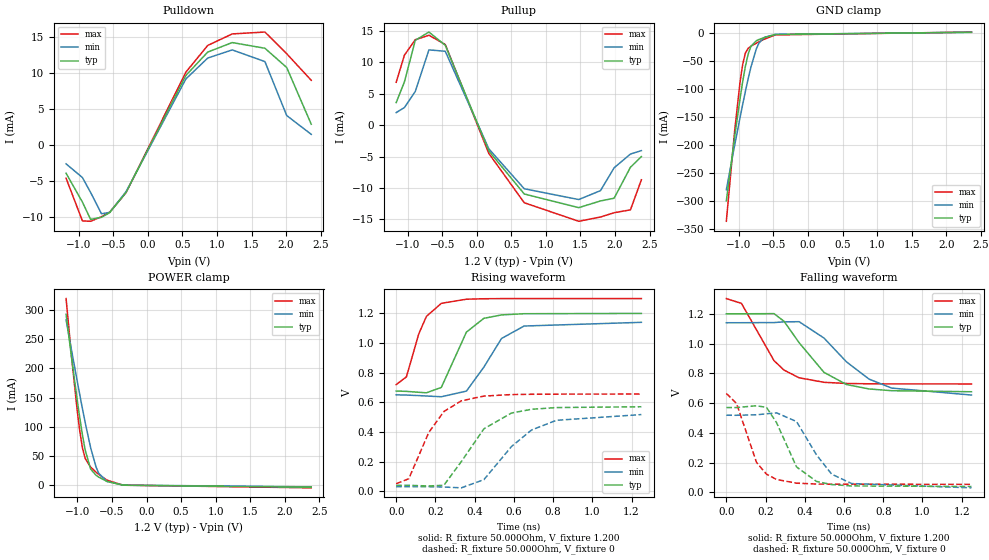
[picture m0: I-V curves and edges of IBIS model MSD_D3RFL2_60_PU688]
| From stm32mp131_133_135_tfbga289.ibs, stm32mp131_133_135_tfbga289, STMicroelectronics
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[Model] MSD_D3RFL2_60_PU688
Model_type   I/O
C_comp 2.464pF   2.377pF   2.591pF
Vinh = 820.000mV
Vinl = 380.000mV
Vmeas = 600.000mV
Vref = 600.000mV
[Model Spec]
Vinh   820.000mV   790.000mV   870.000mV
Vinl   380.000mV   350.000mV   430.000mV
Vmeas   600.000mV   570.000mV   650.000mV
Vref   600.000mV   570.000mV   650.000mV
[Receiver Thresholds]
Vth   =  0.600V
Vth_min  =  0.5880V
Vth_max  =  0.6120V
Vinh_ac  =  0.220V
Vinh_dc  =  0.130V
Vinl_ac  = -0.220V
Vinl_dc  = -0.130V
Tslew_ac =  5.000ns |Not specified, so set to high value
[Temperature Range]   25.000   125.000   -40.000
[Voltage Range]   1.200V   1.140V   1.300V
[GND Clamp Reference]   0.00V   0.00V   0.00V
[Pulldown Reference]   0.00V   0.00V   0.00V
[POWER Clamp Reference]   1.200V   1.140V   1.300V
[Pullup Reference]   1.200V   1.140V   1.300V
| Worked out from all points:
|   slope of the pulldown table from 0 to 0.18 V, typ, clamps not added: 50.1 ohm
|   slope of the pullup table from 0 to 0.18 V, typ, clamps not added: 42.9 ohm
|   GND clamp passes 1 mA (typ) near -0.40 V on its own axis
|   POWER clamp passes 1 mA (typ) near -0.41 V on its own axis
|   rising waveform, R_fixture 50.000Ohm, V_fixture 1.200: 20-80 % time 106ps typ, 137ps min, 87.7ps max; typ from 0.676 V to 1.2 V
|   rising waveform, R_fixture 50.000Ohm, V_fixture 0: 20-80 % time 176ps typ, 217ps min, 146ps max; typ from 0.04 V to 0.57 V
|   falling waveform, R_fixture 50.000Ohm, V_fixture 1.200: 20-80 % time 199ps typ, 249ps min, 161ps max; typ from 1.2 V to 0.676 V
|   falling waveform, R_fixture 50.000Ohm, V_fixture 0: 20-80 % time 117ps typ, 144ps min, 100ps max; typ from 0.57 V to 0.04 V
[GND Clamp]
-1.182V   -299.5mA   -279.5mA   -335.8mA
-1.064V   -187.3mA   -201.8mA   -177.4mA
-984.9mV  -117.9mA   -151.6mA   -88.56mA
-945.5mV  -86.48mA   -127.3mA   -55.74mA
-906.1mV  -59.08mA   -103.8mA   -35.61mA
-866.7mV  -37.56mA   -81.65mA   -27.19mA
-827.3mV  -23.76mA   -61.08mA   -23.39mA
-748.5mV  -13.58mA   -28.09mA   -17.94mA
-709.1mV  -11.39mA   -17.47mA   -15.42mA
-630.3mV  -7.849mA   -7.504mA   -10.69mA
-472.7mV  -2.436mA   -2.132mA   -3.171mA
2.364V    1.653mA    1.397mA    1.945mA
[Power Clamp]
-1.164V   292.6mA    282.9mA    319.4mA
-1.085V   218.8mA    231.1mA    220.2mA
-1.006V   148.6mA    180.3mA    131.2mA
-966.7mV  116mA      155.4mA    93.45mA
-927.3mV  86.24mA    131mA      64.09mA
-887.9mV  60.5mA     107.5mA    45.96mA
-809.1mV  27.9mA     64.44mA    31.21mA
-730.3mV  17.1mA     31.25mA    22.47mA
-690.9mV  14mA       20.4mA     18.6mA
-572.7mV  6.682mA    6.615mA    8.806mA
-336.4mV  202.2uA    381.9uA    225.6uA
2.382V    -3.312mA   -2.631mA   -4.291mA
[Pulldown]
-1.182V   -3.9mA     -2.6mA     -4.6mA
-945.5mV  -7.91mA    -4.5mA     -10.52mA
-827.3mV  -10.31mA   -6.57mA    -10.57mA
-669.7mV  -10.02mA   -9.53mA    -9.94mA
-551.5mV  -9.373mA   -9.337mA   -9.307mA
-315.1mV  -6.567mA   -6.465mA   -6.607mA
551.5mV   9.679mA    9.198mA    10.14mA
866.7mV   12.92mA    12.09mA    13.84mA
1.221V    14.24mA    13.22mA    15.44mA
1.694V    13.45mA    11.6mA     15.7mA
2.009V    10.78mA    4.11mA     12.69mA
2.364V    2.9mA      1.5mA      9mA
[Pullup]
-1.164V   3.6mA      2.005mA    6.838mA
-1.045V   6.9mA      2.809mA    11.16mA
-887.9mV  13.51mA    5.376mA    13.61mA
-690.9mV  14.83mA    11.99mA    14.32mA
-454.5mV  12.72mA    11.77mA    12.85mA
175.8mV   -4.107mA   -3.772mA   -4.491mA
687.9mV   -10.95mA   -10.12mA   -12.35mA
1.476V    -13.13mA   -11.84mA   -15.3mA
1.791V    -12.06mA   -10.42mA   -14.62mA
1.988V    -11.63mA   -6.784mA   -13.94mA
2.224V    -6.7mA     -4.595mA   -13.48mA
2.382V    -5mA       -4.048mA   -8.7mA
[Ramp]
R_load=50.000Ohm
dV/dt_r   316.350mV/142.000ps  293.172mV/178.500ps  351.894mV/116.500ps
dV/dt_f   316.380mV/158.500ps  293.139mV/199.500ps  351.894mV/130.500ps
[Rising waveform]
R_fixture=50.000Ohm
V_fixture=1.200
V_fixture_min=1.140
V_fixture_max=1.300
0s        676.4mV    650.8mV    719.8mV
52ps      674.3mV    649.3mV    772.2mV
115ps     668.1mV    645.8mV    1.062V
154ps     664.5mV    643mV      1.18V
230ps     700.8mV    637.9mV    1.268V
358ps     1.074V     676.1mV    1.296V
447ps     1.167V     838.1mV    1.299V
537ps     1.19V      1.031V     1.3V
652ps     1.198V     1.115V     1.3V
1.25ns    1.2V       1.14V      1.3V
[Rising waveform]
R_fixture=50.000Ohm
V_fixture=0
0s        40.03mV    31.08mV    51.16mV
64ps      40.42mV    31.36mV    84.76mV
166ps     36.13mV    31.29mV    396.7mV
243ps     40.81mV    29.01mV    538.2mV
332ps     200.4mV    23.55mV    610.4mV
447ps     421.6mV    78.7mV     642.4mV
588ps     528.3mV    302.5mV    652.7mV
690ps     553.4mV    413.7mV    654.7mV
817ps     565.1mV    479.2mV    655.6mV
1.25ns    570.5mV    517.7mV    656.3mV
[Falling waveform]
R_fixture=50.000Ohm
V_fixture=1.200
V_fixture_min=1.140
V_fixture_max=1.300
0s        1.2V       1.14V      1.302V
77ps      1.2V       1.14V      1.27V
243ps     1.201V     1.141V     885.6mV
294ps     1.15V      1.146V     821.8mV
371ps     1.006V     1.147V     770.3mV
498ps     806.6mV    1.037V     739.8mV
613ps     724.8mV    876.6mV    732mV
728ps     695.1mV    761.1mV    729.8mV
843ps     683.4mV    701mV      729.1mV
1.25ns    676.4mV    654.3mV    728.8mV
[Falling waveform]
R_fixture=50.000Ohm
V_fixture=0
0s        570.4mV    518.7mV    664.9mV
52ps      570.2mV    518.3mV    597.9mV
154ps     582.5mV    521.8mV    201.5mV
205ps     570.9mV    528.4mV    122.6mV
256ps     468.9mV    534.8mV    87.13mV
358ps     171.6mV    476.2mV    62.39mV
460ps     73.89mV    251.6mV    56.57mV
537ps     52.93mV    123mV      55.48mV
639ps     43.79mV    59.86mV    54.98mV
1.25ns    39.91mV    31.05mV    54.72mV
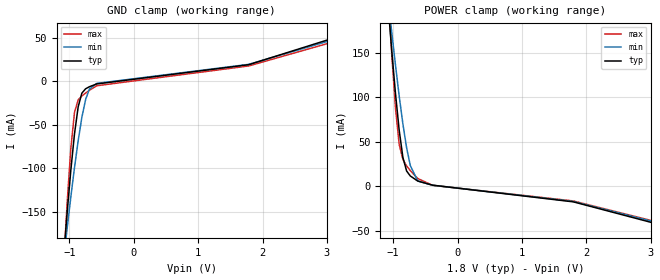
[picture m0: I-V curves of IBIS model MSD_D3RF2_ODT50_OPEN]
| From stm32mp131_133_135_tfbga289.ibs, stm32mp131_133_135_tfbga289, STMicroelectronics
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[Model] MSD_D3RF2_ODT50_OPEN
Model_type   Input
C_comp 2.459pF   2.418pF   2.492pF
Vinh = 1.150V
Vinl = 650.000mV
[Model Spec]
Vinh   1.150V   1.100V   1.200V
Vinl   650.000mV   600.000mV   700.000mV
[Temperature Range]   25.000   125.000   -40.000
[Voltage Range]   1.800V   1.700V   1.900V
[GND Clamp Reference]   0.00V   0.00V   0.00V
[POWER Clamp Reference]   1.800V   1.700V   1.900V
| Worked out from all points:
|   GND clamp passes 1 mA (typ) near -0.47 V on its own axis
|   POWER clamp passes 1 mA (typ) near -0.31 V on its own axis
[GND Clamp]
-1.785V   -922.1mA   -682.3mA   -1.293A
-1.094V   -206.1mA   -207.3mA   -216.6mA
-1.036V   -152.4mA   -170mA     -141.2mA
-978.8mV  -103mA     -133.9mA   -78.03mA
-921.2mV  -60.65mA   -99.61mA   -35.8mA
-863.6mV  -29.22mA   -68.25mA   -21.17mA
-806.1mV  -13.44mA   -41.3mA    -16.71mA
-748.5mV  -8.442mA   -20.88mA   -13.37mA
-690.9mV  -6.138mA   -8.907mA   -10.28mA
-575.8mV  -2.86mA    -2.214mA   -4.94mA
1.785V    19.33mA    19.74mA    17.89mA
3.57V     60.94mA    58.3mA     55.54mA
[Power Clamp]
-1.77V    923.8mA    691.4mA    1.291A
-1.079V   204mA      210.1mA    219.3mA
-1.021V   151.5mA    172.4mA    147.8mA
-963.6mV  104mA      135.9mA    87.42mA
-906.1mV  62.98mA    101.4mA    47.01mA
-848.5mV  32.5mA     69.97mA    30.15mA
-790.9mV  17.3mA     43.32mA    23.09mA
-733.3mV  11.71mA    23.37mA    17.65mA
-618.2mV  6.052mA    6.066mA    8.927mA
-387.9mV  1.424mA    1.334mA    1.245mA
1.8V      -17.31mA   -16.83mA   -16.29mA
3.585V    -51.29mA   -49.34mA   -48.67mA
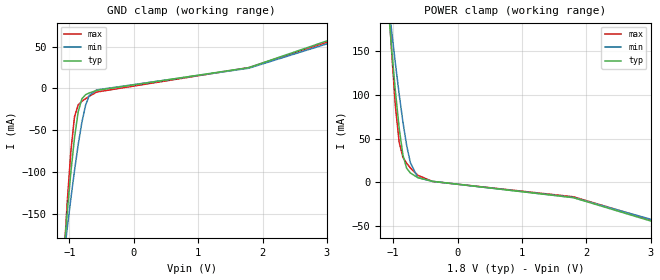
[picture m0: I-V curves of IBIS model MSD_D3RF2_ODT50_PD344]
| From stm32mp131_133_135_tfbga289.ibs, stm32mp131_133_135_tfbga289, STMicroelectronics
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[Model] MSD_D3RF2_ODT50_PD344
Model_type   Input
C_comp 2.222pF   2.185pF   2.249pF
Vinh = 1.150V
Vinl = 650.000mV
[Temperature Range]   25.000   125.000   -40.000
[Voltage Range]   1.800V   1.700V   1.900V
[GND Clamp Reference]   0.00V   0.00V   0.00V
[POWER Clamp Reference]   1.800V   1.700V   1.900V
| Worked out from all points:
|   GND clamp passes 1 mA (typ) near -0.49 V on its own axis
|   POWER clamp passes 1 mA (typ) near -0.32 V on its own axis
[GND Clamp]
-1.785V   -918.7mA   -679.3mA   -1.289A
-1.094V   -204.4mA   -205.9mA   -214.4mA
-1.036V   -150.8mA   -168.8mA   -139.2mA
-978.8mV  -101.6mA   -132.8mA   -76.32mA
-921.2mV  -59.43mA   -98.65mA   -34.22mA
-863.6mV  -28.15mA   -67.34mA   -19.78mA
-806.1mV  -12.49mA   -40.53mA   -15.49mA
-748.5mV  -7.644mA   -20.22mA   -12.33mA
-690.9mV  -5.476mA   -8.362mA   -9.41mA
-575.8mV  -2.45mA    -1.872mA   -4.4mA
1.785V    24.74mA    24.05mA    24.78mA
3.57V     71.74mA    66.83mA    69.28mA
[Power Clamp]
-1.77V    920.1mA    688.1mA    1.286A
-1.079V   202.2mA    208.6mA    217.1mA
-1.021V   149.9mA    171mA      145.9mA
-963.6mV  102.6mA    134.6mA    85.68mA
-906.1mV  61.69mA    100.2mA    45.46mA
-848.5mV  31.36mA    68.99mA    28.77mA
-790.9mV  16.31mA    42.48mA    21.9mA
-733.3mV  10.86mA    22.64mA    16.64mA
-618.2mV  5.498mA    5.583mA    8.272mA
-387.9mV  1.316mA    1.225mA    1.146mA
1.8V      -17.31mA   -17.08mA   -16.28mA
3.585V    -56.74mA   -53.96mA   -55.22mA
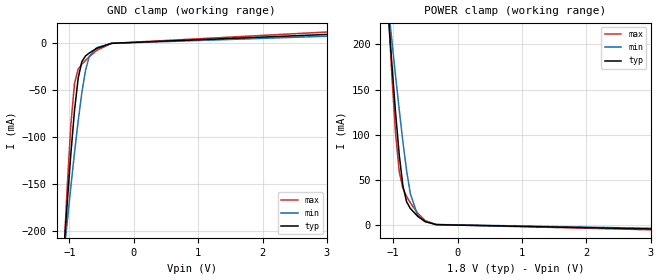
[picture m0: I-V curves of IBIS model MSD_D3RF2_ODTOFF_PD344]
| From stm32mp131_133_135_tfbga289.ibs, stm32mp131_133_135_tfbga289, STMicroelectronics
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[Model] MSD_D3RF2_ODTOFF_PD344
Model_type   Input
C_comp 2.313pF   2.232pF   2.432pF
Vinh = 1.150V
Vinl = 650.000mV
[Temperature Range]   25.000   125.000   -40.000
[Voltage Range]   1.800V   1.700V   1.900V
[GND Clamp Reference]   0.00V   0.00V   0.00V
[POWER Clamp Reference]   1.800V   1.700V   1.900V
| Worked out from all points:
|   GND clamp passes 1 mA (typ) near -0.41 V on its own axis
|   POWER clamp passes 1 mA (typ) near -0.41 V on its own axis
[GND Clamp]
-1.785V   -962.9mA   -720.7mA   -1.332A
-1.094V   -229.6mA   -231.4mA   -236.8mA
-1.036V   -172.7mA   -192.3mA   -156.5mA
-978.8mV  -119.3mA   -154.2mA   -88.15mA
-921.2mV  -72.36mA   -117.4mA   -43.38mA
-863.6mV  -37.35mA   -83.09mA   -27.73mA
-806.1mV  -19.76mA   -52.64mA   -22.51mA
-748.5mV  -13.75mA   -28.77mA   -18.44mA
-690.9mV  -10.61mA   -14.21mA   -14.63mA
-575.8mV  -5.696mA   -4.851mA   -7.796mA
-345.4mV  -314.1uA   -380.4uA   -331.6uA
3.57V     10.76mA    8.559mA    13.79mA
[Power Clamp]
-1.77V    979.6mA    742.9mA    1.343A
-1.079V   237.4mA    245.2mA    243.7mA
-1.021V   179.5mA    205.2mA    166.6mA
-963.6mV  125.2mA    165.9mA    102.4mA
-906.1mV  77.9mA     127.9mA    59.33mA
-848.5mV  43.26mA    91.97mA    40.38mA
-790.9mV  25.55mA    59.93mA    31.5mA
-733.3mV  18.12mA    34.61mA    24.43mA
-618.2mV  9.403mA    10.19mA    12.79mA
-503mV    3.509mA    3.592mA    4.639mA
-330.3mV  151.2uA    322uA      179.8uA
3.585V    -5.45mA    -4.624mA   -6.567mA
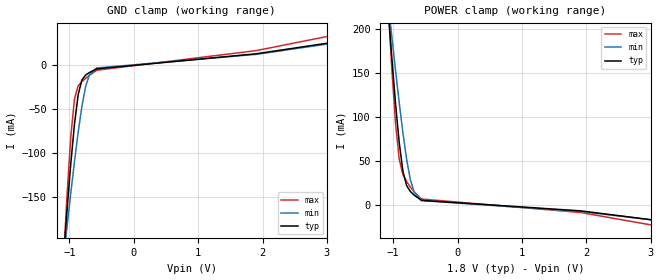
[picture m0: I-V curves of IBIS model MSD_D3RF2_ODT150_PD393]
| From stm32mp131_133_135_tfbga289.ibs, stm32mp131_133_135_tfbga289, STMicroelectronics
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[Model] MSD_D3RF2_ODT150_PD393
Model_type   Input
C_comp 2.299pF   2.233pF   2.364pF
Vinh = 1.150V
Vinl = 650.000mV
[Temperature Range]   25.000   125.000   -40.000
[Voltage Range]   1.800V   1.700V   1.900V
[GND Clamp Reference]   0.00V   0.00V   0.00V
[POWER Clamp Reference]   1.800V   1.700V   1.900V
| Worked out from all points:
|   GND clamp passes 1 mA (typ) near -0.43 V on its own axis
|   POWER clamp passes 1 mA (typ) near -0.41 V on its own axis
[GND Clamp]
-1.785V   -947.9mA   -705.7mA   -1.311A
-1.094V   -220.7mA   -221.8mA   -225.2mA
-1.036V   -164.8mA   -183.3mA   -147.3mA
-978.8mV  -112.6mA   -145.9mA   -81.8mA
-921.2mV  -67.23mA   -110mA     -38.69mA
-863.6mV  -33.81mA   -76.55mA   -23.69mA
-806.1mV  -17.08mA   -47.3mA    -18.93mA
-748.5mV  -11.51mA   -24.81mA   -15.3mA
-690.9mV  -8.693mA   -11.48mA   -11.92mA
-575.8mV  -4.421mA   -3.435mA   -5.99mA
1.9V      12.69mA    12.05mA    16.3mA
3.57V     30.9mA     29.73mA    40.6mA
[Power Clamp]
-1.77V    959mA      722.3mA    1.314A
-1.079V   224.4mA    231.2mA    229.4mA
-1.021V   168mA      192mA      155.5mA
-963.6mV  115.8mA    153.7mA    93.5mA
-906.1mV  71.09mA    116.7mA    51.94mA
-848.5mV  38.43mA    82.13mA    34.19mA
-790.9mV  21.86mA    51.9mA     26.35mA
-733.3mV  15.2mA     28.75mA    20.21mA
-675.8mV  11.04mA    14.69mA    14.85mA
-560.6mV  4.96mA     4.723mA    6.464mA
1.915V    -7.049mA   -7.786mA   -8.938mA
3.585V    -22.53mA   -22.23mA   -30.54mA
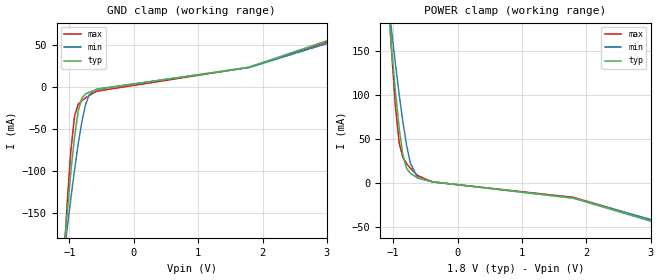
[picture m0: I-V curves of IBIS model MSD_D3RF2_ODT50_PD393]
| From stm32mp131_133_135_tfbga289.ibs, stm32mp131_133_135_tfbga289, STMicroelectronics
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[Model] MSD_D3RF2_ODT50_PD393
Model_type   Input
C_comp 2.252pF   2.214pF   2.279pF
Vinh = 1.150V
Vinl = 650.000mV
[Temperature Range]   25.000   125.000   -40.000
[Voltage Range]   1.800V   1.700V   1.900V
[GND Clamp Reference]   0.00V   0.00V   0.00V
[POWER Clamp Reference]   1.800V   1.700V   1.900V
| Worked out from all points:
|   GND clamp passes 1 mA (typ) near -0.49 V on its own axis
|   POWER clamp passes 1 mA (typ) near -0.31 V on its own axis
[GND Clamp]
-1.785V   -919mA     -679.7mA   -1.289A
-1.094V   -204.6mA   -206.1mA   -214.8mA
-1.036V   -151mA     -168.9mA   -139.4mA
-978.8mV  -101.7mA   -133mA     -76.5mA
-921.2mV  -59.58mA   -98.74mA   -34.42mA
-863.6mV  -28.28mA   -67.51mA   -19.95mA
-806.1mV  -12.61mA   -40.63mA   -15.64mA
-748.5mV  -7.74mA    -20.3mA    -12.45mA
-690.9mV  -5.56mA    -8.436mA   -9.516mA
-575.8mV  -2.5mA     -1.92mA    -4.47mA
1.785V    24.06mA    23.5mA     23.91mA
3.57V     70.32mA    65.73mA    67.61mA
[Power Clamp]
-1.77V    920.6mA    688.6mA    1.287A
-1.079V   202.6mA    208.8mA    217.3mA
-1.021V   150.2mA    171.2mA    146.1mA
-963.6mV  102.8mA    134.8mA    85.91mA
-906.1mV  61.95mA    100.4mA    45.61mA
-848.5mV  31.54mA    69.17mA    28.92mA
-790.9mV  16.47mA    42.62mA    22.03mA
-733.3mV  11.01mA    22.75mA    16.75mA
-618.2mV  5.602mA    5.663mA    8.341mA
-387.9mV  1.354mA    1.253mA    1.146mA
1.8V      -17.31mA   -17.05mA   -16.28mA
3.585V    -56.06mA   -53.38mA   -54.4mA
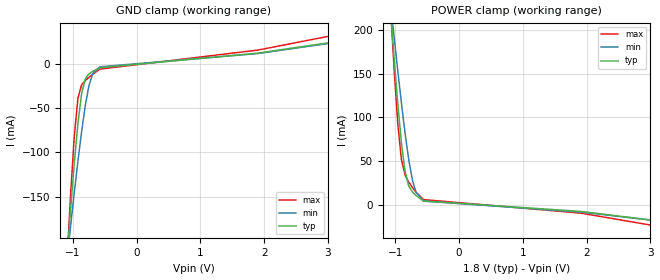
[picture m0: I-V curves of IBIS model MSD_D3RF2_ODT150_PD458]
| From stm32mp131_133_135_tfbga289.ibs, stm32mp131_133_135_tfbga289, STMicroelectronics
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[Model] MSD_D3RF2_ODT150_PD458
Model_type   Input
C_comp 2.328pF   2.262pF   2.394pF
Vinh = 1.150V
Vinl = 650.000mV
[Temperature Range]   25.000   125.000   -40.000
[Voltage Range]   1.800V   1.700V   1.900V
[GND Clamp Reference]   0.00V   0.00V   0.00V
[POWER Clamp Reference]   1.800V   1.700V   1.900V
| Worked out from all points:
|   GND clamp passes 1 mA (typ) near -0.43 V on its own axis
|   POWER clamp passes 1 mA (typ) near -0.41 V on its own axis
[GND Clamp]
-1.785V   -948.4mA   -706.1mA   -1.311A
-1.094V   -220.9mA   -222mA     -225.4mA
-1.036V   -165mA     -183.5mA   -147.5mA
-978.8mV  -112.8mA   -146mA     -82.08mA
-921.2mV  -67.38mA   -110.1mA   -38.89mA
-863.6mV  -33.94mA   -76.66mA   -23.86mA
-806.1mV  -17.19mA   -47.4mA    -19.09mA
-748.5mV  -11.61mA   -24.89mA   -15.43mA
-690.9mV  -8.777mA   -11.55mA   -12.03mA
-575.8mV  -4.481mA   -3.483mA   -6.062mA
1.9V      11.96mA    11.47mA    15.38mA
3.57V     29.52mA    28.66mA    38.87mA
[Power Clamp]
-1.77V    959.5mA    722.8mA    1.315A
-1.079V   224.6mA    231.4mA    229.6mA
-1.021V   168.2mA    192.2mA    155.7mA
-963.6mV  116mA      153.8mA    93.7mA
-906.1mV  71.27mA    116.8mA    52.15mA
-848.5mV  38.59mA    82.26mA    34.37mA
-790.9mV  22mA       52.01mA    26.5mA
-733.3mV  15.31mA    28.84mA    20.34mA
-675.8mV  11.15mA    14.76mA    14.96mA
-560.6mV  5.026mA    4.772mA    6.529mA
1.915V    -7.005mA   -7.719mA   -8.931mA
3.585V    -21.85mA   -21.65mA   -29.71mA
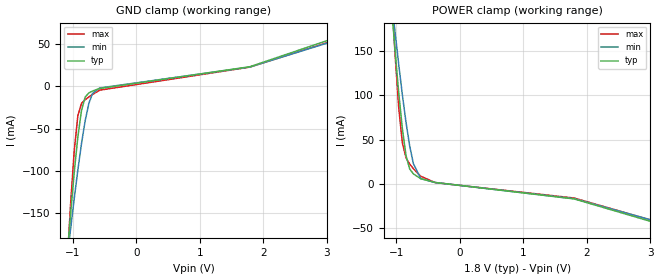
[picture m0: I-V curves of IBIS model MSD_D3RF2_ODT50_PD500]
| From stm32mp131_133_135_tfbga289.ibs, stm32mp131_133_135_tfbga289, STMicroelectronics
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[Model] MSD_D3RF2_ODT50_PD500
Model_type   Input
C_comp 2.298pF   2.260pF   2.327pF
Vinh = 1.150V
Vinl = 650.000mV
[Temperature Range]   25.000   125.000   -40.000
[Voltage Range]   1.800V   1.700V   1.900V
[GND Clamp Reference]   0.00V   0.00V   0.00V
[POWER Clamp Reference]   1.800V   1.700V   1.900V
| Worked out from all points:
|   GND clamp passes 1 mA (typ) near -0.48 V on its own axis
|   POWER clamp passes 1 mA (typ) near -0.31 V on its own axis
[GND Clamp]
-1.785V   -919.7mA   -680.3mA   -1.29A
-1.094V   -204.9mA   -206.3mA   -215.2mA
-1.036V   -151.3mA   -169.2mA   -139.9mA
-978.8mV  -102mA     -133.1mA   -76.81mA
-921.2mV  -59.79mA   -98.96mA   -34.72mA
-863.6mV  -28.47mA   -67.65mA   -20.21mA
-806.1mV  -12.78mA   -40.78mA   -15.87mA
-748.5mV  -7.876mA   -20.43mA   -12.65mA
-690.9mV  -5.664mA   -8.533mA   -9.68mA
-575.8mV  -2.57mA    -1.984mA   -4.57mA
1.785V    23.05mA    22.71mA    22.63mA
3.57V     68.38mA    64.18mA    65.01mA
[Power Clamp]
-1.77V    921.2mA    689.2mA    1.287A
-1.079V   202.7mA    209.1mA    217.7mA
-1.021V   150.4mA    171.4mA    146.5mA
-963.6mV  103mA      135mA      86.21mA
-906.1mV  62.14mA    100.6mA    45.92mA
-848.5mV  31.71mA    69.29mA    29.19mA
-790.9mV  16.61mA    42.74mA    22.26mA
-733.3mV  11.13mA    22.86mA    16.95mA
-618.2mV  5.672mA    5.73mA     8.474mA
-387.9mV  1.344mA    1.252mA    1.174mA
1.8V      -17.31mA   -17mA      -16.29mA
3.585V    -55.07mA   -52.51mA   -53.17mA
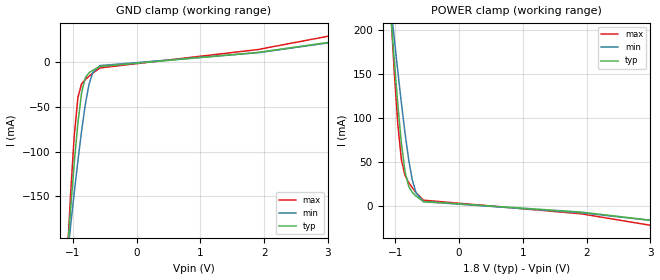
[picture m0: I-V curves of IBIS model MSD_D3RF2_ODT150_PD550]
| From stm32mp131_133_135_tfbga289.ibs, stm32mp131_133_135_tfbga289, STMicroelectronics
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[Model] MSD_D3RF2_ODT150_PD550
Model_type   Input
C_comp 2.358pF   2.290pF   2.424pF
Vinh = 1.150V
Vinl = 650.000mV
[Temperature Range]   25.000   125.000   -40.000
[Voltage Range]   1.800V   1.700V   1.900V
[GND Clamp Reference]   0.00V   0.00V   0.00V
[POWER Clamp Reference]   1.800V   1.700V   1.900V
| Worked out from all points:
|   GND clamp passes 1 mA (typ) near -0.43 V on its own axis
|   POWER clamp passes 1 mA (typ) near -0.40 V on its own axis
[GND Clamp]
-1.785V   -948.7mA   -706.5mA   -1.312A
-1.094V   -221.1mA   -222.1mA   -225.8mA
-1.036V   -165.2mA   -183.6mA   -147.7mA
-978.8mV  -112.9mA   -146.1mA   -82.25mA
-921.2mV  -67.53mA   -110.2mA   -39.09mA
-863.6mV  -34.08mA   -76.77mA   -24.04mA
-806.1mV  -17.31mA   -47.5mA    -19.24mA
-748.5mV  -11.7mA    -24.98mA   -15.56mA
-690.9mV  -8.861mA   -11.61mA   -12.14mA
-575.8mV  -4.531mA   -3.529mA   -6.132mA
1.9V      11.25mA    10.9mA     14.46mA
3.57V     28.22mA    27.59mA    37.14mA
[Power Clamp]
-1.77V    960mA      723.2mA    1.315A
-1.079V   224.8mA    231.6mA    229.8mA
-1.021V   168.3mA    192.3mA    155.9mA
-963.6mV  116.1mA    154mA      93.97mA
-906.1mV  71.4mA     116.9mA    52.36mA
-848.5mV  38.7mA     82.37mA    34.55mA
-790.9mV  22.1mA     52.12mA    26.66mA
-733.3mV  15.4mA     28.93mA    20.48mA
-675.8mV  11.21mA    14.83mA    15.07mA
-560.6mV  5.06mA     4.822mA    6.599mA
1.915V    -6.961mA   -7.654mA   -8.923mA
3.585V    -21.16mA   -21.07mA   -28.89mA
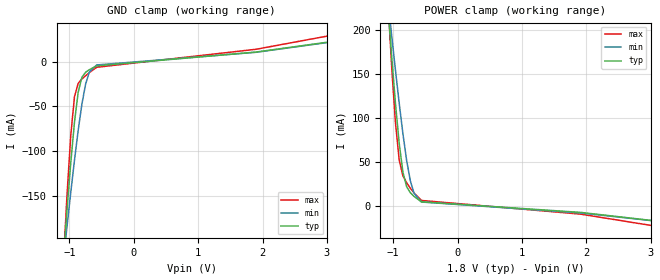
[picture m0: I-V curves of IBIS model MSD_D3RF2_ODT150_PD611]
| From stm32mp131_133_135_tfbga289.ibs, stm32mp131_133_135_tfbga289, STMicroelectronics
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[Model] MSD_D3RF2_ODT150_PD611
Model_type   Input
C_comp 2.375pF   2.307pF   2.442pF
Vinh = 1.150V
Vinl = 650.000mV
[Temperature Range]   25.000   125.000   -40.000
[Voltage Range]   1.800V   1.700V   1.900V
[GND Clamp Reference]   0.00V   0.00V   0.00V
[POWER Clamp Reference]   1.800V   1.700V   1.900V
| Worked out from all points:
|   GND clamp passes 1 mA (typ) near -0.43 V on its own axis
|   POWER clamp passes 1 mA (typ) near -0.40 V on its own axis
[GND Clamp]
-1.785V   -949mA     -706.7mA   -1.312A
-1.094V   -221.2mA   -222.3mA   -225.8mA
-1.036V   -165.2mA   -183.7mA   -147.8mA
-978.8mV  -113mA     -146.3mA   -82.39mA
-921.2mV  -67.61mA   -110.3mA   -39.18mA
-863.6mV  -34.15mA   -76.83mA   -24.13mA
-806.1mV  -17.38mA   -47.54mA   -19.31mA
-748.5mV  -11.76mA   -25.02mA   -15.63mA
-690.9mV  -8.903mA   -11.65mA   -12.19mA
-575.8mV  -4.551mA   -3.547mA   -6.162mA
1.9V      10.89mA    10.61mA    14mA
3.57V     27.51mA    27.06mA    36.27mA
[Power Clamp]
-1.77V    960.2mA    723.4mA    1.316A
-1.079V   225mA      231.7mA    230mA
-1.021V   168.4mA    192.5mA    156mA
-963.6mV  116.2mA    154.1mA    94.07mA
-906.1mV  71.5mA     117mA      52.46mA
-848.5mV  38.79mA    82.44mA    34.64mA
-790.9mV  22.17mA    52.17mA    26.74mA
-733.3mV  15.46mA    28.98mA    20.54mA
-675.8mV  11.27mA    14.88mA    15.12mA
-560.6mV  5.088mA    4.842mA    6.628mA
1.915V    -6.939mA   -7.621mA   -8.92mA
3.585V    -20.82mA   -20.78mA   -28.48mA
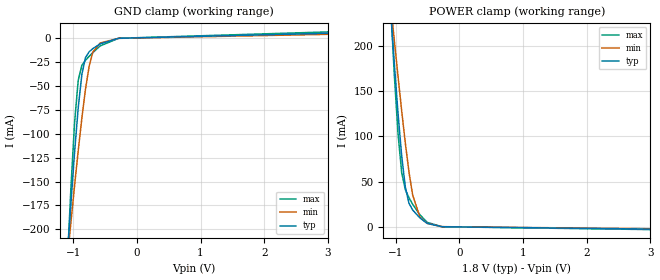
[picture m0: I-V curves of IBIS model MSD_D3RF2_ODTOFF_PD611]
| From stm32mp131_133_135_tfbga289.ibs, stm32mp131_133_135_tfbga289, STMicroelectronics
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[Model] MSD_D3RF2_ODTOFF_PD611
Model_type   Input
C_comp 2.419pF   2.337pF   2.541pF
Vinh = 1.150V
Vinl = 650.000mV
[Temperature Range]   25.000   125.000   -40.000
[Voltage Range]   1.800V   1.700V   1.900V
[GND Clamp Reference]   0.00V   0.00V   0.00V
[POWER Clamp Reference]   1.800V   1.700V   1.900V
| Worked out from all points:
|   GND clamp passes 1 mA (typ) near -0.40 V on its own axis
|   POWER clamp passes 1 mA (typ) near -0.41 V on its own axis
[GND Clamp]
-1.785V   -964.4mA   -722mA     -1.334A
-1.094V   -230.3mA   -232mA     -237.7mA
-1.036V   -173.4mA   -192.9mA   -157.3mA
-978.8mV  -119.9mA   -154.6mA   -88.94mA
-921.2mV  -72.89mA   -117.9mA   -44.07mA
-863.6mV  -37.82mA   -83.48mA   -28.35mA
-806.1mV  -20.18mA   -52.98mA   -23.04mA
-748.5mV  -14.1mA    -29.06mA   -18.9mA
-690.9mV  -10.89mA   -14.45mA   -15.01mA
-575.8mV  -5.877mA   -5.002mA   -8.041mA
-287.9mV  -76.58uA   -127.5uA   -62.1uA
3.57V     6.054mA    4.82mA     7.76mA
[Power Clamp]
-1.77V    981.2mA    744.3mA    1.345A
-1.079V   238.2mA    245.8mA    244.6mA
-1.021V   180.1mA    205.8mA    167.5mA
-963.6mV  125.7mA    166.5mA    103.1mA
-906.1mV  78.45mA    128.3mA    60.03mA
-848.5mV  43.75mA    92.37mA    40.99mA
-790.9mV  25.97mA    60.3mA     32.04mA
-733.3mV  18.48mA    34.93mA    24.88mA
-618.2mV  9.63mA     10.41mA    13.08mA
-503mV    3.635mA    3.714mA    4.794mA
-272.7mV  30uA       103.6uA    30.94uA
3.585V    -3.066mA   -2.602mA   -3.693mA
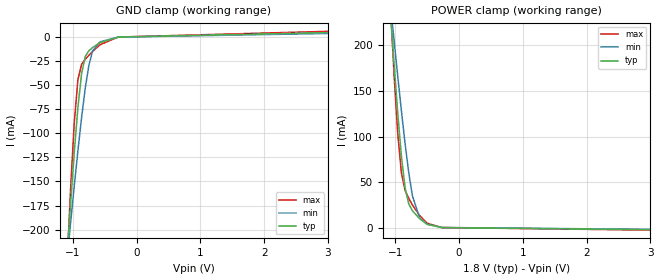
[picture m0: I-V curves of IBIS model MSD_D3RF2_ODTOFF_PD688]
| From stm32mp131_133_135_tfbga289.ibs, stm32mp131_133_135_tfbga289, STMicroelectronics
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[Model] MSD_D3RF2_ODTOFF_PD688
Model_type   Input
C_comp 2.432pF   2.349pF   2.554pF
Vinh = 1.150V
Vinl = 650.000mV
[Model Spec]
Vinh   1.150V   1.100V   1.200V
Vinl   650.000mV   600.000mV   700.000mV
[Temperature Range]   25.000   125.000   -40.000
[Voltage Range]   1.800V   1.700V   1.900V
[GND Clamp Reference]   0.00V   0.00V   0.00V
[POWER Clamp Reference]   1.800V   1.700V   1.900V
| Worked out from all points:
|   GND clamp passes 1 mA (typ) near -0.40 V on its own axis
|   POWER clamp passes 1 mA (typ) near -0.41 V on its own axis
[GND Clamp]
-1.785V   -964.7mA   -722.2mA   -1.335A
-1.094V   -230.4mA   -232.1mA   -237.9mA
-1.036V   -173.5mA   -192.9mA   -157.5mA
-978.8mV  -120mA     -154.7mA   -89.04mA
-921.2mV  -72.96mA   -118mA     -44.17mA
-863.6mV  -37.89mA   -83.53mA   -28.44mA
-806.1mV  -20.23mA   -53.03mA   -23.12mA
-748.5mV  -14.16mA   -29.1mA    -18.96mA
-690.9mV  -10.94mA   -14.48mA   -15.06mA
-575.8mV  -5.903mA   -5.024mA   -8.075mA
-287.9mV  -77.38uA   -128.5uA   -62.9uA
3.57V     5.381mA    4.276mA    6.893mA
[Power Clamp]
-1.77V    981.4mA    744.5mA    1.345A
-1.079V   238.4mA    245.9mA    244.8mA
-1.021V   180.2mA    205.9mA    167.6mA
-963.6mV  125.8mA    166.5mA    103.2mA
-906.1mV  78.53mA    128.4mA    60.13mA
-848.5mV  43.82mA    92.44mA    41.08mA
-790.9mV  26.03mA    60.36mA    32.11mA
-733.3mV  18.52mA    34.98mA    24.95mA
-618.2mV  9.667mA    10.44mA    13.12mA
-503mV    3.653mA    3.734mA    4.819mA
-272.7mV  31uA       107.1uA    32.94uA
3.585V    -2.725mA   -2.312mA   -3.283mA
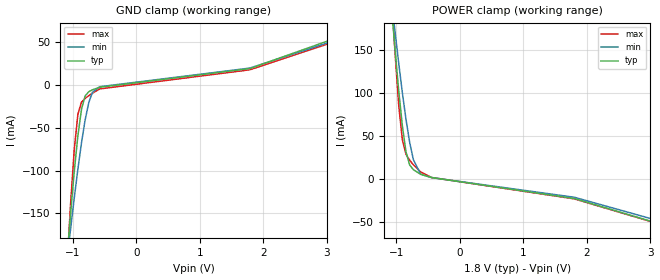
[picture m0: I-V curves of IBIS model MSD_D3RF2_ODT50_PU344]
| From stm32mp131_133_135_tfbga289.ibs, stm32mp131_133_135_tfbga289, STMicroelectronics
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[Model] MSD_D3RF2_ODT50_PU344
Model_type   Input
C_comp 2.224pF   2.187pF   2.252pF
Vinh = 1.150V
Vinl = 650.000mV
[Temperature Range]   25.000   125.000   -40.000
[Voltage Range]   1.800V   1.700V   1.900V
[GND Clamp Reference]   0.00V   0.00V   0.00V
[POWER Clamp Reference]   1.800V   1.700V   1.900V
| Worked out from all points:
|   GND clamp passes 1 mA (typ) near -0.49 V on its own axis
|   POWER clamp passes 1 mA (typ) near -0.32 V on its own axis
[GND Clamp]
-1.785V   -918.6mA   -679.1mA   -1.289A
-1.094V   -204.5mA   -205.8mA   -214.5mA
-1.036V   -150.8mA   -168.7mA   -139.3mA
-978.8mV  -101.6mA   -132.7mA   -76.26mA
-921.2mV  -59.47mA   -98.56mA   -34.23mA
-863.6mV  -28.15mA   -67.35mA   -19.78mA
-806.1mV  -12.51mA   -40.49mA   -15.5mA
-748.5mV  -7.652mA   -20.18mA   -12.33mA
-690.9mV  -5.478mA   -8.314mA   -9.416mA
-575.8mV  -2.46mA    -1.84mA    -4.41mA
1.785V    19.34mA    19.95mA    17.93mA
3.57V     66.29mA    62.85mA    61.86mA
[Power Clamp]
-1.77V    920.2mA    688.3mA    1.286A
-1.079V   202.3mA    208.7mA    217.1mA
-1.021V   150mA      171.1mA    145.9mA
-963.6mV  102.6mA    134.7mA    85.67mA
-906.1mV  61.74mA    100.3mA    45.45mA
-848.5mV  31.39mA    69.04mA    28.78mA
-790.9mV  16.33mA    42.52mA    21.9mA
-733.3mV  10.88mA    22.67mA    16.64mA
-618.2mV  5.518mA    5.608mA    8.28mA
-445.5mV  1.754mA    1.642mA    1.781mA
1.8V      -22.67mA   -21.19mA   -23.11mA
3.585V    -61.92mA   -58.02mA   -62.19mA
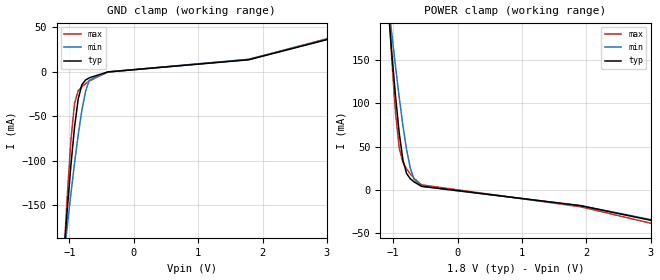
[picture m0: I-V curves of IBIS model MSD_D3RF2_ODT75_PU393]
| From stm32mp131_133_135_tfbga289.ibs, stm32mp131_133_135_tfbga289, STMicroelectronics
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[Model] MSD_D3RF2_ODT75_PU393
Model_type   Input
C_comp 2.276pF   2.211pF   2.340pF
Vinh = 1.150V
Vinl = 650.000mV
[Temperature Range]   25.000   125.000   -40.000
[Voltage Range]   1.800V   1.700V   1.900V
[GND Clamp Reference]   0.00V   0.00V   0.00V
[POWER Clamp Reference]   1.800V   1.700V   1.900V
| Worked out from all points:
|   GND clamp passes 1 mA (typ) near -0.46 V on its own axis
|   POWER clamp passes 1 mA (typ) near -0.38 V on its own axis
[GND Clamp]
-1.785V   -933.1mA   -691.4mA   -1.3A
-1.094V   -212.3mA   -212.9mA   -219.5mA
-1.036V   -157.5mA   -175.1mA   -142.8mA
-978.8mV  -106.7mA   -138.4mA   -78.73mA
-921.2mV  -62.98mA   -103.4mA   -36.16mA
-863.6mV  -30.8mA    -71.15mA   -21.46mA
-806.1mV  -14.67mA   -43.24mA   -16.97mA
-748.5mV  -9.478mA   -22.06mA   -13.61mA
-690.9mV  -6.992mA   -9.634mA   -10.49mA
-403mV    -392uA     -374uA     -512uA
1.785V    13.21mA    13.78mA    13.59mA
3.57V     46.41mA    46.72mA    47.73mA
[Power Clamp]
-1.77V    939.3mA    703.3mA    1.3A
-1.079V   212.6mA    218.6mA    223.1mA
-1.021V   158.1mA    180.3mA    150.6mA
-963.6mV  108.4mA    142.9mA    89.59mA
-906.1mV  65.89mA    107.2mA    48.68mA
-848.5mV  34.6mA     74.35mA    31.47mA
-790.9mV  18.87mA    46.16mA    24.11mA
-733.3mV  12.83mA    25.03mA    18.42mA
-675.8mV  9.261mA    12.46mA    13.46mA
-560.6mV  4.204mA    4.02mA     5.828mA
1.915V    -18.23mA   -18.31mA   -19.56mA
3.585V    -44.15mA   -42.9mA    -48.68mA
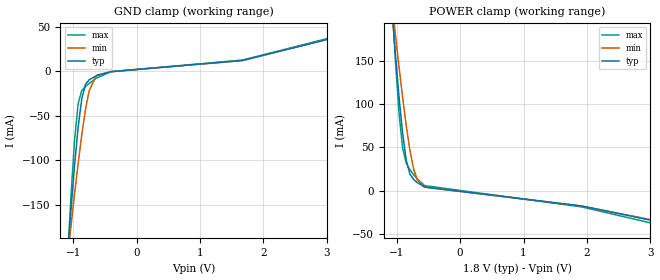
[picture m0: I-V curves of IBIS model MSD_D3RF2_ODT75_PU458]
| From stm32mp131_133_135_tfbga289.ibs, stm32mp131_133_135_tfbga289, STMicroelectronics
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[Model] MSD_D3RF2_ODT75_PU458
Model_type   Input
C_comp 2.305pF   2.239pF   2.370pF
Vinh = 1.150V
Vinl = 650.000mV
[Temperature Range]   25.000   125.000   -40.000
[Voltage Range]   1.800V   1.700V   1.900V
[GND Clamp Reference]   0.00V   0.00V   0.00V
[POWER Clamp Reference]   1.800V   1.700V   1.900V
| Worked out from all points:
|   GND clamp passes 1 mA (typ) near -0.46 V on its own axis
|   POWER clamp passes 1 mA (typ) near -0.38 V on its own axis
[GND Clamp]
-1.785V   -933.6mA   -691.7mA   -1.3A
-1.094V   -212.5mA   -213.1mA   -219.8mA
-1.036V   -157.6mA   -175.3mA   -143mA
-978.8mV  -106.8mA   -138.6mA   -78.87mA
-921.2mV  -63.14mA   -103.6mA   -36.33mA
-863.6mV  -30.94mA   -71.27mA   -21.62mA
-806.1mV  -14.8mA    -43.35mA   -17.11mA
-748.5mV  -9.584mA   -22.15mA   -13.73mA
-633.3mV  -5.108mA   -4.55mA    -7.702mA
-403mV    -416uA     -390uA     -524uA
1.67V     12.21mA    11.98mA    12.62mA
3.57V     45.71mA    46.16mA    46.93mA
[Power Clamp]
-1.77V    939.8mA    703.7mA    1.301A
-1.079V   212.8mA    218.8mA    223.3mA
-1.021V   158.3mA    180.4mA    150.8mA
-963.6mV  108.5mA    143mA      89.77mA
-906.1mV  66.07mA    107.3mA    48.88mA
-848.5mV  34.76mA    74.44mA    31.65mA
-790.9mV  19.01mA    46.26mA    24.26mA
-733.3mV  12.96mA    25.11mA    18.55mA
-675.8mV  9.364mA    12.53mA    13.57mA
-560.6mV  4.272mA    4.066mA    5.888mA
1.915V    -17.51mA   -17.73mA   -18.66mA
3.585V    -42.8mA    -41.8mA    -47.02mA
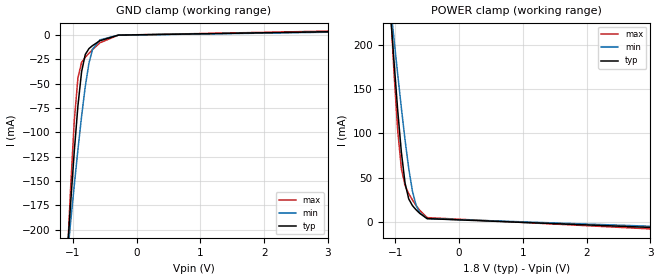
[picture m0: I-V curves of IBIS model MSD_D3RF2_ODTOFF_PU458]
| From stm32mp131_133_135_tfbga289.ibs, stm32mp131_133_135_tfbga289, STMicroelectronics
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[Model] MSD_D3RF2_ODTOFF_PU458
Model_type   Input
C_comp 2.374pF   2.292pF   2.495pF
Vinh = 1.150V
Vinl = 650.000mV
[Temperature Range]   25.000   125.000   -40.000
[Voltage Range]   1.800V   1.700V   1.900V
[GND Clamp Reference]   0.00V   0.00V   0.00V
[POWER Clamp Reference]   1.800V   1.700V   1.900V
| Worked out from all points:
|   GND clamp passes 1 mA (typ) near -0.40 V on its own axis
|   POWER clamp passes 1 mA (typ) near -0.41 V on its own axis
[GND Clamp]
-1.785V   -963.7mA   -721.4mA   -1.334A
-1.094V   -229.9mA   -231.7mA   -237.3mA
-1.036V   -173.1mA   -192.6mA   -157mA
-978.8mV  -119.7mA   -154.5mA   -88.59mA
-921.2mV  -72.65mA   -117.7mA   -43.77mA
-863.6mV  -37.6mA    -83.3mA    -28.08mA
-806.1mV  -19.98mA   -52.82mA   -22.81mA
-748.5mV  -13.94mA   -28.92mA   -18.7mA
-690.9mV  -10.76mA   -14.33mA   -14.85mA
-575.8mV  -5.794mA   -4.929mA   -7.941mA
-287.9mV  -71.99uA   -122uA     -58.99uA
3.57V     3.983mA    3.425mA    4.768mA
[Power Clamp]
-1.77V    980.6mA    743.8mA    1.344A
-1.079V   237.9mA    245.6mA    244.2mA
-1.021V   179.9mA    205.6mA    167.1mA
-963.6mV  125.5mA    166.3mA    102.8mA
-906.1mV  78.24mA    128.2mA    59.74mA
-848.5mV  43.56mA    92.24mA    40.75mA
-790.9mV  25.81mA    60.18mA    31.82mA
-733.3mV  18.34mA    34.82mA    24.7mA
-675.8mV  13.52mA    18.63mA    18.43mA
-618.2mV  9.549mA    10.34mA    12.97mA
-503mV    3.592mA    3.678mA    4.737mA
3.585V    -7.994mA   -6.463mA   -10.16mA
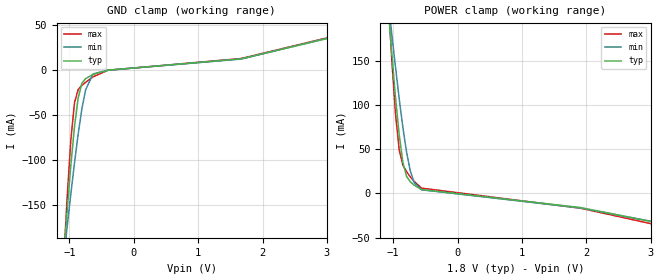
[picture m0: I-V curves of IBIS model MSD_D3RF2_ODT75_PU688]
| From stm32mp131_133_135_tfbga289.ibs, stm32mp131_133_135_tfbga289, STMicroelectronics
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[Model] MSD_D3RF2_ODT75_PU688
Model_type   Input
C_comp 2.363pF   2.297pF   2.430pF
Vinh = 1.150V
Vinl = 650.000mV
[Temperature Range]   25.000   125.000   -40.000
[Voltage Range]   1.800V   1.700V   1.900V
[GND Clamp Reference]   0.00V   0.00V   0.00V
[POWER Clamp Reference]   1.800V   1.700V   1.900V
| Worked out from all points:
|   GND clamp passes 1 mA (typ) near -0.46 V on its own axis
|   POWER clamp passes 1 mA (typ) near -0.37 V on its own axis
[GND Clamp]
-1.785V   -934.4mA   -692.5mA   -1.301A
-1.094V   -212.9mA   -213.5mA   -220.3mA
-1.036V   -158mA     -175.6mA   -143.5mA
-978.8mV  -107.2mA   -138.9mA   -79.29mA
-921.2mV  -63.44mA   -103.9mA   -36.73mA
-863.6mV  -31.21mA   -71.49mA   -21.97mA
-806.1mV  -15.03mA   -43.53mA   -17.41mA
-748.5mV  -9.78mA    -22.31mA   -13.99mA
-633.3mV  -5.23mA    -4.662mA   -7.876mA
-403mV    -440uA     -416.6uA   -562uA
1.67V     12.2mA     11.98mA    12.61mA
3.57V     44.37mA    45.03mA    45.34mA
[Power Clamp]
-1.77V    940.7mA    704.5mA    1.302A
-1.079V   213.4mA    219.2mA    223.9mA
-1.021V   158.7mA    180.7mA    151.3mA
-963.6mV  108.9mA    143.3mA    90.2mA
-906.1mV  66.38mA    107.5mA    49.28mA
-848.5mV  35.03mA    74.67mA    32mA
-790.9mV  19.24mA    46.46mA    24.57mA
-733.3mV  13.16mA    25.28mA    18.8mA
-675.8mV  9.535mA    12.66mA    13.78mA
-560.6mV  4.376mA    4.151mA    6.017mA
1.915V    -16.09mA   -16.57mA   -16.84mA
3.585V    -40.16mA   -39.66mA   -43.64mA
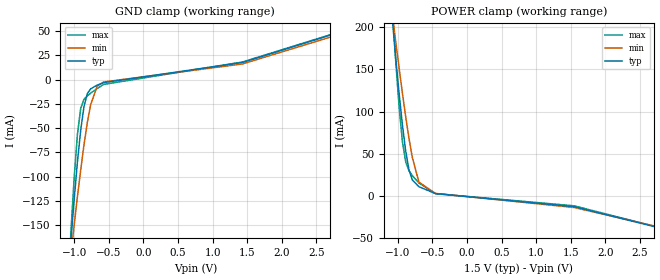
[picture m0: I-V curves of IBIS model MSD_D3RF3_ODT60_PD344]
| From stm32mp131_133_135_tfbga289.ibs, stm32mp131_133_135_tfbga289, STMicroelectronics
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[Model] MSD_D3RF3_ODT60_PD344
Model_type   Input
C_comp 2.257pF   2.212pF   2.315pF
Vinh = 925.000mV
Vinl = 575.000mV
[Temperature Range]   25.000   125.000   -40.000
[Voltage Range]   1.500V   1.425V   1.575V
[GND Clamp Reference]   0.00V   0.00V   0.00V
[POWER Clamp Reference]   1.500V   1.425V   1.575V
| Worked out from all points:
|   GND clamp passes 1 mA (typ) near -0.46 V on its own axis
|   POWER clamp passes 1 mA (typ) near -0.27 V on its own axis
[GND Clamp]
-1.48V    -603mA     -471.3mA   -809.6mA
-1.05V    -166.6mA   -180.5mA   -158.4mA
-1.002V   -123.8mA   -150.1mA   -101.6mA
-954.6mV  -84.86mA   -120.6mA   -56.33mA
-906.8mV  -51.83mA   -92.73mA   -29.37mA
-859.1mV  -27.47mA   -66.85mA   -20.19mA
-811.4mV  -14.34mA   -44.14mA   -16.64mA
-763.6mV  -9.384mA   -25.82mA   -13.91mA
-668.2mV  -5.538mA   -6.51mA    -8.977mA
-572.7mV  -2.951mA   -2.27mA    -4.798mA
1.432V    17.76mA    16.27mA    18.28mA
2.959V    51.73mA    49.49mA    52.06mA
[Power Clamp]
-1.459V   600.4mA    476.5mA    798.7mA
-1.077V   207.6mA    214.1mA    219.3mA
-1.03V    162.9mA    182.5mA    159.1mA
-981.8mV  121.5mA    151.7mA    105.8mA
-934.1mV  84.25mA    121.9mA    64.32mA
-886.4mV  52.96mA    93.72mA    40.04mA
-838.6mV  30.44mA    67.9mA     29.57mA
-790.9mV  18.75mA    45.57mA    23.88mA
-695.5mV  10.63mA    16.05mA    15.1mA
-456.8mV  2.43mA     2.649mA    2.388mA
1.548V    -13.09mA   -14.1mA    -12.09mA
2.98V     -42.38mA   -41.25mA   -42.19mA
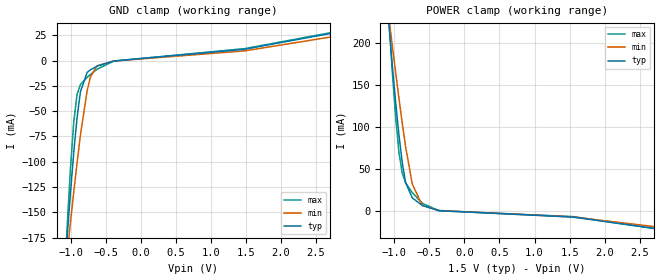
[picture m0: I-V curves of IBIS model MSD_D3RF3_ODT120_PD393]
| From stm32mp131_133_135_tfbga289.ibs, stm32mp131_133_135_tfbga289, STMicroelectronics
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[Model] MSD_D3RF3_ODT120_PD393
Model_type   Input
C_comp 2.296pF   2.253pF   2.399pF
Vinh = 925.000mV
Vinl = 575.000mV
[Temperature Range]   25.000   125.000   -40.000
[Voltage Range]   1.500V   1.425V   1.575V
[GND Clamp Reference]   0.00V   0.00V   0.00V
[POWER Clamp Reference]   1.500V   1.425V   1.575V
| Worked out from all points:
|   GND clamp passes 1 mA (typ) near -0.44 V on its own axis
|   POWER clamp passes 1 mA (typ) near -0.37 V on its own axis
[GND Clamp]
-1.48V    -618.7mA   -488mA     -825.7mA
-1.05V    -175.7mA   -191.7mA   -166.2mA
-1.002V   -131.5mA   -160.3mA   -107.4mA
-954.6mV  -90.92mA   -130mA     -60.83mA
-906.8mV  -56.27mA   -100.9mA   -33.25mA
-859.1mV  -30.85mA   -73.71mA   -23.66mA
-763.6mV  -11.79mA   -29.77mA   -16.64mA
-715.9mV  -9.2mA     -16.07mA   -13.76mA
-620.5mV  -5.557mA   -5.151mA   -8.469mA
-381.8mV  -425.2uA   -485.2uA   -512.6uA
1.48V     11.09mA    9.498mA    11.71mA
2.959V    29.94mA    26mA       30.71mA
[Power Clamp]
-1.459V   620.6mA    497.7mA    818.9mA
-1.077V   220.9mA    229.9mA    229.7mA
-1.03V    174.2mA    197.4mA    167.5mA
-981.8mV  130.3mA    165.5mA    112.8mA
-934.1mV  90.79mA    134.3mA    70.26mA
-886.4mV  57.75mA    104.5mA    45.11mA
-838.6mV  34.16mA    76.64mA    33.89mA
-743.2mV  16.02mA    32.26mA    22.23mA
-600mV    6.985mA    7.042mA    9.617mA
-361.4mV  900.5uA    1.08mA     750.6uA
1.548V    -6.76mA    -6.642mA   -6.146mA
2.98V     -23.37mA   -20.67mA   -23.47mA
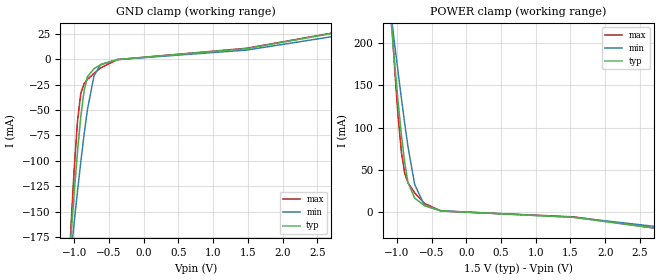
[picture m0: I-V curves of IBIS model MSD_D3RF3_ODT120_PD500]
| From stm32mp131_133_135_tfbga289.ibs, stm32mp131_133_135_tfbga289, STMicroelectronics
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[Model] MSD_D3RF3_ODT120_PD500
Model_type   Input
C_comp 2.343pF   2.299pF   2.446pF
Vinh = 925.000mV
Vinl = 575.000mV
[Temperature Range]   25.000   125.000   -40.000
[Voltage Range]   1.500V   1.425V   1.575V
[GND Clamp Reference]   0.00V   0.00V   0.00V
[POWER Clamp Reference]   1.500V   1.425V   1.575V
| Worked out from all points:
|   GND clamp passes 1 mA (typ) near -0.43 V on its own axis
|   POWER clamp passes 1 mA (typ) near -0.37 V on its own axis
[GND Clamp]
-1.48V    -619.3mA   -488.3mA   -826.3mA
-1.05V    -176mA     -191.9mA   -166.5mA
-1.002V   -131.7mA   -160.6mA   -107.7mA
-954.6mV  -91.16mA   -130.1mA   -61.15mA
-906.8mV  -56.49mA   -101.1mA   -33.54mA
-859.1mV  -31.05mA   -73.88mA   -23.92mA
-811.4mV  -17.31mA   -49.67mA   -19.97mA
-715.9mV  -9.332mA   -16.17mA   -13.94mA
-620.5mV  -5.656mA   -5.23mA    -8.589mA
-381.8mV  -439.6uA   -498.4uA   -539.4uA
1.48V     10.26mA    8.847mA    10.66mA
2.959V    28.26mA    24.72mA    28.6mA
[Power Clamp]
-1.459V   621.1mA    498.2mA    819.6mA
-1.077V   221.2mA    230.2mA    230.1mA
-1.03V    174.5mA    197.7mA    167.9mA
-981.8mV  130.6mA    165.7mA    113.1mA
-934.1mV  91.06mA    134.5mA    70.57mA
-886.4mV  57.99mA    104.7mA    45.41mA
-838.6mV  34.39mA    76.81mA    34.15mA
-743.2mV  16.2mA     32.41mA    22.43mA
-600mV    7.098mA    7.126mA    9.738mA
-361.4mV  918uA      1.093mA    766.6uA
1.548V    -6.733mA   -6.587mA   -6.146mA
2.98V     -22.54mA   -19.97mA   -22.45mA
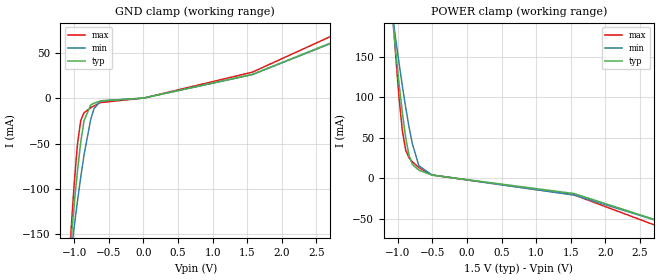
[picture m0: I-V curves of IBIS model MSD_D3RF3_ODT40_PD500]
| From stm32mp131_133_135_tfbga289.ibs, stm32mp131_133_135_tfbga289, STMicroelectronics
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[Model] MSD_D3RF3_ODT40_PD500
Model_type   Input
C_comp 2.301pF   2.260pF   2.378pF
Vinh = 925.000mV
Vinl = 575.000mV
[Temperature Range]   25.000   125.000   -40.000
[Voltage Range]   1.500V   1.425V   1.575V
[GND Clamp Reference]   0.00V   0.00V   0.00V
[POWER Clamp Reference]   1.500V   1.425V   1.575V
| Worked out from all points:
|   GND clamp passes 1 mA (typ) near -0.48 V on its own axis
|   POWER clamp passes 1 mA (typ) near -0.21 V on its own axis
[GND Clamp]
-1.48V    -589.6mA   -457.3mA   -788.6mA
-1.05V    -159.3mA   -171.7mA   -149.4mA
-1.002V   -117.9mA   -142.2mA   -94.99mA
-954.6mV  -80.54mA   -113.8mA   -51.03mA
-906.8mV  -48.63mA   -87.06mA   -24.73mA
-859.1mV  -24.93mA   -62.62mA   -16.06mA
-763.6mV  -7.578mA   -23.82mA   -10.72mA
-715.9mV  -5.64mA    -11.87mA   -8.63mA
-620.5mV  -3.204mA   -2.926mA   -4.934mA
900nV     14.73nA    13.43nA    17.27nA
1.575V    26.12mA    25.82mA    28.56mA
2.959V    68.35mA    67.69mA    76.59mA
[Power Clamp]
-1.459V   583mA      458.8mA    772.4mA
-1.077V   197.7mA    201.4mA    208mA
-1.03V    155.3mA    171mA      150mA
-981.8mV  116mA      141.5mA    98.2mA
-934.1mV  80.37mA    113.3mA    57.93mA
-886.4mV  50.03mA    87.09mA    34.67mA
-838.6mV  28.15mA    63.3mA     25.12mA
-790.9mV  16.99mA    42.7mA     20.26mA
-695.5mV  9.77mA     15.2mA     12.95mA
-504.6mV  3.734mA    3.864mA    3.936mA
1.548V    -19.03mA   -20.88mA   -20.65mA
2.98V     -58.39mA   -58.62mA   -66.41mA
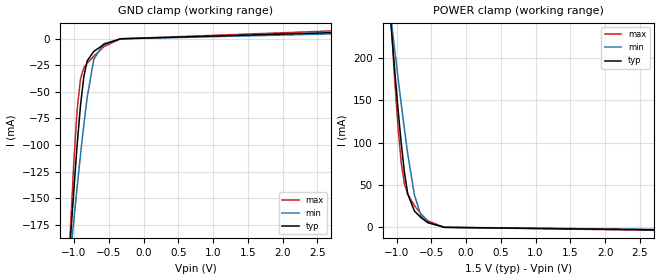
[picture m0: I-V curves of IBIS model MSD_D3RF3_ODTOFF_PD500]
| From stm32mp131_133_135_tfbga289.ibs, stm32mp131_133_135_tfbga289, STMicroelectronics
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[Model] MSD_D3RF3_ODTOFF_PD500
Model_type   Input
C_comp 2.402pF   2.320pF   2.524pF
Vinh = 925.000mV
Vinl = 575.000mV
[Temperature Range]   25.000   125.000   -40.000
[Voltage Range]   1.500V   1.425V   1.575V
[GND Clamp Reference]   0.00V   0.00V   0.00V
[POWER Clamp Reference]   1.500V   1.425V   1.575V
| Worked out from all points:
|   GND clamp passes 1 mA (typ) near -0.40 V on its own axis
|   POWER clamp passes 1 mA (typ) near -0.41 V on its own axis
[GND Clamp]
-1.48V    -635.8mA   -502.8mA   -842.7mA
-1.098V   -233.9mA   -234.4mA   -243mA
-1.05V    -186.4mA   -201.9mA   -175.3mA
-1.002V   -141mA     -169.9mA   -114.5mA
-954.6mV  -98.93mA   -138.8mA   -66.16mA
-906.8mV  -62.56mA   -108.9mA   -37.69mA
-859.1mV  -35.64mA   -80.79mA   -27.61mA
-811.4mV  -21.01mA   -55.47mA   -23.3mA
-715.9mV  -12.09mA   -19.51mA   -16.55mA
-572.7mV  -5.71mA    -4.851mA   -7.809mA
-334.1mV  -253uA     -321.6uA   -258.1uA
2.959V    6.007mA    4.726mA    7.743mA
[Power Clamp]
-1.459V   642.6mA    516.8mA    840.4mA
-1.077V   236.4mA    244.5mA    242.1mA
-1.03V    188.2mA    211.4mA    177.6mA
-981.8mV  142.2mA    178.6mA    121mA
-934.1mV  100.2mA    146.5mA    77.2mA
-886.4mV  64.67mA    115.6mA    51.08mA
-838.6mV  39.37mA    86.39mA    39.01mA
-743.2mV  19.35mA    38.46mA    25.89mA
-647.7mV  11.52mA    13.7mA     15.7mA
-552.3mV  5.808mA    5.708mA    7.784mA
-313.6mV  101.6uA    234.6uA    118.2uA
2.98V     -3.06mA    -2.563mA   -3.724mA
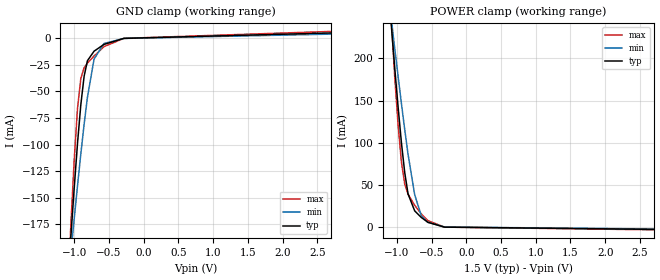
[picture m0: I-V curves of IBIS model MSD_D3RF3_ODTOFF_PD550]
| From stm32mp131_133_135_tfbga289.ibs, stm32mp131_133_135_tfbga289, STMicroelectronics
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[Model] MSD_D3RF3_ODTOFF_PD550
Model_type   Input
C_comp 2.415pF   2.332pF   2.537pF
Vinh = 925.000mV
Vinl = 575.000mV
[Temperature Range]   25.000   125.000   -40.000
[Voltage Range]   1.500V   1.425V   1.575V
[GND Clamp Reference]   0.00V   0.00V   0.00V
[POWER Clamp Reference]   1.500V   1.425V   1.575V
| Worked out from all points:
|   GND clamp passes 1 mA (typ) near -0.40 V on its own axis
|   POWER clamp passes 1 mA (typ) near -0.41 V on its own axis
[GND Clamp]
-1.48V    -635.9mA   -503mA     -842.9mA
-1.098V   -234mA     -234.5mA   -243.2mA
-1.05V    -186.5mA   -201.9mA   -175.5mA
-1.002V   -141.1mA   -170mA     -114.7mA
-954.6mV  -99mA      -138.9mA   -66.27mA
-906.8mV  -62.65mA   -108.9mA   -37.79mA
-859.1mV  -35.71mA   -80.85mA   -27.7mA
-811.4mV  -21.07mA   -55.52mA   -23.37mA
-715.9mV  -12.13mA   -19.55mA   -16.61mA
-572.7mV  -5.736mA   -4.872mA   -7.844mA
-286.4mV  -72.95uA   -123.1uA   -58.38uA
2.959V    5.466mA    4.298mA    7.042mA
[Power Clamp]
-1.459V   642.7mA    516.9mA    840.6mA
-1.077V   236.5mA    244.6mA    242.3mA
-1.03V    188.2mA    211.4mA    177.7mA
-981.8mV  142.2mA    178.7mA    121.1mA
-934.1mV  100.2mA    146.6mA    77.31mA
-886.4mV  64.75mA    115.6mA    51.18mA
-838.6mV  39.44mA    86.44mA    39.09mA
-743.2mV  19.4mA     38.51mA    25.96mA
-647.7mV  11.55mA    13.74mA    15.74mA
-552.3mV  5.831mA    5.734mA    7.81mA
-313.6mV  101.8uA    238uA      118.1uA
2.98V     -2.782mA   -2.33mA    -3.385mA
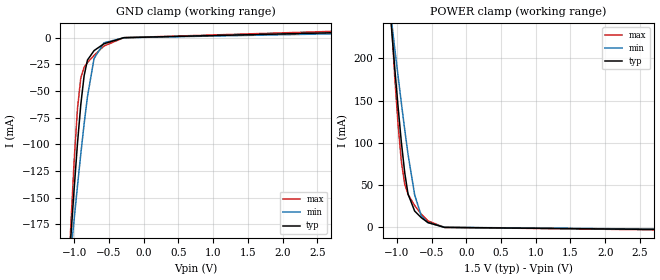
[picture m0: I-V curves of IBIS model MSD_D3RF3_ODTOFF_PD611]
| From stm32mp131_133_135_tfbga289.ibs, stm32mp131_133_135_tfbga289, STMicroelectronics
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[Model] MSD_D3RF3_ODTOFF_PD611
Model_type   Input
C_comp 2.432pF   2.349pF   2.554pF
Vinh = 925.000mV
Vinl = 575.000mV
[Temperature Range]   25.000   125.000   -40.000
[Voltage Range]   1.500V   1.425V   1.575V
[GND Clamp Reference]   0.00V   0.00V   0.00V
[POWER Clamp Reference]   1.500V   1.425V   1.575V
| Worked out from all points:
|   GND clamp passes 1 mA (typ) near -0.40 V on its own axis
|   POWER clamp passes 1 mA (typ) near -0.41 V on its own axis
[GND Clamp]
-1.48V    -636.1mA   -503.1mA   -843.1mA
-1.098V   -234.1mA   -234.6mA   -243.2mA
-1.05V    -186.6mA   -202.1mA   -175.6mA
-1.002V   -141.2mA   -170mA     -114.7mA
-954.6mV  -99.08mA   -138.9mA   -66.37mA
-906.8mV  -62.72mA   -109mA     -37.88mA
-859.1mV  -35.78mA   -80.9mA    -27.79mA
-811.4mV  -21.13mA   -55.56mA   -23.45mA
-715.9mV  -12.18mA   -19.58mA   -16.67mA
-572.7mV  -5.762mA   -4.892mA   -7.877mA
-286.4mV  -73.73uA   -124uA     -59.07uA
2.959V    4.918mA    3.87mA     6.334mA
[Power Clamp]
-1.459V   642.9mA    517.2mA    840.8mA
-1.077V   236.6mA    244.7mA    242.4mA
-1.03V    188.4mA    211.6mA    177.8mA
-981.8mV  142.4mA    178.8mA    121.2mA
-934.1mV  100.2mA    146.7mA    77.42mA
-886.4mV  64.83mA    115.7mA    51.28mA
-838.6mV  39.51mA    86.53mA    39.18mA
-743.2mV  19.45mA    38.55mA    26.02mA
-647.7mV  11.59mA    13.77mA    15.79mA
-552.3mV  5.855mA    5.756mA    7.843mA
-313.6mV  104.4uA    240.4uA    121.3uA
2.98V     -2.504mA   -2.097mA   -3.047mA
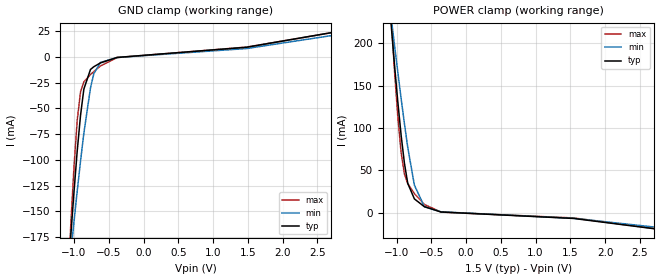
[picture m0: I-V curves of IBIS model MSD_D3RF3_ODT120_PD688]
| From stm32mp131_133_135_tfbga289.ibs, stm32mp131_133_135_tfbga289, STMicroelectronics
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[Model] MSD_D3RF3_ODT120_PD688
Model_type   Input
C_comp 2.385pF   2.341pF   2.490pF
Vinh = 925.000mV
Vinl = 575.000mV
[Temperature Range]   25.000   125.000   -40.000
[Voltage Range]   1.500V   1.425V   1.575V
[GND Clamp Reference]   0.00V   0.00V   0.00V
[POWER Clamp Reference]   1.500V   1.425V   1.575V
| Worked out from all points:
|   GND clamp passes 1 mA (typ) near -0.43 V on its own axis
|   POWER clamp passes 1 mA (typ) near -0.37 V on its own axis
[GND Clamp]
-1.48V    -619.8mA   -488.8mA   -827mA
-1.05V    -176.3mA   -192.1mA   -166.9mA
-1.002V   -132mA     -160.8mA   -108.1mA
-954.6mV  -91.4mA    -130.4mA   -61.47mA
-906.8mV  -56.71mA   -101.2mA   -33.82mA
-859.1mV  -31.25mA   -74.03mA   -24.18mA
-763.6mV  -12.1mA    -30.02mA   -17.06mA
-715.9mV  -9.477mA   -16.28mA   -14.11mA
-620.5mV  -5.747mA   -5.308mA   -8.716mA
-381.8mV  -455.6uA   -512.6uA   -554.6uA
1.48V     9.44mA     8.194mA    9.601mA
2.959V    26.64mA    23.42mA    26.48mA
[Power Clamp]
-1.459V   621.7mA    498.7mA    820.3mA
-1.077V   221.5mA    230.5mA    230.5mA
-1.03V    174.8mA    198mA      168.2mA
-981.8mV  130.8mA    166mA      113.4mA
-934.1mV  91.3mA     134.8mA    70.88mA
-886.4mV  58.22mA    104.9mA    45.7mA
-838.6mV  34.59mA    77.01mA    34.41mA
-743.2mV  16.35mA    32.56mA    22.64mA
-600mV    7.187mA    7.222mA    9.86mA
-361.4mV  927.4uA    1.109mA    782.6uA
1.548V    -6.706mA   -6.532mA   -6.145mA
2.98V     -21.7mA    -19.28mA   -21.44mA
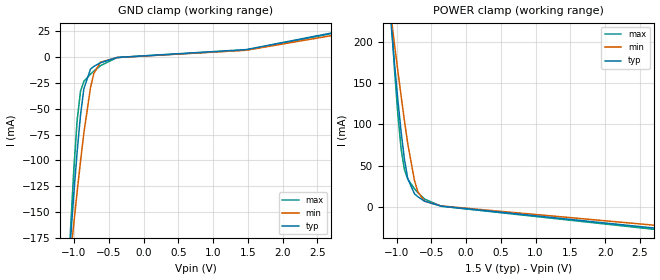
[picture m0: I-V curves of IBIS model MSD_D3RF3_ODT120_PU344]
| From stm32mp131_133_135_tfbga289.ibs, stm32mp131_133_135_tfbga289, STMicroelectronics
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[Model] MSD_D3RF3_ODT120_PU344
Model_type   Input
C_comp 2.270pF   2.226pF   2.373pF
Vinh = 925.000mV
Vinl = 575.000mV
[Temperature Range]   25.000   125.000   -40.000
[Voltage Range]   1.500V   1.425V   1.575V
[GND Clamp Reference]   0.00V   0.00V   0.00V
[POWER Clamp Reference]   1.500V   1.425V   1.575V
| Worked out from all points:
|   GND clamp passes 1 mA (typ) near -0.44 V on its own axis
|   POWER clamp passes 1 mA (typ) near -0.37 V on its own axis
[GND Clamp]
-1.48V    -618.4mA   -487.6mA   -825.3mA
-1.05V    -175.5mA   -191.5mA   -166mA
-1.002V   -131.2mA   -160.1mA   -107.2mA
-954.6mV  -90.7mA    -129.8mA   -60.61mA
-906.8mV  -56.1mA    -100.7mA   -33.05mA
-859.1mV  -30.71mA   -73.55mA   -23.48mA
-763.6mV  -11.67mA   -29.64mA   -16.51mA
-715.9mV  -9.109mA   -15.95mA   -13.64mA
-620.5mV  -5.5mA     -5.064mA   -8.38mA
-381.8mV  -416.8uA   -457.2uA   -510uA
1.48V     7.25mA     6.588mA    6.813mA
2.959V    26.58mA    23.66mA    26.08mA
[Power Clamp]
-1.459V   620.4mA    497.6mA    818.5mA
-1.077V   220.7mA    229.8mA    229.5mA
-1.03V    174mA      197.4mA    167.3mA
-981.8mV  130.1mA    165.4mA    112.6mA
-934.1mV  90.64mA    134.3mA    70.03mA
-886.4mV  57.66mA    104.4mA    44.94mA
-838.6mV  34.08mA    76.57mA    33.74mA
-743.2mV  15.97mA    32.24mA    22.12mA
-695.5mV  12.37mA    18.69mA    17.41mA
-600mV    6.954mA    7.027mA    9.551mA
-361.4mV  909.5uA    1.086mA    745uA
2.98V     -28.12mA   -24.39mA   -29.8mA
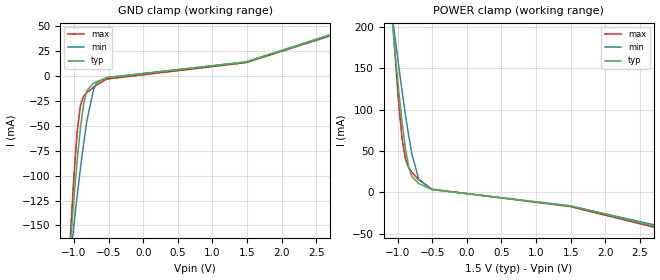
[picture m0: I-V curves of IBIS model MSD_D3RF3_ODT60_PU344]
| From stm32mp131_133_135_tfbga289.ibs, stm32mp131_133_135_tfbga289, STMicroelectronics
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[Model] MSD_D3RF3_ODT60_PU344
Model_type   Input
C_comp 2.260pF   2.215pF   2.319pF
Vinh = 925.000mV
Vinl = 575.000mV
[Temperature Range]   25.000   125.000   -40.000
[Voltage Range]   1.500V   1.425V   1.575V
[GND Clamp Reference]   0.00V   0.00V   0.00V
[POWER Clamp Reference]   1.500V   1.425V   1.575V
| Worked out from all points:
|   GND clamp passes 1 mA (typ) near -0.46 V on its own axis
|   POWER clamp passes 1 mA (typ) near -0.27 V on its own axis
[GND Clamp]
-1.48V    -603mA     -471.1mA   -809.5mA
-1.05V    -166.6mA   -180.4mA   -158.3mA
-1.002V   -123.7mA   -150mA     -101.5mA
-954.6mV  -84.81mA   -120.6mA   -56.25mA
-906.8mV  -51.83mA   -92.62mA   -29.31mA
-859.1mV  -27.47mA   -66.78mA   -20.13mA
-811.4mV  -14.34mA   -44.08mA   -16.58mA
-715.9mV  -7.15mA    -13.18mA   -11.32mA
-668.2mV  -5.54mA    -6.462mA   -8.93mA
-525mV    -1.95mA    -1.468mA   -3.08mA
1.48V     14.06mA    13.97mA    13.35mA
2.959V    47.3mA     46.29mA    45.94mA
[Power Clamp]
-1.459V   600.5mA    476.7mA    798.9mA
-1.077V   207.6mA    214.2mA    219.4mA
-1.03V    162.9mA    182.7mA    159.2mA
-981.8mV  121.5mA    151.8mA    105.9mA
-934.1mV  84.39mA    122mA      64.41mA
-886.4mV  53.01mA    93.78mA    40.13mA
-838.6mV  30.48mA    67.96mA    29.65mA
-790.9mV  18.79mA    45.64mA    23.95mA
-695.5mV  10.66mA    16.11mA    15.16mA
-504.6mV  3.329mA    3.442mA    3.773mA
1.5V      -16.49mA   -16.56mA   -17.3mA
2.98V     -46.56mA   -44.52mA   -47.92mA
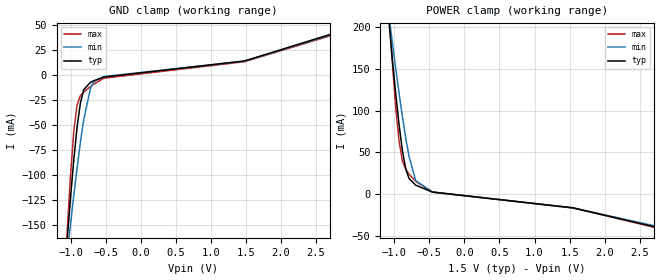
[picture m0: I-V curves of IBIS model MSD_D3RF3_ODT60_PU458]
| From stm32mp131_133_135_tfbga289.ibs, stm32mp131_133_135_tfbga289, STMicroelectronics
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[Model] MSD_D3RF3_ODT60_PU458
Model_type   Input
C_comp 2.319pF   2.273pF   2.379pF
Vinh = 925.000mV
Vinl = 575.000mV
[Temperature Range]   25.000   125.000   -40.000
[Voltage Range]   1.500V   1.425V   1.575V
[GND Clamp Reference]   0.00V   0.00V   0.00V
[POWER Clamp Reference]   1.500V   1.425V   1.575V
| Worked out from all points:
|   GND clamp passes 1 mA (typ) near -0.46 V on its own axis
|   POWER clamp passes 1 mA (typ) near -0.27 V on its own axis
[GND Clamp]
-1.48V    -603.7mA   -471.7mA   -810.4mA
-1.05V    -167mA     -180.7mA   -158.7mA
-1.002V   -124mA     -150.3mA   -102mA
-954.6mV  -85.18mA   -120.9mA   -56.68mA
-906.8mV  -52.12mA   -92.87mA   -29.7mA
-859.1mV  -27.73mA   -67mA      -20.47mA
-811.4mV  -14.57mA   -44.26mA   -16.9mA
-715.9mV  -7.32mA    -13.32mA   -11.56mA
-668.2mV  -5.686mA   -6.577mA   -9.136mA
-525mV    -2.014mA   -1.523mA   -3.174mA
1.48V     14.06mA    13.93mA    13.34mA
2.959V    46.19mA    45.34mA    44.64mA
[Power Clamp]
-1.459V   601.2mA    477.4mA    799.8mA
-1.077V   208.1mA    214.6mA    219.9mA
-1.03V    163.4mA    183mA      159.7mA
-981.8mV  121.9mA    152.1mA    106.3mA
-934.1mV  84.7mA     122.3mA    64.81mA
-886.4mV  53.33mA    94.08mA    40.5mA
-838.6mV  30.77mA    68.25mA    29.99mA
-790.9mV  19.05mA    45.86mA    24.25mA
-695.5mV  10.86mA    16.28mA    15.39mA
-456.8mV  2.502mA    2.736mA    2.48mA
1.548V    -16.34mA   -16.55mA   -16.43mA
2.98V     -44.42mA   -42.81mA   -45.16mA
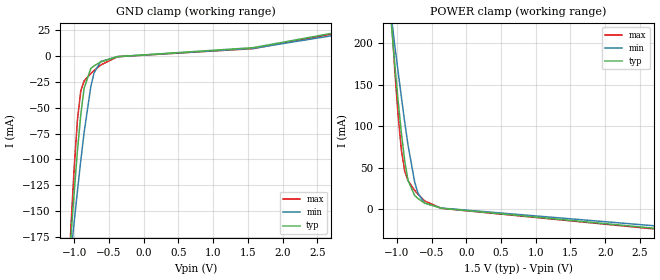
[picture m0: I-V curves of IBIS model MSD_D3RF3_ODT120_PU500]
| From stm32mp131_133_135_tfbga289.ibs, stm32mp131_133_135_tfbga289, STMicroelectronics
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[Model] MSD_D3RF3_ODT120_PU500
Model_type   Input
C_comp 2.346pF   2.301pF   2.449pF
Vinh = 925.000mV
Vinl = 575.000mV
[Temperature Range]   25.000   125.000   -40.000
[Voltage Range]   1.500V   1.425V   1.575V
[GND Clamp Reference]   0.00V   0.00V   0.00V
[POWER Clamp Reference]   1.500V   1.425V   1.575V
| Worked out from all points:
|   GND clamp passes 1 mA (typ) near -0.43 V on its own axis
|   POWER clamp passes 1 mA (typ) near -0.37 V on its own axis
[GND Clamp]
-1.48V    -619.2mA   -488.3mA   -826.3mA
-1.05V    -176mA     -191.9mA   -166.5mA
-1.002V   -131.7mA   -160.5mA   -107.8mA
-954.6mV  -91.11mA   -130.2mA   -61.15mA
-906.8mV  -56.46mA   -101mA     -33.54mA
-859.1mV  -31.03mA   -73.83mA   -23.92mA
-763.6mV  -11.92mA   -29.86mA   -16.86mA
-715.9mV  -9.319mA   -16.15mA   -13.94mA
-620.5mV  -5.646mA   -5.205mA   -8.6mA
-381.8mV  -431.4uA   -485uA     -543.2uA
1.575V    8.266mA    7.578mA    7.322mA
2.959V    25.24mA    22.51mA    24.46mA
[Power Clamp]
-1.459V   621.3mA    498.3mA    819.6mA
-1.077V   221.2mA    230.3mA    230.2mA
-1.03V    174.5mA    197.8mA    167.9mA
-981.8mV  130.6mA    165.8mA    113.1mA
-934.1mV  91.1mA     134.6mA    70.6mA
-886.4mV  58.03mA    104.7mA    45.41mA
-838.6mV  34.41mA    76.87mA    34.16mA
-743.2mV  16.21mA    32.46mA    22.44mA
-695.5mV  12.59mA    18.88mA    17.68mA
-600mV    7.107mA    7.16mA     9.739mA
-361.4mV  922.4uA    1.107mA    766.1uA
2.98V     -25.44mA   -22.21mA   -26.33mA
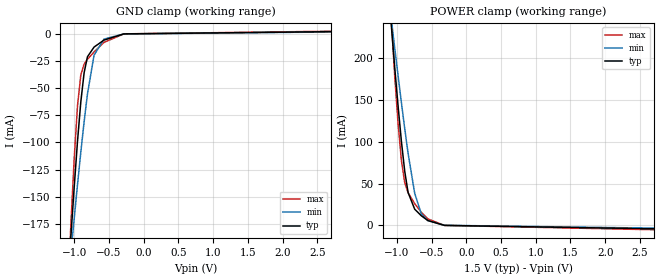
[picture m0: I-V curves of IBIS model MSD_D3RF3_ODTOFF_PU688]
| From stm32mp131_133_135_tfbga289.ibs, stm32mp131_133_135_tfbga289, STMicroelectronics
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[Model] MSD_D3RF3_ODTOFF_PU688
Model_type   Input
C_comp 2.446pF   2.363pF   2.570pF
Vinh = 925.000mV
Vinl = 575.000mV
[Temperature Range]   25.000   125.000   -40.000
[Voltage Range]   1.500V   1.425V   1.575V
[GND Clamp Reference]   0.00V   0.00V   0.00V
[POWER Clamp Reference]   1.500V   1.425V   1.575V
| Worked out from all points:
|   GND clamp passes 1 mA (typ) near -0.40 V on its own axis
|   POWER clamp passes 1 mA (typ) near -0.41 V on its own axis
[GND Clamp]
-1.48V    -636.3mA   -503.2mA   -843.3mA
-1.098V   -234.2mA   -234.6mA   -243.4mA
-1.05V    -186.7mA   -202.1mA   -175.7mA
-1.002V   -141.3mA   -170.1mA   -114.9mA
-954.6mV  -99.12mA   -139mA     -66.47mA
-906.8mV  -62.77mA   -109.1mA   -37.98mA
-859.1mV  -35.82mA   -80.93mA   -27.86mA
-811.4mV  -21.18mA   -55.59mA   -23.52mA
-715.9mV  -12.21mA   -19.6mA    -16.72mA
-572.7mV  -5.778mA   -4.9mA     -7.905mA
-286.4mV  -70.81uA   -120.4uA   -57.41uA
2.959V    2.153mA    1.833mA    2.603mA
[Power Clamp]
-1.459V   643.1mA    517.4mA    841.1mA
-1.077V   236.8mA    244.9mA    242.6mA
-1.03V    188.5mA    211.7mA    178mA
-981.8mV  142.5mA    178.9mA    121.4mA
-934.1mV  100.4mA    146.8mA    77.54mA
-886.4mV  64.93mA    115.8mA    51.39mA
-838.6mV  39.6mA     86.62mA    39.29mA
-743.2mV  19.52mA    38.63mA    26.11mA
-647.7mV  11.65mA    13.83mA    15.85mA
-552.3mV  5.893mA    5.803mA    7.878mA
-313.6mV  110.8uA    253.3uA    125.5uA
2.98V     -4.339mA   -3.493mA   -5.549mA
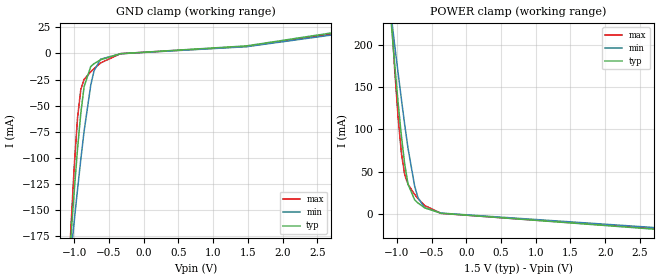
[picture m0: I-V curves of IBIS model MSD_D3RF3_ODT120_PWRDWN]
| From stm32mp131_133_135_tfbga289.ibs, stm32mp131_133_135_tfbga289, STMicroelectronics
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[Model] MSD_D3RF3_ODT120_PWRDWN
Model_type   Input
C_comp 2.505pF   2.458pF   2.612pF
Vinh = 925.000mV
Vinl = 575.000mV
[Model Spec]
Vinh   925.000mV   888.000mV   963.000mV
Vinl   575.000mV   538.000mV   613.000mV
[Temperature Range]   25.000   125.000   -40.000
[Voltage Range]   1.500V   1.425V   1.575V
[GND Clamp Reference]   0.00V   0.00V   0.00V
[POWER Clamp Reference]   1.500V   1.425V   1.575V
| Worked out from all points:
|   GND clamp passes 1 mA (typ) near -0.43 V on its own axis
|   POWER clamp passes 1 mA (typ) near -0.37 V on its own axis
[GND Clamp]
-1.48V    -621.1mA   -490mA     -828.7mA
-1.05V    -177.1mA   -192.8mA   -167.9mA
-1.002V   -132.7mA   -161.4mA   -109mA
-954.6mV  -92.03mA   -130.9mA   -62.31mA
-906.8mV  -57.29mA   -101.7mA   -34.59mA
-859.1mV  -31.78mA   -74.46mA   -24.88mA
-763.6mV  -12.51mA   -30.36mA   -17.6mA
-715.9mV  -9.834mA   -16.58mA   -14.59mA
-620.5mV  -6mA       -5.511mA   -9.054mA
-334.1mV  -216uA     -291.8uA   -207.8uA
1.48V     7.244mA    6.458mA    6.787mA
2.959V    22.27mA    19.99mA    20.87mA
[Power Clamp]
-1.459V   623.1mA    499.9mA    822.1mA
-1.077V   222.3mA    231.3mA    231.7mA
-1.03V    175.6mA    198.7mA    169.3mA
-981.8mV  131.6mA    166.7mA    114.4mA
-934.1mV  92mA       135.4mA    71.74mA
-886.4mV  58.84mA    105.4mA    46.46mA
-838.6mV  35.14mA    77.48mA    35.09mA
-743.2mV  16.78mA    32.95mA    23.16mA
-695.5mV  13.07mA    19.3mA     18.31mA
-600mV    7.437mA    7.455mA    10.16mA
-361.4mV  957.4uA    1.155mA    810.6uA
2.98V     -19.47mA   -17.41mA   -18.73mA
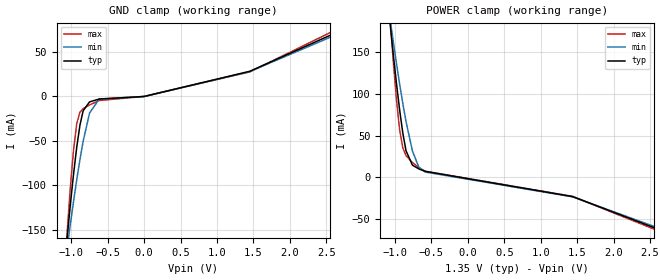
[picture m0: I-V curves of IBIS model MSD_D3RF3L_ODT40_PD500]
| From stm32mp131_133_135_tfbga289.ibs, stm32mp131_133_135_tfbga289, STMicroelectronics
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[Model] MSD_D3RF3L_ODT40_PD500
Model_type   Input
C_comp 2.347pF   2.308pF   2.399pF
Vinh = 810.000mV
Vinl = 540.000mV
[Receiver Thresholds]
Vth   =  0.675V
Vth_min  =  0.6615V
Vth_max  =  0.6885V
Vinh_ac  =  0.160V
Vinh_dc  =  0.090V
Vinl_ac  = -0.160V
Vinl_dc  = -0.090V
Tslew_ac =  5.000ns |Not specified, so set to high value
[Temperature Range]   25.000   125.000   -40.000
[Voltage Range]   1.350V   1.283V   1.450V
[GND Clamp Reference]   0.00V   0.00V   0.00V
[POWER Clamp Reference]   1.350V   1.283V   1.450V
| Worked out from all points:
|   GND clamp passes 1 mA (typ) near -0.46 V on its own axis
|   POWER clamp passes 1 mA (typ) near -0.14 V on its own axis
[GND Clamp]
-1.318V   -415.6mA   -341.5mA   -533.6mA
-1.055V   -159.4mA   -170.6mA   -153.5mA
-1.011V   -121.8mA   -143.8mA   -102.8mA
-966.7mV  -87.28mA   -118mA     -59.97mA
-922.7mV  -56.84mA   -93.51mA   -30.34mA
-878.8mV  -32.17mA   -70.8mA    -17.67mA
-834.9mV  -16.02mA   -50.21mA   -13.7mA
-747mV    -6.076mA   -18.6mA    -9.55mA
-615.1mV  -2.882mA   -2.866mA   -4.55mA
200nV     3.828nA    3.609nA    4.011nA
1.45V     28.28mA    27.98mA    27.61mA
2.68V     73.41mA    70.93mA    76.89mA
[Power Clamp]
-1.33V    441mA      363.6mA    566.1mA
-1.067V   185.1mA    190.3mA    192.6mA
-1.023V   147.9mA    163mA      140.3mA
-978.8mV  112.9mA    136.8mA    93.52mA
-934.9mV  80.8mA     111.8mA    56.78mA
-890.9mV  52.91mA    88.35mA    35.32mA
-847mV    31.84mA    66.79mA    25.99mA
-759.1mV  14.68mA    31.6mA     17.81mA
-671.2mV  10.16mA    12.23mA    11.91mA
-583.3mV  7.211mA    6.431mA    7.436mA
1.438V    -22.88mA   -23.27mA   -22.63mA
2.668V    -63.82mA   -62.07mA   -65.8mA
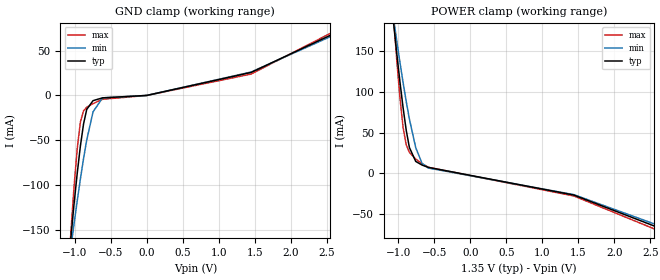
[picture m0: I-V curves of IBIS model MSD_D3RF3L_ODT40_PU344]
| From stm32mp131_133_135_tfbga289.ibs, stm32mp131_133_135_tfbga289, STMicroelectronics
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[Model] MSD_D3RF3L_ODT40_PU344
Model_type   Input
C_comp 2.275pF   2.235pF   2.326pF
Vinh = 810.000mV
Vinl = 540.000mV
[Receiver Thresholds]
Vth   =  0.675V
Vth_min  =  0.6615V
Vth_max  =  0.6885V
Vinh_ac  =  0.160V
Vinh_dc  =  0.090V
Vinl_ac  = -0.160V
Vinl_dc  = -0.090V
Tslew_ac =  5.000ns |Not specified, so set to high value
[Temperature Range]   25.000   125.000   -40.000
[Voltage Range]   1.350V   1.283V   1.450V
[GND Clamp Reference]   0.00V   0.00V   0.00V
[POWER Clamp Reference]   1.350V   1.283V   1.450V
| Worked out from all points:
|   GND clamp passes 1 mA (typ) near -0.47 V on its own axis
|   POWER clamp passes 1 mA (typ) near -0.14 V on its own axis
[GND Clamp]
-1.318V   -414.8mA   -340.7mA   -532.6mA
-1.055V   -158.8mA   -170.1mA   -152.7mA
-1.011V   -121.2mA   -143.3mA   -102.1mA
-966.7mV  -86.84mA   -117.6mA   -59.33mA
-922.7mV  -56.43mA   -93.16mA   -29.74mA
-878.8mV  -31.8mA    -70.47mA   -17.13mA
-834.9mV  -15.69mA   -49.89mA   -13.21mA
-747mV    -5.818mA   -18.35mA   -9.154mA
-615.1mV  -2.716mA   -2.714mA   -4.288mA
200nV     3.408nA    3.271nA    3.439nA
1.45V     25.65mA    26.1mA     23.83mA
2.68V     71.9mA     70.12mA    74.56mA
[Power Clamp]
-1.33V    440.5mA    363.1mA    565.2mA
-1.067V   184.7mA    190mA      191.9mA
-1.023V   147.5mA    162.8mA    139.7mA
-978.8mV  112.6mA    136.5mA    93.02mA
-934.9mV  80.56mA    111.5mA    56.28mA
-890.9mV  52.62mA    88.1mA     34.85mA
-847mV    31.58mA    66.58mA    25.57mA
-759.1mV  14.48mA    31.4mA     17.47mA
-671.2mV  10.01mA    12.09mA    11.66mA
-583.3mV  7.121mA    6.324mA    7.261mA
1.438V    -26.84mA   -26.33mA   -27.97mA
2.668V    -68.73mA   -65.92mA   -72.51mA
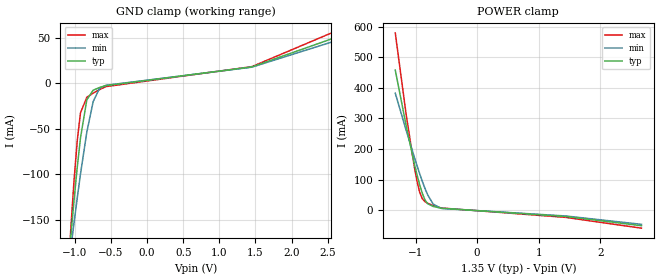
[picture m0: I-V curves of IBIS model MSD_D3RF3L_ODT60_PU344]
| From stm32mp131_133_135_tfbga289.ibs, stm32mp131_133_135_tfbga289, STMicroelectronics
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[Model] MSD_D3RF3L_ODT60_PU344
Model_type   Input
C_comp 2.291pF   2.241pF   2.359pF
Vinh = 810.000mV
Vinl = 540.000mV
[Receiver Thresholds]
Vth   =  0.675V
Vth_min  =  0.6615V
Vth_max  =  0.6885V
Vinh_ac  =  0.160V
Vinh_dc  =  0.090V
Vinl_ac  = -0.160V
Vinl_dc  = -0.090V
Tslew_ac =  5.000ns |Not specified, so set to high value
[Temperature Range]   25.000   125.000   -40.000
[Voltage Range]   1.350V   1.283V   1.450V
[GND Clamp Reference]   0.00V   0.00V   0.00V
[POWER Clamp Reference]   1.350V   1.283V   1.450V
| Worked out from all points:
|   GND clamp passes 1 mA (typ) near -0.46 V on its own axis
|   POWER clamp passes 1 mA (typ) near -0.18 V on its own axis
[GND Clamp]
-1.318V   -428.9mA   -355.9mA   -543.9mA
-1.098V   -208.3mA   -209mA     -215.8mA
-1.055V   -167mA     -180.5mA   -157.9mA
-1.011V   -127.9mA   -152.7mA   -106.1mA
-966.7mV  -91.74mA   -125.7mA   -62.63mA
-922.7mV  -60.22mA   -99.86mA   -32.65mA
-834.9mV  -18.25mA   -53.73mA   -15.52mA
-747mV    -7.662mA   -20.28mA   -10.93mA
-659.1mV  -4.75mA    -5.63mA    -7.02mA
-571.2mV  -2.658mA   -2.292mA   -3.754mA
1.45V     17.86mA    17.6mA     18.18mA
2.68V     52.16mA    48.29mA    59.45mA
[Power Clamp]
-1.33V    458.1mA    382.5mA    579.4mA
-1.155V   278.7mA    262.5mA    315.6mA
-1.023V   154.1mA    175.3mA    144.7mA
-978.8mV  117.4mA    147.3mA    97.2mA
-934.9mV  84.16mA    120.3mA    59.81mA
-890.9mV  55.42mA    94.7mA     37.84mA
-847mV    33.71mA    71.14mA    28.06mA
-803mV    21.24mA    50.29mA    22.99mA
-715.1mV  12.58mA    20.38mA    15.61mA
-583.3mV  6.772mA    6.042mA    7.44mA
1.438V    -20.28mA   -18.58mA   -23.21mA
2.668V    -50.35mA   -45.91mA   -58.4mA
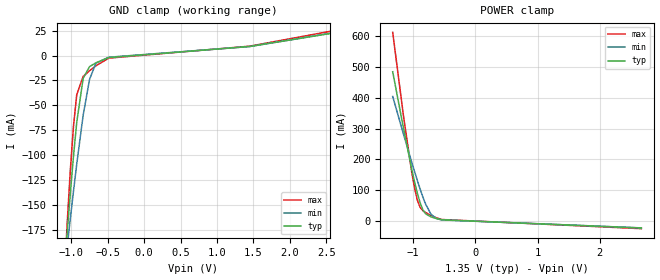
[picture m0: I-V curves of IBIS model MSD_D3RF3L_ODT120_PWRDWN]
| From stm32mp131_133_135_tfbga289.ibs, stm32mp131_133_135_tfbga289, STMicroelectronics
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[Model] MSD_D3RF3L_ODT120_PWRDWN
Model_type   Input
C_comp 2.530pF   2.449pF   2.623pF
Vinh = 810.000mV
Vinl = 540.000mV
[Model Spec]
Vinh   810.000mV   777.000mV   860.000mV
Vinl   540.000mV   507.000mV   590.000mV
[Receiver Thresholds]
Vth   =  0.675V
Vth_min  =  0.6615V
Vth_max  =  0.6885V
Vinh_ac  =  0.160V
Vinh_dc  =  0.090V
Vinl_ac  = -0.160V
Vinl_dc  = -0.090V
Tslew_ac =  5.000ns |Not specified, so set to high value
[Temperature Range]   25.000   125.000   -40.000
[Voltage Range]   1.350V   1.283V   1.450V
[GND Clamp Reference]   0.00V   0.00V   0.00V
[POWER Clamp Reference]   1.350V   1.283V   1.450V
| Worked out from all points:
|   GND clamp passes 1 mA (typ) near -0.42 V on its own axis
|   POWER clamp passes 1 mA (typ) near -0.31 V on its own axis
[GND Clamp]
-1.318V   -448.1mA   -372.7mA   -567.1mA
-1.098V   -222.6mA   -222.2mA   -231.3mA
-1.055V   -179.8mA   -192.9mA   -170.5mA
-1.011V   -138.9mA   -164.2mA   -115.8mA
-966.7mV  -100.7mA   -136.1mA   -70.38mA
-922.7mV  -67.19mA   -109.1mA   -39.41mA
-834.9mV  -22.92mA   -60.08mA   -21.01mA
-747mV    -11.17mA   -23.9mA    -15.29mA
-659.1mV  -7.287mA   -7.691mA   -10.29mA
-483.3mV  -2.017mA   -1.703mA   -2.627mA
1.45V     9.069mA    9.071mA    9.417mA
2.68V     23.65mA    23.86mA    26.05mA
[Power Clamp]
-1.33V    483.3mA    403.5mA    610.5mA
-1.155V   299.2mA    280.6mA    338.1mA
-1.023V   167.8mA    190.6mA    157.7mA
-978.8mV  127.9mA    161.4mA    108.3mA
-934.9mV  91.94mA    132.9mA    69.42mA
-890.9mV  61.36mA    105.6mA    46.12mA
-847mV    38.37mA    79.95mA    35.12mA
-803mV    24.92mA    56.93mA    28.92mA
-715.1mV  14.69mA    23.36mA    19.51mA
-627.3mV  9.201mA    9.328mA    11.89mA
-539.4mV  5.152mA    4.84mA     6.138mA
2.668V    -21.15mA   -20.87mA   -23.36mA
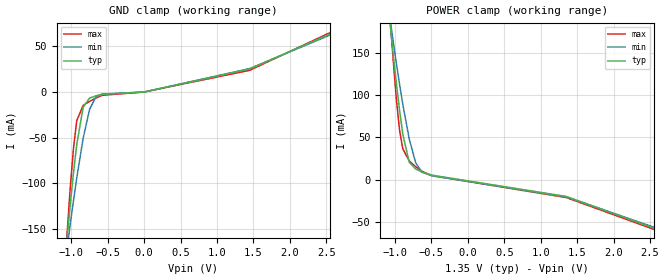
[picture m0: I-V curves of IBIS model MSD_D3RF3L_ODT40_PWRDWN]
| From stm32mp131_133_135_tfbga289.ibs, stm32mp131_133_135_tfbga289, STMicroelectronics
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[Model] MSD_D3RF3L_ODT40_PWRDWN
Model_type   Input
C_comp 2.509pF   2.467pF   2.564pF
Vinh = 810.000mV
Vinl = 540.000mV
[Model Spec]
Vinh   810.000mV   777.000mV   860.000mV
Vinl   540.000mV   507.000mV   590.000mV
[Receiver Thresholds]
Vth   =  0.675V
Vth_min  =  0.6615V
Vth_max  =  0.6885V
Vinh_ac  =  0.160V
Vinh_dc  =  0.090V
Vinl_ac  = -0.160V
Vinl_dc  = -0.090V
Tslew_ac =  5.000ns |Not specified, so set to high value
[Temperature Range]   25.000   125.000   -40.000
[Voltage Range]   1.350V   1.283V   1.450V
[GND Clamp Reference]   0.00V   0.00V   0.00V
[POWER Clamp Reference]   1.350V   1.283V   1.450V
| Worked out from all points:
|   GND clamp passes 1 mA (typ) near -0.45 V on its own axis
|   POWER clamp passes 1 mA (typ) near -0.15 V on its own axis
[GND Clamp]
-1.318V   -417.1mA   -342.8mA   -535.6mA
-1.055V   -160.4mA   -171.5mA   -154.9mA
-1.011V   -122.8mA   -144.6mA   -104.1mA
-966.7mV  -88.16mA   -118.8mA   -61.12mA
-922.7mV  -57.63mA   -94.23mA   -31.44mA
-834.9mV  -16.71mA   -50.78mA   -14.6mA
-747mV    -6.626mA   -19.06mA   -10.27mA
-659.1mV  -4.14mA    -5.18mA    -6.61mA
-571.2mV  -2.434mA   -2.258mA   -3.598mA
200nV     3.413nA    3.285nA    3.464nA
1.45V     25.37mA    25.7mA     23.83mA
2.68V     68.1mA     66.81mA    69.97mA
[Power Clamp]
-1.33V    442.7mA    365.2mA    568.3mA
-1.067V   186.3mA    191.4mA    194mA
-1.023V   149mA      164.1mA    141.7mA
-978.8mV  113.9mA    137.7mA    94.8mA
-934.9mV  81.74mA    112.7mA    57.95mA
-890.9mV  53.76mA    89.11mA    36.38mA
-803mV    20.55mA    48.25mA    22.19mA
-715.1mV  12.58mA    20.14mA    15.35mA
-627.3mV  8.939mA    8.723mA    9.956mA
-495.5mV  5.328mA    4.647mA    4.764mA
1.35V     -19.96mA   -20.38mA   -21.21mA
2.668V    -61.12mA   -59.8mA    -62.59mA
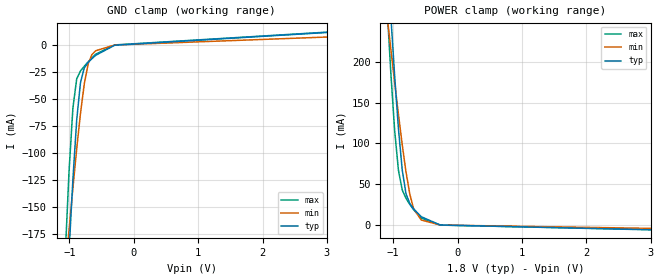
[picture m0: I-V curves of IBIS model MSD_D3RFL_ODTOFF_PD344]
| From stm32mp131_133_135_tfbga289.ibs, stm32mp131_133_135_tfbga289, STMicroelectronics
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[Model] MSD_D3RFL_ODTOFF_PD344
Model_type   Input
C_comp 2.290pF   2.231pF   2.434pF
Vinh = 1.440V
Vinl = 360.000mV
[Temperature Range]   25.000   125.000   -40.000
[Voltage Range]   1.800V   1.650V   1.950V
[GND Clamp Reference]   0.00V   0.00V   0.00V
[POWER Clamp Reference]   1.800V   1.650V   1.950V
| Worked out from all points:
|   GND clamp passes 1 mA (typ) near -0.35 V on its own axis
|   POWER clamp passes 1 mA (typ) near -0.35 V on its own axis
[GND Clamp]
-1.773V   -1.214A    -712mA     -1.313A
-1.064V   -263.5mA   -210.7mA   -193.6mA
-1.005V   -190.9mA   -171mA     -116.6mA
-945.5mV  -124.5mA   -132.7mA   -58.48mA
-886.4mV  -69.52mA   -96.31mA   -31.46mA
-827.3mV  -34.72mA   -63.27mA   -24.15mA
-768.2mV  -21.3mA    -35.99mA   -19.79mA
-709.1mV  -16.3mA    -17.76mA   -15.8mA
-650mV    -12.79mA   -9.043mA   -12.05mA
-590.9mV  -9.653mA   -5.444mA   -8.626mA
-295.4mV  -347.5uA   -143.8uA   -73.98uA
3.545V    13.41mA    8.464mA    13.72mA
[Power Clamp]
-1.745V   1.22A      725mA      1.303A
-1.095V   333.2mA    256.8mA    267.8mA
-1.036V   256.4mA    215.7mA    186.2mA
-977.3mV  183.4mA    175.2mA    116.5mA
-918.2mV  118.3mA    135.8mA    67.39mA
-859.1mV  67.67mA    98.46mA    43.15mA
-800mV    38.28mA    64.86mA    32.79mA
-740.9mV  26.4mA     37.79mA    25.34mA
-681.8mV  19.91mA    19.99mA    18.86mA
-563.6mV  10.26mA    6.254mA    8.477mA
-268.2mV  146uA      86.59uA    27.73uA
3.573V    -6.803mA   -4.694mA   -6.328mA
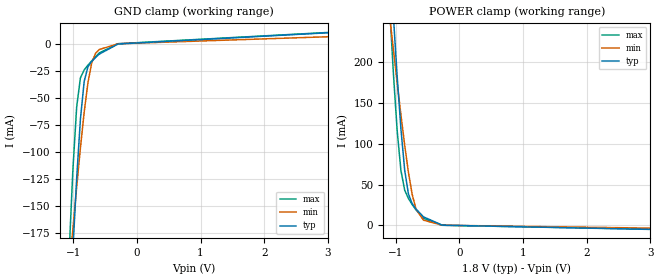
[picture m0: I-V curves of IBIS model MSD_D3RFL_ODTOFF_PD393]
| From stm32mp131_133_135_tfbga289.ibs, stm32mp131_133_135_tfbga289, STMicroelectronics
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[Model] MSD_D3RFL_ODTOFF_PD393
Model_type   Input
C_comp 2.320pF   2.260pF   2.465pF
Vinh = 1.440V
Vinl = 360.000mV
[Model Spec]
Vinh   1.440V   1.365V   1.515V
Vinl   360.000mV   285.000mV   435.000mV
[Temperature Range]   25.000   125.000   -40.000
[Voltage Range]   1.800V   1.650V   1.950V
[GND Clamp Reference]   0.00V   0.00V   0.00V
[POWER Clamp Reference]   1.800V   1.650V   1.950V
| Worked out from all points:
|   GND clamp passes 1 mA (typ) near -0.35 V on its own axis
|   POWER clamp passes 1 mA (typ) near -0.35 V on its own axis
[GND Clamp]
-1.773V   -1.214A    -712.3mA   -1.313A
-1.064V   -263.7mA   -210.9mA   -193.8mA
-1.005V   -191.2mA   -171.3mA   -116.9mA
-945.5mV  -124.7mA   -132.8mA   -58.68mA
-886.4mV  -69.71mA   -96.42mA   -31.65mA
-827.3mV  -34.9mA    -63.37mA   -24.32mA
-768.2mV  -21.45mA   -36.09mA   -19.94mA
-709.1mV  -16.43mA   -17.83mA   -15.92mA
-650mV    -12.89mA   -9.101mA   -12.15mA
-590.9mV  -9.736mA   -5.489mA   -8.694mA
-295.4mV  -355uA     -145.9uA   -76.21uA
3.545V    11.74mA    7.41mA     12.01mA
[Power Clamp]
-1.745V   1.221A     725.4mA    1.304A
-1.095V   333.5mA    257mA      268.1mA
-1.036V   256.6mA    215.8mA    186.5mA
-977.3mV  183.6mA    175.3mA    116.7mA
-918.2mV  118.6mA    136mA      67.59mA
-859.1mV  67.87mA    98.59mA    43.32mA
-800mV    38.46mA    64.97mA    32.95mA
-740.9mV  26.55mA    37.89mA    25.47mA
-681.8mV  20.04mA    20.07mA    18.96mA
-563.6mV  10.35mA    6.299mA    8.542mA
-268.2mV  151uA      88.7uA     28.08uA
3.573V    -5.953mA   -4.108mA   -5.536mA
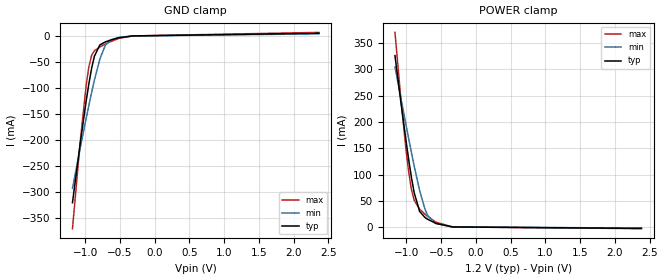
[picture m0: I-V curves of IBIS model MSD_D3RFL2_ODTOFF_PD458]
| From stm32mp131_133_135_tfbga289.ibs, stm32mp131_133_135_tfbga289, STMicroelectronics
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[Model] MSD_D3RFL2_ODTOFF_PD458
Model_type   Input
C_comp 2.401pF   2.315pF   2.526pF
Vinh = 820.000mV
Vinl = 380.000mV
[Model Spec]
Vinh   820.000mV   790.000mV   870.000mV
Vinl   380.000mV   350.000mV   430.000mV
[Temperature Range]   25.000   125.000   -40.000
[Voltage Range]   1.200V   1.140V   1.300V
[GND Clamp Reference]   0.00V   0.00V   0.00V
[POWER Clamp Reference]   1.200V   1.140V   1.300V
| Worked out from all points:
|   GND clamp passes 1 mA (typ) near -0.40 V on its own axis
|   POWER clamp passes 1 mA (typ) near -0.41 V on its own axis
[GND Clamp]
-1.182V   -320.1mA   -292.6mA   -370mA
-1.064V   -199.8mA   -211.1mA   -194.1mA
-984.9mV  -125.1mA   -158.4mA   -94.93mA
-945.5mV  -91.41mA   -133mA     -58.9mA
-906.1mV  -62mA      -108.4mA   -37.33mA
-866.7mV  -39.06mA   -85.06mA   -28.48mA
-787.9mV  -17.41mA   -44.45mA   -21.48mA
-709.1mV  -11.69mA   -17.91mA   -16.04mA
-630.3mV  -8.019mA   -7.633mA   -11.05mA
-512.1mV  -3.588mA   -3.042mA   -4.803mA
-315.1mV  -159.3uA   -225.7uA   -147.9uA
2.364V    5.026mA    3.853mA    6.602mA
[Power Clamp]
-1.164V   326.3mA    304.9mA    370.5mA
-1.085V   244mA      249.5mA    252.5mA
-1.006V   165mA      194.9mA    147.9mA
-966.7mV  128.1mA    168.1mA    104.6mA
-927.3mV  94.42mA    141.8mA    71.4mA
-887.9mV  65.52mA    116.3mA    51mA
-809.1mV  29.69mA    69.42mA    34.22mA
-730.3mV  17.99mA    33.27mA    24.28mA
-690.9mV  14.63mA    21.49mA    19.94mA
-572.7mV  6.826mA    6.704mA    9.191mA
-336.4mV  178.8uA    341.8uA    205.9uA
2.382V    -2.588mA   -2.132mA   -3.077mA
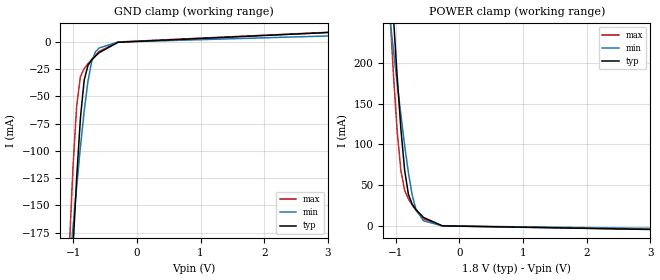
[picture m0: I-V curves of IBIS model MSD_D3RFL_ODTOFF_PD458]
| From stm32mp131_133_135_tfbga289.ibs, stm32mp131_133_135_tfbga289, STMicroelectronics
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[Model] MSD_D3RFL_ODTOFF_PD458
Model_type   Input
C_comp 2.349pF   2.289pF   2.495pF
Vinh = 1.440V
Vinl = 360.000mV
[Temperature Range]   25.000   125.000   -40.000
[Voltage Range]   1.800V   1.650V   1.950V
[GND Clamp Reference]   0.00V   0.00V   0.00V
[POWER Clamp Reference]   1.800V   1.650V   1.950V
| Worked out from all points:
|   GND clamp passes 1 mA (typ) near -0.34 V on its own axis
|   POWER clamp passes 1 mA (typ) near -0.35 V on its own axis
[GND Clamp]
-1.773V   -1.215A    -712.8mA   -1.314A
-1.064V   -264mA     -211.1mA   -194mA
-1.005V   -191.5mA   -171.4mA   -117.1mA
-945.5mV  -124.9mA   -133mA     -58.9mA
-886.4mV  -69.91mA   -96.54mA   -31.83mA
-827.3mV  -35.07mA   -63.48mA   -24.48mA
-768.2mV  -21.6mA    -36.17mA   -20.07mA
-709.1mV  -16.55mA   -17.9mA    -16.04mA
-650mV    -12.99mA   -9.16mA    -12.25mA
-590.9mV  -9.819mA   -5.535mA   -8.772mA
-295.4mV  -361.5uA   -147.9uA   -78.03uA
3.545V    10.05mA    6.348mA    10.29mA
[Power Clamp]
-1.745V   1.221A     725.8mA    1.304A
-1.095V   333.9mA    257.2mA    268.4mA
-1.036V   256.9mA    216mA      186.7mA
-977.3mV  183.9mA    175.5mA    116.9mA
-918.2mV  118.8mA    136.1mA    67.8mA
-859.1mV  68.08mA    98.74mA    43.5mA
-800mV    38.63mA    65.08mA    33.1mA
-740.9mV  26.7mA     37.98mA    25.6mA
-681.8mV  20.16mA    20.15mA    19.07mA
-563.6mV  10.43mA    6.349mA    8.606mA
-268.2mV  156uA      92.36uA    29.34uA
3.573V    -5.104mA   -3.521mA   -4.745mA
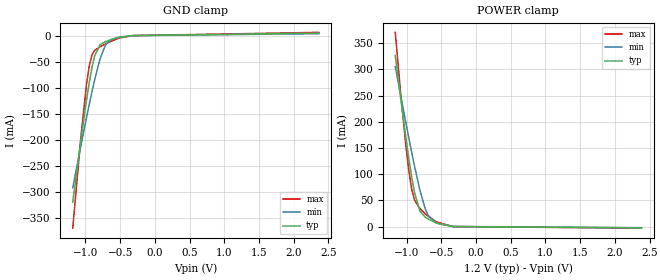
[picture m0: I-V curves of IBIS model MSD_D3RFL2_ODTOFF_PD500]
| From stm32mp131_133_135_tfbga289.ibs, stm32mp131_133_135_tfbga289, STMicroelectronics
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[Model] MSD_D3RFL2_ODTOFF_PD500
Model_type   Input
C_comp 2.418pF   2.333pF   2.542pF
Vinh = 820.000mV
Vinl = 380.000mV
[Temperature Range]   25.000   125.000   -40.000
[Voltage Range]   1.200V   1.140V   1.300V
[GND Clamp Reference]   0.00V   0.00V   0.00V
[POWER Clamp Reference]   1.200V   1.140V   1.300V
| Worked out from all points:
|   GND clamp passes 1 mA (typ) near -0.40 V on its own axis
|   POWER clamp passes 1 mA (typ) near -0.41 V on its own axis
[GND Clamp]
-1.182V   -320.2mA   -292.6mA   -370.2mA
-1.064V   -199.9mA   -211.1mA   -194.1mA
-984.9mV  -125.2mA   -158.5mA   -95.04mA
-945.5mV  -91.49mA   -133mA     -59.01mA
-906.1mV  -62.07mA   -108.5mA   -37.43mA
-866.7mV  -39.13mA   -85.12mA   -28.57mA
-787.9mV  -17.47mA   -44.49mA   -21.56mA
-709.1mV  -11.74mA   -17.95mA   -16.1mA
-630.3mV  -8.051mA   -7.659mA   -11.1mA
-512.1mV  -3.605mA   -3.056mA   -4.826mA
-315.1mV  -160.6uA   -227.1uA   -149.8uA
2.364V    4.611mA    3.534mA    6.049mA
[Power Clamp]
-1.164V   326.4mA    305.1mA    370.6mA
-1.085V   244.1mA    249.6mA    252.6mA
-1.006V   165.1mA    195mA      148.1mA
-966.7mV  128.2mA    168.2mA    104.8mA
-927.3mV  94.5mA     141.8mA    71.51mA
-887.9mV  65.61mA    116.3mA    51.1mA
-809.1mV  29.75mA    69.49mA    34.31mA
-730.3mV  18.05mA    33.32mA    24.35mA
-690.9mV  14.67mA    21.54mA    20mA
-572.7mV  6.859mA    6.73mA     9.23mA
-336.4mV  180uA      346.7uA    210.7uA
2.382V    -2.372mA   -1.954mA   -2.821mA
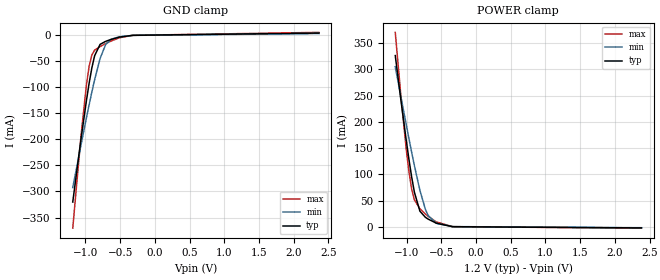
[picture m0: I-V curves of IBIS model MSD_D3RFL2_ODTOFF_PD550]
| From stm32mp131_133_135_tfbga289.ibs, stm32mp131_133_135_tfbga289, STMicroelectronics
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[Model] MSD_D3RFL2_ODTOFF_PD550
Model_type   Input
C_comp 2.431pF   2.347pF   2.556pF
Vinh = 820.000mV
Vinl = 380.000mV
[Temperature Range]   25.000   125.000   -40.000
[Voltage Range]   1.200V   1.140V   1.300V
[GND Clamp Reference]   0.00V   0.00V   0.00V
[POWER Clamp Reference]   1.200V   1.140V   1.300V
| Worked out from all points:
|   GND clamp passes 1 mA (typ) near -0.40 V on its own axis
|   POWER clamp passes 1 mA (typ) near -0.41 V on its own axis
[GND Clamp]
-1.182V   -320.3mA   -292.7mA   -370.4mA
-1.064V   -200mA     -211.3mA   -194.3mA
-984.9mV  -125.3mA   -158.6mA   -95.16mA
-945.5mV  -91.56mA   -133.1mA   -59.11mA
-906.1mV  -62.14mA   -108.5mA   -37.52mA
-866.7mV  -39.2mA    -85.17mA   -28.67mA
-787.9mV  -17.52mA   -44.53mA   -21.63mA
-709.1mV  -11.78mA   -17.99mA   -16.16mA
-630.3mV  -8.084mA   -7.685mA   -11.14mA
-512.1mV  -3.622mA   -3.071mA   -4.849mA
-315.1mV  -161.7uA   -228.2uA   -151.7uA
2.364V    4.189mA    3.207mA    5.502mA
[Power Clamp]
-1.164V   326.5mA    305.2mA    370.8mA
-1.085V   244.2mA    249.7mA    252.8mA
-1.006V   165.2mA    195.1mA    148.2mA
-966.7mV  128.3mA    168.3mA    104.9mA
-927.3mV  94.59mA    142mA      71.62mA
-887.9mV  65.69mA    116.5mA    51.2mA
-809.1mV  29.82mA    69.56mA    34.4mA
-730.3mV  18.1mA     33.37mA    24.42mA
-690.9mV  14.72mA    21.6mA     20.06mA
-572.7mV  6.886mA    6.765mA    9.259mA
-336.4mV  184uA      353.9uA    211.8uA
2.382V    -2.157mA   -1.777mA   -2.564mA
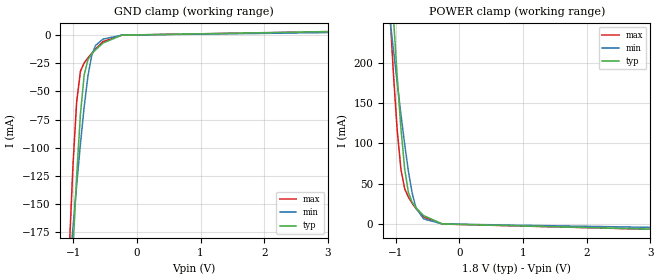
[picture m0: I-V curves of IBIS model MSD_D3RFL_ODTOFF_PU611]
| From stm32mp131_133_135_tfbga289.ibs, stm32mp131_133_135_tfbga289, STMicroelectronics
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[Model] MSD_D3RFL_ODTOFF_PU611
Model_type   Input
C_comp 2.398pF   2.336pF   2.545pF
Vinh = 1.440V
Vinl = 360.000mV
[Temperature Range]   25.000   125.000   -40.000
[Voltage Range]   1.800V   1.650V   1.950V
[GND Clamp Reference]   0.00V   0.00V   0.00V
[POWER Clamp Reference]   1.800V   1.650V   1.950V
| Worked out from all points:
|   GND clamp passes 1 mA (typ) near -0.34 V on its own axis
|   POWER clamp passes 1 mA (typ) near -0.35 V on its own axis
[GND Clamp]
-1.773V   -1.216A    -713.2mA   -1.315A
-1.064V   -264.4mA   -211.2mA   -194.4mA
-1.005V   -191.8mA   -171.6mA   -117.4mA
-945.5mV  -125.2mA   -133.1mA   -59.2mA
-886.4mV  -70.17mA   -96.67mA   -32.1mA
-827.3mV  -35.32mA   -63.6mA    -24.71mA
-768.2mV  -21.81mA   -36.28mA   -20.28mA
-709.1mV  -16.73mA   -17.99mA   -16.21mA
-650mV    -13.15mA   -9.228mA   -12.38mA
-531.8mV  -7.061mA   -3.589mA   -5.783mA
-236.4mV  -77.02uA   -36.01uA   -7.017uA
3.545V    3.684mA    2.595mA    3.422mA
[Power Clamp]
-1.745V   1.222A     726.5mA    1.305A
-1.095V   334.3mA    257.6mA    268.7mA
-1.036V   257.3mA    216.3mA    187.1mA
-977.3mV  184.2mA    175.8mA    117.3mA
-918.2mV  119.2mA    136.3mA    68.12mA
-859.1mV  68.39mA    98.96mA    43.78mA
-800mV    38.91mA    65.27mA    33.35mA
-740.9mV  26.95mA    38.15mA    25.81mA
-681.8mV  20.37mA    20.28mA    19.24mA
-563.6mV  10.56mA    6.44mA     8.709mA
-268.2mV  166.8uA    102.5uA    33.14uA
3.573V    -7.462mA   -4.822mA   -7.619mA
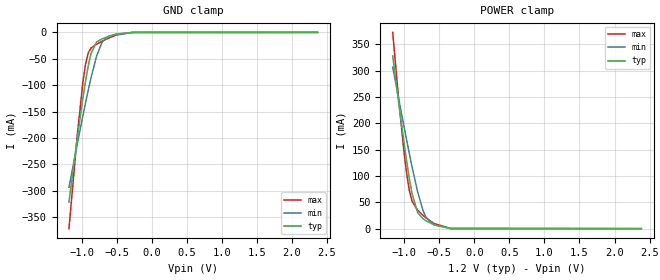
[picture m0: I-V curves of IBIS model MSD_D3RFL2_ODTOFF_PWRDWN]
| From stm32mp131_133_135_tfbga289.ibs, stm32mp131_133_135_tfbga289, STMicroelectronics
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[Model] MSD_D3RFL2_ODTOFF_PWRDWN
Model_type   Input
C_comp 2.581pF   2.493pF   2.708pF
Vinh = 820.000mV
Vinl = 380.000mV
[Model Spec]
Vinh   820.000mV   790.000mV   870.000mV
Vinl   380.000mV   350.000mV   430.000mV
[Temperature Range]   25.000   125.000   -40.000
[Voltage Range]   1.200V   1.140V   1.300V
[GND Clamp Reference]   0.00V   0.00V   0.00V
[POWER Clamp Reference]   1.200V   1.140V   1.300V
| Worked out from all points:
|   GND clamp passes 1 mA (typ) near -0.40 V on its own axis
|   POWER clamp passes 1 mA (typ) near -0.41 V on its own axis
[GND Clamp]
-1.182V   -321.5mA   -293.7mA   -371.9mA
-1.064V   -200.9mA   -212mA     -195.6mA
-984.9mV  -126.1mA   -159.2mA   -96.27mA
-945.5mV  -92.35mA   -133.7mA   -60.14mA
-906.1mV  -62.87mA   -109.1mA   -38.48mA
-866.7mV  -39.86mA   -85.71mA   -29.54mA
-787.9mV  -18.07mA   -44.97mA   -22.35mA
-709.1mV  -12.21mA   -18.33mA   -16.73mA
-630.3mV  -8.407mA   -7.946mA   -11.57mA
-512.1mV  -3.797mA   -3.213mA   -5.085mA
-275.8mV  -58.44uA   -104.1uA   -45.08uA
2.364V    30.51nA    485nA      3.359nA
[Power Clamp]
-1.164V   327.9mA    306.5mA    372.4mA
-1.085V   245.4mA    250.9mA    254.2mA
-1.006V   166.2mA    196.1mA    149.5mA
-966.7mV  129.3mA    169.2mA    106.1mA
-927.3mV  95.49mA    142.8mA    72.71mA
-887.9mV  66.51mA    117.2mA    52.19mA
-809.1mV  30.5mA     70.2mA     35.22mA
-730.3mV  18.64mA    33.89mA    25.07mA
-690.9mV  15.2mA     22.05mA    20.63mA
-572.7mV  7.181mA    7.055mA    9.615mA
-336.4mV  216.5uA    406.1uA    244.2uA
2.382V    -25.08nA   -515.6nA   -2.615nA
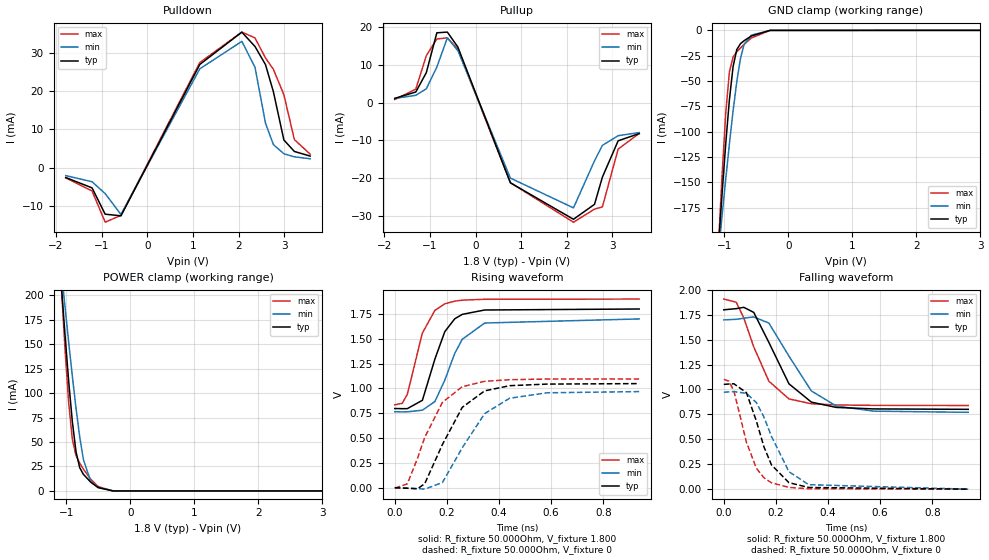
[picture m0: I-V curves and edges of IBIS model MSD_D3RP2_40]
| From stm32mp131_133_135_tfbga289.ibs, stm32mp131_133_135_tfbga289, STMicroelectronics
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[Model] MSD_D3RP2_40
Model_type   I/O
C_comp 2.221pF   2.142pF   2.337pF
Vinh = 1.150V
Vinl = 650.000mV
Vmeas = 900.000mV
Vref = 900.000mV
[Model Spec]
Vinh   1.150V   1.100V   1.200V
Vinl   650.000mV   600.000mV   700.000mV
Vmeas   900.000mV   850.000mV   950.000mV
Vref   900.000mV   850.000mV   950.000mV
[Temperature Range]   25.000   125.000   -40.000
[Voltage Range]   1.800V   1.700V   1.900V
[GND Clamp Reference]   0.00V   0.00V   0.00V
[Pulldown Reference]   0.00V   0.00V   0.00V
[POWER Clamp Reference]   1.800V   1.700V   1.900V
[Pullup Reference]   1.800V   1.700V   1.900V
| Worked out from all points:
|   slope of the pulldown table from 0 to 0.27 V, typ, clamps not added: 37.2 ohm
|   slope of the pullup table from 0 to 0.27 V, typ, clamps not added: 29.4 ohm
|   GND clamp passes 1 mA (typ) near -0.41 V on its own axis
|   POWER clamp passes 1 mA (typ) near -0.41 V on its own axis
|   rising waveform, R_fixture 50.000Ohm, V_fixture 1.800: 20-80 % time 75ps typ, 92.5ps min, 67.7ps max; typ from 0.798 V to 1.8 V
|   rising waveform, R_fixture 50.000Ohm, V_fixture 0: 20-80 % time 120ps typ, 137ps min, 111ps max; typ from 0.001 V to 1.05 V
|   falling waveform, R_fixture 50.000Ohm, V_fixture 1.800: 20-80 % time 115ps typ, 134ps min, 101ps max; typ from 1.8 V to 0.801 V
|   falling waveform, R_fixture 50.000Ohm, V_fixture 0: 20-80 % time 83.5ps typ, 100ps min, 73ps max; typ from 1.05 V to 0 V
[GND Clamp]
-1.785V   -899.6mA   -687.8mA   -1.207A
-1.094V   -214.3mA   -220.6mA   -214.7mA
-1.036V   -161.5mA   -183.4mA   -143mA
-978.8mV  -112mA     -147.1mA   -81.84mA
-921.2mV  -68.38mA   -112.2mA   -40.88mA
-863.6mV  -35.68mA   -79.52mA   -26.12mA
-806.1mV  -18.97mA   -50.56mA   -21.22mA
-748.5mV  -13.2mA    -27.77mA   -17.43mA
-690.9mV  -10.2mA    -13.79mA   -13.86mA
-575.8mV  -5.517mA   -4.735mA   -7.461mA
-287.9mV  -70.53uA   -119uA     -55.71uA
3.57V     33.93nA    572.8nA    3.714nA
[Power Clamp]
-1.77V    876.4mA    686.4mA    1.147A
-1.079V   211mA      225.3mA    210.2mA
-1.021V   159.9mA    188.4mA    145.5mA
-963.6mV  112.3mA    152.2mA    90.31mA
-906.1mV  70.8mA     117.2mA    52.68mA
-848.5mV  39.88mA    84.39mA    36.1mA
-790.9mV  23.74mA    55.21mA    28.44mA
-733.3mV  16.95mA    32.12mA    22.28mA
-618.2mV  8.937mA    9.714mA    11.91mA
-503mV    3.408mA    3.506mA    4.439mA
-272.7mV  29.94uA    100.2uA    29.64uA
3.585V    -51.59nA   -929.3nA   -5.524nA
[Pulldown]
-1.785V   -2.6mA     -2.1mA     -2.7mA
-1.209V   -5.3mA     -3.7mA     -6.1mA
-921.2mV  -12.17mA   -6.8mA     -14.26mA
-575.8mV  -12.6mA    -12.24mA   -12.47mA
1.152V    26.92mA    25.78mA    27.42mA
2.073V    35.36mA    32.95mA    35.37mA
2.361V    31.61mA    26.19mA    33.85mA
2.591V    26.88mA    11.6mA     28.6mA
2.764V    19.8mA     6mA        25.66mA
2.994V    7.2mA      3.6mA      19mA
3.224V    4.2mA      2.8mA      7.3mA
3.57V     3mA        2.3mA      3.5mA
[Pullup]
-1.77V    1.1mA      1.074mA    800uA
-1.309V   2.8mA      1.921mA    3.542mA
-1.079V   7.9mA      3.642mA    12.4mA
-848.5mV  18.43mA    9.365mA    16.8mA
-618.2mV  18.62mA    17.1mA     17.11mA
-387.9mV  14.67mA    13.71mA    14.13mA
763.6mV   -21.21mA   -19.96mA   -21.18mA
2.145V    -30.84mA   -27.83mA   -31.61mA
2.606V    -26.89mA   -15.39mA   -28.16mA
2.779V    -19.7mA    -11.31mA   -27.57mA
3.124V    -10.1mA    -8.753mA   -12.28mA
3.585V    -8.2mA     -7.926mA   -8.174mA
[Ramp]
R_load=50.000Ohm
dV/dt_r   614.400mV/98.000ps  569.759mV/116.000ps  646.950mV/90.000ps
dV/dt_f   614.400mV/99.500ps  569.759mV/117.500ps  646.950mV/88.000ps
[Rising waveform]
R_fixture=50.000Ohm
V_fixture=1.800
V_fixture_min=1.700
V_fixture_max=1.900
0s        798.1mV    765.2mV    835.3mV
29ps      796.6mV    764.4mV    850.9mV
48ps      796.8mV    764.9mV    940.6mV
106ps     880.9mV    781.2mV    1.558V
154ps     1.296V     868.5mV    1.786V
192ps     1.572V     1.084V     1.852V
230ps     1.701V     1.352V     1.879V
259ps     1.746V     1.495V     1.889V
345ps     1.79V      1.659V     1.898V
938ps     1.8V       1.7V       1.9V
[Rising waveform]
R_fixture=50.000Ohm
V_fixture=0
0s        660.7uV    660.4uV    -3.587mV
48ps      -4.649mV   -1.502mV   39mV
87ps      -10.71mV   -7.332mV   294.2mV
115ps     41.78mV    -13.75mV   508.4mV
183ps     436.5mV    53.21mV    860.8mV
259ps     810.1mV    403.1mV    1.018V
345ps     976mV      747mV      1.072V
441ps     1.028V     901.8mV    1.088V
585ps     1.044V     956.4mV    1.095V
938ps     1.049V     968.5mV    1.096V
[Falling waveform]
R_fixture=50.000Ohm
V_fixture=1.800
V_fixture_min=1.700
V_fixture_max=1.900
0s        1.799V     1.698V     1.907V
48ps      1.811V     1.704V     1.875V
77ps      1.824V     1.715V     1.715V
115ps     1.773V     1.728V     1.427V
173ps     1.472V     1.666V     1.083V
250ps     1.057V     1.335V     905.6mV
336ps     873.2mV    985mV      856.3mV
432ps     819.9mV    834mV      844.8mV
575ps     805mV      782.7mV    840.7mV
938ps     800.9mV    770.6mV    839.5mV
[Falling waveform]
R_fixture=50.000Ohm
V_fixture=0
0s        1.051V     972.7mV    1.102V
20ps      1.055V     976mV      1.082V
39ps      1.057V     978.6mV    983.6mV
87ps      967.7mV    961.2mV    471.2mV
125ps     683.5mV    868.5mV    210.4mV
154ps     425.1mV    723.7mV    114.3mV
183ps     243.6mV    529.6mV    63.89mV
250ps     65.1mV     175.6mV    17.65mV
326ps     16.99mV    44.88mV    4.224mV
938ps     10.13uV    17.64uV    6.021uV
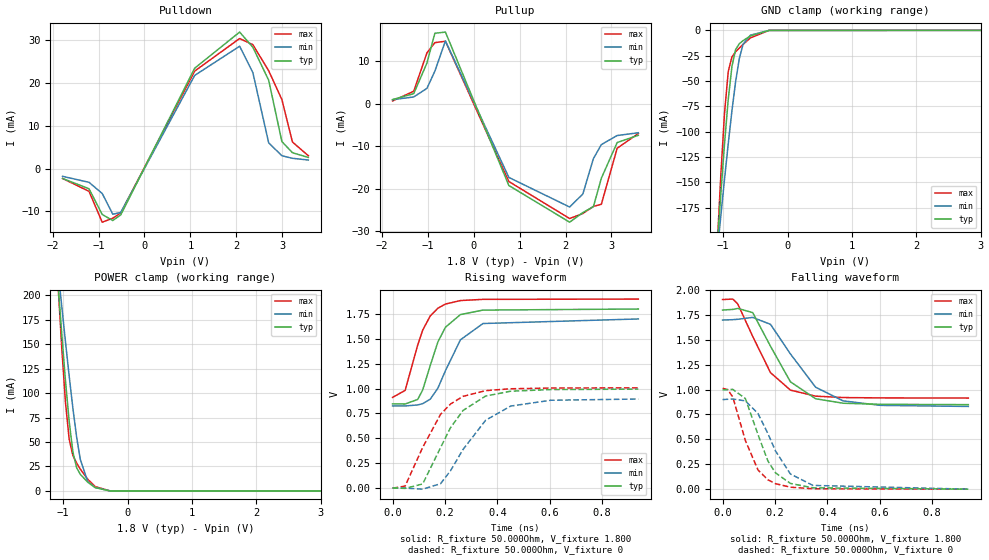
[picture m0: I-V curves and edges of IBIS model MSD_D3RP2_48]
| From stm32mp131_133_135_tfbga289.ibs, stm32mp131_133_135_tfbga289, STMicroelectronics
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[Model] MSD_D3RP2_48
Model_type   I/O
C_comp 2.221pF   2.142pF   2.337pF
Vinh = 1.150V
Vinl = 650.000mV
Vmeas = 900.000mV
Vref = 900.000mV
[Model Spec]
Vinh   1.150V   1.100V   1.200V
Vinl   650.000mV   600.000mV   700.000mV
Vmeas   900.000mV   850.000mV   950.000mV
Vref   900.000mV   850.000mV   950.000mV
[Temperature Range]   25.000   125.000   -40.000
[Voltage Range]   1.800V   1.700V   1.900V
[GND Clamp Reference]   0.00V   0.00V   0.00V
[Pulldown Reference]   0.00V   0.00V   0.00V
[POWER Clamp Reference]   1.800V   1.700V   1.900V
[Pullup Reference]   1.800V   1.700V   1.900V
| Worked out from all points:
|   slope of the pulldown table from 0 to 0.27 V, typ, clamps not added: 41 ohm
|   slope of the pullup table from 0 to 0.27 V, typ, clamps not added: 32.3 ohm
|   GND clamp passes 1 mA (typ) near -0.41 V on its own axis
|   POWER clamp passes 1 mA (typ) near -0.41 V on its own axis
|   rising waveform, R_fixture 50.000Ohm, V_fixture 1.800: 20-80 % time 78.5ps typ, 97.6ps min, 72.7ps max; typ from 0.846 V to 1.8 V
|   rising waveform, R_fixture 50.000Ohm, V_fixture 0: 20-80 % time 127ps typ, 148ps min, 121ps max; typ from 0.001 V to 0.994 V
|   falling waveform, R_fixture 50.000Ohm, V_fixture 1.800: 20-80 % time 121ps typ, 145ps min, 112ps max; typ from 1.8 V to 0.849 V
|   falling waveform, R_fixture 50.000Ohm, V_fixture 0: 20-80 % time 86.4ps typ, 105ps min, 78.9ps max; typ from 0.997 V to 0 V
[GND Clamp]
-1.785V   -899.6mA   -687.8mA   -1.207A
-1.094V   -214.3mA   -220.6mA   -214.7mA
-1.036V   -161.5mA   -183.4mA   -143mA
-978.8mV  -112mA     -147.1mA   -81.84mA
-921.2mV  -68.38mA   -112.2mA   -40.88mA
-863.6mV  -35.68mA   -79.52mA   -26.12mA
-806.1mV  -18.97mA   -50.56mA   -21.22mA
-748.5mV  -13.2mA    -27.77mA   -17.43mA
-690.9mV  -10.2mA    -13.79mA   -13.86mA
-575.8mV  -5.517mA   -4.735mA   -7.461mA
-287.9mV  -70.53uA   -119uA     -55.71uA
3.57V     33.93nA    572.8nA    3.714nA
[Power Clamp]
-1.77V    876.4mA    686.4mA    1.147A
-1.079V   211mA      225.3mA    210.2mA
-1.021V   159.9mA    188.4mA    145.5mA
-963.6mV  112.3mA    152.2mA    90.31mA
-906.1mV  70.8mA     117.2mA    52.68mA
-848.5mV  39.88mA    84.39mA    36.1mA
-790.9mV  23.74mA    55.21mA    28.44mA
-733.3mV  16.95mA    32.12mA    22.28mA
-618.2mV  8.937mA    9.714mA    11.91mA
-503mV    3.408mA    3.506mA    4.439mA
-272.7mV  29.94uA    100.2uA    29.64uA
3.585V    -51.59nA   -929.3nA   -5.524nA
[Pulldown]
-1.785V   -2.3mA     -1.8mA     -2.3mA
-1.209V   -4.7mA     -3.2mA     -5.3mA
-921.2mV  -10.7mA    -5.8mA     -12.5mA
-690.9mV  -12.11mA   -10.64mA   -11.58mA
-518.2mV  -10.81mA   -10.23mA   -10.35mA
1.094V    23.42mA    21.74mA    22.75mA
2.073V    31.84mA    28.54mA    30.34mA
2.361V    28.31mA    22.4mA     28.91mA
2.706V    20.61mA    6mA        22.82mA
2.994V    6.3mA      3mA        16.1mA
3.224V    3.7mA      2.4mA      6.2mA
3.57V     2.6mA      2mA        3mA
[Pullup]
-1.77V    1mA        973.7uA    673.7uA
-1.309V   2.4mA      1.621mA    2.963mA
-1.021V   9.6mA      3.642mA    11.99mA
-848.5mV  16.6mA     7.693mA    14.4mA
-618.2mV  16.88mA    14.81mA    14.73mA
763.6mV   -19.21mA   -17.31mA   -18.27mA
2.088V    -27.84mA   -24.27mA   -26.98mA
2.376V    -25.58mA   -21.21mA   -25.8mA
2.606V    -24.19mA   -12.89mA   -24.13mA
2.779V    -17.5mA    -9.584mA   -23.63mA
3.124V    -9.1mA     -7.453mA   -10.44mA
3.585V    -7.4mA     -6.8mA     -6.974mA
[Ramp]
R_load=50.000Ohm
dV/dt_r   583.740mV/103.500ps  529.829mV/124.000ps  597.780mV/97.500ps
dV/dt_f   583.740mV/104.500ps  529.829mV/126.000ps  597.780mV/95.500ps
[Rising waveform]
R_fixture=50.000Ohm
V_fixture=1.800
V_fixture_min=1.700
V_fixture_max=1.900
0s        845.7mV    824.8mV    911.1mV
48ps      844.5mV    824.5mV    981.3mV
96ps      890.6mV    835.4mV    1.438V
115ps     985.8mV    848mV      1.588V
144ps     1.233V     893.6mV    1.731V
173ps     1.469V     1.004V     1.808V
202ps     1.617V     1.181V     1.85V
259ps     1.744V     1.49V      1.885V
345ps     1.789V     1.654V     1.897V
938ps     1.8V       1.7V       1.9V
[Rising waveform]
R_fixture=50.000Ohm
V_fixture=0
0s        665uV      612.6uV    -2.323mV
48ps      -4.24mV    -1.239mV   19.87mV
115ps     40.58mV    -11.99mV   407.9mV
183ps     405.2mV    42.86mV    740.1mV
221ps     605.7mV    172.7mV    844.2mV
269ps     779.7mV    387.4mV    921.4mV
355ps     924.5mV    680.9mV    978.9mV
451ps     973.4mV    823.8mV    997.8mV
604ps     989.7mV    882.4mV    1.005V
938ps     994.2mV    894.5mV    1.007V
[Falling waveform]
R_fixture=50.000Ohm
V_fixture=1.800
V_fixture_min=1.700
V_fixture_max=1.900
0s        1.799V     1.698V     1.904V
39ps      1.805V     1.702V     1.909V
58ps      1.815V     1.706V     1.86V
115ps     1.773V     1.725V     1.534V
183ps     1.435V     1.655V     1.17V
259ps     1.078V     1.358V     994.7mV
355ps     908.1mV    1.024V     934.1mV
460ps     863mV      886.6mV    920mV
604ps     851.9mV    841.2mV    916.4mV
938ps     848.8mV    830.7mV    914.9mV
[Falling waveform]
R_fixture=50.000Ohm
V_fixture=0
0s        996.6mV    899.5mV    1.013V
20ps      1V         902.7mV    998.6mV
39ps      1.002V     905.3mV    926mV
87ps      910.4mV    886.7mV    488.6mV
135ps     550.1mV    760.3mV    193.5mV
173ps     283.1mV    558.6mV    94.12mV
202ps     163.7mV    383.6mV    55.13mV
259ps     57.39mV    152.4mV    19.7mV
345ps     13.44mV    37.63mV    4.234mV
938ps     12.04uV    27.47uV    -4.294uV
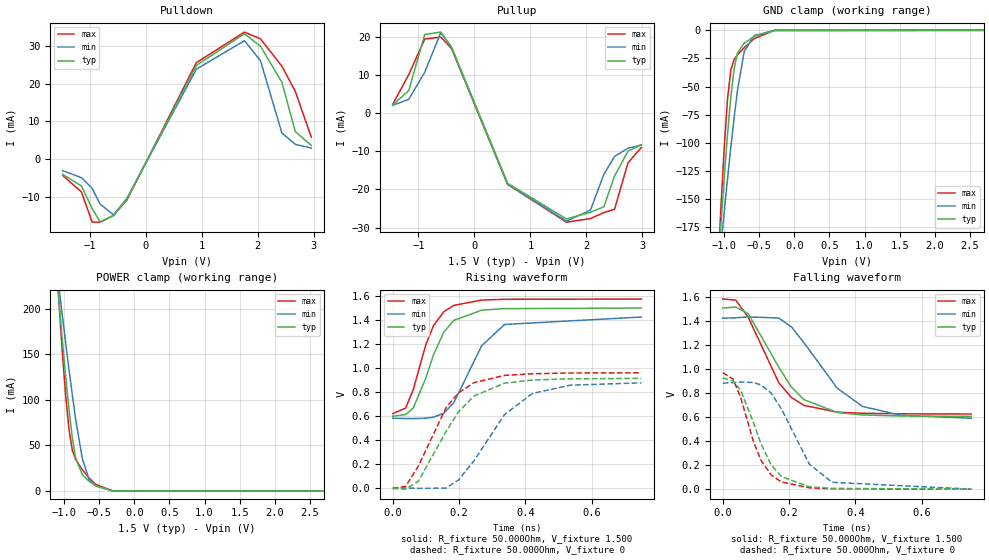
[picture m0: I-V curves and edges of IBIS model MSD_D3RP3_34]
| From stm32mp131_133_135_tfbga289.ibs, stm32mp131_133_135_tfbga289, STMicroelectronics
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[Model] MSD_D3RP3_34
Model_type   I/O
C_comp 2.233pF   2.153pF   2.350pF
Vinh = 925.000mV
Vinl = 575.000mV
Vmeas = 750.000mV
Vref = 750.000mV
[Model Spec]
Vinh   925.000mV   888.000mV   963.000mV
Vinl   575.000mV   538.000mV   613.000mV
Vmeas   750.000mV   713.000mV   788.000mV
Vref   750.000mV   713.000mV   788.000mV
[Temperature Range]   25.000   125.000   -40.000
[Voltage Range]   1.500V   1.425V   1.575V
[GND Clamp Reference]   0.00V   0.00V   0.00V
[Pulldown Reference]   0.00V   0.00V   0.00V
[POWER Clamp Reference]   1.500V   1.425V   1.575V
[Pullup Reference]   1.500V   1.425V   1.575V
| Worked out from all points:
|   slope of the pulldown table from 0 to 0.225 V, typ, clamps not added: 31.5 ohm
|   slope of the pullup table from 0 to 0.225 V, typ, clamps not added: 26.9 ohm
|   GND clamp passes 1 mA (typ) near -0.40 V on its own axis
|   POWER clamp passes 1 mA (typ) near -0.41 V on its own axis
|   rising waveform, R_fixture 50.000Ohm, V_fixture 1.500: 20-80 % time 77ps typ, 93.5ps min, 68.6ps max; typ from 0.597 V to 1.5 V
|   rising waveform, R_fixture 50.000Ohm, V_fixture 0: 20-80 % time 122ps typ, 137ps min, 111ps max; typ from -0.006 V to 0.913 V
|   falling waveform, R_fixture 50.000Ohm, V_fixture 1.500: 20-80 % time 118ps typ, 144ps min, 104ps max; typ from 1.51 V to 0.605 V
|   falling waveform, R_fixture 50.000Ohm, V_fixture 0: 20-80 % time 82.3ps typ, 101ps min, 72.2ps max; typ from 0.925 V to 0 V
[GND Clamp]
-1.48V    -592.8mA   -479.1mA   -761.2mA
-1.098V   -217.8mA   -223.1mA   -219.7mA
-1.05V    -173.8mA   -192.1mA   -159.3mA
-1.002V   -131.7mA   -161.7mA   -105mA
-954.6mV  -92.68mA   -132.2mA   -61.41mA
-906.8mV  -58.93mA   -103.8mA   -35.09mA
-859.1mV  -33.75mA   -77.07mA   -25.6mA
-811.4mV  -19.88mA   -53.01mA   -21.59mA
-715.9mV  -11.39mA   -18.72mA   -15.38mA
-572.7mV  -5.408mA   -4.63mA    -7.309mA
-286.4mV  -67.53uA   -115uA     -52.79uA
2.959V    27.81nA    447.4nA    3.164nA
[Power Clamp]
-1.459V   573.5mA    476.8mA    715.7mA
-1.077V   209.6mA    224.3mA    208.4mA
-1.03V    167.1mA    193.7mA    154.3mA
-981.8mV  126.8mA    163.5mA    105.9mA
-934.1mV  89.99mA    134.1mA    67.88mA
-886.4mV  58.74mA    105.7mA    45.04mA
-838.6mV  36.05mA    79.08mA    34.56mA
-743.2mV  17.84mA    35.43mA    23.27mA
-647.7mV  10.73mA    12.81mA    14.31mA
-552.3mV  5.47mA     5.422mA    7.21mA
-313.6mV  99.22uA    231.1uA    112.6uA
2.98V     -43.92nA   -827nA     -4.18nA
[Pulldown]
-1.48V    -4.1mA     -3.1mA     -4.4mA
-1.145V   -7.2mA     -5mA       -8.8mA
-954.6mV  -13.22mA   -7.8mA     -16.83mA
-811.4mV  -16.77mA   -12.03mA   -16.84mA
-572.7mV  -15.06mA   -14.9mA    -15.03mA
-334.1mV  -10.72mA   -10.48mA   -10.95mA
906.8mV   24.92mA    23.93mA    25.67mA
1.766V    33.35mA    31.49mA    33.79mA
2.052V    30.01mA    26.13mA    31.97mA
2.434V    20.41mA    6.9mA      24.7mA
2.673V    7.3mA      3.9mA      18mA
2.959V    3.6mA      2.9mA      5.8mA
[Pullup]
-1.459V   2.1mA      2.014mA    2.271mA
-1.173V   5.9mA      3.586mA    10.06mA
-886.4mV  20.59mA    10.72mA    19.4mA
-600mV    21.22mA    21.11mA    19.91mA
-409.1mV  17.28mA    17.17mA    16.91mA
593.2mV   -18.4mA    -18.64mA   -18.71mA
1.643V    -27.73mA   -28.33mA   -28.59mA
2.073V    -25.99mA   -25.39mA   -27.64mA
2.311V    -24.56mA   -16.08mA   -26.07mA
2.502V    -16.5mA    -11.34mA   -25.22mA
2.741V    -10mA      -9.229mA   -13.07mA
2.98V     -8.3mA     -8.343mA   -9.029mA
[Ramp]
R_load=50.000Ohm
dV/dt_r   542.520mV/99.500ps  515.429mV/116.500ps  572.730mV/90.000ps
dV/dt_f   542.520mV/100.000ps  515.399mV/124.500ps  572.730mV/89.000ps
[Rising waveform]
R_fixture=50.000Ohm
V_fixture=1.500
V_fixture_min=1.425
V_fixture_max=1.575
0s        596.6mV    580.1mV    618.4mV
39ps      611mV      577.9mV    665.1mV
62ps      666mV      577.3mV    819.5mV
100ps     917.4mV    580.8mV    1.196V
123ps     1.11V      589mV      1.353V
154ps     1.298V     623mV      1.469V
184ps     1.397V     709.4mV    1.522V
268ps     1.482V     1.185V     1.567V
337ps     1.495V     1.363V     1.573V
749ps     1.5V       1.425V     1.575V
[Rising waveform]
R_fixture=50.000Ohm
V_fixture=0
0s        -5.68mV    835.2uV    -5.835mV
39ps      -11.93mV   -1.153mV   10.89mV
77ps      53.06mV    -5.882mV   179.6mV
161ps     470.2mV    -2.222mV   669.8mV
199ps     636.3mV    66.4mV     793.4mV
245ps     766.2mV    225.9mV    877.6mV
337ps     872.7mV    611.2mV    937.9mV
421ps     899.3mV    787.2mV    951.7mV
536ps     909.1mV    856.2mV    957.8mV
749ps     912.9mV    875.8mV    959.5mV
[Falling waveform]
R_fixture=50.000Ohm
V_fixture=1.500
V_fixture_min=1.425
V_fixture_max=1.575
0s        1.507V     1.423V     1.582V
39ps      1.516V     1.426V     1.574V
77ps      1.46V      1.434V     1.43V
169ps     1.015V     1.424V     885.6mV
207ps     849.7mV    1.35V      762.8mV
245ps     744.6mV    1.218V     697.1mV
345ps     638.3mV    840.7mV    640.7mV
421ps     617.8mV    688.6mV    631.7mV
536ps     609.1mV    615.2mV    627.1mV
749ps     605.3mV    590.6mV    625.6mV
[Falling waveform]
R_fixture=50.000Ohm
V_fixture=0
0s        925.2mV    882.1mV    968.7mV
31ps      900.7mV    887.2mV    917.5mV
54ps      823mV      891mV      763.8mV
92ps      559.5mV    887.9mV    401.7mV
115ps     379mV      868mV      242mV
146ps     202.6mV    799.8mV    118.9mV
177ps     104.7mV    667mV      59.79mV
261ps     19.89mV    207.9mV    11.03mV
330ps     6.358mV    56.87mV    2.96mV
749ps     16.72uV    262.5uV    10.11uV
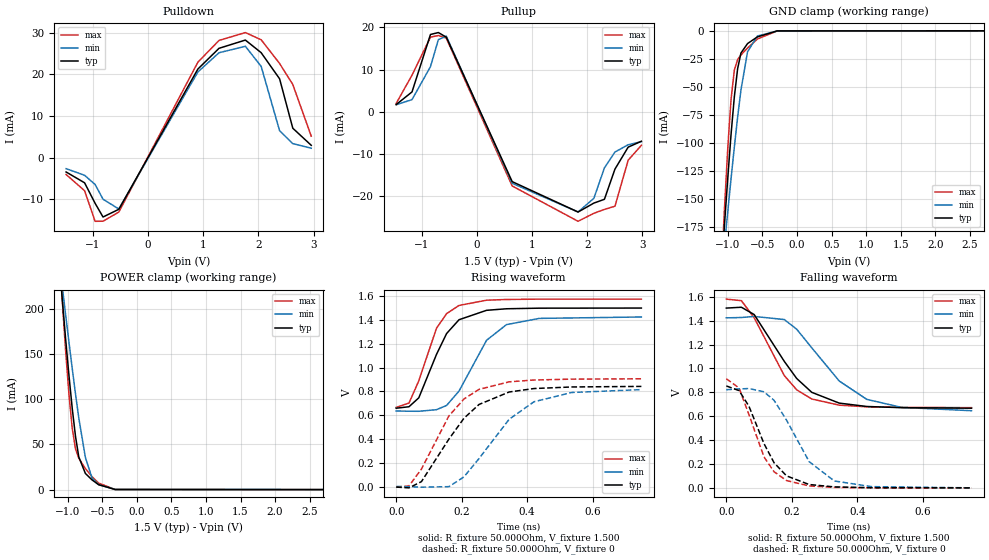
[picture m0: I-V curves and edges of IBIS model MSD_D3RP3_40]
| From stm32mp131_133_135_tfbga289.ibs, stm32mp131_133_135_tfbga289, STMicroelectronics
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[Model] MSD_D3RP3_40
Model_type   I/O
C_comp 2.233pF   2.153pF   2.350pF
Vinh = 925.000mV
Vinl = 575.000mV
Vmeas = 750.000mV
Vref = 750.000mV
[Model Spec]
Vinh   925.000mV   888.000mV   963.000mV
Vinl   575.000mV   538.000mV   613.000mV
Vmeas   750.000mV   713.000mV   788.000mV
Vref   750.000mV   713.000mV   788.000mV
[Temperature Range]   25.000   125.000   -40.000
[Voltage Range]   1.500V   1.425V   1.575V
[GND Clamp Reference]   0.00V   0.00V   0.00V
[Pulldown Reference]   0.00V   0.00V   0.00V
[POWER Clamp Reference]   1.500V   1.425V   1.575V
[Pullup Reference]   1.500V   1.425V   1.575V
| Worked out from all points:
|   slope of the pulldown table from 0 to 0.225 V, typ, clamps not added: 36.6 ohm
|   slope of the pullup table from 0 to 0.225 V, typ, clamps not added: 31.2 ohm
|   GND clamp passes 1 mA (typ) near -0.40 V on its own axis
|   POWER clamp passes 1 mA (typ) near -0.41 V on its own axis
|   rising waveform, R_fixture 50.000Ohm, V_fixture 1.500: 20-80 % time 81.9ps typ, 98.6ps min, 72.3ps max; typ from 0.658 V to 1.5 V
|   rising waveform, R_fixture 50.000Ohm, V_fixture 0: 20-80 % time 133ps typ, 149ps min, 119ps max; typ from -0.005 V to 0.842 V
|   falling waveform, R_fixture 50.000Ohm, V_fixture 1.500: 20-80 % time 128ps typ, 153ps min, 113ps max; typ from 1.51 V to 0.667 V
|   falling waveform, R_fixture 50.000Ohm, V_fixture 0: 20-80 % time 87.8ps typ, 105ps min, 76.6ps max; typ from 0.854 V to 0 V
[GND Clamp]
-1.48V    -592.8mA   -479.1mA   -761.2mA
-1.098V   -217.8mA   -223.1mA   -219.7mA
-1.05V    -173.8mA   -192.1mA   -159.3mA
-1.002V   -131.7mA   -161.7mA   -105mA
-954.6mV  -92.68mA   -132.2mA   -61.41mA
-906.8mV  -58.93mA   -103.8mA   -35.09mA
-859.1mV  -33.75mA   -77.07mA   -25.6mA
-811.4mV  -19.88mA   -53.01mA   -21.59mA
-715.9mV  -11.39mA   -18.72mA   -15.38mA
-572.7mV  -5.408mA   -4.63mA    -7.309mA
-286.4mV  -67.53uA   -115uA     -52.79uA
2.959V    27.81nA    447.4nA    3.164nA
[Power Clamp]
-1.459V   573.5mA    476.8mA    715.7mA
-1.077V   209.6mA    224.3mA    208.4mA
-1.03V    167.1mA    193.7mA    154.3mA
-981.8mV  126.8mA    163.5mA    105.9mA
-934.1mV  89.99mA    134.1mA    67.88mA
-886.4mV  58.74mA    105.7mA    45.04mA
-838.6mV  36.05mA    79.08mA    34.56mA
-743.2mV  17.84mA    35.43mA    23.27mA
-647.7mV  10.73mA    12.81mA    14.31mA
-552.3mV  5.47mA     5.422mA    7.21mA
-313.6mV  99.22uA    231.1uA    112.6uA
2.98V     -43.92nA   -827nA     -4.18nA
[Pulldown]
-1.48V    -3.4mA     -2.6mA     -4mA
-1.145V   -6mA       -4.2mA     -7.9mA
-954.6mV  -10.92mA   -6.4mA     -15.24mA
-811.4mV  -14.21mA   -9.93mA    -15.22mA
-525mV    -12.36mA   -12.29mA   -13.02mA
906.8mV   21.31mA    20.61mA    22.95mA
1.289V    26.28mA    25.22mA    28.17mA
1.766V    28.26mA    26.77mA    30.06mA
2.052V    25.23mA    21.95mA    28.33mA
2.386V    18.96mA    6.5mA      22.63mA
2.625V    7.1mA      3.4mA      17.6mA
2.959V    3mA        2.3mA      5.2mA
[Pullup]
-1.459V   1.7mA      1.657mA    1.971mA
-1.173V   4.7mA      2.871mA    8.671mA
-838.6mV  18.33mA    10.7mA     17.69mA
-695.5mV  18.78mA    17.1mA     18.08mA
-552.3mV  17.69mA    17.93mA    17.46mA
640.9mV   -16.58mA   -16.97mA   -17.61mA
1.834V    -23.79mA   -23.78mA   -25.99mA
2.12V     -21.67mA   -20.54mA   -24.1mA
2.311V    -20.77mA   -13.32mA   -23.17mA
2.502V    -13.6mA    -9.557mA   -22.41mA
2.741V    -8.4mA     -7.829mA   -11.5mA
2.98V     -7mA       -7.1mA     -7.971mA
[Ramp]
R_load=50.000Ohm
dV/dt_r   502.860mV/108.000ps  480.659mV/125.000ps  542.760mV/96.500ps
dV/dt_f   502.860mV/108.000ps  480.659mV/130.000ps  542.760mV/96.000ps
[Rising waveform]
R_fixture=50.000Ohm
V_fixture=1.500
V_fixture_min=1.425
V_fixture_max=1.575
0s        658.3mV    635.2mV    665mV
39ps      670.7mV    632.9mV    701.5mV
69ps      745.5mV    632.6mV    888.4mV
123ps     1.11V      645.7mV    1.33V
154ps     1.286V     681.8mV    1.453V
192ps     1.402V     802.9mV    1.522V
276ps     1.481V     1.229V     1.566V
337ps     1.494V     1.361V     1.572V
437ps     1.499V     1.413V     1.575V
749ps     1.5V       1.425V     1.575V
[Rising waveform]
R_fixture=50.000Ohm
V_fixture=0
0s        -4.502mV   778.3uV    -4.758mV
39ps      -11.04mV   -889.9uV   5.148mV
77ps      41.12mV    -5.223mV   146.7mV
161ps     398.7mV    -975.9uV   593.6mV
207ps     574mV      81.27mV    735.8mV
253ps     689.7mV    235.3mV    816.4mV
345ps     794.5mV    565.2mV    880mV
421ps     823.6mV    712.7mV    895.3mV
536ps     836.8mV    790.3mV    902.6mV
749ps     841.6mV    814.6mV    905.6mV
[Falling waveform]
R_fixture=50.000Ohm
V_fixture=1.500
V_fixture_min=1.425
V_fixture_max=1.575
0s        1.506V     1.424V     1.581V
46ps      1.513V     1.427V     1.568V
85ps      1.452V     1.436V     1.425V
177ps     1.06V      1.41V      940.7mV
215ps     916.1mV    1.329V     821.5mV
261ps     800.3mV    1.173V     744.5mV
345ps     709.9mV    895mV      692.8mV
429ps     681.7mV    741.5mV    679.1mV
536ps     671.6mV    673.8mV    674.2mV
749ps     667.4mV    646.3mV    671.8mV
[Falling waveform]
R_fixture=50.000Ohm
V_fixture=0
0s        853.9mV    822.1mV    914.1mV
39ps      814.3mV    828.8mV    836.4mV
69ps      684.4mV    832mV      614mV
115ps     370.8mV    804.7mV    259.4mV
146ps     209.6mV    732.7mV    134.4mV
184ps     100.3mV    566.8mV    60.96mV
253ps     27.98mV    219.8mV    16.05mV
330ps     7.941mV    57.59mV    3.837mV
444ps     1.38mV     10.22mV    509.6uV
749ps     23.47uV    266.3uV    15.13uV
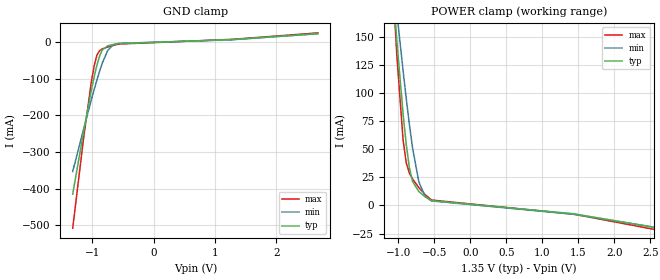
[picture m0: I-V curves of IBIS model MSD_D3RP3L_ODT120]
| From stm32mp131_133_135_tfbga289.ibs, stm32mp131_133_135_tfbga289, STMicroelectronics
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[Model] MSD_D3RP3L_ODT120
Model_type   Input
C_comp 2.197pF   2.122pF   2.281pF
Vinh = 810.000mV
Vinl = 540.000mV
[Receiver Thresholds]
Vth   =  0.675V
Vth_min  =  0.6615V
Vth_max  =  0.6885V
Vinh_ac  =  0.160V
Vinh_dc  =  0.090V
Vinl_ac  = -0.160V
Vinl_dc  = -0.090V
Tslew_ac =  5.000ns |Not specified, so set to high value
[Temperature Range]   25.000   125.000   -40.000
[Voltage Range]   1.350V   1.283V   1.450V
[GND Clamp Reference]   0.00V   0.00V   0.00V
[POWER Clamp Reference]   1.350V   1.283V   1.450V
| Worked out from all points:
|   GND clamp passes 1 mA (typ) near -0.44 V on its own axis
|   POWER clamp passes 1 mA (typ) near -0.33 V on its own axis
[GND Clamp]
-1.318V   -415mA     -353.2mA   -508mA
-1.142V   -246.2mA   -238.2mA   -264.1mA
-1.011V   -128.1mA   -154.9mA   -104.3mA
-966.7mV  -92.99mA   -128.4mA   -63.5mA
-922.7mV  -62.07mA   -102.8mA   -35.06mA
-878.8mV  -37.14mA   -78.64mA   -22.4mA
-834.9mV  -20.69mA   -56.51mA   -18.03mA
-747mV    -9.66mA    -22.26mA   -13mA
-659.1mV  -6.198mA   -6.845mA   -8.626mA
-571.2mV  -3.566mA   -2.927mA   -4.866mA
1.274V    7.314mA    6.947mA    8.003mA
2.68V     23.44mA    23.63mA    25.7mA
[Power Clamp]
-1.33V    427.4mA    369.4mA    514.3mA
-1.155V   263mA      256mA      286mA
-1.023V   147.8mA    172.9mA    134.9mA
-934.9mV  81.61mA    120.2mA    58.32mA
-890.9mV  54.31mA    95.28mA    38.09mA
-847mV    33.56mA    72.06mA    28.73mA
-803mV    21.38mA    51.24mA    23.61mA
-715.1mV  12.36mA    20.81mA    15.87mA
-627.3mV  7.666mA    8.056mA    9.573mA
-539.4mV  4.249mA    4.099mA    4.84mA
1.438V    -7.433mA   -7.9mA     -7.783mA
2.668V    -20.7mA    -20.53mA   -22.68mA
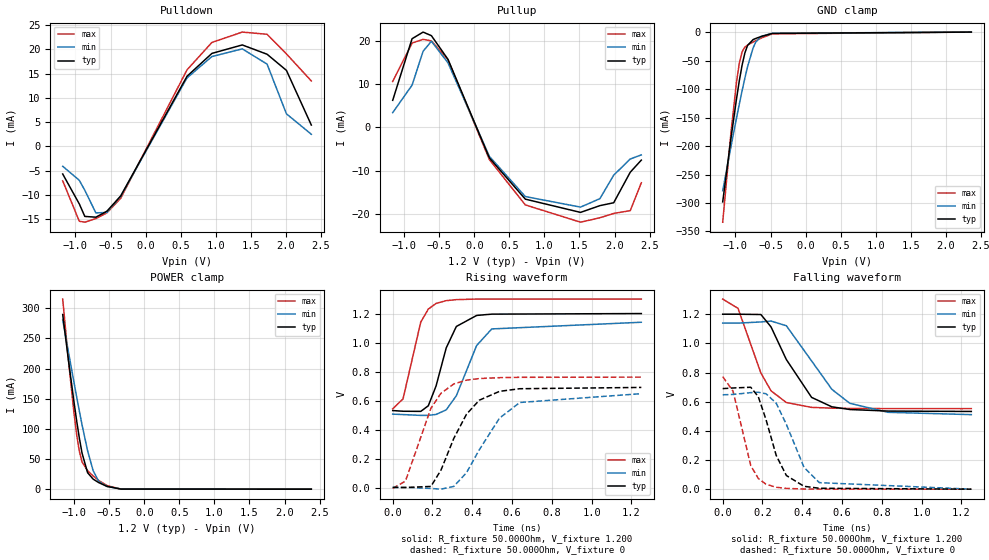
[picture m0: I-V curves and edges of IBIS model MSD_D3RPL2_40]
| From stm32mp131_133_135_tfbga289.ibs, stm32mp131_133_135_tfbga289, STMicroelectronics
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[Model] MSD_D3RPL2_40
Model_type   I/O
C_comp 2.247pF   2.165pF   2.365pF
Vinh = 820.000mV
Vinl = 380.000mV
Vmeas = 600.000mV
Vref = 600.000mV
[Model Spec]
Vinh   820.000mV   790.000mV   870.000mV
Vinl   380.000mV   350.000mV   430.000mV
Vmeas   600.000mV   570.000mV   650.000mV
Vref   600.000mV   570.000mV   650.000mV
[Receiver Thresholds]
Vth   =  0.600V
Vth_min  =  0.5880V
Vth_max  =  0.6120V
Vinh_ac  =  0.220V
Vinh_dc  =  0.130V
Vinl_ac  = -0.220V
Vinl_dc  = -0.130V
Tslew_ac =  5.000ns |Not specified, so set to high value
[Temperature Range]   25.000   125.000   -40.000
[Voltage Range]   1.200V   1.140V   1.300V
[GND Clamp Reference]   0.00V   0.00V   0.00V
[Pulldown Reference]   0.00V   0.00V   0.00V
[POWER Clamp Reference]   1.200V   1.140V   1.300V
[Pullup Reference]   1.200V   1.140V   1.300V
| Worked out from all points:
|   slope of the pulldown table from 0 to 0.18 V, typ, clamps not added: 35.7 ohm
|   slope of the pullup table from 0 to 0.18 V, typ, clamps not added: 29.6 ohm
|   GND clamp passes 1 mA (typ) near -0.41 V on its own axis
|   POWER clamp passes 1 mA (typ) near -0.41 V on its own axis
|   rising waveform, R_fixture 50.000Ohm, V_fixture 1.200: 20-80 % time 89.6ps typ, 117ps min, 76ps max; typ from 0.531 V to 1.2 V
|   rising waveform, R_fixture 50.000Ohm, V_fixture 0: 20-80 % time 148ps typ, 181ps min, 126ps max; typ from 0.001 V to 0.69 V
|   falling waveform, R_fixture 50.000Ohm, V_fixture 1.200: 20-80 % time 159ps typ, 199ps min, 127ps max; typ from 1.2 V to 0.533 V
|   falling waveform, R_fixture 50.000Ohm, V_fixture 0: 20-80 % time 97.4ps typ, 121ps min, 81.8ps max; typ from 0.69 V to 0 V
[GND Clamp]
-1.182V   -298.1mA   -278.5mA   -333.7mA
-1.064V   -186.2mA   -200.9mA   -176mA
-984.9mV  -117mA     -150.8mA   -87.54mA
-945.5mV  -85.76mA   -126.7mA   -54.85mA
-906.1mV  -58.45mA   -103.3mA   -34.84mA
-866.7mV  -37.02mA   -81.16mA   -26.5mA
-827.3mV  -23.29mA   -60.66mA   -22.76mA
-748.5mV  -13.2mA    -27.78mA   -17.43mA
-709.1mV  -11.06mA   -17.2mA    -14.96mA
-630.3mV  -7.603mA   -7.31mA    -10.35mA
-472.7mV  -2.342mA   -2.056mA   -3.036mA
2.364V    24.05nA    406.6nA    2.608nA
[Power Clamp]
-1.164V   289.6mA    280.7mA    315.2mA
-1.085V   216.5mA    229.3mA    217.2mA
-1.006V   146.9mA    178.8mA    129.3mA
-966.7mV  114.6mA    154.1mA    91.94mA
-927.3mV  85.12mA    129.9mA    62.94mA
-887.9mV  59.62mA    106.5mA    45.07mA
-809.1mV  27.34mA    63.75mA    30.55mA
-730.3mV  16.69mA    30.8mA     21.95mA
-651.5mV  10.97mA    13.15mA    14.62mA
-533.3mV  4.62mA     4.579mA    6.036mA
-336.4mV  182.5uA    350.8uA    204.6uA
2.382V    -20.25nA   -432nA     -2.133nA
[Pulldown]
-1.182V   -5.7mA     -4.1mA     -7.1mA
-945.5mV  -11.87mA   -7mA       -15.44mA
-866.7mV  -14.45mA   -9.06mA    -15.64mA
-709.1mV  -14.61mA   -13.72mA   -14.89mA
-551.5mV  -13.37mA   -13.64mA   -13.71mA
-354.6mV  -10.22mA   -10.29mA   -10.7mA
590.9mV   14.46mA    14.13mA    15.78mA
945.5mV   19.18mA    18.53mA    21.44mA
1.379V    20.93mA    20.12mA    23.58mA
1.733V    19.01mA    16.97mA    23.13mA
2.009V    15.68mA    6.72mA     19.08mA
2.364V    4.4mA      2.5mA      13.5mA
[Pullup]
-1.164V   6.2mA      3.357mA    10.56mA
-887.9mV  20.42mA    9.7mA      19.41mA
-730.3mV  21.95mA    17.53mA    20.27mA
-612.1mV  21.12mA    19.83mA    19.92mA
-375.8mV  15.66mA    14.86mA    15.58mA
215.2mV   -7.103mA   -6.741mA   -7.479mA
727.3mV   -16.61mA   -16.01mA   -17.94mA
1.515V    -19.67mA   -18.45mA   -21.93mA
1.791V    -18.11mA   -16.5mA    -20.91mA
1.988V    -17.44mA   -11.08mA   -19.91mA
2.224V    -10.4mA    -7.343mA   -19.26mA
2.382V    -7.6mA     -6.395mA   -12.83mA
[Ramp]
R_load=50.000Ohm
dV/dt_r   407.250mV/119.500ps  383.519mV/150.500ps  452.760mV/101.000ps
dV/dt_f   407.250mV/128.500ps  383.489mV/161.500ps  452.760mV/104.000ps
[Rising waveform]
R_fixture=50.000Ohm
V_fixture=1.200
V_fixture_min=1.140
V_fixture_max=1.300
0s        530.8mV    506.3mV    542.8mV
52ps      526.1mV    503.1mV    611.4mV
141ps     525.1mV    497.5mV    1.141V
179ps     563.9mV    497.6mV    1.231V
218ps     700.5mV    504.2mV    1.27V
269ps     962.9mV    535.6mV    1.289V
320ps     1.111V     633.2mV    1.296V
422ps     1.187V     979.6mV    1.3V
498ps     1.196V     1.094V     1.3V
1.25ns    1.2V       1.14V      1.3V
[Rising waveform]
R_fixture=50.000Ohm
V_fixture=0
0s        869.2uV    838.4uV    -5.727mV
64ps      39.64uV    830.3uV    43.95mV
192ps     7.505mV    -6.613mV   546.5mV
243ps     120.8mV    -11.44mV   650.7mV
307ps     338.4mV    7.589mV    714.3mV
371ps     505.5mV    102mV      740.8mV
435ps     602mV      259.6mV    751.6mV
537ps     663.4mV    478.8mV    757.8mV
639ps     681.5mV    586.5mV    760.2mV
1.25ns    690.4mV    647.4mV    761.5mV
[Falling waveform]
R_fixture=50.000Ohm
V_fixture=1.200
V_fixture_min=1.140
V_fixture_max=1.300
0s        1.2V       1.139V     1.304V
77ps      1.2V       1.139V     1.24V
192ps     1.198V     1.147V     796.6mV
243ps     1.113V     1.153V     674.5mV
320ps     888.9mV    1.121V     594.3mV
447ps     629.4mV    879.4mV    561mV
549ps     564.8mV    684.6mV    555.7mV
639ps     546.4mV    589mV      553.9mV
830ps     535.7mV    527.2mV    552.5mV
1.25ns    533mV      511.2mV    552.3mV
[Falling waveform]
R_fixture=50.000Ohm
V_fixture=0
0s        689.7mV    647.3mV    772mV
52ps      694mV      649.8mV    672.4mV
141ps     699.1mV    662.2mV    162.2mV
179ps     634mV      664.9mV    73.03mV
218ps     476.1mV    654.3mV    33.46mV
269ps     231.6mV    589.5mV    13.01mV
320ps     93.68mV    444.6mV    5.312mV
409ps     19.63mV    149.2mV    1.115mV
486ps     6.165mV    44.71mV    269.3uV
1.25ns    599.8nV    16.43uV    0V
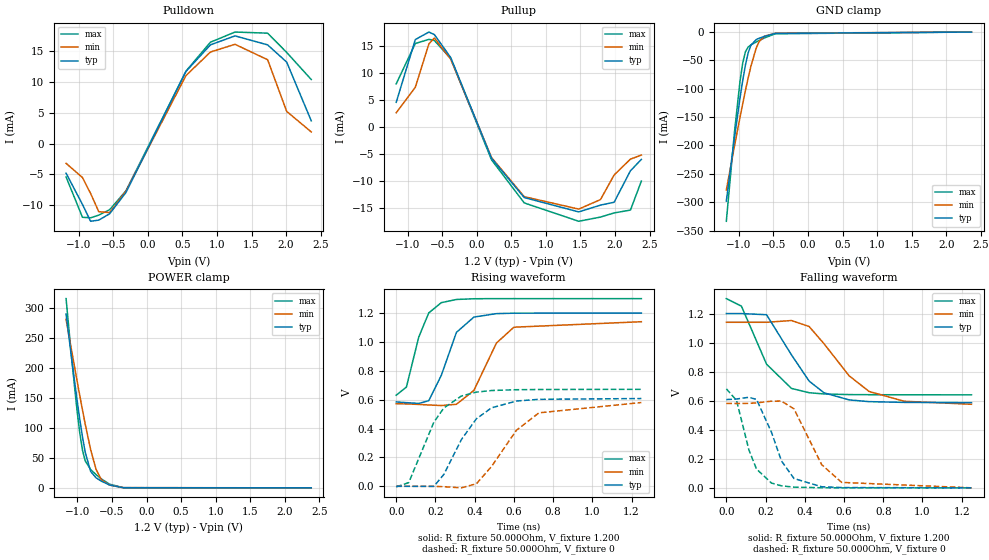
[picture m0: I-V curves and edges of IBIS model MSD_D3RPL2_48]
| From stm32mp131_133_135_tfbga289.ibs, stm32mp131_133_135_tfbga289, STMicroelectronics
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[Model] MSD_D3RPL2_48
Model_type   I/O
C_comp 2.247pF   2.165pF   2.365pF
Vinh = 820.000mV
Vinl = 380.000mV
Vmeas = 600.000mV
Vref = 600.000mV
[Model Spec]
Vinh   820.000mV   790.000mV   870.000mV
Vinl   380.000mV   350.000mV   430.000mV
Vmeas   600.000mV   570.000mV   650.000mV
Vref   600.000mV   570.000mV   650.000mV
[Receiver Thresholds]
Vth   =  0.600V
Vth_min  =  0.5880V
Vth_max  =  0.6120V
Vinh_ac  =  0.220V
Vinh_dc  =  0.130V
Vinl_ac  = -0.220V
Vinl_dc  = -0.130V
Tslew_ac =  5.000ns |Not specified, so set to high value
[Temperature Range]   25.000   125.000   -40.000
[Voltage Range]   1.200V   1.140V   1.300V
[GND Clamp Reference]   0.00V   0.00V   0.00V
[Pulldown Reference]   0.00V   0.00V   0.00V
[POWER Clamp Reference]   1.200V   1.140V   1.300V
[Pullup Reference]   1.200V   1.140V   1.300V
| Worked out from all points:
|   slope of the pulldown table from 0 to 0.18 V, typ, clamps not added: 41.6 ohm
|   slope of the pullup table from 0 to 0.18 V, typ, clamps not added: 36.3 ohm
|   GND clamp passes 1 mA (typ) near -0.41 V on its own axis
|   POWER clamp passes 1 mA (typ) near -0.41 V on its own axis
|   rising waveform, R_fixture 50.000Ohm, V_fixture 1.200: 20-80 % time 97.2ps typ, 124ps min, 81.9ps max; typ from 0.584 V to 1.2 V
|   rising waveform, R_fixture 50.000Ohm, V_fixture 0: 20-80 % time 165ps typ, 198ps min, 141ps max; typ from 0.001 V to 0.608 V
|   falling waveform, R_fixture 50.000Ohm, V_fixture 1.200: 20-80 % time 172ps typ, 220ps min, 140ps max; typ from 1.2 V to 0.587 V
|   falling waveform, R_fixture 50.000Ohm, V_fixture 0: 20-80 % time 102ps typ, 127ps min, 87.2ps max; typ from 0.608 V to 0 V
[GND Clamp]
-1.182V   -298.1mA   -278.5mA   -333.7mA
-1.064V   -186.2mA   -200.9mA   -176mA
-984.9mV  -117mA     -150.8mA   -87.54mA
-945.5mV  -85.76mA   -126.7mA   -54.85mA
-906.1mV  -58.45mA   -103.3mA   -34.84mA
-866.7mV  -37.02mA   -81.16mA   -26.5mA
-827.3mV  -23.29mA   -60.66mA   -22.76mA
-748.5mV  -13.2mA    -27.78mA   -17.43mA
-709.1mV  -11.06mA   -17.2mA    -14.96mA
-630.3mV  -7.603mA   -7.31mA    -10.35mA
-472.7mV  -2.342mA   -2.056mA   -3.036mA
2.364V    24.05nA    406.6nA    2.608nA
[Power Clamp]
-1.164V   289.6mA    280.7mA    315.2mA
-1.085V   216.5mA    229.3mA    217.2mA
-1.006V   146.9mA    178.8mA    129.3mA
-966.7mV  114.6mA    154.1mA    91.94mA
-927.3mV  85.12mA    129.9mA    62.94mA
-887.9mV  59.62mA    106.5mA    45.07mA
-809.1mV  27.34mA    63.75mA    30.55mA
-730.3mV  16.69mA    30.8mA     21.95mA
-651.5mV  10.97mA    13.15mA    14.62mA
-533.3mV  4.62mA     4.579mA    6.036mA
-336.4mV  182.5uA    350.8uA    204.6uA
2.382V    -20.25nA   -432nA     -2.133nA
[Pulldown]
-1.182V   -4.8mA     -3.2mA     -5.4mA
-945.5mV  -9.86mA    -5.5mA     -11.95mA
-827.3mV  -12.6mA    -8.09mA    -12.04mA
-709.1mV  -12.41mA   -11.05mA   -11.6mA
-551.5mV  -11.38mA   -11.19mA   -10.72mA
-315.1mV  -7.912mA   -7.698mA   -7.642mA
551.5mV   11.71mA    11.03mA    11.75mA
906.1mV   16.02mA    14.86mA    16.45mA
1.261V    17.48mA    16.11mA    18.1mA
1.733V    16.02mA    13.61mA    17.92mA
2.009V    13.22mA    5.22mA     14.79mA
2.364V    3.7mA      1.9mA      10.4mA
[Pullup]
-1.164V   4.6mA      2.657mA    8.031mA
-887.9mV  16.25mA    7.39mA     15.52mA
-690.9mV  17.65mA    15.47mA    16.29mA
-612.1mV  17.18mA    16.54mA    16.08mA
-375.8mV  12.92mA    12.62mA    12.73mA
215.2mV   -5.798mA   -5.652mA   -6.079mA
687.9mV   -13.08mA   -12.91mA   -14.07mA
1.476V    -15.74mA   -15.22mA   -17.48mA
1.791V    -14.48mA   -13.45mA   -16.7mA
1.988V    -13.95mA   -8.884mA   -15.93mA
2.224V    -8.1mA     -5.943mA   -15.4mA
2.382V    -6mA       -5.195mA   -10.02mA
[Ramp]
R_load=50.000Ohm
dV/dt_r   366.660mV/132.000ps  344.579mV/162.500ps  399.510mV/111.500ps
dV/dt_f   366.660mV/138.000ps  344.549mV/175.500ps  399.510mV/113.500ps
[Rising waveform]
R_fixture=50.000Ohm
V_fixture=1.200
V_fixture_min=1.140
V_fixture_max=1.300
0s        584.5mV    572.4mV    631.1mV
52ps      579.8mV    570.9mV    687.5mV
115ps     574.1mV    567.3mV    1.034V
166ps     593.2mV    563.6mV    1.201V
230ps     768.7mV    559.6mV    1.272V
307ps     1.066V     568.1mV    1.294V
396ps     1.172V     664.2mV    1.299V
511ps     1.196V     992.3mV    1.3V
600ps     1.199V     1.102V     1.3V
1.25ns    1.2V       1.14V      1.3V
[Rising waveform]
R_fixture=50.000Ohm
V_fixture=0
0s        706.4uV    186.8uV    -3.982mV
64ps      259.1uV    624.3uV    26.31mV
192ps     -29.2uV    106.8uV    444.6mV
243ps     82.9mV     -2.511mV   542.7mV
332ps     323.4mV    -10.2mV    625.4mV
409ps     468.3mV    18.03mV    652.6mV
486ps     543.7mV    137.7mV    663.6mV
613ps     590.8mV    388.6mV    669.2mV
728ps     602.7mV    509.1mV    670.6mV
1.25ns    608.1mV    580.4mV    671.9mV
[Falling waveform]
R_fixture=50.000Ohm
V_fixture=1.200
V_fixture_min=1.140
V_fixture_max=1.300
0s        1.2V       1.14V      1.303V
77ps      1.2V       1.14V      1.251V
205ps     1.192V     1.14V      851.6mV
332ps     916mV      1.152V     684.6mV
422ps     735.3mV    1.111V     655mV
498ps     654.3mV    992.4mV    646.4mV
626ps     605.5mV    771.5mV    642.1mV
728ps     593.6mV    663.4mV    641.3mV
907ps     588.3mV    596.2mV    640.8mV
1.25ns    586.8mV    575.4mV    640.4mV
[Falling waveform]
R_fixture=50.000Ohm
V_fixture=0
0s        607.8mV    581mV      681.9mV
52ps      611.7mV    580.7mV    602.2mV
115ps     623.6mV    581.7mV    261.3mV
154ps     608.5mV    585.1mV    129mV
230ps     383.1mV    596.8mV    32.93mV
281ps     185.5mV    597.3mV    13.82mV
345ps     64.13mV    543.6mV    4.745mV
486ps     7.412mV    159.8mV    445.2uV
588ps     1.889mV    37.39mV    116.4uV
1.25ns    1.152uV    38.65uV    0V
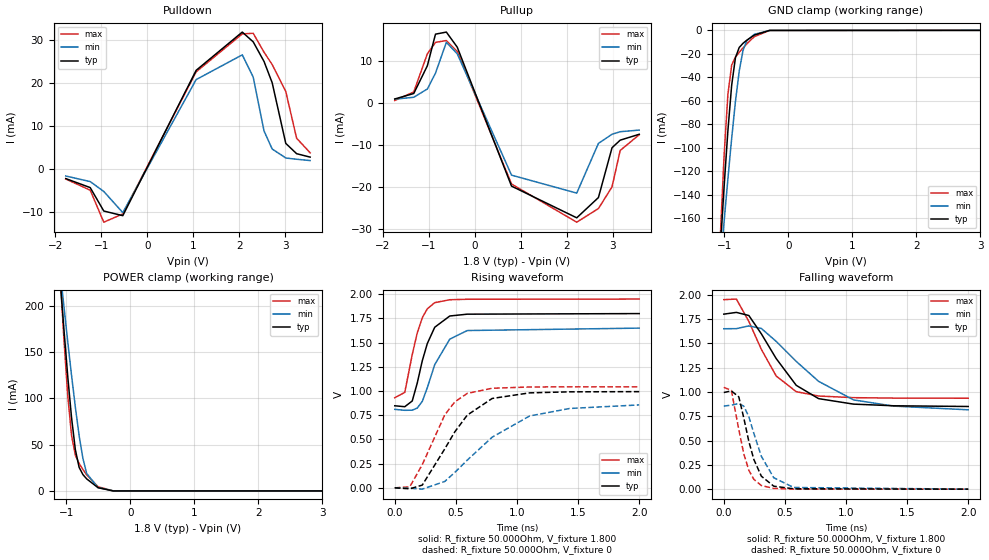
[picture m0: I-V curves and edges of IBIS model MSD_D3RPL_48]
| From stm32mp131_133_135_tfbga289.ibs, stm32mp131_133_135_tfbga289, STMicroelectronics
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[Model] MSD_D3RPL_48
Model_type   I/O
C_comp 2.221pF   2.140pF   2.339pF
Vinh = 1.440V
Vinl = 360.000mV
Vmeas = 900.000mV
Vref = 900.000mV
[Model Spec]
Vinh   1.440V   1.365V   1.515V
Vinl   360.000mV   285.000mV   435.000mV
Vmeas   900.000mV   825.000mV   975.000mV
Vref   900.000mV   825.000mV   975.000mV
[Temperature Range]   25.000   125.000   -40.000
[Voltage Range]   1.800V   1.650V   1.950V
[GND Clamp Reference]   0.00V   0.00V   0.00V
[Pulldown Reference]   0.00V   0.00V   0.00V
[POWER Clamp Reference]   1.800V   1.650V   1.950V
[Pullup Reference]   1.800V   1.650V   1.950V
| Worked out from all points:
|   slope of the pulldown table from 0 to 0.27 V, typ, clamps not added: 41 ohm
|   slope of the pullup table from 0 to 0.27 V, typ, clamps not added: 32.3 ohm
|   GND clamp passes 1 mA (typ) near -0.40 V on its own axis
|   POWER clamp passes 1 mA (typ) near -0.41 V on its own axis
|   rising waveform, R_fixture 50.000Ohm, V_fixture 1.800: 20-80 % time 129ps typ, 162ps min, 113ps max; typ from 0.848 V to 1.8 V
|   rising waveform, R_fixture 50.000Ohm, V_fixture 0: 20-80 % time 308ps typ, 493ps min, 239ps max; typ from 0.001 V to 0.994 V
|   falling waveform, R_fixture 50.000Ohm, V_fixture 1.800: 20-80 % time 317ps typ, 471ps min, 248ps max; typ from 1.8 V to 0.85 V
|   falling waveform, R_fixture 50.000Ohm, V_fixture 0: 20-80 % time 126ps typ, 155ps min, 109ps max; typ from 0.993 V to 0 V
[GND Clamp]
-1.773V   -887.4mA   -679.5mA   -1.189A
-1.064V   -186.2mA   -200.9mA   -176mA
-1.005V   -133.6mA   -163.2mA   -107.4mA
-945.5mV  -85.76mA   -126.7mA   -54.85mA
-886.4mV  -46.87mA   -92.07mA   -29.65mA
-827.3mV  -23.29mA   -60.66mA   -22.76mA
-768.2mV  -14.6mA    -34.68mA   -18.69mA
-709.1mV  -11.06mA   -17.2mA    -14.96mA
-650mV    -8.414mA   -8.79mA    -11.46mA
-531.8mV  -4.025mA   -3.405mA   -5.38mA
-295.4mV  -87.46uA   -140.3uA   -72.54uA
3.545V    30.39nA    447.4nA    3.642nA
[Power Clamp]
-1.745V   852.6mA    670mA      1.113A
-1.095V   226.2mA    236.2mA    230.3mA
-1.036V   173mA      198.1mA    162mA
-977.3mV  123.1mA    160.7mA    102.4mA
-918.2mV  78.83mA    124.5mA    59.74mA
-859.1mV  44.51mA    90.34mA    38.51mA
-800mV    25.4mA     59.71mA    29.55mA
-740.9mV  17.63mA    35.03mA    23.07mA
-681.8mV  12.99mA    18.74mA    17.35mA
-504.5mV  3.464mA    3.576mA    4.546mA
-268.2mV  26.04uA    93.18uA    29.58uA
3.573V    -30.16nA   -532.8nA   -4.25nA
[Pulldown]
-1.773V   -2.3mA     -1.7mA     -2.4mA
-1.241V   -4.4mA     -3mA       -5mA
-945.5mV  -9.86mA    -5.3mA     -12.46mA
-531.8mV  -10.94mA   -10.23mA   -10.53mA
1.064V    22.92mA    20.76mA    22.57mA
2.068V    31.83mA    26.53mA    31.41mA
2.305V    29.56mA    21.35mA    31.55mA
2.541V    24.99mA    8.8mA      27.14mA
2.718V    20.04mA    4.6mA      24.27mA
3.014V    5.9mA      2.5mA      18mA
3.25V     3.5mA      2.2mA      7.1mA
3.545V    2.7mA      1.9mA      3.7mA
[Pullup]
-1.745V   1mA        953.9uA    646.2uA
-1.332V   2.3mA      1.408mA    2.669mA
-1.036V   8.9mA      3.377mA    11.75mA
-859.1mV  16.42mA    7.145mA    14.46mA
-622.7mV  16.91mA    14.47mA    14.9mA
-386.4mV  13.34mA    11.76mA    12.33mA
795.5mV   -19.73mA   -17.12mA   -19.23mA
2.214V    -27.27mA   -21.39mA   -28.31mA
2.686V    -22.45mA   -9.569mA   -25.07mA
2.982V    -10.6mA    -7.392mA   -19.9mA
3.159V    -8.8mA     -6.792mA   -11.25mA
3.573V    -7.4mA     -6.4mA     -7.508mA
[Ramp]
R_load=50.000Ohm
dV/dt_r   583.710mV/219.000ps  505.829mV/324.000ps  617.730mV/176.000ps
dV/dt_f   583.619mV/222.500ps  504.414mV/308.500ps  617.700mV/179.000ps
[Rising waveform]
R_fixture=50.000Ohm
V_fixture=1.800
V_fixture_min=1.650
V_fixture_max=1.950
0s        848.1mV    811mV      931.3mV
82ps      838.5mV    801.3mV    986.6mV
143ps     897.7mV    802.7mV    1.377V
184ps     1.083V     824.5mV    1.601V
225ps     1.312V     893.2mV    1.757V
266ps     1.49V      1.034V     1.849V
327ps     1.659V     1.273V     1.913V
450ps     1.775V     1.536V     1.943V
593ps     1.794V     1.625V     1.948V
2ns       1.8V       1.65V      1.95V
[Rising waveform]
R_fixture=50.000Ohm
V_fixture=0
0s        1.156mV    1.149mV    396.8uV
123ps     -9.403mV   -2.82mV    11.63mV
225ps     29.16mV    -12.95mV   240.2mV
409ps     402.8mV    66.82mV    754.1mV
491ps     578.4mV    159.5mV    888.1mV
593ps     751.6mV    286.7mV    976mV
797ps     923.6mV    524mV      1.029V
1.103ns   981.4mV    742.5mV    1.042V
1.43ns    992.1mV    820.2mV    1.044V
2ns       994.1mV    856.9mV    1.044V
[Falling waveform]
R_fixture=50.000Ohm
V_fixture=1.800
V_fixture_min=1.650
V_fixture_max=1.950
0s        1.799V     1.649V     1.948V
103ps     1.817V     1.65V      1.954V
205ps     1.785V     1.678V     1.724V
307ps     1.597V     1.652V     1.438V
429ps     1.342V     1.519V     1.163V
593ps     1.067V     1.313V     1.002V
776ps     930.4mV    1.108V     957.5mV
1.062ns   874.1mV    917.5mV    940.5mV
1.389ns   857.2mV    853.7mV    936.1mV
2ns       849.8mV    815.8mV    934.8mV
[Falling waveform]
R_fixture=50.000Ohm
V_fixture=0
0s        993.4mV    854.4mV    1.047V
62ps      1.01V      863mV      1.015V
123ps     948.5mV    880.9mV    611.5mV
164ps     729.9mV    852.6mV    360.8mV
205ps     490mV      744.9mV    194.3mV
246ps     305.2mV    573.5mV    101mV
307ps     133.8mV    338.8mV    37.66mV
409ps     30.53mV    117.1mV    7.652mV
572ps     3.759mV    17.27mV    952.5uV
2ns       13.53uV    96.1uV     0V
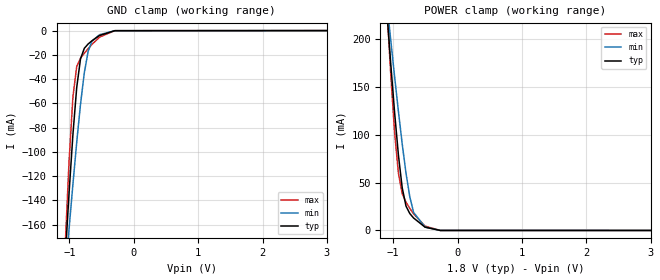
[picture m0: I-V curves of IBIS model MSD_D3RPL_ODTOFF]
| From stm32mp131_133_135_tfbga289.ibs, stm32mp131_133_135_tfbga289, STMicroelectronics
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[Model] MSD_D3RPL_ODTOFF
Model_type   Input
C_comp 2.221pF   2.140pF   2.339pF
Vinh = 1.440V
Vinl = 360.000mV
[Temperature Range]   25.000   125.000   -40.000
[Voltage Range]   1.800V   1.650V   1.950V
[GND Clamp Reference]   0.00V   0.00V   0.00V
[POWER Clamp Reference]   1.800V   1.650V   1.950V
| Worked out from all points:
|   GND clamp passes 1 mA (typ) near -0.40 V on its own axis
|   POWER clamp passes 1 mA (typ) near -0.41 V on its own axis
[GND Clamp]
-1.773V   -887.4mA   -679.5mA   -1.189A
-1.064V   -186.2mA   -200.9mA   -176mA
-1.005V   -133.6mA   -163.2mA   -107.4mA
-945.5mV  -85.76mA   -126.7mA   -54.85mA
-886.4mV  -46.87mA   -92.07mA   -29.65mA
-827.3mV  -23.29mA   -60.66mA   -22.76mA
-768.2mV  -14.6mA    -34.68mA   -18.69mA
-709.1mV  -11.06mA   -17.2mA    -14.96mA
-650mV    -8.414mA   -8.79mA    -11.46mA
-531.8mV  -4.025mA   -3.405mA   -5.38mA
-295.4mV  -87.46uA   -140.3uA   -72.54uA
3.545V    30.38nA    447.4nA    3.632nA
[Power Clamp]
-1.745V   852.6mA    670mA      1.113A
-1.095V   226.2mA    236.2mA    230.3mA
-1.036V   173mA      198.1mA    162mA
-977.3mV  123.1mA    160.7mA    102.4mA
-918.2mV  78.83mA    124.5mA    59.74mA
-859.1mV  44.51mA    90.34mA    38.51mA
-800mV    25.4mA     59.71mA    29.55mA
-740.9mV  17.63mA    35.03mA    23.07mA
-681.8mV  12.99mA    18.74mA    17.35mA
-504.5mV  3.464mA    3.576mA    4.546mA
-268.2mV  26.04uA    93.18uA    29.58uA
3.573V    -30.16nA   -532.8nA   -4.247nA
